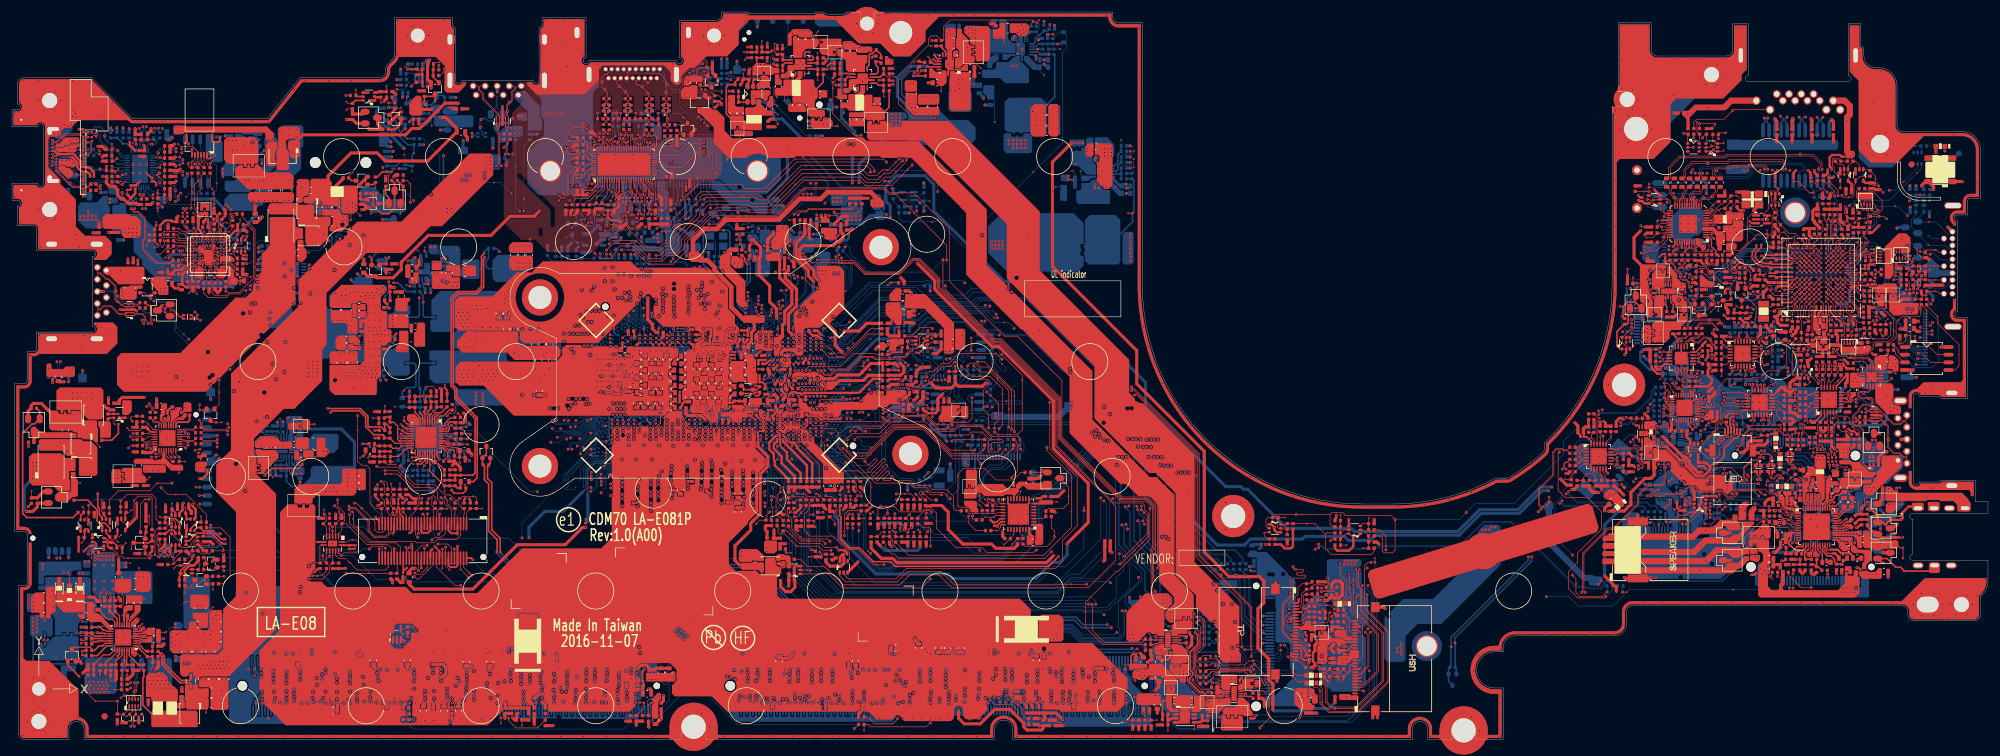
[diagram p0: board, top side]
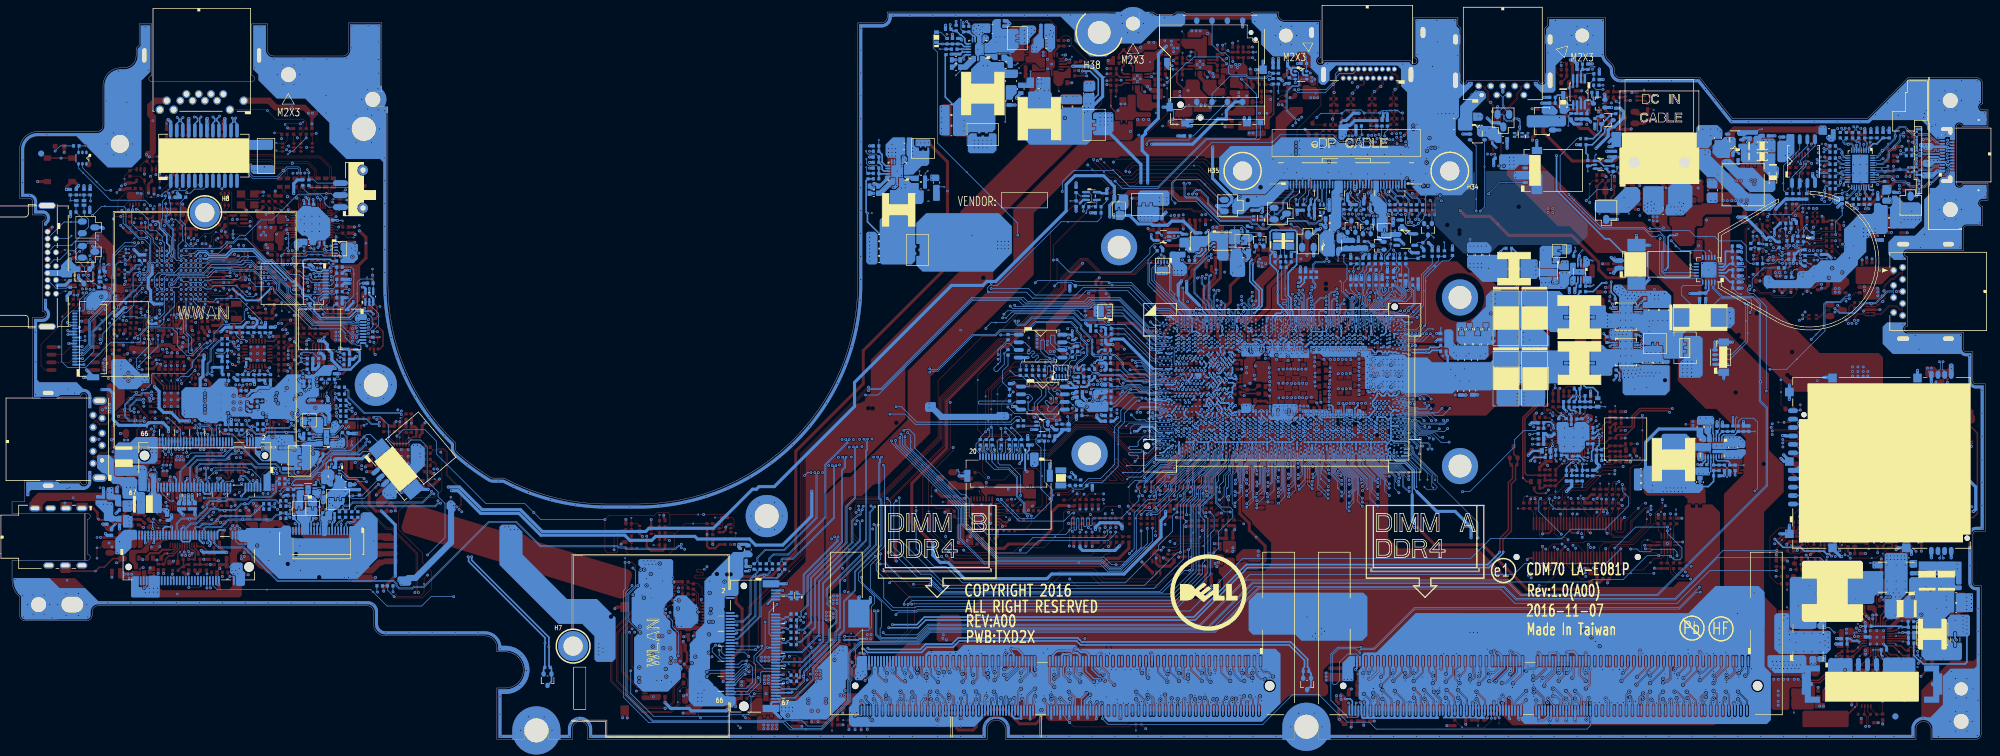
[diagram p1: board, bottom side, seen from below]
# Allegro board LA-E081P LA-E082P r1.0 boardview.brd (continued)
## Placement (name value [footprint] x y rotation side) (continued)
T219  PAD~D  [TPC12]  31.5 84.66 0 bottom
T220  PAD~D  [TPC12]  30.04 85.49 0 bottom
T223  PAD~D  [TPC12]  99.14 91.25 0 top
T224  PAD~D  [TPC12]  101.94 91.61 0 top
T225  PAD~D  [TPC12]  301.34 39.6 180 bottom
T258  PAD~D  [TPC12]  140.04 41.88 180 bottom
T267  PAD~D  [TPC12]  46.26 81.17 180 bottom
T268  PAD~D  [TPC12]  142.7 41.93 180 bottom
T281  PAD~D  [TPC12]  109.23 66.25 0 top
T282  PAD~D  [TPC12]  109.25 67.63 0 top
T283  PAD~D  [TPC12]  167.44 41.27 180 top
TL1  350UH_IH-160  [TAIMA_IH-160_24P]  301.71 92.78 180 bottom
UA1  ALC3246-CG_MQFN48_6X6  [ALC3246-CG_MQFN48_6X6-S]  296.55 37.52 0 top
UC1  SKL-U_BGA1356  [SKL-U_BGA_1356P-T]  137.46 69.71 0 bottom
UC5  -  [W25Q128FVSIQ_SO8]  160.91 67.23 270 bottom
UC6  -  [W25Q128FVSIQ_SO8]  160.53 58.59 270 bottom
UC7  TC7SH08FU_SSOP5~D  [TC7SH08FU_SSOP5]  157.98 52.77 270 bottom
UC8  74CBTLV3126BQ_DHVQFN14_2P5X3  [74CBTLV3126BQ_DHVQFN14_2P5X3-S]  54.69 32.79 180 top
UC12  -  [74AHC1G09GW_TSSOP5]  149.74 90.9 270 bottom
UD1  -  [74AUP1G07GW_TSSOP5]  63.24 16.58 0 top
UE1  MEC5105_WFBGA169_11X11  [MEC5105_WFBGA_169P]  295.56 71.93 90 top
UE2  MCP23008T-E-ML_QFN20_4X4  [IT8010FN-BX-R_QFN20_4X4]  44.31 77 0 bottom
UE3  TC7SH08FU_SSOP5~D  [TC7SH08FU_SSOP5]  307.36 94.69 180 top
UE4  -  [74AUP1G07GW_TSSOP5]  289.56 87.03 270 top
UE5  TC7SH08FU_SSOP5~D  [TC7SH08FU_SSOP5]  304.82 94.69 180 top
UE6  -  [74AUP1G07GW_TSSOP5]  269.39 72.66 180 bottom
UE7  RT9826-30GB  [AP2112K-3P3TRG1_SOT23-5]  284.53 75.78 90 top
UE9  -  [W25Q80DVSSIG_SO8]  314.26 65.17 270 top
UI1  -  [SY6288D20AAC_SOT23-5]  21.27 76.08 270 top
UI2  -  [SY6288D20AAC_SOT23-5]  85.98 101.49 270 bottom
UI3  -  [SLGC55544CVTR_TQFN16_3X3]  309.49 61.77 180 top
UI5  PS8713BTQFN24GTR2_TQFN24_4X4  [PS8713BTQFN24GTR2_TQFN24_4X4-S]  300.38 54.36 0 top
UL1  WGI219LM-QREF- A0_QFN48_6X6~D  [WGI217LM-QPN9-A2_QFN48_6X6-S]  281.24 83.42 90 top
UL2  TC7SH08FU_SSOP5~D  [TC7SH08FU_SSOP5]  273.62 89.03 90 top
UN4  PS8558BTQFN24GTR2-A_TQFN24_4X4  [PS8558BTQFN24_TQFN24_4X4-S]  261.35 48.26 0 top
UN5  PS8558BTQFN24GTR2-A_TQFN24_4X4  [PS8558BTQFN24_TQFN24_4X4-S]  288.89 53.91 90 top
UN7  PI3EQX6741STZDEX_TQFN20_4X4  [PI3EQX6741STZDEX_TQFN20_4X4-S]  278.14 65.3 270 top
UR1  RTS5242-GR_QFN32_4X4  [RTS5242-GR_QFN32_4X4-S]  27.84 48.66 180 top
UT5  TPS65982_BGA96  [TPS65982_BGA_96P]  35.14 83.04 270 top
UT6  -  [W25Q80DVSSIG_SO8]  32.52 92.4 180 bottom
UT7  AP2112K-3.3TRG1_SOT23-5  [AP2112K-3P3TRG1_SOT23-5]  40.85 98.64 90 bottom
UT8  AP2204R-5.0TRG1_SOT89-3  [AP2204R-5P0TRG1_SOT89-3]  46.41 98.64 180 top
UT9  -  [TUSB546_QFN40_4X6]  19.81 97.81 270 bottom
UV2  -  [AP2330W-7_SC59-3]  114.11 104.53 180 top
UV4  -  [AP2330W-7_SC59-3]  316.11 75.71 0 bottom
UV6  RTD2166-CG_QFN32_4X4  [RTD2166-CG_QFN32_4X4-S]  275.64 56.47 0 top
UV7  PS8348BQFN66GTR-A0_QFN66_5X10  [PS8348BQFN66GTR-A0_QFN66_5X10-S]  97.21 92.97 90 top
UV24  -  [G524B1T11U_SOT23-5]  98.15 83.96 270 bottom
UZ2  EM5209VF_SON14_2X3  [TPS22966DPUR_SON14_2X3-S]  274.82 48.98 90 bottom
UZ3  EM5209VF_SON14_2X3  [TPS22966DPUR_SON14_2X3-S]  201.86 8.81 270 top
UZ4  EM5209VF_SON14_2X3  [TPS22966DPUR_SON14_2X3-S]  190.88 17.73 270 top
UZ5  EM5209VF_SON14_2X3  [TPS22966DPUR_SON14_2X3-S]  276.16 75.46 180 top
UZ6  TC7SH08FU_SSOP5~D  [TC7SH08FU_SSOP5]  137.42 27.7 0 top
UZ8  AOZ1336_DFN8_2X2  [AOZ1336_DFN8_2X2-S]  271.65 51.92 180 top
UZ10  TC7SH08FU_SSOP5~D  [TC7SH08FU_SSOP5]  279.93 49.1 180 top
UZ12  -  [NPCT650JB2YX_QFN32_5X5]  169.62 35.67 180 top
UZ19  -  [TPS22961DNYR_WSON8]  131.83 81.43 180 bottom
UZ21  -  [TPS22961DNYR_WSON8]  128.48 83.73 270 bottom
UZ23  AOZ1336_DFN8_2X2  [AOZ1336_DFN8_2X2-S]  277.8 40.73 90 bottom
UZ26  -  [TPS22961DNYR_WSON8]  127.22 27.86 90 top
UZ34  TC7SH08FU_SSOP5~D  [TC7SH08FU_SSOP5]  130.88 27.5 90 top
UZ35  TC7SH08FU_SSOP5~D  [TC7SH08FU_SSOP5]  135.96 82.87 90 bottom
UZ36  PS8558BTQFN24GTR2-A_TQFN24_4X4  [PS8558BTQFN24_TQFN24_4X4-S]  285.25 65.33 0 top
YC1  24MHZ_12PF_X3G024000DC1H  [Y_X3G024000DC1H_4P]  118.07 81.91 180 bottom
YC2  32.768KHZ_12.5PF_9H03200042  [Y_9H03200042_2P]  153.93 42.18 90 bottom
YE1  32.768KHZ_9PF_X1A000141000200  [Y_X1A000141000200_2P]  290.79 69.85 90 top
YL1  25MHZ_18PF_7V25000034  [Y_7V25000034_4P]  290.03 90.58 180 top

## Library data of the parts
CA1-CA4 CA12 CA13 CA19 CA22-CA24 CA27 CA28 CA33 CA35 CA41 CA54 CA69 CZ126 CZ127 = C_0402: room: CODEC
CA5 CA6 CA62 CA72 = C_0402: room: CAMERA
CA7 CV12 CZ1 CZ2 = C_0201: room: LCD
CA8 PC1030-PC1056 PC1083-PC1099 PC1125 PC1126 PC1147-PC1153 PC1164 = C_0201: room: ETY-ROOM
CA9 CA25 CA29 CA31 CA43 CA44 CA46 CA48 CA49 CA51-CA53 CA56 CA58 CA59 CA61 = C_0603: room: CODEC
CA10 CA45 CA47 CA55 CA57 CA60 CZ125 CZ128 = C_0201: room: CODEC
CA63-CA68 CE59 CE60 CI43-CI48 CL29 CL30 CR25-CR28 CT189 CT190 CV18-CV25 CZ3 CZ41 CZ62 CZ63 CZ83-CZ89 = C_0402: room: TBT
CC7 CC8 CC316 CC318-CC321 CE57 = C_0402: room: SPI ROM
CC9 CC10 = C_0201: room: SPI ROM
CC21-CC27 CC176-CC179 CC195 CC199 CC202-CC209 CC211-CC213 CC215-CC218 CC222 CC224 CC250-CC253 CC264-CC266 CC288 CC297 CC300-CC305 CC310 CC312 CC322-CC326 CE61 = C_0402: room: CPU
CC28-CC30 = C_0201: room: CPU XDP
CC32 CC33 CC269 CC306-CC308 = C_0402: room: CPU XDP
CC210 CC219-CC221 CC225 CC226 = C_0805: room: CPU
CC214 CC223 CC270 CC281 CC313 CC314 = C_0201: room: CPU
CC279 CC280 CC294-CC296 = C_0603: room: CPU
CC331-CC333 CE62 CE500 CE503-CE505 CN12-CN16 CZ10 CZ11 CZ57-CZ60 CZ75 CZ134-CZ136 CZ141 CZ142 PC131 PC132 PC314 PC1215-PC1217 PC1286 = C_0402
CD1-CD8 CD20-CD22 CD33-CD40 CD52-CD54 = C_0603: room: MEMORY
CD9-CD16 CD18 CD19 CD23-CD27 CD29 CD31 CD41-CD48 CD50 CD51 CD55-CD59 CD61 CD62 = C_0402: room: MEMORY
CD17 CD49 = C_D3: room: MEMORY
CD28 CD32 CD60 = C_0201: room: MEMORY
CE1 CE6 CE52 CE53 = C_0402: room: PCH
CE2-CE5 CE10 CE12 CE14 CE24 CE26-CE31 CE35-CE40 CE46 CE47 CE54 = C_0402: room: KBC
CE8 = C_0402: room: SIO
CE11 CE13 CE15 CE18-CE23 CE25 = C_0201: room: KBC
CE16 CE17 CE32 = C_0603: room: KBC
CI1 = C_1206: room: JUSB2
CI3 CI7 = C_0201: room: JUSB2
CI4 CI5 = C_0402: room: JUSB2
CI6 = C_0603: room: JUSB2
CI8 = C_1206: room: JUSB3
CI10 CI12 = C_0201: room: JUSB3
CI11 = C_0603: room: JUSB3
CI13 CI16 CI31 CI37-CI42 = C_0402: room: JUSB1
CI14 = C_1206: room: JUSB1
CI17 CI19 = C_0201: room: JUSB1
CI27 CI28 = C_0402: room: JUSB3
CI29 CI30 CZ17-CZ19 CZ21 CZ23-CZ25 CZ198 = C_0402: room: WWAN
CI32 = C_B2-NPM: room: JUSB1
CI33 CI34 = C_0603: room: JUSB1
CL1 CL2 CL5 CL6 CL13 CL14 CL18 = C_0402: room: LAN
CL3 CL7-CL11 CL15-CL17 CL19-CL21 = C_0201: room: LAN
CL4 CL12 = C_0603: room: LAN
CL22 = C_1808: room: LAN
CL28 = C_0805: room: LAN
CLIP1 = CLIP_SH1506X616
CMOS1 = SHORTPADS-NPM: User Part Number: PART#; room: CPU
CN1 = C_0603: room: HDD
CN2 CN3 CN9-CN11 CZ129 = C_0201: room: HDD
CN4-CN8 CZ130 = C_0402: room: HDD
CN17 CZ50 CZ51 CZ54 CZ133 = C_0201
CN20 CN30 CN61 CN62 = C_0201: room: SATA EXPRESS
CN21-CN23 CN26 CN27 CN31-CN33 CN36 CN37 CN69-CN72 = C_0402: room: SATA EXPRESS
CN60 CZ61 CZ69 CZ71-CZ73 = C_0402: room: USH
CN63 CN64 = C_0603: room: SATA EXPRESS
CR1 CR4 CR11-CR15 CR21 CR22 = C_0402: room: RTS5242
CR2 CR3 CR6 CR7 CR17 CR19 = C_0201: room: RTS5242
CR5 CR18 CR20 = C_0603: room: RTS5242
CT70-CT74 CT83 CT85-CT87 CT89 CT90 CT92 CT93 = C_0402: room: PD
CT75-CT78 = C_0805: room: PD
CT80 CT81 CT88 = C_0201: room: PD
CT82 CT84 CT91 CT94 = C_0603: room: PD
CT95-CT102 = C_0201: room: TBT
CT103-CT117 CT122 = C_0402: room: PS8740
CT118-CT121 = C_0201: room: PS8740
CV1-CV6 CV13 CV14 CV17 = C_0402: room: LCD
CV11 CV15 CV16 = C_0603: room: LCD
CV31-CV38 = C_0402: room: HDMI
CV39 CV40 = C_0201: room: HDMI
CV41 = C_0603: room: HDMI
CV80-CV82 CV96 = C_0402: room: PS8348
CV83-CV95 = C_0201: room: PS8348
CV100-CV112 CV126-CV135 = C_0402: room: CRT
CV145-CV150 CV152 CV153 CV156 CV157 CZ12-CZ15 CZ28 CZ29 CZ33-CZ36 = C_0402: room: WLAN
CZ20 = C_0603: room: WWAN
CZ26 = C_B2: room: WWAN
CZ27 CZ32 = C_0603: room: WLAN
CZ30 CZ31 = C_0201: room: WLAN
CZ37-CZ40 = C_0402: room: SIM
CZ52 CZ55 PC223 = C_0603
CZ53 = C_0201: room: TPM
CZ56 = C_0402: room: TPM
CZ64 CZ66-CZ68 = C_0201: room: USH
CZ80 CZ81 = C_0402: room: KBTP
CZ82 = C_0201: room: RSMRST
CZ90-CZ92 = C_0201: room: KBTP
CZ93 = C_0201: room: LED
CZ100 = C_0402: room: +1.0V_VCCST
CZ101 = C_0201: room: +1.0V_VCCST
CZ102 CZ104 = C_0402: room: +VCC_SFR_OC
CZ103 = C_0201: room: +VCC_SFR_OC
CZ105 = C_0402: room: +1.0V_VCCSTG
CZ106 = C_0201: room: +1.0V_VCCSTG
CZ109 CZ110 = C_0402: room: UZ2
CZ111 CZ122 = C_0201: room: UZ2
CZ112 CZ115 = C_0201: room: UZ3
CZ113 CZ114 = C_0402: room: UZ3
CZ116 CZ119 = C_0201: room: UZ4
CZ117 CZ118 CZ124 = C_0402: room: UZ4
CZ120 = C_0201: room: UZ8
CZ121 CZ197 = C_0402: room: UZ8
DA1-DA3 DA6 DA7 = L03ESDL5V0CC3-2_SOT23-3: room: CODEC
DA8 DE1 = RB520SM-30T2R_EMD2-2: room: KBC
DI1 = L05ESDL5V0NA-4_SLP2510P8-10-9: room: JUSB2
DI2 = AZC199-02SPR7G_SOT23-3: room: JUSB2
DI3 = AZC199-02SPR7G_SOT23-3: room: JUSB3
DI4 = L05ESDL5V0NA-4_SLP2510P8-10-9: room: JUSB1
DI5 = AZC199-02SPR7G_SOT23-3: room: JUSB1
DI6 = L05ESDL5V0NA-4_SLP2510P8-10-9: room: JUSB3
DT1-DT3 = 1N4148WS-7-F_SOD323-2: room: PD
DT4 = L30ESD24VC3-2_SOT23-3: room: ETY-ROOM
DT5-DT20 = ESD8011MUT5G_X3DFN2-2-S: room: ETY-ROOM
DV1-DV3 = BAT54CW_SOT323-3: room: LCD
DV4 = AZC199-02SPR7G_SOT23-3: room: TOUCH
DV5 DV6 = PJDLC05C_SOT23-3: room: CRT
DZ1 DZ2 = RB520SM-30T2R_EMD2-2: room: WLAN
DZ5 DZ6 = RB520SM-30T2R_EMD2-2: room: WWAN
DZ7 = RB520SM-30T2R_EMD2-2: room: USH
FD1-FD4 = FIDUCIAL_C40M80: room: LED
H1-H4 = H_3P8: room: LED
H5 H6 = H_1P1N: room: LED
H7 H8 H34 H35 = H_3P2: room: LED
H9 H16 H26 = H_2P3-G: room: LED
H10 = H_3P0-G: room: LED
H12 H18 H23 H24 H28 H29 = H_2P5-G: room: LED
H14 H15 H17 H20 H22 = H_4P0-G: room: LED
H25 = H_2P2-G: room: LED
H32 = H_2P6X3P6-G: room: LED
H38 = H_3P8
H42 = H_0P7N
H43 = H_0P9N
JAPS1 = ACES_50506-01841-P01_18P: room: CPU
JCRT1 = CCM_C070546HR015M29CZR_15P-T: room: CRT
JDB1 = JXT_FP241AH-006GAAM_6P: room: PD
JDEG1 = JXT_FP241AH-010GAAM_10P: room: KBC
JDIMM1 JDIMM2 = LCN_DAN05-Q0406-0103_260P: room: ETY-ROOM
JEDP1 = ACES_50398-04041-001_40P: room: LCD
JESPI = JXT_FP241AH-010GAAM_10P: room: ETY-ROOM
JFAN1 = ACES_50271-0040N-001_4P: room: KBC
JHDMI1 = CONCR_099BKAC19YBLCNF_19P: room: HDMI
JHP1 = SINGA_2SJ3095-136111F_7P-T: room: CODEC
JIR1 = ACES_50208-0060N-P01_6P: room: CAMERA
JKBTP1 = CVILU_CF5020FD0RK-05-NH_20P-T: room: KBTP
JLED1 = CVILU_CF5006FD0R0-05-NH_6P: room: LED
JLOM1 = SANTA_130456-831_13P-T: room: LAN
JNGFF1 = BELLW_80148-4221_67P: room: WLAN
JNGFF2 = BELLW_80149-4221_67P: room: WWAN
JNGFF3 = LCN_DAN05-67356-0103_75P: room: SATA EXPRESS
JRTC1 = ACES_50271-0020N-001_2P: room: ETY-ROOM
JSATA1 = ACES_59003-02006-002_20P: room: ETY-ROOM
JSD1 = T-SOL_156-2000302608_19P_NR: room: RTS5242
JSIM1 = T-SOL_5-991503004000-6_8P-T: room: SIM
JSPI1 = E-T_6705K-Y20N-00L_20P: room: ETY-ROOM
JSPK1 = ACES_50278-00401-001_4P: room: CODEC
JTAG1 = SHORTPADS: User Part Number: PART#; room: KBC
JUART1 = CVILU_CI1804M1VRA-NH_4P: room: ETY-ROOM
JUSB1 = C-K_26230A-8K1A-02_9P-T: room: JUSB3
JUSB2 = LOTES_AUSB0014-P003A_9P: room: JUSB3
JUSB3 = C-K_26210B-8K1A-02_9P: room: JUSB3
JUSBC1 = JAE_DX07BD24JJ2_24P-T: room: TBT
JUSH1 = CVILU_CF5026FD0RK-05-NH_26P-T: room: USH
JXDP1 = SAMTE_BSH-030-01-L-D-A_60P: room: CPU XDP
LA5 LA12 LA14 = MURAT_BLM15PX600SN1D_2P: room: CODEC
LA6-LA9 = MURAT_BLM15PD800SN1D_2P: room: CODEC
LA10 LA11 = MURAT_BLM15PX330SN1D_2P: room: CODEC
LA13 = TAI-T_HCB2012VF-601T20_2P: room: CODEC
LA15 LA16 = MURAT_BLM15PX330SN1D_2P
LC1 LC2 = MURAT_BLM15GA750SN1D_2P: room: ETY-ROOM
LED3 = LED_LTW-C193DC-C_2P: room: LED
LGA1 = LNG2DMTR_LGA12_2X2
LI3 = PANAS_EXC24CQ900U_4P: room: JUSB2
LI4 = PANAS_EXC24CQ900U_4P: room: JUSB3
LI7 = PANAS_EXC24CQ900U_4P: room: JUSB1
LI8 LI9 = INPAQ_MCM1012B900F06BP_4P: room: ETY-ROOM
LI16 LI17 = INPAQ_HCM1012GH900BP_4P: room: ETY-ROOM
LL1 = TAIYO_BRC2012T4R7MD_2P: room: LAN
LT11 LV14 LV30 = MURAT_BLM15PX600SN1D_2P: room: CRT
LV1 = MURAT_BLM15PX221SN1D_2P: room: LCD
LV3 LV6 LV9 LV12 = TAIYO_MCF12102G900-T_4P-NPM: room: HDMI
LV16-LV18 = MURAT_BLM15BB470SN1D_2P: room: CRT
LV19 LV20 = MURAT_BLM15AG121SN1D_L0402_2P: room: CRT
LV27 = PANAS_EXC24CQ900U_4P: room: TOUCH
LZ1 = PANAS_EXC24CQ900U_4P: room: CAMERA
PBATT1 = DEREN_40-42251-01001RHF_10P-T: room: ETY-ROOM
PC1 PC2 PC1203 PC1208-PC1210 = C_0402: room: P_DCIN
PC3-PC7 PC1202 = C_0603: room: P_DCIN
PC8 PC106-PC110 PC120-PC124 PC129 PC130 PC200 PC201 PL1201 PL1202 = C_0805: room: ETY-ROOM
PC9 PC605 PC618-PC620 PC626 PC627 PC632 PC637 PC639 PC641 PC642 PC644 PC645 PC647 PC649-PC654 PC659-PC661 PC677 PC685 PC949 PC1204 = C_0402: room: CPU_CORE
PC10 PC113 PC127 PC128 PC301 PC303 PC307 PC401 PC402 PC408-PC411 PC417-PC420 PC513 PC515 PC601 PC602 PC613 PC614 PC616 PC617 PC621 PC624 PC625 PC628-PC631 PC633 PC636 PC640 PC643 PC646 PC679 PC680 PC686 PC688 PC944 PC1211 PC1212 PC1214 = C_0402: room: ETY-ROOM
PC11 = C_0603: room: UPD
PC100 PC103 PC115 PC116 = C_0402: room: 3_5V
PC102 PC111 PC114 PC119 PC126 = C_0603: room: 3_5V
PC104 PC105 PC117 PC118 = C_0805: room: 3_5V
PC112 PC125 PC302 PC304-PC306 PC308-PC313 PC403 PC404 PC406 PC407 PC412 PC413 PC415 PC416 PC422 PC424 PC501 PC502 PC504 PC514 PC516 PC940 PC941 PC1001-PC1029 PC1057-PC1061 PC1064-PC1082 PC1129-PC1146 PC1170-PC1181 = C_0603: room: ETY-ROOM
PC202 PC203 PC206-PC208 PC216-PC218 PC221 PC222 = C_0402: room: P_1.2V
PC204 PC205 PC209-PC214 PC219 = C_0603: room: P_1.2V
PC503 PC505 PC506 = C_0402: room: 1.8V
PC603 PC604 PC611 PC622 PC655 PC662 PC671 PC678 = C_0603: room: CPU_CORE
PC606 = C_D: room: ETY-ROOM
PC608 PC612 PC656-PC658 PC672 PC673 = C_0805: room: CPU_CORE
PC663-PC665 = C_0805
PC902 PC903 PC925-PC927 PC932 PC933 PC937-PC939 PC942 PC943 PC945-PC947 PC950 PC1201 PC1205-PC1207 PC1213 = C_0402: room: CHARGER
PC904-PC906 PC911 PC935 PC936 = C_0805: room: CHARGER
PC909 PC910 = C_B2: room: ETY-ROOM
PC913-PC920 = C_0805: room: PWR_CHARGER
PC928 PC929 = C_0402: room: PWR_CHARGER
PC930 PC934 = C_0603: room: CHARGER
PC931 = C_0603: room: PWR_CHARGER
PC951 = C_B2
PC1062 PC1063 PC1127 PC1128 = C_D2: room: CPU
PD1 PD2 = TVNST52302AB0_SOT523-3: room: ETY-ROOM
PD3 = DB3J315E0L_SMINI3-F2-B3: room: ETY-ROOM
PD4 = PESD5V0U2BT_SOT23-3: room: ETY-ROOM
PD5 PD1202 = PDS5100H-13_POWERDI5-3: room: P_SELECTOR
PD100 = RB520SM-30T2R_EMD2-2
PD901 PD904 = SDMK0340L-7-F_SOD323-2: room: ETY-ROOM
PD903 = RB520SM-30T2R_EMD2-2: room: ETY-ROOM
PD905 = BAT54CW_SOT323-3
PD1205 = SDMK0340L-7-F_SOD323-2: room: P_SELECTOR
PD1801 = BAT54CW_SOT323-3: room: ETY-ROOM
PH601 PH603-PH605 PR612 PR623 PR628 PR632 PR633 PR636 PR638 PR641-PR643 PR645-PR650 PR652 PR656 PR657 = R_0402: room: CPU_CORE
PH602 PR102 PR108 PR116 PR117 PR205 PR207 PR302 PR306 PR308 PR311 PR403 PR404 PR407 PR408 PR410-PR412 PR422 PR427 PR428 PR514-PR516 PR601 PR604 PR605 PR608 PR610 PR611 PR613 PR617 PR618 PR621 PR622 PR626 PR629-PR631 PR635 PR639 PR640 PR644 PR651 PR662 PR678 PR680 PR909 PR910 PR919 PR927 PR932-PR934 PR937 PR938 PR1201 PR1208 PR1217 PR1219 PR1237 PR1239 PR1240 PR1246 PR1247 RC211 RE300 RE337-RE339 RE341 RE361-RE363 RN171 RN174 RN176 RN179 RN182-RN189 RN192 RN223-RN225 RZ22 RZ23 RZ43 RZ60 RZ334 RZ335 = R_0402: room: ETY-ROOM
PJP1 = JUMP_43X39: room: +1.0V_VCCST
PJP2 = JUMP_43X39: room: +1.0V_VCCSTG
PJP3 = JUMP_43X118: room: +1.0V_MPHYGT
PJP4 PJP19 PJP37 = JUMP_43X39: room: UZ2
PJP7 = JUMP_43X39: room: PD
PJP8 = JUMP_43X118: room: PD
PJP12 = JUMP_43X39: room: LCD
PJP14 = JUMP_43X79: room: RTS5242
PJP15 PJP16 PJP18 = JUMP_43X39: room: CODEC
PJP17 PJP34 PJP40 = JUMP_43X79: room: UZ4
PJP20-PJP22 = JUMP_43X39: room: KBC
PJP31 = JUMP_43X118: room: SATA EXPRESS
PJP32 PJP33 = JUMP_43X39: room: HDD
PJP35 = JUMP_43X39: room: KBTP
PJP36 = JUMP_43X79: room: UZ2
PJP38 = JUMP_43X39: room: UZ3
PJP39 = JUMP_43X118: room: UZ3
PJP41 = JUMP_43X118: room: UZ4
PJP42 = JUMP_43X39: room: UZ8
PJP100 PJP101 PJP202 PJP301 PJP602 = JUMP_43X79: room: DDR_VTT_0.75V
PJP102 PJP103 PJP1202 = JUMP_43X118: room: 1.5V
PJP200 = JUMP_43X118: room: P_1.2V
PJP201 = JUMP_43X39: room: P_1.2V
PJP302 = JUMP_43X118: room: ETY-ROOM
PJP391 PJP403 PJP404 PJP501 = JUMP_43X39
PJP401 PJP402 = JUMP_43X79: room: 1.5V
PJP502 PJP505 PJP506 PJP603 = JUMP_43X39: room: VGA_CORE
PJP601 = JUMP_43X118: room: CHARGER
PJP901 = JUMP_43X118-NPM: room: CHARGER
PJPDC1 = CVILU_CI0805M1HRC-NH_5P-T: room: ETY-ROOM
PL1 PL2 PL4 = TAIYO_FBMJ4516HS720NT_2P: room: P_DCIN
PL3 = MURAT_BLM15AG102SN1D_2P: room: P_DCIN
PL100 PL201 = L_7X7X3_M_2P: room: ETY-ROOM
PL101 = L_7X7X3_M_2P: room: VDDCI
PL301 = L_5X5X3_M_2P: room: ETY-ROOM
PL402 PL404 PL501 = MAG_MLV-FY12N1R0M-O1L_2P: room: ETY-ROOM
PL602 = 9A_Z80_1812_2P-NPM: room: CPU_CORE
PL610 PL612 = L_7X7X3_M
PL614 = L_5X5X3_M_2P
PL901 = MAGLA_MMD-05CZ-1R0M-M7L_2P: room: ETY-ROOM
PL902 = CYNTE_PCMB103T-2R2MS_2P: room: ETY-ROOM
PQ1 PQ1201 PQ1204 PQ1209 PQ1214 QE2 = DMN65D8LDW-7_SOT363-6: room: ETY-ROOM
PQ2 = FDV301N-G_SOT23-3: room: P_DCIN
PQ3 = MMST3904-7-F_SOT323-3: room: P_DCIN
PQ4 = FDMC6679AZ_MLP8-5: room: CHARGER
PQ5 PQ1203 PQ1215 = NTR4502PT1G_SOT23-3: room: P_CHARGER
PQ6-PQ8 PQ909 PQ1205 PQ1212 = DMN65D8LW-7_SOT323-3: room: ETY-ROOM
PQ9 PQ906 PQ1202 PQ1206 PQ1213 = FDMC6679AZ_MLP8-5: room: ETY-ROOM
PQ501 = AON7934_DFN3X3A8-10: room: ETY-ROOM
PQ904 PQ905 = CSD87351Q5D_SON8-7: room: ETY-ROOM
PQ1207 PQ1208 PQ1210 PQ1211 = DMN66D0LDW-7_SOT363-6: room: P_USBB
PQ1216 = DMN65D8LW-7_SOT323-3
PR1-PR8 PR11 PR12 PR14 PR16 PR18 PR24 PR27 PR1207 PR1210 PR1222 PR1224 PR1227-PR1229 PR1248 = R_0402: room: P_DCIN
PR10 PR15 PR17 PR28 PR944 PR945 PR1202 PR1205 PR1206 PR1209 PR1212-PR1214 PR1226 PR1230-PR1236 PR1249 PR1251-PR1253 = R_0402: room: P_SELECTOR
PR13 = R_0805: room: P_DCIN
PR19 PR21 PR22 PR25 PR1211 PR1215 PR1216 PR1218 PR1220 PR1223 PR1238 PR1250 = R0402_0OHM: room: P_DCIN
PR20 PR23 PR104 PR105 PR114 PR119 PR120 PR208 PR210 PR312 PR402 PR406 PR423 PR425 PR426 PR504 PR513 PR602 PR603 PR614 PR616 PR620 PR625 PR659 PR671 PR679 PR920 PR922 PR926 PR928 PR935 PR936 PR947 PR1243 RA35-RA37 RC37 RC170 RC171 RC173 RC214 RC228-RC231 RC235 RC300-RC308 RC328 RC337 RE32 RE275 RE290 RE318 RE360 RE364 RN99 RR6-RR10 RZ64 RZ70 RZ85 RZ345-RZ347 = R0402_0OHM: room: ETY-ROOM
PR26 PR1221 = R0402_0OHM: room: P_USBA
PR29 PR1225 = R0402_0OHM: room: P_SELECTOR
PR100 PR111 PR304 R274 RA3 RC169 RC299 RC309 RC310 = R0603_0OHM: room: ETY-ROOM
PR103 = R_0402: room: 3_5V
PR106 PR112 = R_1206: room: 1.5V
PR107 PR113 PR307 PR310 = R_0402: room: 1P5V
PR202 = R_1206: room: P_1.2V
PR203 = R0603_0OHM: room: P_1.2V
PR204 PR206 PR209 PR212 PR517 = R_0402: room: P_1.2V
PR303 PR923 PR924 = R_1206: room: ETY-ROOM
PR405 PR409 PR502 = R_0603: room: 1.8V
PR413-PR420 PR424 PR915 PR918 PR925 PR930 PR931 PR940 PR1203 = R_0402: room: CHARGER
PR421 RC1-RC7 RC10-RC17 RC19-RC23 RC25 RC27 RC44-RC48 RC50-RC52 RC54 RC56 RC57 RC59 RC60 RC65 RC67-RC69 RC71-RC75 RC77-RC84 RC86-RC96 RC109 RC110 RC112-RC115 RC120 RC130 RC140 RC141 RC152 RC153 RC157 RC161 RC163 RC165-RC168 RC175-RC178 RC183 RC184 RC186 RC187 RC189 RC190 RC215 RC220 RC222-RC225 RC227 RC234 RC237 RC243 RC267 RC268 RC272 RC278 RC279 RC282 RC283 RC287 RC288 RC291 RC292 RC295 RC297 RC298 RC311 RC313 RC317-RC319 RC323 RC324 RC330 RC331 RC338 RC344-RC349 RC362 RC363 RC366-RC370 RC387 RC402-RC405 RC411 RE95 RE349 RL70 RV7 = R_0402: room: CPU
PR501 PR505 PR506 = R_0402: room: 1.8V
PR606 PR949 PR951 PR960 PR1257 RE515 RI81 RT380 RZ89 RZ363 = R0402_0OHM
PR619 PR624 PR660 PR661 PR672 PR674 = R_0603: room: CPU_CORE
PR627 PR663 PR676 = R_1206: room: CPU_CORE
PR681 PR682 PR948 PR950 PR953 PR1254 PR1255 PR1258-PR1261 RA59-RA61 RC413 RC414 RC417 RE376 RE377 RE505 RE507 RE508 RE512-RE514 RE524-RE526 RE530 RE532 RE536 RE537 RE539 RN6-RN21 RN100 RN101 RT375-RT379 RT393 RZ62 RZ111-RZ113 RZ131 RZ132 RZ154-RZ167 RZ348 RZ354-RZ362 = R_0402
PR901 PR917 = R_1206_4P-D: room: CHARGER
PR914 PR921 = R_0603: room: CHARGER
PR916 = R_0805: room: CHARGER
PR929 = R0402_0OHM: room: CHARGER
PR939 PR941 PR942 PR946 = R0402_0OHM: room: PWR_CHARGER
PR943 = R0603_0OHM: room: CHARGER
PR1241 PR1242 PR1244 PR1245 = R0402_0OHM: room: P_USBB
PRP1 = RP_0804_8P4R: room: ETY-ROOM
PT1 T258 T267 T268 T281-T283 = TPC12
PU1 PU1200 = TC7SH08FU_SSOP5: room: PCH
PU2 = AP2204RA-3P3TRG1_SOT89-3: room: ETY-ROOM
PU100 = SY8288BRAC_QFN20_3X3: room: ETY-ROOM
PU102 = SY8288CRAC_QFN20_3X3: room: ETY-ROOM
PU200 = SY8210AQVC_QFN19_4X3: room: P_1.2V
PU301 = SY8288RAC_QFN20_3X3: room: ETY-ROOM
PU401 PU402 = SY8057QDC_QFN16_3X3: room: ETY-ROOM
PU501 = RT8097ALGE_SOT23-6: room: ETY-ROOM
PU503 = AP7361C-FGE-7_U-DFN3030-8_3X3: room: ETY-ROOM
PU602 = ISL62883CHRTZ-T_TQFN40_5X5-S: room: GPU_CORE
PU610 PU612 = CSD97374CQ4M_SON8_3P5X4P5
PU614 = ISL95808HRZ-TS2378_DFN8_2X2-S
PU901 = ISL88738HRTZ-T_TQFN32_4X4: room: ETY-ROOM
PU903 = TC7SH08FU_SSOP5: room: ETY-ROOM
PU1201 = LM393DGKR_VSSOP8: room: ETY-ROOM
QC2 = DMN65D8LDW-7_SOT363-6: room: CPU
QE3-QE7 = MMBT3904WT1G_SC70-3: room: KBC
QE11 QE12 = L2N7002WT1G_SC-70-3: room: ETY-ROOM
QE13 QZ2 = DMN65D8LDW-7_SOT363-6
QL1 QL2 = DMN65D8LDW-7_SOT363-6: room: LAN
QN1 = DMN65D8LDW-7_SOT363-6: room: HDD
QN4 QN5 = DMN66D0LDW-7_SOT363-6: room: CODEC
QR1 = L2N7002WT1G_SC-70-3: room: RTS5242
QT1 = DMN66D0LDW-7_SOT363-6: room: PD
QV1 = AO6405_TSOP6: room: LCD
QV2 = L2N7002WT1G_SC-70-3: room: LCD
QV3 = DMN65D8LDW-7_SOT363-6: room: HDMI
QV4 QV5 = L2N7002WT1G_SC-70-3: room: HDMI
QV7 = L2N7002WT1G_SC-70-3: room: TOUCH
QV8 = LP2301ALT1G_SOT23-3: room: TOUCH
QZ1 = LP2301ALT1G_SOT23-3: room: CAMERA
QZ3 = DDTA144VCA-7-F_SOT23-3
QZ7 = DMN65D8LDW-7_SOT363-6: room: LED
QZ8 = L2N7002WT1G_SC-70-3
QZ9 = LP2301ALT1G_SOT23-3
RA5-RA9 RA12-RA14 RA17 RA18 RA44 RA45 RA51 RA52 = R_0402: room: CODEC
RA48 RA54 RE90 = R0402_0OHM: room: UZ8
RA50 RA53 RA57 RA58 = R_0402: room: UZ8
RC28-RC32 RC39 RC42 RC43 RC316 RC407-RC410 RE98 RE350 RE366-RE374 = R_0402: room: SPI ROM
RC33-RC36 RC38 RC40 RC41 = R0402_0OHM: room: SPI ROM
RC62 RC212 RC221 RC244 RC290 RC296 RC325 RC373-RC378 = R0402_0OHM: room: CPU
RC121-RC124 RC126 RC128 RC129 RC131-RC139 RC217-RC219 RC239-RC241 RE79 = R_0402: room: CPU XDP
RC143 = R0603_0OHM: room: CPU
RC216 = R0603_0OHM: room: CPU XDP
RC371 RC372 RC400 RC401 RE6 RE14 RE15 RE18 RE31 RE33 RE37 RE43 RE48 RE51 RE55-RE58 RE60 RE63-RE65 RE67-RE75 RE77 RE86 RE280 RE292 RE301-RE304 RE306 RE308 RE312-RE314 RE340 RE342 RE343 RE348 RE375 = R_0402: room: KBC
RD4 RD6 RD8 RD11 RD14-RD20 RD23 RD24 RD27-RD31 = R_0402: room: MEMORY
RD5 RD7 RD9 RD12 RD21 RD22 RD25 = R0402_0OHM: room: MEMORY
RD10 RD26 = R0603_0OHM: room: MEMORY
RE5 RE8 RE10-RE13 RE16 RE17 RE20 RE21 RE25 RE26 RE35 RE38 RE83-RE85 RE91 RE92 RE94 RE274 RE288 RE324 RE365 = R_0402: room: SIO
RE30 RE34 RE59 = R0402_0OHM: room: KBC
RE93 = R_0201: room: SIO
RI13 RI14 RI34-RI45 RI51-RI58 = R_0402: room: JUSB1
RI27-RI30 RI47-RI50 = R_0402-NPM: room: ETY-ROOM
RI79 RT397 = R_0603
RI80 RT398 = R0603_0OHM
RL1 RL2 RL4-RL6 RL9 RL11-RL20 RL29 RL30 = R_0402: room: LAN
RL3 RL7 RL34 = R0402_0OHM: room: LAN
RL8 = R0603_0OHM: room: LAN
RL71-RL78 = R_0603: room: LAN
RN1-RN5 = R_0402: room: HDD
RN25-RN28 RN30 RN31 RN37-RN44 RN49-RN65 RN69-RN74 = R_0402: room: SATA EXPRESS
RN77 RN78 RN81 RN82 = R0402_0OHM: room: SATA EXPRESS
RPC1 = RP_0804_8P4R: room: SPI ROM
RPC3 RPC4 = RP_0804_8P4R: room: CPU
RPE7 RPE10 RPE12 = RP_0804_8P4R: room: KBC
RPE9 RPE11 = RP_0804_8P4R: room: SIO
RR3 RR4 RR19 = R_0402: room: RTS5242
RR5 = R0402_0OHM: room: RTS5242
RT50-RT53 RT64-RT68 RT71 RT75 RT76 RT81 RT82 RT84-RT88 RT95-RT98 RT100 RT101 RT103 RT106 RT107 RT110 RT111 = R_0402: room: PD
RT54-RT60 RT63 RT69 RT70 RT72 RT73 RT83 RT89 RT90 RT92 RT93 RT99 RT104 RT105 RT108 RT109 = R0402_0OHM: room: PD
RT74 RT339 = R_0402: room: TBT
RT120-RT123 = R0402_0OHM: room: TBT
RT130-RT133 RT135-RT145 RT247 RT248 RT300-RT308 = R_0402: room: PS8740
RT246 = R0402_0OHM: room: PS8740
RV1-RV5 = R_0402: room: LCD
RV6 RV8 = R_0402: room: TOUCH
RV10-RV35 = R_0402: room: HDMI
RV70-RV97 = R_0402: room: PS8348
RV102 RV106 RV107 RV116-RV124 = R_0402: room: CRT
RZ8-RZ10 RZ114 = R_0402: room: USH
RZ18-RZ21 RZ116 RZ117 = R_0402: room: KBTP
RZ25 RZ28 RZ32 = R_0402: room: LED
RZ26 RZ29 = R0402_0OHM: room: KBTP
RZ38 RZ71 = R_0402: room: UZ2
RZ40 = R_0402: room: UZ4
RZ56 = R0402_0OHM: room: WLAN
RZ58 RZ59 RZ63 RZ69 = R_0402: room: TPM
RZ61 = R0402_0OHM: room: TPM
RZ65 = R_0402: room: UZ3
RZ76 RZ77 RZ326 = R_0402: room: WWAN
RZ78-RZ81 = R_0402: room: WLAN
RZ87 = R0402_0OHM: room: USH
RZ119 = R_0402: room: +VCC_SFR_OC
RZ120 = R0402_0OHM: room: +VCC_SFR_OC
RZ128-RZ130 = R_0201
RZ151 = R_0603: room: +1.0V_VCCSTG
RZ320 = R_0402: room: +1.0V_VCCSTG
SW1 = SW_SS3-CMFTQR9_3P: room: CPU
SW3 = SW_SKRBAAE010_4P: room: LED
T1-T6 T9-T19 T113-T115 T120 T122 T123 T126-T130 T132 = TPC12: room: CPU
T50 T51 T54 T55 T225 = TPC12: room: MEMORY
T87 = TPC12: room: CRT
T88 T89 = TPC12: room: LAN
T204 T223 T224 = TPC12: room: PS8348
T219 T220 = TPC12: room: PD
TL1 = TAIMA_IH-160_24P: room: LAN
UA1 = ALC3246-CG_MQFN48_6X6-S: room: ETY-ROOM
UC1 = SKL-U_BGA_1356P-T: room: CPU
UC5 UC6 = W25Q128FVSIQ_SO8: room: SPI ROM
UC7 UE3 UE5 = TC7SH08FU_SSOP5: room: CPU
UC8 = 74CBTLV3126BQ_DHVQFN14_2P5X3-S: room: CPU XDP
UC12 = 74AHC1G09GW_TSSOP5: room: CPU
UD1 = 74AUP1G07GW_TSSOP5: room: MEMORY
UE1 = MEC5105_WFBGA_169P: room: ETY-ROOM
UE2 = IT8010FN-BX-R_QFN20_4X4: room: ETY-ROOM
UE4 UE6 = 74AUP1G07GW_TSSOP5: room: ETY-ROOM
UE7 = AP2112K-3P3TRG1_SOT23-5: room: ETY-ROOM
UE9 UT6 = W25Q80DVSSIG_SO8: room: PD
UI1 = SY6288D20AAC_SOT23-5: room: JUSB2
UI2 = SY6288D20AAC_SOT23-5: room: JUSB3
UI3 = SLGC55544CVTR_TQFN16_3X3: room: JUSB1
UI5 = PS8713BTQFN24GTR2_TQFN24_4X4-S: room: JUSB1
UL1 = WGI217LM-QPN9-A2_QFN48_6X6-S: room: LAN
UL2 = TC7SH08FU_SSOP5: room: LAN
UN4 UN5 = PS8558BTQFN24_TQFN24_4X4-S: room: SATA EXPRESS
UN7 = PI3EQX6741STZDEX_TQFN20_4X4-S
UR1 = RTS5242-GR_QFN32_4X4-S: room: RTS5242
UT5 = TPS65982_BGA_96P: room: PD
UT7 = AP2112K-3P3TRG1_SOT23-5: room: PD
UT8 = AP2204R-5P0TRG1_SOT89-3: room: PD
UT9 = TUSB546_QFN40_4X6: room: ETY-ROOM
UV2 = AP2330W-7_SC59-3: room: HDMI
UV4 = AP2330W-7_SC59-3: room: CRT
UV6 = RTD2166-CG_QFN32_4X4-S: room: CRT
UV7 = PS8348BQFN66GTR-A0_QFN66_5X10-S: room: PS8348
UV24 = G524B1T11U_SOT23-5: room: LCD
UZ2 = TPS22966DPUR_SON14_2X3-S: room: UZ2
UZ3 = TPS22966DPUR_SON14_2X3-S: room: UZ3
UZ4 = TPS22966DPUR_SON14_2X3-S: room: UZ4
UZ5 = TPS22966DPUR_SON14_2X3-S: room: CODEC
UZ6 = TC7SH08FU_SSOP5: room: RSMRST
UZ8 = AOZ1336_DFN8_2X2-S: room: UZ8
UZ10 = TC7SH08FU_SSOP5: room: LED
UZ12 = NPCT650JB2YX_QFN32_5X5: room: ETY-ROOM
UZ19 = TPS22961DNYR_WSON8: room: +1.0V_VCCSTG
UZ21 = TPS22961DNYR_WSON8: room: +1.0V_VCCST
UZ23 = AOZ1336_DFN8_2X2-S: room: HDD
UZ26 = TPS22961DNYR_WSON8: room: +VCC_SFR_OC
UZ34 = TC7SH08FU_SSOP5: room: +VCC_SFR_OC
UZ35 = TC7SH08FU_SSOP5: room: +1.0V_VCCSTG
UZ36 = PS8558BTQFN24_TQFN24_4X4-S
YC1 = Y_X3G024000DC1H_4P: room: CPU
YC2 = Y_9H03200042_2P: room: CPU
YE1 = Y_X1A000141000200_2P: room: ETY-ROOM
YL1 = Y_7V25000034_4P: room: LAN

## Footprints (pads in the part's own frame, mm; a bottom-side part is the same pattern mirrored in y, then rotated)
1N4148WS-7-F_SOD323-2
  rect 1.346x0.66 smd: 1(0,0) 2(2.4,0)
9A_Z80_1812_2P-NPM
  rect 1.803x3.404 smd: 1(0,0) 2(3.8,0)
74AHC1G09GW_TSSOP5
  oval 0.381x1.346 smd: 1(0,0) 2(0.65,0) 3(1.3,0) 4(1.3,1.79) 5(0,1.79)
74AUP1G07GW_TSSOP5
  oval 0.381x1.346 smd: 1(0,0) 2(0.65,0) 3(1.3,0) 4(1.3,1.79) 5(0,1.79)
74CBTLV3126BQ_DHVQFN14_2P5X3-S
  oval 1.041x0.254 smd: 1(0,0) 7(2.95,0) 8(2.95,0.5) 14(0,0.5)
  oval 0.254x1.041 smd: 2(0.475,-0.975) 3(0.975,-0.975) 4(1.475,-0.975) 5(1.975,-0.975) 6(2.475,-0.975) 9(2.475,1.475) 10(1.975,1.475) 11(1.475,1.475) 12(0.975,1.475) 13(0.475,1.475)
  rect 1.499x0.991 smd: 15(1.475,0.25)
ACES_50208-0060N-P01_6P
  oval 0.508x0.991 smd: 1(0,0) 2(0.8,0) 3(1.6,0) 4(2.4,0) 5(3.2,0) 6(4,0)
  rect 1.194x1.702 smd: 7(-1.3,-1.95) 8(5.3,-1.95)
ACES_50271-0020N-001_2P
  oval 0.787x1.6 smd: 1(0,0) 2(1.25,0)
  rect 2.108x2.997 smd: 3(3.8,-2.9) 4(-2.55,-2.9)
ACES_50271-0040N-001_4P
  oval 0.787x1.6 smd: 1(0,0) 2(-1.25,0) 3(-2.5,0) 4(-3.75,0)
  rect 2.108x2.997 smd: 5(2.55,-2.9) 6(-6.3,-2.9)
ACES_50278-00401-001_4P
  oval 0.787x1.905 smd: 1(0,0) 2(1.25,0) 3(2.5,0) 4(3.75,0)
  rect 1.295x3.353 smd: 5(-2.85,-4.925) 6(6.6,-4.925)
ACES_50398-04041-001_40P
  oval 0.254x1.295 smd: 1(0,0) 2(0.5,0) 3(1,0) 4(1.5,0) 5(2,0) 6(2.5,0) 7(3,0) 8(3.5,0) 9(4,0) 10(4.5,0) 11(5,0) 12(5.5,0) 13(6,0) 14(6.5,0) 15(7,0) 16(7.5,0) 17(8,0) 18(8.5,0) 19(9,0) 20(9.5,0) 21(10,0) 22(10.5,0) 23(11,0) 24(11.5,0) 25(12,0) 26(12.5,0) 27(13,0) 28(13.5,0) 29(14,0) 30(14.5,0) 31(15,0) 32(15.5,0) 33(16,0) 34(16.5,0) 35(17,0) 36(17.5,0) 37(18,0) 38(18.5,0) 39(19,0) 40(19.5,0)
  rect 1.194x3.2 smd: 41(-2.4,1.95) 45(21.9,1.95)
  rect 2.311x1.295 smd: 42(0.85,3.9) 43(9.75,3.9) 44(18.65,3.9)
ACES_50506-01841-P01_18P
  oval 0.305x0.889 smd: 1(0,0) 2(0.5,0) 3(1,0) 4(1.5,0) 5(2,0) 6(2.5,0) 7(3,0) 8(3.5,0) 9(4,0) 10(4.5,0) 11(5,0) 12(5.5,0) 13(6,0) 14(6.5,0) 15(7,0) 16(7.5,0) 17(8,0) 18(8.5,0)
  rect 0.991x2.007 smd: 19(-2.1,-3.05) 20(10.6,-3.05)
ACES_59003-02006-002_20P
  oval 0.254x1.397 smd: 1(0,0) 2(0.5,0) 3(1,0) 4(1.5,0) 5(2,0) 6(2.5,0) 7(3,0) 8(3.5,0) 9(4,0) 10(4.5,0) 11(5,0) 12(5.5,0) 13(6,0) 14(6.5,0) 15(7,0) 16(7.5,0) 17(8,0) 18(8.5,0) 19(9,0) 20(9.5,0)
  rect 1.295x1.397 smd: 21(10.55,0.125) 22(10.55,4.125) 23(-1.05,4.125) 24(-1.05,0.125)
ALC3246-CG_MQFN48_6X6-S
  oval 0.889x0.203 smd: 1(0,0) 2(0,-0.4) 3(0,-0.8) 4(0,-1.2) 5(0,-1.6) 6(0,-2) 7(0,-2.4) 8(0,-2.8) 9(0,-3.2) 10(0,-3.6) 11(0,-4) 12(0,-4.4) 25(6.1,-4.4) 26(6.1,-4) 27(6.1,-3.6) 28(6.1,-3.2) 29(6.1,-2.8) 30(6.1,-2.4) 31(6.1,-2) 32(6.1,-1.6) 33(6.1,-1.2) 34(6.1,-0.8) 35(6.1,-0.4) 36(6.1,0)
  oval 0.203x0.889 smd: 13(0.85,-5.25) 14(1.25,-5.25) 15(1.65,-5.25) 16(2.05,-5.25) 17(2.45,-5.25) 18(2.85,-5.25) 19(3.25,-5.25) 20(3.65,-5.25) 21(4.05,-5.25) 22(4.45,-5.25) 23(4.85,-5.25) 24(5.25,-5.25) 37(5.25,0.85) 38(4.85,0.85) 39(4.45,0.85) 40(4.05,0.85) 41(3.65,0.85) 42(3.25,0.85) 43(2.85,0.85) 44(2.45,0.85) 45(2.05,0.85) 46(1.65,0.85) 47(1.25,0.85) 48(0.85,0.85)
  rect 4.394x4.394 smd: 49(3.05,-2.2)
AO6405_TSOP6
  oval 0.508x1.473 smd: 1(0,0) 2(0.95,0) 3(1.9,0) 4(1.9,2.35) 5(0.95,2.35) 6(0,2.35)
AON7934_DFN3X3A8-10
  oval 0.457x0.508 smd: 1(0,0) 2(0.65,0) 3(1.3,0) 4(1.95,0) 5(1.95,2.76) 6(1.3,2.76) 7(0.65,2.76) 8(0,2.76)
  rect 2.54x1.041 smd: 9(0.975,1.813)
  rect 2.54x0.559 smd: 10(0.975,0.708)
AOZ1336_DFN8_2X2-S
  oval 0.254x0.787 smd: 1(0,0) 2(0.5,0) 3(1,0) 4(1.5,0) 5(1.5,2.2) 6(1,2.2) 7(0.5,2.2) 8(0,2.2)
  rect 1.499x0.889 smd: 9(0.75,1.1)
AP2112K-3P3TRG1_SOT23-5
  oval 0.508x0.965 smd: 1(0,0) 2(0.95,0) 3(1.9,0) 4(1.9,2.375) 5(0,2.375)
AP2204R-5P0TRG1_SOT89-3
  oval 0.889x1.295 smd: 1(0,0) 3(3,0)
  custom 0.433x0.433 smd: 2(1.5,1.775)
AP2204RA-3P3TRG1_SOT89-3
  oval 0.889x1.295 smd: 1(0,0) 3(3,0)
  custom 0.433x0.433 smd: 2(1.5,1.775)
AP2330W-7_SC59-3
  oval 0.787x0.991 smd: 1(0,0) 2(-0.95,-2.4) 3(0.95,-2.4)
AP7361C-FGE-7_U-DFN3030-8_3X3
  oval 0.457x0.94 smd: 1(0,0) 2(0.65,0) 3(1.3,0) 4(1.95,0) 5(1.95,3.05) 6(1.3,3.05) 7(0.65,3.05) 8(0,3.05)
  rect 2.261x1.499 smd: 9(0.975,1.525)
AZC199-02SPR7G_SOT23-3
  oval 1.016x1.524 smd: 1(0,0) 2(0.965,2.083) 3(-0.965,2.083)
BAT54CW_SOT323-3
  oval 0.711x0.889 smd: 1(0,0) 2(-0.65,-1.9) 3(0.65,-1.9)
BELLW_80148-4221_67P
  round 1.092 hole 1.092 unplated: (-0.75,-5.275)
  round 1.6 hole 1.6 unplated: (19.25,-5.275)
  oval 0.305x1.549 smd: 1(0,0) 2(0.25,-7.55) 3(0.5,0) 4(0.75,-7.55) 5(1,0) 6(1.25,-7.55) 7(1.5,0) 8(3.75,-7.55) 9(4,0) 10(4.25,-7.55) 11(4.5,0) 12(4.75,-7.55) 13(5,0) 14(5.25,-7.55) 15(5.5,0) 16(5.75,-7.55) 17(6,0) 18(6.25,-7.55) 19(6.5,0) 20(6.75,-7.55) 21(7,0) 22(7.25,-7.55) 23(7.5,0) 24(7.75,-7.55) 25(8,0) 26(8.25,-7.55) 27(8.5,0) 28(8.75,-7.55) 29(9,0) 30(9.25,-7.55) 31(9.5,0) 32(9.75,-7.55) 33(10,0) 34(10.25,-7.55) 35(10.5,0) 36(10.75,-7.55) 37(11,0) 38(11.25,-7.55) 39(11.5,0) 40(11.75,-7.55) 41(12,0) 42(12.25,-7.55) 43(12.5,0) 44(12.75,-7.55) 45(13,0) 46(13.25,-7.55) 47(13.5,0) 48(13.75,-7.55) 49(14,0) 50(14.25,-7.55) 51(14.5,0) 52(14.75,-7.55) 53(15,0) 54(15.25,-7.55) 55(15.5,0) 56(15.75,-7.55) 57(16,0) 58(16.25,-7.55) 59(16.5,0) 60(16.75,-7.55) 61(17,0) 62(17.25,-7.55) 63(17.5,0) 64(17.75,-7.55) 65(18,0) 66(18.25,-7.55) 67(18.5,0)
  rect 1.194x2.743 smd: 68(-1.1,-0.775) 69(19.6,-0.775)
BELLW_80149-4221_67P
  round 1.092 hole 1.092 unplated: (-0.75,-5.275)
  round 1.6 hole 1.6 unplated: (19.25,-5.275)
  oval 0.305x1.549 smd: 1(0,0) 2(0.25,-7.55) 3(0.5,0) 4(0.75,-7.55) 5(1,0) 6(1.25,-7.55) 7(1.5,0) 8(1.75,-7.55) 9(2,0) 10(2.25,-7.55) 11(2.5,0) 12(4.75,-7.55) 13(5,0) 14(5.25,-7.55) 15(5.5,0) 16(5.75,-7.55) 17(6,0) 18(6.25,-7.55) 19(6.5,0) 20(6.75,-7.55) 21(7,0) 22(7.25,-7.55) 23(7.5,0) 24(7.75,-7.55) 25(8,0) 26(8.25,-7.55) 27(8.5,0) 28(8.75,-7.55) 29(9,0) 30(9.25,-7.55) 31(9.5,0) 32(9.75,-7.55) 33(10,0) 34(10.25,-7.55) 35(10.5,0) 36(10.75,-7.55) 37(11,0) 38(11.25,-7.55) 39(11.5,0) 40(11.75,-7.55) 41(12,0) 42(12.25,-7.55) 43(12.5,0) 44(12.75,-7.55) 45(13,0) 46(13.25,-7.55) 47(13.5,0) 48(13.75,-7.55) 49(14,0) 50(14.25,-7.55) 51(14.5,0) 52(14.75,-7.55) 53(15,0) 54(15.25,-7.55) 55(15.5,0) 56(15.75,-7.55) 57(16,0) 58(16.25,-7.55) 59(16.5,0) 60(16.75,-7.55) 61(17,0) 62(17.25,-7.55) 63(17.5,0) 64(17.75,-7.55) 65(18,0) 66(18.25,-7.55) 67(18.5,0)
  rect 1.194x2.743 smd: 68(-1.1,-0.775) 69(19.6,-0.775)
C-K_26210B-8K1A-02_9P
  round 1.118 hole 0.711: 1(0,0) 2(-2.5,0) 3(-4.5,0) 4(-7,0) 5(-7.5,-1.5) 6(-5.5,-1.5) 7(-3.5,-1.5) 8(-1.5,-1.5) 9(0.5,-1.5)
  oval 1.549x3.353 hole 0.787x2.591: 10(4.35,-2.43) 11(-11.35,-2.43)
  oval 1.549x2.464 hole 0.787x1.702: 12(-11.35,-9.23) 13(4.35,-9.23)
C-K_26230A-8K1A-02_9P-T
  round 1.194 hole 0.711: 1(0,0) 2(-2.5,0) 3(-4.5,0) 4(-7,0) 5(-7.5,-1.5) 6(-5.5,-1.5) 7(-3.5,-1.5) 8(-1.5,-1.5) 9(0.5,-1.5)
  oval 1.295x2.388 hole 0.711x1.803: 10(2.9,-0.4) 11(4.2,-8.95) 12(-9.9,-0.4) 13(-11.2,-8.95)
C_0201
  rect 0.381x0.356 smd: 1(0,0) 2(0.584,0)
C_0402
  rect 0.508x0.559 smd: 1(0,0) 2(0.914,0)
C_0603
  rect 0.635x0.889 smd: 1(0,0) 2(1.397,0)
C_0805
  rect 0.813x1.397 smd: 1(0,0) 2(1.702,0)
C_1206
  rect 1.016x1.778 smd: 1(0,0) 2(2.667,0)
C_1808
  rect 1.041x2.311 smd: 1(0,0) 2(4.35,0)
C_B2
  rect 1.346x2.692 smd: 1(0,0) 2(-2.75,0)
C_B2-NPM
  rect 1.346x2.692 smd: 1(0,0) 2(-2.75,0)
C_D
  rect 2.388x2.896 smd: 1(0,0) 2(6.1,0)
C_D2
  rect 2.388x2.794 smd: 1(0,0) 2(6.4,0)
C_D3
  rect 2.388x2.794 smd: 1(0,0) 2(6.4,0)
CCM_C070546HR015M29CZR_15P-T
  round 0.965 hole 0.711: 1(0,0) 2(-2.29,0) 3(-4.58,0) 4(-6.87,0) 5(-9.16,0) 6(1.145,0) 7(-1.145,0) 8(-3.435,0) 9(-5.725,0) 10(-8.015,0) 11(0,-1.4) 12(-2.29,-1.4) 13(-4.58,-1.4) 14(-6.87,-1.4) 15(-9.16,-1.4)
  oval 1.092x2.896 hole 0.787x2.591: 16(-14.63,0.1) 17(5.47,0.1)
CLIP_SH1506X616
  custom 3.922x3.922 smd: 1(0,0)
CONCR_099BKAC19YBLCNF_19P
  round 0.813 hole 0.508: 1(0,0) 2(0.5,1.5) 3(1,0) 4(1.5,1.5) 5(2,0) 6(2.5,1.5) 7(3,0) 8(3.5,1.5) 9(4,0) 10(4.5,1.5) 11(5,0) 12(5.5,1.5) 13(6,0) 14(6.5,1.5) 15(7,0) 16(7.5,1.5) 17(8,0) 18(8.5,1.5) 19(9,0)
  oval 1.397x3.15 hole 0.787x2.54: 20(-2.75,0.9) 21(11.75,0.9)
  oval 1.803x2.794 hole 0.787x1.803: 22(-4.75,-6.08) 23(13.75,-6.08)
CSD87351Q5D_SON8-7
  oval 1.93x0.838 smd: 1(0,0)
  oval 0.66x0.838 smd: 2(1.905,0) 3(3.175,0) 4(3.175,5.39) 5(1.905,5.39) 6(0.635,5.39) 7(-0.635,5.39)
  custom 0.87x0.87 smd: 8(1.27,2.695)
CSD97374CQ4M_SON8_3P5X4P5
  oval 0.203x0.889 smd: 1(0,0) 2(0.4,0) 3(0.8,0) 6(0.8,3.5) 7(0.4,3.5) 8(0,3.5)
  custom 0.225x0.225 smd: 4(2.2,0.262) 5(2.2,3.238)
  rect 4.039x2.21 smd: 9(1.6,1.75)
CVILU_CF5006FD0R0-05-NH_6P
  oval 0.305x1.092 smd: 1(0,0) 2(0.5,0) 3(1,0) 4(1.5,0) 5(2,0) 6(2.5,0)
  rect 0.991x2.007 smd: 7(-2.1,-3.15) 8(4.6,-3.15)
CVILU_CF5020FD0RK-05-NH_20P-T
  oval 0.305x0.94 smd: 1(0,0) 2(0.5,0) 3(1,0) 4(1.5,0) 5(2,0) 6(2.5,0) 7(3,0) 8(3.5,0) 9(4,0) 10(4.5,0) 11(5,0) 12(5.5,0) 13(6,0) 14(6.5,0) 15(7,0) 16(7.5,0) 17(8,0) 18(8.5,0) 19(9,0) 20(9.5,0)
  rect 1.651x1.397 smd: 21(-2.325,-3.375) 22(11.825,-3.375)
CVILU_CF5026FD0RK-05-NH_26P-T
  oval 0.305x0.94 smd: 1(0,0) 2(0.5,0) 3(1,0) 4(1.5,0) 5(2,0) 6(2.5,0) 7(3,0) 8(3.5,0) 9(4,0) 10(4.5,0) 11(5,0) 12(5.5,0) 13(6,0) 14(6.5,0) 15(7,0) 16(7.5,0) 17(8,0) 18(8.5,0) 19(9,0) 20(9.5,0) 21(10,0) 22(10.5,0) 23(11,0) 24(11.5,0) 25(12,0) 26(12.5,0)
  rect 1.651x1.397 smd: 27(14.825,-3.375) 28(-2.325,-3.375)
CVILU_CI0805M1HRC-NH_5P-T
  round 1.803 hole 1.803 unplated: (-0.2,5.2) (8.2,5.2)
  oval 0.889x2.388 smd: 1(0,0) 2(2,0) 3(4,0) 4(6,0) 5(8,0)
  rect 1.6x2.489 smd: 6(11.15,9.05) 7(-3.15,9.05)
CVILU_CI1804M1VRA-NH_4P
  oval 0.508x0.991 smd: 1(0,-0.05) 2(-0.8,-0.05) 3(-1.6,-0.05) 4(-2.4,-0.05)
  rect 1.194x1.702 smd: 5(-3.7,1.4) 6(1.3,1.4)
CYNTE_PCMB103T-2R2MS_2P
  rect 3.81x3.988 smd: 1(0,0) 2(9.2,0)
DB3J315E0L_SMINI3-F2-B3
  oval 0.889x0.787 smd: 1(0,0) 2(-0.65,-1.9) 3(0.65,-1.9)
DDTA144VCA-7-F_SOT23-3
  oval 1.016x1.524 smd: 1(0,0) 2(0.965,2.083) 3(-0.965,2.083)
DEREN_40-42251-01001RHF_10P-T
  oval 0.838x2.21 smd: 1(0,0.1) 2(1.5,0.1) 3(3,0.1) 4(4.5,0.1) 5(6,0.1) 6(7.5,0.1) 7(9,0.1) 8(10.5,0.1) 9(12,0.1) 10(13.5,0.1)
  custom 0.75x0.75 smd: 11(-3.4,-3.15) 12(16.9,-3.15)
DMN65D8LDW-7_SOT363-6
  oval 0.432x0.61 smd: 1(0,0) 2(0.65,0) 3(1.3,0) 4(1.3,1.9) 5(0.65,1.9) 6(0,1.9)
DMN65D8LW-7_SOT323-3
  oval 0.711x0.889 smd: 1(0,0) 2(-0.65,-1.9) 3(0.65,-1.9)
DMN66D0LDW-7_SOT363-6
  oval 0.432x0.61 smd: 1(0,0) 2(0.65,0) 3(1.3,0) 4(1.3,1.9) 5(0.65,1.9) 6(0,1.9)
E-T_6705K-Y20N-00L_20P
  oval 0.305x1.092 smd: 1(0,0) 2(-0.5,0) 3(-1,0) 4(-1.5,0) 5(-2,0) 6(-2.5,0) 7(-3,0) 8(-3.5,0) 9(-4,0) 10(-4.5,0) 11(-5,0) 12(-5.5,0) 13(-6,0) 14(-6.5,0) 15(-7,0) 16(-7.5,0) 17(-8,0) 18(-8.5,0) 19(-9,0) 20(-9.5,0)
  rect 0.991x2.007 smd: 21(2.1,-3.15) 22(-11.6,-3.15)
ESD8011MUT5G_X3DFN2-2-S
  rect 0.33x0.356 smd: 1(0,0) 2(0.43,0)
FDMC6679AZ_MLP8-5
  oval 0.432x0.711 smd: 1(0,0) 2(0.65,0) 3(1.3,0) 4(1.95,0)
  custom 0.537x0.537 smd: 5(0.975,2.075)
FDV301N-G_SOT23-3
  oval 1.016x1.524 smd: 1(0,0) 2(0.965,2.083) 3(-0.965,2.083)
FIDUCIAL_C40M80
  round 1.016 smd: 1(0,0)
G524B1T11U_SOT23-5
  oval 0.533x1.194 smd: 1(0,0) 2(0.95,0) 3(1.9,0) 4(1.9,3) 5(0,3)
H_0P7N
  round 0.711 hole 0.711 unplated: (0,0)
H_0P9N
  round 0.889 hole 0.889 unplated: (0,0)
H_1P1N
  round 1.092 hole 1.092 unplated: (0,0)
H_2P2-G
  round 2.718 hole 2.21: 1(0,0)
H_2P3-G
  round 2.819 hole 2.311: 1(0,0)
H_2P5-G
  round 2.997 hole 2.489: 1(0,0)
H_2P6X3P6-G
  oval 3.099x4.115 hole 2.591x3.607: 1(0,0)
H_3P0-G
  round 3.505 hole 2.997: 1(0,0)
H_3P2
  round 3.708 hole 3.2: 1(0,0)
H_3P8
  round 4.318 hole 3.81: 1(0,0)
H_4P0-G
  round 4.496 hole 3.988: 1(0,0)
INPAQ_HCM1012GH900BP_4P
  rect 0.711x0.305 smd: 1(0,0) 2(1.25,0) 3(1.25,-0.5) 4(0,-0.5)
INPAQ_MCM1012B900F06BP_4P
  rect 0.711x0.305 smd: 1(0,0) 2(1.25,0) 3(1.25,-0.5) 4(0,-0.5)
ISL62883CHRTZ-T_TQFN40_5X5-S
  oval 0.203x0.991 smd: 1(0,0) 2(0.4,0) 3(0.8,0) 4(1.2,0) 5(1.6,0) 6(2,0) 7(2.4,0) 8(2.8,0) 9(3.2,0) 10(3.6,0) 21(3.6,4.95) 22(3.2,4.95) 23(2.8,4.95) 24(2.4,4.95) 25(2,4.95) 26(1.6,4.95) 27(1.2,4.95) 28(0.8,4.95) 29(0.4,4.95) 30(0,4.95)
  oval 0.991x0.203 smd: 11(4.275,0.675) 12(4.275,1.075) 13(4.275,1.475) 14(4.275,1.875) 15(4.275,2.275) 16(4.275,2.675) 17(4.275,3.075) 18(4.275,3.475) 19(4.275,3.875) 20(4.275,4.275) 31(-0.675,4.275) 32(-0.675,3.875) 33(-0.675,3.475) 34(-0.675,3.075) 35(-0.675,2.675) 36(-0.675,2.275) 37(-0.675,1.875) 38(-0.675,1.475) 39(-0.675,1.075) 40(-0.675,0.675)
  rect 3.505x3.505 smd: 41(1.8,2.475)
ISL88738HRTZ-T_TQFN32_4X4
  oval 0.889x0.203 smd: 1(0,0) 2(0,-0.4) 3(0,-0.8) 4(0,-1.2) 5(0,-1.6) 6(0,-2) 7(0,-2.4) 8(0,-2.8) 17(4.1,-2.8) 18(4.1,-2.4) 19(4.1,-2) 20(4.1,-1.6) 21(4.1,-1.2) 22(4.1,-0.8) 23(4.1,-0.4) 24(4.1,0)
  oval 0.203x0.889 smd: 9(0.65,-3.45) 10(1.05,-3.45) 11(1.45,-3.45) 12(1.85,-3.45) 13(2.25,-3.45) 14(2.65,-3.45) 15(3.05,-3.45) 16(3.45,-3.45) 25(3.45,0.65) 26(3.05,0.65) 27(2.65,0.65) 28(2.25,0.65) 29(1.85,0.65) 30(1.45,0.65) 31(1.05,0.65) 32(0.65,0.65)
  rect 2.692x2.692 smd: 33(2.05,-1.4)
ISL95808HRZ-TS2378_DFN8_2X2-S
  oval 0.254x0.787 smd: 1(0,0) 2(0.5,0) 3(1,0) 4(1.5,0) 5(1.5,2.2) 6(1,2.2) 7(0.5,2.2) 8(0,2.2)
  rect 1.549x0.889 smd: 9(0.75,1.1)
IT8010FN-BX-R_QFN20_4X4
  oval 0.889x0.254 smd: 1(0,0) 2(0,-0.5) 3(0,-1) 4(0,-1.5) 5(0,-2) 11(4.1,-2) 12(4.1,-1.5) 13(4.1,-1) 14(4.1,-0.5) 15(4.1,0)
  oval 0.254x0.889 smd: 6(1.05,-3.05) 7(1.55,-3.05) 8(2.05,-3.05) 9(2.55,-3.05) 10(3.05,-3.05) 16(3.05,1.05) 17(2.55,1.05) 18(2.05,1.05) 19(1.55,1.05) 20(1.05,1.05)
  rect 2.565x2.565 smd: 21(2.05,-1)
JAE_DX07BD24JJ2_24P-T
  oval 1.194x2.311 hole 0.61x1.905: 1(-1.695,-0.7) 2(6.945,-0.7)
  oval 1.651x1.092 hole 1.245x0.711: 3(-1.37,-1.3) 4(6.62,-1.3)
  custom 0.325x0.325 hole 0.711x1.499: 5(-3.225,-6) 6(8.475,-6)
  oval 0.279x0.889 smd: A1(0,0) A2(0.5,0) A3(1,0) A4(1.5,0) A5(2,0) A6(2.5,0) A7(3,0) A8(3.5,0) A9(4,0) A10(4.5,0) A11(5,0) A12(5.5,0)
  oval 0.279x0.787 smd: B1(5.25,-1.6) B2(4.75,-1.6) B3(4.25,-1.6) B4(3.75,-1.6) B5(3.25,-1.6) B6(2.75,-1.6) B7(2.25,-1.6) B8(1.75,-1.6) B9(1.25,-1.6) B10(0.75,-1.6) B11(0.25,-1.6) B12(-0.25,-1.6)
JUMP_43X39
  custom 0.191x0.191 smd: 1(0,0) 2(0.914,0)
JUMP_43X79
  custom 0.188x0.188 smd: 1(0,0) 2(1.1,0)
JUMP_43X118
  custom 0.187x0.187 smd: 1(0,0) 2(1.1,0)
JUMP_43X118-NPM
  custom 0.187x0.187 smd: 1(0,0) 2(1.1,0)
JXT_FP241AH-006GAAM_6P
  oval 0.305x0.965 smd: 1(0,0) 2(0.5,0) 3(1,0) 4(1.5,0) 5(2,0) 6(2.5,0)
  rect 0.305x1.143 smd: 7(-0.885,-2.965) 8(3.385,-2.965)
JXT_FP241AH-010GAAM_10P
  oval 0.305x1.092 smd: 1(0,0) 2(0.5,0) 3(1,0) 4(1.5,0) 5(2,0) 6(2.5,0) 7(3,0) 8(3.5,0) 9(4,0) 10(4.5,0)
  rect 0.406x0.787 smd: 11(-1,-2.65) 12(5.5,-2.65)
L2N7002WT1G_SC-70-3
  oval 0.711x0.889 smd: 1(0,0) 2(-0.65,-1.9) 3(0.65,-1.9)
L03ESDL5V0CC3-2_SOT23-3
  oval 1.016x1.524 smd: 1(0,0) 2(0.965,2.083) 3(-0.965,2.083)
L05ESDL5V0NA-4_SLP2510P8-10-9
  rect 0.203x0.686 smd: 1(0,0) 2(-0.5,0) 4(-1.5,0) 5(-2,0) 6(-2,-0.875) 7(-1.5,-0.875) 8(-0.5,-0.875) 9(0,-0.875)
  rect 0.406x1.549 smd: 3(-1,-0.437)
L30ESD24VC3-2_SOT23-3
  oval 1.016x1.524 smd: 1(0,0) 2(0.965,2.083) 3(-0.965,2.083)
L_5X5X3_M_2P
  rect 2.159x2.794 smd: 1(0,0) 2(4.35,0)
L_7X7X3_M
  custom 0.591x0.591 smd: 1(0,0) 4(6.05,0)
  rect 0.762x0.508 smd: 2(0.8,0) 3(5.25,0)
L_7X7X3_M_2P
  rect 2.362x3.505 smd: 1(0,0) 2(6.05,0)
LCN_DAN05-67356-0103_75P
  round 1.092 hole 1.092 unplated: (-0.75,-5.275)
  round 1.6 hole 1.6 unplated: (19.25,-5.275)
  oval 0.305x1.549 smd: 1(0,0) 2(0.25,-7.55) 3(0.5,0) 4(0.75,-7.55) 5(1,0) 6(1.25,-7.55) 7(1.5,0) 8(1.75,-7.55) 9(2,0) 10(2.25,-7.55) 11(2.5,0) 12(2.75,-7.55) 13(3,0) 14(3.25,-7.55) 15(3.5,0) 16(3.75,-7.55) 17(4,0) 18(4.25,-7.55) 19(4.5,0) 20(4.75,-7.55) 21(5,0) 22(5.25,-7.55) 23(5.5,0) 24(5.75,-7.55) 25(6,0) 26(6.25,-7.55) 27(6.5,0) 28(6.75,-7.55) 29(7,0) 30(7.25,-7.55) 31(7.5,0) 32(7.75,-7.55) 33(8,0) 34(8.25,-7.55) 35(8.5,0) 36(8.75,-7.55) 37(9,0) 38(9.25,-7.55) 39(9.5,0) 40(9.75,-7.55) 41(10,0) 42(10.25,-7.55) 43(10.5,0) 44(10.75,-7.55) 45(11,0) 46(11.25,-7.55) 47(11.5,0) 48(11.75,-7.55) 49(12,0) 50(12.25,-7.55) 51(12.5,0) 52(12.75,-7.55) 53(13,0) 54(13.25,-7.55) 55(13.5,0) 56(13.75,-7.55) 57(14,0) 58(14.25,-7.55) 67(16.5,0) 68(16.75,-7.55) 69(17,0) 70(17.25,-7.55) 71(17.5,0) 72(17.75,-7.55) 73(18,0) 74(18.25,-7.55) 75(18.5,0)
  rect 1.194x2.743 smd: 76(19.6,-0.775) 77(-1.1,-0.775)
LCN_DAN05-Q0406-0103_260P
  round 1.092 hole 1.092 unplated: (-67.775,-4.1)
  round 1.6 hole 1.6 unplated: (1.025,-4.1)
  oval 0.305x1.753 smd: 1(0,0) 2(-0.25,-8.2) 3(-0.5,0) 4(-0.75,-8.2) 5(-1,0) 6(-1.25,-8.2) 7(-1.5,0) 8(-1.75,-8.2) 9(-2,0) 10(-2.25,-8.2) 11(-2.5,0) 12(-2.75,-8.2) 13(-3,0) 14(-3.25,-8.2) 15(-3.5,0) 16(-3.75,-8.2) 17(-4,0) 18(-4.25,-8.2) 19(-4.5,0) 20(-4.75,-8.2) 21(-5,0) 22(-5.25,-8.2) 23(-5.5,0) 24(-5.75,-8.2) 25(-6,0) 26(-6.25,-8.2) 27(-6.5,0) 28(-6.75,-8.2) 29(-7,0) 30(-7.25,-8.2) 31(-7.5,0) 32(-7.75,-8.2) 33(-8,0) 34(-8.25,-8.2) 35(-8.5,0) 36(-8.75,-8.2) 37(-9,0) 38(-9.25,-8.2) 39(-9.5,0) 40(-9.75,-8.2) 41(-10,0) 42(-10.25,-8.2) 43(-10.5,0) 44(-10.75,-8.2) 45(-11,0) 46(-11.25,-8.2) 47(-11.5,0) 48(-11.75,-8.2) 49(-12,0) 50(-12.25,-8.2) 51(-12.5,0) 52(-12.75,-8.2) 53(-13,0) 54(-13.25,-8.2) 55(-13.5,0) 56(-13.75,-8.2) 57(-14,0) 58(-14.25,-8.2) 59(-14.5,0) 60(-14.75,-8.2) 61(-15,0) 62(-15.25,-8.2) 63(-15.5,0) 64(-15.75,-8.2) 65(-16,0) 66(-16.25,-8.2) 67(-16.5,0) 68(-16.75,-8.2) 69(-17,0) 70(-17.25,-8.2) 71(-17.5,0) 72(-17.75,-8.2) 73(-18,0) 74(-18.25,-8.2) 75(-18.5,0) 76(-18.75,-8.2) 77(-19,0) 78(-19.25,-8.2) 79(-19.5,0) 80(-19.75,-8.2) 81(-20,0) 82(-20.25,-8.2) 83(-20.5,0) 84(-20.75,-8.2) 85(-21,0) 86(-21.25,-8.2) 87(-21.5,0) 88(-21.75,-8.2) 89(-22,0) 90(-22.25,-8.2) 91(-22.5,0) 92(-22.75,-8.2) 93(-23,0) 94(-23.25,-8.2) 95(-23.5,0) 96(-23.75,-8.2) 97(-24,0) 98(-24.25,-8.2) 99(-24.5,0) 100(-24.75,-8.2) 101(-25,0) 102(-25.25,-8.2) 103(-25.5,0) 104(-25.75,-8.2) 105(-26,0) 106(-26.25,-8.2) 107(-26.5,0) 108(-26.75,-8.2) 109(-27,0) 110(-27.25,-8.2) 111(-27.5,0) 112(-27.75,-8.2) 113(-28,0) 114(-28.25,-8.2) 115(-28.5,0) 116(-28.75,-8.2) 117(-29,0) 118(-29.25,-8.2) 119(-29.5,0) 120(-29.75,-8.2) 121(-30,0) 122(-30.25,-8.2) 123(-30.5,0) 124(-30.75,-8.2) 125(-31,0) 126(-31.25,-8.2) 127(-31.5,0) 128(-31.75,-8.2) 129(-32,0) 130(-32.25,-8.2) 131(-32.5,0) 132(-32.75,-8.2) 133(-33,0) 134(-33.25,-8.2) 135(-33.5,0) 136(-33.75,-8.2) 137(-34,0) 138(-34.25,-8.2) 139(-34.5,0) 140(-34.75,-8.2) 141(-35,0) 142(-35.25,-8.2) 143(-35.5,0) 144(-35.75,-8.2) 145(-38,0) 146(-38.25,-8.2) 147(-38.5,0) 148(-38.75,-8.2) 149(-39,0) 150(-39.25,-8.2) 151(-39.5,0) 152(-39.75,-8.2) 153(-40,0) 154(-40.25,-8.2) 155(-40.5,0) 156(-40.75,-8.2) 157(-41,0) 158(-41.25,-8.2) 159(-41.5,0) 160(-41.75,-8.2) 161(-42,0) 162(-42.25,-8.2) 163(-42.5,0) 164(-42.75,-8.2) 165(-43,0) 166(-43.25,-8.2) 167(-43.5,0) 168(-43.75,-8.2) 169(-44,0) 170(-44.25,-8.2) 171(-44.5,0) 172(-44.75,-8.2) 173(-45,0) 174(-45.25,-8.2) 175(-45.5,0) 176(-45.75,-8.2) 177(-46,0) 178(-46.25,-8.2) 179(-46.5,0) 180(-46.75,-8.2) 181(-47,0) 182(-47.25,-8.2) 183(-47.5,0) 184(-47.75,-8.2) 185(-48,0) 186(-48.25,-8.2) 187(-48.5,0) 188(-48.75,-8.2) 189(-49,0) 190(-49.25,-8.2) 191(-49.5,0) 192(-49.75,-8.2) 193(-50,0) 194(-50.25,-8.2) 195(-50.5,0) 196(-50.75,-8.2) 197(-51,0) 198(-51.25,-8.2) 199(-51.5,0) 200(-51.75,-8.2) 201(-52,0) 202(-52.25,-8.2) 203(-52.5,0) 204(-52.75,-8.2) 205(-53,0) 206(-53.25,-8.2) 207(-53.5,0) 208(-53.75,-8.2) 209(-54,0) 210(-54.25,-8.2) 211(-54.5,0) 212(-54.75,-8.2) 213(-55,0) 214(-55.25,-8.2) 215(-55.5,0) 216(-55.75,-8.2) 217(-56,0) 218(-56.25,-8.2) 219(-56.5,0) 220(-56.75,-8.2) 221(-57,0) 222(-57.25,-8.2) 223(-57.5,0) 224(-57.75,-8.2) 225(-58,0) 226(-58.25,-8.2) 227(-58.5,0) 228(-58.75,-8.2) 229(-59,0) 230(-59.25,-8.2) 231(-59.5,0) 232(-59.75,-8.2) 233(-60,0) 234(-60.25,-8.2) 235(-60.5,0) 236(-60.75,-8.2) 237(-61,0) 238(-61.25,-8.2) 239(-61.5,0) 240(-61.75,-8.2) 241(-62,0) 242(-62.25,-8.2) 243(-62.5,0) 244(-62.75,-8.2) 245(-63,0) 246(-63.25,-8.2) 247(-63.5,0) 248(-63.75,-8.2) 249(-64,0) 250(-64.25,-8.2) 251(-64.5,0) 252(-64.75,-8.2) 253(-65,0) 254(-65.25,-8.2) 255(-65.5,0) 256(-65.75,-8.2) 257(-66,0) 258(-66.25,-8.2) 259(-66.5,0) 260(-66.75,-8.2)
  rect 3.505x4.597 smd: 261(0.425,7.9) 262(-67.175,7.9)
LED_LTW-C193DC-C_2P
  rect 0.787x0.787 smd: 1(0,0) 2(1.5,0)
LM393DGKR_VSSOP8
  oval 1.575x0.381 smd: 1(0,0) 2(0,-0.65) 3(0,-1.3) 4(0,-1.95) 5(4.35,-1.95) 6(4.35,-1.3) 7(4.35,-0.65) 8(4.35,0)
LNG2DMTR_LGA12_2X2
  oval 0.406x0.305 smd: 1(0,0) 4(0,-1.5) 7(1.602,-1.5) 10(1.602,0)
  oval 0.508x0.305 smd: 2(0.051,-0.5) 3(0.051,-1) 8(1.551,-1) 9(1.551,-0.5)
  oval 0.305x0.508 smd: 5(0.551,-1.5) 6(1.051,-1.5) 11(1.051,0) 12(0.551,0)
LOTES_AUSB0014-P003A_9P
  round 1.118 hole 0.711: 1(0,0) 2(-2.5,0) 3(-4.5,0) 4(-7,0) 5(-7.5,-1.5) 6(-5.5,-1.5) 7(-3.5,-1.5) 8(-1.5,-1.5) 9(0.5,-1.5)
  oval 1.549x2.769 hole 0.787x2.007: 10(-11.35,-1.59) 11(4.35,-1.59)
  oval 1.549x2.565 hole 0.787x1.803: 12(-11.35,-9.09) 13(4.35,-9.09)
LP2301ALT1G_SOT23-3
  oval 1.016x1.524 smd: 1(0,0) 2(0.965,2.083) 3(-0.965,2.083)
MAG_MLV-FY12N1R0M-O1L_2P
  rect 0.889x2.489 smd: 1(0,0) 2(2.6,0)
MAGLA_MMD-05CZ-1R0M-M7L_2P
  rect 1.905x2.794 smd: 1(0,0) 2(4.1,0)
MEC5105_WFBGA_169P
  round 0.343 smd: A1(0,0) A2(0.8,0) A3(1.6,0) A4(2.4,0) A5(3.2,0) A6(4,0) A7(4.801,0) A8(5.601,0) A9(6.401,0) A10(7.201,0) A11(8.001,0) A12(8.801,0) A13(9.601,0) B1(0,-0.8) B2(0.8,-0.8) B3(1.6,-0.8) B4(2.4,-0.8) B5(3.2,-0.8) B6(4,-0.8) B7(4.801,-0.8) B8(5.601,-0.8) B9(6.401,-0.8) B10(7.201,-0.8) B11(8.001,-0.8) B12(8.801,-0.8) B13(9.601,-0.8) C1(0,-1.6) C2(0.8,-1.6) C3(1.6,-1.6) C4(2.4,-1.6) C5(3.2,-1.6) C6(4,-1.6) C7(4.801,-1.6) C8(5.601,-1.6) C9(6.401,-1.6) C10(7.201,-1.6) C11(8.001,-1.6) C12(8.801,-1.6) C13(9.601,-1.6) D1(0,-2.4) D2(0.8,-2.4) D3(1.6,-2.4) D4(2.4,-2.4) D5(3.2,-2.4) D6(4,-2.4) D7(4.801,-2.4) D8(5.601,-2.4) D9(6.401,-2.4) D10(7.201,-2.4) D11(8.001,-2.4) D12(8.801,-2.4) D13(9.601,-2.4) E1(0,-3.2) E2(0.8,-3.2) E3(1.6,-3.2) E4(2.4,-3.2) E5(3.2,-3.2) E6(4,-3.2) E7(4.801,-3.2) E8(5.601,-3.2) E9(6.401,-3.2) E10(7.201,-3.2) E11(8.001,-3.2) E12(8.801,-3.2) E13(9.601,-3.2) F1(0,-4) F2(0.8,-4) F3(1.6,-4) F4(2.4,-4) F5(3.2,-4) F6(4,-4) F7(4.801,-4) F8(5.601,-4) F9(6.401,-4) F10(7.201,-4) F11(8.001,-4) F12(8.801,-4) F13(9.601,-4) G1(0,-4.801) G2(0.8,-4.801) G3(1.6,-4.801) G4(2.4,-4.801) G5(3.2,-4.801) G6(4,-4.801) G7(4.801,-4.801) G8(5.601,-4.801) G9(6.401,-4.801) G10(7.201,-4.801) G11(8.001,-4.801) G12(8.801,-4.801) G13(9.601,-4.801) H1(0,-5.601) H2(0.8,-5.601) H3(1.6,-5.601) H4(2.4,-5.601) H5(3.2,-5.601) H6(4,-5.601) H7(4.801,-5.601) H8(5.601,-5.601) H9(6.401,-5.601) H10(7.201,-5.601) H11(8.001,-5.601) H12(8.801,-5.601) H13(9.601,-5.601) J1(0,-6.401) J2(0.8,-6.401) J3(1.6,-6.401) J4(2.4,-6.401) J5(3.2,-6.401) J6(4,-6.401) J7(4.801,-6.401) J8(5.601,-6.401) J9(6.401,-6.401) J10(7.201,-6.401) J11(8.001,-6.401) J12(8.801,-6.401) J13(9.601,-6.401) K1(0,-7.201) K2(0.8,-7.201) K3(1.6,-7.201) K4(2.4,-7.201) K5(3.2,-7.201) K6(4,-7.201) K7(4.801,-7.201) K8(5.601,-7.201) K9(6.401,-7.201) K10(7.201,-7.201) K11(8.001,-7.201) K12(8.801,-7.201) K13(9.601,-7.201) L1(0,-8.001) L2(0.8,-8.001) L3(1.6,-8.001) L4(2.4,-8.001) L5(3.2,-8.001) L6(4,-8.001) L7(4.801,-8.001) L8(5.601,-8.001) L9(6.401,-8.001) L10(7.201,-8.001) L11(8.001,-8.001) L12(8.801,-8.001) L13(9.601,-8.001) M1(0,-8.801) M2(0.8,-8.801) M3(1.6,-8.801) M4(2.4,-8.801) M5(3.2,-8.801) M6(4,-8.801) M7(4.801,-8.801) M8(5.601,-8.801) M9(6.401,-8.801) M10(7.201,-8.801) M11(8.001,-8.801) M12(8.801,-8.801) M13(9.601,-8.801) N1(0,-9.601) N2(0.8,-9.601) N3(1.6,-9.601) N4(2.4,-9.601) N5(3.2,-9.601) N6(4,-9.601) N7(4.801,-9.601) N8(5.601,-9.601) N9(6.401,-9.601) N10(7.201,-9.601) N11(8.001,-9.601) N12(8.801,-9.601) N13(9.601,-9.601)
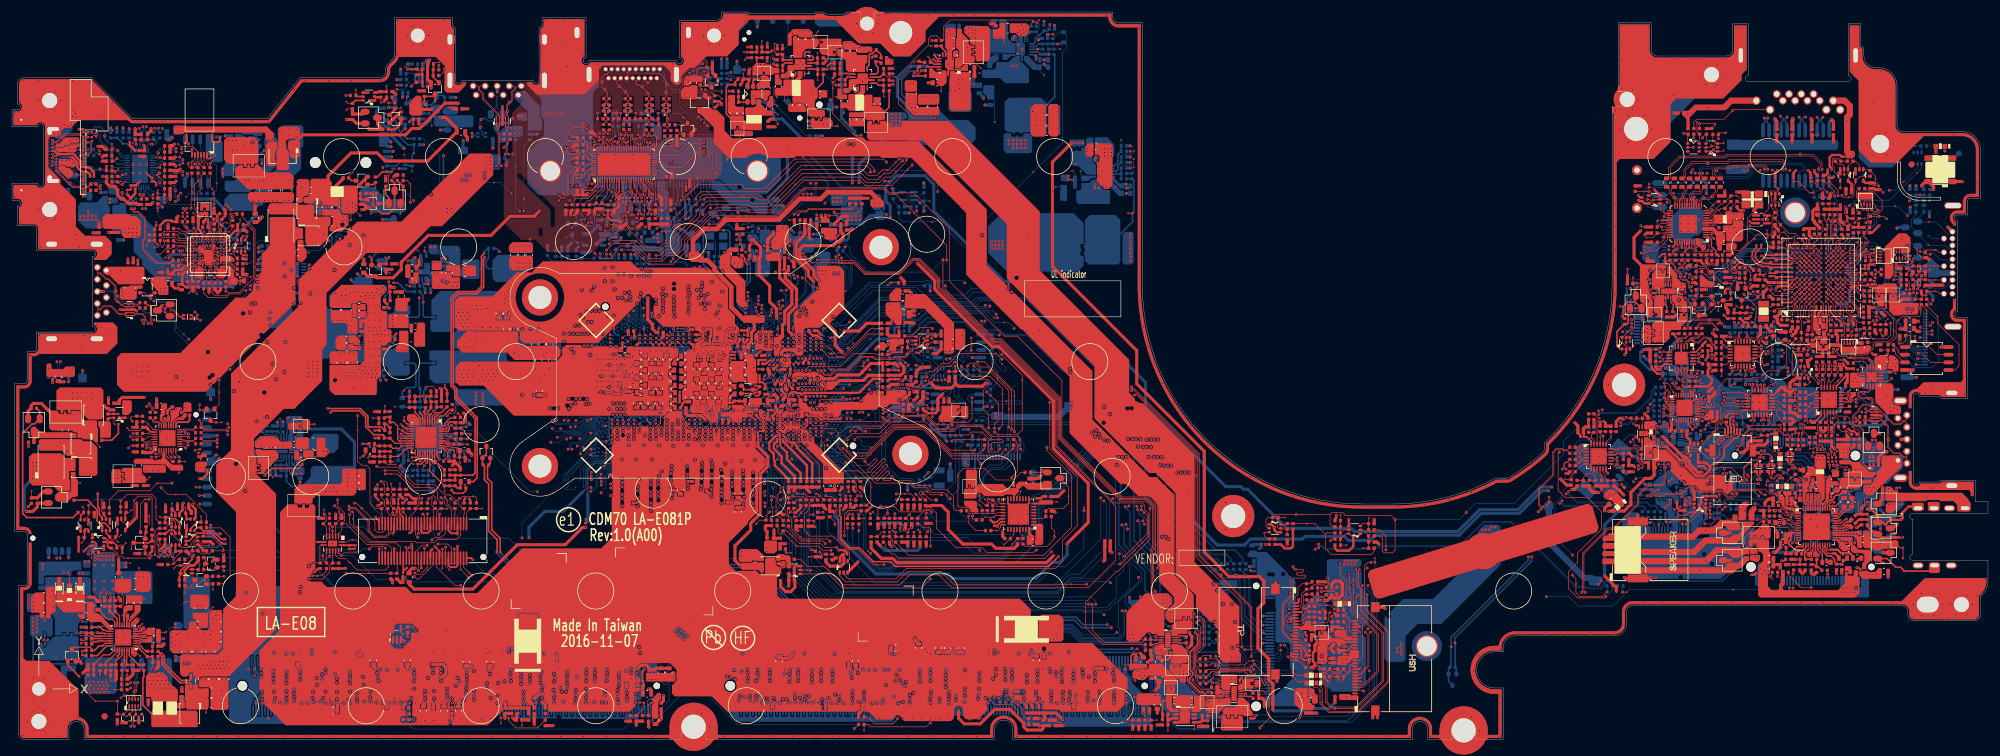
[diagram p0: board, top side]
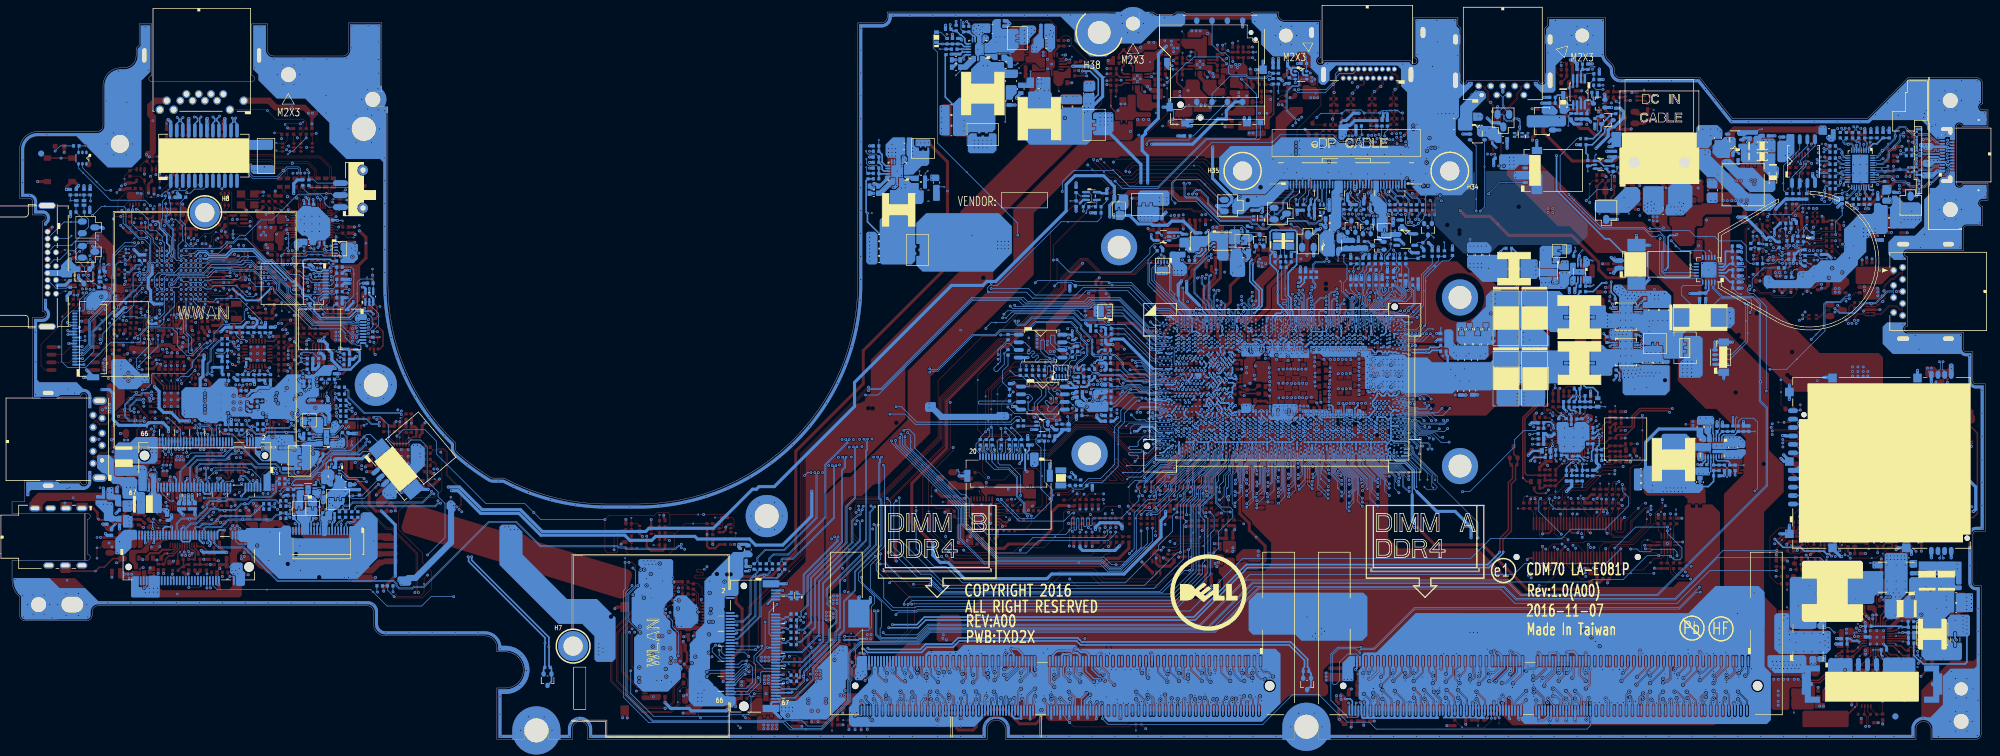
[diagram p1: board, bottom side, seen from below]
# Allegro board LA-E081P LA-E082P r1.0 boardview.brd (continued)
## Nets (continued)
+3.3V_RUN: CA7.1 CC30.1 CN1.1 CN2.1 CN3.1 CN20.1 CN21.1 CN30.1 CN31.1 CV80.1 CV81.1 CV82.1 CV83.1 CV84.1 CV85.1 CV100.1 CV106.1 CZ67.1 CZ72.1 JEDP1.10 JESPI.1 JESPI.2 JUSH1.19 LGA1.2 LGA1.3 LGA1.9 LGA1.10 LV14.1 LV30.1 PJP14.1 PJP18.1 PJP31.2 PJP34.1 PJP35.1 PJP39.2 PR612.1 QC2.2 QC2.5 QV3.2 QV3.5 QV5.2 QZ1.3 RC13.2 RC27.2 RC47.2 RC50.2 RC51.2 RC59.2 RC137.2 RC175.2 RC176.2 RC177.2 RC178.2 RC186.2 RC189.2 RC190.2 RC225.2 RC237.2 RC267.2 RC272.2 RC278.2 RC279.2 RC282.2 RC287.2 RC291.2 RC292.2 RC318.2 RC319.2 RC345.2 RC370.2 RC402.2 RC403.2 RC404.2 RC413.2 RC414.2 RD4.1 RD6.1 RD8.1 RD10.1 RD19.2 RD20.1 RD22.1 RD24.1 RD26.1 RE48.1 RE51.1 RE67.2 RI79.1 RN2.1 RN4.1 RN25.1 RN26.1 RN27.1 RN28.1 RN42.1 RN43.1 RN44.1 RN49.1 RN50.1 RN51.1 RN55.1 RN56.1 RN57.1 RN58.1 RN63.1 RN64.1 RN65.1 RN69.1 RN70.1 RN71.1 RN171.1 RPC4.5 RPC4.6 RPC4.7 RPC4.8 RT397.1 RV8.2 RV18.1 RV19.2 RV20.2 RV70.2 RV71.2 RV72.2 RV79.2 RV81.2 RV83.2 RV85.2 RV87.2 RV89.2 RV91.2 RV93.2 RV95.2 RV106.2 RV107.2 RV124.1 RZ89.1 RZ362.1 UC8.14 UC12.5 UN4.12 UN4.24 UN5.12 UN5.24 UV6.14 UV6.26 UV7.1 UV7.10 UV7.34 UZ5.6 UZ5.7
+3.3V_RUN_AUDIO: CA67.1 CA68.1 LA12.2 LA14.2 PJP16.2 PJP18.2 RA18.2 RA59.1 RA61.1
+3.3V_RUN_AUDIO_DVDD: CA10.1 CA61.1 LA14.1 UA1.1
+3.3V_RUN_AUDIO_IO: CA55.1 CA56.1 LA12.1 UA1.9
+3.3V_RUN_AUDIO_UZ5: CZ128.1 PJP16.1 UZ5.8 UZ5.9
+3.3V_RUN_CARD: CR17.2 CR18.2 JSD1.4 UR1.12
+3.3V_RUN_DIMM1: CD27.1 CD28.1 JDIMM1.255 RD10.2
+3.3V_RUN_DIMM2: CD59.1 CD60.1 JDIMM2.255 RD26.2
+3.3V_RUN_UT9: LT11.1 RT131.2 RT135.2 RT137.2 RT139.2 RT141.2 RT143.2 RT145.2 RT247.2 RT308.2 RT397.2 RT398.2
+3.3V_RUN_UZ3: CZ115.1 PJP39.1 UZ3.8 UZ3.9
+3.3V_SPI: CC9.1 CC10.1 JSPI1.6 RC30.2 RC31.2 RC41.2 UC1.AJ16 UC5.8 UC6.8
+3.3V_TBTA_FLASH: CT70.1 CT84.1 JDB1.1 RT50.1 RT51.1 RT52.1 RT53.1 RT66.2 RT67.2 RT76.2 RT95.2 RT98.2 RT106.2 RT107.2 RT378.2 RT379.2 UT5.G1 UT6.8
+3.3V_TP: CZ83.1 CZ90.1 JKBTP1.9 PJP35.2 RZ18.1 RZ19.1 RZ20.1 RZ21.1 RZ116.1 RZ117.1
+3.3V_USB_UI5: CI37.1 CI38.1 RI79.2 RI80.2 UI5.1 UI5.13
+3.3V_VCCHDA: CC313.1 CC324.1 LC1.2 UC1.AJ19
+3.3V_VDD_DCIN: PC9.1 PC10.1 PD1801.3 PR17.1 PR27.2 PR1206.1 PR1208.1 PU1.5 PU2.3
+3.3V_VDD_PIC: CT91.1 CT92.1 PC1204.1 PD1801.2 PJP7.1 PR1214.1 PR1226.1 PR1236.2 PR1237.1 PR1240.1 PR1253.1 PR1254.2 PU1200.5 QT1.2 QT1.5 RT398.1 UT7.5
+3.3V_VDD_PIC_PDA: CT74.1 PJP7.2 UT5.B1 UT5.H1
+3.3V_VGA: LV14.2 UV6.1
+3.3V_WLAN: CZ27.1 CZ28.1 CZ29.1 CZ30.1 CZ31.1 CZ32.1 CZ33.1 CZ34.1 CZ35.1 CZ36.1 JNGFF1.2 JNGFF1.4 JNGFF1.64 JNGFF1.66 PJP36.2
+3.3V_WLAN_UZ4: CZ122.1 PJP36.1 UZ4.8 UZ4.9
+3.3V_WWAN: CZ17.1 CZ18.1 CZ19.1 CZ20.1 CZ21.1 CZ23.1 CZ24.1 CZ25.1 CZ26.1 CZ133.1 CZ134.1 JNGFF2.2 JNGFF2.4 JNGFF2.62 JNGFF2.64 JNGFF2.66 PJP41.2 RZ43.2 RZ154.1 RZ156.1 RZ158.1 RZ160.1 RZ162.1 RZ164.1 RZ166.1 RZ354.1 RZ356.1 RZ358.1 RZ360.1 UZ36.12 UZ36.24
+3.3V_WWAN_UZ2: CZ119.1 CZ124.1 PJP41.1 UZ2.13 UZ2.14
+5V_ALW: CI6.1 CI7.1 CI11.1 CI12.1 CI19.1 CI31.1 CI33.1 CI34.1 CZ64.1 CZ69.1 DT1.2 JLED1.1 JUART1.1 JUSH1.18 LED3.2 PC661.1 PC677.1 PC685.1 PJP8.1 PJP103.2 PJP403.1 PJP404.1 PR7.1 PR602.2 PU602.9 PU602.10 PU610.2 PU612.2 PU614.6 RA53.2 RI13.2 UI1.5 UI2.5 UI3.1 UI3.7 UI3.8 UZ2.4 UZ3.4 UZ4.1 UZ4.2 UZ4.4 UZ5.4 UZ8.4 UZ19.3 UZ21.3 UZ23.1 UZ23.2 UZ23.4 UZ26.3
+5V_ALW2: PC126.1 PU102.15
+5V_ALW_PDA: CT75.1 CT76.1 CT77.1 CT78.1 PJP8.2 UT5.A11 UT5.B11 UT5.C11 UT5.D11 UT5.H10
+5V_ALWP: PC120.1 PC121.1 PC122.1 PC123.1 PC124.1 PC130.1 PJP103.1 PL101.2 PR117.2 PU102.14
+5V_HDD: CN8.1 CN9.1 JSATA1.15 JSATA1.16 JSATA1.17 PJP32.2 PJP33.1 RN1.1
+5V_HDD_UZ23: CZ129.1 PJP32.1 UZ23.7 UZ23.8
+5V_PD_VDD: CT88.1 CT89.1 DT1.1 DT2.1 RT111.1 RT393.1 UT7.1
+5V_RUN: CE32.1 CV39.1 CZ66.1 CZ71.1 CZ92.1 DE1.1 JFAN1.4 JKBTP1.16 JUSH1.20 PJP17.1 PJP33.2 PJP40.2 QV8.3 RV6.2 UV2.1 UV4.1 UZ5.1 UZ5.2
+5V_RUN_AUDIO: CA59.1 CA60.1 CA63.1 CA64.1 LA5.2 LA13.2 PJP15.1 PJP17.2
+5V_RUN_AUDIO_UZ5: CZ125.1 PJP15.2 UZ5.13 UZ5.14
+5V_RUN_PVDD_L: CA45.1 CA46.1 CA47.1 CA48.1 LA13.1 UA1.41 UA1.46
+5V_RUN_UZ4: CZ116.1 PJP40.1 UZ4.13 UZ4.14
+5V_TBT_VBUS: CT93.1 DT2.2 DT3.1
+5V_TBTA_VBUS_D: DT3.2 UT8.3
+5V_TSP: CV18.1 CV19.1 CZ2.1 JEDP1.1 QV8.1
+5V_USB_CHG_PWR: CI14.1 CI17.1 CI32.1 CI43.1 CI44.1 JUSB1.1 UI3.12
+DV33_18: CR22.1 UR1.18
+GND_CHASSIS: CL22.2 RL15.2 RL16.2 RL17.2 RL18.2
+VBUS_DC_SS: PD903.2 PD1202.2 PD1202.3 PQ1202.5 PQ1213.5
+VCC1V8A_TBTA_LDO: CT73.1 UT5.K1
+VCC1V8D_TBTA_LDO: CT72.1 RT97.1 UT5.A2
+VCC_1P8: CC222.1 RC313.2 UC1.U11 UC1.U12
+VCC_CORE: PC1001.1 PC1002.1 PC1003.1 PC1004.1 PC1005.1 PC1006.1 PC1007.1 PC1008.1 PC1009.1 PC1010.1 PC1011.1 PC1012.1 PC1013.1 PC1030.1 PC1031.1 PC1032.1 PC1033.1 PC1034.1 PC1035.1 PC1036.1 PC1037.1 PC1038.1 PC1039.1 PC1050.1 PC1051.1 PC1052.1 PC1053.1 PC1054.1 PC1061.1 PC1062.1 PC1064.1 PC1065.1 PC1066.1 PC1067.1 PC1068.1 PC1069.1 PC1070.1 PC1071.1 PC1072.1 PC1073.1 PC1074.1 PC1075.1 PC1076.1 PC1077.1 PC1078.1 PC1079.1 PC1080.1 PC1081.1 PC1082.1 PC1083.1 PC1084.1 PC1085.1 PC1086.1 PC1087.1 PC1088.1 PC1089.1 PC1090.1 PC1091.1 PC1092.1 PC1093.1 PC1094.1 PC1095.1 PC1096.1 PC1097.1 PC1098.1 PC1099.1 PC1125.1 PC1126.1 PC1127.1 PC1164.1 PC1170.1 PC1171.1 PC1172.1 PC1173.1 PC1174.1 PL610.1 RC140.2 UC1.A30 UC1.A34 UC1.A39 UC1.A44 UC1.AK33 UC1.AK35 UC1.AK37 UC1.AK38 UC1.AK40 UC1.AL33 UC1.AL37 UC1.AL40 UC1.AM32 UC1.AM33 UC1.AM35 UC1.AM37 UC1.AM38 UC1.G30 UC1.G32 UC1.G33 UC1.G35 UC1.G37 UC1.G38 UC1.G40 UC1.G42 UC1.J30 UC1.J33 UC1.J37 UC1.J40 UC1.K33 UC1.K35 UC1.K37 UC1.K38 UC1.K40 UC1.K42 UC1.K43
+VCC_CORE_G0: T122.1(TP-1) UC1.K32
+VCC_CORE_G1: T123.1(TP-1) UC1.AK32
+VCC_GT: PC1014.1 PC1015.1 PC1016.1 PC1017.1 PC1018.1 PC1019.1 PC1020.1 PC1021.1 PC1022.1 PC1023.1 PC1024.1 PC1025.1 PC1026.1 PC1027.1 PC1028.1 PC1029.1 PC1040.1 PC1041.1 PC1042.1 PC1043.1 PC1044.1 PC1045.1 PC1046.1 PC1047.1 PC1048.1 PC1049.1 PC1055.1 PC1056.1 PC1063.1 PC1128.1 PC1129.1 PC1130.1 PC1131.1 PC1132.1 PC1133.1 PC1134.1 PC1135.1 PC1136.1 PC1137.1 PC1138.1 PC1175.1 PC1176.1 PC1177.1 PC1178.1 PC1179.1 PC1180.1 PC1181.1 PL612.1 RC161.2 UC1.A48 UC1.A53 UC1.A58 UC1.A62 UC1.A66 UC1.AA63 UC1.AA64 UC1.AA66 UC1.AA67 UC1.AA69 UC1.AA70 UC1.AA71 UC1.AC64 UC1.AC65 UC1.AC66 UC1.AC67 UC1.AC68 UC1.AC69 UC1.AC70 UC1.AC71 UC1.J43 UC1.J45 UC1.J46 UC1.J48 UC1.J50 UC1.J52 UC1.J53 UC1.J55 UC1.J56 UC1.J58 UC1.J60 UC1.K48 UC1.K50 UC1.K52 UC1.K53 UC1.K55 UC1.K56 UC1.K58 UC1.K60 UC1.L62 UC1.L63 UC1.L64 UC1.L65 UC1.L66 UC1.L67 UC1.L68 UC1.L69 UC1.L70 UC1.L71 UC1.M62 UC1.N63 UC1.N64 UC1.N66 UC1.N67 UC1.N69 UC1.N70 UC1.N71 UC1.R63 UC1.R64 UC1.R65 UC1.R66 UC1.R67 UC1.R68 UC1.R69 UC1.R70 UC1.R71 UC1.T62 UC1.U65 UC1.U68 UC1.U71 UC1.W63 UC1.W64 UC1.W65 UC1.W66 UC1.W67 UC1.W68 UC1.W69 UC1.W70 UC1.W71 UC1.Y62
+VCC_GTUS: UC1.AK42 UC1.AK43 UC1.AK45 UC1.AK46 UC1.AK48 UC1.AK50 UC1.AK52 UC1.AK53 UC1.AK55 UC1.AK56 UC1.AK58 UC1.AK60 UC1.AL43 UC1.AL46 UC1.AL50 UC1.AL53 UC1.AL56 UC1.AL60 UC1.AM48 UC1.AM50 UC1.AM52 UC1.AM53 UC1.AM56 UC1.AM58
+VCC_SA: PC633.2 PC637.2 PC644.1 PC1057.1 PC1058.1 PC1059.1 PC1060.1 PC1139.1 PC1140.1 PC1141.1 PC1142.1 PC1143.1 PC1144.1 PC1145.1 PC1146.1 PC1147.1 PC1148.1 PC1149.1 PC1150.1 PC1151.1 PC1152.1 PC1153.1 PH604.2 PL614.1 PR636.2 PR641.2 PR643.1 RC168.1 UC1.AK23 UC1.AK25 UC1.G23 UC1.G25 UC1.G27 UC1.G28 UC1.J22 UC1.J23 UC1.J27 UC1.K23 UC1.K25 UC1.K27 UC1.K28 UC1.K30
+VCC_SFR_OC: CC288.1 CC322.1 CZ103.1 RZ119.2 UC1.AL23 UZ26.6
+VCCK_12: CV103.1 CV104.1 CV105.1 UV6.4 UV6.25
+VDD_DAC_33: LV30.2 UV6.20
+VDDA_AVDD1: CA8.1 CA9.1 LA5.1 UA1.26
+VSS_PLL: CE17.2 CE18.2 UE1.G1
GND: CA5.2 CA6.2 CA7.2 CA10.2 CA12.2 CA13.1 CA19.2 CA22.2 CA23.2 CA24.2 CA31.2 CA33.2 CA45.2 CA46.2 CA47.2 CA48.2 CA49.2 CA53.2 CA54.2 CA55.2 CA56.2 CA59.2 CA60.2 CA61.2 CA62.2 CA63.2 CA64.2 CA65.2 CA66.2 CA67.2 CA68.2 CA69.2 CA72.2 CC7.2 CC8.2 CC9.2 CC10.2 CC21.2 CC22.2 CC23.2 CC24.2 CC25.2 CC26.2 CC27.2 CC28.2 CC29.2 CC30.2 CC32.2 CC33.2 CC176.2 CC177.2 CC178.2 CC179.2 CC195.2 CC199.2 CC202.2 CC203.2 CC204.2 CC205.2 CC206.2 CC207.2 CC208.2 CC209.2 CC210.2 CC211.2 CC212.2 CC213.2 CC214.2 CC215.2 CC216.2 CC217.2 CC218.2 CC219.2 CC220.2 CC221.2 CC222.2 CC223.2 CC224.2 CC225.2 CC226.2 CC250.2 CC251.2 CC252.2 CC253.2 CC264.2 CC265.2 CC266.2 CC269.2 CC270.2 CC279.2 CC280.2 CC281.2 CC288.2 CC294.2 CC295.2 CC296.2 CC297.2 CC300.2 CC301.2 CC302.2 CC303.2 CC304.2 CC305.2 CC306.2 CC307.2 CC308.2 CC310.2 CC312.2 CC313.2 CC314.2 CC316.2 CC318.2 CC319.2 CC320.2 CC321.2 CC322.2 CC323.2 CC324.2 CC325.2 CC326.2 CC331.2 CC332.2 CC333.2 CD1.2 CD2.2 CD3.2 CD4.2 CD5.2 CD6.2 CD7.2 CD8.2 CD9.2 CD10.2 CD11.2 CD12.2 CD13.2 CD14.2 CD15.2 CD16.2 CD17.2 CD18.2 CD19.2 CD20.2 CD21.2 CD22.2 CD23.2 CD24.2 CD25.2 CD26.2 CD27.2 CD28.2 CD29.2 CD32.2 CD33.2 CD34.2 CD35.2 CD36.2 CD37.2 CD38.2 CD39.2 CD40.2 CD41.2 CD42.2 CD43.2 CD44.2 CD45.2 CD46.2 CD47.2 CD48.2 CD49.2 CD50.2 CD51.2 CD52.2 CD53.2 CD54.2 CD55.2 CD56.2 CD57.2 CD58.2 CD59.2 CD60.2 CD61.2 CE1.2 CE2.2 CE3.2 CE4.2 CE5.2 CE6.2 CE8.2 CE10.2 CE11.2 CE12.2 CE13.2 CE14.2 CE15.2 CE16.2 CE19.2 CE20.2 CE21.2 CE22.2 CE23.2 CE25.2 CE28.2 CE29.2 CE30.2 CE31.2 CE32.2 CE36.2 CE38.2 CE40.2 CE47.2 CE52.2 CE53.2 CE54.2 CE57.2 CE59.2 CE60.2 CE61.2 CE62.2 CE500.2 CE503.2 CE504.2 CE505.2 CI1.2 CI3.2 CI6.2 CI7.2 CI8.2 CI10.2 CI11.2 CI12.2 CI14.2 CI17.2 CI19.2 CI31.2 CI32.2 CI33.2 CI34.2 CI37.2 CI38.2 CI43.2 CI44.2 CI45.2 CI46.2 CI47.2 CI48.2 CL3.2 CL4.2 CL7.2 CL8.2 CL9.2 CL10.2 CL11.2 CL12.2 CL13.2 CL14.2 CL15.2 CL16.2 CL17.2 CL18.2 CL19.2 CL20.2 CL21.2 CL22.1 CL28.2 CL29.2 CL30.2 CMOS1.2 CN1.2 CN2.2 CN3.2 CN8.2 CN9.2 CN10.2 CN11.2 CN16.2 CN17.2 CN20.2 CN21.2 CN30.2 CN31.2 CN60.2 CN61.2 CN62.2 CN63.2 CN64.2 CR1.2 CR2.2 CR3.2 CR4.2 CR5.2 CR6.2 CR7.2 CR15.2 CR17.1 CR18.1 CR19.1 CR20.1 CR21.2 CR22.2 CR25.2 CR26.2 CR27.2 CR28.2 CT70.2 CT71.2 CT72.2 CT73.2 CT74.2 CT75.2 CT76.2 CT77.2 CT78.2 CT82.2 CT83.2 CT84.2 CT85.2 CT86.2 CT87.2 CT88.2 CT89.2 CT90.2 CT91.2 CT92.2 CT93.2 CT94.2 CT99.2 CT100.2 CT101.2 CT102.2 CT117.2 CT118.2 CT119.2 CT120.2 CT121.2 CT122.2 CT189.2 CT190.2 CV11.2 CV12.2 CV14.2 CV15.2 CV16.2 CV17.2 CV18.2 CV19.2 CV20.2 CV21.2 CV22.2 CV23.2 CV24.2 CV25.2 CV39.2 CV40.2 CV41.2 CV80.2 CV81.2 CV82.2 CV83.2 CV84.2 CV85.2 CV96.2 CV100.2 CV101.2 CV102.2 CV103.2 CV104.2 CV105.2 CV106.2 CV126.2 CV127.2 CV128.2 CV129.2 CV130.2 CV131.2 CV132.2 CV133.2 CV134.2 CV135.2 CZ1.2 CZ2.2 CZ3.2 CZ17.2 CZ18.2 CZ19.2 CZ20.2 CZ21.2 CZ23.2 CZ24.2 CZ25.2 CZ26.2 CZ27.2 CZ28.2 CZ29.2 CZ30.2 CZ31.2 CZ32.2 CZ33.2 CZ34.2 CZ35.2 CZ36.2 CZ37.2 CZ39.2 CZ40.2 CZ41.2 CZ50.2 CZ51.2 CZ52.2 CZ53.2 CZ54.2 CZ55.2 CZ56.2 CZ57.2 CZ58.2 CZ59.2 CZ60.2 CZ61.2 CZ62.2 CZ63.2 CZ64.2 CZ66.2 CZ67.2 CZ68.2 CZ69.2 CZ71.2 CZ72.2 CZ73.2 CZ75.2 CZ80.2 CZ81.2 CZ82.2 CZ83.2 CZ84.2 CZ85.2 CZ86.2 CZ87.2 CZ88.2 CZ89.2 CZ90.2 CZ91.2 CZ92.2 CZ93.2 CZ100.2 CZ101.2 CZ102.2 CZ103.2 CZ104.2 CZ105.2 CZ106.2 CZ109.2 CZ110.2 CZ111.2 CZ112.2 CZ113.2 CZ114.2 CZ115.2 CZ116.2 CZ117.2 CZ118.2 CZ119.2 CZ120.2 CZ121.2 CZ122.2 CZ124.2 CZ125.2 CZ126.2 CZ127.2 CZ128.2 CZ129.2 CZ130.2 CZ133.2 CZ134.2 CZ197.2 CZ198.2 DA1.1 DA2.1 DA3.1 DA6.1 DA7.1 DE1.2 DI1.3 DI2.1 DI3.1 DI4.3 DI5.1 DI6.3 DT4.1 DT5.2 DT6.2 DT7.2 DT8.2 DT9.2 DT10.2 DT11.2 DT12.2 DT13.2 DT14.2 DT15.2 DT16.2 DT17.2 DT18.2 DT19.2 DT20.2 DV4.1 DV5.1 DV6.1 H1.1(TP-1) H2.1(TP-1) H3.1(TP-1) H4.1(TP-1) H7.1(TP-1) H8.1(TP-1) H9.1(TP-1) H10.1(TP-1) H12.1(TP-1) H14.1(TP-1) H15.1(TP-1) H16.1(TP-1) H17.1(TP-1) H18.1(TP-1) H20.1(TP-1) H22.1(TP-1) H23.1(TP-1) H24.1(TP-1) H25.1(TP-1) H26.1(TP-1) H28.1(TP-1) H29.1(TP-1) H32.1(TP-1) H34.1(TP-1) H35.1(TP-1) H38.1(TP-1) JAPS1.8 JAPS1.10 JAPS1.12 JAPS1.14 JAPS1.19 JAPS1.20 JCRT1.5 JCRT1.6 JCRT1.7 JCRT1.8 JCRT1.10 JCRT1.16 JCRT1.17 JDB1.6 JDB1.7 JDB1.8 JDEG1.10 JDEG1.11 JDEG1.12 JDIMM1.1 JDIMM1.2 JDIMM1.5 JDIMM1.6 JDIMM1.9 JDIMM1.10 JDIMM1.14 JDIMM1.15 JDIMM1.18 JDIMM1.19 JDIMM1.22 JDIMM1.23 JDIMM1.26 JDIMM1.27 JDIMM1.30 JDIMM1.31 JDIMM1.35 JDIMM1.36 JDIMM1.39 JDIMM1.40 JDIMM1.43 JDIMM1.44 JDIMM1.47 JDIMM1.48 JDIMM1.51 JDIMM1.52 JDIMM1.56 JDIMM1.57 JDIMM1.60 JDIMM1.61 JDIMM1.64 JDIMM1.65 JDIMM1.68 JDIMM1.69 JDIMM1.72 JDIMM1.73 JDIMM1.77 JDIMM1.78 JDIMM1.81 JDIMM1.82 JDIMM1.85 JDIMM1.86 JDIMM1.89 JDIMM1.90 JDIMM1.93 JDIMM1.94 JDIMM1.98 JDIMM1.99 JDIMM1.102 JDIMM1.103 JDIMM1.106 JDIMM1.107 JDIMM1.167 JDIMM1.168 JDIMM1.171 JDIMM1.172 JDIMM1.175 JDIMM1.176 JDIMM1.180 JDIMM1.181 JDIMM1.184 JDIMM1.185 JDIMM1.188 JDIMM1.189 JDIMM1.192 JDIMM1.193 JDIMM1.196 JDIMM1.197 JDIMM1.201 JDIMM1.202 JDIMM1.205 JDIMM1.206 JDIMM1.209 JDIMM1.210 JDIMM1.213 JDIMM1.214 JDIMM1.217 JDIMM1.218 JDIMM1.222 JDIMM1.223 JDIMM1.226 JDIMM1.227 JDIMM1.230 JDIMM1.231 JDIMM1.234 JDIMM1.235 JDIMM1.238 JDIMM1.239 JDIMM1.243 JDIMM1.244 JDIMM1.247 JDIMM1.248 JDIMM1.251 JDIMM1.252 JDIMM1.261 JDIMM1.262 JDIMM2.1 JDIMM2.2 JDIMM2.5 JDIMM2.6 JDIMM2.9 JDIMM2.10 JDIMM2.14 JDIMM2.15 JDIMM2.18 JDIMM2.19 JDIMM2.22 JDIMM2.23 JDIMM2.26 JDIMM2.27 JDIMM2.30 JDIMM2.31 JDIMM2.35 JDIMM2.36 JDIMM2.39 JDIMM2.40 JDIMM2.43 JDIMM2.44 JDIMM2.47 JDIMM2.48 JDIMM2.51 JDIMM2.52 JDIMM2.56 JDIMM2.57 JDIMM2.60 JDIMM2.61 JDIMM2.64 JDIMM2.65 JDIMM2.68 JDIMM2.69 JDIMM2.72 JDIMM2.73 JDIMM2.77 JDIMM2.78 JDIMM2.81 JDIMM2.82 JDIMM2.85 JDIMM2.86 JDIMM2.89 JDIMM2.90 JDIMM2.93 JDIMM2.94 JDIMM2.98 JDIMM2.99 JDIMM2.102 JDIMM2.103 JDIMM2.106 JDIMM2.107 JDIMM2.167 JDIMM2.168 JDIMM2.171 JDIMM2.172 JDIMM2.175 JDIMM2.176 JDIMM2.180 JDIMM2.181 JDIMM2.184 JDIMM2.185 JDIMM2.188 JDIMM2.189 JDIMM2.192 JDIMM2.193 JDIMM2.196 JDIMM2.197 JDIMM2.201 JDIMM2.202 JDIMM2.205 JDIMM2.206 JDIMM2.209 JDIMM2.210 JDIMM2.213 JDIMM2.214 JDIMM2.217 JDIMM2.218 JDIMM2.222 JDIMM2.223 JDIMM2.226 JDIMM2.227 JDIMM2.230 JDIMM2.231 JDIMM2.234 JDIMM2.235 JDIMM2.238 JDIMM2.239 JDIMM2.243 JDIMM2.244 JDIMM2.247 JDIMM2.248 JDIMM2.251 JDIMM2.252 JDIMM2.261 JDIMM2.262 JEDP1.4 JEDP1.6 JEDP1.8 JEDP1.15 JEDP1.23 JEDP1.24 JEDP1.25 JEDP1.27 JEDP1.28 JEDP1.39 JEDP1.41 JEDP1.42 JEDP1.43 JEDP1.44 JEDP1.45 JESPI.9 JESPI.11 JESPI.12 JFAN1.1 JFAN1.5 JFAN1.6 JHDMI1.2 JHDMI1.5 JHDMI1.8 JHDMI1.11 JHDMI1.17 JHDMI1.20 JHDMI1.21 JHDMI1.22 JHDMI1.23 JIR1.2 JIR1.3 JIR1.7 JIR1.8 JKBTP1.1 JKBTP1.4 JKBTP1.6 JKBTP1.12 JKBTP1.18 JKBTP1.19 JKBTP1.21 JKBTP1.22 JLED1.4 JLED1.7 JLED1.8 JLOM1.14 JLOM1.15 JNGFF1.1 JNGFF1.7 JNGFF1.10 JNGFF1.15 JNGFF1.16 JNGFF1.21 JNGFF1.22 JNGFF1.25 JNGFF1.28 JNGFF1.31 JNGFF1.37 JNGFF1.43 JNGFF1.49 JNGFF1.55 JNGFF1.61 JNGFF1.67 JNGFF1.68 JNGFF1.69 JNGFF2.3 JNGFF2.5 JNGFF2.11 JNGFF2.19 JNGFF2.25 JNGFF2.31 JNGFF2.37 JNGFF2.43 JNGFF2.49 JNGFF2.63 JNGFF2.65 JNGFF2.68 JNGFF2.69 JNGFF3.1 JNGFF3.3 JNGFF3.9 JNGFF3.15 JNGFF3.21 JNGFF3.27 JNGFF3.33 JNGFF3.39 JNGFF3.45 JNGFF3.51 JNGFF3.57 JNGFF3.71 JNGFF3.73 JNGFF3.75 JNGFF3.76 JNGFF3.77 JRTC1.2 JRTC1.3 JRTC1.4 JSATA1.1 JSATA1.4 JSATA1.7 JSATA1.12 JSATA1.14 JSATA1.18 JSATA1.21 JSATA1.22 JSATA1.23 JSATA1.24 JSD1.3 JSD1.6 JSD1.10 JSD1.13 JSD1.17 JSD1.20 JSD1.21 JSD1.22 JSD1.23 JSD1.24 JSD1.25 JSD1.26 JSIM1.5 JSIM1.10 JSIM1.11 JSIM1.12 JSIM1.13 JSIM1.14 JSIM1.15 JSIM1.16 JSPI1.1 JSPI1.2 JSPI1.3 JSPI1.21 JSPI1.22 JSPK1.5 JSPK1.6 JTAG1.2 JUART1.4 JUART1.5 JUART1.6 JUSB1.4 JUSB1.7 JUSB1.10 JUSB1.11 JUSB1.12 JUSB1.13 JUSB2.4 JUSB2.7 JUSB2.10 JUSB2.11 JUSB2.12 JUSB2.13 JUSB3.4 JUSB3.7 JUSB3.10 JUSB3.11 JUSB3.12 JUSB3.13 JUSBC1.1 JUSBC1.2 JUSBC1.3 JUSBC1.4 JUSBC1.5 JUSBC1.6 JUSBC1.A1 JUSBC1.A12 JUSBC1.B1 JUSBC1.B12 JUSH1.6 JUSH1.7 JUSH1.10 JUSH1.24 JUSH1.25 JUSH1.27 JUSH1.28 JXDP1.2 JXDP1.7 JXDP1.8 JXDP1.13 JXDP1.14 JXDP1.19 JXDP1.20 JXDP1.25 JXDP1.26 JXDP1.31 JXDP1.32 JXDP1.37 JXDP1.38 JXDP1.49 JXDP1.50 JXDP1.59 LGA1.5 LGA1.6 LGA1.7 LGA1.8 PBATT1.7 PBATT1.8 PBATT1.9 PBATT1.10 PC1.2 PC2.1 PC3.2 PC5.2 PC7.2 PC8.2 PC9.2 PC10.2 PC11.2 PC100.2 PC103.2 PC104.2 PC105.2 PC106.2 PC107.2 PC108.2 PC109.2 PC110.2 PC111.2 PC112.2 PC115.2 PC116.2 PC117.2 PC118.2 PC119.2 PC120.2 PC121.2 PC122.2 PC123.2 PC124.2 PC125.2 PC126.2 PC128.2 PC129.2 PC130.2 PC131.2 PC132.2 PC200.2 PC201.2 PC202.2 PC203.2 PC204.2 PC206.2 PC207.2 PC209.2 PC210.2 PC211.2 PC212.2 PC213.2 PC214.2 PC216.2 PC217.2 PC218.2 PC219.2 PC221.2 PC222.2 PC223.2 PC301.2 PC302.2 PC303.2 PC305.2 PC306.2 PC308.2 PC309.2 PC310.2 PC311.2 PC312.2 PC313.2 PC314.2 PC401.2 PC402.2 PC403.2 PC404.2 PC406.2 PC407.2 PC408.2 PC409.2 PC410.2 PC411.2 PC412.2 PC413.2 PC415.2 PC416.2 PC417.2 PC418.2 PC419.2 PC420.2 PC422.2 PC424.2 PC501.2 PC502.1 PC504.2 PC505.2 PC506.2 PC513.2 PC514.2 PC516.2 PC601.2 PC602.2 PC603.2 PC604.2 PC605.1 PC606.2 PC608.2 PC612.2 PC613.1 PC614.1 PC616.1 PC618.1 PC619.1 PC621.1 PC622.2 PC625.1 PC628.2 PC629.1 PC631.2 PC636.1 PC641.2 PC643.2 PC644.2 PC645.2 PC647.1 PC649.2 PC651.1 PC652.2 PC654.1 PC656.2 PC657.2 PC658.2 PC659.2 PC660.2 PC661.2 PC662.2 PC663.2 PC664.2 PC665.2 PC672.2 PC673.2 PC677.2 PC678.2 PC679.2 PC680.2 PC685.2 PC686.2 PC688.2 PC902.2 PC903.2 PC904.2 PC905.2 PC906.2 PC909.2 PC910.2 PC911.2 PC913.2 PC914.2 PC915.2 PC916.2 PC917.2 PC918.2 PC919.2 PC920.2 PC926.2 PC927.2 PC928.2 PC929.2 PC931.1 PC932.1 PC933.2 PC935.2 PC936.2 PC937.1 PC938.2 PC939.2 PC940.2 PC941.2 PC942.2 PC943.2 PC944.2 PC946.2 PC947.2 PC949.1 PC950.1 PC951.2 PC1001.2 PC1002.2 PC1003.2 PC1004.2 PC1005.2 PC1006.2 PC1007.2 PC1008.2 PC1009.2 PC1010.2 PC1011.2 PC1012.2 PC1013.2 PC1014.2 PC1015.2 PC1016.2 PC1017.2 PC1018.2 PC1019.2 PC1020.2 PC1021.2 PC1022.2 PC1023.2 PC1024.2 PC1025.2 PC1026.2 PC1027.2 PC1028.2 PC1029.2 PC1030.2 PC1031.2 PC1032.2 PC1033.2 PC1034.2 PC1035.2 PC1036.2 PC1037.2 PC1038.2 PC1039.2 PC1040.2 PC1041.2 PC1042.2 PC1043.2 PC1044.2 PC1045.2 PC1046.2 PC1047.2 PC1048.2 PC1049.2 PC1050.2 PC1051.2 PC1052.2 PC1053.2 PC1054.2 PC1055.2 PC1056.2 PC1057.2 PC1058.2 PC1059.2 PC1060.2 PC1061.2 PC1062.2 PC1063.2 PC1064.2 PC1065.2 PC1066.2 PC1067.2 PC1068.2 PC1069.2 PC1070.2 PC1071.2 PC1072.2 PC1073.2 PC1074.2 PC1075.2 PC1076.2 PC1077.2 PC1078.2 PC1079.2 PC1080.2 PC1081.2 PC1082.2 PC1083.2 PC1084.2 PC1085.2 PC1086.2 PC1087.2 PC1088.2 PC1089.2 PC1090.2 PC1091.2 PC1092.2 PC1093.2 PC1094.2 PC1095.2 PC1096.2 PC1097.2 PC1098.2 PC1099.2 PC1125.2 PC1126.2 PC1127.2 PC1128.2 PC1129.2 PC1130.2 PC1131.2 PC1132.2 PC1133.2 PC1134.2 PC1135.2 PC1136.2 PC1137.2 PC1138.2 PC1139.2 PC1140.2 PC1141.2 PC1142.2 PC1143.2 PC1144.2 PC1145.2 PC1146.2 PC1147.2 PC1148.2 PC1149.2 PC1150.2 PC1151.2 PC1152.2 PC1153.2 PC1164.2 PC1170.2 PC1171.2 PC1172.2 PC1173.2 PC1174.2 PC1175.2 PC1176.2 PC1177.2 PC1178.2 PC1179.2 PC1180.2 PC1181.2 PC1201.1 PC1204.2 PC1205.2 PC1206.2 PC1207.2 PC1208.2 PC1209.2 PC1211.2 PC1212.2 PC1213.2 PC1214.2 PC1215.2 PC1216.2 PC1217.2 PC1286.2 PD1.1 PD2.1 PD4.1 PH601.1 PH603.1 PJP19.2 PJPDC1.4 PJPDC1.5 PJPDC1.6 PJPDC1.7 PQ1.1 PQ1.4 PQ3.3 PQ6.3 PQ7.3 PQ501.5 PQ501.6 PQ501.7 PQ904.8 PQ905.8 PQ909.3 PQ1201.1 PQ1201.4 PQ1204.1 PQ1204.4 PQ1207.1 PQ1207.4 PQ1208.1 PQ1208.4 PQ1209.1 PQ1209.4 PQ1210.1 PQ1210.4 PQ1212.3 PQ1214.1 PQ1214.4 PQ1216.3 PR8.1 PR13.2 PR14.2 PR24.2 PR103.2 PR116.2 PR206.2 PR207.1 PR209.2 PR212.2 PR302.2 PR310.2 PR311.2 PR403.2 PR407.2 PR412.1 PR415.2 PR416.2 PR419.2 PR420.2 PR424.2 PR427.2 PR428.2 PR505.2 PR506.2 PR514.2 PR516.2 PR608.2 PR611.2 PR613.1 PR629.1 PR631.1 PR647.1 PR651.2 PR662.2 PR680.2 PR681.2 PR682.2 PR925.2 PR927.2 PR930.2 PR932.2 PR945.2 PR948.2 PR953.2 PR960.1 PR1210.2 PR1217.2 PR1219.2 PR1222.2 PR1227.2 PR1246.2 PR1247.2 PR1249.2 PU1.3 PU2.1 PU100.7 PU100.8 PU100.18 PU100.21 PU102.7 PU102.8 PU102.18 PU102.21 PU200.4 PU200.9 PU200.15 PU301.7 PU301.8 PU301.18 PU301.21 PU401.6 PU401.15 PU401.16 PU401.17 PU402.6 PU402.15 PU402.16 PU402.17 PU501.2 PU503.4 PU503.9 PU602.41 PU610.3 PU610.9 PU612.3 PU612.9 PU614.4 PU614.9 PU901.33 PU903.3 PU1200.3 PU1201.4 QE2.1 QE2.4 QE12.3 QE13.2 QN1.1 QN1.4 QN4.1 QN4.4 QN5.1 QN5.4 QV2.3 QV4.3 QV7.3 QZ8.3 RA35.2 RA36.2 RA37.2 RA45.2 RA51.2 RA52.1 RC1.2 RC3.2 RC4.2 RC5.2 RC6.2 RC7.2 RC44.2 RC48.2 RC65.2 RC75.2 RC86.2 RC88.2 RC89.2 RC90.2 RC91.2 RC96.2 RC109.2 RC110.2 RC112.2 RC113.2 RC114.2 RC122.2 RC136.2 RC139.2 RC141.2 RC163.2 RC166.2 RC167.2 RC219.2 RC220.2 RC227.2 RC268.2 RC311.2 RC316.2 RC324.2 RC337.2 RC338.2 RC349.2 RC372.2 RC401.2 RC411.2 RD5.2 RD7.2 RD9.2 RD16.2 RD18.2 RD21.2 RD23.2 RD25.2 RD29.2 RD31.2 RE14.2 RE16.2 RE18.2 RE20.2 RE55.2 RE56.2 RE58.2 RE65.2 RE77.2 RE85.2 RE86.2 RE93.2 RE95.1 RE313.2 RE342.2 RE513.2 RE537.1 RI14.1 RI35.1 RI36.1 RI37.1 RI39.2 RI41.2 RI43.2 RI45.2 RI52.2 RI54.2 RI56.2 RI58.2 RL3.2 RL9.2 RL12.2 RL13.2 RN5.2 RN7.1 RN9.1 RN11.1 RN13.1 RN15.1 RN17.1 RN19.2 RN21.2 RN30.2 RN31.2 RN38.2 RN39.2 RN40.2 RN41.2 RN52.2 RN53.2 RN54.2 RN59.2 RN60.2 RN61.2 RN62.2 RN72.2 RN73.2 RN74.2 RN174.2 RN176.2 RN179.2 RN183.2 RN185.2 RN188.2 RPE10.5 RPE10.6 RPE10.7 RPE10.8 RR4.2 RT63.2 RT64.2 RT65.2 RT71.2 RT81.2 RT82.2 RT86.2 RT96.2 RT99.2 RT100.2 RT101.2 RT103.2 RT130.2 RT136.2 RT138.2 RT140.2 RT142.2 RT144.2 RT248.2 RT300.2 RT301.2 RT302.2 RT303.2 RT304.2 RT305.2 RT306.2 RT307.2 RT377.2 RT393.2 RV1.2 RV2.2 RV3.1 RV21.2 RV73.2 RV74.2 RV75.2 RV76.2 RV77.2 RV78.2 RV80.2 RV82.2 RV84.2 RV86.2 RV88.2 RV90.2 RV92.2 RV94.2 RV96.2 RV97.2 RV102.2 RV116.2 RV117.2 RV118.2 RV123.1 RZ10.1 RZ25.2 RZ38.1 RZ40.1 RZ62.2 RZ111.2 RZ155.2 RZ157.2 RZ159.2 RZ161.2 RZ163.2 RZ165.2 RZ167.2 RZ334.2 RZ348.2 RZ355.2 RZ357.2 RZ359.2 SW1.4 SW1.5 SW3.1 SW3.3 UA1.49 UC1.A5 UC1.A67 UC1.A70 UC1.AA2 UC1.AA4 UC1.AA65 UC1.AA68 UC1.AB8 UC1.AB15 UC1.AB16 UC1.AB18 UC1.AB21 UC1.AD8 UC1.AD13 UC1.AD16 UC1.AD19 UC1.AD20 UC1.AD21 UC1.AD62 UC1.AE64 UC1.AE65 UC1.AE66 UC1.AE67 UC1.AE68 UC1.AE69 UC1.AF1 UC1.AF2 UC1.AF4 UC1.AF10 UC1.AF15 UC1.AF17 UC1.AF63 UC1.AG16 UC1.AG17 UC1.AG18 UC1.AG19 UC1.AG20 UC1.AG21 UC1.AG71 UC1.AH6 UC1.AH13 UC1.AH63 UC1.AH64 UC1.AH67 UC1.AJ4 UC1.AJ15 UC1.AJ18 UC1.AJ20 UC1.AK8 UC1.AK11 UC1.AK16 UC1.AK18 UC1.AK21 UC1.AK22 UC1.AK27 UC1.AK63 UC1.AK68 UC1.AK69 UC1.AL2 UC1.AL4 UC1.AL28 UC1.AL32 UC1.AL35 UC1.AL38 UC1.AL45 UC1.AL48 UC1.AL52 UC1.AL55 UC1.AL58 UC1.AL64 UC1.AL65 UC1.AL66 UC1.AM8 UC1.AM13 UC1.AM21 UC1.AM25 UC1.AM27 UC1.AM43 UC1.AM45 UC1.AM46 UC1.AM55 UC1.AM60 UC1.AM61 UC1.AM68 UC1.AM71 UC1.AN20 UC1.AN23 UC1.AN28 UC1.AN30 UC1.AN32 UC1.AN33 UC1.AN35 UC1.AN37 UC1.AN38 UC1.AN40 UC1.AN42 UC1.AN58 UC1.AN63 UC1.AP10 UC1.AP18 UC1.AP20 UC1.AP23 UC1.AP28 UC1.AP32 UC1.AP35 UC1.AP38 UC1.AP42 UC1.AP58 UC1.AP63 UC1.AP68 UC1.AP70 UC1.AR5 UC1.AR8 UC1.AR11 UC1.AR15 UC1.AR16 UC1.AR20 UC1.AR23 UC1.AR28 UC1.AR35 UC1.AR42 UC1.AR43 UC1.AR45 UC1.AR46 UC1.AR48 UC1.AR50 UC1.AR52 UC1.AR53 UC1.AR55 UC1.AR58 UC1.AR63 UC1.AT2 UC1.AT4 UC1.AT20 UC1.AT23 UC1.AT28 UC1.AT35 UC1.AT42 UC1.AT56 UC1.AT58 UC1.AT63 UC1.AT68 UC1.AT71 UC1.AU10 UC1.AU15 UC1.AU20 UC1.AU32 UC1.AU38 UC1.AV1 UC1.AV68 UC1.AV69 UC1.AV70 UC1.AV71 UC1.AW6 UC1.AW8 UC1.AW10 UC1.AW12 UC1.AW14 UC1.AW16 UC1.AW18 UC1.AW21 UC1.AW23 UC1.AW26 UC1.AW28 UC1.AW30 UC1.AW32 UC1.AW34 UC1.AW36 UC1.AW38 UC1.AW41 UC1.AW43 UC1.AW45 UC1.AW47 UC1.AW49 UC1.AW51 UC1.AW53 UC1.AW55 UC1.AW57 UC1.AW60 UC1.AW62 UC1.AW64 UC1.AW66 UC1.AY3 UC1.AY66 UC1.AY71 UC1.B10 UC1.B14 UC1.B18 UC1.B22 UC1.B30 UC1.B34 UC1.B39 UC1.B44 UC1.B48 UC1.B53 UC1.B58 UC1.B62 UC1.B66 UC1.B71 UC1.BA1 UC1.BA2 UC1.BA6 UC1.BA10 UC1.BA14 UC1.BA18 UC1.BA23 UC1.BA28 UC1.BA32 UC1.BA36 UC1.BA41 UC1.BA45 UC1.BA49 UC1.BA53 UC1.BA57 UC1.BA62 UC1.BA66 UC1.BA71 UC1.BB6 UC1.BB18 UC1.BB26 UC1.BB30 UC1.BB34 UC1.BB38 UC1.BB43 UC1.BB55 UC1.BB60 UC1.BB64 UC1.BB67 UC1.BB70 UC1.C1 UC1.C5 UC1.C25 UC1.D6 UC1.D10 UC1.D11 UC1.D14 UC1.D18 UC1.D22 UC1.D25 UC1.D26 UC1.D30 UC1.D34 UC1.D39 UC1.D44 UC1.D45 UC1.D47 UC1.D48 UC1.D53 UC1.D58 UC1.D62 UC1.D66 UC1.D69 UC1.E6 UC1.E11 UC1.E15 UC1.E18 UC1.E21 UC1.E46 UC1.E50 UC1.E53 UC1.E56 UC1.E65 UC1.E71 UC1.F1 UC1.F2 UC1.F4 UC1.F8 UC1.F13 UC1.F22 UC1.F23 UC1.F27 UC1.F28 UC1.F32 UC1.F33 UC1.F35 UC1.F37 UC1.F38 UC1.F40 UC1.F42 UC1.F68 UC1.G5 UC1.G6 UC1.G10 UC1.G22 UC1.G43 UC1.G45 UC1.G48 UC1.G52 UC1.G55 UC1.G58 UC1.G60 UC1.G63 UC1.G66 UC1.H15 UC1.H18 UC1.H71 UC1.J8 UC1.J11 UC1.J13 UC1.J25 UC1.J28 UC1.J32 UC1.J35 UC1.J38 UC1.J42 UC1.K16 UC1.K18 UC1.K22 UC1.K61 UC1.K63 UC1.K64 UC1.K65 UC1.K66 UC1.K67 UC1.K68 UC1.K70 UC1.K71 UC1.L2 UC1.L4 UC1.L8 UC1.L11 UC1.L16 UC1.L17 UC1.L18 UC1.L20 UC1.N6 UC1.N10 UC1.N13 UC1.N19 UC1.N21 UC1.N65 UC1.N68 UC1.P17 UC1.P19 UC1.P20 UC1.P21 UC1.R6 UC1.R13 UC1.T2 UC1.T4 UC1.T15 UC1.T17 UC1.T18 UC1.T21 UC1.U10 UC1.U63 UC1.U64 UC1.U66 UC1.U67 UC1.U69 UC1.U70 UC1.V16 UC1.V17 UC1.V18 UC1.W6 UC1.W9 UC1.W13 UC1.Y17 UC1.Y19 UC1.Y20 UC1.Y21 UC5.4 UC6.4 UC7.3 UC8.7 UC8.15 UC12.3 UD1.3 UE1.A6 UE1.A13 UE1.C4 UE1.E6 UE1.H4 UE2.17 UE2.21 UE3.3 UE4.3 UE5.3 UE6.3 UE7.2 UE9.4 UI1.2 UI2.2 UI3.14 UI3.17 UI5.10 UI5.21 UI5.25 UL1.49 UL2.3 UN4.7 UN4.25 UN5.7 UN5.25 UN7.3 UN7.21 UR1.33 UT5.A1 UT5.A6 UT5.A7 UT5.A8 UT5.B7 UT5.B8 UT5.D8 UT5.E5 UT5.E6 UT5.E7 UT5.E8 UT5.F5 UT5.F6 UT5.F7 UT5.F8 UT5.G5 UT5.G6 UT5.G7 UT5.G8 UT5.H4 UT5.H5 UT5.H8 UT5.L1 UT6.4 UT7.2 UT8.2 UT9.41 UV2.2 UV4.2 UV6.24 UV6.33 UV7.67 UV24.2 UZ2.11 UZ2.15 UZ3.11 UZ3.15 UZ4.11 UZ4.15 UZ5.11 UZ5.15 UZ6.3 UZ8.5 UZ8.9 UZ10.3 UZ12.9 UZ12.16 UZ12.23 UZ12.32 UZ12.33 UZ19.5 UZ21.5 UZ23.5 UZ23.9 UZ26.5 UZ34.3 UZ35.3 UZ36.7 UZ36.25 YL1.2 YL1.4
GNDA: CA1.1 CA2.2 CA3.2 CA4.2 CA8.2 CA9.2 CA25.2 CA35.2 CA41.2 CA51.2 CA52.2 CA57.2 CA58.2 DA2.2 JHP1.5 JHP1.7 PJP19.1 RA35.1 RA36.1 RA37.1 RA44.2 UA1.25 UA1.38
VBAT1_ISL88738: PC950.2 PR940.2 PU901.31
VBUS1_ECOK: PR1220.2 PR1222.1 PR1257.1 UE2.13
VBUS2_ECOK: PR20.2 PR24.1 PR1242.1 UE2.16
VCC_CPU: PC603.1 PR602.1 PU602.34
VCC_GT_SENSE: PC617.1 PC618.2 PC620.1 PR622.1 RC161.1 UC1.J70
VCCIO_SENSE: PR422.2 RC165.1 UC1.AM23
VCCSA_B+: PC608.1 PC612.1 PJP603.1 PQ501.2 PQ501.3 PQ501.4 PQ501.10
VCCSENSE: PC639.1 PC651.2 PC653.1 PR648.1 RC140.1 UC1.E32
VCCST_PWRGD: CC301.1 RC71.1 RC78.1 RC123.1 RE308.1 UE4.4
VCCST_PWRGD_CPU: RC78.2 UC1.B65
VCCST_PWRGD_EC: RE308.2 UE1.K10
VCCSTG_EN: RZ120.1 RZ320.2 UZ19.4 UZ35.4
VDD_ISL88738: PC933.1 PR915.2 PR918.2 PR919.1 PU901.18
VDDP_ISL88738: PC932.2 PR915.1 PU901.8
VIN_1.8VALW: PC502.2 PJP501.2 PU501.4
VIN_1V_PRIM: PC412.1 PC413.1 PC417.1 PC418.1 PJP404.2 PU402.10 PU402.11 PU402.12
VIN_1VS_VCCIO: PC403.1 PC404.1 PC408.1 PC409.1 PJP403.2 PU401.10 PU401.11 PU401.12
VIN_CPU: PC604.1 PR603.1 PU602.33
VSS_GT_SENSE: PC619.2 PC620.2 PU602.6 RC163.1 UC1.J69
VSSIO_SENSE: PR412.2 RC167.1 UC1.AM22
VSSSENSE: PC653.2 PC654.2 PU602.18 RC141.1 UC1.E33
32KHZ_OUT: CE54.1 UE1.F3
+AC_IN: PC1202.1 PC1210.2 PJP1202.2 PQ1206.1 PQ1206.2 PQ1206.3 PQ1213.1 PQ1213.2 PQ1213.3 PQ1215.3 PR1205.1 PR1228.1 PR1251.1 PR1255.1
+BL_PWR_SRC: CV11.1 CV15.1 CV24.1 CV25.1 JEDP1.17 JEDP1.18 JEDP1.19 QV1.1 QV1.2 QV1.5 QV1.6
+CHARGER_SRC: PC902.1 PC903.1 PC904.1 PC905.1 PC906.1 PC909.1 PC910.1 PC911.1 PC951.1 PJP901.2 PL901.1 PQ905.1
+COINCELL: JRTC1.1 PC2.2 PR2.1
+CRT_VCC: CV101.1 CV102.1 CV134.1 JCRT1.9 RV119.2 RV120.2 RV121.2 RV122.2 UV4.3 UV6.17
+DC_IN: PC6.2 PC7.1 PC11.1 PL4.2 PQ9.1 PQ9.2 PQ9.3 PR12.1 PR13.1 PR1201.1 PU2.2
+DC_IN_SS: PC8.1 PD5.2 PD5.3 PD904.2 PQ4.5 PQ9.5 PR14.1
+DCIN_JACK: PC5.1 PJPDC1.2 PJPDC1.3 PL4.1
+DCPRTC: CC214.1 UC1.BB10
+DDR_VREF_A_CA: CD25.1 CD26.1 JDIMM1.164 RD15.2 RD16.1 RD17.1
+DDR_VREF_A_DQ: T132.1(TP-1) UC1.AY68
+DDR_VREF_B_CA: CD57.1 CD58.1 JDIMM2.164 RD28.2 RD29.1 RD30.1
+DDR_VREF_B_DQ: CD62.1 RD30.2 UC1.BA67
+DDR_VREF_CA: CD31.1 RD17.2 UC1.AY67
+EC_DEBUG_VCC: JDEG1.1 RE71.2
+EDP_VDD: PJP12.2 UV24.1
+LCDVDD: CV12.1 CV16.1 CV20.1 CV21.1 JEDP1.30 JEDP1.31 PJP12.1 RV7.2
+LINE1-VREFO-L: RA57.1 UA1.31
+LINE1-VREFO-R: RA58.1 UA1.30
+MIC2-VREFO: RA5.1 RA6.1 UA1.29
+PBATT: PL1.2 PL2.2 PQ906.5 PR940.1
+PECI_VREF: CE25.1 RE59.2 UE1.J11
+PWR_SRC: CV13.2 CZ3.1 JIR1.5 JIR1.6 PC913.1 PC914.1 PC915.1 PC916.1 PC917.1 PC918.1 PC919.1 PC920.1 PC928.1 PC929.1 PD901.2 PJP100.1 PJP101.1 PJP202.1 PJP301.1 PJP601.2 PL602.2 PQ904.1 PR102.2 PR917.1 PR929.2 QV1.4 RV4.2 RZ85.1
+PWR_SRC_AC: PJP901.1 PL901.2 PR901.4
+PWR_SRC_R: JUSH1.1 RZ85.2
+REGCTL_PNP10: LL1.1 UL1.7
+RREF: RR4.1 UR1.9
+RSVD_VCC3P3_1: RL6.1 UL1.1
+RTC_CELL: CC213.1 CC270.1 PC3.1 PD3.1 RA54.2 RC56.2 RC57.2 RC69.2 RE31.1 RE32.2 RE324.2 RE507.2 RE508.2 UC1.AK19 UC1.BB14
+RTC_CELL_VBAT: CE11.1 RE32.1 UE1.A2
+SDC_IN: PC4.1 PC1203.1 PD5.1 PD1202.1 PQ4.1 PQ4.2 PQ4.3 PQ5.3 PQ1202.1 PQ1202.2 PQ1202.3 PQ1203.3 PR10.1 PR11.1 PR901.1 PR943.2 PR944.1 PR1202.1 PR1207.1
+SDREG2: CR15.1 UR1.24
+SIM_PWR: CZ37.1 CZ41.1 JNGFF2.28 JSIM1.1 RZ335.1
+TBTA_LDO_BMC: CT71.1 UT5.E1
+TBTA_VBUS: CT99.1 CT100.1 CT101.1 CT102.1 CT189.1 CT190.1 DT4.2 DT4.3 JUSBC1.A4 JUSBC1.A9 JUSBC1.B4 JUSBC1.B9 PC1208.1 PC1215.1 PL1201.1 PL1202.1
+TBTA_VBUS_1: CT82.1 CT94.1 PC1209.1 PC1216.1 PJP1202.1 PL1201.2 PL1202.2 PQ1206.5 PR1227.1 PR1239.1 UT5.A10 UT5.B10 UT5.H11 UT5.J10 UT5.J11 UT5.K11 UT8.1
+USB_EX2_PWR: CI1.1 CI3.1 CI45.1 CI46.1 JUSB2.1 UI1.1
+USB_EX3_PWR: CI8.1 CI10.1 CI47.1 CI48.1 JUSB3.1 UI2.1
+UZ12_TPM: CZ50.1 CZ75.1 RZ89.2 UZ12.8
+VCHGR: PC935.1 PC936.1 PQ906.1 PQ906.2 PQ906.3 PR917.4
+VHDMI_VCC: CV40.1 CV41.1 JHDMI1.18 RV22.2 RV23.2 UV2.3
+VR_CAP: CE31.1 UE1.C10 UE1.J1
+Z4012: PD3.2 PR2.2
AC1_DISC#: PR939.1 PR1244.1 RT72.2
AC1_DISC#_R: RT72.1 UT5.G11
AC_DIS: PQ909.2 PR927.1 RE83.1 UE1.H12
AC_DISC#: PC1217.1 PQ1210.6 PQ1211.3 PQ1211.6 PR25.1 PR1223.1 PR1231.1 PR1245.1 UE1.E13
AC_PRESENT: RC243.1 UC1.AY15 UE1.K8
ACAV_IN: PR946.2 PR953.1 QE13.4 RE530.2 UE1.C7
ACAV_IN1: PQ909.1 PR918.1 PR925.1 PR928.1 PR942.1
ACAV_IN_NB: PC1207.1 PR21.1 PR941.1 PR1203.2 PR1206.2 PR1241.1 PR1258.1 PU1201.1 UE1.N6
ACIN_ISL88738: PC1286.1 PR944.2 PR945.1 PU901.19
ACOK_ISL88738: PR928.2 PU901.24
ADP_ISL88738: PR943.1 PU901.16
ALW_PWRGD_3V_5V: PR119.2 PR120.2 UZ6.2
ALWON: PD100.2 PR114.1 UE1.A5
AR_DET#: RC400.1 RC401.1 UC1.P4
AUD_HP_NB_SENSE: DA2.3 JHP1.6 RA60.2
AUD_HP_OUT_L: LA15.1 RA7.2 RA57.2
AUD_HP_OUT_L1: CA3.1 DA1.2 JHP1.1 LA15.2
AUD_HP_OUT_R: LA16.1 RA8.2 RA58.2
AUD_HP_OUT_R1: CA2.1 DA1.3 JHP1.2 LA16.2
AUD_NB_MUTE#: DA8.1 RA48.1 UE1.A4
AUD_PC_BEEP: CA27.2 CA28.2 UA1.16
AUD_PWR_EN: RC279.1 UC1.W8 UZ5.3 UZ5.5
AUD_SENSE_A: CA41.1 RA59.2 RA60.1 UA1.13
AUD_SENSE_B: RA61.2 UA1.14
AUX1_SNOOP_EN#: RT308.1 UT9.29
AUX_EN_WOWL: RZ38.2 RZ70.1 UE1.D3
BAT1_LED#: RZ28.1 UE1.D10
BAT2_LED#: QZ2.1 RZ361.1 UE1.D11
BAT2_LED#_R: QZ2.3 QZ2.6 QZ3.2
BATGONE_ISL88738: PC938.1 PR930.1 PR931.2 PU901.25
BATT_WHITE#: JLED1.3 QZ3.3 RZ361.2
BATT_YELLOW#: JLED1.2 RZ28.2
BBS_BIT6: RC184.1 UC1.AN5
BC_CLK_ECE1117: CZ87.1 JKBTP1.11 UE1.D13
BC_DAT_ECE1117: CZ86.1 JKBTP1.13 RE365.1 UE1.D12
BC_INT#_ECE1117: CZ85.1 JKBTP1.14 UE1.E2
BCM5882_ALERT#: JUSH1.13 RE532.1 UE1.G10
BEEP: RA13.2 UE1.L9
BEEP_R: CA28.1 CA62.1 RA13.1 RA45.1
BGATE_ISL88738: PC937.2 PQ906.4 PU901.32
BIA_PWM: DV1.1 LV1.2 RV1.1
BIA_PWM_EC: DV1.2 UE1.N1
BL_PWR_SRC_ON: CV13.1 CV14.1 QV1.3 RV4.1 RV5.1
BLUE: CV131.1 DV6.2 JCRT1.3 LV18.2
BLUE_CRT: CV128.1 LV18.1 RV118.1 UV6.21
BOARD_ID: CE40.1 RE79.2 UE1.J13
BOOT1_ISL88738: PR914.1 PU901.12
BOOT2_ISL88738: PC934.2 PU901.4
BREATH_LED#: QZ7.4 UE1.C11
BREATH_LED#_Q: QZ7.3 RZ32.1
BREATH_WHITE_LED_SNIFF#: LED3.1 RZ32.2
BST_3V: PR100.1 PU100.1
BST_3V_R: PC102.1 PR100.2
BST_5V: PR111.1 PU102.1
BST_5V_R: PC114.1 PR111.2
BST_+1VALWP: PC304.1 PU301.1
BST_+1VALWP_C: PC304.2 PR304.1
BST_C_GT: PC671.1 PR672.1
BST_C_IA: PC655.1 PR660.1
BST_C_SA: PC611.1 PR619.1
BST_GT: PC671.2 PU612.7
BST_IA: PC655.2 PU610.7
BST_R_GT: PR672.2 PU612.6
BST_R_IA: PR660.2 PU610.6
BST_SA: PC611.2 PU614.2
BT_RADIO_DIS#: DZ2.1 RE11.1 UE1.C2
BT_RADIO_DIS#_R: DZ2.2 JNGFF1.46
CAM_MIC_CBL_DET#: JEDP1.14 RC413.1 UC1.AB11
CFG0: JXDP1.9 RC113.1 RC126.1 UC1.E68
CFG1: JXDP1.11 RC112.1 UC1.B67
CFG2: JXDP1.15 UC1.D65
CFG3: JXDP1.17 RC110.1 RC121.2 UC1.D67
CFG4: JXDP1.27 RC109.1 UC1.E70
CFG5: JXDP1.29 UC1.C68
CFG6: JXDP1.33 UC1.D68
CFG7: JXDP1.35 UC1.C67
CFG8: JXDP1.10 UC1.F71
CFG9: JXDP1.12 UC1.G69
CFG10: JXDP1.16 UC1.F70
CFG11: JXDP1.18 UC1.G68
CFG12: JXDP1.28 UC1.H70
CFG13: JXDP1.30 UC1.G71
CFG14: JXDP1.34 UC1.H69
CFG15: JXDP1.36 UC1.G70
CFG16: JXDP1.6 UC1.E63
CFG17: JXDP1.4 UC1.F63
CFG18: JXDP1.24 UC1.E66
CFG19: JXDP1.22 UC1.F66
CFG_RCOMP: RC114.1 UC1.E60
CLK_DDC2_CRT: JCRT1.15 RV120.1 UV6.15
CLK_ITPXDP_N: RC297.1 UC1.F43
CLK_ITPXDP_N_R: JXDP1.42 RC297.2
CLK_ITPXDP_P: RC298.1 UC1.E43
CLK_ITPXDP_P_R: JXDP1.40 RC298.2
CLK_PCIE_N0: JNGFF2.45 UC1.D42
CLK_PCIE_N1: JNGFF1.41 UC1.B42
CLK_PCIE_N2: JNGFF1.65 UC1.D41
CLK_PCIE_N3: JNGFF3.53 UC1.D40
CLK_PCIE_N4: UC1.B40 UL1.45
CLK_PCIE_N5: UC1.E40 UR1.6
CLK_PCIE_P0: JNGFF2.47 UC1.C42
CLK_PCIE_P1: JNGFF1.39 UC1.A42
CLK_PCIE_P2: JNGFF1.63 UC1.C41
CLK_PCIE_P3: JNGFF3.55 UC1.C40
CLK_PCIE_P4: UC1.A40 UL1.44
CLK_PCIE_P5: UC1.E38 UR1.5
CLK_TP_SIO_I2C_DAT: CZ81.1 RZ23.2 RZ346.2 UE1.E10
CLK_TP_SIO_R: CZ89.1 JKBTP1.7 RZ19.2 RZ23.1
CLKDET#: T258.1(TP-1) UC1.AY8
CLKREQ_PCIE#0: JNGFF2.44 RC373.2
CLKREQ_PCIE#0_R: RC189.1 RC373.1 UC1.AR10
CLKREQ_PCIE#1: JNGFF1.45 RC374.2
CLKREQ_PCIE#1_R: RC47.1 RC374.1 UC1.AT7
CLKREQ_PCIE#2: JNGFF1.60 RC375.2
CLKREQ_PCIE#2_R: RC50.1 RC375.1 UC1.AT8
CLKREQ_PCIE#3: JNGFF3.52 RC376.2
CLKREQ_PCIE#3_R: RC59.1 RC376.1 UC1.AT10
CLKREQ_PCIE#4: RC377.2 RL4.1 UL1.48
CLKREQ_PCIE#4_R: RC51.1 RC377.1 UC1.AU8
CLKREQ_PCIE#5: RC378.2 UR1.2
CLKREQ_PCIE#5_R: RC190.1 RC378.1 UC1.AU7
CLKRUN#: RC27.1 RE337.1 UC1.AW11
CLKRUN#_EC: RE337.2 UE1.L2
CMOUT: PQ1210.2 PQ1210.3 PQ1216.2 PR951.1
COMP_GT: PC616.2 PR617.2 PU602.4
COMP_IA: PC636.2 PR639.2 PU602.16
COMP_ISL88738: PC943.1 PR934.1 PU901.28
COMP_VSA: PC628.1 PR630.1 PU602.24
CONTACTLESS_DET#: JUSH1.23 RC278.1 UC1.W11
CORE_VID0: PR408.1 UC1.AN11
CORE_VID1: PR411.1 UC1.AN13
CPU_B+: PC606.1 PC656.1 PC657.1 PC658.1 PC659.1 PC660.1 PC663.1 PC680.1 PC686.1 PJP601.1 PJP602.2 PJP603.2 PL602.1 PR603.2 PU610.5
CPU_DP1_AUXN: T281.1(TP-1) UC1.G50
CPU_DP1_AUXP: T282.1(TP-1) UC1.F50
CPU_DP1_CTRL_CLK: QV3.1 RC175.1 UC1.L13
CPU_DP1_CTRL_DATA: QV3.4 RC178.1 UC1.L12
CPU_DP1_HPD: QV5.3 RV20.1 UC1.L9
CPU_DP1_N0: CV32.1 UC1.E55
CPU_DP1_N1: CV34.1 UC1.E58
CPU_DP1_N2: CV36.1 UC1.F53
CPU_DP1_N3: CV38.2 UC1.F56
CPU_DP1_P0: CV31.1 UC1.F55
CPU_DP1_P1: CV33.1 UC1.F58
CPU_DP1_P2: CV35.1 UC1.G53
CPU_DP1_P3: CV37.2 UC1.G56
CPU_DP2_AUXN: CV95.1 UC1.E48
CPU_DP2_AUXN_C: CV95.2 UV7.63
CPU_DP2_AUXP: CV94.1 UC1.F48
CPU_DP2_AUXP_C: CV94.2 UV7.64
CPU_DP2_CTRL_CLK: RC176.1 UC1.N7 UV7.66
CPU_DP2_CTRL_DATA: RC177.1 UC1.N8 UV7.65
CPU_DP2_HPD: UC1.L7 UV7.7
CPU_DP2_N0: CV87.1 UC1.C50
CPU_DP2_N0_C: CV87.2 UV7.12
CPU_DP2_N1: CV89.1 UC1.C52
CPU_DP2_N1_C: CV89.2 UV7.15
CPU_DP2_N2: CV91.1 UC1.A50
CPU_DP2_N2_C: CV91.2 UV7.17
CPU_DP2_N3: CV93.1 UC1.D51
CPU_DP2_N3_C: CV93.2 UV7.20
CPU_DP2_P0: CV86.1 UC1.D50
CPU_DP2_P0_C: CV86.2 UV7.11
CPU_DP2_P1: CV88.1 UC1.D52
CPU_DP2_P1_C: CV88.2 UV7.14
CPU_DP2_P2: CV90.1 UC1.B50
CPU_DP2_P2_C: CV90.2 UV7.16
CPU_DP2_P3: CV92.1 UC1.C51
CPU_DP2_P3_C: CV92.2 UV7.19
CPU_DP3_AUXN: T1.1(TP-1) UC1.G46
CPU_DP3_AUXP: T2.1(TP-1) UC1.F46
CPU_POPIRCOMP: RC88.1 UC1.AT16
CPU_XDP_PRDY#: JXDP1.5 UC1.D56
CPU_XDP_PREQ#: JXDP1.3 RC138.1 UC1.D61
CPU_XDP_TCLK: JXDP1.57 RC139.1 RC328.2 UC1.B61
CPU_XDP_TDI: RC134.1 UC1.D60 UC8.6
CPU_XDP_TDO: RC135.1 UC1.A61 UC8.3
CPU_XDP_TMS: RC131.1 UC1.C60 UC8.8
CPU_XDP_TRST#: CC308.1 RC136.1 UC1.B59 UC1.C61 UC8.11
CSI2_COMP: RC3.1 UC1.E13
CSIN_ISL88738: PC925.2 PC927.1 PR910.2 PU901.14
CSIP_ISL88738: PC925.1 PC926.1 PR909.2 PU901.15
CSON_ISL88738: PC945.1 PC946.1 PR938.1 PU901.1
CSOP_ISL88738: PC942.1 PC945.2 PR937.1 PU901.2
CV2_ON: JUSH1.3 RE539.2
CV2_ON_R: RE539.1 RPE10.1 UE1.H8
DAT_DDC2_CRT: JCRT1.12 RV119.1 UV6.16
DAT_TP_SIO_I2C_CLK: CZ80.1 RZ22.2 RZ347.2 UE1.C12
DAT_TP_SIO_R: CZ88.1 JKBTP1.8 RZ18.2 RZ22.1
DCIN1_EN: PR1221.1 UE2.12
DCIN2_EN: PR26.1 UE2.15
DCIN_ISL88738: PC931.2 PR916.1 PU901.17
DDR_A_ACT#: JDIMM1.114 UC1.BA55
DDR_A_ALERT#: JDIMM1.116 UC1.AW50
DDR_A_BA0: JDIMM1.150 UC1.AU52
DDR_A_BA1: JDIMM1.145 UC1.AT48
DDR_A_BG0: JDIMM1.115 UC1.AY55
DDR_A_BG1: JDIMM1.113 UC1.AY54
DDR_A_CKE0: JDIMM1.109 UC1.BA56
DDR_A_CKE1: JDIMM1.110 UC1.BB56
DDR_A_CKE2: T3.1(TP-1) UC1.AW56
DDR_A_CKE3: T4.1(TP-1) UC1.AY56
DDR_A_CLK0: JDIMM1.137 UC1.AT53
DDR_A_CLK1: JDIMM1.138 UC1.AT55
DDR_A_CLK#0: JDIMM1.139 UC1.AU53
DDR_A_CLK#1: JDIMM1.140 UC1.AU55
DDR_A_CS#0: JDIMM1.149 UC1.AU45
DDR_A_CS#1: JDIMM1.157 UC1.AU43
DDR_A_D0: JDIMM1.7 UC1.AL71
DDR_A_D1: JDIMM1.3 UC1.AL68
DDR_A_D2: JDIMM1.21 UC1.AN68
DDR_A_D3: JDIMM1.16 UC1.AN69
DDR_A_D4: JDIMM1.4 UC1.AL70
DDR_A_D5: JDIMM1.8 UC1.AL69
DDR_A_D6: JDIMM1.17 UC1.AN70
DDR_A_D7: JDIMM1.20 UC1.AN71
DDR_A_D8: JDIMM1.28 UC1.AR70
DDR_A_D9: JDIMM1.24 UC1.AR68
DDR_A_D10: JDIMM1.38 UC1.AU71
DDR_A_D11: JDIMM1.42 UC1.AU68
DDR_A_D12: JDIMM1.29 UC1.AR71
DDR_A_D13: JDIMM1.25 UC1.AR69
DDR_A_D14: JDIMM1.41 UC1.AU70
DDR_A_D15: JDIMM1.37 UC1.AU69
DDR_A_D16: JDIMM1.194 UC1.AF65
DDR_A_D17: JDIMM1.195 UC1.AF64
DDR_A_D18: JDIMM1.204 UC1.AK65
DDR_A_D19: JDIMM1.203 UC1.AK64
DDR_A_D20: JDIMM1.190 UC1.AF66
DDR_A_D21: JDIMM1.191 UC1.AF67
DDR_A_D22: JDIMM1.207 UC1.AK67
DDR_A_D23: JDIMM1.208 UC1.AK66
DDR_A_D24: JDIMM1.186 UC1.AF70
DDR_A_D25: JDIMM1.174 UC1.AF68
DDR_A_D26: JDIMM1.173 UC1.AH71
DDR_A_D27: JDIMM1.183 UC1.AH68
DDR_A_D28: JDIMM1.182 UC1.AF71
DDR_A_D29: JDIMM1.187 UC1.AF69
DDR_A_D30: JDIMM1.169 UC1.AH70
DDR_A_D31: JDIMM1.170 UC1.AH69
DDR_A_D32: JDIMM1.46 UC1.BB65
DDR_A_D33: JDIMM1.62 UC1.AW65
DDR_A_D34: JDIMM1.63 UC1.AW63
DDR_A_D35: JDIMM1.45 UC1.AY63
DDR_A_D36: JDIMM1.50 UC1.BA65
DDR_A_D37: JDIMM1.49 UC1.AY65
DDR_A_D38: JDIMM1.59 UC1.BA63
DDR_A_D39: JDIMM1.58 UC1.BB63
DDR_A_D40: JDIMM1.66 UC1.BA61
DDR_A_D41: JDIMM1.70 UC1.AW61
DDR_A_D42: JDIMM1.79 UC1.BB59
DDR_A_D43: JDIMM1.84 UC1.AW59
DDR_A_D44: JDIMM1.67 UC1.BB61
DDR_A_D45: JDIMM1.71 UC1.AY61
DDR_A_D46: JDIMM1.83 UC1.BA59
DDR_A_D47: JDIMM1.80 UC1.AY59
DDR_A_D48: JDIMM1.211 UC1.AT66
DDR_A_D49: JDIMM1.215 UC1.AU66
DDR_A_D50: JDIMM1.225 UC1.AP65
DDR_A_D51: JDIMM1.229 UC1.AN65
DDR_A_D52: JDIMM1.216 UC1.AN66
DDR_A_D53: JDIMM1.212 UC1.AP66
DDR_A_D54: JDIMM1.224 UC1.AT65
DDR_A_D55: JDIMM1.228 UC1.AU65
DDR_A_D56: JDIMM1.233 UC1.AT61
DDR_A_D57: JDIMM1.237 UC1.AU61
DDR_A_D58: JDIMM1.246 UC1.AP60
DDR_A_D59: JDIMM1.250 UC1.AN60
DDR_A_D60: JDIMM1.236 UC1.AN61
DDR_A_D61: JDIMM1.232 UC1.AP61
DDR_A_D62: JDIMM1.249 UC1.AT60
DDR_A_D63: JDIMM1.245 UC1.AU60
DDR_A_DQS0: JDIMM1.13 UC1.AM69
DDR_A_DQS1: JDIMM1.34 UC1.AT70
DDR_A_DQS2: JDIMM1.200 UC1.AH65
DDR_A_DQS3: JDIMM1.179 UC1.AG70
DDR_A_DQS4: JDIMM1.55 UC1.AY64
DDR_A_DQS5: JDIMM1.76 UC1.BA60
DDR_A_DQS6: JDIMM1.221 UC1.AR65
DDR_A_DQS7: JDIMM1.242 UC1.AR60
DDR_A_DQS#0: JDIMM1.11 UC1.AM70
DDR_A_DQS#1: JDIMM1.32 UC1.AT69
DDR_A_DQS#2: JDIMM1.198 UC1.AH66
DDR_A_DQS#3: JDIMM1.177 UC1.AG69
DDR_A_DQS#4: JDIMM1.53 UC1.BA64
DDR_A_DQS#5: JDIMM1.74 UC1.AY60
DDR_A_DQS#6: JDIMM1.219 UC1.AR66
DDR_A_DQS#7: JDIMM1.240 UC1.AR61
DDR_A_MA0: JDIMM1.144 UC1.AY50
DDR_A_MA1: JDIMM1.133 UC1.BB50
DDR_A_MA2: JDIMM1.132 UC1.AY51
DDR_A_MA3: JDIMM1.131 UC1.BA50
DDR_A_MA4: JDIMM1.128 UC1.BB52
DDR_A_MA5: JDIMM1.126 UC1.BA51
DDR_A_MA6: JDIMM1.127 UC1.BA52
DDR_A_MA7: JDIMM1.122 UC1.AW52
DDR_A_MA8: JDIMM1.125 UC1.AY52
DDR_A_MA9: JDIMM1.121 UC1.BB54
DDR_A_MA10: JDIMM1.146 UC1.AT50
DDR_A_MA11: JDIMM1.120 UC1.BA54
DDR_A_MA12: JDIMM1.119 UC1.AW54
DDR_A_MA13: JDIMM1.158 UC1.AU46
DDR_A_MA14: JDIMM1.151 UC1.AT46
DDR_A_MA15: JDIMM1.156 UC1.AU48
DDR_A_MA16: JDIMM1.152 UC1.AU50
DDR_A_ODT0: JDIMM1.155 UC1.AT45
DDR_A_ODT1: JDIMM1.161 UC1.AT43
DDR_A_PARITY: JDIMM1.143 UC1.AT52
DDR_B_ACT#: JDIMM2.114 UC1.AN53
DDR_B_ALERT#: JDIMM2.116 UC1.AN43
DDR_B_BA0: JDIMM2.150 UC1.BB44
DDR_B_BA1: JDIMM2.145 UC1.BA44
DDR_B_BG0: JDIMM2.115 UC1.AP52
DDR_B_BG1: JDIMM2.113 UC1.AN52
DDR_B_CKE0: JDIMM2.109 UC1.AN56
DDR_B_CKE1: JDIMM2.110 UC1.AP55
DDR_B_CKE2: T5.1(TP-1) UC1.AN55
DDR_B_CKE3: T6.1(TP-1) UC1.AP53
DDR_B_CLK0: JDIMM2.137 UC1.AP45
DDR_B_CLK1: JDIMM2.138 UC1.AP46
DDR_B_CLK#0: JDIMM2.139 UC1.AN45
DDR_B_CLK#1: JDIMM2.140 UC1.AN46
DDR_B_CS#0: JDIMM2.149 UC1.BB42
DDR_B_CS#1: JDIMM2.157 UC1.AY42
DDR_B_D0: JDIMM2.8 UC1.AY39
DDR_B_D1: JDIMM2.3 UC1.AW39
DDR_B_D2: JDIMM2.16 UC1.AY37
DDR_B_D3: JDIMM2.20 UC1.AW37
DDR_B_D4: JDIMM2.7 UC1.BB39
DDR_B_D5: JDIMM2.4 UC1.BA39
DDR_B_D6: JDIMM2.21 UC1.BA37
DDR_B_D7: JDIMM2.17 UC1.BB37
DDR_B_D8: JDIMM2.28 UC1.AY35
DDR_B_D9: JDIMM2.24 UC1.AW35
DDR_B_D10: JDIMM2.42 UC1.AY33
DDR_B_D11: JDIMM2.38 UC1.AW33
DDR_B_D12: JDIMM2.29 UC1.BB35
DDR_B_D13: JDIMM2.25 UC1.BA35
DDR_B_D14: JDIMM2.37 UC1.BA33
DDR_B_D15: JDIMM2.41 UC1.BB33
DDR_B_D16: JDIMM2.170 UC1.AU40
DDR_B_D17: JDIMM2.174 UC1.AT40
DDR_B_D18: JDIMM2.182 UC1.AT37
DDR_B_D19: JDIMM2.186 UC1.AU37
DDR_B_D20: JDIMM2.173 UC1.AR40
DDR_B_D21: JDIMM2.169 UC1.AP40
DDR_B_D22: JDIMM2.187 UC1.AP37
DDR_B_D23: JDIMM2.183 UC1.AR37
DDR_B_D24: JDIMM2.191 UC1.AT33
DDR_B_D25: JDIMM2.195 UC1.AU33
DDR_B_D26: JDIMM2.203 UC1.AU30
DDR_B_D27: JDIMM2.207 UC1.AT30
DDR_B_D28: JDIMM2.190 UC1.AR33
DDR_B_D29: JDIMM2.194 UC1.AP33
DDR_B_D30: JDIMM2.208 UC1.AR30
DDR_B_D31: JDIMM2.204 UC1.AP30
DDR_B_D32: JDIMM2.50 UC1.AY31
DDR_B_D33: JDIMM2.45 UC1.AW31
DDR_B_D34: JDIMM2.58 UC1.AY29
DDR_B_D35: JDIMM2.62 UC1.AW29
DDR_B_D36: JDIMM2.49 UC1.BB31
DDR_B_D37: JDIMM2.46 UC1.BA31
DDR_B_D38: JDIMM2.63 UC1.BA29
DDR_B_D39: JDIMM2.59 UC1.BB29
DDR_B_D40: JDIMM2.66 UC1.AY27
DDR_B_D41: JDIMM2.70 UC1.AW27
DDR_B_D42: JDIMM2.67 UC1.AY25
DDR_B_D43: JDIMM2.71 UC1.AW25
DDR_B_D44: JDIMM2.79 UC1.BB27
DDR_B_D45: JDIMM2.83 UC1.BA27
DDR_B_D46: JDIMM2.80 UC1.BA25
DDR_B_D47: JDIMM2.84 UC1.BB25
DDR_B_D48: JDIMM2.216 UC1.AU27
DDR_B_D49: JDIMM2.215 UC1.AT27
DDR_B_D50: JDIMM2.224 UC1.AT25
DDR_B_D51: JDIMM2.228 UC1.AU25
DDR_B_D52: JDIMM2.211 UC1.AP27
DDR_B_D53: JDIMM2.212 UC1.AN27
DDR_B_D54: JDIMM2.229 UC1.AN25
DDR_B_D55: JDIMM2.225 UC1.AP25
DDR_B_D56: JDIMM2.233 UC1.AT22
DDR_B_D57: JDIMM2.237 UC1.AU22
DDR_B_D58: JDIMM2.245 UC1.AU21
DDR_B_D59: JDIMM2.249 UC1.AT21
DDR_B_D60: JDIMM2.236 UC1.AN22
DDR_B_D61: JDIMM2.232 UC1.AP22
DDR_B_D62: JDIMM2.246 UC1.AP21
DDR_B_D63: JDIMM2.250 UC1.AN21
DDR_B_DQS0: JDIMM2.13 UC1.AY38
DDR_B_DQS1: JDIMM2.34 UC1.BA34
DDR_B_DQS2: JDIMM2.179 UC1.AR38
DDR_B_DQS3: JDIMM2.200 UC1.AR32
DDR_B_DQS4: JDIMM2.55 UC1.AY30
DDR_B_DQS5: JDIMM2.76 UC1.BA26
DDR_B_DQS6: JDIMM2.221 UC1.AR27
DDR_B_DQS7: JDIMM2.242 UC1.AR21
DDR_B_DQS#0: JDIMM2.11 UC1.BA38
DDR_B_DQS#1: JDIMM2.32 UC1.AY34
DDR_B_DQS#2: JDIMM2.177 UC1.AT38
DDR_B_DQS#3: JDIMM2.198 UC1.AT32
DDR_B_DQS#4: JDIMM2.53 UC1.BA30
DDR_B_DQS#5: JDIMM2.74 UC1.AY26
DDR_B_DQS#6: JDIMM2.219 UC1.AR25
DDR_B_DQS#7: JDIMM2.240 UC1.AR22
DDR_B_MA0: JDIMM2.144 UC1.BA46
DDR_B_MA1: JDIMM2.133 UC1.AY46
DDR_B_MA2: JDIMM2.132 UC1.AY47
DDR_B_MA3: JDIMM2.131 UC1.BB46
DDR_B_MA4: JDIMM2.128 UC1.BA47
DDR_B_MA5: JDIMM2.126 UC1.AY48
DDR_B_MA6: JDIMM2.127 UC1.BA48
DDR_B_MA7: JDIMM2.122 UC1.AP48
DDR_B_MA8: JDIMM2.125 UC1.BB48
DDR_B_MA9: JDIMM2.121 UC1.AP50
DDR_B_MA10: JDIMM2.146 UC1.AW46
DDR_B_MA11: JDIMM2.120 UC1.AN48
DDR_B_MA12: JDIMM2.119 UC1.AN50
DDR_B_MA13: JDIMM2.158 UC1.BA43
DDR_B_MA14: JDIMM2.151 UC1.AY44
DDR_B_MA15: JDIMM2.156 UC1.AY43
DDR_B_MA16: JDIMM2.152 UC1.AW44
DDR_B_ODT0: JDIMM2.155 UC1.BA42
DDR_B_ODT1: JDIMM2.161 UC1.AW42
DDR_B_PARITY: JDIMM2.143 UC1.AP43
DDR_DRAMRST#: RD11.2 RD12.2 UC1.AT13
DDR_DRAMRST#_R: CD29.1 CD61.1 JDIMM1.108 JDIMM2.108 RD12.1
DDR_VTT_CTRL: UC1.AW67 UD1.2
DDR_XDP_WAN_SMBCLK: JDIMM1.253 JDIMM2.253 JXDP1.53 LGA1.1 QC2.1 RC319.1
DDR_XDP_WAN_SMBDAT: JDIMM1.254 JDIMM2.254 JXDP1.51 LGA1.4 QC2.4 RC318.1
DEBUG_TX: JDEG1.9 RE30.2 RE74.2
DEW1: RN16.2 RN17.2 UN7.16
DEW2: RN14.2 RN15.2 UN7.6
DIMM1_SA0: JDIMM1.256 RD4.2 RD5.1
DIMM1_SA1: JDIMM1.260 RD6.2 RD7.1
DIMM1_SA2: JDIMM1.166 RD8.2 RD9.1
DIMM2_SA0: JDIMM2.256 RD20.2 RD21.1
DIMM2_SA1: JDIMM2.260 RD22.2 RD23.1
DIMM2_SA2: JDIMM2.166 RD24.2 RD25.1
DISP_ON: DV2.1 JEDP1.22 RV2.1
DMIC0: CA6.1 JEDP1.7 RA52.2 UA1.2
DMIC_CLK0: CA5.1 CA54.1 JEDP1.9 RA14.1
DMIC_CLK_CODEC: RA14.2 UA1.3
EC_FPM_EN: JUSH1.5 UE1.D6
EDP_AUXN: CV1.1 UC1.E45
EDP_AUXN_C: CV1.2 JEDP1.33
EDP_AUXP: CV2.1 UC1.F45
EDP_AUXP_C: CV2.2 JEDP1.34
EDP_BIA_PWM: DV1.3 UC1.R11
EDP_COMP: RC2.1 UC1.E52
EDP_HPD: JEDP1.26 RC1.1 RV7.1 UC1.L10
EDP_TXN0: CV4.1 UC1.C47
EDP_TXN0_C: CV4.2 JEDP1.36
EDP_TXN1: CV6.1 UC1.D46
EDP_TXN1_C: CV6.2 JEDP1.38
EDP_TXP0: CV3.1 UC1.C46
EDP_TXP0_C: CV3.2 JEDP1.35
EDP_TXP1: CV5.1 UC1.C45
EDP_TXP1_C: CV5.2 JEDP1.37
EDRAM_OPIO_RCOMP: RC90.1 UC1.H66
EMMC_RCOMP: RC4.1 UC1.AT1
EN_0.6V: PC222.1 PR210.1 PR212.1 PU200.2
EN_1.0V_PRIM_COREP: PC411.1 PR406.2 PR407.1 PU402.13
EN_1.2V: PC221.1 PR208.1 PR209.1 PU200.1
EN_1.8VALW: PC505.1 PR504.2 PR505.1 PU501.1
EN_1VS_VCCIO: PC402.1 PR402.2 PR403.1 PU401.13
EN_2.5V: PC513.1 PR513.2 PR514.1 PU503.5
EN_+1VALWP: PR302.1 PR312.1 PU301.11
EN_CPU: PR616.2 PU602.40
EN_INVPWR: QV2.2 RE55.1 UE1.B2
EN_LCDPWR: DV3.1 RV3.2 UV24.4
EN_PD_HV_1: PQ1214.5 PR1210.1 PR1211.1 PR1250.2 PR1254.1 PR1260.1 RT70.2
EN_PD_HV_1#: PQ1214.2 PQ1214.3 PR1253.2
EN_PD_HV_1_R: RT70.1 UT5.C2
ENLDO_3V5V: PR102.1 PR103.1 PU100.11 PU102.11
ENVDD_PCH: DV3.3 UC1.U13 UE1.L12
EOPIO_RCOMP: RC91.1 UC1.H65
ESPI_ALERT#: RC21.1 UC1.AY11 UE1.H7
ESPI_CLK: RC16.1 UC1.AW9
ESPI_CLK_5105: CC316.1 JESPI.10 RC16.2 RE350.1 UE1.G7
ESPI_CS#: JESPI.7 UC1.BA12 UE1.H6
ESPI_IO0: JESPI.3 RC366.2 UE1.K5
ESPI_IO0_R: RC366.1 UC1.AY13
ESPI_IO1: JESPI.4 RC367.2 UE1.L4
ESPI_IO1_R: RC367.1 UC1.BA13
ESPI_IO2: JESPI.5 RC368.2 UE1.G6
ESPI_IO2_R: RC368.1 UC1.BB13
ESPI_IO3: JESPI.6 RC369.2 UE1.L5
ESPI_IO3_R: RC369.1 UC1.AY12
ESPI_RESET#: UC1.BA11 UE1.K6
EXPANDER_ALERT#: T267.1(TP-1) UE2.7
EXPANDER_GPU_SMCLK: CE505.1 RE525.1 UE1.M4 UE2.19
EXPANDER_GPU_SMDAT: CE504.1 RE524.1 UE1.M7 UE2.20
FAN1_PWM: JFAN1.2 RE48.2 UE1.L10
FAN1_TACH: JFAN1.3 RE51.2 UE1.E3
FB_1.8VALW: PC503.2 PR501.2 PR506.1 PU501.6
FB_1VS_VCCIO: PR421.2 PR422.1 PU401.5
FB_+1VALWP: PR306.2 PR308.2 PR311.1 PU301.14
FB_GT: PR621.2 PR622.2 PR623.2 PU602.5
FB_IA: PR645.2 PR648.2 PR650.1 PU602.17
FB_PRIM_CORE: PR423.1 PR424.1 PU402.5
FB_VSA: PR646.1 PR649.1 PR652.1 PU602.25
FCCM_GT: PR671.2 PR682.1 PU602.11
FCCM_IA: PR659.2 PR681.1 PU602.21
FCCM_R_GT: PR671.1 PU612.1
FCCM_R_IA: PR659.1 PU610.1
FCCM_VSA: PR679.2 PU602.29
FFS_INT2: LGA1.11 QN1.2 RC404.1 UC1.J5
FFS_INT2_Q: JSATA1.19 QN1.3 RN1.2
FIVR_EN: RC217.1 RC218.1 RC219.1
FIVR_EN_R: JXDP1.45 RC126.2 RC132.1 RC217.2
GPIO126: RE5.1 UE1.E12
GPP_B23: RC317.1 UC1.AM7
GPP_C5: RC25.1 UC1.W1
GPP_C8: RC405.1 UC1.AB1
GPP_E23: T120.1(TP-1) UC1.N12
GPU_B+: PC664.1 PC665.1 PC672.1 PC673.1 PC679.1 PC688.1 PJP602.1 PU612.5
GREEN: CV130.1 DV5.3 JCRT1.2 LV17.2
GREEN_CRT: CV127.1 LV17.1 RV117.1 UV6.22
GT1P: PL612.3 PR674.2
GT_SNUB1: PC678.1 PR676.2
GT_SW1: PL612.4 PR676.1 PU612.4
H_CATERR#: RC79.1 UC1.D63
H_CPU_SVIDALRT#: RC153.1 UC1.B63
H_CPUPWRGD: CC300.1 RC77.2 UC1.A68
H_CPUPWRGD_R: RC77.1 T9.1(TP-1)
H_PROCHOT#: CC310.1 PC605.2 PR678.1 PR926.1 RC83.1 RC84.1 RE288.2
H_PROCHOT#_R: RC84.2 UC1.C65
H_PROCHOT#_R1: RE288.1 UE1.H13
H_THERMTRIP#: CC312.1 QE4.3 RC80.1 RD14.2 RD27.2 UC1.C63
H_VCCST_PWRGD_XDP: CC307.1 JXDP1.39 RC123.2 RC124.2
HDA_BIT_CLK: RC93.2 UC1.AY22
HDA_BIT_CLK_R: CC27.1 RA17.1 RC93.1 UA1.6
HDA_RST#: CC331.1 RC95.2 UC1.AW22
HDA_RST#_R: RA50.1 RC95.1
HDA_SDIN0: CC332.1 RA9.1 UC1.BA21
HDA_SDIN0_R: RA9.2 UA1.8
HDA_SDOUT: CC333.1 RC94.2 RC187.1 RC223.2 UC1.BB22
HDA_SDOUT_R: RC94.1 UA1.5
HDA_SYNC: RC92.2 UC1.BA22
HDA_SYNC_R: RC92.1 UA1.10
HDD_A_EQ: RN10.1 RN11.2 UN7.17
HDD_A_EQ2: RN20.2 RN21.1 UN7.18
HDD_A_PRE: RN6.2 RN7.2 UN7.9
HDD_B_EQ: RN12.2 RN13.2 UN7.19
HDD_B_EQ2: RN18.2 RN19.1 UN7.13
HDD_B_PRE: RN8.1 RN9.2 UN7.8
HDD_DET#: JSATA1.13 RPC4.3 UC1.H2
HDD_DEVSLP: JSATA1.11 RN3.2 UC1.J1
HDD_EN: RN4.2 RN5.1 UC1.AB4 UZ23.3
HDD_FALL_INT: LGA1.12 RC370.1 UC1.AM5
HDMI_CEC: JHDMI1.13 RV19.1
HDMI_CLKN: CV38.1 LV12.2 RV17.1 RV34.1
HDMI_CLKP: CV37.1 LV12.1 RV16.1 RV33.1
HDMI_CTRL_CLK: JHDMI1.15 QV3.6 RV22.1
HDMI_CTRL_DATA: JHDMI1.16 QV3.3 RV23.1
HDMI_HPD: JHDMI1.19 QV5.1 RV21.1
HDMI_L_CLKN: JHDMI1.12 LV12.3 RV34.2 RV35.1
HDMI_L_CLKP: JHDMI1.10 LV12.4 RV33.2 RV35.2
HDMI_L_TX_N0: JHDMI1.9 LV9.3 RV31.2 RV32.1
HDMI_L_TX_N1: JHDMI1.6 LV6.3 RV28.2 RV29.1
HDMI_L_TX_N2: JHDMI1.3 LV3.3 RV25.2 RV26.1
HDMI_L_TX_P0: JHDMI1.7 LV9.4 RV30.2 RV32.2
HDMI_L_TX_P1: JHDMI1.4 LV6.4 RV27.2 RV29.2
HDMI_L_TX_P2: JHDMI1.1 LV3.4 RV24.2 RV26.2
HDMI_OB: QV4.1 RV10.2 RV11.2 RV12.2 RV13.2 RV14.2 RV15.2 RV16.2 RV17.2
HDMI_TX_N0: CV36.2 LV9.2 RV15.1 RV31.1
HDMI_TX_N1: CV34.2 LV6.2 RV13.1 RV28.1
HDMI_TX_N2: CV32.2 LV3.2 RV11.1 RV25.1
HDMI_TX_P0: CV35.2 LV9.1 RV14.1 RV30.1
HDMI_TX_P1: CV33.2 LV6.1 RV12.1 RV27.1
HDMI_TX_P2: CV31.2 LV3.1 RV10.1 RV24.1
HOST_DEBUG_TX: JDEG1.8 RE73.2 RE306.2 RZ132.1 UE1.G11
HOST_SD_WP#: QR1.2 RC292.1 UC1.W10
HP_OUT_L: CA43.2 RA7.1 UA1.32
HP_OUT_R: CA44.2 RA8.1 UA1.33
HSYNC_CONN: CV133.1 JCRT1.13 LV19.2 RV122.1
HSYNC_CRT: LV19.1 UV6.19
HV_GATE1_A: RT64.1 UT5.B9
HV_GATE2_A: RT65.1 UT5.A9
HW_GPS_DISABLE#: DZ6.1 RE12.1 UE1.H5
HW_GPS_DISABLE#_R: DZ6.2 JNGFF2.18
I2C1_SCK_TP: RZ21.2 RZ29.1 UC1.U9
I2C1_SCK_TP_R: JKBTP1.2 RZ29.2 RZ117.2 RZ347.1
I2C1_SDA_TP: RZ20.2 RZ26.1 UC1.U8
I2C1_SDA_TP_R: JKBTP1.3 RZ26.2 RZ116.2 RZ346.1
I_ADP: PR935.2 UE1.B11
I_BATT: PR947.2 RE64.2
I_BATT_R: CE3.1 RE64.1 UE1.J4
I_SYS: PR620.1 PR936.2 RE312.2
I_SYS_R: CE4.1 RE312.1 RE313.1 UE1.J5
IA_SNUB: PC662.1 PR663.2
IA_SW: PL610.4 PR663.1 PU610.4
IFDET_SATA_PCIE#: QN4.6 RN171.2 RN186.1 RN189.1 RN192.1
ILIM_SEL: RI13.1 UI3.4
ILMT_+1VALWP: PR307.2 PR310.1 PU301.13
ILMT_DDR: PR205.1 PR207.2 PU200.17
IMON_IA: PC625.2 PR629.2 PU602.14
IMON_VSA: PC643.1 PR651.1 PU602.23
IMVP_VR_ON: PR616.1 RE304.1 UE3.4 UE4.2
IMVP_VR_ON_EC: RE304.2 RPE10.2 UE1.N7 UE3.1
INT_SPK_L+: CA22.1 LA6.1 UA1.42
INT_SPK_L-: CA23.1 LA7.1 UA1.43
INT_SPK_R+: CA19.1 LA8.1 UA1.45
INT_SPK_R-: CA24.1 LA9.1 UA1.44
INT_SPKR_L+: DA6.2 JSPK1.1 LA6.2
INT_SPKR_L-: DA6.3 JSPK1.2 LA7.2
INT_SPKR_R+: DA7.2 JSPK1.3 LA8.2
INT_SPKR_R-: DA7.3 JSPK1.4 LA9.2
INTRUDER#: RC69.1 UC1.AP16
IR_CAM_DET#: JIR1.1 RC345.1 UC1.H5
ISH_I2C2_SCL: RC362.1 RZ76.1 UC1.AD12
ISH_I2C2_SCL_R: JNGFF2.32 RZ76.2
ISH_I2C2_SDA: RC363.1 RZ77.1 UC1.AD11
ISH_I2C2_SDA_R: JNGFF2.34 RZ77.2
ISH_UART0_CTS#: RZ80.1 UC1.U4
ISH_UART0_CTS#_R: JNGFF1.54 RZ80.2
ISH_UART0_RTS#: RZ81.1 UC1.U3
ISH_UART0_RTS#_R: JNGFF1.56 RZ81.2
ISH_UART0_RXD: RZ78.1 UC1.U1
ISH_UART0_RXD_R: JNGFF1.50 RZ78.2
ISH_UART0_TXD: RZ79.1 UC1.U2
ISH_UART0_TXD_R: JNGFF1.52 RZ79.2
ISPSCL: RV106.1 UV6.30
ISPSDA: RV107.1 UV6.29
ISUMN_GT: PC624.2 PC626.2 PC641.1 PH602.2 PL612.2 PR632.1 PR633.2 PR638.1
ISUMN_IA: PC642.2 PC645.1 PC646.2 PH605.2 PL610.2 PR640.2 PR644.2 PR656.2
ISUMN_R_GT: PC627.2 PR638.2 PU602.8
ISUMN_R_IA: PC630.1 PR640.1 PU602.20
ISUMN_R_VSA: PC632.1 PR636.1 PU602.28
ISUMP_GT: PC624.1 PC626.1 PR628.1 PR633.1 PR674.1 PU602.7
ISUMP_IA: PC642.1 PC646.1 PR656.1 PR657.1 PR661.2 PU602.19
ISUMP_VSA: PC633.1 PC637.1 PR624.2 PR642.1 PR643.2 PU602.27
ITP_PMODE: JXDP1.46 RC115.1 UC1.E8
JCRT-11: JCRT1.11 T87.1(TP-1)
JDIMM1_EVENT#: JDIMM1.134 RD14.1
JDIMM2_EVENT#: JDIMM2.134 RD27.1
JTAG_CLK: JDEG1.4 RPE7.3 UE1.C8
JTAG_RST#: CE30.1 JTAG1.1 RE63.1 RE65.1 UE1.G13
JTAG_TDI: JDEG1.2 RPE7.1 UE1.E9
JTAG_TDO: JDEG1.5 RPE7.4 UE1.F6
JTAG_TMS: JDEG1.3 RPE7.2 UE1.C5
KB_DET#: CZ84.1 JKBTP1.20 RC288.1 UC1.D8
LAN_ACTLED_YEL#: QL1.6 RL14.1
LAN_ACTLED_YEL_R#: JLOM1.10 RL14.2
LAN_DISABLE#_R: RL5.1 RL7.2 RL9.1 UL1.3
LAN_MDIN0: RL72.1 UL1.14
LAN_MDIN0_L: RL72.2 TL1.11
LAN_MDIN1: RL74.1 UL1.18
LAN_MDIN1_L: RL74.2 TL1.5
LAN_MDIN2: RL76.1 UL1.21
LAN_MDIN2_L: RL76.2 TL1.8
LAN_MDIN3: RL78.1 UL1.24
LAN_MDIN3_L: RL78.2 TL1.2
LAN_MDIP0: RL71.1 UL1.13
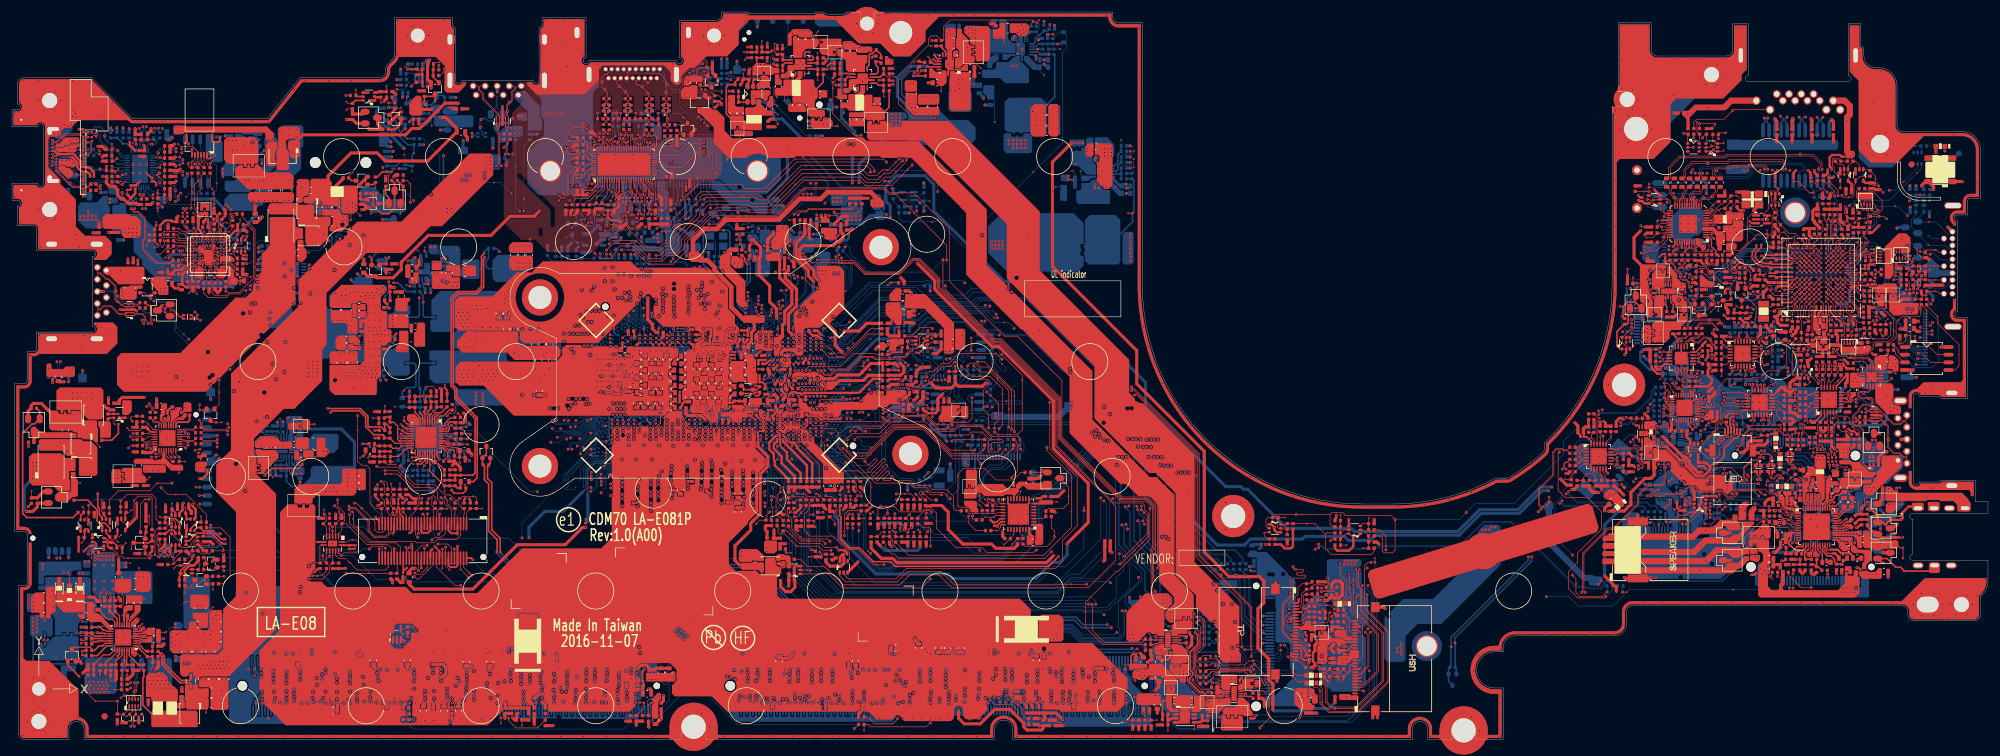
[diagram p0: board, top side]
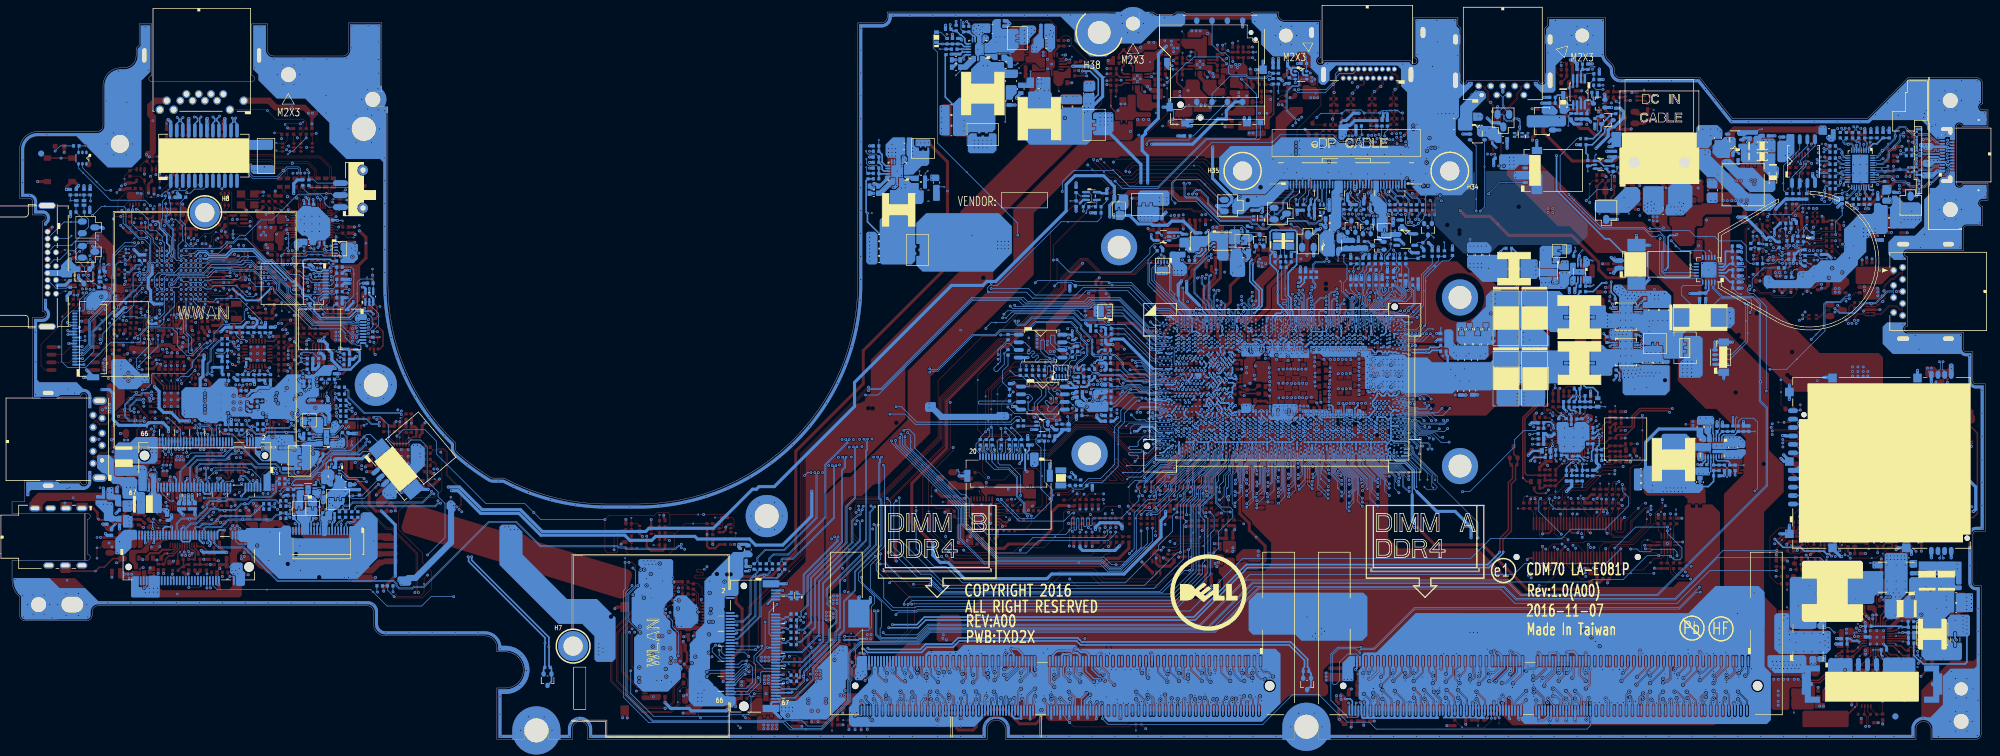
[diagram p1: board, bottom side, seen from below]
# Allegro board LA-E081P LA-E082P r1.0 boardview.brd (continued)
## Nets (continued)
LAN_MDIP0_L: RL71.2 TL1.12
LAN_MDIP1: RL73.1 UL1.17
LAN_MDIP1_L: RL73.2 TL1.6
LAN_MDIP2: RL75.1 UL1.20
LAN_MDIP2_L: RL75.2 TL1.9
LAN_MDIP3: RL77.1 UL1.23
LAN_MDIP3_L: RL77.2 TL1.3
LAN_TEST_EN: RL12.1 UL1.30
LAN_WAKE#: RC323.1 RL70.1 UC1.AM15 UE1.L3 UL1.2
LCD_CBL_DET#: JEDP1.40 RC287.1 UC1.AC3
LCD_TST: JEDP1.29 RE20.1 UE1.D1
LCD_VCC_TEST_EN: DV3.2 UE1.E1
LED_10_GRN#: QL2.6 RL19.1
LED_10_GRN_R#: JLOM1.11 RL19.2
LED_100_ORG#: QL1.3 RL20.1
LED_100_ORG_R#: JLOM1.13 RL20.2
LG1_ISL88738: PQ905.4 PU901.9
LG2_ISL88738: PQ904.4 PU901.7
LID_CL#: JLED1.5 RE26.1 UZ10.2
LID_CL#_PCH: T268.1(TP-1) UC1.AW7
LID_CL_NB#: CE8.1 RE25.2 RE26.2 UE1.N11
LINE1_L: CA43.1 UA1.22
LINE1_R: CA44.1 UA1.21
LM393_P: PC949.2 PC1201.2 PD1801.1 PR950.2 PU903.5 PU1201.8
LOM_ACTLED_YEL#: QL1.1 UL1.26
LOM_CABLE_DETECT#: RE505.1 UE1.D2 UL2.4
LOM_SPD10LED_GRN#: QL2.1 RL30.2 UL1.25 UL2.2
LOM_SPD100LED_ORG#: QL1.4 RL29.2 UL1.27 UL2.1
LPM_1.0V_PRIM_COREP: PR410.2 PR426.2 PU402.14
LPM_1VS_VCCIO: PR404.2 PR425.2 PU401.14
LPS_PROTECT#: PR1248.2 PT1.1(TP-1)
LPSS_UART2_RXD: JUART1.3 RC330.1 RC402.1 UC1.AD1
LPSS_UART2_TXD: JUART1.2 RC331.1 RC403.1 UC1.AD2
LX1_ISL88738: PC930.2 PQ905.3 PU901.10
LX2_ISL88738: PQ904.3 PR921.1 PU901.6
LX_1.8VALW: PL501.1 PR502.1 PU501.3
LX_1V_PRIM: PL404.1 PR409.1 PU402.2 PU402.3
LX_1VS_VCCIO: PL402.1 PR405.1 PU401.2 PU401.3
LX_3V: PC102.2 PL100.1 PR106.1 PU100.6 PU100.19 PU100.20
LX_5V: PC114.2 PL101.1 PR112.1 PU102.6 PU102.19 PU102.20
M2280_DEVSLP: JNGFF3.38 RN37.2 UC1.J3
M2280_PCIE_SATA#: JNGFF3.69 QN4.2 RN182.1 RN184.1 RN187.1 RPC4.4 UC1.G4 UN4.20 UN5.20
M3042_DEVSLP: JNGFF2.30 UC1.J2
M3042_PCIE#_SATA: QZ8.2 RPC4.1 UC1.H3 UE1.J12
M3042_PCIE_SATA#: QZ8.1 RZ360.2 UZ36.20
M_ID2#: CV135.1 JCRT1.4
MASK_BASE_LEDS#: QZ7.5 UZ10.4
ME_FW_EC: RC221.1 SW1.1 UE1.G12
ME_FWP: RC221.2 RC223.1 SW1.3
ME_RESET#: RC225.1 RC227.1 UC12.2
ME_SUS_PWR_ACK: RC74.1 UC1.AR13 UE1.B13
MEC_XTAL1: CE28.1 UE1.A1 YE1.1
MEC_XTAL2: CE29.1 RE290.2 YE1.2
MEC_XTAL2_R: RE290.1 UE1.A3
MEDIACARD_IRQ#: RR19.1 UC1.AN8 UR1.32
MEM_INTERLEAVED: RC371.1 RC372.1 UC1.P2
MEM_SMBCLK: CC320.1 QC2.6 RC12.1 UC1.R7
MEM_SMBDATA: QC2.3 RC14.1 UC1.R8
MPHYP_PWR_EN: RC387.1 UC1.AM10
MSCLK: JDEG1.6 RE30.1 RE72.2 UE1.H10
MSDATA: JDEG1.7 RE75.2 RE86.1 UE1.G9
MUX1_DP_SEL: RT89.1 UT9.23
MUX1_DPEQ0: RT139.1 RT140.1 RT306.1 UT9.14
MUX1_DPEQ1: RT247.1 RT248.1 RT303.1 UT9.2
MUX1_FLIP_SEL: RT69.2 RT375.1 UT9.21
MUX1_FLIP_SEL_R: RT69.1 UT5.B2
MUX1_I2C_EN: RT145.1 RT300.1 RT301.1 UT9.17
MUX1_SSEQ0: RT137.1 RT138.1 RT302.1 UT9.11
MUX1_SSEQ1: RT135.1 RT136.1 RT305.1 UT9.3
MUX1_USB_EQ0: RT143.1 RT144.1 RT304.1 UT9.38
MUX1_USB_EQ1: RT141.1 RT142.1 RT307.1 UT9.35
MUX1_USB_SEL: RT90.1 RT376.1 UT9.22
NB_PSID: PD4.2 PD4.3 PJPDC1.1 PL3.2
NRB_BIT: RC186.1 UC1.AR7
NTC_GT: PR610.2 PU602.3
NTC_GT_R: PH601.2 PR610.1 PR631.2
NTC_IA: PR635.2 PU602.15
NTC_R_IA: PH603.2 PR635.1 PR647.2
NVME_LED#: JNGFF3.10 RN100.1
ONE_DIMM#: RC267.1 RC268.1 UC1.AP7
OTG_ID: RT74.1 UT5.E10
OTGEN/CMIN: PR919.2 PR960.2 PU901.20
PANEL_BKEN_EC: DV2.2 UE1.J9
PANEL_BKLEN: DV2.3 UC1.R12
PANEL_ID: CE47.1 RE300.2 UE1.J10
PBAT_CHARGER_SMBCLK: PD2.3 PR922.1 PRP1.3 RE43.1 UE1.N2
PBAT_CHARGER_SMBDAT: PD1.2 PR920.1 PRP1.2 RE37.1 UE1.M3
PBAT_PRES#: PD1.3 PR1.2 PR931.1 PRP1.1 UE1.F9
PBAT_PRES#_C: PBATT1.6 PRP1.8
PBAT_SMBCLK_C: PBATT1.4 PRP1.6
PBAT_SMBDAT_C: PBATT1.5 PRP1.7
PBATT+_C: PBATT1.1 PBATT1.2 PBATT1.3 PC1.1 PL1.1 PL2.1
PCH_ALW_ON: RPE10.3 RZ65.1 UE1.M8
PCH_BATLOW#: RC72.1 UC1.AU13
PCH_CL_CLK1: JNGFF1.34 UC1.G3
PCH_CL_DATA1: JNGFF1.32 UC1.G2
PCH_CL_RST1#: JNGFF1.30 UC1.G1
PCH_DPWROK: CC266.1 RC215.1 RC220.1 RE536.2 UC1.BB20 UE7.1
PCH_DPWROK_EC: RE34.1 UE1.F8
PCH_JTAG_TCK: JXDP1.55 RC86.1 UC1.B56
PCH_JTAG_TDI: CC304.1 RC81.1 RC229.2 UC1.D59
PCH_JTAG_TDO: CC303.1 RC82.1 RC230.2 UC1.A56
PCH_JTAG_TMS: RC130.1 RC228.2 UC1.C59
PCH_PCIE_WAKE#: RC67.1 RE274.2 UC1.BB15 UE1.L1
PCH_PLTRST#: RC60.1 RC62.1 RC244.1 UC1.AN10 UC7.1 UC7.2
PCH_PLTRST#_5105: RE340.1 UE1.K1 UE6.4
PCH_PLTRST#_AND: CZ61.1 JNGFF1.44 JNGFF1.58 JNGFF2.42 JNGFF3.50 RC65.1 RC325.1 RZ114.1 UC7.4 UR1.1
PCH_PLTRST#_EC: RC244.2 RE375.2 UE6.2
PCH_POPIRCOMP: RC89.1 UC1.AU16
PCH_PWROK: PR614.1 RC411.1 UC1.BA20
PCH_RSMRST#: RE342.1 RE363.2 RE364.2 UZ6.1
PCH_RSMRST#_AND: RC75.1 RC124.1 RC215.2 UC1.AY17 UZ6.4
PCH_RSMRST#_GPIO204: RE363.1 UE1.H2
PCH_RTCRST#: CC25.1 CMOS1.1 JAPS1.9 RC57.1 RE94.2 UC1.AM16
PCH_RTCX1: CC23.1 RC54.2 UC1.AM18 YC2.1
PCH_RTCX2: RC54.1 RC296.1 UC1.AM20
PCH_RTCX2_R: CC26.1 RC296.2 YC2.2
PCH_SMB_ALERT#: RC23.1 UC1.R10
PCH_SPI_CLK: JSPI1.13 RC35.2 UC1.AV2
PCH_SPI_CLK_0_R: RC29.1 RPC1.6 UC5.6
PCH_SPI_CLK_1_R: RC28.1 RC408.2 UC6.6
PCH_SPI_CLK_2_R: RZ60.2 RZ63.2 UZ12.19
PCH_SPI_CLK_R1: JSPI1.14 RC35.1 RC408.1 RPC1.3 RZ60.1
PCH_SPI_CS#0: JSPI1.11 RC36.2 UC1.AU3
PCH_SPI_CS#0_R1: JSPI1.12 RC36.1 RC37.1
PCH_SPI_CS#0_R2: RC37.2 UC5.1
PCH_SPI_CS#1: JSPI1.19 RC32.2 UC1.AU2
PCH_SPI_CS#1_R1: JSPI1.20 RC32.1 RC42.1
PCH_SPI_CS#1_R2: RC42.2 UC6.1
PCH_SPI_CS#2: RZ61.1 UC1.AU1
PCH_SPI_CS#2_R: RZ61.2 RZ113.1 UZ12.20
PCH_SPI_D0: JSPI1.17 RC10.2 RC33.2 UC1.AV3
PCH_SPI_D0_0_R: RPC1.7 UC5.5
PCH_SPI_D0_1_R: RC409.2 UC6.5
PCH_SPI_D0_2_R: RZ59.2 UZ12.21
PCH_SPI_D0_R1: JSPI1.18 RC33.1 RC409.1 RPC1.2 RZ59.1
PCH_SPI_D1: JSPI1.15 RC34.2 UC1.AW3
PCH_SPI_D1_0_R: RPC1.8 UC5.2
PCH_SPI_D1_1_R: RC410.2 UC6.2
PCH_SPI_D1_2_R: RZ58.2 UZ12.24
PCH_SPI_D1_R1: JSPI1.16 RC34.1 RC410.1 RPC1.1 RZ58.1
PCH_SPI_D2: JSPI1.9 RC11.2 RC38.2 UC1.AW2
PCH_SPI_D2_0_R: RC39.2 UC5.3
PCH_SPI_D2_1_R: RC43.2 UC6.3
PCH_SPI_D2_R1: JSPI1.10 RC30.1 RC38.1 RC39.1 RC43.1
PCH_SPI_D3: JSPI1.7 RC40.2 UC1.AU4
PCH_SPI_D3_0_R: RPC1.5 UC5.7
PCH_SPI_D3_1_R: RC407.2 UC6.7
PCH_SPI_D3_R1: JSPI1.8 RC31.1 RC40.1 RC316.1 RC407.1 RPC1.4
PCH_SPI_DO2_XDP: JXDP1.60 RC11.1
PCH_SPI_DO_XDP: RC10.1 RC128.1 RC133.1
PCI_CLK_LPC1: RC22.1 UC1.AY9
PCIE_PRX_C_DTX_N1: CR14.2 UR1.8
PCIE_PRX_C_DTX_N9: CL2.2 UL1.39
PCIE_PRX_C_DTX_N11: JNGFF3.29 RN82.1
PCIE_PRX_C_DTX_N12: JNGFF3.43 RN78.1
PCIE_PRX_C_DTX_P1: CR13.2 UR1.7
PCIE_PRX_C_DTX_P9: CL1.2 UL1.38
PCIE_PRX_C_DTX_P11: JNGFF3.31 RN81.1
PCIE_PRX_C_DTX_P12: JNGFF3.41 RN77.1
PCIE_PRX_C_RD_DTX_N8: CZ142.2 UZ36.4
PCIE_PRX_C_RD_DTX_N11: CN27.2 UN4.4
PCIE_PRX_C_RD_DTX_N12: CN37.2 UN5.4
PCIE_PRX_C_RD_DTX_P8: CZ141.2 UZ36.5
PCIE_PRX_C_RD_DTX_P11: CN26.2 UN4.5
PCIE_PRX_C_RD_DTX_P12: CN36.2 UN5.5
PCIE_PRX_DTX_N1: CR14.1 UC1.H13
PCIE_PRX_DTX_N3: JNGFF1.35 UC1.H16
PCIE_PRX_DTX_N4: JNGFF1.59 UC1.G15
PCIE_PRX_DTX_N8: CZ142.1 UC1.G21
PCIE_PRX_DTX_N9: CL2.1 UC1.E22
PCIE_PRX_DTX_N11: CN27.1 UC1.E28
PCIE_PRX_DTX_N12: CN37.1 UC1.E30
PCIE_PRX_DTX_P1: CR13.1 UC1.G13
PCIE_PRX_DTX_P3: JNGFF1.33 UC1.G16
PCIE_PRX_DTX_P4: JNGFF1.57 UC1.F15
PCIE_PRX_DTX_P8: CZ141.1 UC1.F21
PCIE_PRX_DTX_P9: CL1.1 UC1.E23
PCIE_PRX_DTX_P11: CN26.1 UC1.E27
PCIE_PRX_DTX_P12: CN36.1 UC1.F30
PCIE_PRX_RD_DTX_N8: JNGFF2.35 UZ36.15
PCIE_PRX_RD_DTX_N11: RN82.2 UN4.15
PCIE_PRX_RD_DTX_N12: RN78.2 UN5.15
PCIE_PRX_RD_DTX_P8: JNGFF2.33 UZ36.14
PCIE_PRX_RD_DTX_P11: RN81.2 UN4.14
PCIE_PRX_RD_DTX_P12: RN77.2 UN5.14
PCIE_PTX_C_DRX_N1: CR12.2 UR1.4
PCIE_PTX_C_DRX_N3: CZ13.2 JNGFF1.29
PCIE_PTX_C_DRX_N4: CZ15.2 JNGFF1.53
PCIE_PTX_C_DRX_N8: CZ10.2 JNGFF2.39
PCIE_PTX_C_DRX_N9: CL6.2 UL1.42
PCIE_PTX_C_DRX_N11: CN69.1 JNGFF3.35
PCIE_PTX_C_DRX_N12: CN71.1 JNGFF3.47
PCIE_PTX_C_DRX_P1: CR11.2 UR1.3
PCIE_PTX_C_DRX_P3: CZ12.2 JNGFF1.27
PCIE_PTX_C_DRX_P4: CZ14.2 JNGFF1.51
PCIE_PTX_C_DRX_P8: CZ11.2 JNGFF2.41
PCIE_PTX_C_DRX_P9: CL5.2 UL1.41
PCIE_PTX_C_DRX_P11: CN70.1 JNGFF3.37
PCIE_PTX_C_DRX_P12: CN72.1 JNGFF3.49
PCIE_PTX_C_RD_DRX_N8: CZ136.2 UZ36.2
PCIE_PTX_C_RD_DRX_N11: CN23.2 UN4.2
PCIE_PTX_C_RD_DRX_N12: CN33.2 UN5.2
PCIE_PTX_C_RD_DRX_P8: CZ135.2 UZ36.1
PCIE_PTX_C_RD_DRX_P11: CN22.2 UN4.1
PCIE_PTX_C_RD_DRX_P12: CN32.2 UN5.1
PCIE_PTX_DRX_N1: CR12.1 UC1.B17
PCIE_PTX_DRX_N3: CZ13.1 UC1.D17
PCIE_PTX_DRX_N4: CZ15.1 UC1.B19
PCIE_PTX_DRX_N8: CZ136.1 UC1.D21
PCIE_PTX_DRX_N9: CL6.1 UC1.B23
PCIE_PTX_DRX_N11: CN23.1 UC1.D24
PCIE_PTX_DRX_N12: CN33.1 UC1.A25
PCIE_PTX_DRX_P1: CR11.1 UC1.A17
PCIE_PTX_DRX_P3: CZ12.1 UC1.C17
PCIE_PTX_DRX_P4: CZ14.1 UC1.A19
PCIE_PTX_DRX_P8: CZ135.1 UC1.C21
PCIE_PTX_DRX_P9: CL5.1 UC1.A23
PCIE_PTX_DRX_P11: CN22.1 UC1.C24
PCIE_PTX_DRX_P12: CN32.1 UC1.B25
PCIE_PTX_RD_DRX_N8: CZ10.1 UZ36.17
PCIE_PTX_RD_DRX_N11: CN69.2 UN4.17
PCIE_PTX_RD_DRX_N12: CN71.2 UN5.17
PCIE_PTX_RD_DRX_P8: CZ11.1 UZ36.18
PCIE_PTX_RD_DRX_P11: CN70.2 UN4.18
PCIE_PTX_RD_DRX_P12: CN72.2 UN5.18
PCIE_RCOMPN: RC45.1 UC1.F5
PCIE_RCOMPP: RC45.2 UC1.E5
PCIE_WAKE#: JNGFF1.47 JNGFF1.62 JNGFF2.46 JNGFF3.54 RE274.1 RE275.1
PCIE_WAKE#_R: RE35.1 RE275.2 UE1.N13
PD1_GPIO2: RT71.1 UT5.D10
PD1_GPIO6: RT75.1 UT5.G10
PD1_GPIO7: RT339.1 UT5.D7
PD1_GPIO8: RT76.1 RT377.1 UT5.H6
PD#: CA31.1 DA8.2 RA18.1 RA48.2 RA50.2 UA1.47
PDA_RESET#_R: RT110.2 UT5.F11
PECI_EC: RE60.2 UC1.A54
PECI_EC_R: RE60.1 UE1.K13
PGOOD_3V: PR107.2 PR119.1 PU100.9
PGOOD_5V: PR113.2 PR120.1 PU102.9
PLTRST_LAN#: RC62.2 UL1.36
PLTRST_TPM#: RC60.2 RC325.2 UZ12.17
PM_LANPHY_ENABLE: RL7.1 UC1.AW17
PME#: T115.1(TP-1) UC1.AU11
POA_WAKE#: JUSH1.4 RE324.1 UE1.E4
PORT80_DET#: RE512.1 RE513.1 RZ131.1 UE1.K4
POWER_SW#_MB: CE10.1 JAPS1.11 RE33.2 SW3.2 SW3.4
POWER_SW_IN#: CE12.1 RE31.2 RE33.1 UE1.D5
PRIM_PWRGD_GPIO024: RE361.1 RE362.1 UE1.C1
PROCHOT#_ISL88738: PQ1216.1 PR926.2 PU901.23
PROG1_CPU: PR608.1 PU602.32
PROG2_CPU: PR611.1 PU602.31
PS8348B_CFG: RV85.1 RV86.1 UV7.21
PS8348B_PC1: RV83.1 RV84.1 UV7.22
PS8348B_PC2: RV81.1 RV82.1 UV7.23
PS8348B_PC3: RV79.1 RV80.1 UV7.45
PS8348B_PEQ: RV87.1 RV88.1 UV7.18
PS8348B_PI0: RV95.1 RV96.1 UV7.2
PS8348B_PI1: RV93.1 RV94.1 UV7.3
PS8348B_SW0: RV89.1 RV90.1 UV7.5
PS8348B_SW1: RV91.1 RV92.1 UV7.4
PS_ID: PR4.1 PR5.2 UE1.L11
PWM1_GT: PR680.1 PU602.12 PU612.8
PWM_IA: PR662.1 PU602.22 PU610.8
PWM_SA: PR606.2 PU614.3
PWM_VSA: PR606.1 PU602.30
RD1_A_DE0: RN25.2 RN38.1 UN4.6
RD1_A_DE1: RN26.2 RN39.1 UN4.8
RD1_A_EQ0: RN42.2 RN179.1 UN4.23
RD1_A_EQ1: RN43.2 RN176.1 UN4.22
RD1_A_EQ2: RN44.2 RN174.1 UN4.19
RD1_B_DE0: RN27.2 RN40.1 UN4.13
RD1_B_DE1: RN28.2 RN41.1 UN4.9
RD1_B_EQ0: RN49.2 RN52.1 UN4.11
RD1_B_EQ1: RN50.2 RN53.1 UN4.21
RD1_B_EQ2: RN51.2 RN54.1 UN4.16
RD1_REXT: RN30.1 UN4.10
RD2_A_DE0: RN55.2 RN59.1 UN5.6
RD2_A_DE1: RN56.2 RN60.1 UN5.8
RD2_A_EQ0: RN225.2 UN5.23
RD2_A_EQ0_R: QN5.3 RN63.2 RN225.1
RD2_A_EQ1: RN224.2 UN5.22
RD2_A_EQ1_R: QN5.6 RN64.2 RN224.1
RD2_A_EQ2: RN223.2 UN5.19
RD2_A_EQ2_R: QN4.3 RN65.2 RN223.1
RD2_B_DE0: RN57.2 RN61.1 UN5.13
RD2_B_DE1: RN58.2 RN62.1 UN5.9
RD2_B_EQ0: RN69.2 RN72.1 UN5.11
RD2_B_EQ1: RN70.2 RN73.1 UN5.21
RD2_B_EQ2: RN71.2 RN74.1 UN5.16
RD2_REXT: RN31.1 UN5.10
RD5_A_DE0: RZ154.2 RZ155.1 UZ36.6
RD5_A_DE1: RZ156.2 RZ157.1 UZ36.8
RD5_A_EQ0: RZ354.2 RZ355.1 UZ36.23
RD5_A_EQ1: RZ356.2 RZ357.1 UZ36.22
RD5_A_EQ2: RZ358.2 RZ359.1 UZ36.19
RD5_B_DE0: RZ158.2 RZ159.1 UZ36.13
RD5_B_DE1: RZ160.2 RZ161.1 UZ36.9
RD5_B_EQ0: RZ162.2 RZ163.1 UZ36.11
RD5_B_EQ1: RZ164.2 RZ165.1 UZ36.21
RD5_B_EQ2: RZ166.2 RZ167.1 UZ36.16
RD5_REXT: RZ348.1 UZ36.10
RED: CV129.1 DV5.2 JCRT1.1 LV16.2
RED_CRT: CV126.1 LV16.1 RV116.1 UV6.23
REM_DIODE1_N: CE24.1 CE35.1 QE3.3 UE1.A8
REM_DIODE1_P: CE24.2 CE35.2 QE3.1 QE3.2 UE1.A7
REM_DIODE2_N: CE26.1 CE37.2 CE46.2 QE5.3 QE7.1 QE7.2 UE1.A10
REM_DIODE2_P: CE26.2 CE37.1 CE46.1 QE5.1 QE5.2 QE7.3 UE1.A9
REM_DIODE4_N: CE27.1 CE39.1 QE6.3 UE1.A11
REM_DIODE4_P: CE27.2 CE39.2 QE6.1 QE6.2 UE1.B10
RES_BIAS: RL13.1 UL1.12
RESET_OUT#_R: CC33.1 JXDP1.47 RC128.2 RC129.2
RING2: LA10.1 RA5.2 UA1.17
RING2_R: CA4.1 CA13.2 DA3.3 JHP1.4 LA10.2
RJ45_MDIN0: JLOM1.2 TL1.14
RJ45_MDIN1: JLOM1.6 TL1.20
RJ45_MDIN2: JLOM1.5 TL1.17
RJ45_MDIN3: JLOM1.8 TL1.23
RJ45_MDIP0: JLOM1.1 TL1.13
RJ45_MDIP1: JLOM1.3 TL1.19
RJ45_MDIP2: JLOM1.4 TL1.16
RJ45_MDIP3: JLOM1.7 TL1.22
RTCRST_ON: QE12.2 RE93.1 RE514.2 RE515.2
RTCRST_ON_GPIO122: RE515.1 UE1.F11
RTCRST_ON_GPIO141: RE514.1 UE1.B6
RTD3_CIO_PWR_EN: T18.1(TP-1) UC1.AC2
RUN_ON: PR402.1 QE2.2 RE280.2 RE292.1 RZ320.1 RZ345.1 UE5.4 UZ3.5 UZ4.3 UZ35.2
RUN_ON#: QE2.5 QE2.6 RE68.1
RUN_ON_1.8V: CZ197.1 RZ345.2 UZ8.3
RUN_ON_EC: RE292.2 RPE10.4 UE1.E8 UE5.2
RUNPWROK: QE2.3 RE67.1 UC8.1 UC8.4 UC8.10 UC8.13 UE1.G3
SA_LGATE: PQ501.8 PU614.5
SA_SNUB: PC622.1 PR627.2
SA_SW: PL614.2 PQ501.9 PR619.2 PR624.1 PR627.1 PU614.8
SA_UGATE: PQ501.1 PU614.1
SATA_LED_EN: QZ2.5 UE2.14
SATA_PRX_C_DTX_N0: CN6.1 JSATA1.5
SATA_PRX_C_DTX_P0: CN7.1 JSATA1.6
SATA_PRX_C_RD_DTX_N0: CN14.2 UN7.4
SATA_PRX_C_RD_DTX_P0: CN15.2 UN7.5
SATA_PRX_DTX_N0: CN14.1 UC1.F20
SATA_PRX_DTX_P0: CN15.1 UC1.E20
SATA_PRX_RD_DTX_N0: CN6.2 UN7.12
SATA_PRX_RD_DTX_P0: CN7.2 UN7.11
SATA_PTX_C_DRX_N0: CN5.1 JSATA1.3
SATA_PTX_C_DRX_P0: CN4.1 JSATA1.2
SATA_PTX_C_RD_DRX_N0: CN13.2 UN7.2
SATA_PTX_C_RD_DRX_P0: CN12.2 UN7.1
SATA_PTX_DRX_N0: CN13.1 UC1.B21
SATA_PTX_DRX_P0: CN12.1 UC1.A21
SATA_PTX_RD_DRX_N0: CN5.2 UN7.14
SATA_PTX_RD_DRX_P0: CN4.2 UN7.15
SATALED#: QZ2.4 RN100.2 RN101.2 RPC4.2 UC1.H1
SBIOS_TX: RE306.1 UC1.AB2
SCL_ISL88738: PR922.2 PU901.22
SD/MMCCD#: JSD1.18 UR1.30
SD/MMCCLK: RR5.1 UR1.17
SD/MMCCLK_R: CR21.1 JSD1.5 RR5.2
SD/MMCCMD: RR6.1 UR1.19
SD/MMCCMD_R: JSD1.2 RR6.2
SD/MMCDAT0/RCLK+: RR10.1 UR1.16
SD/MMCDAT0/RCLK+_R: JSD1.7 RR10.2
SD/MMCDAT1/RCLK-: RR9.1 UR1.15
SD/MMCDAT1/RCLK-_R: JSD1.8 RR9.2
SD/MMCDAT2: RR8.1 UR1.21
SD/MMCDAT2_R: JSD1.9 RR8.2
SD/MMCDAT3: RR7.1 UR1.20
SD/MMCDAT3_R: JSD1.1 RR7.2
SD_GPIO: RR3.2 UR1.28
SD_RCOMP: RC96.1 UC1.AB7
SD_UHS2_D0N: JSD1.12 UR1.25
SD_UHS2_D0P: JSD1.11 UR1.26
SD_UHS2_D1N: JSD1.15 UR1.23
SD_UHS2_D1P: JSD1.16 UR1.22
SDA_ISL88738: PR920.2 PU901.21
SDWP: QR1.1 UR1.29
SDWP_Q: JSD1.19 QR1.3
SHD_CLK: RE374.1 UE1.J8
SHD_CLK_R1: RE374.2 UE9.6
SHD_CS#: RE98.1 RE364.1 UE1.M5 UE9.1
SHD_IO0: CE503.1 QE13.5 RE366.1 RE530.1 UE1.J7
SHD_IO0_R1: RE366.2 RE367.1
SHD_IO0_R2: RE367.2 UE9.5
SHD_IO1: RE368.1 UE1.L6
SHD_IO1_R1: RE368.2 RE369.1
SHD_IO1_R2: RE369.2 UE9.2
SHD_IO2: RE360.1 RE370.1 UE1.L7
SHD_IO2_R1: RE370.2 RE371.1 RE376.1
SHD_IO2_R2: RE371.2 UE9.3
SHD_IO3: RE372.1 UE1.M6
SHD_IO3_R1: RE372.2 RE373.1 RE377.1
SHD_IO3_R2: RE373.2 UE9.7
SIM_DET: JNGFF2.58 JSIM1.9
SIO_EXT_SCI#: RC237.1 RE341.1 UC1.AN7
SIO_EXT_SCI#_EC: RE341.2 UE1.M1
SIO_EXT_SMI#: RC346.1 RE338.1 UC1.A6
SIO_EXT_SMI#_EC: RE338.2 UE1.K7
SIO_EXT_WAKE#: RC283.1 UC1.AC1 UE1.M12
SIO_PWRBTN#: CC269.1 JXDP1.41 RC241.1 UC1.BA15 UE1.K11
SIO_RCIN#: RC13.1 RE339.1 UC1.AW13
SIO_RCIN#_EC: RE339.2 UE1.N3
SIO_SLP_A#: JAPS1.6 UC1.AN16 UE1.M11
SIO_SLP_LAN#: RC68.1 RC344.1 UC1.AW15 UE1.H9 UZ2.5
SIO_SLP_S0#: JAPS1.15 PR425.1 PR426.1 RZ112.1 RZ363.1 UC1.AT11 UZ35.1
SIO_SLP_S3#: JAPS1.2 QE11.2 RE280.1 UC1.AP15 UE1.K9 UE3.2 UE5.1
SIO_SLP_S4#: JAPS1.5 PR208.2 PR513.1 UC1.BA16 UE1.N12 UZ21.4 UZ34.2
SIO_SLP_S5#: JAPS1.4 UC1.AY16 UE1.N8
SIO_SLP_SUS#: PR312.2 PR406.1 PR504.1 RE349.1 RZ64.1 UC1.AN15 UZ34.1
SIO_SLP_WLAN#: RZ71.1 UC1.BB17 UE1.D9
SLEEVE: LA11.1 RA6.2 UA1.18
SLEEVE_R: CA1.2 CA12.1 DA3.2 JHP1.3 LA11.2
SLOT2_CONFIG_0: JNGFF2.13 RPE9.3 UE1.N9
SLOT2_CONFIG_1: JNGFF2.61 RPE9.1 UE1.M10
SLOT2_CONFIG_2: JNGFF2.67 RPE9.2 UE1.N10
SLOT2_CONFIG_3: JNGFF2.1 RPE9.4 UE1.F4
SLOT2_SATA_LED#: JNGFF2.10 RN101.1
SM_RCOMP0: RC5.1 UC1.AR18
SM_RCOMP1: RC6.1 UC1.AT18
SM_RCOMP2: RC7.1 UC1.AU18
SML0_SMBCLK: CC318.1 RC19.1 RC347.1 UC1.R9 UL1.28
SML0_SMBDATA: RC20.1 RC348.1 UC1.W2 UL1.31
SML1_SMBCLK: CC319.1 RC15.1 UC1.W3 UE1.D8
SML1_SMBDATA: RC17.1 UC1.V3 UE1.E11
SNB_+1VALWP: PC302.1 PR303.2
SNUB_1.8VALW: PC506.1 PR502.2
SNUB_1V_PRIM: PC419.1 PR409.2
SNUB_1VS_VCCIO: PC401.1 PR405.2
SNUB_CHG1: PC940.1 PR923.2
SNUB_CHG2: PC941.1 PR924.2
SPKR: RA12.2 RC183.1 UC1.AW5
SPKR_R: CA27.1 CA72.1 RA12.1 RA51.1
SRTCRST#: CC24.1 RC56.1 UC1.AN18
SS_1V_PRIM: PC420.1 PR428.1 PU402.7
SS_1VS_VCCIO: PC410.1 PR427.1 PU401.7
SUSACK#: UC1.AP11 UE1.K12
SUSCLK: RC48.1 RN99.2 RZ56.1 UC1.BA17
SUSCLK_R: JNGFF3.68 RN99.1
SW1_ISL88738: PL902.1 PQ905.5 PQ905.6 PQ905.7 PR923.1
SW2_DP1_AUXN: CT81.1 CT116.1 RV70.1 UV7.61
SW2_DP1_AUXN_C: CT116.2 RT131.1 UT9.25
SW2_DP1_AUXP: CT80.1 CT115.1 RV76.1 UV7.62
SW2_DP1_AUXP_C: CT115.2 RT130.1 UT9.24
SW2_DP1_CADET: RV73.1 UV7.48
SW2_DP1_HPD: RT73.2 RT380.1 UV7.53
SW2_DP1_HPD_R: RT73.1 UT5.C10
SW2_DP1_N0: CT104.1 UV7.54
SW2_DP1_N0_C: CT104.2 UT9.10
SW2_DP1_N1: CT106.1 UV7.51
SW2_DP1_N1_C: CT106.2 UT9.13
SW2_DP1_N2: CT108.1 UV7.49
SW2_DP1_N2_C: CT108.2 UT9.16
SW2_DP1_N3: CT110.1 UV7.46
SW2_DP1_N3_C: CT110.2 UT9.19
SW2_DP1_P0: CT103.1 UV7.55
SW2_DP1_P0_C: CT103.2 UT9.9
SW2_DP1_P1: CT105.1 UV7.52
SW2_DP1_P1_C: CT105.2 UT9.12
SW2_DP1_P2: CT107.1 UV7.50
SW2_DP1_P2_C: CT107.2 UT9.15
SW2_DP1_P3: CT109.1 UV7.47
SW2_DP1_P3_C: CT109.2 UT9.18
SW2_DP2_AUXN: CV150.1 RV71.1 UV7.59
SW2_DP2_AUXN_C: CV150.2 JNGFF1.12
SW2_DP2_AUXP: CV149.1 RV77.1 UV7.60
SW2_DP2_AUXP_C: CV149.2 JNGFF1.14
SW2_DP2_CADET: RV74.1 UV7.37
SW2_DP2_HPD: JNGFF1.23 UV7.42
SW2_DP2_N0: CV156.1 UV7.43
SW2_DP2_N0_C: CV156.2 JNGFF1.24
SW2_DP2_N1: CV152.1 UV7.40
SW2_DP2_N1_C: CV152.2 JNGFF1.18
SW2_DP2_N2: CV148.1 UV7.38
SW2_DP2_N2_C: CV148.2 JNGFF1.17
SW2_DP2_N3: CV145.1 UV7.35
SW2_DP2_N3_C: CV145.2 JNGFF1.11
SW2_DP2_P0: CV157.1 UV7.44
SW2_DP2_P0_C: CV157.2 JNGFF1.26
SW2_DP2_P1: CV153.1 UV7.41
SW2_DP2_P1_C: CV153.2 JNGFF1.20
SW2_DP2_P2: CV147.1 UV7.39
SW2_DP2_P2_C: CV147.2 JNGFF1.19
SW2_DP2_P3: CV146.1 UV7.36
SW2_DP2_P3_C: CV146.2 JNGFF1.13
SW2_DP3_AUXN: CV112.1 RV72.1 UV7.57
SW2_DP3_AUXN_C: CV112.2 UV6.3
SW2_DP3_AUXP: CV111.1 RV78.1 UV7.58
SW2_DP3_AUXP_C: CV111.2 UV6.2
SW2_DP3_CADET: RV75.1 UV7.26
SW2_DP3_HPD: RV102.1 UV6.32 UV7.31
SW2_DP3_N0: CV108.1 UV7.32
SW2_DP3_N0_C: CV108.2 UV6.6
SW2_DP3_N1: CV110.1 UV7.29
SW2_DP3_N1_C: CV110.2 UV6.8
SW2_DP3_P0: CV107.1 UV7.33
SW2_DP3_P0_C: CV107.2 UV6.5
SW2_DP3_P1: CV109.1 UV7.30
SW2_DP3_P1_C: CV109.2 UV6.7
SW2_ISL88738: PL902.2 PQ904.5 PQ904.6 PQ904.7 PR924.1
SW_+1VALWP: PL301.1 PR303.1 PR304.2 PU301.6 PU301.19 PU301.20
SW_USB20_N1: LI7.1 UI3.11
SW_USB20_P1: LI7.4 UI3.10
SYS_LED_MASK#: QL1.2 QL1.5 QL2.2 RE21.1 UE1.A12 UZ10.1
SYS_PWROK: RC129.1 RE56.1 UC1.B6 UE1.G4
SYS_RESET#: CC302.1 JAPS1.13 RC224.2 RC291.1 UC1.B5
SYS_RESET#_R: RC224.1 RC290.2 UC12.4
TBT_FORCE_PWR: T19.1(TP-1) UC1.B7
TBT_RESET_N_EC_R: RE95.2 UE1.L8
TBTA_AUXN_C: CT81.2 RT95.1 UT5.J2
TBTA_AUXP_C: CT80.2 RT96.1 UT5.J1
TBTA_BOT_N: RT122.2 UT5.L7
TBTA_BOT_N_R: DT20.1 JUSBC1.B7 RT122.1
TBTA_BOT_P: RT123.2 UT5.K7
TBTA_BOT_P_R: DT19.1 JUSBC1.B6 RT123.1
TBTA_CC1: CT86.1 DT7.1 JUSBC1.A5 RT104.2 UT5.L9
TBTA_CC2: CT85.1 DT16.1 JUSBC1.B5 RT105.2 UT5.L10
TBTA_DBG_CTL1: RT106.1 UT5.E4
TBTA_DBG_CTL2: RT107.1 UT5.D5
TBTA_DEBUG1: RT92.2 UT5.L2
TBTA_DEBUG2: RT93.2 UT5.K2
TBTA_DEBUG3: RT89.2 UT5.L3
TBTA_DEBUG4: RT90.2 UT5.K3
TBTA_LSRX_R: RT88.2 UT5.K4
TBTA_LSTX_R: RT87.2 UT5.L4
TBTA_MRESET: RT86.1 UT5.E11
TBTA_ROM_CLK_PD: RT54.1 UT5.A3
TBTA_ROM_CLK_PD_R: JDB1.2 RT54.2 UT6.6
TBTA_ROM_CS#_PD: RT57.1 UT5.B3
TBTA_ROM_CS#_PD_R: JDB1.5 RT51.2 RT57.2 UT6.1
TBTA_ROM_DI_PD: RT55.1 UT5.B4
TBTA_ROM_DI_PD_R: JDB1.3 RT55.2 UT6.5
TBTA_ROM_DO_PD: RT56.1 UT5.A4
TBTA_ROM_DO_PD_R: JDB1.4 RT52.2 RT56.2 UT6.2
TBTA_ROM_HOLD#_PD: RT50.2 UT6.7
TBTA_ROM_WP#_PD: RT53.2 UT6.3
TBTA_ROSC: RT100.1 UT5.G2
TBTA_RX1N: DT14.1 JUSBC1.B10 UT9.31
TBTA_RX1P: DT13.1 JUSBC1.B11 UT9.30
TBTA_RX2N: DT9.1 JUSBC1.A10 UT9.39
TBTA_RX2P: DT10.1 JUSBC1.A11 UT9.40
TBTA_SBU1: DT8.1 JUSBC1.A8 RT108.2 RT132.2
TBTA_SBU1_R: RT108.1 UT5.K8
TBTA_SBU2: DT15.1 JUSBC1.B8 RT109.2 RT133.2
TBTA_SBU2_R: RT109.1 UT5.L8
TBTA_TOP_N: RT121.1 UT5.L6
TBTA_TOP_N_R: DT12.1 JUSBC1.A7 RT121.2
TBTA_TOP_P: RT120.1 UT5.K6
TBTA_TOP_P_R: DT11.1 JUSBC1.A6 RT120.2
TBTA_TX1N: CT96.1 UT9.34
TBTA_TX1N_C: CT96.2 DT6.1 JUSBC1.A3
TBTA_TX1P: CT95.1 UT9.33
TBTA_TX1P_C: CT95.2 DT5.1 JUSBC1.A2
TBTA_TX2N: CT98.1 UT9.36
TBTA_TX2N_C: CT98.2 DT18.1 JUSBC1.B3
TBTA_TX2P: CT97.1 UT9.37
TBTA_TX2P_C: CT97.2 DT17.1 JUSBC1.B2
TDI_XDP: JXDP1.56 RC229.1 UC8.5
TDO_XDP: CC306.1 JXDP1.52 RC230.1 UC8.2
THERMATRIP1#: RE301.1 UE1.B12
THERMATRIP2#: CE36.1 QE4.1 RE69.2 UE1.H3
TOUCH_SCREEN_DET#: JEDP1.32 RV8.1 UC1.AY5
TOUCH_SCREEN_PD#: JEDP1.5 RC272.1 UC1.A7
TOUCHPAD_INTR#: JKBTP1.5 RC414.1 RE318.2 UC1.BA5
TP_LAN_JTAG_TCK: RL2.1 UL1.35
TP_LAN_JTAG_TDI: T88.1(TP-1) UL1.32
TP_LAN_JTAG_TDO: T89.1(TP-1) UL1.34
TP_LAN_JTAG_TMS: RL1.1 UL1.33
TPM_GPIO4: T283.1(TP-1) UZ12.13
TPM_LPM#: QZ9.1 RZ111.1 RZ363.2 UZ12.3
TPM_PIRQ#: RZ69.2 UC1.AP8 UZ12.18
TPM_TYPE: RC349.1 UC1.AY7
TRST#_XDP: JXDP1.54 UC8.12
TUSB546A_SBU1_R: RT132.1 UT9.27
TUSB546A_SBU2_R: RT133.1 UT9.26
TYPEC_ID: CE62.1 RE343.2 UE1.F2
UART_MISO: RT82.1 RT83.2 UT5.F2
UART_MOSI: RT81.1 RT83.1 UT5.E2
UG1_ISL88738: PQ905.2 PU901.11
UG2_ISL88738: PQ904.2 PU901.5
UIM_CLK: CZ38.1 JNGFF2.24 JSIM1.3
UIM_DATA: CZ39.1 JNGFF2.26 JSIM1.7 RZ335.2
UIM_RESET: CZ40.1 JNGFF2.22 JSIM1.2
UPD1_ALERT#: RE91.1 RT60.1 UE1.F10
UPD1_SMBCLK: QT1.1 RE303.1 RT58.1 UE1.C3
UPD1_SMBCLK_Q: QT1.6 RT58.2 RT67.1 RT92.1 RT375.2 UT5.B5
UPD1_SMBDAT: QT1.4 RE302.1 RT59.1 UE1.B4
UPD1_SMBDAT_Q: QT1.3 RT59.2 RT66.1 RT93.1 RT376.2 UT5.A5
UPD1_SMBUS_ALERT#: RT60.2 RT68.1 UT5.B6
UPD2_ALERT#: RE92.1 UE1.F5
UPD2_SMBCLK: RPE12.3 UE1.D7
UPD2_SMBDAT: RPE12.4 UE1.E7
USB1_A_DE0: RI53.1 RI54.1 UI5.16
USB1_A_DE1: RI51.1 RI52.1 UI5.18
USB1_A_EQ0: RI40.1 RI41.1 UI5.17
USB1_A_EQ1: RI38.1 RI39.1 UI5.15
USB1_B_DE0: RI57.1 RI58.1 UI5.3
USB1_B_DE1: RI55.1 RI56.1 UI5.6
USB1_B_EQ0: RI44.1 RI45.1 UI5.2
USB1_B_EQ1: RI42.1 RI43.1 UI5.4
USB1_TEST: RI34.2 UI5.14
USB2_ID: RC337.1 RT74.2 UC1.AG3
USB2_VBUSSENSE: RC338.1 UC1.AG4
USB3_PD#: RI37.2 RI81.2 UI5.5
USB3_PRX_C_DTX_N6: CT112.2 UT9.4
USB3_PRX_C_DTX_P6: CT111.2 UT9.5
USB3_PRX_C_RD_DTX_N1: CI42.2 UI5.23
USB3_PRX_C_RD_DTX_P1: CI41.2 UI5.22
USB3_PRX_DTX_N1: CI42.1 UC1.H8
USB3_PRX_DTX_N2: LI16.4 RI28.1 UC1.J6
USB3_PRX_DTX_N3: DI1.1 DI1.9 JUSB2.5 UC1.J10
USB3_PRX_DTX_N4: DI6.1 DI6.9 JUSB3.5 UC1.E10
USB3_PRX_DTX_N6: CT112.1 UC1.G11
USB3_PRX_DTX_P1: CI41.1 UC1.G8
USB3_PRX_DTX_P2: LI16.1 RI27.1 UC1.H6
USB3_PRX_DTX_P3: DI1.2 DI1.8 JUSB2.6 UC1.H10
USB3_PRX_DTX_P4: DI6.2 DI6.8 JUSB3.6 UC1.F10
USB3_PRX_DTX_P6: CT111.1 UC1.F11
USB3_PRX_L_DTX_N2: JNGFF2.21 LI16.3 RI28.2
USB3_PRX_L_DTX_P2: JNGFF2.23 LI16.2 RI27.2
USB3_PRX_RD_DTX_N1: DI4.1 DI4.9 JUSB1.5 UI5.8
USB3_PRX_RD_DTX_P1: DI4.2 DI4.8 JUSB1.6 UI5.9
USB3_PTX_C_DRX_N1: CI13.1 DI4.4 DI4.7 JUSB1.8
USB3_PTX_C_DRX_N2: CI29.1 LI17.4 RI30.1
USB3_PTX_C_DRX_N3: CI5.1 DI1.4 DI1.7 JUSB2.8
USB3_PTX_C_DRX_N4: CI27.1 DI6.4 DI6.7 JUSB3.8
USB3_PTX_C_DRX_N6: CT114.2 UT9.7
USB3_PTX_C_DRX_P1: CI16.1 DI4.5 DI4.6 JUSB1.9
USB3_PTX_C_DRX_P2: CI30.1 LI17.1 RI29.1
USB3_PTX_C_DRX_P3: CI4.1 DI1.5 DI1.6 JUSB2.9
USB3_PTX_C_DRX_P4: CI28.1 DI6.5 DI6.6 JUSB3.9
USB3_PTX_C_DRX_P6: CT113.2 UT9.8
USB3_PTX_C_RD_DRX_N1: CI40.1 UI5.20
USB3_PTX_C_RD_DRX_P1: CI39.1 UI5.19
USB3_PTX_DRX_N1: CI40.2 UC1.C13
USB3_PTX_DRX_N2: CI29.2 UC1.B13
USB3_PTX_DRX_N3: CI5.2 UC1.B15
USB3_PTX_DRX_N4: CI27.2 UC1.C15
USB3_PTX_DRX_N6: CT114.1 UC1.D16
USB3_PTX_DRX_P1: CI39.2 UC1.D13
USB3_PTX_DRX_P2: CI30.2 UC1.A13
USB3_PTX_DRX_P3: CI4.2 UC1.A15
USB3_PTX_DRX_P4: CI28.2 UC1.D15
USB3_PTX_DRX_P6: CT113.1 UC1.C16
USB3_PTX_L_DRX_N2: JNGFF2.27 LI17.3 RI30.2
USB3_PTX_L_DRX_P2: JNGFF2.29 LI17.2 RI29.2
USB3_PTX_RD_DRX_N1: CI13.2 UI5.11
USB3_PTX_RD_DRX_P1: CI16.2 UI5.12
USB20_N1: UC1.AB9 UI3.2
USB20_N1_R: DI5.2 JUSB1.2 LI7.2
USB20_N2: LI3.4 UC1.AD6
USB20_N2_R: DI2.3 JUSB2.2 LI3.3
USB20_N3: LI4.4 UC1.AH3
USB20_N3_R: DI3.3 JUSB3.2 LI4.3
USB20_N4: LI8.4 RI48.1 UC1.AD9
USB20_N4_L: JNGFF2.9 LI8.3 RI48.2
USB20_N5: LZ1.1 UC1.AJ1
USB20_N5_R: JEDP1.12 LZ1.2
USB20_N7: LI9.1 RI50.1 UC1.AH1
USB20_N7_L: JNGFF1.5 LI9.2 RI50.2
USB20_N8: LV27.3 UC1.AF8
USB20_N8_R: DV4.2 JEDP1.2 LV27.4
USB20_N9: UC1.AG1 UT5.K5
USB20_N10: JUSH1.8 UC1.AH7
USB20_P1: UC1.AB10 UI3.3
USB20_P1_R: DI5.3 JUSB1.3 LI7.3
USB20_P2: LI3.1 UC1.AD7
USB20_P2_R: DI2.2 JUSB2.3 LI3.2
USB20_P3: LI4.1 UC1.AJ3
USB20_P3_R: DI3.2 JUSB3.3 LI4.2
USB20_P4: LI8.1 RI47.1 UC1.AD10
USB20_P4_L: JNGFF2.7 LI8.2 RI47.2
USB20_P5: LZ1.4 UC1.AJ2
USB20_P5_R: JEDP1.13 LZ1.3
USB20_P7: LI9.4 RI49.1 UC1.AH2
USB20_P7_L: JNGFF1.3 LI9.3 RI49.2
USB20_P8: LV27.2 UC1.AF9
USB20_P8_R: DV4.3 JEDP1.3 LV27.1
USB20_P9: UC1.AG2 UT5.L5
USB20_P10: JUSH1.9 UC1.AH8
USB_OC0#: RPC3.2 UC1.A9 UI3.13
USB_OC1#: RPC3.3 UC1.C9 UI1.3
USB_OC2#: RPC3.4 UC1.D9 UI2.3
USB_OC3#: RPC3.1 UC1.B9
USB_PWR_EN1#: RPE11.3 UE1.K3 UI1.4
USB_PWR_EN2#: RPE11.1 UE1.G5 UI2.4
USB_PWR_SHR_LFT_EN#: RPE11.2 UE1.J3 UI3.6
USB_PWR_SHR_VBUS_EN: RI81.1 RPE11.4 UE1.J2 UI3.5
USBCOMP: RC44.1 UC1.AB6
USH_DET#: DZ7.2 RE526.1 RZ87.1 UE1.C13
USH_DET#_R: DZ7.1 JUSH1.26 RZ87.2
USH_PWR_STATE#: JUSH1.22 RZ10.2 UE2.9
USH_RST#_R: JUSH1.21 RZ114.2
USH_SMBCLK: CZ62.1 JUSH1.11 RZ8.2 UE1.B3
USH_SMBDAT: CZ63.1 JUSH1.12 RZ9.2 UE1.E5
VCI_IN1#: RE507.1 UE1.B5
VCI_IN2#: RE508.1 UE1.D4
VCT_LAN_R1: RL3.1 UL1.6
VGA_ID: RE84.1 RE85.1 UE1.H11
VID0_PRIM_CORE: PR408.2 PR418.2 PR420.1 PU402.9
VID0_VCCIO: PR414.2 PR416.1 PU401.9
VID1_PRIM_CORE: PR411.2 PR417.2 PR419.1 PU402.8
VID1_VCCIO: PR413.2 PR415.1 PU401.8
VIDALERT_N: PR604.2 PR625.1 RC152.1 RC153.2
VIDALERT_N_B: PR625.2 PU602.36
VIDSCLK: CC321.1 PR601.2 PR618.1 UC1.A63
VIDSCLK_B: PR618.2 PU602.37
VIDSOUT: PR605.2 PR626.1 RC157.1 UC1.D64
VIDSOUT_B: PR626.2 PU602.35
VR_HOT#_CPU: PR678.2 PU602.38
VR_READY_CPU: PR612.2 PR614.2 PU602.39
VRALERT#: RC73.1 UC1.AM11
VSA_SEN+: PC640.2 PC650.1 PC652.1 PR649.2 RC168.2 UC1.H20
VSA_SEN-: PC649.1 PC650.2 PU602.26 RC166.1 UC1.H21
VSET_5105: CE38.1 RE77.1 UE1.C9
VSYNC_CONN: CV132.1 JCRT1.14 LV20.2 RV121.1
VSYNC_CRT: LV20.1 UV6.18
VSYS_ISL88738: PC939.1 PR929.1 PU901.3
WIGIG_32KHZ: JNGFF1.42 RZ56.2
WLAN_COEX1: JNGFF1.40 RZ130.2
WLAN_COEX2: JNGFF1.38 RZ129.2
WLAN_COEX3: JNGFF1.36 RZ128.2
WLAN_WIGIG60GHZ_DIS#: DZ1.1 RE8.1 UE1.L13
WLAN_WIGIG60GHZ_DIS#_R: DZ1.2 JNGFF1.48
WRST#: CE500.1 RE6.2 UE2.4
WWAN_COEX1: JNGFF2.56 RZ130.1
WWAN_COEX2: JNGFF2.54 RZ129.1
WWAN_COEX3: JNGFF2.52 RZ128.1
WWAN_PWR_EN: CZ198.1 JNGFF2.6 RZ43.1
WWAN_RADIO_DIS#: DZ5.1 RE10.1 UE1.M2
WWAN_RADIO_DIS#_R: DZ5.2 JNGFF2.8
WWAN_WAKE#: JNGFF2.15 RE38.1 UE1.M13
XCLK_BIASREF: RC52.1 RC324.1 UC1.E42
XDP_DBRESET#: CC32.1 JXDP1.48 RC137.1 RC290.1 UC12.1
XDP_JTAGX: CC305.1 RC87.1 RC328.1 UC1.A59
XDP_OBS0: JXDP1.21 RC239.2
XDP_OBS0_R: RC239.1 UC1.C55
XDP_OBS1: JXDP1.23 RC240.2
XDP_OBS1_R: RC240.1 UC1.D55
XDP_OBS2_R: T10.1(TP-1) UC1.B54
XDP_OBS3_R: T11.1(TP-1) UC1.C56
XDP_PRSNT_PIN1: JXDP1.1 RC121.1 RC122.1
XDP_TMS: JXDP1.58 RC228.1 UC8.9
XTAL24_IN: RC46.2 RC417.1 UC1.E37
XTAL24_IN_R: CC21.1 RC417.2 YC1.3
XTAL24_OUT: RC46.1 RC295.1 UC1.E35
XTAL24_OUT_R: CC22.1 RC295.2 YC1.1
XTALI: CL14.1 RL11.2 UL1.10 YL1.1
XTALO: RL11.1 RL34.2 UL1.9
XTALO_R: CL13.1 RL34.1 YL1.3
Z2805: RL18.1 TL1.24
Z2806: RL16.1 TL1.18
Z2807: RL17.1 TL1.21
Z2808: RL15.1 TL1.15
N43975: QN1.5 QN1.6 RN2.2
N16399089: PD901.1 PD903.1 PD904.1 PR916.2
N16400770: PR901.3 PR910.1
N16404606: PD905.3 PR939.2 PR950.1
N16404788: PD905.1 PU903.1
N16404800: PR946.1 PU903.4
N16783126: PC111.1 PR104.1 PR105.1 PU100.16 PU100.17
N17185089: PQ1204.5 PR1218.1
N17185092: PQ1204.6 PR1214.2 PR1218.2
N17185371: PQ1204.2 PR1223.2
N17370862: PC4.2 PQ4.4 PQ5.1 PR11.2 PR16.1
N17370885: PQ5.2 PR10.2 PR15.1
N17370921: PQ1.6 PR15.2
N17370961: PL3.1 PQ2.1 PR3.1 PR6.2
N17370983: PQ2.3 PR3.2 PR5.1
N17370995: PQ3.2 PR6.1 PR8.2
N17370999: PQ2.2 PQ3.1 PR7.2
N17371029: PC6.1 PQ9.4 PR12.2 PR18.1
N17371125: PQ7.2 PR20.1
N17371184: PR23.2 PU1.4
N17372063: PQ1.3 PR17.2 PR19.1
N17372074: PQ1.5 PR25.2
N17372283: PQ1.2 PR19.2
N17400451: PC515.2 PR515.2 PR516.1 PU503.3
N17479322: PQ1215.2 PR1251.2 PR1252.1
N17494434: PC1211.1 PD1205.1 PQ1212.1 PR1238.1 PR1239.2 PR1246.1 PR1255.2 PU1201.5
N17509431: PC947.1 PR935.1 PR947.1 PR949.2
N18490882: RI14.2 UI3.16
N18762046: CA33.1 RA17.2
N18762152: CZ127.1 UZ5.10
N18762172: CZ126.1 UZ5.12
N18762349: CA51.1 RA44.1 UA1.27
N18762353: CA53.1 UA1.7
N18762355: CA52.1 UA1.39
N18762401: RA53.1 RA54.1 UA1.20
N18762411: CA29.1 UA1.35
N18762416: CA29.2 UA1.37
N18762426: CA35.1 UA1.28
N18762428: CA49.1 UA1.34
N18762438: CA25.1 UA1.19
N20151644: PR901.2 PR909.1
N27076242: PC930.1 PR914.2
N27077001: PR917.2 PR937.2
N28424999: T113.1(TP-1) UC1.AW71
N28425002: T114.1(TP-1) UC1.AW70
N28489601: RC222.1 SW1.2
N28810563: CZ110.1 UZ2.10
N28811129: CZ114.1 UZ3.10
N28856399: T16.1(TP-1) UC1.BA70
N28856402: T17.1(TP-1) UC1.BA68
N28857231: T12.1(TP-1) UC1.BB68
N28857234: T13.1(TP-1) UC1.BB69
N28857237: T14.1(TP-1) UC1.AK13
N28857240: T15.1(TP-1) UC1.AK12
N28861827: RC120.1 UC1.C64
N28938912: CC8.1 RC29.2
N28938914: CC7.1 RC28.2
N29708559: T126.1(TP-1) UC1.AY4
N29708561: T127.1(TP-1) UC1.BB3
N29708599: T128.1(TP-1) UC1.AU5
N29708601: T129.1(TP-1) UC1.AT5
N29708639: T130.1(TP-1) UC1.BB5
N30342894: QV4.2 RV18.2
N32590572: CZ117.1 UZ4.12
N32592963: CZ118.1 UZ4.10
N32594166: CZ109.1 UZ2.12
N32817808: CZ113.1 UZ3.12
N32818355: RZ64.2 RZ65.2 UZ3.3
N32819772: CZ121.1 UZ8.6
N32875032: CZ130.1 UZ23.6
N33199744: JDIMM1.165 T51.1(TP-1)
N33298471: JDIMM2.165 T55.1(TP-1)
N35551558: PC1210.1 PQ1206.4 PR1228.2 PR1229.1
N35551572: PC1214.1 PQ1209.5 PR1243.2
N35551576: PQ1209.2 PQ1209.3 PR1236.1
N35551584: PC1213.1 PD1205.2 PR1238.2 PR1240.2 PR1243.1 PU1201.7
N35551592: PC1212.1 PR1237.2 PR1247.1 PU1201.6
N35551616: PQ1212.2 PR1248.1 PR1249.1 PR1250.1
N35551696: PC1202.2 PQ1213.4 PQ1215.1 PR1205.2 PR1212.1
N35551783: PC1203.2 PQ1202.4 PQ1203.1 PR1207.2 PR1213.1
N35551785: PQ1203.2 PR1202.2 PR1209.1
N35551806: PQ1204.3 PR1209.2
N36626863: CT90.1 RT111.2 UT7.3
N36827741: RZ120.2 UZ26.4 UZ34.4
N37776698: CV96.1 UV7.56
N37776840: RV97.1 UV7.9
N37894644: QE13.1 RE34.2 RE348.1 RE536.1 RE537.2 UE7.3
N37894887: CE5.1 UE7.4
N38798736: RT97.2 RT98.1 RT99.1 UT5.F10
N38798744: RT85.1 UT5.G4
N38798745: RT84.1 UT5.F4
N38798858: RT63.1 UT5.F1
N38798904: RT105.1 UT5.K10
N38798905: RT104.1 UT5.K9
N38798908: RT103.1 UT5.L11
N38798948: RT85.2 T220.1(TP-1)
N38798949: RT84.2 T219.1(TP-1)
N38799002: CT87.1 UT5.H7
N38799008: RT101.1 UT5.D6
N38802239: QV2.1 RV5.2
N38802260: QV7.1 QV8.2 RV6.1
N38804727: JEDP1.21 LV1.1
N39067212: RE57.1 RE58.1 UE1.B1
N39067288: RE318.1 UE1.G2
N39067419: RE349.2 UE1.N4
N39070459: QE11.3 RE70.1 RE90.2
N39070470: QE4.2 RE70.2
N39154673: RV123.2 UV6.10
N39154676: RV124.2 UV6.9
N39468508: PC647.2 PR650.2
N39468570: PC629.2 PR639.1
N39469718: PC627.1 PR632.2
N39469798: PR679.1 PU614.7
N39469812: PH602.1 PR628.2
N39469818: PC631.1 PR630.2
N39469908: PC617.2 PR621.1
N39470129: PC640.1 PR646.2
N39470145: PC601.1 PR652.2
N39470169: PC630.2 PR644.1
N39470173: PC632.2 PR641.1
N39470189: PH604.1 PR642.2
N39470248: PC621.2 PR623.1
N39470270: PH605.1 PR657.2
N39470328: PC614.2 PR617.1
N39470375: PC613.2 PR613.2 PU602.2
N39470546: PC639.2 PR645.1
N39473183: PL610.3 PR661.1
N40543303: RI36.2 UI5.7
N40543312: RI35.2 UI5.24
N40719702: CE57.1 RE350.2
N41288260: JNGFF2.17 RZ326.1
N41303246: CZ38.2 RZ334.1
N41840158: QN4.5 RN182.2 RN183.1 RN192.2
N41840194: QN5.2 RN184.2 RN185.1 RN186.2
N41840238: QN5.5 RN187.2 RN188.1 RN189.2
N45131598: RZ70.2 RZ71.2 UZ4.5
N45200928: JNGFF2.59 T225.1(TP-1)
N45242868: RE13.2 RE14.1 UE2.1
N45242870: RE15.2 RE16.1 UE2.2
N45242966: RE17.2 RE18.1 UE2.3
N45269008: JESPI.8 RE375.1
N45589397: CL17.1 TL1.4
N45589399: CL16.1 TL1.1
N45589425: CL20.1 TL1.7
N45589439: CL21.1 TL1.10
N45863109: CD31.2 RD18.1
N45863346: JDIMM1.162 T50.1(TP-1)
N45879530: JDIMM2.162 T54.1(TP-1)
N45879727: CD62.2 RD31.1
N45886539: RT378.1 UT5.D1
N45886541: RT379.1 UT5.D2
N45912878: PC119.1 PU102.16 PU102.17
N45957243: PR949.1 PU901.29
N45957346: PR936.1 PR948.1 PU901.30
N45971013: PQ8.3 PR26.2 PR28.1
N45971015: PQ8.1 PR22.1 PR27.1
N45971023: PQ8.2 PR29.2
N45972642: PQ1205.2 PR1225.1
N45972646: PQ1205.1 PR1215.1 PR1226.2
N45972650: PQ1205.3 PR1221.2 PR1224.1
N45973945: PQ1208.2 PQ1208.3 PR1259.1
N45973953: PQ1208.5 PR1244.2 PR1260.2 PR1261.1
N45973980: PQ1208.6 PQ1211.1 PR1234.1 PR1261.2
N45974004: PQ1211.5 PR1233.1 PR1242.2
N45974006: PQ1211.2 PR1235.1 PR1257.2
N45974105: PQ1207.6 PQ1211.4 PR1230.1 PR1258.2
N45974290: PQ1207.2 PQ1207.3 PR1232.1
N45981582: PR933.2 PR951.2 PU901.26
N46029111: PC1206.1 PR1201.2 PR1203.1 PR1219.1 PU1201.3
N46029167: PC1205.1 PR1208.2 PR1217.1 PU1201.2
N46142452: PQ1201.2 PR1216.2
N46142922: PR1216.1 PU1200.4
N46144380: PQ1214.6 PR1252.2
N46177388: PQ7.1 PR16.2
N46177446: PQ6.1 PR18.2
N46177523: PQ1209.6 PR1229.2
N46178128: PQ1201.6 PR1212.2
N46178191: PQ1201.3 PR1213.2
N46204184: PC313.1 PU301.16 PU301.17
N46204205: PC307.2 PR308.1
N46260620: PC944.1 PR934.2
N46425689: PR1211.2 PU1200.1
N46425853: PR1215.2 PU1200.2
N46425954: PQ1201.5 PR1220.1
N46426354: PQ1207.5 PR1241.2
N46426548: PQ1210.5 PR1245.2
N46427561: PR21.2 PU1.1
N46427605: PR22.2 PU1.2
N46427645: PQ6.2 PR23.1
N46428671: PR620.2 PU602.1
N46430626: PD905.2 PR941.2
N46430682: PR942.2 PU903.2
N46447690: QZ3.1 RZ25.1
N46932507: RT380.2 UT9.32
N47045001: CZ56.1 RZ63.1
N47045031: RZ112.2 RZ362.2 UZ12.29
N47045035: RZ62.1 UZ12.27
N47045174: QZ9.2 RZ113.2
N47046012: JNGFF2.48 RZ131.2
N47046031: JNGFF2.50 RZ132.2
N47298137: QE12.1 RE94.1
N49127672: QE13.3 QE13.6
N132000604: PC934.1 PR921.2
N132005053: PR917.3 PR938.2
N379222690: T224.1(TP-1) UV7.13
N379222980: T223.1(TP-1) UV7.6
N3792239420: T204.1(TP-1) UV7.8
N4919186218: PR932.1 PU901.27

Pads without a net: CLIP1 1; DV6 3; FD1 1; FD2 1; FD3 1; FD4 1; JAPS1 16 17 18; JDIMM1 87 88 91 92 95 97 100 101 104 105; JDIMM2 87 88 91 92 95 97 100 101 104 105; JEDP1 16 20; JHDMI1 14; JIR1 4; JKBTP1 10 17; JNGFF1 6 8 9; JNGFF2 12 14 16 20 36 38 40 51 53 55 57 60; JNGFF3 5 6 7 8 11 13 17 19 20 22 23 24 25 26 28 30 32 34 36 40 42 44 46 48 56 58 67; JSATA1 8 20; JSIM1 4 6 8; JSPI1 4; JUSH1 2 17; PBATT1 11 12; PD2 2; PRP1 4 5; PU100 10 15; PU102 10; PU200 18 19; PU301 9 10 12; PU401 4; PU402 4; PU503 2 6 7; PU602 13; PU901 13; QL2 3 4 5; QZ7 1 2 6; RC22 2; RC405 2; RPE12 1 2 7 8; RT75 2; RT87 1; RT88 1; RT110 1; RT339 2; RZ326 2; UA1 4 11 12 15 23 24 48; UC1 A3 A4 A11 A26 A27 A29 A31 A33 A36 A38 A45 A47 A52 A65 A69 AB3 AB12 AB13 AB62 AC63 AD3 AD4 AE62 AE63 AF6 AF7 AF11 AF12 AF13 AG62 AH9 AH10 AH11 AH12 AJ62 AK6 AK7 AK9 AK10 AK62 AK70 AL25 AL27 AL61 AL63 AM1 AM2 AM3 AM4 AN1 AN2 AN3 AP1 AP2 AP3 AP4 AP13 AP56 AR56 AU56 AU58 AU63 AW1 AW20 AW48 AW68 AW69 AY1 AY2 AY20 AY21 B2 B3 B11 B26 B27 B29 B31 B33 B36 B38 B45 B47 B52 B69 B70 BA3 BA4 BA7 BA8 BA9 BB2 BB4 BB7 BB9 BB11 BB57 BB66 C2 C4 C7 C8 C11 C12 C19 C20 C23 C27 C28 C29 C31 C32 C33 C36 C37 C38 C54 C70 C71 D1 D3 D4 D5 D7 D12 D19 D20 D23 D27 D28 D29 D31 D32 D33 D36 D37 D38 D54 D71 E1 E2 E3 E16 E25 E61 F6 F16 F18 F25 F52 F60 F61 F65 G18 G61 G65 H11 H63 J4 J68 J71 K45 K46 L6 M1 M2 M3 M4 N1 N2 N3 N9 N11 P1 P3 P62 U6 U7 V1 V2 V62 W4 W7 W12; UD1 1; UE1 B8 B9 F7 F12 F13 J6; UE2 5 6 8 10 11; UE4 1; UE6 1; UI3 9 15; UN4 3; UN5 3; UN7 7; UR1 31; UT5 C1; UT7 4; UV6 11 12 13 27 28 31; UV7 24 25 27 28; UV24 3; UZ12 2 4 5 6 7 10 11 12 15 25 26 28 30 31; UZ36 3; YC1 2 4

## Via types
v1: diameter 0.457, hole 0.203, TOP to BOTTOM, 5964 vias
v2: diameter 0.305, hole 0.152, TOP to BOTTOM, 945 vias
v3: diameter 0.406, hole 0.203, TOP to BOTTOM, 176 vias
v4: diameter 0.508, hole 0.254, TOP to BOTTOM, 96 vias

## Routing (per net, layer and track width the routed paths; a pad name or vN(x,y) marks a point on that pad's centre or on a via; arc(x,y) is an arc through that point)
0.6V_DDR_VTT_ON: length 4.3
  TOP w0.102: v1(67.03,18.12) v2(66.65,18.5) 66.45,18.7 RD19.1 65.34,18.37 UD1.4
  BOTTOM w0.254: PR210.2 v1(42.34,53.53)
1.8V_PRIM_PWRGD: length 100.7
  TOP w0.102: v1(314.46,74.69) 314.46,74.98 314.53,75.05 RE360.2 ; v1(295.65,65.84) 295.65,65.96 296.14,66.45 RE361.2
  TOP w0.254: v1(123.96,109.67) 123.94,109.65 PR517.1 123.05,109.45 PU501.5
  BOTTOM w0.102: v1(123.96,109.67) 121.42,107.13 121.42,100.04 121.62,99.84 129.77,99.84 137.75,91.86 142.58,91.86 v2(145.23,94.52) 151.78,94.52 153.68,92.61 v1(153.68,91.01) ; v1(314.46,74.69) 314.56,74.69 315.98,73.27 315.98,71.42 316.24,71.16 318.1,71.16 319.79,69.47 319.79,62.73 318.81,61.75 315.85,61.75 311.66,65.94 306.94,65.94 306.68,66.2 306.68,67.18 305.52,68.34 301.48,68.34 300.56,67.43 300.56,65.3 299.03,63.76 298.06,63.76 295.98,65.84 v1(295.65,65.84)
2.5VSP: length 4.3
  TOP w0.254: PC515.1 190.98,4.2 190.98,6.27 191.16,6.45 PC516.1
  TOP w0.381: PC515.1 191.01,3.31 PR515.1
  vias: v2(192.09,5.25)
3.3V_CAM_EN#: length 64.9
  TOP w0.076: 130.35,49.35 130.17,49.53 130.17,50.71 130,50.88 129.87,50.88 129.87,50.88 129.54,50.88 129.54,50.88 129.26,50.88 128.88,50.51 v1(128.88,50.47)
  TOP w0.102: v1(115.71,85.59) 117.03,85.59 118.29,86.85 127.06,86.85 131.61,91.41 144.78,91.41 145.62,90.57 146.65,90.57 v2(148.7,88.52) 155.16,82.06 v1(155.16,79.61) ; 130.35,49.35 133.99,45.71 RC311.1
  BOTTOM w0.102: QZ1.2 113.87,84.49 114.6,85.22 115.34,85.22 v1(115.71,85.59) ; v1(128.88,50.47) 129.26,50.85 UC1.AT15
3.3V_TS_EN: length 3.7
  TOP w0.102: v2(152.79,55.89) RC282.1 152.15,54.88 v1(152.02,55.01)
  BOTTOM w0.076: UC1.AP5 134.58,52.15 134.32,52.41 v1(134.32,52.55)
  BOTTOM w0.102: QV7.2 121.56,81.16 v1(121.8,80.92)
3.3V_WWAN_EN: length 32.6
  TOP w0.102: v1(278.12,48.32) 280,48.32 283.22,51.54 283.22,52.3 283.93,53.02 283.93,53.82 284.66,54.55 286.55,54.55 287.28,53.81 287.28,52.8 287.93,52.16 v2(288.16,52.16) 291.5,52.16 292.46,53.12 292.46,53.89 292.22,54.13 v1(292.22,54.2)
  TOP w0.107: UE1.C6 296.77,75.54 v1(296.75,75.54)
  BOTTOM w0.102: v1(278.12,48.32) 277.23,48.32 277.16,48.25 272.83,48.25 272.42,48.66 272.42,50.18 RZ40.2 273.39,50.97 273.54,50.82 273.54,50.13 273.88,49.78 UZ2.3
3V5V_EN: length 7.3
  TOP w0.254: v1(153.04,112.92) 153.35,112.61 PU100.12
  BOTTOM w0.102: v1(153.04,112.92) v2(152.34,112.92)
  BOTTOM w0.254: PD100.1 174.31,115.5 v1(173.6,115.5) PR114.2 PR116.1 171.91,115.5 PC128.1 170.43,115.5 170,115.07 PU102.12
3V_FB: length 2.6
  TOP w0.102: PC113.1 152.45,113.04 v2(152.1,113.39)
  TOP w0.254: PU100.13 153.89,112.16 153.07,112.16 152.76,112.46 PC113.1
3V_FB_R: length 2
  TOP w0.102: PR108.1 149.93,112.65 v2(149.67,112.39)
  TOP w0.254: PC113.2 150.8,112.46 PR108.1
3V_SN: length 1.9
  BOTTOM w0.102: PR106.2 v2(158.95,110.95)
3V_VIN:
  vias: v1(157.98,114.96) v1(157.95,114.33) v1(158.58,114.98) v1(158.59,114.36) v2(158.44,115.49)
5V_FB: length 1.9
  BOTTOM w0.254: PC127.1 v1(170.29,114.63) 170.28,114.62 PU102.13
5V_FB_R: length 2
  BOTTOM w0.102: v2(174.05,114.65) PR117.1
  BOTTOM w0.254: PR117.1 172.96,114.63 PC127.2
5V_SN: length 4.5
  BOTTOM w0.102: PC125.1 163.15,106.11 v2(163.15,102.55)
5V_VIN: length 0.8
  TOP w0.102: v1(164.67,116.65) v2(164.67,115.82)
  vias: v1(163.25,116.65) v1(164.04,116.65)
+0.6V_DDR_VTT: length 5.6
  TOP w0.127: 49.28,52.34 v3(50.17,52.34)
  BOTTOM w0.254: v1(106.73,6.75) 105.89,6.75 105.53,6.39 JDIMM1.258 ; JDIMM2.258 186.53,5.82 v1(187.05,6.34)
  vias: v1(48.97,52.79) v1(48.97,52.15) v1(107.4,6.65) v1(107.45,7.23) v1(189.84,7.31) v1(190.46,7.32)
+0.6VSP:
  vias: v1(46.2,51.9) v1(46.83,51.91) v2(46.04,52.43)
+0.9V_LAN: length 12.3
  TOP w0.203: UL1.37 276.06,82.16 v1(275.76,81.86) ; UL1.8 282.22,86.22 v1(282.3,86.3) ; UL1.11 281.75,87.42 282.2,87.86 v1(282.2,87.98) ; UL1.40 v1(277.26,81.7) ; UL1.43 v1(278.46,81.61) ; UL1.22 v1(276.86,89.68)
  TOP w0.254: UL1.16 279.26,89.32 279.15,89.43 279.15,89.93 v1(279.28,90.06) ; CL8.1 273.95,80.57 v1(273.52,80.14)
  BOTTOM w0.254: CL11.1 278.77,89.55 v1(279.28,90.06) ; CL10.1 276.99,81.97 v1(277.26,81.7) ; CL9.1 276.23,82.11 275.98,81.86 v1(275.76,81.86)
  vias: v1(280.71,81.41) v1(280.98,81.93) v1(284.74,87.5) v1(285.32,87.47) v1(285.88,87.22) v2(280.54,82.76)
+1.0V_AMPHYPLL: length 1.1
  BOTTOM w0.254: UC1.K15 v1(129.68,63.86) UC1.L15
  vias: v1(145.67,72.28) v2(145.62,71.05)
+1.0V_APLL: length 12.7
  TOP w0.508: 134.61,60.02 134.73,59.9 136.47,59.9 137.1,60.53 140.66,60.53 142.56,62.44 LC2.2 144.54,61.36 CC323.1
  BOTTOM w0.254: UC1.V15 129.62,60.09 129.77,60.24 v1(129.86,60.24)
  vias: v2(133.74,60.65)
+1.0V_APLLEBB: length 1.5
  TOP w0.381: v1(127.06,62.19) 127.06,62.09 126.48,61.51 CC325.1
  BOTTOM w0.254: v1(127.06,62.19) UC1.N18
  vias: v1(146.41,74.03) v2(145.95,73.51)
+1.0V_CLK1: length 20.1
  TOP w0.508: RC302.2 131.6,86.17 131.6,83.84 130.18,82.42 130.18,79.96 132.21,77.93 132.21,76.97 v1(133.09,76.08)
  BOTTOM w0.203: 130.9,72.08 130.4,71.59 130.4,71.23 129.66,70.49 129.66,69.5 129.66,69.5 UC1.A14
  BOTTOM w0.508: v1(133.09,76.08) 133.03,76.02 133.03,74.22 v2(131.63,72.81) 130.9,72.08
+1.0V_CLK2: length 15.2
  TOP w0.508: 126.85,80.31 127.45,79.71 127.45,76.68 129.47,74.66 129.47,72.27 128.28,71.07 128.28,69.18 127.92,68.82 127.92,67.38
  BOTTOM w0.254: v1(127.06,63.86) 126.74,64.18 UC1.K19
  vias: v2(126.85,64.61)
+1.0V_CLK3: length 3.2
  TOP w0.508: v1(128.15,78) 128.26,78.1 RC303.2
  BOTTOM w0.127: v1(128.15,78) 128.15,77.44 v2(128.11,77.4)
  BOTTOM w0.254: v1(125.76,63.86) UC1.L21
+1.0V_CLK4: length 0.5
  BOTTOM w0.254: v1(125.76,62.18) UC1.N20
  vias: v1(125.4,77.48) v2(124.45,78.49)
+1.0V_CLK5: length 2.5
  TOP w0.305: v1(126.41,63.02) 126.3,62.91 125.69,62.91 125.17,62.39 RC52.2
  BOTTOM w0.254: v1(126.41,63.02) UC1.L19
  vias: v1(135.12,83.58) v2(136.56,83.28)
+1.0V_CLK6: length 25
  TOP w0.508: v1(133.93,76.16) 133.1,77 133.1,77.91 130.79,80.22 130.79,81.48 131.32,82.01 136.35,82.01 136.97,82.63 137.36,82.63 137.96,83.23 137.96,83.94 137.6,84.3 CC216.1 RC300.2
  BOTTOM w0.203: 134.43,73.74 134.34,73.65 134.34,72.95 132.51,71.12 132.51,70.21 132.14,69.84 UC1.A10
  BOTTOM w0.508: v1(133.93,76.16) 133.93,76.02 v2(134.43,75.52) 134.43,73.74
+1.0V_DTS: length 10.5
  BOTTOM w0.203: UC1.T1 138.64,61.56
  BOTTOM w0.508: RC301.2 145.39,66.49 143.57,66.49 v2(141.9,64.82) 138.64,61.56
+1.0V_MPHYAON: length 11.7
  TOP w0.508: v1(137.88,64.23) 136.66,65.46 136.66,67.76 134.02,70.4 ; 129.78,64.7 CC203.1 128.11,64.7 127.71,64.3 v1(127.71,63.86)
  BOTTOM w0.254: UC1.L1 137.63,64.21 137.65,64.23 v1(137.88,64.23) ; v1(127.71,63.86) UC1.K17
  vias: v1(133.88,77.88) v1(133.88,77.25) v1(134.52,77.88) v1(134.52,77.25) v1(135.1,77.88) v1(135.1,77.24) v2(133.14,77.98)
+1.0V_MPHYGT: length 2.8
  BOTTOM w0.254: UC1.N16 129.01,62.92 v1(129.01,63.02) ; UC1.P16 128.69,61.8 128.38,62.11 v1(128.38,62.18) 128.38,62.26 UC1.N17 ; UC1.N15 129.03,62.29 v1(129.03,62.18) 129.03,62.07 UC1.P15
  vias: v1(119.93,79.01) v1(120.56,79.11) v1(120.51,78.51) v1(120.89,79.8) v1(121.08,78.66) v1(121.16,79.27) v1(136.33,89.94) v1(136.33,89.29) v1(136.96,89.96) v1(136.97,89.28) v1(137.55,89.95) v1(137.59,89.32) v1(155.03,64.44) v1(155.66,64.43) v1(156.16,66.12) v1(156.18,65.53) v3(127.86,62.77)
+1.0V_PRIM: length 59.2
  TOP w0.508: v1(126.37,84.35) 126.37,83.94 v3(126,83.57) 125.46,83.04 RC170.1 ; v4(95.23,35.2) 94.7,35.2 91.84,32.34 83.89,32.34 76.52,24.97 66.74,24.97 65.92,25.8 RC216.1 ; LC2.1 146.59,62.44 v1(147.14,61.88) ; RC302.1 132.59,85.65 132.34,85.4 132.34,83.36 v1(132.59,83.11) ; v1(127.67,61.32) 127.8,61.45 CC206.1 ; v1(129.14,82.95) 128.26,82.07 RC303.1 ; v1(145.32,65.6) 145.01,65.3 CC225.1 143.85,65.3 v1(143.36,64.81) ; v1(138.82,86.25) 138.51,85.95 RC300.1 ; RC171.1 136.53,85.62 137.8,86.89 v1(138.82,86.89)
  BOTTOM w0.203: v1(124.92,53.9) 124.96,53.86 125.58,53.86 125.71,53.99 UC1.AK20
  BOTTOM w0.254: UC1.AB20 126.09,58.36 v1(126.39,57.97) 126.39,58.06 UC1.AB19 126.78,58.41 v1(127.09,58.02) ; v1(127.71,59.67) 127.39,59.34 UC1.Y18 127.8,58.83 127.8,58.65 UC1.AB17 ; UC1.P18 127.67,61.4 v1(127.67,61.32)
  BOTTOM w0.508: v1(145.32,65.6) 146.24,65.6 146.49,65.85 RC301.1
  vias: v1(139.45,86.89) v1(139.45,86.25) v1(140.09,86.89) v1(140.09,86.25) v1(140.72,86.89) v1(140.72,86.25) v1(162.63,82.7) v1(162.63,82.1) v1(162.63,81.51) v1(163.23,82.7) v1(163.23,82.1) v1(163.23,81.51) v1(163.83,82.7) v1(163.83,82.1) v1(163.83,81.51) v1(164.42,82.7) v1(164.42,82.1) v1(164.42,81.51)
+1.0V_PRIM_CORE: length 5.7
  TOP w0.127: 135.9,101.87 v3(137.04,101.87)
  TOP w0.508: v1(127.06,56.31) 127.06,56.87 126.73,57.21 CC205.1
  BOTTOM w0.254: v1(125,60.42) 124.79,60.22 v1(124.79,59.82) 125.23,59.82 UC1.V21 125.51,60.01 126.01,60.01 UC1.V20 ; UC1.AF19 v1(127.06,56.31) UC1.AF18
  vias: v1(134.68,102.15) v1(135.29,102.2) v1(135.34,102.91) v1(135.87,102.63)
+1.0V_PRIM_COREP: length 3.7
  TOP w0.254: PR423.2 134.67,109.16 133.48,107.97 ; v1(129.61,109.97) 130.08,110.44 PU402.1
  vias: v1(132.8,107.78) v2(132.63,105.42)
+1.0V_PRIM_XDP: length 11.4
  TOP w0.127: RC115.2 v2(128.96,86.25)
  TOP w0.254: v1(63.84,37.79) 63.95,37.91 63.95,38.33 CC29.1 64.34,38.32 64.34,37.52 64.95,36.9 JXDP1.43 ; CC28.1 64.95,27.73 JXDP1.44
  TOP w0.305: RC138.2 75.06,39.85 v1(75.21,40) ; v1(65.51,28.49) 64.9,27.88 CC28.1
  TOP w0.508: RC216.2 65.92,27.9 66.44,28.43 v1(66.92,28.43) ; v1(129.9,85.49) RC115.2
+1.0V_SRAM: length 3
  TOP w0.381: CC217.1 125.55,57.33 v1(125.76,57.13)
  BOTTOM w0.254: UC1.AF20 126.09,56.8 v1(125.76,57.13) 125.44,56.8 UC1.AF21 ; UC1.T20 126.09,60.81 126.32,60.57 126.32,60.52 v1(126.35,60.49) 126.74,60.87 UC1.T19
  vias: v1(121.54,72.82) v1(121.89,72.19) v2(118.24,78.89)
+1.0V_VCCST: length 177.6
  TOP w0.508: RE90.1 v1(281.33,74.69) ; RE59.1 v1(305.65,88.11) ; v1(126.99,69.96) 126.94,70 126.94,71.51 125.78,72.67 125.78,75.36 124.03,77.11 v3(124.03,78.63) 124.03,79.96 CC202.1 124.27,81.75 123.05,82.97 v1(122.64,82.97) ; v1(125.11,63.86) 125.02,63.77 CC195.1 ; RC218.2 64.39,40.53 v1(64.9,40.02)
  BOTTOM w0.152: v1(126.99,69.96) 127.18,69.76 UC1.A18
  BOTTOM w0.254: UC1.K20 125.99,64.28 125.95,64.31 125.57,64.31 125.53,64.28 UC1.K21 125.44,64.18 v1(125.11,63.86) ; RC71.2 v1(97.67,80.69) ; RC120.2 v1(98.68,80.6) ; RC80.2 v1(100.72,80.54)
  BOTTOM w0.508: PC602.1 72.4,50.37 v1(72.78,50.37) 73.02,50.37 73.43,50.78 PR601.1 PR604.1 PR605.1 ; v1(145.8,86.76) 145.8,88.66 145.04,89.43 RZ151.2 145.04,91.83 146.84,93.63 151.56,93.63 153.04,92.16 153.04,87.78 164.75,76.07 166.22,76.07 166.88,75.41 172.06,75.41 188.17,59.29 188.17,55.31 201.5,41.99 204.04,41.99 204.48,41.55 205.13,41.55 211.6,35.07 222.31,35.07 222.84,34.54 240.02,34.54 243.64,38.16 250,38.16 253.77,41.93 v1(255.63,41.93) ; RC79.2 v1(101.61,77.23) ; v1(98.38,78.24) 98.68,77.93 RC157.2 ; RC152.2 v1(99.7,78.38)
  vias: v1(122.45,83.62)
+1.0V_VCCST_C: length 0.6
  BOTTOM w0.127: v2(125.09,85.03) 125.09,84.47
+1.0V_VCCSTG: length 64.4
  TOP w0.305: RC131.2 50.81,28.39 v1(50.24,27.82)
  TOP w0.508: 123.22,69.46 123.22,68.04 122.74,67.56 122.74,66.11 122.29,65.66 RC143.2 121.5,65.16 CC199.1 ; v1(53.73,37.41) RC135.2 ; RC134.2 v1(50.82,36.73)
  TOP w0.762: v1(144,89.1) 144,89.45 142.59,90.86 135.34,90.86 134.27,89.79 130.77,89.79 127.3,86.32 118.52,86.32 116.97,84.78 v3(115.77,84.78) 114.91,84.78 113.06,82.92 v1(113.06,80.38) ; v1(114.08,79.8) 114.31,79.57 115.45,79.57 116.63,78.39 116.63,77.94 119.41,75.16 119.41,71.8 121.47,69.74
  BOTTOM w0.203: v1(124.39,70.1) 124.5,70.1 124.7,69.89 UC1.A22
  BOTTOM w0.508: RC83.2 93.66,81.42 v1(94.06,81.81) ; v1(101.63,80.54) 101.73,80.43 RC87.2 ; RC82.2 v1(105.8,80.56) ; v1(103.41,80.56) 103.76,80.21 RC81.2 ; RC130.2 v1(102.75,80.56)
  vias: v1(143.13,89.12)
+1.0V_VCCSTG_C: length 14.1
  BOTTOM w0.508: UZ19.6 131.61,84.13 133.56,86.07 135.51,86.07 v2(136.03,85.56) 136.2,85.39 138.71,85.39 138.94,85.62 141.09,85.62 142.49,87.01 143.52,87.01
+1.0V_VCCSTG_R: length 0.5
  BOTTOM w0.254: v1(126.12,65.94) UC1.G20
  vias: v2(125.59,67.75)
+1.0VO_DSW: length 6.7
  TOP w0.254: CC204.1 132.14,53.71 133.67,53.71 134.18,53.21 v2(136.07,53.21) 137.44,53.21 v1(137.63,53.39)
  BOTTOM w0.254: v1(137.63,53.39) 137.35,53.39 UC1.AL1
+1.0VS_VCCIO: length 85.3
  TOP w0.508: RC132.2 v1(63.38,39.9) ; v1(105.54,73.42) 105.54,69.74 106.3,68.98 106.3,68.22 106.94,67.58 RC2.2 ; QE11.1 v1(281.21,70.44)
  BOTTOM w0.203: v1(120.63,54.62) 120.86,54.62 UC1.AK28 ; v1(120.63,54.62) UC1.AL30 ; v1(120.63,54.62) 120.4,54.62 UC1.AK30 ; UC1.AL30 120.17,53.47 UC1.AM30 ; UC1.AL30 v1(120.63,53.06)
  BOTTOM w0.254: v1(119.72,53.06) UC1.AM30 ; v1(113.32,53.06) UC1.AM42 v1(114.23,53.06) UC1.AL42 ; UC1.AM28 v1(120.63,53.06)
  BOTTOM w0.508: v1(255.07,41.32) 254.02,41.32 250.24,37.54 243.88,37.54 240.27,33.93 226.33,33.93 225.47,33.07 221.86,33.07 221.2,33.72 214.68,33.72 214.25,33.29 205.62,33.29 204.6,32.28 200.11,32.28 195.28,37.1 v1(195.28,41.22)
  vias: v1(142.37,100.98) v1(202.43,13.66) v1(202.42,13.03) v1(203.02,13.66) v1(203.02,13.03) v1(203.63,13.66) v1(203.62,13.05) v3(168.66,83.71)
+1.2V_DDR_B+:
  vias: v1(41.41,46.87) v1(42.13,46.84) v1(42.83,46.84) v1(43.46,46.83) v2(43.46,46.22)
+1.2V_DDR_BST: length 1.3
  TOP w0.102: v2(46.11,47.66) 47.04,47.66 PR203.1
  vias: v1(47.8,46.51)
+1.2V_DDR_BST_R: length 2.6
  TOP w0.102: PR203.2 48.67,46.44 48.29,46.07 47.31,46.07 v2(47.25,46.13)
+1.2V_DDR_FB: length 5.4
  BOTTOM w0.102: v2(43.31,43.58) 43.31,45.12 PR206.1
  BOTTOM w0.203: PR204.2 45.56,45.58 PU200.16
  BOTTOM w0.254: PR206.1 PC208.2 PR204.2
+1.2V_DDR_LX:
  vias: v1(51.77,47.82) v1(52.36,47.82) v2(52.13,47.3)
+1.2V_DDR_SNB: length 1.1
  TOP w0.102: 47.85,49.93 47.16,49.93 v2(46.89,50.2)
+1.2V_DDR_VCC: length 1.5
  BOTTOM w0.203: PC207.1 46.46,45.87 PU200.14
+1.2V_DDR_VTTREF: length 3.7
  BOTTOM w0.102: PC218.1 44.98,51.15 44.53,51.59 v2(44.53,53.23)
  BOTTOM w0.203: PC218.1 44.98,50.87 45.11,50.74 PU200.3
+1.2V_DDRP: length 19.8
  BOTTOM w0.254: PC208.1 PR204.1 45.55,44.63 PC217.1 45.55,42.86 46.42,41.99 47.79,41.99
  BOTTOM w0.508: 48.2,51.56 54.65,51.56 56.86,49.35 PC223.1
  vias: v1(50.22,41.77) v1(50.74,41.17) v1(50.86,41.77) v1(51.38,41.17) v1(51.49,41.77) v1(52.01,41.17) v1(52.13,41.77) v1(52.65,41.17) v1(52.76,41.77) v1(53.28,41.17) v1(53.4,41.77) v1(53.92,41.17) v1(55.78,44.72) v1(55.73,44.09) v1(55.73,43.48) v1(55.72,42.83) v1(55.72,42.21) v3(55.76,41.29)
+1.2V_LDO:
  vias: v1(24.77,53.23) v1(28.33,53.52) v2(27.69,53.29)
+1.2V_MEM: length 118.1
  TOP w0.102: v1(74.6,14.37) 75.38,13.59 CD6.1
  TOP w0.254: CD16.1 47.47,14.15 v1(47.86,14.55) ; CD42.1 171.33,11.84 v1(171.25,11.76) ; v1(176.55,6.73) 177.19,6.09 CD48.1
  TOP w0.356: CD32.1 90.52,12.01 v1(90.78,11.75)
  TOP w0.508: CD9.1 102.76,10.06 v1(102.78,10.08)
  BOTTOM w0.152: v1(119.64,46.54) 119.63,46.55 UC1.BB32
  BOTTOM w0.178: v1(124.8,46.16) 124.8,46.21 124.65,46.36 124.65,47.46 UC1.BB23 ; UC1.BB47 111.02,46.54 v1(111.06,46.5)
  BOTTOM w0.203: v1(120.63,50.55) 120.63,50.53 120.96,50.2 UC1.AU28 ; UC1.BB51 108.57,46.56 v1(108.52,46.51) ; UC1.BB41 114.59,47.4 114.59,46.54 114.62,46.51 v1(114.61,46.51)
  BOTTOM w0.254: JDIMM2.199 171.78,12.02 171.52,11.76 v1(171.25,11.76) ; JDIMM2.33 v1(128.28,11.6) ; v1(123.37,50.55) 123.37,50.55 123.65,50.27 123.76,50.27 UC1.AU23 ; v1(181.74,11.1) 182.28,11.63 JDIMM2.241 ; v1(42.16,6.05) 42.03,5.91 JDIMM1.12 ; JDIMM2.75 138.78,14.12 v1(138.92,14.27) ; UC1.AU35 117.36,50.27 117.23,50.27 v1(116.98,50.52) ; v1(74.53,3.29) 74.47,3.24 73.72,3.24 73.03,3.94 JDIMM1.136 ; JDIMM1.153 79.28,14.63 v1(79.27,14.63) ; JDIMM2.147 158.78,11.31 v1(158.19,10.72) ; JDIMM1.163 81.78,13.97 81.95,14.15 v1(81.95,14.72) ; JDIMM2.96 v1(144.03,3.57) ; UC1.AU42 113.45,50.52 v1(113.35,50.52) ; v1(176.55,6.73) 177.03,6.26 JDIMM2.220 ; v1(152,14.52) 152.18,14.7 154.5,14.7 155.28,13.92 JDIMM2.141 ; JDIMM1.199 v1(90.78,11.75) ; JDIMM2.178 166.53,6.92 v1(166.31,7.13) ; JDIMM1.130 v1(71.53,3.21) ; v1(133.41,6.67) 133.53,6.55 JDIMM2.54 ; v1(79.38,3.45) 79.53,3.59 JDIMM1.154 ; v1(162.12,15) 161.15,15 160.28,14.12 JDIMM2.153 ; JDIMM2.148 v1(159.03,3.38) ; JDIMM1.96 63.03,6.35 v1(63.47,6.8) ; v1(77.86,3.32) 78.03,3.49 JDIMM1.148 ; JDIMM1.178 v1(85.53,6.07) ; v1(162.11,14.39) 162.29,14.39 162.78,13.91 JDIMM2.163 ; v1(52.71,6.62) 52.52,6.44 JDIMM1.54 ; JDIMM1.33 47.27,13.96 v1(47.86,14.55) ; JDIMM2.12 v1(123.03,6.15) ; v1(81.03,6.62) 81.27,6.38 81.27,5.88 81.03,5.63 JDIMM1.160 ; JDIMM1.112 v1(67.03,6.08) ; JDIMM1.75 v1(57.78,14.78) ; JDIMM1.124 v1(70.03,3.15)
  BOTTOM w0.305: v1(66.78,14.31) JDIMM1.111 ; JDIMM1.241 101.28,11.3 102.49,10.08 v1(102.78,10.08) ; v1(151.59,14.95) 151.04,14.95 150.58,14.49 149.74,14.49 149.28,14.03 JDIMM2.117 ; JDIMM1.141 74.27,14.05 v1(74.6,14.37) ; v1(152,14.52) 151.87,14.39 151.21,14.39 150.78,13.96 JDIMM2.123 ; JDIMM1.123 69.78,14.14 69.88,14.24 v1(69.88,14.42) 69.75,14.55 68.76,14.55 68.27,14.06 JDIMM1.117 ; JDIMM1.135 72.78,14.18 72.63,14.32 v1(71.66,14.32) 71.58,14.32 71.27,14.01 JDIMM1.129 ; v1(162.11,14.39) 161.78,14.06 JDIMM2.159 ; JDIMM2.136 v1(154.03,3.5) ; v1(81.41,14.37) 81.28,14.37 80.78,13.86 JDIMM1.159 ; JDIMM2.111 147.78,13.99 147.5,14.27 v1(147.3,14.27) ; v1(78.73,14.29) 78.21,14.29 77.78,13.86 JDIMM1.147 ; JDIMM2.118 v1(149.52,3.54) ; JDIMM2.112 v1(148.03,3.42) ; JDIMM2.160 162.03,3.95 161.57,3.49 v1(160.53,3.49) JDIMM2.154 ; JDIMM2.129 152.28,13.97 v1(152.47,14.17) 153.54,14.17 153.78,13.93 JDIMM2.135 ; JDIMM1.220 v1(96.03,6.08) ; v1(152.53,3.48) JDIMM2.130 ; JDIMM2.124 v1(151.03,3.5) ; JDIMM2.142 v1(155.53,3.52)
  BOTTOM w0.381: JDIMM1.142 v1(74.53,3.29) ; JDIMM1.118 v1(68.52,3.13)
  vias: v3(72.14,18.05)
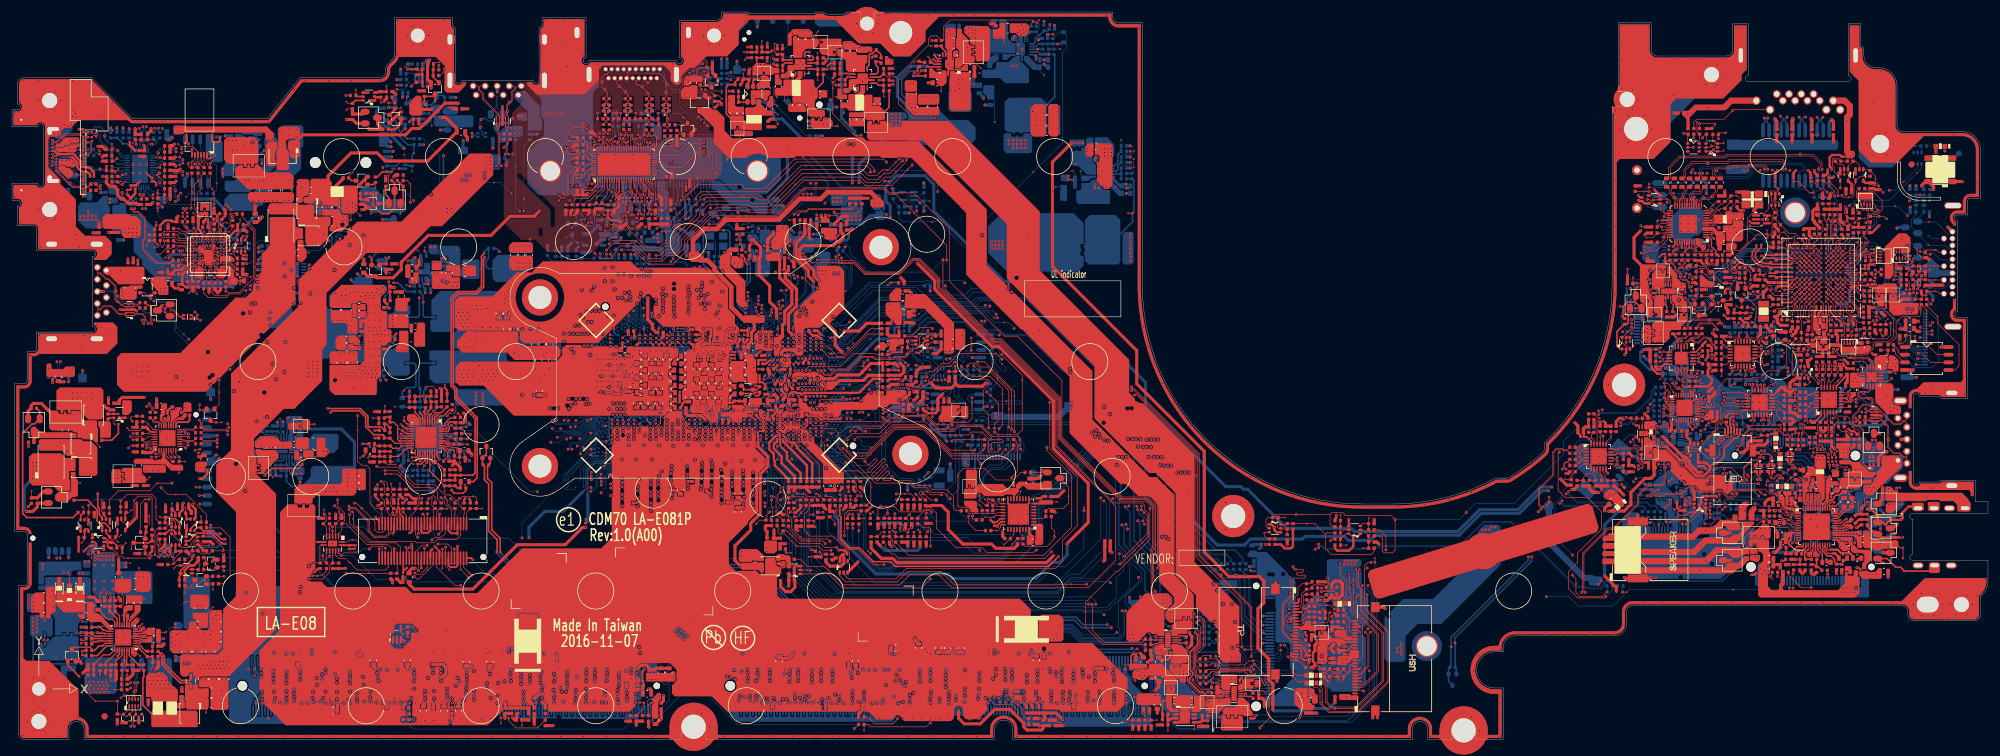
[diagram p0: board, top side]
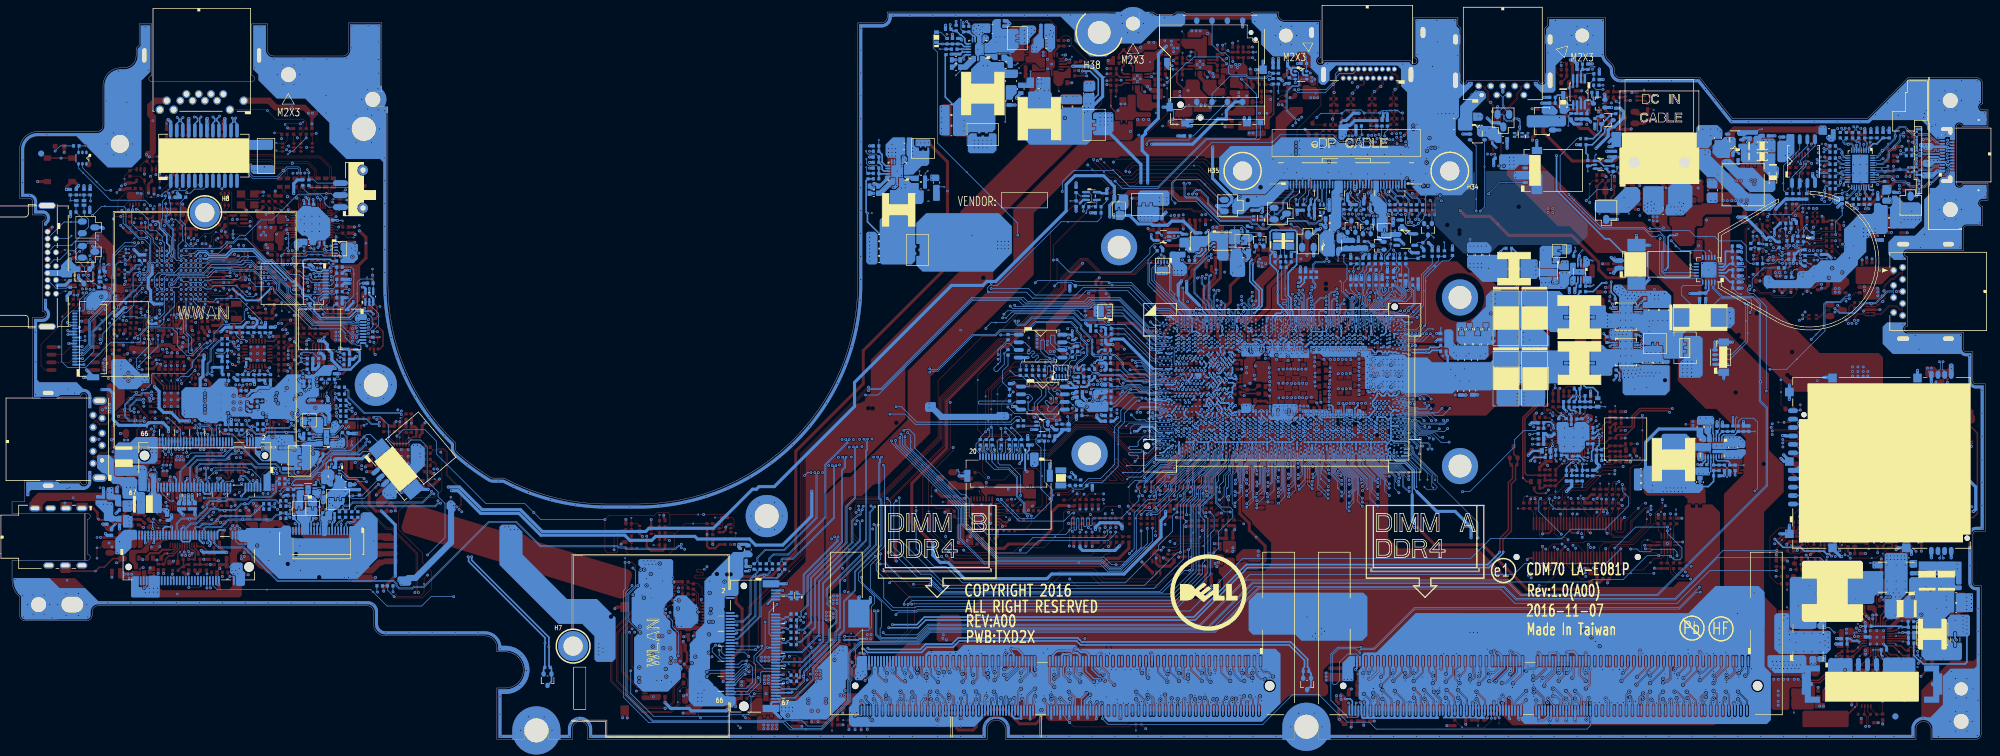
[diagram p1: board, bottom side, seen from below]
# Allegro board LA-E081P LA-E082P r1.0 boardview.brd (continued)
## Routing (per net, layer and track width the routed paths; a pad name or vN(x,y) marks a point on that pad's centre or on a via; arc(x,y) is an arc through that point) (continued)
+1.2V_MEM_CPUCLK: length 4.6
  TOP w0.508: CC297.1 111.89,55.07 RC231.1 112.21,53.8 v2(113.68,53.8) 114.41,53.8 v1(115.14,53.06)
+1.8V_3.3V_ALW_VTR3: length 6.4
  TOP w0.254: 309.74,75.03 309.7,75.07 308.53,75.07 308.15,75.46 CE21.1 307.96,75.39 305.76,75.39 305.49,75.13 UE1.N5
  BOTTOM w0.102: v2(270.32,75.67) 270.22,75.77 v1(269.77,75.77)
  BOTTOM w0.508: RE340.2 v1(269.77,75.77)
  vias: v1(311.86,74.88)
+1.8V_PGPPF: length 17.7
  TOP w0.381: RC304.2 144.2,59.89 142.93,59.89 140.6,57.56 131.48,57.56 v2(131.22,57.3) 131.07,57.3 130.84,57.52 130.21,57.52 130.06,57.67 129.41,57.67 129.03,57.29 v1(129.03,57.15)
  BOTTOM w0.254: v1(129.03,57.15) UC1.AF16
+1.8V_PRIM: length 34
  TOP w0.127: v1(255.19,39.35) v3(255.19,40.25)
  TOP w0.381: v1(147.84,59.55) 148.29,60 148.29,60.17 CC212.1 ; RC304.1 145.67,59.84 v1(147.28,59.84)
  TOP w0.508: v1(146.06,69.36) 145.8,69.11 RC313.1 ; RC212.1 v1(155.58,56.66)
  BOTTOM w0.203: v1(139.08,58.91) UC1.AA1
  BOTTOM w0.508: RC234.1 151.72,56.85 v1(151.97,56.6)
  BOTTOM w1.016: 164.28,53.56 173.74,53.56 174.89,54.71 ; 255.17,38.07 255.17,32.73 261.08,26.82 262.26,26.82
  vias: v1(122.01,100.71) v1(122.64,100.7) v1(163.34,54.07) v1(163.34,53.47) v1(175.76,55.08) v1(175.81,55.75) v1(254.78,38.87) v1(263.35,25.75) v1(263.82,26.32) v1(272.16,51.93) v1(272.69,51.66) v1(310.8,73.09) v1(310.82,73.68)
+1.8V_RUN: length 27.6
  TOP w0.508: CA66.1 272.62,43.91 272.06,43.35 271.1,43.35 268.77,41.02 268.77,39.04 267.67,37.94 v1(266.73,37.94) ; v1(264.42,27.15) 266.35,25.21 v1(266.35,24.63) ; RC362.2 RC363.2 149.23,55.64 v1(149.61,55.26)
  BOTTOM w0.508: v1(264.42,27.15) 264.42,35.63 v1(266.73,37.94)
  vias: v1(284.71,42.17) v1(284.74,41.56) v1(302.33,44.6) v1(302.96,44.6) v3(276.99,43.83)
+1.8V_RUN_AUDIO:
  vias: v1(301.8,43.59) v1(301.87,42.98) v1(302.26,38.01) v1(302.82,38.24) v2(301.45,42.66)
+1.8V_RUN_CARD:
  vias: v1(6.1,62.17) v1(6.1,61.59) v1(9.4,61.68) v1(10.04,61.68) v1(25.41,53.21) v3(9.72,61.04)
+1.8V_RUN_UZ8: length 0.7
  BOTTOM w0.127: v1(271.66,48.85) v2(271.66,49.51)
+1.8VALWP: length 8.6
  TOP w0.254: PC503.1 120.04,109.18 PR501.1 120.02,108.75 v3(118.98,108.75) 118.58,108.36 118.58,103.88 119.22,103.25 119.69,103.25
+1VALWP: length 12.7
  TOP w0.102: v1(186.03,87.39) v2(185.3,87.39)
  BOTTOM w0.254: PC310.1 186.03,85.97 v1(186.03,87.39) 186.25,87.61 186.25,92.78 PC307.1 185.07,93.1 PR306.1
+1VALWP_B+:
  vias: v1(178.52,98.19) v1(178.52,97.6) v1(178.52,97.02) v2(176.61,95.6)
+1VS_VCCIOP: length 4.8
  TOP w0.254: 144.82,104.19 145.62,104.99 v2(145.62,105.25) PR421.1 ; PU401.1 140.48,107.87 140.16,107.55 v1(139.98,107.55)
  vias: v1(144.45,104.46)
+2.5V_MEM:
  vias: v1(105.72,9.97) v1(106.3,9.97) v1(106.89,9.97) v1(109.89,11.02) v1(109.89,10.43) v1(109.89,9.85) v1(186.41,10.73) v1(186.77,11.27) v1(187.21,10.57) v1(187.61,11.06) v1(187.67,10.12) v3(187.97,10.59)
+2.5V_VIN: length 1.3
  TOP w0.102: v2(196.02,7.9) 196.55,7.37 196.55,6.84
+3.3V_1.8V_ESPI: length 44.4
  TOP w0.254: v1(173.72,30.37) v2(172.85,29.51) 172.09,28.75 146.61,28.75 145.83,29.53 142.93,29.53 140.64,31.82 139.04,31.82 137.63,33.23 137.63,36.94 137.42,37.14 137.42,38.73 RC21.2
  vias: v1(158.27,53.49)
+3.3V_1.8V_PGPPA: length 0.7
  BOTTOM w0.254: UC1.AK15 129.41,54.21 v1(129.82,53.71)
  vias: v1(154.08,53.08) v1(154.69,52.98) v2(154.98,53.68)
+3.3V_1.8V_PGPPG: length 3.9
  TOP w0.508: v1(149.66,56.33) 149.78,56.33 RC235.2
  BOTTOM w0.127: v1(149.66,56.33) 149.6,56.33 149.3,56.63 v2(149.06,56.63)
  BOTTOM w0.254: v1(129.67,57.15) 129.67,57.24 UC1.AD15
  BOTTOM w0.508: v1(149.66,56.33) 149.78,56.33 RC235.2 150.36,56.91 CC326.1
+3.3V_ALW: length 163.9
  TOP w0.254: v1(291.45,86.32) 291.35,86.42 UE4.5 ; v1(41.98,43.9) 43.1,45.02 47.54,45.02 v1(48.2,45.68) ; v1(136.77,108.68) 136.77,108.68 PR404.1 ; v1(218.57,9.55) 217.86,10.25 RZ8.1 ; JKBTP1.15 213.82,15.65 214.76,14.71 214.76,14.42 215.19,13.99 ; JLED1.6 286.9,50.64 286.34,50.08 286.01,50.08 284.26,48.33 284.26,46.98 283.04,45.76 282.42,45.76 281.91,45.25 ; PR107.1 v1(152.66,116.08) ; 123.63,111.99 PR417.1 PR418.1 ; RZ9.1 v1(217.05,11.7)
  TOP w0.305: RE69.1 284.41,74.62 284.64,74.85 v1(285.15,74.85)
  TOP w0.381: CE53.1 307.73,92.42 UE3.5 ; v1(138.1,30.14) 138.05,30.18 CZ82.1 137.89,30.75 137.5,30.36 137.5,29.68 UZ6.5 ; v1(267.75,63.92) 267.98,64.15 267.98,64.85 ; PR1235.2 25.41,32.29 PR1230.2 25.25,32.16 24.63,31.54 v1(24.63,31.36) ; v1(301.45,94.62) 301.45,94.07 301.07,93.69 RE84.2 ; RE38.2 RE35.2 ; RE35.2 306.6,85.04 RE25.1 ; RE35.2 v1(306.58,85.77) ; CE52.1 305.39,92.22 UE5.5 ; CZ91.1 214.87,13.99 v1(214.63,13.75) ; v1(304.03,83.19) 304.03,83.6 RE79.1 ; v1(274.12,48.63) 274.66,48.63 276.9,46.39 277.51,46.39 277.91,45.99 277.91,45.53 279.63,43.81 280.92,43.81 281.91,44.8 281.91,45.27 281.21,45.97 CZ93.1 279.93,45.98 UZ10.5
  TOP w0.457: RT68.2 38.44,79.77 v1(38.93,79.77) ; v1(137.42,41.29) 137.8,41.67 RC214.1
  TOP w0.508: CE53.1 309,92.42 v1(309.27,92.16) ; v1(295.49,67.05) 295.53,67.05 296.06,67.57 RE362.2 296.14,67.89 296.49,68.24 RE11.2 ; v1(25.48,38.96) PR1234.2 ; RE92.2 290.28,67.28 v1(289.82,66.82) ; v1(309.55,65.47) 309.66,65.58 RE376.2 ; v1(29.49,30.72) 29.21,31 28.94,31.26 PR1233.2 ; v1(298.76,83.3) 298.38,83.69 298.38,84.84 ; v1(63.4,93.46) 63.68,93.74 PR4.2 ; RC68.2 135.13,29.44 135.79,28.79 137.63,28.79 138.1,29.26 v1(138.1,30.14) ; RE98.2 v1(313.42,66.41) ; v1(29.34,39.13) 29.34,38.37 29.75,37.96 PR1232.2 ; v1(292.65,84.3) 292.65,83.86 292.33,83.55 RE301.2 ; 298.38,84.84 297.6,84.84 RE365.2 ; 298.38,84.84 RE5.2 ; PR933.1 v1(15.54,10.77) ; PR1231.2 32.96,32.85 v1(33.41,32.4) ; RE10.2 308.32,70.97 RE43.2 308.28,71.01 RE37.2 308.4,71.72 v1(309.17,71.72) ; PR1.1 v1(17.48,2.56) ; PR1224.2 v1(22.23,39.13) ; UE9.8 v1(320.25,65.17) ; RE68.2 v1(295.92,58.95) ; RE303.2 RE302.2 290.91,74.36 v1(291.37,74.82) ; RE63.2 RE91.2 RE83.2 303.51,88.05 CE61.1 303.54,88.78 v1(303.54,88.79) ; v1(305.39,90.75) CE52.1 ; RE300.1 v1(300.61,90.74) ; RE8.2 304.81,85.22 v1(305.04,85.45) ; v1(181.22,29.62) 181.41,29.81 CZ57.1 CZ58.1 ; RE512.2 v1(310.95,70.35) ; v1(128.96,25.48) CZ104.1 128.98,26.38 UZ34.5 ; PR1225.2 v1(20.33,30.88) ; RE505.2 v1(270.41,91.93) ; PR1259.2 v1(27.46,39.16)
  BOTTOM w0.254: UE2.18 46.36,74.64 CE2.1 ; v1(48.2,45.68) 48.15,45.63 PC206.1 46.91,46.28 PU200.13 ; PR205.2 v1(41.98,43.9) ; v1(170.13,119.04) 170.13,118.48 PR113.1 ; JAPS1.3 v1(316.35,63.25) ; JAPS1.7 v1(316.41,65.25)
  BOTTOM w0.305: v1(285.15,74.85) 287.06,72.93 289.23,72.93 290.21,73.91 290.45,73.91 v1(291.37,74.82)
  BOTTOM w0.381: UZ35.5 138.55,82.87 138.92,83.24 v1(138.92,83.86) ; v1(272.01,77.88) 272.76,77.88 273.22,77.42 RE72.1 ; v1(269.93,75.13) 269.65,75.13 269.39,74.86 UE6.5
  BOTTOM w0.457: PR307.1 v1(185.68,96.73)
  BOTTOM w0.508: RE17.1 v1(40.77,79.01) ; RE532.2 300.13,90.05 RE526.2 300.12,90.25 v1(300.61,90.74) ; v1(271.94,75.77) 272.85,75.77 RE75.1 ; CE2.1 CE1.1 47.96,74.06 v1(49.5,74.06) ; v1(40.9,80.93) 41.01,81.04 RE6.1 ; v1(97.68,84.65) 97.68,84.96 CV17.1 95.9,83.96 UV24.5 ; PR28.2 61.08,104.83 60.53,104.29 60.53,103.24 62.04,101.73 62.55,101.73 63.06,101.22 63.06,100.16 v1(65.07,98.15) ; RE15.1 v1(40.77,78) ; 146,100.88 140.63,95.51 v1(140.63,92.44) ; 182.96,92.91 183.96,91.9 PC312.1 184.6,92.22 v1(184.98,92.22) ; PR29.1 v1(65.26,101.39) ; v1(310.95,70.35) 310.75,70.35 309.38,71.72 v1(309.17,71.72) ; RE74.1 RE73.1 v1(272.42,73.36) ; RE13.1 v1(40.8,74.95)
  vias: v1(124.27,112.1) v1(124.62,111.59) v1(124.91,112.1) v1(125.61,111.78) v1(145.5,103.27) v1(145.47,102.69) v1(145.53,103.89) v1(146.06,112.76) v1(146.13,103.88) v1(146.12,103.28) v1(146.12,102.69) v1(146.11,102.08) v1(146.72,103.93) v1(146.71,103.3) v1(146.71,102.69) v1(146.72,102.07) v1(147.4,103.28) v1(147.4,102.67) v1(147.4,103.93) v1(147.4,102.05) v1(170.95,32.72) v1(190.1,15.36) v1(190.1,14.78) v1(190.69,14.82) v1(190.95,14.29) v1(191.5,14.51) v1(191.43,13.93) v1(198.47,5.3) v1(198.47,4.71) v1(199.06,5.31) v1(199.08,4.72) v1(199.66,5.29) v1(199.66,4.7) v1(200.28,5.33) v1(200.26,4.74) v1(202.44,10.53) v1(202.48,9.92) v1(202.48,9.34) v1(203.12,10.51) v1(203.15,9.9) v1(203.13,9.3) v1(220.22,9.8) v1(220.88,12.69) v1(220.96,13.33) v1(220.99,9.8) v1(221.15,29.09) v1(221.35,29.65) v1(221.47,12.67) v1(221.55,13.29) v1(221.75,29.09) v1(221.95,29.65) v1(222.33,29.07) v1(222.53,29.66) v1(222.97,29.07) v1(223.17,29.66) v1(271.07,81.81) v1(271.07,81.21) v1(273.31,49.78) v1(273.31,49.19) v1(273.54,48.63) v1(273.75,51.85) v1(273.96,49.22) v1(274.21,52.71) v1(274.29,52.12) v1(274.78,52.46) v1(274.85,51.87) v1(281.28,75.32) v1(299.66,65.9) v1(299.81,65.18) v1(307.79,64.29) v1(313.8,83.61) v1(313.8,83.03) v1(314.74,70.92) v1(315.33,70.92) v3(200.55,6.47) v3(312.6,71.34)
+3.3V_ALW2: length 3.2
  TOP w0.127: v1(150.95,111.09) 150.95,110.96 150.5,110.51 150.12,110.51 149.87,110.76 v3(149.74,110.76)
  TOP w0.254: PR104.2 v1(150.95,111.09)
  TOP w0.508: v1(295.28,67.71) 295.28,67.94 295.58,68.24 RE57.2
+3.3V_ALW_DSW: length 14.4
  TOP w0.127: RC243.2 v2(132.31,30.35)
  TOP w0.254: RC241.2 v1(65.53,39.9)
  TOP w0.508: RC323.2 143.64,32.68 v1(144.17,32.15) ; v1(133.17,35.34) 133.08,35.43 RC67.2 ; RC243.2 134.29,30.35 v1(134.36,30.28) ; RC72.2 v1(150.75,32.13)
  BOTTOM w0.254: v1(127.71,54.64) UC1.AJ17 ; UC1.AD17 v1(127.73,57.15) 127.66,57.23 UC1.AD18
  BOTTOM w0.508: v1(144.17,32.15) 144.93,31.39 150.32,31.39 150.75,31.82 v1(150.75,32.13)
  vias: v1(136.02,43.58)
+3.3V_ALW_PCH: length 75.5
  TOP w0.254: RC12.2 147.76,64.34 v1(147.73,64.32) 146.09,64.32 145.74,63.96 RC23.2
  TOP w0.305: RC133.2 60.33,40.28 v1(60.81,39.79)
  TOP w0.381: v1(129.82,37.66) 130.1,37.66 130.94,38.5 RC187.2
  TOP w0.457: RI55.2 306.66,48.9 306.66,48.31 v1(306.67,48.29)
  TOP w0.508: v1(147.55,76.68) 148.11,76.12 RC288.2 ; 151.25,56.88 151.25,56.52 v1(150.55,55.82) ; 151.25,56.88 RC306.1 ; 151.25,56.88 RC235.1 ; v1(149.79,32.09) 149.74,32.09 RC387.2 ; RI57.2 301.12,51.43 300.8,51.11 v1(300.64,51.11) 300.23,51.52 RI44.2 ; RC344.2 136.35,29.85 136.66,30.15 v1(136.93,30.15) ; RI38.2 RI53.2 301.63,64.1 v1(301.51,64.22) ; RC184.2 v1(149.74,38.25) ; RI80.1 v1(316.51,69.46) ; RI42.2 v1(302.07,51.11) ; v1(300.61,64.23) RI40.2 RI51.2 ; v1(147.45,62.5) 148.03,61.92 148.03,60.98 147.53,60.47 RC308.1 ; RC183.2 148.34,35.03 v1(148.16,34.85) ; RC14.2 v1(154.26,67.91) ; RI34.1 303.66,61.8 303.37,62.09 v1(303.37,62.31) ; v1(126.5,34.79) LC1.1 127.5,33.4 CC215.1 ; RC74.2 v1(143.77,34.98) ; RC73.2 v1(151.77,32.06) ; RC211.1 v1(154.69,56.66)
  BOTTOM w0.254: RC347.2 151.16,60.09 151.77,60.09 v1(151.9,60.22) ; RC348.2 150.37,62.15 v1(150.07,62.15) ; UC1.AJ21 125.14,55.35 125.04,55.35 v1(124.92,55.47) ; UC1.V19 126.41,59.76 v1(126.41,59.61) ; v1(147.73,64.32) 147.29,64.76 146.69,64.76 RC17.2 ; RC41.1 159.19,48.66 159.19,48.05 159.85,47.38 JSPI1.5 ; UC1.AK17 128.04,53.79 v1(127.96,53.71) ; JAPS1.1 v1(316.11,62.25)
  BOTTOM w0.305: v1(159.54,44.47) 159.85,44.78 JSPI1.5
  BOTTOM w0.381: RC371.2 RC400.2 146.74,68.47 v1(147.25,68.47)
  BOTTOM w0.508: v1(147.45,62.5) RC15.2 146.41,62.32 146.41,61.54 RC25.2 ; v1(313.14,58.1) 311.92,58.1 311.23,57.41 311.23,53.08 310.32,52.16 305.77,52.16 305.33,52.61 302.99,52.61 302.07,51.69 v1(302.07,51.11) ; v1(281.29,90.64) 281.29,92.3 280.66,92.93 RC222.2 ; RC346.2 v1(152.43,74.47) ; UC7.5 v1(156.08,52.19) ; v1(143.77,34.98) 143.77,35.42 144.34,35.99 147.42,35.99 148.16,35.25 v1(148.16,34.85) ; v1(158.6,48.9) RC41.1
  vias: v1(136.5,77.41) v1(137.22,77.39) v1(147.12,57.78) v1(147.17,55.72) v1(151.34,55.66) v1(206.9,9.58) v1(206.94,8.99)
+3.3V_ALW_PCH_UZ3: length 2.5
  TOP w0.127: v2(207.95,9.09) 207.6,9.44 207.6,9.84 207.36,10.08 206.09,10.08
+3.3V_ALW_UE1: length 22
  TOP w0.203: 294.85,76.04 295.13,76.33 295.96,76.33 UE1.B7 ; v1(303.16,72.33) UE1.K2
  TOP w0.254: UE1.H1 v1(301.16,70.51) 301.16,70.34 301.35,70.15 301.35,69.53 CE15.1 301.31,69.44 301.31,68.03 RE314.2 ; v1(306.96,78.15) CE20.1 307.65,78.74 CE19.1 ; v1(299.98,77.9) UE1.G8 ; UE1.M9 v1(304.8,78.76)
  TOP w0.381: v1(292.92,75.88) CE13.1 294.68,75.88 294.85,76.04
  TOP w0.508: v1(292.92,75.88) v2(292.04,75.88) 291.52,75.88 CE14.1
  BOTTOM w0.508: v1(303.16,72.33) 304.54,72.33 305.05,72.83 305.05,74.57 305.44,74.96 305.44,76.65 304.8,77.3 v1(304.8,78.76)
+3.3V_ALWP: length 20.6
  TOP w0.254: PU100.14 152.04,111.71 v1(151.95,111.8) ; v1(150.35,110.99) 150.35,111.46 PR108.2
  BOTTOM w0.254: v1(150.35,110.99) 149.08,110.99 147.71,109.62 147.71,107.08 148.47,106.32
  BOTTOM w0.508: v1(151.95,111.8) 148.87,111.8 146.99,109.92 146.99,106.78 148.47,105.3
  vias: v1(148.98,105.56) v1(149.36,104.92) v1(149.74,105.56) v1(149.99,104.92) v1(149.99,104.16) v3(149.46,104.36)
+3.3V_CAM: length 9.1
  TOP w0.127: v1(111.82,86.43) 112.2,86.43 v3(112.4,86.63)
  BOTTOM w0.254: CZ1.1 111.76,88.94 111.76,89.51 111.3,89.97 JEDP1.11
  BOTTOM w0.508: QZ1.1 112.31,83.8 111.44,84.67 111,84.67 v1(110.82,84.86) ; v1(111.82,86.43) CV23.1 CV22.1 111.85,88.13 CZ1.1
+3.3V_CPS: length 10.9
  TOP w0.127: v1(16.39,101.54) v2(16.78,101.15)
  TOP w0.254: v1(19.11,91.23) 19.5,91.23 CT120.1 ; v1(23.93,92.05) 23.93,92.41 23.65,92.69 CT121.1
  TOP w0.381: CT119.1 21.93,97.81 CT117.1 21.98,98.57 v1(21.85,98.7) ; v1(19.1,90.6) 19.1,90.49 LT11.2 20.45,90.66 CT118.1
  BOTTOM w0.203: UT9.20 23.67,92.56 23.93,92.3 v1(23.93,92.05) ; v1(19.11,91.23) 19.61,91.23 19.81,91.43 UT9.28
  BOTTOM w0.254: v1(21.85,98.7) 21.81,98.66 UT9.6
  BOTTOM w0.508: RT246.1 v1(16.39,101.54)
+3.3V_CPS_R1: length 4.5
  BOTTOM w0.203: 19.58,98.42 19.81,98.19 UT9.1
  BOTTOM w0.254: RT246.2 CT122.1 17.47,99.89 v2(18.42,98.94) 19.07,98.94 19.58,98.42
+3.3V_EC_PLL: length 0.6
  BOTTOM w0.102: v2(300.61,68.22) v1(300.03,68.22)
+3.3V_HDD: length 32.9
  TOP w0.127: v3(270.66,64.39) 270.64,64.39 270.64,64.41 271.02,64.79 v1(271.16,64.79) ; v3(273.99,60.27) 274.2,60.47 274.2,60.98 273.75,61.43 v1(273.61,61.43)
  TOP w0.254: UN7.20 279.55,64.32 CN16.1 ; RN12.1 RN20.1 281.56,63.4 v1(281.19,63.03) ; UN7.10 274.36,62.32 273.97,61.93 CN17.1
  TOP w0.381: CN17.1 272.84,61.81 273.22,61.43 v1(273.61,61.43) ; CN16.1 280.66,65.54 v1(281.18,66.06) ; RN18.1 281.58,58.62 282.15,59.19 v3(282.15,59.68) 282.15,59.89 281.56,60.47 RN16.1 281.56,61.37 v1(281.9,61.71) 281.59,62.02 RN10.2
  TOP w0.508: v1(271.16,64.79) RN14.1 RN8.2 RN6.1
  BOTTOM w0.381: 273.58,61.43 271.87,61.43 270.34,62.96 270.34,64.38 270.74,64.79 v1(271.16,64.79)
  BOTTOM w0.508: 273.58,61.43 v1(273.61,61.43) 273.61,61.68 274.96,63.03 274.96,64.15 275.71,64.9 275.71,65.59 276.31,66.19 v1(277.17,66.19)
  vias: v1(274.4,38.45) v1(274.83,38.85) v1(275.34,39.82) v1(275.32,39.19)
+3.3V_HDD_M2:
  vias: v1(290.33,28.4) v1(290.66,27.51) v1(290.9,28.05) v1(291.28,27.51) v1(291.54,28.04) v1(291.75,28.64) v1(303.92,25.1) v1(303.92,24.47) v1(304.55,25.1) v1(304.55,24.47) v1(305.25,25.1) v1(305.25,24.47) v3(293.76,25.67) v3(300.61,24.15) v3(305.95,24.4)
+3.3V_LAN: length 59.5
  TOP w0.381: RL4.2 279.4,79.57 RL5.2 280.4,79.34 v1(280.8,78.94) ; UL2.5 271,89.03 CL15.1 270.17,89.39 v1(270.01,89.55)
  TOP w0.457: RL29.1 282.19,101.44 v1(282.32,101.57)
  TOP w0.508: v1(282.93,78.81) 283.09,78.97 RL6.2 ; RL2.2 v1(271.15,82.57) ; RL30.1 v1(278.26,102.25) ; v1(271.1,83.83) 271.36,84.09 RL1.2 ; RL70.2 142.63,31.75 144.3,30.08 146.2,30.08 146.92,29.36 v3(150.93,29.36) 171.73,29.36 v1(172.93,30.55)
  TOP w1.016: JLOM1.12 304.25,106.08 305.11,105.22 305.11,103.76 304.68,103.33 v3(304.68,102.76) 304.68,97.79 ; JLOM1.9 285.39,106.08 284.42,105.11
  BOTTOM w0.254: RC19.2 151.26,59.56 v1(151.69,59.56) ; v1(148.77,62.17) 148.32,61.72 RC20.2
  vias: v1(278.19,104) v1(278.86,104.01) v1(279.81,52.38) v1(280.02,52.94) v1(285.63,81.62) v1(285.89,82.16) v1(305.26,96.75) v1(305.72,97.14) v3(281.61,104.95)
+3.3V_LAN_OUT: length 6.4
  TOP w0.203: UL1.19 v1(278.06,89.68) ; UL1.15 v1(279.66,89.55) ; v1(274.01,86.19) 274.04,86.22 UL1.29
  BOTTOM w0.127: v1(274.01,86.19) v2(273.27,86.19)
  BOTTOM w0.254: v1(279.66,89.55) 279.53,89.42 CL7.1 ; v1(278.06,89.68) 278.01,89.63 CL30.1
  BOTTOM w0.381: v1(274.01,86.19) 274.07,86.25 CL29.1
  vias: v1(282.44,84.61) v1(284.14,83.92)
+3.3V_LAN_UZ2:
  vias: v2(276.71,53.33)
+3.3V_M_TPM: length 2.5
  TOP w0.254: UZ12.22 164.06,36.67 163.45,36.06 CZ53.1
  TOP w0.381: v1(162.44,36.5) 162.87,36.06 CZ53.1
  vias: v1(162.64,41.55) v2(161.17,41.55)
+3.3V_MMI_AUX: length 2.4
  TOP w0.127: RR19.2 v2(27.74,44.25)
  TOP w0.203: 25.15,46.58 25.19,46.61 ; UR1.27 25.19,47.44
  TOP w0.508: 25.19,47.44 25.19,46.61
+3.3V_MMI_IN: length 1.2
  TOP w0.127: v2(22.84,43.55) 22.37,43.08 CR25.1
  vias: v1(20.61,43.92) v1(21.33,43.91) v1(27.34,54.86) v1(27.92,54.86)
+3.3V_PDA_VOUT: length 4.4
  TOP w0.076: 30.53,84.41 31.39,83.55 31.39,82.79 UT5.H2
  TOP w0.102: 30.53,84.41 30.5,84.43 v2(30.5,84.51) 30.5,84.61 v1(30.18,84.93)
  BOTTOM w0.102: v1(30.18,84.93) 29.45,84.21 CT83.1
+3.3V_PGPPB: length 2.5
  TOP w0.508: v1(129.03,55.48) 129.03,55.85 128.97,55.91 CC265.1 129.87,56.44 RC305.2
  BOTTOM w0.254: v1(129.03,55.48) 129.28,55.82 UC1.AG15
+3.3V_PGPPC: length 3.6
  TOP w0.127: v2(151.4,58.68) 151.19,58.68 150.33,57.82 RC306.2
  TOP w0.508: RC306.2 v1(149.67,57.73) ; v1(128.4,58.82) 128.4,58.32 CC207.1
  BOTTOM w0.254: UC1.Y16 128.66,59.24 128.39,58.88 v1(128.4,58.82)
+3.3V_PGPPD: length 2.2
  TOP w0.508: RC307.2 143.9,57.55 v1(143.64,57.8)
  BOTTOM w0.127: v2(144.11,57.3) 143.64,57.76 v1(143.64,57.8)
  BOTTOM w0.254: v1(129.71,58.89) 129.71,58.9 129.36,59.25 UC1.Y15
+3.3V_PGPPE: length 10.7
  TOP w0.381: v1(128.4,60.47) 128.29,60.37 128.29,59.49 127.78,58.98 CC208.1
  TOP w0.508: RC308.2 142.16,60.47 141.31,59.61 137.35,59.61 136.87,59.13
  BOTTOM w0.254: UC1.T16 128.45,60.61 128.45,60.52 128.42,60.48 v1(128.4,60.47)
  vias: v1(134.42,59.17) v2(136.13,59.11)
+3.3V_RTC_LDO: length 26.1
  TOP w0.127: v3(59.4,80.17) 59.7,79.86 v1(59.7,79.7)
  TOP w0.254: PR105.2 v1(149.62,110.2) ; PD3.3 v1(59.7,79.7)
  BOTTOM w0.254: v1(59.7,79.7) 59.7,79.97 62.87,83.14 63.57,83.14 71.63,91.2 v1(71.63,96.96)
+3.3V_RUN: length 185.1
  TOP w0.203: UV7.34 106.48,98.07 107.02,98.61 107.02,99.92 v1(107.22,100.12) ; UV7.10 100.81,92.03 100.78,92.01 100.78,90.95 100.42,90.59 100.42,89.98 CV85.1 ; CV81.1 96.32,91.2 97.21,92.09 UV7.1
  TOP w0.254: v1(264.93,44.24) 264.65,44.51 UN4.12 ; v1(93.14,97.74) 93.24,97.84 93.81,97.84 RV71.2 ; UN4.24 262.15,49.58 261.49,50.25 CN20.1 ; v1(98.91,87.2) 98.94,87.23 RV89.2 ; v1(92.72,99.87) 92.86,100.01 93.8,100.01 RV72.2 ; v1(93.22,95.79) 93.82,95.79 RV70.2 ; v1(150.12,64.23) 150.63,64.23 151.26,64.86 151.26,65.83 151.67,66.25 QC2.2 ; QC2.5 v1(149.34,66.25) ; UN5.12 292.48,57.21 293.04,57.78 ; CZ67.1 221.24,16.15 JUSH1.19 ; v1(279.03,51.45) 279.03,51.53 278.29,52.27 UV6.14 ; UN5.24 287.31,54.71 v1(287.23,54.63) ; v1(278.69,57.96) UV6.26
  TOP w0.305: v1(65.82,16.96) 65.66,17.11 RD19.2 ; v1(57,32.25) CC30.1 54.73,32.25 UC8.14
  TOP w0.381: v1(117.81,105.4) 117.81,105.61 117.43,105.99 RV19.2 ; v1(141.44,41.25) 141.44,41.32 RC414.2 ; RN171.1 v1(212.67,34.05) 212.67,32.09 212.32,31.74 211.31,31.74 210.66,32.39 RN65.1 ; v1(146,32.04) 145.67,32.37 RC51.2 ; CN21.1 260.96,50.92 CN20.1 ; v1(142.75,38.75) 141.98,37.98 RC190.2 ; v1(98.91,87.2) 98.91,86.74 99.43,86.22 100.74,86.22 CV82.1 ; RN2.1 276.84,38.04 276.44,38.44 v1(276.44,39.49) ; RC282.2 153.7,54.56 153.32,54.18 152.08,54.18 151.76,54.5 151.52,54.5 151.26,54.76 RC237.2 ; CV85.1 100.84,89.81 100.84,90.21 v1(101.14,90.51) ; CA7.1 v1(111.89,91.13) ; RN64.1 219.64,31.71 220,31.35 221.97,31.35 222.68,32.06 v1(222.68,33.77)
  TOP w0.457: RN42.1 v1(261.75,52.53) RN43.1 ; v1(264.29,52.79) 264.55,52.53 RN50.1
  TOP w0.508: RC178.2 RC175.2 RC413.2 v1(142.12,89.88) ; RC189.2 RC186.2 148.72,32.05 v1(148.71,32.05) ; CV81.1 CV83.1 95.34,90.44 v1(95.58,90.69) ; RN25.1 258.12,42.23 v1(257.1,43.25) ; v1(134.75,36.91) 134.66,36.82 RC13.2 ; RV124.1 275.5,51.56 275.5,52.74 v1(275.45,52.79) ; RV18.1 110.37,98.69 v1(110.64,98.42) ; v1(152.87,64.05) 153.53,64.05 154.26,64.79 RC319.2 ; RC345.2 RC404.2 145.64,67.01 RC318.2 v1(147.25,67.89) ; v1(147.2,58.97) 147.2,58.97 147.2,58.97 146.07,58.97 145.66,58.57 RC279.2 ; RN27.1 v1(269.19,44.47) ; RD20.1 v1(186.06,1.66) ; v1(103.64,2.35) RD4.1 RD6.1 ; RC50.2 v1(144.79,35.2) ; RV93.2 RV91.2 95.89,87.48 v1(95.62,87.21) ; v1(174.68,41.35) 173.68,40.35 RZ89.1 ; LV30.1 CV100.1 282.14,56.91 282.67,57.44 282.67,57.73 v1(282.73,57.79) ; v1(92.77,87.08) 92.77,87.68 RV95.2 ; v1(187.27,14.33) 187.84,13.76 RD26.1 ; v1(138.05,38.25) 138.44,38.63 RC27.2 ; RC137.2 63.15,26.39 v1(63.15,26) ; RN51.1 268.51,47.52 v1(268.99,47.03) ; 266.88,41.29 v1(267.58,40.59) ; 266.88,41.29 RN49.1 ; 266.88,41.29 RE51.1 ; CN21.1 260.88,51.62 261.17,51.91 RN42.1 ; RD8.1 v1(89.84,2.29) ; v1(316.74,67.79) 316.25,67.79 RI79.1 ; v1(116.29,112.57) RV20.2 116.29,110.73 QV5.2 ; v1(263.43,41.01) 262.49,41.01 261.88,41.62 RN28.1 RN26.1 ; RC176.2 RC177.2 v1(120.34,85.57) ; RV81.2 RV83.2 RV85.2 RV87.2 v1(105.8,84.88) ; RN58.1 295.46,53.29 v1(295.98,52.78) 295.81,52.78 295.37,52.34 RN56.1 ; RC292.2 v1(133.61,84.78) ; RD22.1 v1(189.11,1.63) ; RE67.2 v1(296.17,63.85) ; RD10.1 106.13,8.2 105.96,8.37 v1(105.68,8.37) ; RC59.2 v1(149.36,35.2) ; RN63.1 v1(226.14,36.54) ; RC47.2 v1(146.56,35.2) ; 293.04,57.78 293.71,58.44 CN31.1 ; RC282.2 153.7,56.58 v1(154.53,57.41) ; RZ362.1 166.95,32.29 166.4,31.74 163.33,31.74 162.62,32.45 157.84,32.45 155.43,34.87 155.43,37.76 154.34,38.85 RC370.2 152.68,38.85 v1(152.58,38.76) 151.74,38.76 RC278.2 ; v1(170.55,3.56) 170.5,3.5 RD24.1 ; RN44.1 RN50.1 ; RC267.2 v1(147.71,38.25)
  BOTTOM w0.254: RV8.2 98.95,87.51 98.95,87.24 v1(98.91,87.2) ; v1(111.89,91.13) 111.82,91.2 111.82,91.25 111.8,91.27 JEDP1.10
  BOTTOM w0.305: QV3.5 113.58,110.32 113.77,110.51 113.77,111.22 114.1,111.55 115.42,111.55 115.7,111.27 115.7,110.69 115.33,110.32 QV3.2
  BOTTOM w0.381: UC12.5 147.4,90.9 147.21,90.71 RC291.2
  BOTTOM w0.508: RV79.2 105.14,102.79 105.92,102 106.56,102 ; RC287.2 147.1,58.88 147.2,58.97 147.2,58.97 v1(147.2,58.97) ; v1(111.97,80.31) 111.94,80.33 QZ1.3 ; RC403.2 146.73,56.85 v1(147.24,56.34) ; 115.7,111.27 116.29,111.85 v1(116.29,112.57) ; RC225.2 v1(151.39,92.44) ; 273.87,46.63 269.93,46.63 269.52,47.03 v1(268.99,47.03) ; RC272.2 137.01,81.53 v1(137.29,81.81) ; PR612.1 75.75,52.57 v1(76.03,52.29) ; v1(296.17,63.85) 296.17,63.14 296.36,62.95 296.36,60.33 296.82,59.87 296.82,58.11 296.83,58.1 ; RN55.1 292.61,52.76 293.19,53.33 293.19,53.74 ; RC291.2 146.31,91.33 v1(146.13,91.51) ; v1(147.22,53.93) 147.09,53.8 RC402.2
  vias: v1(16.24,89.77) v1(16.24,89.16) v1(16.79,43.93) v1(16.82,44.61) v1(16.81,43.31) v1(17.46,44.6) v1(17.46,43.97) v1(17.46,43.35) v1(106.66,100.42) v1(148.04,71.21) v1(148.04,70.6) v1(201.13,2.37) v1(201.12,1.79) v1(201.81,2.37) v1(201.81,1.79) v1(202.53,2.37) v1(202.55,1.79) v1(203.26,2.39) v1(203.25,1.8) v1(217.15,13) v1(217.89,13) v1(270.68,70.26) v1(270.73,69.66) v1(272.19,41.5) v1(272.6,77.26) v1(272.52,75.15) v1(272.75,41.19) v1(273.28,41.45) v1(274.52,61.68) v1(290.26,35.04) v1(290.67,35.48) v1(291.05,35.04) v1(291.43,35.49) v1(291.73,34.97) v1(295.99,58.08) v1(299.42,54.54) v1(299.46,53.93) v3(217.81,14.5)
+3.3V_RUN_AUDIO: length 16
  TOP w0.508: 294.68,40.74 294.68,39.13 v1(294.72,39.08) ; RA61.1 296.22,30.98 v1(296.64,31.4) ; v1(292.41,31.08) 292.77,31.08 293.58,31.9 RA59.1 293.62,32.75 LA12.2 ; v1(270.39,84.47) 269.29,83.38 v3(269.29,82.42) 269.29,79.95 270.52,78.73
  BOTTOM w0.508: v1(292.41,31.08) 296.32,31.08 v1(296.64,31.4)
+3.3V_RUN_AUDIO_DVDD:
  vias: v2(294.45,38.6)
+3.3V_RUN_AUDIO_IO:
  vias: v2(295.53,34.46)
+3.3V_RUN_AUDIO_UZ5:
  vias: v2(272.72,72.59)
+3.3V_RUN_CARD:
  vias: v1(26.02,53.56) v1(26.02,52.97) v1(30.64,45.12) v1(31.25,45.13) v3(30.94,44.62)
+3.3V_RUN_DIMM1: length 5.8
  TOP w0.305: CD27.1 104.82,9.55 CD28.1 v2(104.65,10.89) 104.65,11.28 v1(105,11.62)
  TOP w0.508: CD27.1 104.73,8.87 RD10.2
  BOTTOM w0.254: JDIMM1.255 104.78,11.84 v1(105,11.62)
+3.3V_RUN_DIMM2: length 2.3
  TOP w0.102: CD60.1 v2(184.74,12.36)
  BOTTOM w0.254: JDIMM2.255 v1(185.78,11.73)
+3.3V_RUN_UT9: length 13.8
  TOP w0.508: RT145.2 26.99,92.47 v1(27.24,92.72) ; v1(23.06,101.45) 23.06,101.06 RT135.2 ; RT143.2 v1(14.95,96.04) ; RT131.2 20.91,88.84 20.7,89.05 LT11.1 19.24,89.05 18.51,89.78 18.11,89.78 17.55,90.34 17.55,91.24 16.92,91.88 v1(16.27,91.88) 16.19,91.88 15.68,92.39 RT141.2 ; v1(27.11,96.73) 26.92,96.54 RT137.2 ; v1(27.19,95.23) 26.9,95.52 RT139.2
  BOTTOM w0.508: RT247.2 v1(18.42,101.57)
  vias: v1(26.08,99.62) v1(26.61,99.97) v2(25.49,99.66)
+3.3V_RUN_UZ3: length 1.1
  TOP w0.127: CZ115.1 206.57,4.08 v2(206.7,3.95)
+3.3V_SPI: length 21.6
  TOP w0.508: v1(161.74,59.26) 161.14,58.66 v2(158.26,58.66) 157.1,58.66 156.6,59.17 ; v1(152.6,59.29) 152.6,59.14 153.38,58.36 155.96,58.36 156.6,59 156.6,59.17 ; 156.6,59.17 RC31.2
  BOTTOM w0.254: JSPI1.6 160.35,46.35 160.69,46.02 160.69,45.89 v1(160.79,45.79) ; UC1.AJ16 128.69,54.95 v1(129,54.64)
  BOTTOM w0.305: UC5.8 152.31,67.23 CC9.1
  BOTTOM w0.381: UC6.8 153.07,58.38 151.32,58.38 CC10.1 151.6,58.57 152.29,59.25 152.56,59.25 v1(152.6,59.29) ; v1(152.04,67.9) 152.02,67.88 CC9.1
  BOTTOM w0.508: v1(161.74,59.26) 161.91,59.08 RC30.2 ; RC41.2 v1(159.43,50.49)
+3.3V_TBTA_FLASH: length 28.6
  TOP w0.203: UT5.G1 32.27,83.16 v1(32.27,83.69)
  TOP w0.254: v1(33.08,96.73) 32.82,96.47 32.52,96.47 32.37,96.62 JDB1.1
  TOP w0.381: RT378.2 35.39,86.94 RT379.2 ; RT66.2 24.59,85.37 25.41,86.19 v2(25.89,86.19) 26.42,86.19 26.61,86 RT95.2
  TOP w0.508: v1(41.53,86.76) 40.68,85.91 CT84.1 ; RT98.2 v1(32.71,74.25) ; v1(27.56,86.89) 27.36,86.68 RT95.2 ; RT378.2 35.39,87.88 v1(35.18,88.08)
  BOTTOM w0.381: RT106.2 32.45,83.51 v1(32.27,83.69) ; RT67.2 36.47,83.39 35.88,83.39 35.12,82.63 RT107.2
  BOTTOM w0.508: RT53.1 RT52.1 RT51.1 RT50.1 33.61,89.73 35.18,88.16 v1(35.18,88.08) ; RT76.2 26.61,80.54 v1(26.04,79.96) ; RT67.2 37.41,83.72 v1(37.41,83.9) 40.26,86.76 v1(41.53,86.76)
  vias: v1(33.08,97.31) v1(33.66,96.98)
+3.3V_TP: length 9.5
  TOP w0.254: RZ19.1 214.91,21.71 v1(214.38,21.71)
  TOP w0.508: RZ117.1 219.08,25.75 219.64,26.31 v3(220.05,26.31) 220.45,26.31 220.86,25.9 RZ21.1 RZ20.1 220.86,24 220.35,23.49 219.41,23.49 219.08,23.82 ; 219.08,23.82 219.08,23.79 218.37,23.08 v1(217.94,23.08) ; 219.08,23.82 RZ116.1
  vias: v1(216.94,18.76) v1(217.59,18.78)
+3.3V_USB_UI5: length 20
  TOP w0.254: CI38.1 300.38,53.84 UI5.1 ; UI5.13 302.88,58.72 304.07,59.91 304.07,60.04 CI37.1
  TOP w0.508: v1(313.43,68.18) 314.3,68.18 RI79.2 RI80.2 ; CI37.1 304.68,59.38 304.42,59.12 v1(304.42,58.59) ; CI38.1 298.79,52.67 v1(298.56,52.9)
  BOTTOM w0.508: v1(298.56,52.9) 300.23,52.9 301.63,54.3 302.89,54.3 303.64,55.05 v2(303.64,56.38) 303.64,57.81 v1(304.42,58.59)
+3.3V_VCCHDA: length 1.5
  TOP w0.381: v1(126.41,54.64) 126.36,54.69 CC313.1
  BOTTOM w0.254: UC1.AJ19 126.74,54.96 v1(126.41,54.64)
  vias: v1(125.36,31.82) v1(125.37,31.21) v2(126.32,31.35)
+3.3V_VDD_DCIN: length 8.1
  TOP w0.102: v1(73.07,104.89) v2(72.51,104.89)
  TOP w0.508: v1(73.07,104.89) 73.23,104.73 PC10.1 ; PR17.1 63.27,107.59 v1(63.71,107.14)
  BOTTOM w0.457: PR27.2 v1(68.33,98.76)
  BOTTOM w0.508: PU1.5 62.5,96.09 PC9.1 v1(63.02,96.75) ; PR1206.1 v1(63.89,109.59) ; PR1208.1 v1(65.67,112.18) ; v1(63.71,107.14) 63.6,107.03 PD1801.3
+3.3V_VDD_PIC: length 36.9
  TOP w0.254: QT1.5 38.04,83.27 v1(38.36,83.58) ; v1(38.93,80.41) 38.3,80.41 38.04,80.66 QT1.2 ; PR1214.1 v1(18.3,31.02)
  TOP w0.381: PU1200.5 18.79,34.94 v2(20.71,36.85) v1(20.71,39.26) ; PR1226.1 23.25,31.26 v1(22.87,30.88) ; PR1253.1 v1(11.05,31.26)
  TOP w0.508: PR1254.2 v1(18.95,39.36) ; PR1240.1 v1(67.54,102.21) ; PC1204.1 16.93,55.83 PR1236.2 17.79,56.3 18.29,56.81 v1(21.95,56.81)
  TOP w1.016: 42.82,100.58 42.11,101.29 28.64,101.29
  BOTTOM w0.508: v1(67.54,102.21) 68.73,102.21 69.24,102.72 PR1237.1 ; PD1801.2 v1(62.48,104.95)
  vias: v1(27.09,101.69) v1(27.74,101.69) v1(31.82,88.92) v1(32.45,88.92) v1(42.51,99.73) v1(43.23,99.77)
+3.3V_VDD_PIC_PDA: length 4.8
  TOP w0.102: v2(30.08,87.44) 30.59,86.94 30.82,86.94
  TOP w0.203: UT5.H1 31.64,83.95 31.34,84.26 ; UT5.B1 v1(34.64,83.59)
  TOP w0.381: 31.34,84.26 31.34,84.38 30.92,84.8 CT74.1
  vias: v1(31.95,87.01)
+3.3V_VGA: length 2.1
  TOP w0.203: UV6.1 275.79,56.47 275.8,56.49 v1(275.8,56.95)
  BOTTOM w0.127: v1(275.8,56.95) v2(275.8,57.63)
  BOTTOM w0.508: LV14.2 275.6,56.74 v1(275.8,56.95)
+3.3V_WLAN: length 1.7
  TOP w0.127: 214.13,5.1 214.13,3.96 v3(213.75,3.57)
  vias: v1(193.89,11.37) v1(193.89,10.79) v1(193.86,10.19) v1(194.49,11.38) v1(194.49,10.8) v1(194.49,10.19) v1(213.5,7.67) v1(213.53,7.01) v1(213.54,6.37) v1(214.17,7.63) v1(214.19,6.32) v1(214.2,6.98) v3(194.49,9.54) v3(213.16,8.17)
+3.3V_WLAN_UZ4:
  vias: v2(193.93,14.75)
+3.3V_WWAN: length 20.8
  TOP w0.127: v3(285.37,58.69) 285.74,59.06 v1(285.96,59.06)
  TOP w0.254: UZ36.24 284.61,66.13 CZ134.1 ; v1(289.31,61.87) 288.93,61.49 288.68,61.49 288.55,61.62 UZ36.12
  TOP w0.381: RZ360.1 290.97,65.79 v1(290.58,66.19)
  TOP w0.508: RZ43.2 288.55,49.6 288.15,49.2 288.15,48.32 287.5,47.67 287.06,47.67 v1(287.06,47.67) ; RZ154.1 282.42,61.3 v1(282.27,61.15) ; v1(284.74,66.95) CZ134.1
  BOTTOM w0.381: RZ160.1 RZ156.1 286.1,59.2 v1(285.96,59.06) ; v1(288.8,69.28) 289.06,69.28 289.81,68.53 RZ164.1 RZ358.1 ; v1(289.31,61.87) 289.18,61.99 CZ133.1
  BOTTOM w0.457: v1(293.88,63.65) RZ166.1 RZ158.1
  BOTTOM w0.508: RZ356.1 RZ354.1 286.03,68.83 285.96,68.9 v1(285.96,69.26) ; RZ162.1 290.8,59.67 v1(291.22,60.09)
  vias: v1(282.84,49.36) v1(283.26,49.79) v1(283.37,49.08) v1(283.67,50.21) v1(283.83,49.5) v1(284.21,49.95) v1(304.12,48.21) v1(304.14,47.63) v1(304.75,48.21) v1(304.78,47.63)
+3.3V_WWAN_UZ2: length 1
  BOTTOM w0.127: 278.03,46.26 278.03,45.73 v2(277.69,45.39)
+5V_ALW: length 78.3
  TOP w0.203: v1(275.04,76.3) 275.04,76.25 274.96,76.17 UZ5.4 ; UZ4.4 v1(189.82,16.53)
  TOP w0.254: JUSH1.18 222.55,15.65 221.65,14.75 CZ64.1 ; v1(62.74,65.3) 62.29,64.84 PC677.1 ; v1(62.67,71.65) 62.58,71.74 PC661.1 ; UZ3.4 201.15,7.61 200.76,7.22 198.46,7.22 197.75,7.93 197.15,7.93 195.48,9.6 195.48,10.14 196.02,10.69 196.02,11.09 195.62,11.49 195.62,14.55 196.83,15.75 196.83,17.34 v1(196.42,17.75) ; v1(269.6,52.16) 269.9,52.16 UZ8.4
  TOP w0.305: JLED1.1 284.4,50.67 v1(284.81,50.26)
  TOP w0.381: RI13.2 304.24,63.04 v1(304.11,63.04)
  TOP w0.508: RA53.2 v1(303.79,27.58) ; CZ64.1 220.6,14.75 CZ69.1 220.35,14.72 v1(219.92,15.16) ; v1(273.98,50.28) 274.1,50.28 277.44,46.94 277.75,46.94 278.5,46.19 278.5,45.74 279.86,44.37 v1(280.57,44.37) ; PR602.2 v1(75.23,46.2) ; LED3.2 v1(319.4,97.5) ; PR7.1 v1(62.03,93.51)
  BOTTOM w0.203: v1(62.67,71.65) 62.45,71.43 PU610.2 ; UZ2.4 274.07,50.18 v1(273.98,50.28) ; v1(62.74,65.3) 62.55,65.49 PU612.2
  BOTTOM w0.254: UZ21.3 128.64,82.43 v1(129.1,81.98) ; UZ23.4 277.57,42.46 v1(277.57,42.74) ; v1(131.37,80.74) 130.96,80.74 130.53,81.17 UZ19.3 ; v1(189.82,16.53) 187.52,16.53 187.32,16.73 v1(186.15,16.73) ; PU614.6 68.09,75.88 68.33,75.65 68.33,75.13 PC685.1
  BOTTOM w0.508: v1(136.41,115.14) 137.72,113.82 137.72,103.14 139.88,100.98 139.88,100.6 140.42,100.07 140.42,97.81 139.5,96.9 v1(139.5,92.41) ; v1(68.58,74.19) PC685.1 ; JUART1.1 v1(43.29,62.29)
  vias: v1(24.71,74.88) v1(24.71,74.27) v1(25.34,74.88) v1(25.34,74.27) v1(35.89,99.48) v1(35.88,97.86) v1(36.55,99.48) v1(36.59,97.86) v1(37.23,99.48) v1(37.23,97.86) v1(65.92,53.16) v1(66.44,53.45) v1(66.43,52.77) v1(82.81,101.49) v1(83.44,100.73) v1(84.21,100.73) v1(84.46,101.49) v1(127.75,29.43) v1(128.01,28.7) v1(128.33,29.22) v1(134.54,114.82) v1(135.2,114.83) v1(135.2,114.19) v1(135.58,115.97) v1(135.58,115.33) v1(165.49,99.52) v1(165.49,98.89) v1(166.18,99.52) v1(166.18,98.89) v1(166.18,98.25) v1(166.88,99.52) v1(166.88,98.89) v1(166.88,98.25) v1(167.58,99.52) v1(167.58,98.89) v1(167.58,98.25) v1(168.28,99.52) v1(168.28,98.89) v1(168.28,98.25) v1(185.44,17.42) v1(185.51,16.71) v1(186.07,17.41) v1(191.08,23.83) v1(191.09,23.19) v1(191.08,22.6) v1(191.68,23.83) v1(191.68,23.2) v1(191.73,22.59) v1(192.23,23.58) v1(192.27,22.91) v1(277.04,41.38) v1(277.21,40.28) v1(305.43,60.01) v1(305.68,59.44) v1(306.03,60) v1(306.36,60.49) v1(306.34,59.45) v1(309.83,62.72) v1(309.97,62.14) v1(309.98,61.5) v1(311.02,61.89) v1(311.16,62.53) v3(38.49,98.82) v3(136.66,116.03) v3(185.81,18.69)
+5V_ALW2: length 2.3
  TOP w0.102: v3(169.99,112.93) v1(169.99,113.49)
  BOTTOM w0.254: PU102.15 169.77,113.72 v1(169.99,113.49) PC126.1
+5V_ALW_PDA: length 1
  TOP w0.203: UT5.H10 31.64,78.99 v1(31.72,79.06) ; v1(33.64,77.55) UT5.D11
  vias: v1(34.49,76.95) v1(34.62,77.54) v1(35.12,76.95) v1(35.3,77.52) v1(38.68,92.83) v1(38.82,92.25) v1(39.28,92.83) v1(41.05,92.76) v1(41.74,92.78) v1(45.8,92.91) v1(46.44,92.91) v2(44.84,93.74)
+5V_ALWP: length 13
  BOTTOM w0.254: 170.63,113.81 170.27,114.17 PU102.14 ; PC130.1 171.24,104.83 173.11,106.7 173.11,113.61 PR117.2
  BOTTOM w0.508: 170.63,113.81 v1(172.15,113.81)
  vias: v1(169.99,103.71) v1(169.99,102.82) v1(169.99,101.87) v1(169.99,101.05) v3(169.42,104.29)
+5V_HDD: length 10.4
  TOP w0.127: v3(276.61,37.23) 277.88,37.23 278.37,37.72 v1(279.07,37.72) 279.07,37.27 v3(278.77,36.98)
  TOP w0.381: v1(279.07,37.72) 279.46,37.72 280.17,38.43 280.17,39.01 280.42,39.26 280.42,40.02 280.8,40.4 v3(282.2,40.4) 282.94,40.4 v1(283.05,40.29)
  BOTTOM w0.381: v1(283.05,40.29) 282.76,40.58 RN1.1
+5V_PD_VDD:
  vias: v2(39.93,97.68)
+5V_RUN: length 22.2
  TOP w0.254: JKBTP1.16 213.75,15.15 214.06,14.84 214.06,13.56 214.45,13.17 215.22,13.17 CZ92.1
  TOP w0.381: CZ92.1 215.4,12.87 v1(215.19,12.67)
  BOTTOM w0.254: v1(122.18,85.06) 122.58,85.06 122.78,85.26 RV6.2
  BOTTOM w0.508: v1(128.73,98.39) 128.73,93.18 125.54,89.98 125.54,89.37 126.27,88.64 128.05,88.64 ; QV8.3 127.11,87.7 128.05,88.64 ; v1(127.99,88.7) 128.05,88.64 ; v1(317,77.11) 317,76.6 UV4.1
  vias: v1(191.72,20.89) v1(191.72,20.25) v1(192.26,21.13) v1(192.24,20.52) v1(192.25,19.89) v1(192.86,21.11) v1(192.84,20.52) v1(192.87,19.89) v1(220.1,17.16) v1(220.68,17.16) v1(229.96,15.17) v1(229.96,14.52) v1(230.63,15.87) v1(230.63,15.27) v1(230.66,14.68) v1(230.66,14.06) v1(244.07,34.84) v1(244.66,34.84) v1(245.27,34.84) v1(245.62,35.32) v1(246.23,35.32) v1(260.22,48.55) v1(260.27,46.93) v1(260.31,47.51) v1(260.77,48.85) v1(261.41,48.85) v1(264.75,40.15) v1(265.16,40.61) v1(265.74,40.58) v1(266.25,40.89) v1(270.88,66.76) v1(270.91,68.35) v1(271.49,67.61) v1(271.52,68.23) v1(271.53,66.76) v1(271.53,66.14) v1(275.06,77.74) v1(275.26,78.32) v1(277.04,74.82) v1(277.12,75.48) v1(277.68,74.9) v1(277.7,75.51) v1(278.12,39.62) v1(278.51,40.16) v1(278.62,39.31) v3(170.57,67.96)
+5V_RUN_AUDIO:
  vias: v1(273.66,67.68) v1(273.66,67.05) v1(273.66,66.36) v1(274.28,67.64) v1(274.28,67.04) v1(274.3,66.41) v1(299.59,46.42) v1(299.94,47) v1(300.17,46.42) v1(300.58,47) v1(300.77,46.42) v1(308.17,27.45) v1(308.81,27.45) v1(309.4,27.45) v3(308.62,26.82)
+5V_RUN_AUDIO_UZ5:
  vias: v2(277.4,72.48)
+5V_RUN_PVDD_L:
  vias: v2(300.64,40.15)
+5V_RUN_UZ4: length 1
  TOP w0.127: 193.02,18.83 v2(191.98,18.83)
+5V_TBT_VBUS: length 0.6
  TOP w0.102: v1(34.99,94.06) v3(34.99,93.45)
  vias: v1(25.34,89.81) v1(25.34,89.17) v1(34.99,94.7)
+5V_TBTA_VBUS_D:
  vias: v1(42.76,95.63) v1(43.33,95.88) v2(43.87,95.95)
+5V_TSP:
  vias: v3(121.42,90.12)
+5V_USB_CHG_PWR:
  vias: v1(307.78,41.88) v1(307.9,41.24) v1(308.41,41.88) v1(308.67,41.24) v1(309.05,41.88) v1(311.82,55.67) v1(311.85,55.06) v1(311.87,54.48) v1(312.48,55.06) v1(313.03,54.75) v3(311.41,57.04)
+DV33_18: length 5.3
  TOP w0.127: CR22.1 21.16,51.33 19.5,51.33 v2(19.12,51.71)
  TOP w0.254: 22.57,51.54 23.06,51.06 UR1.18
  TOP w0.508: 22.57,51.54 22.28,51.83 CR22.1
+GND_CHASSIS: length 5.9
  TOP w0.127: RL17.2 v2(299.93,100.4)
  TOP w0.508: RL16.2 v1(295.53,99.21) ; v1(298.84,99.21) RL17.2 ; RL15.2 v1(292.99,99.21) ; RL18.2 v1(302.39,99.21)
+VBUS_DC_SS: length 2.3
  TOP w0.102: PD903.2 v2(9.53,27.26)
  TOP w0.254: v1(9.53,24.94) PD903.2
  vias: v1(9.23,47.92)
+VCC1V8A_TBTA_LDO: length 4.7
  TOP w0.076: UT5.K1 30.64,83.24 30.12,83.77
  TOP w0.102: 30.12,83.77 29.95,83.93 29.25,83.93 28.78,84.4 28.16,84.4 v2(27.72,84.84) 27.7,84.85 CT73.1
+VCC1V8D_TBTA_LDO: length 5.1
  TOP w0.102: RT97.1 37.46,85.53 37.88,85.95 v2(37.88,86.38)
  TOP w0.203: UT5.A2 35.15,82.54 35.95,83.33 35.95,83.38
  TOP w0.381: 35.95,83.38 37.06,84.5 37.36,84.5 CT72.1 RT97.1
+VCC_1P8: length 8.4
  TOP w0.356: CC222.1 130.02,59.59 130.46,60.03 v1(131.09,60.03)
  TOP w0.508: RC313.2 141.89,69.11 140.61,67.83 v2(138.63,67.83) 138.26,67.83 v1(138.07,67.64)
+VCC_CORE: length 27.5
  TOP w0.381: 111.44,57.16 PC1035.1 111.43,57.73 PC1036.1
  BOTTOM w0.127: 115.91,64.76 UC1.K38 115.6,64.44 ; 114.69,54.76 UC1.AK40 114.88,54.39 115.01,54.51 ; 118.8,54.27 UC1.AL33 118.46,53.93 ; 117.43,64.43 UC1.K35 117.75,64.76 ; 118.02,64.76 UC1.K33 118.34,64.46 ; 116.66,53.93 UC1.AL37 117.25,53.93 ; UC1.AK38 115.6,54.8 ; UC1.AK38 115.28,54.39 ; UC1.AK38 115.6,54.05 ; 118.19,65.23 UC1.J33 ; UC1.J33 117.58,65.23 ; UC1.J33 117.89,65.53 ; 119.41,65.23 UC1.J30 119.72,64.92 ; 116.52,54.04 UC1.AK37 ; UC1.AK37 116.87,54.39 ; UC1.AK37 116.52,54.77 ; UC1.J40 113.92,65.23 113.77,65.07 UC1.K42 113.77,64.44 ; UC1.J40 114.23,64.92 ; UC1.J40 114.54,65.23 ; 117.43,54.76 UC1.AK35 ; UC1.AK35 117.13,54.39 ; UC1.AK35 117.43,54.03 ; 115.14,54.28 UC1.AL40 115.47,53.93 ; 112.86,64.38 UC1.K43 ; UC1.J37 116.06,65.53 ; UC1.J37 116.06,64.92 ; UC1.J37 116.36,65.23 ; UC1.J37 115.75,65.23 ; 114.69,65.1 UC1.K40 114.69,64.45 ; UC1.AK33 118.34,54.03 ; UC1.AK33 118.34,54.74 ; UC1.AK33 118.68,54.39 ; 116.52,64.43 UC1.K37 116.21,64.76
  BOTTOM w0.203: UC1.A39 114.87,69.47 114.87,70.23 v1(114.92,70.28) ; UC1.G33 118.34,65.72 v1(117.84,66) 117.43,65.77 UC1.G35 ; v1(112.31,70.3) UC1.A44 ; v1(119.54,70.01) 119.75,69.8 UC1.A30 ; UC1.A34 117.27,69.42 117.49,69.64 v1(117.49,69.88)
  BOTTOM w0.254: 115.96,65.94 115.85,65.94 UC1.G38 ; UC1.G42 114.07,65.99 v1(114.22,65.99) 114.39,65.99 UC1.G40 ; UC1.AM33 117.89,53.06 UC1.AM35 v1(116.97,53.06) UC1.AM37 v1(116.06,53.06) UC1.AM38 ; UC1.G30 120.17,65.71 119.9,65.98 v1(119.76,65.98) 119.55,65.98 UC1.G32 ; 116.12,65.96 116.39,65.69 UC1.G37
  BOTTOM w0.508: RC140.2 113.29,78.29 v1(113.27,78.31)
  vias: v1(73.73,69.11) v1(73.8,70.29) v1(74.11,70.88) v1(74.17,69.68) v1(74.36,71.52) v1(74.49,70.31) v1(74.49,69.11) v1(74.87,70.88) v1(74.87,69.68) v1(75,71.46) v1(74.94,68.53) v1(75.19,70.31) v1(75.25,69.11) v1(75.63,70.88) v1(75.7,69.74) v1(75.76,68.53) v1(75.82,71.46) v1(76.01,70.38) v1(76.01,69.17) v1(76.59,71.46) v1(76.84,68.41) v1(77.09,72.03) v1(77.28,71.46) v1(77.73,72.03) v1(78.05,71.46) v1(78.11,68.41) v1(78.75,71.58) v1(79.44,68.41) v1(79.51,71.58) v1(80.65,68.41) v1(81.79,73.93) v1(81.79,73.17) v1(81.79,72.34) v1(82.3,74.38) v1(82.3,73.61) v1(82.36,72.79) v1(111.76,63.47) v1(111.79,61.99) v1(111.74,59.39) v1(112.38,64.48) v1(112.35,56.83) v1(112.93,55.36) v1(113.16,59.12) v1(113.16,56.74) v1(113.25,61.52) v1(113.31,64.52) v1(113.59,55.36) v1(113.85,64.08) v1(114.23,64.54) v1(114.2,55.37) v1(114.21,54.78) v1(114.4,59.11) v1(114.34,56.79) v1(114.4,63.63) v1(114.56,61.44) v1(114.72,64.14) v1(114.92,55.4) v1(115.15,64.54) v1(115.59,64.1) v1(115.56,55.39) v1(115.62,59.13) v1(115.61,56.76) v1(115.73,61.52) v1(116.05,64.46) v1(116.21,62.93) v1(116.29,55.36) v1(116.54,64.09) v1(116.97,64.53) v1(117,61.49) v1(116.91,55.34) v1(116.96,54.72) v1(117.03,59.16) v1(117,56.74) v1(117.36,64.09) v1(117.64,55.32) v1(117.91,64.4) v1(118.12,63.13) v1(118.34,55.34) v1(119.25,59.44) v1(119.25,58.04) v3(91.83,78.63)
+VCC_CORE_G0: length 1.1
  TOP w0.254: T122.1 119.59,64.36 v1(119.58,64.34)
  BOTTOM w0.254: UC1.K32 119.58,64.45 v1(119.58,64.34)
+VCC_CORE_G1: length 1.6
  TOP w0.254: v1(119.21,55.36) 119.21,55.22 T123.1
  BOTTOM w0.254: v1(119.21,55.36) 119.26,55.3 UC1.AK32
+VCC_GT: length 37.1
  TOP w0.381: 104.42,63.17 v1(104.45,63.17)
  BOTTOM w0.127: 107.38,65.1 107.37,65.1 UC1.K53 ; 102.04,62.08 102.04,62.08 UC1.R63 ; UC1.J46 110.2,65.23 110.2,65.23 ; UC1.J46 110.95,65.23 110.96,65.23 ; UC1.J46 110.57,64.92 ; UC1.J52 108.19,65.23 108.19,65.23 ; UC1.J52 107.83,64.92 ; UC1.J52 107.48,65.23 107.48,65.23 ; 106.37,65.23 UC1.J55 106,64.92 ; 102.36,59.91 UC1.W63 ; UC1.W63 102.04,59.6 ; UC1.W63 101.68,59.91 ; 104.32,64.76 UC1.K58 ; UC1.K58 104.63,64.39 ; UC1.K58 104.63,65.07 ; UC1.K58 104.93,64.76 ; 101.73,63.57 UC1.L63 ; UC1.L63 102.36,63.57 ; UC1.L63 102.04,63.39 102.08,63.34 102.08,63.26 ; 102.04,58.66 UC1.AA63 ; UC1.AA63 101.7,59 ; UC1.AA63 102.36,59 ; UC1.AA63 102.04,59.3 ; 105.55,64.39 105.54,64.4 UC1.K56 ; 111.85,65.23 111.84,65.23 UC1.J45 ; UC1.J45 111.49,64.92 ; UC1.J45 111.14,65.23 111.14,65.23 ; 106.91,64.92 UC1.J53 ; UC1.J53 106.61,65.23 ; UC1.J53 107.32,65.23 107.33,65.23 ; 109.51,64.76 UC1.K50 ; UC1.K50 109.2,64.45 ; UC1.K50 109.2,65.07 ; UC1.K50 108.9,64.76 ; UC1.K48 110.12,65.12 110.12,65.13 ; UC1.K48 110.42,64.76 ; UC1.K48 109.81,64.76 ; UC1.K48 110.12,64.39 ; UC1.K60 104.02,64.76 ; UC1.K60 103.71,64.41 ; UC1.K60 103.41,64.76 ; UC1.R63 102.34,61.74 ; UC1.R63 102.04,61.39 ; UC1.R63 101.73,61.74 ; 108.39,65.23 108.4,65.23 UC1.J50 ; UC1.Y62 102.78,59.45 ; UC1.Y62 102.51,59.79 102.5,59.8 ; UC1.Y62 102.51,59.11 102.5,59.11 ; UC1.Y62 102.18,59.45 ; 104.5,65.23 UC1.J58 ; UC1.J58 103.84,65.23 103.81,65.2 ; UC1.J58 104.17,64.92 ; UC1.K53 107.07,64.76 ; UC1.K53 107.37,64.38 ; UC1.K53 107.68,64.76 ; UC1.K55 106.76,64.76 ; UC1.K55 106.15,64.76 ; UC1.K55 106.46,64.38 ; UC1.K55 106.46,65.07 ; 108.29,65.1 108.29,65.1 UC1.K52 ; UC1.L62 102.89,64.02 ; UC1.L62 102.51,64.35 ; UC1.L62 102.51,63.72 ; UC1.N63 101.7,62.65 ; UC1.N63 102.36,62.65 ; UC1.N63 102.04,62.29 ; 112.4,64.94 UC1.J43 112.1,65.23 ; 103.26,64.92 UC1.J60 103.6,65.23 ; UC1.J56 105.42,65.23 105.42,65.23 ; UC1.J56 105.09,64.92 ; UC1.J56 104.74,65.23 ; UC1.J50 108.74,64.92 ; UC1.J50 109.1,65.23 ; UC1.M62 102.82,63.11 ; UC1.M62 102.51,62.77 ; UC1.M62 102.51,63.42 ; 102.81,61.28 UC1.T62 ; UC1.T62 102.51,61.59 ; UC1.T62 102.51,60.92 102.5,60.91 ; UC1.T62 102.18,61.28 ; 109.31,65.23 UC1.J48 ; UC1.J48 110.02,65.23 110.02,65.23 ; UC1.J48 109.66,64.92 ; 105.24,64.76 UC1.K56 ; UC1.K56 105.85,64.76 ; 108.29,64.42 UC1.K52 ; UC1.K52 108.59,64.76 ; UC1.K52 107.98,64.76
  BOTTOM w0.203: UC1.A53 107.28,69.47 107.28,70.18 v1(107.37,70.28) ; v1(99.92,70.4) UC1.A66 ; UC1.A48 109.89,69.44 109.89,70.09 v1(109.99,70.2) ; v1(104.88,70.4) UC1.A58 ; v1(102.4,70.4) UC1.A62
  BOTTOM w0.381: 89.69,62.38 89.69,63.67 89.97,63.95 RC161.2
  vias: v1(73.92,60.66) v1(73.94,59.5) v1(74.24,61.3) v1(74.24,60.09) v1(74.55,59.52) v1(74.68,60.66) v1(75,61.3) v1(75,60.09) v1(75.32,59.52) v1(75.44,60.66) v1(75.76,61.3) v1(75.76,60.09) v1(76.08,59.52) v1(76.21,60.66) v1(76.52,61.3) v1(76.52,60.09) v1(77.54,59.58) v1(77.98,60.22) v1(78.11,61.36) v1(78.36,60.79) v1(78.3,59.58) v1(78.75,60.22) v1(78.87,61.36) v1(79.06,59.58) v1(79.13,60.79) v1(79.51,60.22) v1(79.63,61.36) v1(79.89,60.79) v1(79.82,59.58) v1(80.27,60.22) v1(80.4,61.36) v1(80.65,60.79) v1(86.15,59.5) v1(86.87,61.54) v1(87.62,59.55) v1(88.38,60.39) v1(89.18,61.46) v1(97.16,63.11) v1(97.16,62.2) v1(97.16,61.28) v1(97.16,60.37) v1(97.16,59.45) v1(97.16,58.54) v1(97.15,57.68) v1(97.81,63.11) v1(97.81,62.2) v1(97.81,61.28) v1(97.81,59.45) v1(97.81,58.54) v1(98.46,63.11) v1(98.46,62.2) v1(98.46,61.28) v1(98.46,60.37) v1(98.46,59.45) v1(98.46,58.54) v1(99.11,63.11) v1(99.11,61.28) v1(99.11,60.37) v1(99.11,59.45) v1(99.76,63.11) v1(99.76,62.2) v1(99.76,61.28) v1(99.76,59.45) v1(99.76,58.54) v1(100.41,63.11) v1(100.41,62.2) v1(100.41,61.28) v1(100.41,60.37) v1(100.41,59.45) v1(100.41,58.54) v1(101.06,60.37) v1(101.71,63.11) v1(101.71,62.2) v1(101.71,58.54) v1(102.77,61.74) v1(103.01,63.58) v1(103.03,62.28) v1(103.01,60.96) v1(103.01,59.87) v1(103.03,59.14) v1(103.01,58.53) v1(103.26,64.54) v1(103.35,55.82) v1(104.17,64.54) v1(104.4,57.93) v1(104.43,61.82) v1(104.42,60.44) v1(105.09,64.51) v1(105.31,55.82) v1(105.78,63.08) v1(105.9,60.8) v1(105.88,58.25) v1(105.92,55.8) v1(106,64.51) v1(106.91,64.51) v1(107.8,55.81) v1(107.83,64.51) v1(107.87,63.11) v1(107.88,60.72) v1(107.84,58.24) v1(108.74,64.51) v1(109.17,63.11) v1(109.23,61.71) v1(109.25,59.66) v1(109.35,59.06) v1(109.36,57.27) v1(109.38,56.68) v1(109.38,54.89) v3(77.6,62.12)
+VCC_GTUS: length 24.9
  BOTTOM w0.102: 113.77,54.73 UC1.AK42 113.47,54.39
  BOTTOM w0.127: UC1.AK46 111.03,54.71 ; UC1.AK46 111.03,54.02 ; UC1.AK46 111.36,54.39 ; UC1.AK46 110.63,54.39 ; 104.17,53.6 UC1.AL60 ; UC1.AL60 104.53,53.93 ; UC1.AL60 103.85,53.93 ; UC1.AL60 104.17,54.26 ; 108.63,53.45 UC1.AM52 ; UC1.AM52 107.93,53.45 ; UC1.AM52 108.29,53.77 ; UC1.AK43 112.49,54.39 ; UC1.AK43 112.86,54.06 ; UC1.AK43 113.19,54.39 ; UC1.AK43 112.86,54.71 ; UC1.AL46 111.49,54.3 ; UC1.AL46 111.8,53.93 ; UC1.AL46 111.14,53.93 ; UC1.AK45 111.65,54.39 ; UC1.AK45 111.94,54.72 ; UC1.AK45 112.27,54.39 ; UC1.AK45 111.94,54.04 ; 107.72,53.45 UC1.AM53 ; UC1.AM53 107.01,53.45 ; UC1.AM53 107.37,53.78 ; 109.66,53.58 UC1.AL50 ; UC1.AL50 109.66,54.26 ; UC1.AL50 110,53.93 ; UC1.AL50 109.33,53.93 ; UC1.AK55 106.46,54.75 ; UC1.AK55 106.46,54.04 ; UC1.AK55 106.14,54.39 ; 108.29,54.7 UC1.AK52 ; UC1.AK52 108.29,54.05 ; UC1.AK52 107.92,54.39 ; 107.37,54.06 UC1.AK53 ; UC1.AK53 107.37,54.71 ; UC1.AK53 107.7,54.39 ; UC1.AM50 109.2,53.81 ; UC1.AM50 108.84,53.45 ; UC1.AM50 109.55,53.45 ; UC1.AM48 110.47,53.45 ; UC1.AM48 109.75,53.45 ; UC1.AM48 110.12,53.82 ; UC1.AK48 110.47,54.39 ; UC1.AK48 109.8,54.39 ; UC1.AK48 110.12,54.09 ; UC1.AK48 110.12,54.7 ; 113.32,54.28 UC1.AL43 112.97,53.93 ; 109.56,54.39 UC1.AK50 109.2,54.05 ; 107.83,54.26 UC1.AL53 ; UC1.AL53 107.83,53.6 ; UC1.AL53 107.48,53.93 ; UC1.AL53 108.16,53.93 108.17,53.93 ; 103.71,54.02 UC1.AK60 104.05,54.39 ; 105.18,53.45 UC1.AM56 105.54,53.78 ; 104.31,53.45 UC1.AM58 104.63,53.76 ; UC1.AL56 106,53.6 ; UC1.AL56 106,54.29 ; UC1.AL56 106.36,53.93 ; UC1.AL56 105.58,53.93 ; 104.63,54.06 UC1.AK58 ; UC1.AK58 104.63,54.72 ; UC1.AK58 104.31,54.39 ; 105.54,54.8 UC1.AK56 105.54,54.1
+VCC_SA: length 68.2
  TOP w0.254: PR636.2 72.71,43.88 PR641.2 ; PR641.2 73.57,43.87 PC644.1 74.45,43.88 76.5,43.88 76.87,44.25 76.87,53.31 73.51,56.67 73.51,58.07 72.91,58.67 72.91,73.36 73.93,74.38 77.05,74.38 77.93,75.26 77.93,80.23 v1(78.36,80.66) ; PR641.2 73.57,43.08 PC637.2 PR643.1 PC633.2
  TOP w0.381: PC1152.1 121.37,66.12 v1(121.55,65.94) 121.7,65.94 122.15,66.4 PC1148.1
  TOP w0.508: v1(122.68,82.29) 122.43,82.04 RC168.1
  BOTTOM w0.127: 121.89,64.49 122,64.6 UC1.K27 ; 123.98,65.23 UC1.J22 124.29,64.92 ; 120.17,65.07 UC1.K30 120.17,64.46 ; 123.68,65.23 UC1.J23 ; UC1.J23 123.07,65.23 ; UC1.J23 123.37,64.92 ; 121.24,65.23 UC1.J27 ; UC1.J27 121.85,65.23 ; UC1.J27 121.55,64.92 ; 122,65.07 UC1.K27 ; UC1.K27 121.7,64.76 ; UC1.K28 121.39,64.76 ; UC1.K28 121.09,64.46 ; UC1.K28 121.09,65.07 ; UC1.K23 123.53,64.76 ; UC1.K23 123.83,64.46 ; UC1.K23 123.83,65.07 ; UC1.K25 123.22,64.76 ; UC1.K25 122.92,65.07 ; UC1.K25 122.92,64.46
  BOTTOM w0.203: UC1.G23 v1(123.37,65.94) UC1.G25 UC1.G27 v1(121.55,65.94) UC1.G28
  BOTTOM w0.254: v1(78.36,80.66) 78.36,80.97 78.95,81.55 PH604.2 79.1,79.88 78.72,79.49 78.72,78.5 79.04,78.19 PL614.1
  vias: v1(84.08,79.01) v1(84.1,78.38) v1(84.71,79.01) v1(84.71,78.4) v1(85.35,79.01) v1(85.35,78.4) v1(85.98,79.01) v1(85.98,78.4) v1(121.55,64.54) v1(121.8,60.47) v1(122.53,59.15) v1(122.52,55.53) v1(123.09,61.79) v1(123.09,60.88) v1(123.1,55.43) v1(123.73,55.5) v3(82.94,78.25)
+VCC_SFR_OC: length 27.5
  TOP w0.254: 124.59,51.2 124.08,51.2 123.83,50.95 123.83,49.42
  TOP w0.508: 123.83,49.42 123.83,48.66 125.48,47.01 125.48,45.36 124.21,44.08 124.21,37.48 122.64,35.91 122.64,34.75 v3(121.49,33.6) 120.02,32.14 120.02,29.74 120.78,28.97 CC288.1
  BOTTOM w0.254: v1(124.29,54.55) UC1.AL23
+VCCK_12: length 6.7
  TOP w0.254: v1(279.34,57.98) 279.34,57.93 279.09,57.68 UV6.25 ; UV6.4 275.25,55.27 274.53,56 274.53,56.67 v1(274.32,56.87)
  BOTTOM w0.102: v1(274.32,56.87) 274.51,56.68 v2(274.51,56.39)
  BOTTOM w0.254: v1(274.32,56.87) 273.8,56.34 CV103.1 ; CV104.1 CV105.1 278.71,58.62 v1(279.34,57.98)
+VDD_DAC_33: length 3.1
  TOP w0.127: v2(282.64,55.29) 282.58,55.23 LV30.2
  TOP w0.203: UV6.20 280.27,54.87 280.57,55.17 281.13,55.17 281.18,55.23 LV30.2
+VDDA_AVDD1:
  vias: v2(305.44,32.89)
+VSS_PLL:
  vias: v2(300,70.5)
GND: length 1929
  TOP w0.127: v1(171.92,117.11) v3(172.85,117.11) ; v1(310.14,91.31) 310.16,91.31 v3(310.65,90.82) ; v3(270.41,85.34) 270.64,85.11 v1(271.2,85.11) ; v1(268.2,77.1) v3(268.2,78.12) ; v3(176.05,92.96) v1(175.38,92.96)
  TOP w0.203: UT5.A6 UT5.A7 ; UZ4.11 v1(193.93,16.53) ; UT5.A1 35.45,83.35 v1(35.45,83.71) ; UT5.L1 30.14,83.2 v1(29.89,83.46) ; v1(204.82,7.59) 204.81,7.61 UZ3.11
  TOP w0.254: RC166.2 121.16,82.08 v1(120.9,82.34) ; JKBTP1.18 212.64,14.15 v1(212.37,14.42) 212.3,14.35 212.3,13.95 212.61,13.65 JKBTP1.19 ; CC179.2 103.69,39.25 v1(103.88,39.44) ; v1(288.51,86.03) 288.81,85.73 UE4.3 ; v1(285.26,61.73) 285.74,61.73 UZ36.7 ; v1(278.81,56.19) 279.06,56.19 279.34,56.47 UV6.24 ; DT7.2 11.85,93.23 v1(11.83,93.21) ; v1(93.19,96.46) 93.34,96.6 RV77.2 ; UE1.E6 298.34,75.51 298.34,75.52 v1(298.35,75.52) ; v1(300.51,56.41) 300.26,56.66 UI5.21 ; JKBTP1.12 212.64,17.15 v1(212.35,17.44) ; v1(142.77,113.24) 143.01,113.48 PR415.2 ; PC402.2 v1(135.93,111.41) ; PC651.1 v1(60.19,51.33) ; v1(135.31,111.31) 135.29,111.31 135.29,111.31 PR424.2 ; CZ90.2 214.74,17.41 v1(214.97,17.19) ; PR403.2 135.86,112.3 v1(135.44,111.88) ; JXDP1.38 66.45,32.26 v1(66.34,32.38) ; PQ1208.4 v1(26.48,35.96) ; v1(302.53,62.06) 302.65,61.94 RI39.2 ; CC323.2 147.15,61.36 v1(147.27,61.23) ; PC1091.2 115.46,54.84 PC1098.2 115.95,54.85 v1(116.05,54.74) 116.28,54.52 PC1125.2 PC1099.2 ; DT15.2 v1(11.86,96.03) DT16.2 ; v1(116.23,63.6) PC1054.2 115.58,63.04 PC1126.2 ; CZ67.2 v1(221.67,15.44) ; v1(223.93,10.24) 223.84,10.15 JUSH1.7 ; UZ12.9 168.82,39.17 v1(168.6,38.94) ; v1(276.21,66.83) 275.72,67.33 CA64.2 CA63.2 ; JXDP1.19 v1(70.95,37.44) ; RI41.2 v1(300.61,62.09) ; v1(93.33,93.96) 93.33,93.98 RV76.2 ; v1(165.55,38.94) 165.32,39.17 UZ12.16 ; v1(186.57,14.22) 186.14,14.22 185.81,13.89 CD60.2 ; RN19.2 278.35,58.51 277.63,58.51 v1(277.39,58.75) ; v1(121.95,55.34) 122.52,54.77 RC167.2 ; CC29.2 v1(64.14,39.95) ; UI5.10 304.56,56.66 v1(304.63,56.59) ; CC33.2 62.36,39.76 v1(62.22,39.91) ; CC204.2 132.06,52.88 132.06,52.23 v1(131.6,51.77) ; CA55.2 295.28,33.17 295.03,32.91 295.03,32.39 v1(295.26,32.16) ; v1(22.33,94.05) 23.11,93.27 CT121.2 ; v1(309.36,60.22) 309.61,59.97 UI3.14 ; v1(122.12,114.99) 122.12,114.99 PR419.2 ; PC1094.2 113.84,63.02 PC1096.2 v1(114.39,63.01) ; v1(11.44,18.65) 12.25,18.65 PR960.1 ; v1(212.32,19.54) 212.32,19.8 212.67,20.15 JKBTP1.6 ; PC654.1 v1(60.23,50.06) ; UE1.A6 295.16,75.53 ; RT63.2 33.72,87.34 33.98,87.09 33.98,86.84 34.04,86.78 34.04,86.08 33.98,86.02 33.98,86.01 CT71.2 ; v1(106,65.94) 106.43,65.51 PC1041.2 ; PR420.2 v1(125.4,115.65) ; PC1042.2 109.2,65.5 v1(109.64,65.94) ; v1(271.05,45.99) 270.88,45.99 270.52,46.35 CZ121.2 ; JUSH1.6 223.84,9.65 v1(223.91,9.58) ; v1(119.98,63.86) 119.53,63.86 119.52,63.85 PC1052.2 ; PC1040.2 108.3,65.58 v1(107.88,66) 107.45,65.57 PC1046.2 ; CC195.2 124.26,64.46 v1(124.3,64.46) ; JXDP1.32 v1(67.95,28.49) ; PC1033.2 118.12,65.4 117.76,65.4 117.5,65.67 PC1039.2 117.28,65.68 PC1038.2 ; RI52.2 299.6,61.89 v1(299.45,62.04) ; v1(274.96,74.44) UZ5.11 ; PC1051.2 v1(119.98,63.28) ; v1(114.21,66.62) 114.03,66.62 113.73,66.32 RC324.2 ; v1(285.68,52.39) 285.9,52.17 JLED1.4 ; v1(217.51,21.74) 218.03,21.21 CZ89.2 CZ88.2 ; UN7.3 v1(277.14,64.15) ; v1(287.07,79.19) 286.74,79.19 285.95,78.39 CE57.2 ; PR412.1 144.68,109.48 v1(143.91,109.48) ; JUSH1.10 223.6,11.65 v1(223.91,11.96) ; UN4.7 262.15,45.76 v1(262.29,45.89) ; JUSH1.25 223.4,19.15 v1(223.81,18.74) 223.72,18.65 JUSH1.24 ; PC1036.2 110.85,57.73 PC1035.2 ; v1(269.62,50.25) UZ8.5 ; CZ63.2 v1(219.53,11.7) ; v1(295.16,81.93) UE1.A13 ; v1(163.63,35.37) 163.63,35.6 164.2,36.17 UZ12.23 ; PR407.2 v1(127.05,115.3) ; UN5.7 291.39,54.71 v1(291.25,54.84) ; RI54.2 v1(301.63,62.06) ; v1(301.56,73.93) UE1.H4 ; CZ81.2 217.3,23.13 v1(217.35,23.08) ; v1(127.92,115.32) 127.92,115.31 PC411.2 ; JDB1.6 v1(29.87,98.04) ; CZ62.2 v1(219.43,10.43)
  TOP w0.305: JXDP1.20 70.95,31.26 v1(70.19,32.02) ; JXDP1.13 72.45,34.71 72.93,34.23 73.85,34.23 v1(73.95,34.13) JXDP1.7 ; RC139.2 60.92,38.85 v1(60.7,38.85) ; JDB1.7 33.25,99.41 33.43,99.23 34.25,99.23 34.55,99.52 v1(34.55,100.04) ; v1(103.73,10.35) 104.07,10.01 CD28.2 103.91,9.55 CD27.2 ; UE1.C4 v1(296.76,73.93) ; DT8.2 v1(11.83,98.85) DT18.2 ; v1(11.13,101.34) 11.14,101.33 DT17.2 ; v1(73.95,32.07) JXDP1.8 73.95,28.89 73.68,28.62 72.76,28.62 72.45,28.92 JXDP1.14 ; v1(63.22,34.23) 63.45,34.47 JXDP1.49 ; RI37.1 305.77,51.24 305.24,51.24 v1(304.91,51.57) ; JXDP1.37 66.45,34.61 66.15,34.31 v1(65.99,34.31) ; v1(11.85,90.21) 11.85,90.24 11.84,90.25 DT20.2 ; CE15.2 v1(300.79,70.06) ; v1(11.83,93.21) 11.85,93.19 DT19.2 ; CC30.2 v1(56.88,31.66) ; CA60.2 306.56,28.53 v1(306.27,28.53) ; v1(76.5,29.86) 76.26,30.11 JXDP1.2 ; RC122.2 76.08,39.77 v1(75.9,39.95) ; v1(213.62,23.26) 213.62,22.85 213.42,22.65 JKBTP1.1 ; v1(118.16,63.84) 117.9,63.59 PC1093.2 PC1092.2 ; v1(50.68,32.79) UC8.7 ; JXDP1.26 69.45,31.3 v1(69.73,31.58) ; JXDP1.50 v1(63.45,31.69) ; v1(125.04,58.89) 124.61,59.31 PC1151.2 PC1150.2 PC1153.2 ; JXDP1.59 60.95,36.28 v1(60.36,36.87) ; CC223.2 129.83,55.63 v1(129.68,55.48) ; RC44.2 129.58,58.28 v1(129.03,58.83) ; JKBTP1.4 v1(214.13,21.15) ; v1(29.32,98.87) 28.98,99.21 JDB1.8 ; JXDP1.25 69.45,34.69 69.07,34.31 v1(68.1,34.31) 67.95,34.46 JXDP1.31 ; v1(65.16,16.25) 64.82,16.58 UD1.3 ; v1(15.68,95.2) RT307.2 ; RT142.2 v1(14.99,93.49)
  TOP w0.356: v1(292.68,89.69) 292.74,89.76 QE13.2 ; v1(129.03,58.83) 129.03,59.46 CC222.2
  TOP w0.381: CD58.2 168.43,5.63 v1(168.03,6.03) ; v1(299.22,94.51) 299.22,94.2 RE85.2 ; CZ82.2 138.64,30.98 138.17,31.45 v1(137.27,31.45) ; UE5.3 v1(303.52,93.87) ; v1(292.89,74.92) 293.26,75.29 CE13.2 294.92,75.29 295.16,75.53 ; v1(296.17,94.51) 295.79,94.13 CL20.2 ; PQ1.4 v1(59.13,107.42) ; PC1032.2 118.61,67.1 PC1030.2 118.61,66.13 v1(118.74,66) ; PC1032.2 118.98,67.12 PC1087.2 ; PC1032.2 118.61,67.15 PC1085.2 119.11,68.23 v1(119.84,68.23) ; RE77.2 CE38.2 291.98,81.68 v1(291.75,81.9) ; PQ1209.1 v1(17.71,53.42) ; PC1011.2 110.58,63.14 v1(110.25,63.14) 109.97,62.86 PC1029.2 ; 125.28,53.12 125.3,53.14 CC270.2 ; 125.28,53.12 125.28,53.47 125.5,53.69 CC313.2 ; 125.28,53.12 v1(125.2,53.04) ; v1(90.37,14.24) 90.52,14.09 CD32.2 ; PC1037.2 112.46,68.09 v1(112.31,68.23) ; CZ117.2 195.9,17.09 195.5,17.49 CZ116.2 ; v1(81.25,70.75) 80.88,70.38 PC1081.2 ; CC253.2 117.99,52.51 v1(117.89,52.41) ; v1(116.35,59.14) 116.17,59.32 PC1068.2 ; CZ122.2 192.37,13.77 191.84,13.24 v1(191.5,13.24) ; v1(111.8,62.73) 111.71,62.73 111.38,62.4 PC1001.2 ; v1(129.07,60.49) 129.16,60.58 129.16,61.4 CC206.2 ; PC1056.2 100.94,58.66 v1(101.06,58.54) ; v1(115.14,65.94) 115.41,65.68 PC1089.2 115.85,65.76 PC1090.2 115.85,66.78 115.99,66.92 PC1097.2 116.01,67.02 PC1084.2 PC1086.2 115.06,68.12 v1(114.97,68.21) ; PC949.1 28.67,28.07 29.49,28.9 PU903.3 30.18,28.9 v1(30.61,29.33) ; v1(116.34,56.77) 116.34,57.21 PC1066.2 ; v1(216.46,12.51) 215.98,13 CZ92.2 CZ91.2 215.98,14.42 CZ85.2 ; CE25.2 v1(304.63,88.11) ; CR17.1 32.43,44.13 31.6,43.3 v1(31.12,43.3) ; PC1005.2 119.71,58.82 v1(119.24,58.82) ; PC1043.2 103.75,65.52 v1(104.17,65.94) ; v1(104.41,59.81) 103.99,59.81 PC1134.2 ; v1(104.45,63.99) 104.49,63.99 104.5,63.97 104.52,63.97 104.81,63.68 PC1019.2 ; v1(104.45,57.26) 104.19,57.26 103.82,57.63 PC1137.2 ; QN4.1 209.1,35.72 v1(209.56,35.26) 209.55,34.82 209.95,34.42 QN4.4 ; v1(110.75,56.01) 110.86,56.12 PC1083.2 110.86,57.16 PC1035.2 ; CZ66.2 220.3,18.51 CZ71.2 219.18,18.71 CZ61.2 ; CL21.2 292.74,94.13 v1(293.12,94.51) ; PC1055.2 101.68,60.94 101.68,60.4 v1(101.71,60.37) 101.77,60.42 PC1048.2 ; v1(305.44,69.54) 305.76,69.23 CE3.2 ; CD57.2 169.45,5.61 v1(169.03,6.03) ; v1(288.65,70.27) 288.3,69.92 CE12.2 ; CC217.2 125.01,58.85 v1(125.04,58.89) ; v1(106.51,55.81) 106.51,55.42 PC1136.2 ; PC1079.2 117.73,61.2 v1(117.73,61.5) ; v1(288.83,27.35) 289.23,27.35 CN61.2 ; PQ1207.1 30.49,36.81 30.49,38.25 29.98,38.75 v1(29.98,39.01) ; v1(128.38,57.15) 128.38,57.28 127.72,57.93 CC207.2 ; v1(117.2,105.4) 116.76,104.96 CV39.2 ; v1(28.98,35.6) PQ1207.4 28.9,34.62 PQ1210.1 ; v1(270.9,50.82) 270.91,50.84 272,50.84 272.55,50.29 CZ120.2 ; v1(115.12,61.54) 115.11,61.53 115.11,61.01 PC1069.2 ; v1(107.17,60.77) 107.17,60.39 107.46,60.1 PC1021.2 ; CL16.2 302.28,93.27 v1(302.44,93.44) ; CZ115.2 206.16,3.5 v1(206.3,3.64) ; PC680.2 59.08,67.72 v1(59.2,67.84) ; v1(289.31,76.34) 289.31,76.95 CE11.2 ; CI3.2 v1(20.89,79.66) ; PU1200.3 v1(17.49,35.74) ; RE93.2 286.52,75.84 286.5,75.82 v1(286.45,75.82) ; v1(115.03,59.11) 114.93,59.01 PC1082.2 ; PC1025.2 107.44,62.72 107.18,62.98 v1(107.18,63.11) ; PC1075.2 111.64,56.11 v1(111.43,55.9) 111.24,55.7 111.24,55.43 110.97,55.16 CC297.2 ; v1(204.17,10.27) 203.85,9.95 CZ112.2 ; v1(111.71,58.68) 111.67,58.68 111.64,58.65 PC1064.2 ; v1(219.84,37.24) 219.84,36.8 219.64,36.59 RN188.2 ; v1(274.76,78.96) 274.45,79.27 CL8.2 ; CC314.2 132.45,59.7 v1(132.45,59.14) ; v1(302.07,94.67) 302.07,94.88 301.77,95.18 301.77,96.66 302.17,97.06 303.45,97.06 303.72,96.79 CL19.2 ; v1(287.48,87.8) 287.43,87.85 286.82,87.85 286.39,88.28 CL13.2 ; PC1130.2 109.8,56.09 v1(109.38,56.09) ; v1(118.74,66) 119.14,65.6 PC1031.2 ; v1(118.74,66) 118.29,65.56 PC1033.2 ; PC1003.2 113.92,61.9 v1(113.92,61.49) ; v1(32.45,86.38) 32.53,86.3 RT100.2 ; CA45.2 299.56,41.46 CA46.2 298.62,41.97 CA47.2 ; v1(278.07,50.18) 278.63,49.62 UZ10.3 ; CD37.2 169.46,13.86 v1(169.07,14.24) ; v1(19.56,99.21) 19.56,98.66 CT119.2 ; CI46.2 v1(19.24,79.81) ; PQ1204.1 v1(13.35,34.05) ; CE62.2 299.09,66.3 v1(299.6,66.8) CE23.2 ; PR428.2 134.82,113.18 v1(135.26,112.73) 134.82,112.29 PC420.2 ; PC1135.2 109.72,55.49 v1(109.38,55.49) ; PC1012.2 119.72,57.36 119.47,57.11 119.31,57.11 v1(119.24,57.04) 119.24,56.58 PC1095.2 119.13,55.9 PC1053.2 119.59,55.9 CC251.2 CC250.2 121.64,56.19 PC1139.2 121.69,55.6 v1(121.95,55.34) ; v1(109.25,60.44) 109.28,60.44 109.63,60.1 PC1015.2 ; PC1073.2 117.73,56.47 v1(117.73,56.74) ; CA7.2 112.48,93.12 v1(112.44,93.15) ; CE8.2 308.8,84.16 v3(309.6,84.95) v1(310,85.36) ; v1(309.25,78.89) 308.38,78.89 CE19.2 308.24,78.16 CE20.2 ; CI19.2 309.03,63.9 v1(308.84,64.09) ; CE22.2 v1(311.09,71.71) ; CC208.2 126.67,59.08 127.06,59.47 v1(127.06,59.67) ; PQ1214.4 v1(12.69,35.72) ; CN17.2 272.25,61.63 273.15,60.74 v1(273.69,60.74) ; v1(104,55.85) 104,55.4 PC1133.2 ; RD29.2 170.46,5.75 v1(170.03,6.19) ; CR19.1 v1(6.74,59.26) ; CC212.2 v1(149.26,59.58) ; v1(282.25,52.8) 282.73,52.8 283.1,53.17 CV101.2 CV102.2 ; CI31.2 CI37.2 304.02,62.22 304.02,62.41 v1(303.97,62.45) ; PC1065.2 111.11,61.19 111.42,60.88 111.71,60.88 v1(111.74,60.86) ; PC1074.2 117.76,58.79 v1(117.76,59.17) ; v1(116.34,61.52) 116.34,62 PC1078.2 ; DI4.3 310.17,53.87 v1(310.39,53.65) ; v1(20.67,71.13) 20.43,71.38 DI1.3 v1(17.93,71.38) ; CZ64.2 v1(221.65,14.17) ; CZ53.2 163.53,35.48 v1(163.63,35.37) ; v1(281.21,44.93) 281.21,45 280.83,45.38 CZ93.2 ; v1(107.14,58.24) 107.14,57.9 PC1014.2 ; PC1027.2 107.09,55.42 v1(107.09,55.81) ; PQ1201.1 v1(14.95,35.41) ; v1(55.39,28.45) 55.33,28.39 RC136.2 CC308.2 ; PQ1210.4 30.97,32.34 31.63,31.67 v1(31.63,31.42) ; v1(274.96,74.44) 276.48,74.44 276.95,73.97 CZ125.2 ; PC1044.2 101.98,63.77 v1(101.69,64.05) ; v1(106.53,60.77) 106.53,60.65 106.22,60.34 PC1132.2 ; v1(113.79,56.75) 113.79,57.27 PC1007.2 ; PQ1208.1 27.78,37.58 28.3,38.09 28.3,39.11 v1(28.45,39.26) ; v1(282.2,64.53) 282.2,65.05 281.82,65.44 CN16.2 ; v1(120.66,64.54) 121.1,64.09 PC1059.2 ; v1(101.06,62.2) 100.99,62.13 100.99,61.71 PC1047.2 ; CI7.2 v1(26.42,76.66) ; CC199.2 120.48,65.86 v1(120.65,66.03) 120.78,66.16 PC1152.2 ; v1(281.34,37.38) 281.18,37.54 QN1.1 ; CZ75.2 171.11,40.35 CZ50.2 v1(169.93,40.06) ; PQ1.1 v1(59.38,106.12) ; v1(114.99,56.76) 114.99,56.2 PC1077.2 ; PC410.2 v1(146.28,111.42) ; v1(112.16,42.89) 112.21,42.84 CC177.2 ; CV81.2 93.83,90.77 CV83.2 v1(93.35,90.44) ; PQ1204.4 v1(15.25,31.51) ; PC1088.2 121.99,67.91 122.15,68.07 ; PQ1201.4 v1(16.25,35.85) ; UZ34.3 v1(130.02,28.8) ; CN20.2 260.38,50.48 259.96,50.89 CN21.2 ; v1(104.42,61.13) 104.57,61.27 PC1131.2 ; PC1028.2 108.64,63.51 108.47,63.34 v1(108.47,63.08) ; CE21.2 308.77,75.54 v1(309.4,75.54) ; CA31.2 295.41,39.05 CA10.2 ; PC1149.2 123.91,62.91 PC1147.2 123.99,63.02 v1(125.11,63.02) ; PC1006.2 111.33,59.94 111.61,60.22 v1(111.75,60.22) ; CC252.2 119,52.61 v1(118.8,52.41) ; DI6.3 v1(81.41,105.1) ; CV85.2 100.72,88.54 100.07,87.89 RV97.2 ; CC176.2 115.7,40.9 v1(116.09,40.9) ; PC1049.2 100.7,63.74 v1(100.39,64.05) ; CZ54.2 v1(166.31,42.69) ; PC1050.2 113.09,65.63 PC1034.2 112.77,65.64 v1(112.42,65.98) ; v1(104.43,62.45) 104.41,62.47 PC1020.2 ; QN5.4 v1(221.94,36.52) ; PR427.2 v1(146.28,110.53) ; v1(82.48,70.73) 82.48,70.42 PC1067.2 ; PC1022.2 104.61,55.45 v1(104.61,55.82) ; PC1148.2 122.15,68.07 ; 122.15,68.07 v1(122.34,68.26) ; v1(101.33,65.94) 101.33,65 PC1023.2 ; CL17.2 298.58,94.13 v1(298.2,94.51) ; v1(106.52,58.27) 106.52,57.82 PC1026.2 ; RC1.2 131.37,62.68 131.82,63.12 v1(131.82,63.28) ; v1(102.97,57.86) 102.95,57.84 PC1129.2 101.9,57.64 v1(101.18,57.64) 100.92,57.37 PC1045.2 100.02,57.37 v1(99.78,57.62) 99.76,57.6 v1(98.46,57.6) ; PC1018.2 109.69,58.47 v1(109.34,58.47) ; PC1138.2 v1(104.41,58.85) ; CC214.2 v1(139.2,38.51) ; CR4.2 26.49,55.21 v1(26.07,54.78) 25.8,54.51 CR6.2 ; CL15.2 270.35,89.97 v1(270.01,90.32) ; PC1016.2 109.69,61.32 109.39,61.03 v1(109.2,61.03) ; v1(272.67,91.28) UL2.3 ; v1(106.59,63.11) 106.54,63.11 106.24,62.81 PC1024.2 ; v1(109.36,57.86) 109.8,57.86 PC1017.2 ; CT120.2 CT118.2 20.58,92 v1(21.21,92.64) ; UE3.3 v1(306.06,93.89) ; PQ1214.1 v1(11.39,35.28) ; QN5.1 v1(223.39,33.72) ; CZ128.2 v1(272.29,74.14)
  TOP w0.457: v1(102.34,67.21) 102.29,67.27 RC114.2 ; CT74.2 32.21,86.38 v1(32.45,86.38) ; v1(31.63,31.42) 31.73,31.32 PC1217.2 ; CD41.2 166.46,7.97 v1(166.26,7.78) ; CI6.2 26.55,75.39 26.99,74.95 v1(27.63,74.95) 27.89,74.68 CT85.2 ; v1(267.49,53.15) 267.34,53.31 266.81,53.31 266.32,52.82 RN174.2 ; RN53.2 v1(263.66,52.79) ; RA45.2 297.69,27.96 v1(297.25,27.51) 296.8,27.96 CA62.2 ; v1(139.96,41.17) 139.71,41.42 CC316.2 ; RN176.2 v1(262.64,52.53) RN179.2 ; PC927.2 18.01,23.3 v1(17.66,23.65) ; RN60.2 295.36,51.45 295.46,51.56 v1(296.22,51.56) ; CC307.2 66.93,39.74 v1(67.21,40.02) 66.5,40.02 65.88,40.64 RC219.2
  TOP w0.508: CC32.2 64.48,26.08 v1(64.9,26.08) CC28.2 ; v1(11.56,12.65) 11.18,13.04 PQ1216.3 ; v1(73.1,45.49) 73.42,45.81 PR608.2 ; RC3.2 129.82,79.14 v1(129.38,79.58) ; CE29.2 291.88,73.61 v1(291.66,73.61) ; v1(311.11,67.34) RE313.2 ; v1(305.34,48.25) 305.78,48.7 RI56.2 ; RA52.1 CA61.2 291.62,39.92 291.02,39.32 v1(291.02,38.88) ; CD14.2 62.25,5.81 v1(62.52,6.09) ; v1(269.4,45.26) 269.17,45.48 RN40.2 RN54.2 ; v1(126.53,6.11) 126.26,5.85 CD45.2 ; v1(57.27,14.29) 57.55,14.01 CD15.2 ; PR8.1 58.39,88.89 PQ3.3 58.84,88.35 58.5,88.01 v1(58.03,88.01) ; DE1.2 265.79,37.91 v1(265.08,37.91) ; RN30.2 RN41.2 ; RN30.2 RN52.2 ; RN30.2 v1(263.91,41.47) ; JUSH1.27 227.72,21.97 v1(227.97,21.72) ; YL1.2 287.51,90.9 v1(286.29,90.9) ; v1(269.54,35.13) 269.92,35.51 JSPK1.6 v1(269.92,37.31) ; v1(40.23,88.82) 40.37,88.68 CT84.2 ; v1(53.94,6.03) 54.01,5.97 CD5.2 ; v1(38.99,84.28) 38.68,84.6 CT72.2 ; CV100.2 282.26,58.36 v1(282.44,58.36) ; QE2.1 298.22,62.36 298.07,62.5 CE54.2 298.35,62.93 v1(298.73,63.31) ; CD24.2 107.78,3.46 v1(107.66,3.34) 106.88,2.56 CD22.2 ; v1(71.07,58.31) 71.3,58.08 PR631.1 71.3,57.39 PC621.1 ; RD31.2 v1(174.46,2.29) ; SW3.1 v1(323.81,92.65) ; v1(23.37,89.17) 23.04,88.84 RT130.2 ; v1(319.03,91.34) 319.03,91.73 SW3.3 317.68,92.65 v1(317,91.97) ; CA49.2 305.57,39.96 v1(305.57,39.39) ; DI5.1 v1(310.06,50.82) ; DA1.1 312.3,35.07 v1(312.98,35.76) ; CZ61.2 219.14,18.09 v1(218.93,17.87) ; RA51.2 298.71,27.61 v1(298.84,27.48) 299.32,27.48 CA72.2 ; v1(54.74,37.36) CC306.2 ; CZ84.2 215.91,11.96 v1(216.46,12.51) ; CC224.2 131.73,56.92 v1(131.82,57.01) ; v1(309.54,67.36) 309.29,67.61 CE4.2 ; v1(209.99,9.62) 209.99,10.59 JKBTP1.22 ; RN185.2 226.58,32.78 v1(226.94,32.43) ; CV96.2 96.35,100.88 v1(96.92,100.31) ; RD21.2 v1(187.08,1.6) ; v1(64.66,104.21) 64.47,104.21 PQ7.3 ; v1(304.6,50.59) 304.6,50.42 304.93,50.09 304.93,49.83 CZ24.2 CZ23.2 CZ21.2 ; PC1208.2 v1(13.4,84.14) ; v1(70.07,6.03) 69.95,5.91 CD11.2 ; v1(285.61,80.78) 285.3,80.47 RE537.1 ; RL13.2 CL14.2 v1(284.36,91.08) ; PC111.2 v1(152.1,109.06) ; QN1.4 279.28,41.1 v1(278.9,41.48) ; v1(225.91,3.57) 225.91,4.39 JUSH1.28 226.67,4.5 v1(226.67,3.6) ; DA7.1 285.15,34.31 v1(285.26,34.42) ; RZ155.2 v1(282.2,62.25) ; RC89.2 131.96,41.58 v1(132.46,41.08) ; RC89.2 RC5.2 RC7.2 ; RC89.2 RC88.2 RC311.2 ; RN183.2 v1(211.71,32.4) ; CD34.2 156.95,14.49 v1(156.81,14.36) ; PQ909.3 33.52,29.85 v1(33.28,29.61) ; v1(293.34,67.76) 293.43,67.67 QZ8.3 ; v1(164.47,34.59) 164.47,33.72 RZ62.2 ; v1(81.83,3.53) 81.83,4.23 CD25.2 CD26.2 ; CC279.2 CC280.2 v1(136.53,42.12) ; CZ85.2 CZ86.2 216.63,15.95 216.63,16 216.63,16 v1(216.63,16.29) ; PR925.2 30.91,29.63 v1(30.61,29.33) ; v1(311.28,47.77) 310.77,47.77 309.86,46.86 CI43.2 CI44.2 ; CC203.2 128.96,63.79 v1(129.03,63.86) ; v1(141.43,6.03) 141.15,5.76 141.15,4.91 140.54,4.3 CD61.2 ; v1(108.15,7.27) 108.15,6.42 CD23.2 ; v1(115.89,106.57) 115.42,106.57 UV2.2 ; PC605.1 74.83,52.61 75.27,53.05 75.27,53.9 v1(74.96,54.21) ; v1(129.78,41.27) 129.93,41.41 RC7.2 ; CD2.2 79.34,11.54 v1(79.25,11.45) ; v1(113.39,101.34) 112.8,100.74 QV4.3 ; CC178.2 119.51,39.41 v1(119.56,39.46) ; v1(310.14,91.31) 309.33,91.31 309.12,91.51 CE53.2 ; v1(26.24,89.67) RT301.2 RT300.2 ; v1(189.75,8.12) 190.38,8.75 CD53.2 189.88,10.16 CD51.2 ; v1(139.45,84.85) 139.2,84.6 CC216.2 ; v1(271.05,45.99) CA65.2 CA66.2 ; v1(135.03,6.11) 135.03,5.65 CD44.2 ; CZ87.2 215.73,17.37 CZ83.2 215.93,17.4 216.27,17.06 v1(216.54,17.06) ; CN31.2 295.18,59.16 295.69,59.67 v1(295.9,59.67) 296.26,60.03 QE2.4 ; v1(123.2,79.52) 123.35,79.68 CC202.2 ; v1(278.01,78.4) 278.28,78.67 CE5.2 ; CD9.2 101.99,8.5 v1(102.01,8.48) ; CD3.2 74.14,6.16 v1(74.39,6.41) ; v1(103.88,85.01) 104.47,85.6 RV88.2 ; v1(140.28,11.61) 140.03,11.85 CD39.2 ; PR506.2 122.36,111.21 v1(122.5,111.34) ; CN64.2 CN63.2 292.61,29.04 RA37.2 v1(293.55,28.38) ; RT305.2 RT136.2 v1(20.45,101.43) ; RD16.2 RD18.2 v1(86.7,2.51) ; CD29.2 64.97,5.62 65.25,5.9 v1(65.25,6.08) ; PC2.1 v1(63.99,78.98) ; v1(304.21,85.51) 303.6,86.12 CE40.2 303.54,86.15 CE61.2 ; v1(149.93,16.78) 149.93,16.46 CD38.2 ; PR1210.2 v1(13.65,36.95) ; CC265.2 128.05,56.57 128.38,56.89 v1(128.38,57.15) ; PC3.2 v1(58.39,79.78) ; v1(121.39,39.65) 121.28,39.65 120.78,40.15 CC296.2 ; v1(299.72,88.91) 299.73,88.91 JTAG1.2 299.34,88.11 298.98,87.74 298.98,86.28 RE65.2 299.26,85.86 300.09,85.02 CE30.2 ; RT99.2 33.72,74.63 v1(34.17,74.19) 34.61,74.63 RT86.2 ; CI45.2 v1(20.13,80) ; PR608.2 74.44,45.18 PC644.2 ; PR608.2 73.41,46.21 PR611.2 ; RZ10.1 219.89,20.59 v1(219.54,20.95) ; CE32.2 265.09,39.08 264.42,38.42 v1(264.42,37.97) ; RN38.2 258.35,44.19 v1(258,44.19) ; v1(190.09,2.42) PR516.2 ; CR15.2 v1(20.1,47.77) ; v1(286.45,75.82) 286.45,74.93 QE12.3 ; v1(278.07,50.18) 278.07,51.18 RV123.1 ; v1(149.9,71.17) 149.47,71.17 CC219.2 148.96,70.63 149.13,70.46 v1(149.78,70.46) ; PC931.1 11.33,20.45 v1(11.05,20.72) ; v1(296.36,38.59) 296.03,38.92 296.03,39.28 CA31.2 ; CZ55.2 170.36,43.33 v1(170.82,43.78) ; DA6.1 v1(285.44,29.74) ; CD1.2 65.63,11.87 v1(65.79,11.7) ; CD36.2 CD33.2 155.58,14.49 v1(156.11,15.02) ; RL12.2 v1(271.2,85.11) ; v1(33.53,88.28) RT63.2 ; 314.26,61.36 v1(315.68,61.36) ; v1(8.64,59.39) 7.82,59.39 CR20.1 ; CZ102.2 127.59,25.39 128.44,24.54 129.26,24.54 129.97,25.25 129.97,26.27 CZ104.2 129.88,28.66 v1(130.02,28.8) ; v1(21.21,96.88) 21.25,96.84 CT117.2 ; 66.3,68.6 v1(66.3,67.71) ; v1(105.74,2.06) 105.67,2.13 RD7.2 ; v1(149.33,74.08) 148.93,74.48 CC218.2 ; RC220.2 131.06,35.43 CC266.2 130.18,34.97 v1(130.46,34.69) ; CD35.2 145.83,15.03 v1(145.83,14.29) ; CD43.2 179.98,11.84 v1(179.78,11.63) ; PC1178.2 88.47,57.19 v1(88.49,57.22) ; RE95.1 313.13,78.25 313.06,78.33 v1(312.81,78.33) ; RL9.2 281.31,79.29 v1(281.69,78.91) ; v1(149.84,69.16) 149.37,69.16 149.29,69.23 CC264.2 ; PC1204.2 v1(16.01,56.77) ; CD54.2 v1(190.12,4.39) ; v1(68.55,6.16) 68.29,5.91 CD4.2 ; v1(289.96,47.62) 289.96,47.6 289.4,47.6 JLED1.8 289,48.26 289.65,48.91 290.96,48.91 291.47,49.42 CZ198.2 ; CA56.2 293.12,34.34 292.78,34.68 v1(292.78,34.78) ; v1(271.02,54.12) 271.61,53.54 CZ197.2 ; CA59.2 v1(311.47,26.94) ; v1(107.29,90.4) 107.83,89.86 RV84.2 ; CT73.2 v1(25.9,85.55) ; CD10.2 71.49,12.43 CD12.2 71.52,12.45 72.01,11.96 72.01,10.89 71.51,10.38 v1(71.27,10.38) ; v1(30.04,74.41) RT103.2 ; CC205.2 125.46,56.29 PC1140.2 125.45,55.78 v1(125.76,55.47) ; CZ134.2 282.38,67.46 v1(282.33,67.46) ; v1(191.5,13.24) 190.75,13.24 CD52.2 ; CD13.2 87.44,7.56 v1(88.04,7.56) ; v1(278.97,75.89) 279.41,75.89 CE6.2 ; RN39.2 259.85,42.04 259.34,41.53 v1(258.97,41.53) ; RZ38.1 189.06,13.99 189.21,13.84 CD50.2 188.97,13.2 v1(188.56,12.79) ; v1(99.57,87.2) 99.87,87.5 99.87,87.8 RV97.2 ; RV96.2 91.95,87.22 v1(91.87,87.14) ; v1(293.5,71.14) 293.5,70.75 292.98,70.24 CE28.2 293.1,69.77 293.1,69.27 293.6,68.76 RE55.2 293.8,68.75 RE58.2 ; CZ41.2 v1(126.67,101.75) ; RN72.2 v1(296.04,56.28) ; v1(15.33,55.39) 15.74,54.97 PC1214.2 16.18,54.72 PQ1209.4 ; RC7.2 RC6.2 128.94,41.89 128.94,41.04 ; CV132.2 318.88,75.44 318.88,75.44 v1(320.57,75.44) ; UZ6.3 138.72,27.73 v1(140.47,29.48) ; v1(19.99,51.83) CR22.2 20.71,51.88 CR21.2 ; RI36.1 v1(304.3,54.37) ; CE31.2 302.86,67.9 RE56.2 302.83,67.25 RE342.2 v1(303.09,66.09) ; PC11.2 75.23,100.38 75.6,100.02 v1(75.6,99.51) ; PC946.2 24.29,12.07 v1(23.75,11.53) ; RI35.1 296.59,53.61 296.02,54.18 v1(296.02,54.23) 295.61,54.23 295.53,54.31 RN62.2 RN31.2 ; PC1076.2 113.79,59.63 v1(113.79,59.14) ; v1(276.41,70.63) 275.95,70.17 CZ126.2 CZ127.2 ; v1(298.11,67.91) 298.28,68.08 RE20.2 ; RI45.2 RI58.2 RI43.2 302.07,48.72 v1(302.54,48.25) ; v1(93.4,87.14) 93.86,87.6 RV94.2 ; RD5.2 v1(101.89,3.05) ; PC10.2 v1(75.69,104.73) ; v1(267.69,26.91) 267.84,26.76 JSPK1.5 272.08,26.76 v1(272.2,26.87) ; v1(176.53,6.03) 176.28,5.79 CD48.2 ; CE503.2 292.7,85.18 293.29,84.6 v1(293.29,84.42) ; PC1209.2 PR1227.2 v1(16.01,84.19) ; v1(17.07,9.77) 17.28,9.98 PC944.2 17.27,10.64 PC943.2 ; CD59.2 v1(186.57,14.22) ; CZ113.2 CZ114.2 207.56,6.83 207.92,6.47 v1(207.92,5.45) ; v1(96.72,87.19) 96.72,87.89 RV92.2 RV90.2 ; PR681.2 62.95,75.08 v1(63.51,75.08) ; v1(135.06,87.06) 135.06,86.26 CC221.2 134.9,86.21 134.35,86.77 v1(134.35,87.06) ; CZ80.2 218.14,26.18 v1(218.17,26.15) ; v1(127.26,37.6) 127.73,37.6 CC331.2 ; CE59.2 CE60.2 313.67,72.84 v1(313.19,72.84) ; v1(289.31,76.34) CE14.2 ; PD2.1 v1(21.04,3.49) ; CI33.2 305.69,57.11 v1(305.25,56.67) ; RT304.2 15.25,96.97 v1(14.99,96.72) ; CZ73.2 v1(218.66,13.48) ; RT96.2 v1(30.05,86.7) ; CE10.2 284.87,71.29 284.54,71.62 v1(284.54,72.2) CE36.2 ; CV82.2 101.35,85.08 101.85,85.58 v1(102.01,85.58) ; PC942.2 24.9,15.5 v1(25.26,15.86) ; RT140.2 27.7,94.51 v1(27.9,94.7) ; RT144.2 15.47,97.99 14.97,98.49 v1(14.26,98.49) ; CZ58.2 CZ57.2 182.33,31.29 v1(182.58,31.03) ; RZ111.2 172.97,37.93 v1(173.17,37.72) ; DI2.1 v1(24.94,72.07) ; CD20.2 CD21.2 106.89,11.81 CD18.2 CD19.2 105.76,11.82 105.25,12.33 104.44,12.33 v1(103.78,11.67) ; RV78.2 93.45,98.76 v1(93,98.31) ; v1(195.39,15.28) 195.85,15.74 CZ118.2 CZ117.2 ; v1(129.78,14.32) 128.93,13.48 CD46.2 127.57,13.48 CD40.2 ; CZ69.2 218.81,15.12 v1(218.79,15.12) CZ72.2 ; v1(60.55,11.62) 59.95,12.22 CD8.2 ; PC926.2 v1(15.35,23.65) ; v1(310.52,41.93) 310.52,39.92 DA3.1 ; PC937.1 v1(28.2,8.65) ; UE7.2 285.48,76.73 v1(285.53,76.68) ; v1(155.45,59.4) 155.58,59.53 RC316.2 ; v1(148.72,38.25) RC268.2 ; PR24.2 62.18,106.42 v1(61.71,105.95) ; v1(128.44,32.5) CC215.2 127.5,32.49 CC332.2 ; v1(47.78,11.7) 47.47,12.01 CD16.2 ; YL1.4 v1(289.14,87.89) ; v1(152.27,61.87) 152.12,61.87 152.06,61.81 v3(151.26,61.81) 150.89,61.81 150.12,61.04 RC96.2 ; CZ29.2 CZ36.2 v1(216.65,4.39) ; RV86.2 v1(106.81,87.27) ; v1(109.38,89.67) 109.35,89.65 RV82.2 ; v1(296.73,44.9) 296.89,44.73 297.44,44.73 ; CR18.1 31.63,47.2 31.37,46.94 v1(30.93,46.94) ; PC1.2 v1(22.61,5.73) ; CC27.2 125.18,35.51 RC411.2 125.06,35.4 v1(125.06,34.84) 125.35,34.55 CC324.2 ; CL18.2 v1(275.91,104.03) ; 64.65,74.31 v1(63.51,74.31) ; v1(72.23,6.54) 71.72,6.03 CD7.2 ; PR514.2 197.61,2.19 PC513.2 v1(196.91,2.2) ; CD56.2 v1(187.84,4.45) ; v1(24.2,77.55) CT86.2 ; CE16.2 306.91,65.85 v1(306.17,65.85) ; CD47.2 138.89,11.88 v1(139.28,11.5) ; RV75.2 v1(109.56,94.16) ; v1(170.56,2.24) 170.31,2.49 RD25.2 ; CN21.2 259.96,52.1 v1(259.47,52.6) ; v1(57.81,91.98) 57.81,92.25 PQ6.3 ; v1(139.2,38.51) 139.74,38.51 RC349.2 ; PC950.1 20.08,11.49 PR948.2 20.07,10.78 v1(19.98,10.69) 19.34,10.05 PC947.2 ; v1(109.53,41.39) 110.39,41.39 CC294.2 ; CR5.2 v1(24.01,56.58) ; RD9.2 88.52,5.74 v1(87.99,6.27) ; JKBTP1.21 v1(209.75,26.21) ; CA53.2 v1(293.44,36.02) ; v1(59.26,69.63) 59.14,69.51 PC660.2 57.93,69.49 PC659.2 ; CC325.2 125.72,61.32 v1(125.72,60.48) ; CT82.2 v1(37.85,76.15) ; PC116.2 162.98,118.89 v1(162.41,118.89) ; v1(135.13,38.25) 134.75,38.63 CC24.2 RC48.2 133.73,38.85 RC75.2 ; v1(69.33,112.85) 69.06,112.58 PR1249.2 68.98,112.1 PR1219.2 68.97,111.26 PC1206.2 68.97,109.65 PQ1212.3 v1(69.56,108.2) ; v1(271.53,80.17) CA68.2 CA67.2 ; CD55.2 v1(188.85,4.41) ; PR927.2 v1(35.14,30.7) ; v1(290.16,38.02) 290.81,38.02 CA54.2 CA33.2 ; CC269.2 CC307.2 ; PC1211.2 v1(67.45,107.71) ; CC213.2 127.97,55.36 128.09,55.48 v1(128.38,55.48) ; v1(298.96,43.33) 298.96,42.31 CA46.2 ; RT302.2 RT138.2 26.66,98.57 v1(26.93,98.84) ; PC938.2 PR930.2 12.29,11.56 v1(11.72,10.99) ; PD1.1 v1(18.21,2.78) ; CC295.2 120.58,38.44 v1(121.39,38.44) ; PC940.2 v1(17.71,29.99) ; JUSB1.7 v1(313.62,49.85) ; v1(38.99,77.23) RT65.2 RT64.2 ; CI38.2 v1(297.72,51.76) ; RD23.2 v1(188.09,1.61) ; RC337.2 v1(152.67,35.88) ; CV133.2 v1(317.63,77.06) ; CZ68.2 v1(218.74,12.72) ; PC603.2 76.32,47.4 v1(76.32,47.17) ; CE47.2 301.83,90.09 301.83,90.5 v1(302.04,90.71) ; CC209.2 149,57.35 148.49,56.84 148.29,56.84 v1(147.83,56.38) ; v1(171.4,14.42) 171.33,14.34 CD42.2 ; PC1164.2 114.76,65.56 v1(115.14,65.94) ; PC645.2 v1(59.33,46.09) ; JUSB2.7 v1(15.19,74.4) ; PR953.2 v1(24.24,29.05) ; JCRT1.6 321.71,84.77 321.71,84.77 v1(321.39,85.08) ; v1(281.2,48.1) 281.3,48 JLED1.7 ; PR1222.2 v1(15.22,39.29) ; PC647.1 v1(60.15,54.45) ; CR26.2 v1(19.91,42.17) ; CR25.2 v1(22.67,42.17) ; RC338.2 v1(150.75,38.25) ; RT306.2 v1(27.23,93.49) ; CD6.2 v1(76.37,12.19) ; DA2.1 v1(310.58,31.01) ; RZ25.2 v1(268.2,77.1) ; CE52.2 v1(304.47,90.56)
  BOTTOM w0.102: UC1.F35 117.45,66.34 117.8,66.69 117.8,67.19 UC1.D34 ; UC1.B34 116.97,69.04 116.97,69.78 116.36,70.39 116.34,70.39 ; v1(114.97,68.21) 115.09,68.09 115.58,68.09 116.08,67.59 116.08,66.73 116.47,66.34 UC1.F37 ; 115.38,70.59 115.38,70.15 115.12,69.89 115.12,69.07 UC1.B39 ; v1(85.98,81.93) v3(85.98,83.08)
  BOTTOM w0.127: v1(195.41,44.32) 195.99,44.32 v3(196.47,43.83) ; UC1.AN58 105.08,52.8 105.4,53.12 106.06,53.12 106.39,53.45 UC1.AM55 ; v1(281.49,42.36) 281.49,42.66 280.97,43.18 278.43,43.18 277.24,44.37 276.61,44.37 ; CZ124.2 275.74,47.39 275.18,47.95 271.92,47.95 v1(269.62,50.25) 269.25,50.61 268.51,50.61 267.11,49.22 JFAN1.5 267.62,47.8 269.83,47.8 270.34,47.28 274.76,47.28 275.14,46.9 CN3.2 ; v3(311.92,78.89) 312.25,78.89 v1(312.81,78.33) ; v1(93.35,90.44) 93.35,87.19 v1(93.4,87.14) 93.67,86.87 93.67,86.51 94.48,85.69 v1(94.57,85.69) 94.92,85.34 v1(95.31,85.34) 96.37,85.34 96.72,85.68 v1(96.72,87.19) ; v1(170.82,43.78) 170.82,44.47 v3(171.07,44.72) ; v1(281.21,44.93) 281.21,44.23 280.83,43.85 278.71,43.85 277.27,45.29 v1(277.27,45.87)
  BOTTOM w0.178: v1(96.07,53.19) 96.13,53.24 96.88,53.24 UC1.AM71 ; UC1.BB55 106.21,47.02 106.21,46.54 v1(106.25,46.5) ; UC1.BB60 103.61,46.54 v1(103.57,46.5) ; UC1.BB64 101.26,46.88 101.26,46.5 v1(101.26,46.5) ; UC1.BB26 123.31,47.01 123.31,46.5 v1(123.37,46.45) ; UC1.BB38 115.99,47.4 115.99,46.45 v1(116.02,46.43) ; v1(96.06,50.89) 96.24,50.89 UC1.AT71 ; UC1.BB34 118.33,47.14 118.33,45.83 v1(118.36,45.8) ; v1(95.87,55.78) 95.99,55.9 96.67,55.9 UC1.AG71 ; UC1.BB18 127.06,46.52 v1(127.09,46.49) ; v1(96.2,65.39) 96.3,65.5 UC1.H71 ; v1(113.35,46.46) 113.38,46.48 UC1.BB43 ; UC1.BB30 120.96,46.76 120.96,46.37 v1(121.09,46.24)
  BOTTOM w0.203: UC1.D48 109.88,67.76 UC1.D47 ; v1(99.6,49.23) 99.79,49.23 UC1.AW66 100.14,49.41 101.11,49.41 UC1.AW64 101.64,49.36 101.67,49.39 101.97,49.39 102,49.36 UC1.AW62 102.87,49.36 102.9,49.39 103.19,49.39 103.22,49.36 UC1.AW60 104.1,49.36 104.13,49.39 104.42,49.39 104.45,49.36 UC1.AW57 105.37,49.36 105.4,49.39 105.7,49.39 105.73,49.36 UC1.AW55 106.6,49.36 106.63,49.39 106.92,49.39 106.95,49.36 UC1.AW53 107.82,49.36 107.85,49.39 108.15,49.39 108.18,49.36 UC1.AW51 108.99,49.36 109.02,49.39 109.31,49.39 109.34,49.36 UC1.AW49 110.25,49.36 110.28,49.39 110.57,49.39 110.6,49.36 UC1.AW47 111.41,49.36 111.44,49.39 111.74,49.39 111.77,49.36 UC1.AW45 112.64,49.36 112.69,49.41 112.84,49.41 112.86,49.39 112.92,49.39 112.92,49.4 112.93,49.39 112.96,49.39 112.99,49.36 113.48,49.36 UC1.AW43 ; v1(99.6,49.23) UC1.AY66 UC1.BA66 ; v1(99.6,49.23) 99.15,49.69 UC1.AV68 ; v1(122.29,64.32) 122.46,64.49 UC1.J25 ; v1(46.44,44.1) 46.02,44.52 46.02,46.09 46.01,46.1 PU200.15 ; v1(121.95,55.34) 122,55.28 UC1.AK27 ; UC1.F38 v1(115.14,65.94) UC1.F40 ; v1(131.6,65.94) UC1.G10 ; UC1.K71 97.13,64.11 96.53,64.11 96.31,63.89 v1(95.99,63.89) ; v1(107.09,55.81) 106.91,55.63 UC1.AL55 ; v1(120.66,64.54) 120.63,64.56 UC1.J28 ; UC1.D44 UC1.D45 111.25,67.76 111.19,67.71 110.57,67.71 UC1.D47 ; UC1.AV1 137.99,49.57 v1(138.12,49.44) ; UC1.AM13 130.26,53.45 130.46,53.66 130.46,53.87 v1(130.51,53.92) 130.54,53.94 131.03,53.94 UC1.AK11 ; UC1.K61 102.32,64.76 UC1.K63 ; UC1.AM68 99.11,52.86 99.14,52.83 99.14,52.53 99.11,52.5 UC1.AP68 99.11,51.63 99.14,51.6 99.14,51.31 99.11,51.28 UC1.AT68 99.11,50.47 99.16,50.3 99.16,50.12 99.11,50.07 99.11,49.7 UC1.AV68 ; UC1.AM68 99.11,53.73 99.2,53.82 99.2,54.09 98.79,54.5 UC1.AK68 98.81,54.57 99.14,54.9 v1(99.17,54.9) 99.17,55.05 99.44,55.31 UC1.AH67 ; UC1.AM68 99.3,53.34 v1(99.6,53.04) ; v1(109.38,55.49) 108.99,55.49 108.74,55.25 UC1.AL52 ; UC1.AL58 105.09,54.96 104.61,55.43 v1(104.61,55.82) ; v1(117.39,68.23) 117.27,68.1 UC1.D34 ; UC1.C1 138.45,68.75 v1(139.04,69.34) ; UC1.AF63 102.14,56.15 102.14,55.44 UC1.AH63 ; UC1.D47 110.51,67.29 v1(110.57,67.24) ; UC1.AD21 125.55,57.68 125.98,57.68 UC1.AD20 ; UC1.AW8 132.74,49.36 132.71,49.39 132.42,49.39 132.39,49.36 UC1.AW10 131.9,49.57 v1(131.6,49.87) 131.1,49.36 UC1.AW12 130.32,49.36 130.29,49.39 130,49.39 129.97,49.36 UC1.AW14 129.37,49.36 128.92,49.81 128.8,49.81 128.35,49.36 UC1.AW16 127.9,49.36 127.87,49.39 127.58,49.39 127.55,49.36 UC1.AW18 126.63,49.36 126.6,49.39 126.3,49.39 126.27,49.36 UC1.AW21 125.48,49.36 125.45,49.39 125.16,49.39 125.13,49.36 UC1.AW23 124.16,49.36 124.13,49.39 123.83,49.39 123.8,49.36 UC1.AW26 122.93,49.36 122.9,49.39 122.6,49.39 122.57,49.36 UC1.AW28 121.7,49.36 121.67,49.39 121.38,49.39 121.35,49.36 UC1.AW30 120.48,49.36 120.45,49.39 120.15,49.39 120.12,49.36 UC1.AW32 119.29,49.36 v1(118.8,49.85) 118.43,49.49 UC1.AW34 117.95,49.36 117.92,49.39 117.62,49.39 117.59,49.36 UC1.AW36 116.72,49.36 116.69,49.39 116.4,49.39 116.37,49.36 UC1.AW38 115.65,49.36 v1(115.14,49.87) ; UC1.BA1 UC1.BA2 ; UC1.F1 137.57,66.87 v1(137.77,67.07) ; v1(45.79,53.41) 45.66,53.28 45.66,50.81 45.56,50.7 PU200.4 ; UC1.AV68 98.83,49.69 v1(98.64,49.5) ; UC1.AL64 101.29,53.55 101.24,53.51 100.86,53.51 100.82,53.55 UC1.AL65 100.65,53.55 100.61,53.51 100.23,53.51 100.18,53.55 UC1.AL66 ; 275.93,44.75 275.93,45.86 275.4,46.38 CN3.2 ; UC1.K70 98.15,64.14 98.3,64.35 ; v1(116.05,54.74) 116.06,54.73 UC1.AL38 ; UC1.AM61 102.89,53.55 103.62,53.55 UC1.AM60 ; UZ2.11 v1(278.07,50.18)
  BOTTOM w0.254: JDIMM1.31 46.78,14.14 v1(46.65,14.26) ; UC1.E50 v1(108.74,67.22) ; UC1.AB15 v1(129.03,58.83) UC1.AB16 ; UC1.AR5 134.8,51.42 134.43,51.13 v1(134.35,51.14) ; UC1.F27 121.91,66.44 121.18,66.44 UC1.F28 120.96,66.34 v1(120.65,66.03) ; v1(128.89,53.69) 128.7,54.22 UC1.AK16 ; UC1.AR28 v1(120.63,51.14) UC1.AT28 ; v1(61.52,6.07) JDIMM1.90 ; UC1.F22 124.55,66.15 124.4,66.15 124.23,65.98 v1(124.23,65.97) ; JNGFF2.5 287.8,42.58 v1(287.37,43.01) 287.37,42.79 287.3,42.73 JNGFF2.3 ; v1(121.63,7.06) 121.53,6.95 JDIMM2.6 ; UC1.D18 127.1,67.8 v1(127.1,68.23) 127.1,68.66 UC1.B18 ; v1(96.78,11.7) JDIMM1.223 ; v1(133.45,51.7) 133.17,51.7 UC1.AR8 ; JDIMM2.106 146.52,6.91 v1(146.39,7.05) ; CN8.2 280.4,35.86 JSATA1.18 ; UC1.BA41 v1(114.68,48.85) UC1.AW41 ; UC1.U10 132.13,60.39 132.32,60.13 132.32,60.1 132.78,59.64 UC1.W9 132.78,59.47 v1(132.45,59.14) ; UC1.AN30 v1(120.63,52.41) UC1.AN28 ; UC1.AP68 v1(98.5,52.07) UC1.AP70 ; JNGFF3.57 293.95,34.47 293.65,34.78 v1(292.78,34.78) ; JDIMM2.98 v1(144.52,6.03) ; JDIMM1.197 90.28,14.15 v1(90.37,14.24) ; v1(48.03,6.03) JDIMM1.36 ; JDIMM2.1 120.28,11.93 v1(119.89,11.55) ; JDIMM2.78 v1(139.52,6.03) ; JNGFF3.39 298.45,33.04 298.65,32.85 299.7,32.85 299.95,33.1 JNGFF3.33 299.95,34.97 v1(299.6,35.32) ; UC1.B62 UC1.D62 102.4,67.27 v1(102.34,67.21) ; 126.6,49.39 126.57,49.42 UC1.AU20 126.47,50.2 v1(126.15,50.53) 126.47,50.85 UC1.AT20 ; v1(145.49,11.6) 145.78,11.89 JDIMM2.103 ; UC1.W6 134.75,59.6 134.79,59.54 135.01,59.16 ; v1(199.83,13.84) 199.91,13.75 JNGFF1.37 ; JEDP1.39 97.3,93.72 v1(97.48,93.9) ; UC1.AU38 v1(115.14,49.87) ; v1(125.2,67.22) UC1.E21 ; UC1.E65 100.66,67.21 100.31,67.21 99.92,67.6 UC1.D66 v1(99.92,68.23) UC1.B66 ; UC1.AT63 v1(101.43,51.14) UC1.AR63 ; v1(142.7,6.01) 142.52,5.83 JDIMM2.90 ; UC1.C25 122.74,68.26 122.34,68.26 ; v1(144.58,6.64) 144.96,6.64 145.52,6.08 JDIMM2.102 ; v1(96.2,67.43) 96.33,67.3 UC1.E71 ; v1(164.82,11.76) 164.78,11.8 JDIMM2.171 ; UC1.AR55 106.46,51.43 106.06,51.11 v1(105.99,51.12) ; JEDP1.15 109.3,93.9 v1(109.56,94.16) ; 116.34,70.39 116.27,70.46 116.27,70.8 v1(117.52,72.05) 117.92,72.45 v1(117.92,74.36) v1(117.92,77.78) 119.19,79.05 119.19,80.36 118.67,80.88 v1(118.35,80.88) 118.49,81.02 118.95,81.02 119.19,81.26 119.19,84.25 118.86,84.57 v1(118.14,84.57) 115.04,84.57 114.77,84.3 114.77,80.96 ; v1(116.97,51.77) UC1.AP35 ; v1(101.06,62.2) 100.74,62.52 UC1.N65 ; 114.77,80.96 114.79,80.97 115.56,80.97 v1(115.66,80.87) ; 114.77,80.96 114.77,78.85 v1(115.4,78.22) 116.17,77.45 v1(116.17,76) 116.17,73.74 115.71,73.28 v1(115.71,72.43) 115.71,71.4 115.38,71.07 115.38,70.59 ; v1(178.53,6.32) JDIMM2.226 ; UC1.AD21 UC1.AB21 125.44,58.49 v1(125.04,58.89) 125.04,58.98 125.31,59.25 UC1.Y21 UC1.Y20 ; v1(131.82,57.01) 131.82,56.72 UC1.AF10 ; 58.27,11.64 JDIMM1.77 ; UC1.AP42 v1(113.32,51.77) UC1.AR43 ; JDIMM2.35 128.78,11.83 v1(129.11,11.49) ; UC1.U70 97.49,60.69 v1(97.81,60.37) 98.14,60.69 UC1.U69 ; v1(134.35,65.94) UC1.G5 ; JDIMM2.36 v1(129.03,6.12) ; v1(118.8,52.41) UC1.AN32 ; v1(49.79,14.9) 49.31,14.9 48.78,14.37 JDIMM1.39 ; UC1.F4 135.68,66.7 v1(135.99,66.7) 136.16,66.87 UC1.F2 ; JDIMM2.94 v1(143.52,6.03) ; v1(105.73,93.9) 105.24,93.9 104.3,92.95 JEDP1.25 ; JDIMM2.218 v1(176.53,6.03) ; v1(40.52,6.03) JDIMM1.6 ; v1(61.18,11.62) 61.27,11.71 JDIMM1.89 ; v1(296.25,32.64) 296.46,32.64 296.95,33.13 JNGFF3.45 ; UC1.AL28 v1(121.55,54.62) 121.78,54.62 UC1.AK27 ; UC1.AW23 v1(124.62,48.85) UC1.BA23 ; UC1.K63 v1(101.69,64.05) UC1.K64 UC1.K65 v1(100.39,64.05) UC1.K66 99.8,64.18 v1(99.8,63.99) 99.8,63.98 UC1.K67 UC1.K68 98.3,64.35 ; v1(93.53,6.12) JDIMM1.210 ; v1(45.56,14.24) 45.78,14.02 JDIMM1.27 ; JAPS1.12 318.64,67.75 v1(318.8,67.91) ; v1(163.1,14.9) 163.56,14.9 163.78,14.68 JDIMM2.167 ; 135.01,59.16 v1(135.01,59.08) ; 135.01,59.16 135.01,59.16 135.26,58.91 UC1.AA4 UC1.AA2 ; CC312.2 99.7,80.22 v1(99.33,80.59) ; JDIMM2.223 177.78,11.7 v1(177.72,11.65) ; UC1.AW18 v1(127.06,48.67) UC1.BA18 ; JDIMM2.22 125.53,6.06 v1(125.43,6.16) ; UC1.J32 118.8,65.94 v1(118.74,66) ; JDIMM2.2 120.53,6.34 v1(120.65,6.46) ; v1(134.32,10.35) 134.42,10.35 135.28,11.21 JDIMM2.61 ; UC1.J13 v1(130.69,64.67) UC1.J11 ; CC319.2 146.98,63 147.85,63 v1(148.31,62.55) ; UC1.AN20 126.44,52.8 126.16,52.56 v1(126.12,52.56) 126.53,52.15 UC1.AP20 ; v1(64.01,11.58) 63.78,11.82 JDIMM1.99 ; v1(105.09,50.5) UC1.AT56 ; JNGFF2.11 289.3,41.1 v1(289.98,40.42) ; v1(45.52,6.12) JDIMM1.26 ; v1(107.88,66) 108.18,65.69 UC1.G52 ; UE2.17 v1(46.86,74.95) ; JEDP1.24 104.8,91.47 v1(105.09,91.18) 105.3,91.38 JEDP1.23 ; UC1.H15 129.07,65.04 v1(128.82,65.29) ; v1(53.03,6.03) JDIMM1.56 ; UC1.AK22 124.78,54.36 125.11,54.36 125.25,54.22 UC1.AK21 125.76,54.54 125.76,54.64 125.87,54.75 126.09,54.96 UC1.AJ20 126.09,55.14 v1(125.76,55.47) ; JNGFF1.15 199.89,19.25 v1(199.62,19.52) ; UC1.AN38 v1(116.06,52.41) UC1.AN37 ; JDIMM2.73 138.28,11.74 ; 138.28,11.74 139.15,10.86 v1(139.32,10.86) ; 138.28,11.74 138.28,11.73 138.38,11.62 ; v1(101.43,52.41) 101.61,52.56 101.63,52.56 101.77,52.71 UC1.AN63 ; v1(84.57,11.13) 84.78,11.34 JDIMM1.175 ; UC1.AT35 v1(116.97,51.14) UC1.AR35 ; UC1.F8 132.55,66.56 v1(132.55,66.64) ; UC1.AH13 129.93,55.33 129.79,55.48 v1(129.68,55.48) ; v1(274.67,36.14) 274.67,36.1 274.9,35.87 JSATA1.7 ; v1(131.6,49.87) UC1.AU10 ; UC1.AJ15 129.34,55.13 129.68,55.47 v1(129.68,55.48) ; UC1.L16 v1(128.36,63.02) UC1.L17 ; v1(126.12,51.22) 126.19,51.22 126.55,51.5 UC1.AR20 ; v1(129.68,55.48) 129.75,55.55 129.75,56.05 129.61,56.19 129.61,56.46 UC1.AF15 UC1.AG16 v1(128.38,55.48) 128.04,55.81 UC1.AG17 ; JEDP1.28 102.8,92.86 101.76,93.9 v1(100.23,93.9) ; v1(101.69,54.88) UC1.AK63 UC1.AM61 v1(102.34,53.06) ; v1(101.69,54.88) UC1.AH64 ; v1(101.69,54.88) UC1.AH63 ; v1(98.96,70.31) 98.96,70.2 99.17,70 99.17,69.8 UC1.A67 ; v1(127.71,62.18) UC1.P17 ; UC1.F13 129.97,66.6 v1(129.78,66.6) 129.75,66.6 UC1.E15 ; JDIMM2.234 v1(180.53,6.07) ; UC1.U63 102.04,60.69 v1(101.71,60.37) 101.39,60.69 UC1.U64 ; 122.27,67.76 122.34,67.84 122.34,68.26 ; 122.27,67.76 UC1.D26 ; 122.27,67.76 UC1.D25 ; UC1.AR46 v1(111.49,51.14) UC1.AR45 ; UC1.B48 v1(109.84,68.23) UC1.D48 ; UC1.G58 v1(104.17,65.94) 103.92,65.69 UC1.G60 ; UC1.AE68 98.72,57.1 98.2,57.1 UC1.AE69 97.81,57.49 v1(97.81,57.66) ; UC1.AE68 98.9,57.06 99.33,57.06 UC1.AE67 99.44,57.28 v1(99.78,57.62) 100.09,57.31 UC1.AE66 100.21,57.05 100.62,57.05 UC1.AE65 101.18,57.61 v1(101.18,57.64) 101.39,57.43 UC1.AE64 UC1.AF63 ; UC1.AE68 98.79,57.28 v1(98.46,57.6) ; v1(101.33,65.94) UC1.G63 ; v1(110.57,53.06) UC1.AM46 110.57,53.91 UC1.AL48 ; UC1.BA36 v1(117.16,48.85) UC1.AW36 ; v1(298.96,43.33) 298.96,43.2 299.3,42.86 JNGFF2.43 ; 119.72,48.85 v1(119.72,48.86) ; 119.72,48.85 119.63,48.94 UC1.AW32 ; 119.72,48.85 119.63,48.76 UC1.BA32 ; UC1.E6 133.89,66.96 133.51,66.58 v1(133.46,66.58) ; UC1.J8 132.98,64.44 v1(132.53,64.72) ; JEDP1.27 103.3,93.58 v1(102.98,93.9) ; 87.27,13 87.27,11.84 87.88,11.23 v1(88.01,11.23) ; v1(62.27,11.55) JDIMM1.93 ; UC1.D58 104.9,67.74 v1(104.9,68.23) 104.9,68.72 UC1.B58 ; UC1.T17 127.89,60.78 127.54,60.78 UC1.T18 v1(127.08,61.34) UC1.P19 ; 7.93,94.43 JUSBC1.A1 ; UC1.AU32 v1(118.8,49.85) ; UC1.AR11 131.42,51.77 v1(131.6,51.77) UC1.AP10 ; UC1.AG17 127.39,55.24 UC1.AJ18 127.38,55.06 127.2,54.87 127.2,54.41 UC1.AK18 127.34,54.21 v1(127.02,53.73) ; UC1.AG17 128.04,55.99 127.71,56.31 ; v1(124.3,64.46) 124.6,64.76 UC1.K22 ; UC1.BB67 99.25,46.6 v1(99.32,46.53) ; JDIMM1.252 104.03,5.95 v1(104.24,6.16) ; v1(104.17,51.77) UC1.AP58 ; JDIMM2.9 122.28,11.85 v1(122.07,11.65) ; UC1.N13 130.18,62.78 129.78,62.37 v1(129.78,62.34) 129.78,62.02 130.07,61.73 UC1.R13 ; v1(53.62,10.86) 53.28,11.21 ; 53.28,11.21 53.27,11.21 53.27,11.4 ; 53.28,11.21 53.28,11.39 53.27,11.4 ; JDIMM2.40 v1(130.03,6.26) ; JDIMM2.77 v1(139.28,11.5) ; v1(207.72,17.7) 207.92,17.5 JNGFF1.22 ; v1(58.52,6.32) JDIMM1.78 ; JDIMM2.181 167.28,14.13 v1(167.14,14.27) ; v1(134.95,61.25) 134.74,61.61 UC1.R6 ; JDIMM2.19 124.78,11.22 v1(123.9,10.35) ; UC1.AW53 v1(107.39,48.85) UC1.BA53 ; UC1.AW62 v1(102.43,48.85) UC1.BA62 ; UC1.Y19 126.8,59.25 127.06,59.51 v1(127.06,59.67) 127.39,59.99 UC1.V18 127.6,60.3 127.82,60.3 UC1.V17 ; JDIMM2.85 v1(141.28,11.62) ; CV103.2 271.96,55.7 v1(271.96,55.66) ; v1(199.96,9.4) 200.11,9.25 JNGFF1.55 ; v1(146.53,14.18) 146.78,13.93 JDIMM2.107 ; JDIMM2.197 171.28,14.29 v1(171.4,14.42) ; v1(293.03,42.94) 293.3,42.67 JNGFF2.19 ; UC1.AW10 v1(131.9,48.85) UC1.BA10 ; v1(128.3,10.94) 128.03,10.94 127.78,11.19 JDIMM2.31 ; v1(101.06,58.54) 100.74,58.86 UC1.AA65 ; UC1.N10 131.82,63.12 v1(131.82,63.28) UC1.L11 ; v1(99.11,62.2) 98.79,62.52 UC1.N68 ; v1(60.55,11.62) 60.27,11.89 JDIMM1.85 ; v1(200,17.84) 200.09,17.75 JNGFF1.21 ; v1(83.06,15) 83.78,14.29 JDIMM1.171 ; v1(117.89,52.41) UC1.AN33 ; JNGFF3.21 302.95,35.02 302.65,35.32 v1(301.57,35.32) 301.45,35.21 JNGFF3.27 ; v1(135.34,48.85) 135.46,48.74 135.6,48.74 135.96,48.37 UC1.AY3 UC1.BA2 ; UC1.B30 119.84,68.65 v1(119.84,68.23) 119.84,67.82 UC1.D30 ; JEDP1.8 112.8,92.79 v1(112.44,93.15) ; v1(96.11,48.2) UC1.AY71 ; UC1.F68 UC1.D69 98.06,67.37 v1(98.06,67.37) ; UC1.BA14 v1(129.48,48.77) UC1.AW14 ; v1(124.23,65.97) 124.51,65.69 UC1.G22 ; v1(124.23,65.97) 124.18,65.97 123.83,66.32 UC1.F23 ; v1(117.89,54.71) UC1.AL35 ; v1(105.09,67.21) UC1.E56 ; JDIMM2.60 v1(135.03,6.11) ; v1(102.97,57.86) 102.97,57.78 102.81,57.62 UC1.AD62 ; v1(52.04,10.99) 51.94,10.99 50.78,12.15 JDIMM1.47 ; UC1.P20 v1(126.41,62.2) UC1.N19 v1(127.07,63.02) UC1.L18 ; UC1.AH6 v1(135.01,54.88) 135.37,54.44 UC1.AJ4 ; UC1.AL4 135.71,53.8 v1(135.98,53.8) 136.29,53.8 UC1.AL2 ; JDIMM2.89 v1(142.28,11.58) ; v1(63.52,6.09) JDIMM1.98 ; 122.34,68.26 v1(122.34,68.26) ; v1(42.52,3.5) JDIMM1.14 ; UC1.D22 124.7,68.1 v1(124.57,68.24) 124.7,68.38 UC1.B22 ; v1(129.03,63.86) UC1.K16 ; UC1.AF4 135.78,56.52 136.23,56.52 UC1.AF2 UC1.AF1 137.24,56.36 137.77,56.36 137.78,56.35 138.16,56.35 138.17,56.36 138.36,56.36 v1(138.52,56.52) ; JDIMM2.65 136.28,11.55 v1(136.22,11.49) ; v1(202.59,22.53) 201.88,23.25 JNGFF1.7 ; v1(136.22,70.17) 135.65,70.17 UC1.A5 ; UC1.AD13 130.55,57.01 130.61,56.94 v1(130.61,56.97) ; JEDP1.6 v1(113.8,93.22) ; JDIMM2.86 141.52,5.94 v1(141.43,6.03) ; v1(109.66,51.14) UC1.AR48 ; UC1.D6 134.59,68.12 v1(134.71,68.24) 135.02,68.24 UC1.C5 ; v1(125.76,55.47) 126.09,55.79 UC1.AG20 126.18,55.89 126.22,55.86 126.6,55.86 126.64,55.89 UC1.AG19 126.83,55.89 126.87,55.86 127.25,55.86 127.29,55.89 UC1.AG18 127.71,56.31 ; v1(125.76,55.47) 125.44,55.79 UC1.AG21 ; CZ101.2 123.75,84.65 v1(123.96,84.85) ; JNGFF2.49 300.8,43.25 v1(301.11,43.56) ; JDIMM2.72 v1(138.03,6.03) ; UC1.AR23 v1(123.37,51.14) UC1.AT23 ; v1(121.55,53.06) UC1.AM27 ; v1(120.63,51.77) UC1.AP28 ; UC1.L20 126.09,63.38 125.64,62.94 125.64,62.81 UC1.N21 125.11,62.92 v1(125.11,63.02) ; v1(296.73,43.05) 296.72,43.05 296.3,42.62 JNGFF2.31 296.3,41.04 296.05,40.79 295.15,40.79 294.8,41.14 JNGFF2.25 ; JSATA1.4 v1(273.4,35.69) ; JNGFF2.37 v1(297.8,43.13) ; UC1.B44 v1(112.31,68.23) UC1.D44 ; v1(133.72,58.08) UC1.AB8 ; JNGFF1.28 v1(207.69,16) ; v1(132.95,6.14) 133.03,6.06 JDIMM2.52 ; v1(295.26,32.16) 295.04,32.38 295.04,32.74 295.45,33.16 JNGFF3.51 ; 130.78,11.88 130.78,11.89 ; 130.78,11.89 v1(130.51,11.62) ; 130.78,11.89 JDIMM2.43 ; UC1.AT58 v1(104.17,51.14) UC1.AR58 ; UC1.T2 136.45,61.52 136.16,61.52 v1(136.01,61.37) 135.82,61.56 UC1.T4 ; v1(169.07,14.24) 169.28,14.04 JDIMM2.189 ; v1(99.6,53.04) 100.09,53.53 UC1.AL66 ; UC1.L4 135.67,64.05 v1(136,64.05) 136.33,64.05 UC1.L2 ; UC1.AW57 v1(104.91,48.85) UC1.BA57 ; UC1.B10 UC1.D10 UC1.D11 v1(130.69,67.21) UC1.E11 ; UC1.W13 130.17,59.48 130.5,59.06 v1(130.59,59.06) ; JDIMM1.73 v1(57.27,14.29) ; v1(127.03,65.31) UC1.H18 UC1.K18 ; v1(134.32,11.62) 134.28,11.66 JDIMM2.57 ; UC1.AM43 112.86,53.47 UC1.AL45 112.4,53.91 UC1.AM45 v1(111.49,53.06) ; v1(123.37,51.77) UC1.AP23 ; v1(125.72,60.48) 125.69,60.5 125.69,60.61 125.44,60.87 UC1.T21 UC1.P21 ; v1(111.5,65.95) 111.76,65.69 UC1.G45 112.24,65.98 v1(112.42,65.98) 112.57,65.98 UC1.G43 113.32,65.23 UC1.J42 ; JDIMM2.39 v1(129.78,14.32) ; JDIMM2.69 137.28,14.07 137.14,14.2 v1(136.53,14.2) ; v1(62.52,6.09) JDIMM1.94 ; JNGFF1.43 v1(199.76,12.25) ; v1(120.9,82.34) 120.5,81.94 QV7.3 ; v1(133.46,65.96) 133.46,65.96 133.49,65.94 133.5,65.91 UC1.G6 ; 53.27,11.4 JDIMM1.57 ; UC1.AN42 113.34,52.43 v1(113.32,52.41) ; v1(96.11,49.32) 96.29,49.5 UC1.AV71 UC1.AV70 UC1.AV69 v1(98.64,49.5) ; v1(122.46,53.06) UC1.AM25 ; v1(136.99,6.03) 137.03,5.99 JDIMM2.68 ; v1(114.21,66.62) 113.93,66.34 UC1.F42 ; UC1.D39 114.97,67.9 v1(114.97,68.21) 114.97,68.56 UC1.B39 ; v1(106.91,51.14) UC1.AR53 ; v1(276.74,73.01) 276.35,73.4 JDEG1.10 ; v1(125.2,53.04) 125.27,53.04 125.66,53.39 UC1.AM21 ; JDIMM2.18 v1(124.53,6.15) ; UC1.E46 110.82,66.99 v1(110.57,67.24) ; CZ130.2 281.31,38.56 281.81,38.06 v1(281.88,38.06) ; v1(44.52,6.14) JDIMM1.22 ; UC1.AW28 v1(122.14,48.85) UC1.BA28 ; JDIMM2.10 v1(122.53,6.52) ; v1(96.26,69.31) 96.3,69.27 96.82,69.27 UC1.B71 UC1.A70 ; JDIMM2.175 165.78,11.79 v1(165.94,11.62) ; v1(99.11,58.54) 98.79,58.86 UC1.AA68 ; v1(199.95,16.57) 200.12,16.75 JNGFF1.25 ; v1(125.81,10.35) 126.04,10.35 126.78,11.09 JDIMM2.27 ; v1(116.97,52.41) UC1.AN35 ; v1(140.52,6.27) JDIMM2.82 ; 127.71,56.31 UC1.AF17 ; v1(114.23,52.41) UC1.AN40 ; UC1.E53 107.36,67 UC1.D53 v1(107.36,68.23) UC1.B53 ; UC1.Y17 128.26,59.54 128.4,59.71 UC1.V16 128.77,60.09 129.07,60.46 v1(129.07,60.49) 129.07,60.6 129.34,60.87 UC1.T15 ; UC1.AU15 128.94,49.93 128.92,49.81 v1(128.92,49.84) ; UC1.D14 v1(129.66,68.23) UC1.B14 ; JDIMM2.56 134.03,6.05 v1(134.09,6.11) ; JDIMM2.64 v1(136.03,6.09) ; JNGFF1.31 v1(202.63,15.25) ; UC1.F33 118.4,66.34 v1(118.74,66) ; v1(123.53,6.54) JDIMM2.14 ; v1(92.17,11.24) 92.28,11.35 JDIMM1.205 ; UC1.U66 100.09,60.69 v1(99.76,60.37) 99.44,60.69 UC1.U67 ; JDIMM1.189 88.28,14.25 v1(88.27,14.25) ; CN9.2 278.1,36.41 278.4,36.1 JSATA1.14 ; UC1.F35 117.43,66.4 117.19,66.64 v1(117.04,66.64) 116.82,66.64 UC1.F37 116.97,65.88 UC1.J35 ; JNGFF1.1 v1(200.08,24.75) ; PH601.1 61.17,60.8 v1(61.17,59.66) ; v1(112.2,48.85) UC1.BA45 ; JDIMM2.51 v1(132.78,11.51) ; UZ23.5 281.36,42.23 v1(281.49,42.36) ; UC1.AD19 126.53,57.36 126.29,57.36 UC1.AD20 ; JAPS1.10 v1(316.74,66.75) ; v1(47.78,11.7) JDIMM1.35 ; v1(278.9,41.48) 278.9,40.67 279.37,40.2 CZ129.2 ; UC1.AP18 127.47,52.13 127.47,52.13 v1(127.04,51.78) ; JAPS1.8 v1(318.65,65.75) ; UC1.N6 134.63,62.8 134.24,62.42 v1(134.24,62.32) ; UC1.AT2 136.18,50.96 v1(136,50.78) 135.82,50.96 UC1.AT4 ; v1(40.28,11.75) JDIMM1.5 ; JNGFF1.49 v1(200,10.75) ; v1(119.72,54.62) UC1.AL32 ; UC1.AK69 98.12,54.57 98.3,54.75 98.61,54.75 UC1.AK68 ; JDIMM2.26 v1(126.53,6.11) ; UC1.F32 119.08,66.34 v1(118.74,66) ; v1(121.09,11.27) 121.09,11.83 121.28,12.02 JDIMM2.5 v1(121.28,14.25) ; JNGFF1.61 198.66,7.75 v1(198.54,7.88) ; v1(133.72,57.01) UC1.AD8 ; v1(109.64,65.94) 110.1,65.69 UC1.G48 ; JDIMM2.231 v1(179.78,11.63) ; v1(43.52,6.22) JDIMM1.18 ; UC1.AR50 v1(108.74,51.14) UC1.AR52 v1(107.83,51.14) ; JDIMM2.206 v1(173.53,6.03) ; v1(60.76,10.35) 60.63,10.35 59.27,11.71 JDIMM1.81 ; UC1.AN58 v1(104.17,52.41) ; UC1.J38 v1(115.14,65.94) ; UC1.BA71 96.33,47.55 v1(96.08,47.3) 96.3,47.09 UC1.BB70 ; JDIMM2.230 v1(179.53,6.49) ; v1(128.38,57.15) UC1.AD16 128.27,57.99 127.72,57.99 UC1.AB18 ; v1(91.53,6.28) JDIMM1.202 ; JDIMM2.30 v1(127.53,6.1) ; v1(101.43,51.77) UC1.AP63 ; JDIMM2.99 v1(144.78,11.58) ; v1(123.78,11.61) JDIMM2.15 ; JEDP1.4 v1(114.8,94.12) ; v1(131.55,14.29) 131.78,14.07 JDIMM2.47 ; UC1.BB6 UC1.BA6 v1(134.32,48.85) 134.28,48.9 UC1.AW6 ; JDIMM2.81 v1(140.28,11.61) ; JDIMM2.210 v1(174.53,6.09) ; v1(99.29,65.94) UC1.G66 ; JDIMM2.202 v1(172.53,6.14) ; JSATA1.12 277.4,35.62 277.27,35.75 v1(277.27,35.83) ; v1(127.03,67.21) UC1.E18 ; v1(64.52,6.16) JDIMM1.102 ; JDIMM2.93 v1(143.28,11.55) ; v1(106,65.94) UC1.G55 ; JDIMM2.48 v1(132.03,6.15) ; UC1.AR42 v1(113.32,51.14) UC1.AT42 ; v1(100.78,10.99) JDIMM1.239 ; UC1.AR16 128.5,51.5 128.77,51.24 v1(128.86,51.24) 129.19,51.5 UC1.AR15 ; v1(49.78,14.27) JDIMM1.43 ; UC1.L8 v1(133.72,63.28) ; v1(98.78,11.62) JDIMM1.231 ; JDIMM2.214 v1(175.53,6.03) ; v1(109.79,48.72) UC1.BA49 ; JDIMM2.23 v1(125.78,11.62) ; JNGFF1.16 v1(207.67,19) ; v1(115.14,51.77) UC1.AP38 ; JDIMM2.252 v1(185.03,6.05) ; JNGFF1.10 v1(207.68,20.5) ; JAPS1.14 v1(318.5,68.75) ; v1(118.8,51.77) UC1.AP32 ; UC1.AM8 133.44,53.91 UC1.AK8 133.07,54.76 v1(133.07,54.88) ; v1(41.52,6.03) JDIMM1.10 ; v1(123.37,52.41) UC1.AN23 ; JDIMM2.44 v1(131.03,6.15) ; v1(55.03,6.03) JDIMM1.64
  BOTTOM w0.305: v1(95.35,11.62) 95.28,11.69 JDIMM1.217 ; v1(98.6,6.14) 98.53,6.06 JDIMM1.230 ; JDIMM1.52 v1(52.03,6.08) ; JDIMM2.213 175.28,14.32 v1(175.43,14.47) ; v1(46.83,6.41) 46.52,6.11 JDIMM1.30 ; JDIMM2.238 181.53,6.58 180.8,7.3 v1(180.63,7.3) ; v1(56.1,11.24) 55.27,12.07 JDIMM1.65 ; JDIMM2.185 168.28,14.39 168.76,14.88 169.19,14.88 v1(169.27,14.8) ; DT4.1 v1(11.85,90.21) 11.4,90.66 DT13.2 ; JDIMM2.201 172.28,11.75 v1(172.27,11.75) ; JDIMM1.227 97.78,11.22 98.65,10.35 v1(98.77,10.35) ; JDIMM1.60 54.03,5.95 v1(53.94,6.03) ; v1(101.95,11.37) 101.78,11.54 JDIMM1.243 ; JDIMM1.44 50.03,6.17 v1(50.09,6.24) ; v1(170.26,11.49) 170.28,11.51 JDIMM2.193 ; JDIMM1.61 54.27,14.27 54.06,14.49 v1(53.57,14.49) 52.06,14.49 51.78,14.2 JDIMM1.51 ; v1(93.57,7.43) 93.44,7.43 92.53,6.52 JDIMM1.206 ; JDIMM1.19 43.78,14.17 v1(43.53,14.42) ; v1(277.55,36.72) CN9.2 ; JNGFF1.69 202.05,5.94 201.75,6.25 JNGFF1.67 ; JDIMM1.247 102.78,11.75 v1(102.78,11.75) ; JDIMM2.205 173.28,14.02 173.01,14.29 v1(172.29,14.29) ; v1(45.56,11.24) 44.78,12.03 JDIMM1.23 ; JDIMM2.239 181.78,11.81 v1(181.69,11.72) ; v1(100.55,7.56) 99.53,6.53 JDIMM1.234 ; JUSBC1.A1 v1(8.37,94.42) ; JDIMM1.222 96.53,6.09 v1(96.63,6.19) ; v1(41.37,11.62) 41.27,11.72 JDIMM1.9 ; v1(68.91,108.37) 68.87,108.41 PU1201.4 ; JDIMM2.243 182.78,11.83 v1(182.88,11.72) ; v1(60.52,6.14) JDIMM1.86 ; JDIMM2.209 174.28,11.8 v1(174.32,11.75) ; DT15.2 v1(11.86,96.03) DT16.2 ; DT18.2 v1(11.83,98.85) DT8.2 ; v1(305.92,32.62) 305.95,32.65 JNGFF3.9 ; JDIMM1.238 100.53,5.92 v1(100.67,6.06) ; v1(95.35,6.16) 95.53,5.98 JDIMM1.218 ; v1(56.1,6.03) 56.03,5.96 JDIMM1.68 ; v1(176.23,11.49) 176.28,11.54 JDIMM2.217 ; v1(103.78,11.67) 103.78,11.67 JDIMM1.251 ; JDIMM2.196 v1(171.03,6.08) ; v1(59.52,6.32) JDIMM1.82 ; v1(182.96,6.03) 183.03,5.97 JDIMM2.244 ; JDIMM2.251 v1(184.78,11.64) ; JDIMM2.247 183.78,11.26 v1(182.96,10.44) ; v1(57.27,14.29) 56.69,14.29 56.27,13.87 JDIMM1.69 ; UE6.3 268.09,73.21 268.74,73.86 v1(268.74,74.92) ; JDIMM1.48 51.03,6.21 v1(51.14,6.32) ; v1(43.4,11.37) 42.78,11.99 JDIMM1.15 ; DT5.2 10.73,93.77 v1(10.71,93.78) ; JDIMM1.40 v1(49.03,6.06) ; v1(65.25,6.08) 65.52,5.81 JDIMM1.106 ; UC1.AL64 101.39,53.09 v1(101.43,53.04) ; v1(270.68,65.99) 270.33,66.34 JESPI.9 ; v1(304.55,32.66) 304.45,32.76 JNGFF3.15 ; v1(57.25,6.16) 57.03,5.94 JDIMM1.72 ; DT17.2 11.14,101.33 v1(11.13,101.34) ; v1(100.81,9.72) 100.68,9.72 99.78,10.62 JDIMM1.235 ; DT14.2 11.4,92.79 v1(11.83,93.21) ; v1(39.28,11.75) JDIMM1.1 ; JDIMM1.209 93.28,10.9 v1(93.82,10.35)
  BOTTOM w0.381: RN73.2 288.52,55.26 289.02,55.76 v1(289.02,55.96) ; v1(274.67,36.14) 274.5,36.31 CN11.2 CN10.2 ; v1(112.33,89.77) 112.44,89.66 CZ1.2 112.73,88.56 CV22.2 CV23.2 ; v1(17.33,15.84) 16.82,15.33 PR932.2 ; v1(288.65,70.27) 288.3,69.92 288.13,69.92 288.13,69.92 287.71,69.92 287.34,69.54 287.34,69.08 287.91,68.51 RZ357.2 RZ165.2 ; v1(32.3,79.06) 32.3,79.62 RT71.2 32.17,80.63 RT101.2 31.93,80.64 31.45,81.12 v1(31.16,81.12) 30.97,81.31 RT377.2 ; v1(129.42,84.56) 129.86,84.13 UZ19.5 ; RN74.2 288.27,57.83 v1(289.02,57.08) ; CV84.2 107.12,102.79 CV80.2 ; v1(35.45,83.71) 35.45,84.79 RT81.2 ; v1(151.38,66.61) 151.62,66.36 CC9.2 ; v1(110.88,85.54) 110.6,85.54 110.21,85.15 CV15.2 CV11.2 ; CZ105.2 133.99,84.17 UZ35.3 ; v1(69.98,54.5) 70.47,54.99 PC619.1 PC618.1 ; v1(277.27,45.87) 276.83,46.31 CZ119.2 276.41,47.05 CZ124.2 ; CZ133.2 288.66,63.21 v1(288.41,62.97) ; JESPI.11 272.41,71.53 271.4,72.54 v1(271.4,72.79) ; JDEG1.12 278.63,72.02 v1(278.39,71.77) ; v1(273.68,65.01) 273.36,65.01 273.18,64.84 JESPI.12 272.04,64.47 RN15.1 ; CC10.2 149.64,58.57 149.26,58.95 v1(149.26,59.58) 148.8,59.58 148.32,60.06 CC318.2 ; v1(276.57,53.95) 276.03,53.41 CZ111.2 ; CI12.2 82.3,98.95 v1(81.67,98.32) ; v1(41.91,97.85) 41.36,97.3 CT88.2 ; CZ106.2 v1(145.14,87.19) ; PU1.3 v1(64.22,94.79) ; v1(150.75,89.07) 150.23,89.6 UC12.3 ; CV21.2 102.54,88.13 CV12.2 ; RE513.2 304.23,69.03 305.17,69.03 305.44,69.3 v1(305.44,69.54) ; CN30.2 288.68,54.5 v1(289.02,54.84) ; CZ31.2 205.75,27.96 v1(205.62,28.09) ; v1(152.15,44.34) 151.49,43.68 CC26.2 ; PC604.2 75.57,47.92 v1(76.32,47.17) ; v1(124.84,82) 125.06,81.78 UZ21.5 ; CT87.2 30.66,78.62 31.16,79.11 v1(31.16,79.37) ; v1(120.55,87.46) 120.4,87.61 CZ2.2 120.66,88.31 121.07,87.89 CV18.2 ; UC7.3 v1(158.83,51.47)
  BOTTOM w0.457: PC1215.2 15.55,90.82 v1(14.7,90.82) ; RZ167.2 v1(293.88,64.66) ; RV80.2 100.59,103.21 100.41,103.38 v1(100.41,104.03) ; CC8.2 151.64,65.32 v1(151.95,65.02) ; RV73.2 99.7,103.9 v1(99.83,104.03) ; PR310.2 v1(185.68,95.84) ; v1(32.45,86.38) 32.14,86.38 31.81,86.05 RT82.2 ; PC217.2 43.87,43.79 v1(43.76,43.9) PR206.2 ; v1(132.99,83.91) CZ105.2 ; PR302.2 v1(185.68,98.57) ; RN61.2 293.2,60.77 RZ159.2 294.72,61.8 v1(294.84,61.68) ; PR311.2 v1(185.68,94.89)
  BOTTOM w0.508: RV3.1 92.89,82.5 v1(92.27,81.88) RC112.2 ; CZ40.2 v1(134.52,100.22) ; v1(41.6,20.9) JDIMM1.261 v1(38.85,24.34) ; v1(45.15,60.99) JUART1.6 v1(43.86,59.87) ; CMOS1.2 152.67,51.45 CC25.2 153.74,51.14 154.5,50.37 RC65.2 154.93,49.8 v1(155.18,49.55) ; v1(32.98,58.88) JSD1.20 v1(32.98,56.47) ; CA69.2 301.96,36.39 301.57,36.78 v1(301.57,37.29) ; v1(270.9,63.62) 271.38,63.14 RN9.1 RN7.1 ; RN59.2 291.67,53.08 v1(291.63,53.13) ; v1(185.55,23.59) 185.55,22.8 JDIMM2.262 187.45,23.58 v1(187.34,23.69) ; v1(44.09,52.7) PR212.2 44.08,52.06 PC222.2 ; JSD1.17 v1(9.4,59.39) ; CV16.2 v1(98.75,85.36) ; JRTC1.2 62.03,79.53 v1(62.56,80.06) ; v1(280.29,50.69) 280.29,50.31 279.91,49.92 CZ109.2 CZ110.2 ; UC6.4 160.94,54.78 161.45,55.29 v1(161.93,55.29) ; v1(74.91,99.48) 74.91,97.83 JIR1.8 ; UV4.2 314.65,78.62 v1(314.65,79.26) ; JEDP1.44 97.65,96.98 v1(97.48,97.15) ; CV20.2 v1(102.01,85.58) ; CT94.2 v1(18.55,82.95) ; PR1246.2 v1(73.68,106.63) ; CZ3.2 82.06,96.3 v1(82.06,95.27) ; PC1216.2 v1(18.29,90.85) ; PC1205.2 68.24,112.16 PR1217.2 68.24,112.2 68.88,112.85 v1(69.33,112.85) ; PC125.2 v1(161.51,105.36) ; v1(277.14,64.15) 276.74,64.15 276.23,63.64 RN13.1 ; CC300.2 v1(91.25,81.79) ; v1(42.4,65.99) JUART1.5 v1(45.36,65.99) 45.31,65.94 JUART1.4 ; v1(58.35,83.7) JRTC1.3 v1(56.12,82.08) ; PC933.2 v1(11.44,18.65) ; v1(123.2,79.52) 122.76,79.95 CC226.2 123.25,80.79 v1(123.61,81.16) ; v1(32.98,35.58) JSD1.22 v1(34.55,34.15) ; JFAN1.1 266.57,45.61 266.37,45.61 v1(266.35,45.64) ; PC641.2 v1(65.98,57.87) ; v1(278.81,56.19) 278.62,56.38 CV106.2 ; PR207.1 v1(42.87,43.9) ; JEDP1.43 106.55,96.33 v1(105.73,97.15) ; UV24.2 97.73,83.01 v1(96.98,82.26) ; DI3.1 81.15,102.41 82.35,102.41 v1(83.14,103.19) ; PC313.2 v1(184.98,90.7) ; RC113.2 RC110.2 v1(94.59,74.67) ; CT83.2 29.73,83.29 v1(29.89,83.46) ; CC326.2 151.45,57.73 151.71,57.47 v1(152.03,57.47) ; v1(285.23,44.4) 285.7,43.92 JNGFF2.68 ; RV2.2 105.84,88.82 RV1.2 105.92,89.13 106.3,89.51 v1(106.3,90.57) ; PC1013.2 v1(83.36,68.14) ; v1(135.84,106.24) JSIM1.14 v1(136.95,105.01) ; PC312.2 185.36,91.59 v1(184.98,91.59) ; v1(171.33,112.16) 171.84,111.65 PC119.2 ; v1(40.89,81.65) 41.18,81.95 CE500.2 ; UC5.4 v1(159.39,63.42) ; v1(56.28,76.36) 56.91,75.73 JRTC1.4 58.35,76.32 v1(57.32,77.35) ; CV21.2 102.53,87.77 v1(102.25,87.48) ; PC1201.1 v1(64.85,106.65) ; v1(281.21,44.93) 281.26,44.98 CZ20.2 ; UT7.2 40.55,99.89 CT90.2 39.5,99.61 v1(39.92,99.19) ; PD4.1 v1(61.5,86.36) ; v1(120.35,112.64) JSIM1.11 v1(121.6,111.21) ; CV135.2 318.9,73.66 v1(318.9,72.93) ; CC305.2 v1(102.75,76.98) ; v1(41.91,97.85) 42.35,97.42 CT92.2 ; v1(84.7,57.24) 84.71,57.23 PC1181.2 ; CA13.1 310.65,41.8 v1(310.52,41.93) ; v1(15.25,31.51) 14.93,31.82 JSD1.26 13.27,31.82 12.71,31.26 v1(12.71,30.75) ; CC302.2 v1(149.03,87.45) ; v1(96.02,81.17) 95.66,80.82 CC310.2 ; PC649.2 69.98,42.91 PC652.2 69.11,42.04 v1(69.98,41.17) ; v1(271.09,42.44) 271.21,42.31 CN1.2 ; v1(281.34,37.38) 281.26,37.3 CN8.2 ; v1(40.59,52.78) PC221.2 39.71,52.06 PR209.2 ; v1(314.65,81.92) 314.3,81.57 DV6.1 ; v1(136.49,87.58) 136.49,87.49 137.14,86.84 CZ100.2 ; v1(161.27,106.47) 161.27,106.63 PC112.2 ; RV117.2 v1(316.11,91.97) ; v1(278.01,78.4) 278.5,78.9 JDEG1.11 ; RE14.2 v1(40.77,75.96) ; v1(149.84,69.16) 149.41,68.73 RC401.2 RC372.2 ; JIR1.2 v1(78.43,93.29) ; PC1178.2 86.69,57.19 v1(86.66,57.22) ; v1(62.91,99.22) 62.47,99.65 PJPDC1.7 61.7,99.06 62.32,98.45 v1(62.94,98.45) ; PC1170.2 v1(86.06,68.11) ; v1(65.97,102.56) 66.42,103.01 PC1213.2 66.6,103.04 67.49,103.04 ; RC4.2 147.31,52.85 147.94,53.48 v1(147.94,53.86) ; JUSB3.7 v1(80.55,107.52) ; JSIM1.15 136.29,111.77 v1(135.93,111.41) ; v1(307.82,81.39) CE504.2 CE505.2 ; CE1.2 v1(47.88,72.45) ; v1(312.92,84.87) 313.09,85.04 DV5.1 ; v1(122.61,103.22) 122.61,102.73 JSIM1.12 123.47,102.77 v1(123.47,103.24) ; PC9.2 v1(63.3,97.67) ; CA23.2 CA22.2 300.36,38.05 v1(299.6,37.29) ; CV134.2 318.46,76.2 319.22,75.44 v1(320.57,75.44) ; v1(104.93,100.4) RV74.2 ; RT303.2 v1(19.44,101.43) ; CZ18.2 CZ17.2 281.52,48.42 v1(281.2,48.1) ; v1(132.15,102.68) 132.92,102.68 JSIM1.13 132.85,101.9 v1(132.21,101.9) ; RV102.2 v1(273.69,60.74) ; PR116.2 v1(171.92,117.11) ; DV4.1 117.13,86.63 117.21,86.63 v1(117.29,86.55) ; v1(11.46,17.79) 11.49,17.77 PR945.2 12.3,16.91 PC1286.2 ; CV131.2 312.81,77.88 v1(312.81,78.33) ; v1(79.82,98.19) CI11.2 ; v1(24.3,30.37) 24.46,30.37 25.8,31.71 JSD1.24 ; RC227.2 v1(151.39,87.72) ; CC303.2 v1(105.8,76.98) ; v1(117.15,109.39) 117.52,109.76 RZ334.2 ; v1(199.47,25.85) JNGFF1.68 ; JSD1.10 v1(9.4,30.17) ; CV25.2 CV24.2 v1(109.38,89.67) ; JIR1.3 v1(78.43,94.09) ; RZ163.2 RZ348.2 RZ161.2 287.91,59.37 287.79,59.24 v1(287.79,58.95) ; PC1207.2 v1(64.52,111.32) ; 67.49,103.04 PR1247.2 ; 67.49,103.04 PC1212.2 ; v1(293.34,67.76) 292.64,68.46 RZ359.2 ; PR103.2 v1(173.08,118.61) ; JSIM1.10 v1(121.74,119.21) ; UI2.2 v1(87.19,100.54) ; JSD1.25 v1(11.7,61.3) ; RZ40.1 272.14,50.82 v1(270.9,50.82) ; CT93.2 24.4,88.97 v1(24.96,88.41) ; CV126.2 317.38,91.59 v1(317,91.97) ; RZ355.2 284.42,68.46 v1(284.29,68.59) ; CV127.2 v1(315.09,91.97) ; CV17.2 v1(97.97,86.26) ; v1(33.91,47.26) 32.98,46.32 JSD1.21 33.84,46.15 v1(34.37,46.68) ; RC141.2 v1(114.16,78.48) ; CV105.2 CV104.2 280.11,59.5 v1(280.36,59.75) ; v1(114.69,87.19) CA6.2 CA5.2 ; RZ157.2 285.15,58.8 285.48,58.47 287.11,58.47 287.65,57.93 RN74.2 ; CC23.2 v1(148.7,41.39) ; PC132.2 162.86,119.33 v1(162.41,118.89) 162.86,118.45 PC115.2 ; CC301.2 v1(96.65,75.22) ; PC601.2 65.18,44.7 v1(64.46,45.42) 65.02,45.97 PC629.1 65.01,46.36 PC636.1 ; RC86.2 v1(104.91,76.98) ; JFAN1.6 v1(258.97,41.53) ; v1(170.38,116.16) 170.63,116.42 PC128.2 ; v1(27.25,60.15) 25.93,60.15 JSD1.23 ; CT89.2 v1(41.48,95.6) ; v1(94.34,91.92) 94.34,94.03 JEDP1.45 95.09,94.09 95.39,93.79 v1(95.39,92.83) ; CE2.2 v1(46.87,72.44) ; PC1174.2 v1(87.39,68.09) ; v1(118.7,113.05) CZ37.2 118.69,112.4 CZ39.2 ; v1(40.9,79.65) 41.28,80.03 RE18.2 ; CZ28.2 207.4,31.97 v1(207.4,32.4) 206.06,32.4 CZ32.2 ; QV2.3 100.59,82.64 101.1,83.15 v1(101.1,83.35) ; v1(277.14,62.5) 277.14,62 277.64,61.5 278.14,61.5 ; RT248.2 v1(20.45,101.43) ; PC1072.2 v1(84.71,68.12) ; JNGFF1.69 v1(200.51,3.61) ; v1(297.63,37.29) 297.69,37.36 CA19.2 CA24.2 ; PC685.2 v1(69.5,74.19) ; PC932.1 19.63,17.03 v1(19.56,16.96) ; 278.14,61.5 RN11.1 278.11,62.4 RN21.2 ; 278.14,61.5 RN17.1 ; v1(264.52,47.01) 264.91,47.4 266.2,47.4 JFAN1.5 ; RE86.2 v1(271.84,76.41) ; CC321.2 v1(100.59,77.23) ; CV19.2 CV18.2 ; CA12.2 v1(312.98,35.76) ; v1(116.86,94.09) JEDP1.41 v1(118.7,96.35) ; PU2.1 v1(71.07,101.21) ; PC218.2 v1(44.98,52.78) ; CC21.2 v1(115.66,80.87) ; v1(34.09,50.47) 33.65,50.47 33.57,50.4 JSD1.6 ; CV14.2 v1(104.53,83.46) ; PC939.2 v1(25.26,15.86) ; PC126.2 v1(171.33,112.86) ; RE16.2 v1(40.77,76.98) ; CC7.2 v1(151.34,53.16) ; CC22.2 v1(118.35,80.88) ; JSD1.3 v1(31.12,43.3) ; v1(104.41,104) 105.36,104 106.57,102.79 CV80.2 ; CC304.2 v1(104.02,77.06) ; JSPI1.21 v1(155.75,45.79) ; CV129.2 v1(318.34,86.81) ; RV116.2 v1(319.03,91.34) ; CZ34.2 CZ33.2 v1(205.47,28.72) ; JSIM1.5 v1(123.74,118.35) ; JSD1.13 v1(6.1,30.17) ; CT70.2 v1(34.55,100.04) ; v1(29.09,94) 29.09,93.5 28.71,93.11 UT6.4 ; PC211.2 v1(47.81,42.72) ; RT393.2 v1(35.37,100.25) ; CT122.2 v1(17.4,101.59) ; RC109.2 v1(88.91,81.97) ; JEDP1.42 115.45,96.86 v1(115.7,97.11) ; CV130.2 v1(315.14,88.41) ; JSPI1.22 v1(170.82,43.78) ; v1(316.17,60.15) JAPS1.19 314.58,60.27 v1(315.68,61.36)
  vias: v1(0.56,104.03) v1(0.51,90.11) v1(0.98,57.93) v1(0.98,54.12) v1(0.98,50.31) v1(0.98,46.5) v1(0.98,42.69) v1(0.98,38.88) v1(0.98,35.07) v1(1.4,105.91) v1(1.4,85.79) v1(1.66,21.74) v1(1.66,17.93) v1(1.66,14.12) v1(1.66,6.5) v1(1.78,0.65) v1(1.81,109.38) v1(2.48,8.4) v1(2.6,3) v1(2.74,23.89) v1(2.74,23.26) v1(2.74,22.56) v1(2.74,21.93) v1(2.93,25.67) v1(3.05,63.77) v1(3,31.31) v1(3,28.87) v1(3.5,10.11) v1(3.53,23.56) v1(3.53,22.92) v1(3.53,22.22) v1(3.53,21.59) v1(3.59,6.92) v1(3.52,4.61) v1(3.52,1.39) v1(4.37,109.39) v1(4.4,106.1) v1(4.4,88) v1(4.58,67.07) v1(4.65,81.76) v1(5.11,29.08) v1(5.11,28.38) v1(5.32,107.71) v1(5.32,104.49) v1(5.32,89.61) v1(5.32,86.39) v1(5.31,6.92) v1(5.38,4.61) v1(5.38,1.39) v1(5.4,10.11) v1(6.3,3) v1(6.42,8.4) v1(7.07,100.41) v1(7.18,107.71) v1(7.18,104.49) v1(7.18,89.61) v1(7.18,86.39) v1(7.75,100.42) v1(8.1,106.1) v1(8.1,88) v1(8.23,0.52) v1(8.53,27.7) v1(8.7,102.06) v1(9.29,27.7) v1(9.31,101.79) v1(9.3,93.95) v1(9.3,93.36) v1(9.63,99.46) v1(9.85,102.19) v1(10.06,109.39) v1(10.04,103.46) v1(10.17,104.41) v1(10.21,102.79) v1(10.55,103.97) v1(10.68,103.32) v1(10.72,99.64) v1(10.8,3.57) v1(11.21,81.65) v1(12.07,67.07) v1(12.45,0.53) v1(12.77,9.54) v1(12.77,8.4) v1(13.06,109.37) v1(13.09,8.97) v1(13.15,7.83) v1(13.53,9.54) v1(13.53,8.4) v1(13.73,28.95) v1(13.73,26.28) v1(13.73,24.95) v1(13.82,30.47) v1(13.82,29.89) v1(13.85,8.97) v1(13.91,7.83) v1(14.1,79.98) v1(14.1,68.85) v1(14.29,9.54) v1(14.29,8.4) v1(14.41,30.47) v1(14.41,29.89) v1(14.6,23.74) v1(14.61,8.97) v1(14.67,7.83) v1(14.79,24.33) v1(14.89,107.56) v1(14.99,30.47) v1(14.99,29.89) v1(14.99,9.54) v1(14.99,8.4) v1(15.24,28.95) v1(15.24,26.28) v1(15.24,24.95) v1(15.31,8.97) v1(15.37,7.83) v1(15.58,30.47) v1(15.58,29.89) v1(15.58,0.5) v1(15.68,24.35) v1(15.63,9.54) v1(15.63,8.4) v1(15.94,8.97) v1(16.01,7.83) v1(16.16,30.47) v1(16.16,29.89) v1(16.69,105.71) v1(16.77,30.47) v1(16.77,29.89) v1(16.75,28.95) v1(16.75,26.28) v1(16.75,24.95) v1(17.33,18.08) v1(17.33,16.96) v1(18.29,74.92) v1(18.29,74.31) v1(18.29,73.68) v1(18.45,18.08) v1(18.45,16.96) v1(18.45,15.84) v1(18.7,103.75) v1(18.67,0.53) v1(19.56,18.08) v1(19.56,15.84) v1(20.1,95.47) v1(20.1,94.05) v1(20.51,75.17) v1(20.51,74.56) v1(21.1,101.46) v1(21.24,102.56) v1(21.21,95.47) v1(21.21,94.05) v1(21.87,69.08) v1(22.18,44.65) v1(22.33,95.47) v1(22.48,0.53) v1(22.99,48.3) v1(23.14,46.89) v1(23.32,44.62) v1(23.56,72.79) v1(23.55,69.66) v1(24.29,44.65) v1(24.67,51.17) v1(24.67,48.94) v1(24.95,101.44) v1(25.05,102.56) v1(25.79,50.06) v1(26.29,0.53) v1(26.53,17.7) v1(26.53,16.94) v1(26.51,16.06) v1(26.51,15.3) v1(26.9,51.17) v1(26.9,48.94) v1(27.06,16.4) v1(27.06,15.64) v1(27.12,89.32) v1(27.84,96.72) v1(27.86,95.42) v1(27.87,17.63) v1(27.87,16.12) v1(27.87,14.61) v1(28,90.73) v1(28.15,98.1) v1(28.17,97.43) v1(28.76,55.75) v1(28.76,55.16) v1(28.73,50.97) v1(28.86,102.56) v1(29.21,17.63) v1(29.21,14.61) v1(30.1,0.53) v1(30.37,70.98) v1(30.54,17.63) v1(30.54,14.61) v1(31.3,69.61) v1(31.5,9.99) v1(31.88,17.63) v1(31.88,16.12) v1(31.88,14.61) v1(32.14,9.99) v1(32.67,102.56) v1(32.89,79.06) v1(32.9,16.53) v1(32.97,17.43) v1(33.02,18.02) v1(33.22,9.99) v1(33.31,20.09) v1(33.47,82.01) v1(33.84,20.59) v1(33.88,19.82) v1(33.91,9.99) v1(33.91,0.53) v1(34.05,48.58) v1(34.66,18.45) v1(34.68,17.59) v1(34.66,16.54) v1(34.6,15.73) v1(34.8,9.99) v1(34.82,8.03) v1(34.82,7.33) v1(34.82,6.32) v1(34.82,5.68) v1(35.57,9.99) v1(35.64,80.18) v1(35.64,79.6) v1(35.82,52.42) v1(35.82,50.64) v1(36.23,80.08) v1(36.48,102.56) v1(36.53,79.57) v1(37.72,0.53) v1(39.73,102.58) v1(40.02,89.52) v1(40.68,49.43) v1(40.97,89.5) v1(41.09,49.87) v1(41.39,48.63) v1(41.37,10.35) v1(41.5,7.3) v1(41.53,0.53) v1(41.65,50.12) v1(41.89,89.49) v1(42.05,48.52) v1(42.28,50.09) v1(42.58,102.58) v1(42.54,89.48) v1(42.63,48.52) v1(42.75,69.89) v1(42.9,70.94) v1(42.85,68.8) v1(42.9,50.1) v1(43.27,89.47) v1(43.22,48.53) v1(43.4,9.46) v1(43.52,50.08) v1(43.96,89.48) v1(44.15,104.49) v1(44.16,48.72) v1(44.91,101.36) v1(45.05,48.72) v1(45.26,89.47) v1(45.31,79.05) v1(45.31,76.94) v1(45.34,0.53) v1(45.45,106.09) v1(45.56,9.97) v1(45.56,7.43) v1(45.99,101.36) v1(45.98,89.49) v1(46.02,100.26) v1(46.36,78) v1(46.89,107.92) v1(46.81,53.35) v1(46.83,8.32) v1(47.29,44.09) v1(47.35,101.32) v1(47.41,79.05) v1(47.41,76.94) v1(47.76,53.38) v1(47.85,10.48) v1(48.02,44.13) v1(48.72,109.39) v1(49.15,0.53) v1(50.55,89.02) v1(50.53,87.6) v1(50.84,88.49) v1(51.08,87.85) v1(51.1,87.25) v1(51.21,89.12) v1(51.47,88.41) v1(51.49,10.1) v1(52.05,88.44) v1(52.53,109.39) v1(52.63,88.44) v1(52.96,0.53) v1(53.22,32.54) v1(53.87,84.97) v1(54.46,60.89) v1(54.72,73.75) v1(54.72,73.14) v1(54.95,86.78) v1(54.95,86.1) v1(55.15,60.86) v1(55.35,73.75) v1(55.35,73.14) v1(55.58,86.12) v1(55.5,60.34) v1(55.6,86.81) v1(55.82,60.91) v1(56.01,74) v1(56.11,60.36) v1(56.1,9.97) v1(56.34,109.39) v1(56.46,60.91) v1(56.77,60.34) v1(56.77,0.53) v1(56.9,74.25) v1(57.09,60.91) v1(57.41,60.34) v1(57.6,74.25) v1(57.59,43.86) v1(57.59,43.28) v1(57.59,42.68) v1(57.58,42.08) v1(57.72,61.46) v1(57.82,60.88) v1(58.04,73.55) v1(58.07,61.97) v1(58.04,60.34) v1(58.3,74.25) v1(58.3,61.3) v1(58.54,73.17) v1(58.5,60.72) v1(58.68,73.74) v1(58.68,61.87) v1(58.93,61.3) v1(58.93,60.15) v1(59.06,74.25) v1(59.12,73.23) v1(59.19,60.72) v1(59.26,72.02) v1(59.26,70.83) v1(59.26,68.44) v1(59.24,66.08) v1(59.24,64.89) v1(59.24,63.7) v1(59.24,62.5) v1(59.44,73.74) v1(59.44,61.87) v1(59.7,61.3) v1(59.7,60.15) v1(59.82,74.25) v1(59.82,73.23) v1(59.84,67.82) v1(59.89,60.72) v1(60.04,67.26) v1(60.14,73.74) v1(60.14,72.02) v1(60.14,70.83) v1(60.14,69.63) v1(60.14,68.44) v1(60.11,66.08) v1(60.11,64.89) v1(60.11,63.7) v1(60.11,62.5) v1(60.14,61.87) v1(60.36,60.11) v1(60.46,74.31) v1(60.41,61.33) v1(60.5,67.83) v1(60.51,60.72) v1(60.58,0.53) v1(60.62,74.89) v1(60.65,67.26) v1(60.77,61.87) v1(60.82,73.84) v1(60.99,66.08) v1(60.99,64.89) v1(60.99,63.7) v1(60.99,62.5) v1(61.1,75.26) v1(61.01,72.02) v1(61.01,70.83) v1(61.01,69.63) v1(61.01,68.44) v1(61.12,109.39) v1(61.14,67.83) v1(61.22,74.67) v1(61.28,67.26) v1(61.39,74.05) v1(61.66,75.08) v1(61.84,74.48) v1(61.85,67.84) v1(61.93,67.18) v1(62.57,111.45) v1(62.55,67.92) v1(62.54,67.18) v1(64.01,119.4) v1(64.01,113.73) v1(64.39,0.53) v1(65.58,116.9) v1(66.47,118.43) v1(66.47,115.37) v1(66.77,11.62) v1(66.77,10.35) v1(67.24,51.71) v1(67.24,50.18) v1(67.24,48.66) v1(67.84,77.66) v1(68.23,118.43) v1(68.23,115.37) v1(68.2,0.53) v1(68.55,7.43) v1(68.76,51.71) v1(68.76,50.18) v1(68.76,48.66) v1(69.12,116.9) v1(69.86,11.7) v1(70.01,77.49) v1(70.29,51.71) v1(70.29,50.18) v1(70.29,48.66) v1(70.62,77.49) v1(71.27,11.62) v1(71.84,119.4) v1(72.01,0.53) v1(72.23,7.81) v1(72.87,75.9) v1(73.1,114.01) v1(73.1,75.25) v1(73.48,75.88) v1(73.83,75.25) v1(74.08,75.88) v1(74.3,65.17) v1(74.27,9.67) v1(74.68,92.86) v1(75.04,108.93) v1(75.06,65.17) v1(75.38,93.68) v1(75.44,92.86) v1(75.46,11.21) v1(75.49,9.12) v1(75.41,7.18) v1(75.76,65.17) v1(75.82,0.53) v1(76.01,93.68) v1(76.52,65.17) v1(76.7,7.25) v1(77.04,57.56) v1(77.02,56.98) v1(77.02,56.34) v1(77.02,55.71) v1(77.16,67.58) v1(77.16,66.82) v1(77.16,65.99) v1(78.05,66.82) v1(78.13,57.45) v1(78.17,56.86) v1(78.19,56.28) v1(78.19,55.69) v1(78.92,8.63) v1(79.63,0.53) v1(82.17,66.62) v1(82.73,10.36) v1(82.83,11.58) v1(83.09,97.21) v1(83.32,81.93) v1(83.38,64.12) v1(83.44,0.53) v1(84.02,103.52) v1(84.08,81.93) v1(84.3,63.68) v1(84.55,9.84) v1(84.61,103.52) v1(84.71,81.93) v1(84.78,17.75) v1(84.92,7.3) v1(84.93,6.03) v1(85.35,81.93) v1(85.43,17.77) v1(85.98,108.96) v1(85.95,9.34) v1(86.01,17.77) v1(86.16,64.12) v1(86.6,63.68) v1(87.03,6.06) v1(87.25,0.53) v1(87.74,9.97) v1(88.02,113.56) v1(88.07,8.81) v1(88.28,63.7) v1(88.55,119.35) v1(88.69,64.21) v1(88.78,103.9) v1(89.41,103.9) v1(90.05,103.9) v1(90.02,6.15) v1(90.12,10.22) v1(90.12,7.56) v1(90.48,63.68) v1(90.68,103.9) v1(91.04,8.55) v1(91.06,0.53) v1(91.16,98.36) v1(91.32,103.9) v1(91.5,119.4) v1(91.42,115.84) v1(91.5,90.61) v1(92.17,9.97) v1(92.21,8.55) v1(94.77,119.35) v1(94.77,113.71) v1(94.79,102.15) v1(94.81,101.18) v1(94.87,0.53) v1(95.36,10.35) v1(95.35,7.58) v1(96.19,98.27) v1(96.74,9.72) v1(97.16,112.16) v1(97.54,100.68) v1(98.17,100) v1(98.48,7.43) v1(98.68,0.53) v1(100.23,97.15) v1(101.11,100.46) v1(101.44,99.79) v1(102.08,6.41) v1(102.49,0.53) v1(102.98,97.15) v1(103.7,86.57) v1(103.61,6.8) v1(104.27,99.94) v1(104.78,112.16) v1(105.54,109.1) v1(106.3,0.53) v1(106.49,98.74) v1(108.04,72.22) v1(108.27,98.54) v1(108.55,73.79) v1(109.39,98.55) v1(109.62,112.2) v1(109.86,72.18) v1(110.16,17.96) v1(110.55,2.1) v1(110.65,18.46) v1(110.63,17.5) v1(111.17,18.04) v1(111.11,17.12) v1(111.35,118.86) v1(111.31,114.01) v1(111.68,17.61) v1(111.61,16.74) v1(111.77,109.64) v1(111.85,4.35) v1(112.12,17.14) v1(112.27,109.97) v1(112.27,109.34) v1(112.33,72.16) v1(112.51,74.09) v1(113.76,74.65) v1(113.92,103.35) v1(114.02,73.34) v1(114.26,98.12) v1(114.27,97.07) v1(114.31,99.45) v1(114.37,72.34) v1(114.45,4.35) v1(114.78,116.9) v1(115.4,101.95) v1(115.47,73.96) v1(115.67,118.43) v1(115.67,115.37) v1(115.75,2.1) v1(117.43,118.43) v1(117.43,115.37) v1(118.17,119.78) v1(118.24,0.53) v1(118.32,116.9) v1(119.09,106.29) v1(119.25,60.17) v1(119.31,61.71) v1(119.31,60.92) v1(119.33,10.33) v1(119.71,103.98) v1(120.94,103.98) v1(121.15,31.26) v1(121.15,30.55) v1(121.65,62.02) v1(121.72,59.84) v1(121.95,120.29) v1(122.05,0.53) v1(122.16,74.27) v1(122.12,9.58) v1(123.06,106.84) v1(123.91,73.56) v1(123.93,70.55) v1(124.17,7.3) v1(124.39,107.43) v1(124.38,106.83) v1(124.49,72.13) v1(125.86,70.35) v1(125.86,0.53) v1(126.73,77.62) v1(127.15,84.33) v1(127.97,72.95) v1(127.98,72) v1(128.02,85.04) v1(128.56,110.03) v1(128.68,110.61) v1(128.68,85.03) v1(129.15,104.96) v1(129.14,10.2) v1(129.27,110.84) v1(129.57,117.24) v1(129.67,0.53) v1(129.95,105.4) v1(129.94,76.6) v1(130,7.56) v1(130.35,112.08) v1(130.51,10.35) v1(130.64,105.4) v1(130.79,117.67) v1(130.84,112.59) v1(130.83,111.64) v1(130.89,71.38) v1(131.3,112.08) v1(131.47,117.67) v1(131.45,71.57) v1(131.65,7.3) v1(132.18,117.67) v1(132.72,90.57) v1(132.79,9.46) v1(132.87,72.71) v1(133.48,0.53) v1(134.17,107.61) v1(134.15,106.86) v1(136.22,10.22) v1(136.68,119.86) v1(137.29,0.53) v1(137.33,7.26) v1(138.49,115.75) v1(138.75,120.29) v1(139.08,107.99) v1(139.32,115.76) v1(139.35,102.96) v1(139.51,108.44) v1(139.53,8.07) v1(140.18,118.9) v1(140.21,102.97) v1(140.68,114.92) v1(140.75,109.72) v1(141.07,117.37) v1(141.18,102.97) v1(141.1,0.53) v1(141.23,110.23) v1(141.22,109.26) v1(141.43,7.3) v1(141.7,109.72) v1(142.83,117.37) v1(143.28,105.52) v1(143.72,118.9) v1(143.88,120.21) v1(143.94,105.52) v1(144.91,0.53) v1(147.14,66.29) v1(147.15,65.64) v1(147.35,11.57) v1(147.76,9.31) v1(148.24,8.88) v1(148.72,0.53) v1(148.98,108.98) v1(149.02,6.77) v1(149.61,108.98) v1(150.74,11.53) v1(150.7,10.17) v1(151.26,106.83) v1(151.91,106.82) v1(152.33,120.29) v1(152.48,11.65) v1(152.48,10.38) v1(152.5,6.1) v1(152.53,0.53) v1(152.61,7.33) v1(153.02,106.8) v1(153.7,106.8) v1(154,6.19) v1(155.08,11.45) v1(155.02,9.41) v1(155.15,117.32) v1(155.28,116.71) v1(155.44,112.16) v1(155.53,7.96) v1(155.55,6.01) v1(155.63,117.72) v1(155.68,114.52) v1(155.78,117.11) v1(156.14,120.29) v1(156.15,112.96) v1(156.12,111.35) v1(156.26,116.26) v1(156.26,115.63) v1(156.27,115.04) v1(156.39,116.93) v1(156.34,0.53) v1(156.7,7.23) v1(157.87,67.07) v1(157.87,66.44) v1(157.87,65.8) v1(157.87,65.17) v1(158.17,7.79) v1(158.11,6.21) v1(158.25,45.99) v1(158.63,45.48) v1(158.63,38.75) v1(159.31,38.04) v1(159.95,120.29) v1(160.15,0.53) v1(160.48,7.44) v1(160.6,10.44) v1(162.03,6.01) v1(162.69,2.3) v1(163.76,120.29) v1(164.06,6.27) v1(164.93,10.48) v1(164.95,6.22) v1(165.05,7.3) v1(165.49,3.51) v1(165.55,37.42) v1(165.55,35.9) v1(165.94,9.72) v1(165.99,6.24) v1(166.45,2.58) v1(166.76,0.53) v1(166.97,118.34) v1(166.94,117.38) v1(166.95,113.85) v1(167.01,115.42) v1(167.07,38.94) v1(167.07,37.42) v1(167.07,35.9) v1(167.03,6.24) v1(167.33,117.85) v1(167.47,117.07) v1(167.57,120.29) v1(167.58,118.56) v1(167.69,114.62) v1(167.92,118.01) v1(167.97,7.3) v1(168,117.33) v1(168.33,118.46) v1(168.46,117.75) v1(168.48,10.1) v1(168.6,37.42) v1(168.6,35.9) v1(168.98,33.67) v1(169.49,33.04) v1(170.01,7.3) v1(170.26,10.22) v1(170.57,0.53) v1(171.38,120.29) v1(172.55,8.07) v1(172.93,16.55) v1(173.39,10.51) v1(173.43,17.38) v1(173.5,16.79) v1(173.74,104.98) v1(173.74,104.35) v1(173.74,103.21) v1(173.74,102.51) v1(173.74,101.43) v1(173.74,100.73) v1(174.27,10.28) v1(174.38,0.53) v1(174.45,7.3) v1(175.19,120.29) v1(175.38,93.55) v1(175.59,7.3) v1(176.23,9.59) v1(176.58,7.38) v1(177.75,10.35) v1(178.57,0.53) v1(179,120.29) v1(179.78,10.33) v1(180.36,95.13) v1(180.36,93.63) v1(181.11,94.38) v1(181.18,91.97) v1(181.36,98.09) v1(181.36,97.48) v1(181.36,96.89) v1(181.68,91.65) v1(181.74,120.29) v1(181.95,98.09) v1(181.95,97.48) v1(181.95,96.89) v1(182.38,0.53) v1(182.53,98.09) v1(182.53,97.48) v1(182.53,96.89) v1(182.96,7.94) v1(184.99,7.3) v1(185.01,46.88) v1(185.17,34.96) v1(185.27,49.9) v1(185.68,83.95) v1(185.68,83.33) v1(185.68,82.06) v1(185.67,81.46) v1(185.67,80.81) v1(185.67,80.16) v1(185.67,79.44) v1(185.7,82.67) v1(186.19,0.53) v1(186.74,38.73) v1(186.95,48.64) v1(187.14,118.06) v1(187.15,114.5) v1(187.15,110.69) v1(187.15,106.88) v1(187.15,103.07) v1(187.15,99.26) v1(187.15,95.45) v1(187.15,91.64) v1(187.15,87.83) v1(187.15,84.02) v1(187.15,80.21) v1(187.15,76.4) v1(187.23,72.89) v1(187.34,49.84) v1(187.49,38.74) v1(187.81,68.52) v1(188.01,35.76) v1(188.36,49.79) v1(188.63,65.27) v1(188.71,46.91) v1(189.06,48.54) v1(189.62,62.32) v1(190,0.53) v1(190.26,49.81) v1(190.66,45.59) v1(190.86,46.84) v1(190.99,59.15) v1(191.99,33.31) v1(191.9,16.53) v1(192.47,45.48) v1(192.87,55.82) v1(192.95,6.7) v1(192.95,6.11) v1(193.49,44.33) v1(193.81,0.53) v1(194.24,4.74) v1(194.24,2.93) v1(195.28,4.74) v1(195.28,2.93) v1(195.64,52.01) v1(195.84,6.65) v1(195.83,6.03) v1(197.62,0.53) v1(198.51,48.91) v1(200.15,37.1) v1(201.45,39.35) v1(201.45,34.85) v1(201.43,0.53) v1(202.06,45.92) v1(202.88,7.61) v1(204.05,39.35) v1(204.05,34.85) v1(205.24,0.53) v1(205.35,37.1) v1(205.52,43.63) v1(209.05,0.53) v1(209.17,41.75) v1(212.83,40.35) v1(212.86,0.53) v1(215.99,7.38) v1(216.36,31.59) v1(216.51,39.39) v1(216.57,7.26) v1(216.67,0.53) v1(220.43,38.78) v1(220.48,0.53) v1(224.29,0.53) v1(225.1,18.36) v1(225.48,38.6) v1(228.1,0.53) v1(230.18,38.6) v1(231.91,0.53) v1(232.14,2.43) v1(234.19,3.45) v1(234.52,38.96) v1(235.39,2.35) v1(235.51,0.53) v1(238.4,1.5) v1(238.69,39.85) v1(239.7,3.75) v1(242.3,41.01) v1(242.3,3.75) v1(242.65,11.45) v1(243.54,13.89) v1(243.6,1.5) v1(243.74,9.01) v1(244.73,42.03) v1(246.89,0.53) v1(247.02,15.08) v1(247.05,7.14) v1(247.05,4.16) v1(247.27,42.89) v1(250.68,17.69) v1(252.46,45.59) v1(253.37,37.81) v1(254.49,17.69) v1(256.21,50.36) v1(258.3,17.7) v1(258.81,53.46) v1(261.09,56.91) v1(262.11,17.69) v1(262.29,48.13) v1(262.29,47.01) v1(262.9,60.39) v1(263.4,48.13) v1(263.4,47.01) v1(263.4,45.89) v1(264,54.73) v1(264.14,63.57) v1(264.52,48.13) v1(264.52,45.89) v1(265.08,66.74) v1(265.05,58.9) v1(265.79,70.53) v1(266,17.7) v1(266.2,104.41) v1(266.17,96.59) v1(266.17,92.78) v1(266.17,88.97) v1(266.17,85.16) v1(266.17,81.35) v1(266.15,77.54) v1(266.12,73.75) v1(266.35,61.15) v1(266.35,56.65) v1(267.05,101.4) v1(267.15,118.5) v1(267.14,115.84) v1(267.17,112.92) v1(267.16,110.62) v1(267.29,108.08) v1(267.25,104.55) v1(268.1,22.37) v1(268.35,103.65) v1(268.35,99.15) v1(268.94,118.51) v1(268.95,61.15) v1(268.95,56.65) v1(269.08,107.91) v1(269.08,104.69) v1(270,106.3) v1(270.25,58.9) v1(270.9,22.7) v1(270.95,103.65) v1(270.95,99.15) v1(271.63,118.46) v1(271.66,114.85) v1(272.25,101.4) v1(272.5,113.15) v1(272.91,26.86) v1(274.07,22.7) v1(275.09,42.89) v1(275.63,43.25) v1(275.77,112.97) v1(275.85,50.18) v1(276.57,56.19) v1(276.99,86.89) v1(276.99,85.62) v1(276.99,84.35) v1(277.69,55.07) v1(277.88,22.7) v1(278.26,86.89) v1(278.26,85.62) v1(278.26,84.35) v1(278.81,53.95) v1(279.14,64.87) v1(279.44,94.06) v1(279.58,112.97) v1(279.53,86.89) v1(279.53,85.62) v1(279.53,84.35) v1(280.3,110.4) v1(281.22,112.01) v1(281.22,108.79) v1(281.42,94.03) v1(281.69,22.7) v1(283.08,112.01) v1(283.08,108.79) v1(283.96,38.2) v1(284,110.4) v1(284.59,113) v1(285.07,85.03) v1(285.5,22.7) v1(285.97,85.05) v1(285.94,83.72) v1(286.18,65.2) v1(286.18,64.08) v1(286.18,62.97) v1(286.26,84.22) v1(286.71,83.77) v1(286.87,118.33) v1(286.9,85.06) v1(287.3,65.2) v1(287.3,64.08) v1(287.3,62.97) v1(287.53,94.51) v1(287.76,111.52) v1(288.17,94.51) v1(288.41,65.2) v1(288.41,64.08) v1(289.31,22.7) v1(290.02,65.92) v1(290.14,57.08) v1(290.14,55.96) v1(290.14,54.84) v1(290.25,94.53) v1(290.47,62.71) v1(291.25,57.08) v1(291.25,55.96) v1(292.22,94.56) v1(293.12,22.7) v1(295.15,94.51) v1(296.93,22.7) v1(300.51,57.52) v1(300.51,55.29) v1(300.74,22.7) v1(301.63,57.52) v1(301.63,56.41) v1(301.63,55.29) v1(302.29,64.25) v1(302.75,57.52) v1(302.75,56.41) v1(302.75,55.29) v1(304.37,43.92) v1(304.55,22.7) v1(304.93,39.39) v1(305,43.91) v1(305.06,40.79) v1(305.12,28.47) v1(305.36,111.14) v1(305.9,118.33) v1(306.17,55.33) v1(306.1,44.82) v1(306.61,90.65) v1(306.68,44.82) v1(307.09,54.37) v1(307.23,90.73) v1(307.27,44.82) v1(308.04,98.9) v1(308.12,60.22) v1(308.36,22.7) v1(308.74,60.84) v1(308.74,59.59) v1(309.1,100.73) v1(309.1,97.07) v1(310.2,32.85) v1(310.37,110.99) v1(311.2,100.73) v1(311.2,97.07) v1(312.17,22.7) v1(312.26,98.9) v1(312.31,62.46) v1(312.45,106.01) v1(312.67,63.13) v1(312.67,61.94) v1(312.77,61.36) v1(312.92,62.49) v1(314.66,71.54) v1(315.14,55.39) v1(315.12,44.06) v1(315.47,71.52) v1(315.47,20.34) v1(315.64,22.4) v1(317.01,24.23) v1(317.01,20.57) v1(317.66,57.5) v1(319.09,24.23) v1(319.09,20.57) v1(320.46,22.4) v1(321.44,20.21) v1(321.8,22.4) v1(322.25,100.45) v1(322.43,85.74) v1(322.48,72.81) v1(322.72,24.01) v1(322.72,20.79) v1(324.16,67.63) v1(324.13,62.71) v1(324.13,57.32) v1(324.58,24.01) v1(324.58,20.79) v1(325.13,90.34) v1(325.43,40.79) v1(325.5,22.4) v1(326.14,20.34) v1(326.27,96.23) v1(326.29,92.5) v1(326.27,23.89) v1(327.54,26.56) v3(6.1,11.32) v3(10.17,99.75) v3(10.55,83.84) v3(11.44,64.79) v3(14.86,103.65) v3(16.13,67.84) v3(27.31,17.42) v3(44.46,100.98) v3(51.77,87.24) v3(53.73,74.06) v3(55.38,74.76) v3(56.65,58.44) v3(58.68,58.18) v3(70.87,75.08) v3(76.08,66.31) v3(88.78,65.49) v3(92.21,111.78) v3(113.04,20.34) v3(157.99,67.84) v3(174.12,19.07) v3(181.95,98.82) v3(268,32.97) v3(270.77,27.7) v3(275.91,106.95) v3(280.1,86.31) v3(309,105.81) v3(318.52,41.8) v3(318.78,58.18) v3(318.9,41.67) v3(318.9,26.43)
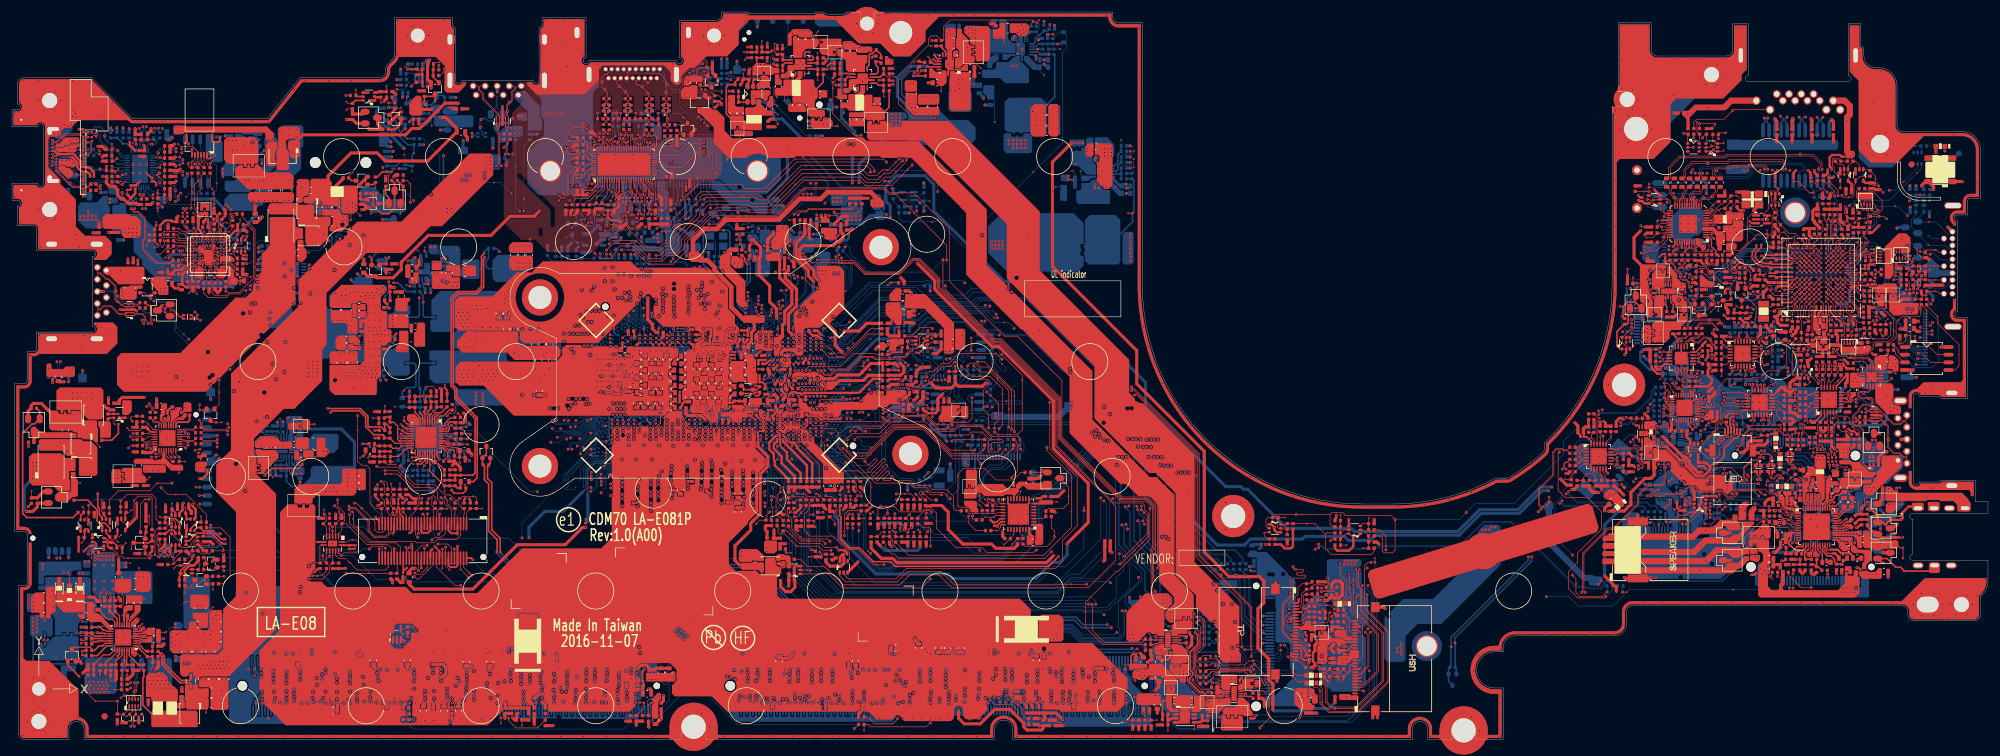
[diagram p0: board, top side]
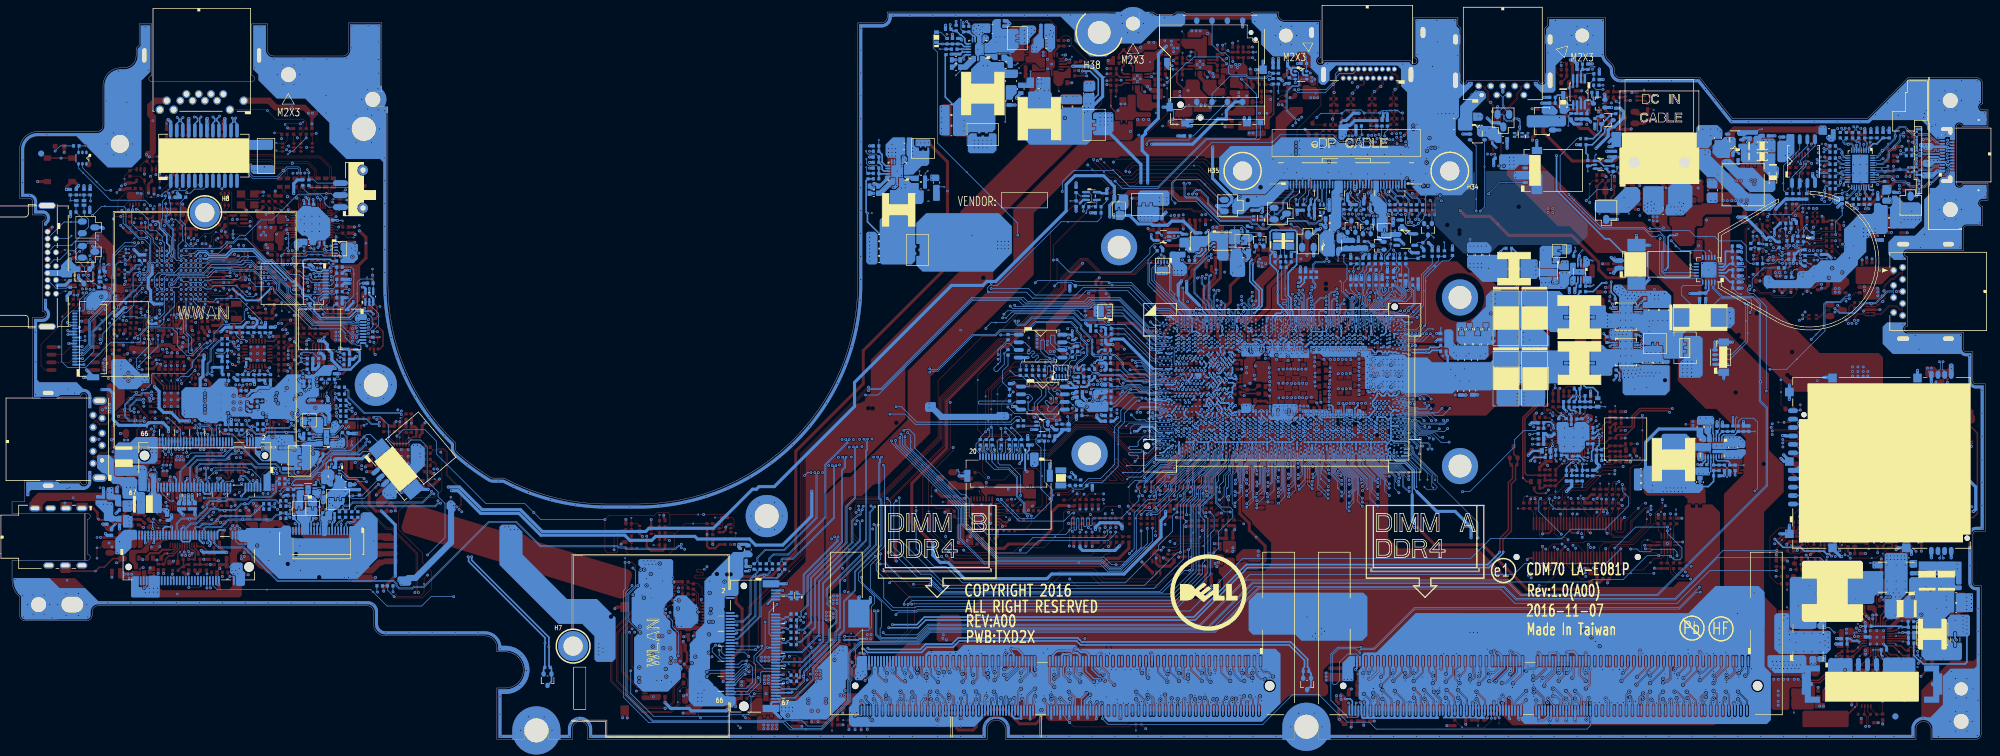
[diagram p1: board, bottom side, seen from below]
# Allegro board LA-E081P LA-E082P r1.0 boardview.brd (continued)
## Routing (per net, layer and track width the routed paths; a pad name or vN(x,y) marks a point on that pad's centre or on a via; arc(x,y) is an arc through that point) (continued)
GNDA: length 15.7
  TOP w0.127: v3(313.95,30.09) v3(313.95,31.82) 313.43,31.82 CA2.2 ; v1(312.87,41.74) 312.93,41.8 v3(313.44,41.8)
  TOP w0.203: v1(302.52,39.39) 302.02,39.39 301.4,38.77 UA1.38
  TOP w0.254: CA57.2 301.99,40.7 v1(302.07,40.79)
  TOP w0.381: v1(302.07,40.79) 302.2,40.79 CA58.2
  TOP w0.508: v1(301.25,29.61) 301.44,29.42 CA25.2 ; DA2.2 v1(311.46,31.97) ; RA37.1 v1(295.15,29.04) ; CA41.2 v1(296.22,29.91) ; CA2.2 v1(311.94,32.63)
  BOTTOM w0.508: CA1.1 313.81,40.28 CA4.2 312.87,40.29 v1(312.87,41.74) ; v1(312.55,34.18) 312.27,33.9 CA3.2
  vias: v1(303.6,43.2) v1(303.54,32.02) v1(304.93,31.96) v1(319.28,39.26)
VBAT1_ISL88738: length 4
  TOP w0.203: PU901.31 19.45,13.95 v2(20.08,13.31) PC950.2 PR940.2
VBUS1_ECOK: length 18.6
  TOP w0.102: PR1220.2 16.16,38.48 ; 16.16,38.48 16.16,39.79 17.66,41.29 22.87,41.29 v2(24.14,42.56) v1(26.55,42.56) ; 16.16,38.48 PR1222.1 ; v1(25.34,30.39) 24.91,30.39 24.25,31.05 24.25,31.81 24.58,32.14 24.58,32.59 24.52,32.66 PR1257.1
  BOTTOM w0.102: v1(49.36,78.2) 49.15,78 UE2.13
VBUS2_ECOK: length 37.7
  TOP w0.102: v1(62.5,105.71) PR20.2 63.1,106.16 PR24.1 ; PR1242.1 26.22,30.76 v1(26.68,30.31)
  BOTTOM w0.102: v1(54.44,83.18) 54.56,83.05 54.56,77.35 53.72,76.51 47.54,76.51 47.36,76.33 UE2.16 47.36,75.56 47.51,75.41 50.59,75.41 50.92,75.08 50.92,73.86 49.09,72.03 45.73,72.03 v2(44.75,73) 44.58,73.17 39.5,73.17 39.25,72.92 39.25,71.27 39.5,71.01 v1(39.5,70.88)
VCC_CPU: length 6
  TOP w0.102: PR602.1 74.31,46.06 v2(74.43,45.95)
  TOP w0.203: PC603.1 73.87,48.46 73.07,48.46 72.78,48.75 72.78,48.94 72.46,49.26 72.26,49.26 71.93,49.58 PU602.34
  TOP w0.254: PR602.1 74.31,47.9 PC603.1
VCC_GT_SENSE: length 11
  TOP w0.254: PC617.1 69.55,57.83 PR622.1 68.89,56.99 v1(68.84,57.04) 68.64,56.85 PC620.1
  BOTTOM w0.076: UC1.J70 97.46,64.83 97.19,64.56 95.95,64.56 95.66,64.27 95.55,64.27 95.52,64.24 95.44,64.24
  BOTTOM w0.254: RC161.1 91.02,64.61 92.31,64.61 92.68,64.24 v1(93.25,64.24) 95.44,64.24 ; PC618.2 69.56,56.32 v1(68.84,57.04)
VCCIO_SENSE: length 2.5
  TOP w0.254: PR422.2 145.75,108.76 v1(146.28,108.76) ; v1(123.37,53.06) 122.63,53.8 RC165.1
  BOTTOM w0.254: v1(123.37,53.06) 123.77,53.45 UC1.AM23
VCCSA_B+:
  vias: v1(69.97,79.16) v1(70.58,79.16) v2(73.78,81.25)
VCCSENSE: length 22.8
  TOP w0.254: PC653.1 62.74,51.78 PR648.1 62.09,52.46 PC639.1 61.88,52.39 PC651.2 61.32,51.89 59.31,51.89 59.08,52.12 59.08,53.7 57.83,54.95 v1(52.41,54.95)
  BOTTOM w0.076: UC1.E32 118.77,67.48 118.77,67.94 118.84,68 118.84,68.24 118.76,68.31 118.76,68.52 118.83,68.59 118.83,68.86 118.78,68.91 118.78,70.03
  BOTTOM w0.254: 118.78,70.03 118.78,70.11 118.12,70.77 117.44,70.77 v1(117.18,71.02) ; RC140.1 113.49,76.54 113.49,75.91 114.18,75.22 114.54,75.22 v1(114.54,75.23)
VCCST_PWRGD: length 74.7
  TOP w0.102: RC123.1 68.04,39.36 v1(68.04,40.05) ; RE308.1 306.28,87.82 306.28,88.34 306.07,88.55 v1(306.07,88.8) ; v1(98.69,81.26) 99.82,82.39 103.29,82.39 105.83,79.85 107.79,79.85 108.75,80.8 110.1,80.8 111.15,81.85 111.15,83.02 115.74,87.61 116.19,87.61 116.86,88.28 121.93,88.28 122.29,87.92 125.95,87.92 131.41,93.39 140.88,93.39 141.79,92.47 144,92.47 144.91,93.39 145.91,93.39 v2(146.79,94.27) 148.47,95.94 v1(148.47,96.31) ; v1(288.53,85.27) 288.63,85.16 290.39,85.16 290.95,85.73 UE4.4
  BOTTOM w0.102: 96.71,77.12 97.08,76.74 97.08,75.07 96.58,74.56 v1(96.22,74.56) ; 96.71,77.12 RC78.1 97.34,77.35 97.34,78.67 RC71.1 97.89,79 98.2,79.31 98.2,80.77 v1(98.69,81.26) ; 96.71,77.12 CC301.1
VCCST_PWRGD_CPU: length 10.5
  BOTTOM w0.076: UC1.B65 100.91,69.37 100.91,69.84 100.69,70.06 100.69,70.64 99.64,71.69 99.64,72.32 99.34,72.62
  BOTTOM w0.102: RC78.2 97.41,76.05 v2(97.41,75.3) 97.41,75.13 96.61,74.33 96.61,73.48 97.22,72.88 99.08,72.88 99.34,72.62
VCCST_PWRGD_EC: length 10
  TOP w0.102: v1(305.94,85.86) 306.6,86.52 RE308.2 v2(307.6,86.52)
  TOP w0.107: v1(303.16,79.51) 303.16,79.5 303.14,79.5 UE1.K10
  BOTTOM w0.102: v1(305.94,85.86) 305.94,84.59 304.62,83.27 304.62,82.64 303.57,81.59 303.57,79.92 v1(303.16,79.51)
VCCSTG_EN: length 147.6
  TOP w0.102: v1(131.68,80.16) 132.62,79.22 137.06,79.22 137.25,79.02 139.76,79.02 141.57,77.21 147.37,77.21 149.66,79.5 150.51,79.5 153.62,76.4 153.62,74.92 162.89,65.65 164.02,65.65 173.28,56.38 173.28,48.65 183.24,38.69 183.24,29.77 178.66,25.19 156.01,25.19 153.88,27.32 149.03,27.32 147.38,25.67 138,25.67 134.95,28.72 132.09,28.72 130.88,29.92 RZ120.1
  BOTTOM w0.254: v1(137.17,83.71) 137.62,84.17 UZ35.4 ; UZ19.4 129.88,81.11 v2(130.54,80.45) 130.71,80.28 131.55,80.28 v1(131.68,80.16) RZ320.2
VDD_ISL88738: length 10.7
  TOP w0.203: 15.25,18.12 15.56,18.12 15.72,17.96 PU901.18
  TOP w0.254: 15.25,18.12 15.18,18.12 v2(14.8,18.5) 14.65,18.65 v1(14.24,18.65) 13.29,18.65 PR919.1
  BOTTOM w0.254: PR918.2 13.24,18.68 PC933.1 v1(14.24,18.65) 14.39,18.8 PR915.2
VDDP_ISL88738: length 3.2
  TOP w0.127: v1(21.15,18.75) v2(21.61,19.21)
  TOP w0.203: PU901.8 20.76,18.36 v1(21.15,18.75)
  BOTTOM w0.254: v1(21.15,18.75) 21.1,18.8 PR915.1 20.34,18.79 PC932.2
VIN_1V_PRIM: length 2.1
  TOP w0.102: 133.48,115.65 133.48,117.25 v2(133.81,117.58)
VIN_1VS_VCCIO:
  vias: v2(139.13,112.48)
VIN_CPU: length 3.9
  TOP w0.203: PU602.33 71.92,49.18 v1(72.29,48.81)
  BOTTOM w0.102: v1(72.29,48.81) v2(72.29,49.33)
  BOTTOM w0.203: v1(72.29,48.81) 72.29,48.74 72.65,48.38 PC604.1 72.65,46.9 PR603.1
VSS_GT_SENSE: length 12.2
  TOP w0.203: PC620.2 68.56,55.04 68.56,54.73 68.38,54.55 v1(68.38,54.33) 68.56,54.14 PU602.6
  BOTTOM w0.076: 95.29,64.75 95.3,64.74 96.31,64.74 96.68,65.11 96.92,65.11 97.05,65.04 97.26,65.04 97.4,65.12 97.77,65.12 98.06,64.83 UC1.J69
  BOTTOM w0.254: 95.29,64.75 92.93,64.75 v1(92.84,64.84) 92.84,64.86 92.59,65.12 v2(91.88,65.12) 91.18,65.12 RC163.1 ; v1(68.38,54.33) 68.71,54.65 69.25,54.65 69.56,54.96 PC619.2
VSSIO_SENSE: length 2.4
  TOP w0.254: PR412.2 145.75,109.39 v1(146.28,109.39) ; v1(124.29,53.06) 123.58,53.77 RC167.1
  BOTTOM w0.254: v1(124.29,53.06) 124.68,53.45 UC1.AM22
VSSSENSE: length 23
  TOP w0.203: PC654.2 61.82,50.03 PC653.2 63.58,49.18 PU602.18
  TOP w0.254: v1(52.86,54.33) 53.1,54.57 57.67,54.57 58.7,53.54 58.7,51.96 60.06,50.61 61.54,50.61 61.8,50.35 PC654.2
  BOTTOM w0.076: 118.33,69.4 118.33,69.04 118.21,68.93 118.21,68.63 118.27,68.57 118.27,68.26 118.2,68.2 118.2,67.93 118.34,67.79 UC1.E33
  BOTTOM w0.254: 118.33,69.4 118.33,69.89 117.87,70.35 117.02,70.35 v1(116.81,70.55) ; RC141.1 114,76.58 114,76.12 114.27,75.85 v1(114.54,75.85)
32KHZ_OUT: length 10.3
  TOP w0.102: CE54.1 298.07,64.53 v1(298.21,64.67)
  TOP w0.107: v1(299.16,73.13) UE1.F3
  BOTTOM w0.102: v1(298.21,64.67) 298.21,66.67 299.17,67.62 v2(299.17,68.7) 299.17,73.12 v1(299.16,73.13)
+AC_IN: length 7.8
  TOP w0.102: PR1255.1 13.98,49.22 v2(14.61,48.58)
  TOP w0.508: 6.42,54.25 4.87,55.8 3.53,55.8 3.17,55.44 PR1251.1 2.66,54.5 PQ1215.3
+BL_PWR_SRC: length 4.2
  TOP w0.102: v3(108.56,82.72) v1(108.56,84.35) ; v1(108.56,84.35) v3(107.87,84.35) ; v1(108.56,84.35) 109.03,84.35 v3(110.04,85.35)
+CHARGER_SRC:
  vias: v1(6.75,24.74) v1(6.93,23.79) v1(6.94,23.16) v1(6.93,21.96) v2(5.97,25.29)
+COINCELL: length 3.4
  TOP w0.508: PC2.2 62.12,78.07 PR2.1 v1(62.12,77.44)
  BOTTOM w0.127: v1(62.12,77.44) v2(62.75,77.44)
  BOTTOM w0.508: JRTC1.1 61.39,78.28 62.12,77.54 v1(62.12,77.44)
+CRT_VCC: length 9.7
  TOP w0.127: RV119.2 317.05,80.01 316.31,80.75 v2(316.31,81.36)
  TOP w0.203: v1(281.27,53.63) 281.14,53.5 280.56,53.5 280.38,53.67 UV6.17
  TOP w0.381: v1(315.73,74.82) 315.73,75.31 RV121.2 ; v1(317.15,73.78) 316.97,73.96 RV120.2
  TOP w0.508: RV122.2 315.6,77.46 315.33,77.2 v1(315.33,77.08) ; v1(318.29,79.65) 317.93,80.01 RV119.2
  BOTTOM w1.016: 319.41,77.74 319.7,77.46 322.15,77.46 JCRT1.9
  vias: v1(281.57,54.14) v1(318.39,78.02)
+DC_IN: length 31.9
  TOP w0.254: PR1201.1 v1(65.65,111.31)
  TOP w0.508: 52.48,92.69 52.48,93.59 56.29,97.4 60.63,97.4 v2(61.29,96.74) 61.96,96.07 69.01,96.07 PC11.1 73.84,101.46 72,103.3 v1(71.14,103.3)
+DC_IN_SS: length 8.9
  TOP w0.254: v1(10.41,25.06) 11.26,25.92 PD904.2
  BOTTOM w0.254: v1(53.53,77.99) 53.09,78.43 53.09,83.46 52.84,83.71 v2(52.3,83.71) 51.82,83.71 v1(51.66,83.87)
+DCIN_JACK: length 2.4
  TOP w0.102: v3(56.19,86.25) 56.27,86.33 56.27,87.52 ; 57.03,87.78 v3(57.79,87.01)
  vias: v1(55.36,88.92) v1(55.51,88.22) v1(55.9,89.33) v1(55.89,87.78) v1(55.93,88.73) v1(56.49,89.02) v1(56.52,88.41) v1(56.52,87.75) v1(57.07,88.72) v1(57.04,88.12) v3(55.12,87.78)
+DCPRTC: length 11.8
  TOP w0.102: CC214.1 v1(139.2,40.4)
  BOTTOM w0.076: UC1.BB10 131.9,46.81 132.86,45.85 133.41,45.85 134.92,44.34 135.39,44.34
  BOTTOM w0.102: v1(139.2,40.4) 139.08,40.4 138.46,41.02 138.46,42.08 v2(137.39,43.15) 136.2,44.34 135.39,44.34
+DDR_VREF_A_CA: length 7.3
  TOP w0.508: v1(82.03,6.22) 81.92,6.11 CD25.1 CD26.1 RD17.1 v2(84.88,5.24) 85.73,5.24 RD15.2 RD16.1
  BOTTOM w0.254: JDIMM1.164 v1(82.03,6.22)
+DDR_VREF_A_DQ: length 2.9
  TOP w0.102: v1(98.61,47.6) 98.61,45.77 T132.1
  BOTTOM w0.102: v1(98.61,47.6) UC1.AY68
+DDR_VREF_B_CA: length 9.9
  TOP w0.508: RD30.1 171.48,3.48 RD28.2 ; CD58.1 CD57.1 RD29.1 RD28.2 ; v1(174.41,3.32) v2(173.33,4.4) RD28.2
  BOTTOM w0.254: JDIMM2.164 v1(163.03,6.97)
+DDR_VREF_B_DQ: length 42.6
  TOP w0.508: CD62.1 RD30.2 171.2,1.84 170.93,1.57 168.51,1.57 167.96,2.12 167.96,2.7 165.67,4.99 163.15,4.99 160.76,2.6 158.08,2.6 157.14,3.54 v1(157.14,4.86)
  BOTTOM w0.152: 98.43,46.38 98.93,46.88 98.93,47.26 99.25,47.58 UC1.BA67
  BOTTOM w0.203: 98.43,46.38 98.22,46.17 96.69,46.17 95.26,44.74 95.26,41.61 94.8,41.15
  BOTTOM w0.508: 94.8,41.15 91.52,37.87 88.46,37.87 85.82,35.23 v1(85.82,33.5)
+DDR_VREF_CA: length 18.8
  TOP w0.203: v1(95.23,35.92) v2(95.23,36.66)
  TOP w0.508: v1(83.11,3.59) 83.45,3.25 CD31.1 83.75,4.12 RD17.2
  BOTTOM w0.203: 95.58,40.68 95.58,44.65 96.79,45.86 99.29,45.86 99.78,46.34 99.78,46.96 99.59,47.15 99.59,48.17 99.37,48.39 UC1.AY67
  BOTTOM w0.508: v1(95.23,35.92) 95.58,36.27 95.58,40.68
+EC_DEBUG_VCC: length 10.9
  BOTTOM w0.254: JDEG1.1 276.48,77.9 276.7,77.68 277.5,77.68 277.73,77.91 278.31,77.91 278.8,78.39 279.51,78.39 279.77,78.64 279.77,79.44 279.51,79.7 278.97,79.7 278.92,79.75 v2(277.46,79.75) 277.44,79.72 275.21,79.72 274.95,79.46 RE71.2
+EDP_VDD: length 1.3
  TOP w0.127: v2(99.13,82.99) 99.58,83.44 v1(100.28,83.44)
+LCDVDD: length 7.1
  TOP w0.127: v1(99.95,85.49) 99.42,85.49 v3(98.74,86.17) ; v1(99.95,85.49) 99.95,85.24 99.18,84.46 v3(98.46,84.46) ; v1(99.95,85.49) 100.34,85.49 100.46,85.36 100.46,84.38 v3(100.17,84.09)
  BOTTOM w0.508: v1(103.51,90.49) 103.51,89.78 103.64,89.66 RV7.2
+LINE1-VREFO-L:
  vias: v2(304.58,36.06)
+LINE1-VREFO-R:
  vias: v2(303.74,35.1)
+MIC2-VREFO: length 4.9
  TOP w0.203: UA1.29 304.41,34.72 v1(304.72,35.03)
  BOTTOM w0.127: v1(304.72,35.03) 304.72,36 v2(304.91,36.19)
  BOTTOM w0.508: v1(310.22,34.94) RA6.1 ; RA5.1 v1(310.78,37.55)
+PBATT: length 9.1
  TOP w0.254: 23.98,3.39 23.98,3.46 v2(22.07,5.36) 21.72,5.71 21.72,10.23 21.87,10.38 PR940.1
+PECI_VREF: length 12.1
  TOP w0.102: CE25.1 304.23,87.28 304.23,88.4 v2(304.4,88.56)
  TOP w0.254: v1(302.36,80.33) UE1.J11 ; v1(304.68,86.05) 304.63,86.1 CE25.1 304.99,86.52 RE59.2
  BOTTOM w0.254: v1(304.68,86.05) 303.84,86.05 303.55,85.76 303.55,84.93 302.37,83.75 302.37,82.44 301.88,81.96 301.88,80.94 302.36,80.47 v1(302.36,80.33)
+PWR_SRC: length 129.1
  TOP w0.508: v1(209.33,4.92) 209.33,9.18 208.64,9.87 208.64,13.37 206.85,15.17 206.85,21.72 207.83,22.7 207.83,26.33 207.12,27.04 202.05,27.04 197.93,31.16 197.93,47.86 186.72,59.07 186.72,64.58 172.74,78.57 v3(172.74,91.08) 172.74,95.9 v1(175.92,99.08) ; PD901.2 v1(7.83,25.07) ; RZ85.1 v1(219.64,6.11)
  BOTTOM w0.254: PR102.2 v1(171.31,119.27)
  BOTTOM w0.508: v1(209.33,4.92) 209.51,4.74 215.26,4.74 215.67,5.16 218.68,5.16 v1(219.64,6.11) ; PR929.2 v1(25.16,16.74)
  vias: v1(31.15,12.38) v1(31.4,11.78) v1(31.79,12.34) v1(32.04,11.78) v1(32.42,12.34) v1(32.67,11.78) v1(33.06,12.34) v1(33.21,12.93) v1(33.31,11.78) v1(33.69,12.34) v1(33.84,12.93) v1(33.94,11.78) v1(34.33,12.34) v1(34.48,12.93) v1(34.58,11.78) v1(34.96,12.34) v1(35.11,12.93) v1(35.21,11.78) v1(35.6,12.34) v1(35.75,12.93) v1(35.95,11.83) v1(49.16,62.75) v1(49.18,62.15) v1(49.19,61.55) v1(49.21,60.94) v1(49.2,60.29) v1(49.93,62.75) v1(49.92,62.14) v1(49.95,61.54) v1(49.95,60.94) v1(49.96,60.32) v1(50.67,62.74) v1(50.68,62.14) v1(50.68,61.55) v1(50.66,60.95) v1(50.66,60.32) v1(72.27,88.16) v1(72.27,87.52) v1(73.03,88.16) v1(73.03,87.52) v1(78.7,94.88) v1(78.75,96.69) v1(78.74,96.09) v1(78.7,95.48) v1(79.4,95.46) v1(79.37,94.86) v1(79.44,96.67) v1(79.42,96.06) v1(106.51,83.39) v1(107.2,83.94) v1(107.18,83.27) v1(107.27,82.62) v1(158.29,117.76) v1(158.76,118.12) v1(158.76,117.27) v1(159.39,118.03) v1(159.39,117.39) v1(159.36,116.73) v1(159.36,116.05) v1(160,117.75) v1(160,117.11) v1(159.97,116.45) v1(159.97,115.77) v1(176.54,99.08) v1(177.17,99.08) v1(177.81,99.08)
+PWR_SRC_AC:
  vias: v2(7.36,13.34)
+PWR_SRC_R:
  vias: v3(221.57,7.1)
+REGCTL_PNP10:
  vias: v2(282.58,86.82)
+RREF: length 2.8
  TOP w0.305: RR4.1 29.47,52.98 v2(29.41,52.91) 29.19,52.7 27.61,52.7
+RSVD_VCC3P3_1: length 4
  TOP w0.203: RL6.1 282.87,80.69 282.87,81.12 v2(282.4,81.59) 282.14,81.85 282.14,83.03 281.74,83.42 UL1.1
+RTC_CELL: length 158.2
  TOP w0.381: RE32.2 288.58,78.5 v1(288.49,78.5) ; RE31.1 287.58,69.23 v1(288.04,69.23) 288.24,69.03 RE508.2 ; CC270.1 126.43,53.36 v1(126.12,53.68) 126.21,53.68 126.96,54.43 126.96,54.97 126.77,55.16 CC213.1
  TOP w0.508: RE507.2 289.01,75.33 v1(288.63,74.95) ; v1(175.17,32.54) 178.67,36.04 178.67,42.54 172.88,48.33 172.88,56.22 163.87,65.22 162.74,65.22 153.19,74.77 153.19,76.2 v1(150.31,79.09) ; RE324.2 291.22,68.5 291.93,67.79 v1(292.38,67.79) ; RC56.2 RC69.2 v1(136.53,37.89) ; v1(87.62,87.83) 86.68,86.89 82.68,86.89 v2(81.41,85.62) 79.51,83.71 69.08,83.71 64.62,79.26 64.62,78.02 63.27,76.67 60.59,76.67 PD3.1 59.02,76.9 PC3.1 ; RA54.2 v1(302.9,27.58)
  BOTTOM w0.178: UC1.BB14 129.48,46.55 v1(129.47,46.53)
  BOTTOM w0.254: v1(126.12,53.68) 126.56,54.06 UC1.AK19
  BOTTOM w0.508: v1(136.53,37.89) 136.53,37.1 137.29,36.34 137.29,33.62 143.44,27.48 155.45,27.48 156.22,26.7 169.94,26.7 172.65,29.41 173.97,29.41 175.17,30.61 v1(175.17,32.54) ; v1(155.45,51.96) 154.94,51.45 RC57.2
+RTC_CELL_VBAT: length 3.9
  TOP w0.102: v1(290.77,77.02) 290.78,77.02 v2(291.14,77.39)
  TOP w0.254: v1(293.87,72.64) 293.96,72.56 295.39,72.56 UE1.A2 ; RE32.1 290.24,77.76 290.24,77.29 CE11.1 290.61,77.19 v1(290.77,77.02)
+SDC_IN: length 32.4
  TOP w0.508: PQ1203.3 5.97,39.23 PR1202.1 4.2,38.63 3.43,37.86 v1(2.39,37.86) ; PQ5.3 57.18,102.3 PR10.1 v1(55.54,102.96) ; v1(12.51,23.62) 13.6,23.62 PR943.2
  BOTTOM w0.254: v1(3.5,17.61) 3.5,12.84 3.81,12.53 10.74,12.53 11.31,13.1 11.44,13.1 12.32,13.98 12.32,15.97 PR944.1
  BOTTOM w0.508: v1(2.39,37.86) 2.04,38.22 2.04,41.93 v1(3.43,43.33)
  vias: v1(3.43,45.99) v1(3.43,45.36) v1(3.43,44.72) v1(3.43,44.09) v1(3.5,20.15) v1(3.5,19.51) v1(3.5,18.88) v1(3.5,18.24) v1(4.07,45.99) v1(4.07,45.36) v1(4.07,44.72) v1(4.07,44.09) v1(4.07,43.33) v1(4.13,20.4) v1(4.13,19.77) v1(4.13,19.13) v1(4.13,18.5) v1(4.13,17.86) v1(5.44,19.79) v1(19.94,61.11) v1(19.94,60.34) v1(20.71,61.87) v1(20.71,61.11) v1(20.71,60.34) v1(21.6,61.87) v1(21.6,61.11) v1(21.6,60.34) v1(22.48,61.87) v1(22.48,61.11) v1(22.48,60.34) v1(46.74,86.25) v3(28.33,59.58)
+SDREG2:
  vias: v2(22.6,47.77)
+SIM_PWR: length 23.9
  TOP w0.102: v1(126.45,103.04) 126.54,103.04 127.14,102.43 v3(127.14,102.21)
  TOP w0.508: CZ41.1 125.91,103.04 v1(126.45,103.04)
  BOTTOM w0.203: JNGFF2.28 295.55,50.66 v1(295.56,50.67)
  BOTTOM w0.508: v1(138.86,98.85) 132.05,98.85 127.86,103.04 v1(126.45,103.04) 126.45,104.44 125,105.88 JSIM1.1 ; RZ335.1 117.8,112.4 CZ37.1 117.78,113.04 v1(117.8,113.05)
+TBTA_LDO_BMC: length 1.9
  TOP w0.076: 33.34,84.04 33.04,83.74 33.04,83.33 33.14,83.22 UT5.E1
  TOP w0.102: 33.34,84.04 33.53,84.23 CT71.1
+TBTA_VBUS: length 3
  TOP w0.102: v1(12.64,86.95) v3(12.64,87.71)
  TOP w0.508: PC1208.1 v1(14.45,85.87)
  BOTTOM w0.203: JUSBC1.B9 6.23,95.67 6.53,95.37 6.67,95.37 v1(6.7,95.34)
  BOTTOM w0.254: 6.49,98.18 JUSBC1.B4
  vias: v1(6.74,98.35) v1(8.4,96.15) v1(8.98,96.14) v1(9.57,96.08) v1(9.71,98.11) v1(9.99,98.72) v1(9.91,95.2) v1(10.09,95.78) v1(10.32,98.11) v1(10.57,98.72) v1(11.16,98.72) v1(11.37,86.95) v1(11.37,86.31) v1(12.01,86.95) v1(12.01,86.31) v1(12.64,86.31) v1(13.28,86.95) v1(13.28,86.31) v1(13.91,86.95) v1(13.91,86.31)
+TBTA_VBUS_1: length 31.9
  TOP w0.508: v1(74.08,105.66) 71.89,105.66 67.69,101.46 66.37,101.46 65.32,100.42 48.19,100.42 UT8.1
  BOTTOM w0.508: PR1239.1 v1(74.08,105.66)
  vias: v1(10.04,57.55) v1(10.04,56.66) v1(10.8,57.55) v1(10.8,56.66) v1(11.56,57.55) v1(11.56,56.66) v1(12.45,57.55) v1(12.45,56.66) v1(13.34,57.55) v1(13.34,56.66) v1(18.74,84.83) v1(18.74,84.19) v1(19.37,84.83) v1(19.37,84.19) v1(20.01,84.83) v1(20.01,84.19) v1(20.01,83.56) v1(20.64,84.83) v1(20.64,84.19) v1(20.64,83.56) v1(30.68,77.46) v1(30.73,76.86) v1(31.26,77.29) v1(35.49,88.82) v1(35.92,88.41) v1(36.35,87.98) v1(36.33,76.6) v1(36.33,75.96) v1(46.43,97.55) v1(47,97.89) v1(46.94,97.11) v3(8.64,57.68)
+USB_EX2_PWR:
  vias: v3(17.98,77.87)
+USB_EX3_PWR: length 1
  TOP w0.127: v1(84.97,107.59) 85.22,107.59 v3(85.73,107.08)
+UZ12_TPM: length 2.4
  TOP w0.102: RZ89.2 v2(173.54,39.44)
  TOP w0.254: CZ50.1 170.58,39.17 UZ12.8
+VCHGR: length 1.6
  TOP w0.102: PC935.1 v2(32.22,4.46)
+VHDMI_VCC: length 1.6
  BOTTOM w0.381: v1(116.85,108.73) 116.6,108.97 RV23.2 ; v1(114.66,112.24) 114.62,112.27 RV22.2
  vias: v1(111.28,106.57) v1(111.87,106.57) v1(112.45,106.57) v2(111.61,107.31)
+VR_CAP: length 4.7
  TOP w0.254: UE1.J1 301.88,71.85 301.88,70.99 302.8,70.07 v2(302.8,69.76) 303.2,69.76 v1(303.49,69.47) 303.74,69.22 CE31.1 ; v1(296.76,79.53) UE1.C10
+Z4012: length 2.3
  TOP w0.102: v2(61.97,80.05) 62.12,79.9 PR2.2
  TOP w0.254: PR2.2 61.18,78.98 PD3.2
AC1_DISC#: length 11.6
  TOP w0.102: RT72.2 31.82,74.12 32.58,73.36 35.5,73.36 36.14,74 37.85,74 38.42,74.57 v1(38.82,74.57) ; PR939.1 v1(35.18,27.09)
  BOTTOM w0.102: v1(63.91,107.95) 65.12,107.95 65.46,108.3 PR1244.1
AC1_DISC#_R: length 2.5
  TOP w0.076: UT5.G11 32.14,77.9 32.26,77.78 32.26,77.03
  TOP w0.102: 32.26,77.03 v2(32.26,76.73) 32.26,76.23 RT72.1
AC_DIS: length 243.2
  TOP w0.102: v1(226.27,29.41) v2(226.27,30.1) ; UE1.H12 301.17,80.73 301.6,81.16 301.6,82.67 301.93,83.01 301.93,85.95 v1(302.03,86.05) 302.03,86.29 302.65,86.9 RE83.1 ; PQ909.2 34.22,28.73 PR927.1 v1(35.14,28.04)
  BOTTOM w0.102: v1(226.27,29.41) 226.27,24.96 226.52,24.7 226.52,6.98 222.34,2.79 200.02,2.79 198.83,1.6 193.61,1.6 188.91,6.3 188.91,9.55 188.6,9.85 188.6,11.85 187.99,12.47 187.99,14.97 187.11,15.84 177.51,15.84 175.54,17.81 128.26,17.81 121.1,24.97 80.9,24.97 78.55,22.62 51.6,22.62 46.18,28.04 v1(35.14,28.04)
AC_DISC#: length 260.1
  TOP w0.102: PQ1211.3 27.78,32.89 PQ1211.6 27.78,32.28 28.2,31.86 29.27,31.86 29.86,32.45 29.86,32.7 PQ1210.6 31.09,33.64 31.21,33.76 PR1231.1 33.06,33.76 35.06,31.77 v1(35.06,31.39) 34.99,31.32 PC1217.1 32.73,30.82 31.37,30.82 PR1245.1 ; PR25.1 v1(55.43,106.95) ; v1(22.87,30.12) v2(19.31,30.12) 18.54,30.12 18.19,30.47 17.39,30.47 16.86,31.01 14.46,31.01 PR1223.1
  TOP w0.112: UE1.E13 v1(299.2,81.97)
  BOTTOM w0.102: v1(224.97,28.47) 224.55,28.04 224.55,25.52 225.94,24.12 225.94,7.47 221.66,3.19 196.93,3.19 195.95,2.22 193.57,2.22 189.35,6.43 189.35,9.73 189.15,9.93 189.15,14.39 187.29,16.25 177.68,16.25 175.71,18.22 128.93,18.22 121.73,25.43 80.28,25.43 78.23,23.38 51.99,23.38 43.98,31.39 v1(35.06,31.39)
AC_PRESENT: length 85.4
  TOP w0.102: RC243.1 133.1,31.51 v1(132.72,31.51)
  TOP w0.107: v1(303.16,77.93) UE1.K8
  BOTTOM w0.076: UC1.AY15 128.76,48.21 128.6,47.93 128.6,47.65 128.49,47.54 128.49,45.68 130.54,43.63
  BOTTOM w0.102: v1(182.76,40.02) 182.16,39.43 182.16,31.37 177.73,26.94 175.79,26.94 173.41,24.57 137.51,24.57 132.72,29.36 v1(132.72,31.51) 132.67,31.51 132.45,31.74 132.45,39.26 131.46,40.25 131.46,41.57 v2(131.09,41.93) 130.54,42.49 130.54,43.63
ACAV_IN: length 247.7
  TOP w0.102: v1(291.34,83.29) 292.22,84.17 292.22,86.95 292.7,87.43 RE530.2 292.7,87.73 292.09,88.35 QE13.4 ; PR953.1 26.68,29.05 v1(26.87,29.25) 27.51,29.88 PR946.2
  TOP w0.107: v1(296.76,76.33) UE1.C7
  BOTTOM w0.102: v1(225.13,25.57) 225.13,25.44 226.15,24.42 226.15,7.39 221.75,2.99 199.66,2.99 198.47,1.8 193.69,1.8 189.12,6.37 189.12,9.62 188.94,9.8 188.94,14.31 187.2,16.05 177.6,16.05 175.63,18.02 128.34,18.02 121.16,25.2 80.35,25.2 78.32,23.18 51.91,23.18 44.86,30.22 v2(32.12,30.22) 27.84,30.22 v1(26.87,29.25)
ACAV_IN1: length 5.3
  TOP w0.102: v1(11.67,14.03) 11.78,13.92 PR928.1 ; v1(32.77,28.21) PR942.1 31.83,28.89 PQ909.1 32.14,29.88 PR925.1
  BOTTOM w0.102: v1(11.67,14.03) 11.67,13.94 11.21,13.48 v2(11.12,13.48) ; PR918.1 v1(11.7,19.59)
ACAV_IN_NB: length 41.2
  TOP w0.102: UE1.N6 305.53,76.29 306.02,76.29 v1(306.08,76.35) ; PR1203.2 66.96,109.14 v1(66.3,108.48) ; v1(24.74,41.83) 25.91,40.66 v2(27.18,40.66) 28.96,40.66 32.28,37.34 PR1241.1 PR1258.1 32.34,35.13 34.66,35.13 36.2,33.59 36.2,27.08 34.96,25.84 PR941.1
  BOTTOM w0.102: v1(66.69,89.48) 64.84,91.33 v1(62.55,91.33) 62.55,93.71 62.22,94.04 PR21.1 61.79,94.35 61.57,94.58 v1(61.57,95) ; v1(66.3,108.48) 66.3,108.75 PR1206.2 65.43,109.61 PC1207.1 65.53,110.64 66.55,110.64 66.92,110.27 PU1201.1
ACIN_ISL88738: length 5.7
  TOP w0.203: PU901.19 15.42,17.56
  TOP w0.254: v1(14.16,17.77) 14.29,17.63 15.35,17.63 15.42,17.56
  BOTTOM w0.102: v1(14.16,17.77) v2(14.82,17.77)
  BOTTOM w0.254: v1(14.16,17.77) PR945.1 13.2,17.75 PC1286.1 PR944.2
ACOK_ISL88738: length 3.9
  TOP w0.203: PU901.24 15.76,15.56
  TOP w0.254: 15.76,15.56 v2(14.77,14.58) 14.12,13.92 PR928.2
ADP_ISL88738: length 4.2
  TOP w0.203: PR943.1 v2(15.31,20.53) 15.9,19.93 16.67,19.93 17.05,19.55 PU901.16
ALW_PWRGD_3V_5V: length 109.1
  TOP w0.102: v1(169.58,119.25) 169.35,119.47 155.75,119.47 154.69,118.42 154.69,116.17 154.59,116.07 PR119.2 153.55,116.83 152.63,116.83 152.15,116.35 152.15,115.33 149.23,112.41 149.23,111.55 147.15,109.47 v2(147.15,107.51) 147.15,105.61 149.54,103.22 v1(153.25,103.22) ; v1(172.29,55.97) 172.29,48.2 176.84,43.66 176.84,35.48 174.43,33.07 174.43,29.58 173.23,28.39 148.47,28.39 146.74,26.66 138.84,26.66 138.07,27.43 UZ6.2
  BOTTOM w0.254: v1(169.58,119.25) 169.19,118.86 PR120.2
ALWON: length 43.4
  TOP w0.107: v1(294.29,74.64) 294.37,74.72 294.92,74.72 295.33,75.13 UE1.A5
  BOTTOM w0.102: v1(161.08,83.74) 161.08,85.73 v2(169.56,94.21) 174.38,99.03 174.38,114.1 175.11,114.84 175.11,116.91 PD100.2 173.84,117.45 PR114.1
AR_DET#: length 16.1
  BOTTOM w0.102: UC1.P4 135.51,63.01 135.7,63.2 138.55,63.2 143.57,68.22 v2(143.87,68.22) RC400.1 145.57,68.52 145.78,68.73 146.39,68.73 146.61,68.95 147.86,68.95 RC401.1
AUD_HP_NB_SENSE: length 12.5
  TOP w0.254: v1(310.71,29.36) 310.42,29.36 DA2.3 311.31,30.04 312.74,28.61 313.56,28.61 v3(314.2,27.96) 319.35,27.96 ; v1(293.79,29.67) 294.21,29.67 RA60.2
AUD_HP_OUT_L: length 4.4
  TOP w0.127: RA7.2 306.52,37.98 306.52,39.29 v2(306.65,39.41)
  TOP w0.381: LA15.1 RA7.2 306.25,37.41 RA57.2
AUD_HP_OUT_L1: length 13.1
  TOP w0.381: LA15.2 308.67,38.26 309.73,37.19 DA1.2 310.63,36.04 v1(310.9,35.77) 311.12,35.77 311.81,36.45 313.58,36.45 v3(313.72,36.59) 313.86,36.73 313.86,37.67 314.86,38.68 316.07,38.68 316.35,38.4
  BOTTOM w0.381: CA3.1 311.54,35.13 v1(310.9,35.77)
AUD_HP_OUT_R: length 2.2
  TOP w0.381: RA58.2 306.66,36.54 RA8.2 LA16.1
AUD_HP_OUT_R1: length 7
  TOP w0.127: v1(313.38,33.55) v3(313.95,33.55)
  TOP w0.381: v1(313.38,33.55) CA2.1 310.29,33.55 DA1.3 309.33,34.1 307.99,35.44 LA16.2
AUD_NB_MUTE#: length 14.8
  TOP w0.102: RA48.1 295.93,44.04 v1(295.35,43.45) 293.91,42.02 DA8.1
  TOP w0.107: v1(291.99,74.65) 291.99,74.36 v2(292.31,74.05) 292.62,73.73 294.8,73.73 295.4,74.33 UE1.A4
  BOTTOM w0.102: v1(288.78,44.39) 289.33,44.39 289.68,44.73 294.2,44.73 295.3,43.63 295.3,43.5 v1(295.35,43.45)
AUD_PC_BEEP: length 3.9
  TOP w0.203: UA1.16 298.6,31.85 298.26,31.51
  TOP w0.254: CA27.2 CA28.2 297.64,30.05 297.64,31.13 298.02,31.51 298.26,31.51
AUD_PWR_EN: length 28.8
  TOP w0.102: UZ5.3 275.36,76.08 275.44,76.17 275.44,76.51 v1(275.04,76.91) 274.94,76.91 274.56,76.53 UZ5.5 ; v1(164.34,63.15) v2(163.39,64.1) 157.21,64.1 155.54,62.44 154.34,62.44 152.98,61.08 152.21,61.08 150.94,59.81 150.94,59.2 150.31,58.57 148.62,58.57 148.45,58.4 146.45,58.4 146.08,58.03 144.94,58.03 144.53,58.44 RC279.1 143.67,58.57 143.57,58.67 v1(143.57,59.19)
  BOTTOM w0.102: UC1.W8 133.44,59.67 v1(133.76,59.99)
AUD_SENSE_A: length 4.8
  TOP w0.203: 297.28,32.03 297.4,32.15 UA1.13
  TOP w0.254: 297.28,32.03 296.37,32.03 295.34,31 CA41.1 RA60.1 294.53,30.9 RA59.2
AUD_SENSE_B: length 1.7
  TOP w0.203: 297.57,31.62 297.8,31.85 UA1.14
  TOP w0.254: RA61.2 297.13,31.18 297.57,31.62
AUX1_SNOOP_EN#: length 2.1
  BOTTOM w0.102: UT9.29 18.49,92.56 18.39,92.65 v2(18.04,92.65) 17.18,92.65 RT308.1
AUX_EN_WOWL: length 36.9
  TOP w0.102: RZ38.2 RZ70.1 181.08,15.77 178.24,18.61 v2(178.24,21.29) 178.24,22.81 183.29,27.86 183.55,27.86 188.9,33.22 v1(188.9,38.37)
  TOP w0.107: UE1.D3 v1(297.56,73.13)
BAT1_LED#: length 20.3
  TOP w0.254: UE1.D10 v1(297.56,79.53) ; v1(286.39,54.12) v2(285.63,54.12) 284.99,54.12 284.61,53.74 RZ28.1
  BOTTOM w0.127: v1(297.56,79.53) 297.16,79.92 296.42,79.92 296.3,79.8
  BOTTOM w0.254: v1(282.62,76.37) 285.31,79.06 286.02,79.06 288.04,81.09 291.39,81.09 292.44,80.03 295.41,80.03 295.64,79.8 296.3,79.8
BAT2_LED#: length 45.1
  TOP w0.254: UE1.D11 v1(297.56,80.33) ; QZ2.1 266.99,64.85 266.46,65.38 266.46,67.74 267.7,68.98 RZ361.1 268.1,68.98 268.36,69.23 268.36,70.35 v1(268.04,70.67)
  BOTTOM w0.254: v1(297.56,80.33) 297,80.89 295.88,80.89 295.38,80.39 292.63,80.39 291.53,81.49 287.94,81.49 285.87,79.42 284.99,79.42 281.55,75.97 281.22,75.97 279.94,74.69 279.94,74.03 279.51,73.6 278.85,73.6 277.86,72.61 277.86,71.13 276.78,70.05 272.02,70.05 270.94,71.14 v2(268.7,71.14) 268.51,71.14 v1(268.04,70.67)
BAT2_LED#_R: length 8.8
  TOP w0.102: QZ3.2 268.62,71 269.37,70.25 269.37,68.4 268.93,67.96 268.53,67.96 v2(268.26,67.69) QZ2.6 267.33,65.95 267.8,65.47 268.01,65.47 QZ2.3
BATGONE_ISL88738: length 6.3
  TOP w0.203: PC938.1 v2(14.41,13.3) 15.16,14.06 16.19,14.06 PU901.25
  TOP w0.254: PC938.1 PR930.1 13.55,10.71 PR931.2
BATT_WHITE#: length 10.5
  TOP w0.127: 267.47,71.9 v3(266.96,71.9)
  TOP w0.254: v1(285.88,53.61) 285.6,53.61 285.22,53.23 285.22,52.13 285.4,51.96 JLED1.3 ; v1(269.48,71.61) 269.49,71.6 QZ3.3 269.49,72.66 268.23,72.66 267.47,71.9 267.47,70.15 RZ361.2
BATT_YELLOW#: length 2.7
  TOP w0.127: v2(283.69,52.31) 284.08,52.7 RZ28.2
  TOP w0.254: JLED1.2 284.9,51.93 284.61,52.22 RZ28.2
BBS_BIT6: length 4.2
  TOP w0.102: v1(146.82,40.79) v2(148.2,40.79) 149.23,40.79 149.74,40.28 RC184.1
  BOTTOM w0.102: UC1.AN5 134.8,52.79 v1(135.27,52.33)
BC_CLK_ECE1117: length 8.4
  TOP w0.102: CZ87.1 213.69,17.65 JKBTP1.11 212.8,17.65 211.31,19.14 211.31,20.19 v1(212.1,20.97) ; UE1.D13 298.14,81.7 298.14,82.12 v1(298.35,82.34) 298.38,82.36 298.38,82.92 v2(298.34,82.96)
BC_DAT_ECE1117: length 26
  TOP w0.102: CZ86.1 214.79,15.64 213.78,16.65 JKBTP1.13 212.3,16.65 211.08,17.88 211.08,22.37 212.68,23.97 212.68,26.66 212.82,26.8 214.56,26.8 214.7,26.95 214.7,27.15 214.57,27.28 213.43,27.28 213.28,27.44 213.28,27.64 213.4,27.77 214.24,27.77 214.41,27.94 214.41,28.14 214.31,28.25 v3(213.11,28.25) 212.82,28.25 212.68,28.39 v1(212.68,28.69) ; RE365.1 297.45,83.6 v1(297.87,83.17) 297.93,83.12 297.93,81.96 297.5,81.52 297.5,81.19 UE1.D12
BC_INT#_ECE1117: length 15.4
  TOP w0.102: v3(212.22,26.28) v1(212.22,24.33) 212.22,23.93 210.87,22.58 210.87,17.79 212.51,16.15 JKBTP1.14 213.84,16.15 215.02,14.98 215.17,14.98 CZ85.1
  TOP w0.112: v1(298.36,72.33) UE1.E2
BCM5882_ALERT#: length 29.2
  TOP w0.102: v1(222,27.47) v3(222,25.1) 222,24.58 222.28,24.3 222.28,21.2 224.23,19.25 224.23,13.64 223.73,13.15 222.92,13.15 JUSH1.13
  TOP w0.112: v1(299.96,79.53) UE1.G10
  BOTTOM w0.102: RE532.1 301.91,89.22 301.77,89.08 301.77,87.43 302.43,86.77 302.43,85.91 301.2,84.68 301.2,81.45 301,81.26 301,79.85 300.68,79.53 v1(299.96,79.53)
BEEP: length 1.2
  TOP w0.102: v1(295.69,27.51) 295.79,27.61 RA13.2
  TOP w0.107: v1(303.96,78.73) UE1.L9
BEEP_R: length 2.8
  TOP w0.254: RA45.1 CA62.1 ; CA62.1 296.85,29.1 CA28.1 ; CA62.1 RA13.1
BGATE_ISL88738: length 1.1
  TOP w0.127: v2(21.3,13.82) 20.95,14.18 v1(20.33,14.18)
  vias: v1(20.33,14.76) v1(27.31,5.54) v1(27.94,5.54)
BIA_PWM: length 4.1
  BOTTOM w0.102: DV1.1 106.43,86.12 v2(106.96,86.65) 107.19,86.89 107.19,87.79 LV1.2 105.99,88.05 RV1.1
BIA_PWM_EC: length 47
  TOP w0.102: v1(145.19,95.88) 144.69,96.38 142.36,96.38 142.35,96.39 130.09,96.39 130.08,96.38 129.88,96.38 124.96,91.46 121.77,91.46 121.1,92.13 v2(115.92,92.13) 113.98,92.13 111.73,89.88 111.73,88.47 109.5,86.25 109.5,85.48 109.18,85.15 107.36,85.15 v1(107.07,84.85)
  TOP w0.107: UE1.N1 305.56,71.53 v1(305.56,71.06)
  BOTTOM w0.102: v1(107.07,84.85) 106.95,84.85 DV1.2
BL_PWR_SRC_ON: length 1.4
  BOTTOM w0.102: QV1.3 v2(107.89,79.52)
BLUE: length 15.8
  BOTTOM w0.102: JCRT1.3 321.09,79.66 320.14,79.66 318.65,81.15 317.73,81.15 316.94,81.94 DV6.2 315.97,81.94 315.47,82.44 314.08,82.44 313.31,81.68 313.31,79.77 313.44,79.64 v2(313.44,79.37) 313.44,78.12 313.52,78.05 CV131.1 313.52,76.83 LV18.2
BLUE_CRT: length 12.4
  TOP w0.102: v1(281.11,56.51) 281.11,56.14 v2(280.81,55.84) 280.24,55.27 UV6.21
  BOTTOM w0.102: v1(316.79,81.06) 316.96,81.06 317.37,80.65 317.37,79.76 316.03,78.43 316.03,77.89 315.8,77.67 315.8,76.95 314.63,75.78 314.32,75.78 CV128.1 RV118.1 312.68,75.41 313.28,76.01 LV18.1
BOARD_ID: length 6.9
  TOP w0.102: UE1.J13 301.96,81.88 302.27,82.19 v2(302.27,82.9) 302.14,83.03 302.14,85.57 302.65,86.07 CE40.1 302.77,86.12 303.79,85.11 RE79.2
BOOT1_ISL88738:
  vias: v2(18.59,20.88)
BOOT2_ISL88738:
  vias: v2(21.77,16.52)
BREATH_LED#: length 15.8
  TOP w0.107: v1(296.76,80.33) UE1.C11
  BOTTOM w0.102: QZ7.4 317.01,94.86 v2(316.24,94.08) 311.71,89.55 305.99,89.55 v1(305.07,88.64)
BREATH_LED#_Q: length 2.2
  BOTTOM w0.102: v2(315.85,98.57) RZ32.1 317.01,98.48 QZ7.3
BREATH_WHITE_LED_SNIFF#: length 4.2
  TOP w0.102: LED3.1 v1(320.9,97.72)
  BOTTOM w0.102: v1(320.9,97.72) 320.05,98.57 v2(319.32,98.57) RZ32.2
BST_3V: length 3.3
  TOP w0.102: PR100.1 158.37,111.94 158.62,112.18 160.15,112.18 v2(160.86,111.47)
BST_3V_R: length 2.7
  TOP w0.102: v2(159.77,108.84) PC102.1
  TOP w0.508: PC102.1 PR100.2
BST_5V: length 3.1
  BOTTOM w0.102: v2(162.31,113.75) 162.5,113.94 164.55,113.94 164.8,113.68 PR111.1
BST_5V_R: length 1.3
  BOTTOM w0.102: PC114.1 161.39,112 v2(161.1,112.29)
BST_+1VALWP: length 1.4
  BOTTOM w0.102: PC304.1 177.87,93.32 177.4,93.79 v2(177.4,94.4)
BST_+1VALWP_C: length 1.4
  BOTTOM w0.102: v2(176.03,94.43) 176.47,93.99 PC304.2
BST_C_GT:
  vias: v2(53.84,65.82)
BST_C_SA: length 1.3
  TOP w0.102: PC611.1 65.73,79.38 v2(65.92,79.57)
BST_GT: length 0.9
  BOTTOM w0.203: PU612.7 57.72,65.49 v1(57.51,65.7)
  vias: v2(57.45,66.39)
BST_IA: length 0.9
  BOTTOM w0.203: v1(57.57,71.52) 57.66,71.43 PU610.7
BST_R_GT: length 1.5
  TOP w0.102: v1(57.51,65.09) v2(58.18,65.09)
  BOTTOM w0.203: PU612.6 v1(57.51,65.09)
BST_R_IA: length 0.9
  BOTTOM w0.203: v1(57.57,70.92) 57.69,71.03 PU610.6
BST_SA: length 3
  TOP w0.102: v1(67.59,79.65) v2(67.78,80.23)
  TOP w0.508: PC611.2 67.59,78.85 v1(67.59,79.65)
  BOTTOM w0.254: PU614.2 v1(67.59,79.65)
BT_RADIO_DIS#: length 39.7
  TOP w0.102: RE11.1 v1(296.49,70.13) 296.49,71.37 296.76,71.64 296.76,72.33 UE1.C2 ; DZ2.1 215.89,9.97 215.89,8.86 216.11,8.64 216.74,8.64 217.15,8.23 v2(217.15,8.03) 217.15,5.92 218.6,4.47 223.53,4.47 228.65,9.6 228.65,17.83 224.97,21.51 v1(224.97,24.02)
BT_RADIO_DIS#_R: length 9.2
  TOP w0.102: v2(216.97,12.21) 216.73,12.21 215.17,10.65 DZ2.2 214.84,10.62 213.24,10.62 v1(212.67,11.19)
  BOTTOM w0.102: JNGFF1.46 212.36,11.5 v1(212.67,11.19)
CAM_MIC_CBL_DET#: length 11.6
  TOP w0.102: v1(135.64,86.99) 136.69,86.99 137.1,87.39 140.33,87.39 v2(140.52,87.59) 141.1,88.17 RC413.1
  BOTTOM w0.076: v1(131.18,59.08) 131.18,59.15 131.48,58.84 UC1.AB11
  BOTTOM w0.102: JEDP1.14 109.8,90.85 109.87,90.79 109.87,88.27 v1(109.99,88.15)
CFG0: length 17.9
  TOP w0.102: JXDP1.9 73.45,37.26 73.54,37.34 RC126.1 73.08,38.36 72.28,39.15 v2(72.28,39.67) 72.28,39.76 v1(71.87,40.17)
  BOTTOM w0.076: UC1.E68 99.47,68.09 99.54,68.36 99.58,68.62 99.63,68.8 99.66,68.89 99.68,68.95 99.68,68.99 99.68,69 99.68,69.11 99.68,69.17 99.66,69.25 99.65,69.34 99.65,69.48 99.68,69.57 99.68,69.58 99.68,69.94 99.68,69.94 99.68,70.09 99.53,70.24 99.53,70.46 99.53,70.46 99.53,70.59 99.28,70.84 98.66,70.84 98.48,70.66 97.86,70.66 97.74,70.78 97.28,70.78 v1(96.87,71.19)
  BOTTOM w0.102: RC113.1 95.51,76.39 95.96,75.94 95.96,75.12 95.38,74.54 95.38,72.28 95.76,71.9 96.16,71.9 v1(96.87,71.19)
CFG1: length 20.5
  TOP w0.102: v1(71.21,40.15) 71.77,39.58 71.77,39.25 72.95,38.07 JXDP1.11
  BOTTOM w0.076: v1(95.4,71.01) 95.96,70.45 97.6,70.45 97.84,70.21 98.42,70.21 98.63,70.01 98.72,70.01 98.89,69.84 98.89,69.6 99.25,69.24 UC1.B67
  BOTTOM w0.102: v1(95.4,71.01) 94.04,72.37 94.04,77.17 v2(92.92,78.28) 92.27,78.93 RC112.1
CFG2: length 10.5
  TOP w0.102: v1(69.72,33.16) 70.11,33.55 71.25,33.55 71.95,34.25 JXDP1.15
  BOTTOM w0.076: UC1.D65 100.38,68.09 100.31,68.36 100.31,68.47 100.23,68.75 100.18,68.91 100.17,68.95 100.17,69.2 100.2,69.29 100.2,69.48 100.17,69.58 100.17,69.94 100.34,70.11 100.34,70.51 99.83,71.02 98.61,71.02 98.45,70.86 98.05,70.86 97.7,71.21 v1(97.51,71.21)
CFG3: length 24.3
  TOP w0.102: JXDP1.17 71.45,34.73 v1(70.83,34.1) ; v1(74.25,40.05) 74.5,40.05 74.83,40.38 v2(76.55,40.38) 76.89,40.38 77.09,40.18 RC121.2
  BOTTOM w0.076: v1(96.19,71.21) 96.78,70.62 97.67,70.62 97.79,70.5 98.59,70.5 98.77,70.68 99.22,70.68 99.37,70.53 99.37,70.17 99.52,70.02 99.52,69.61 99.46,69.49 99.46,69.34 99.52,69.15 99.52,68.98 99.43,68.72 UC1.D67
  BOTTOM w0.102: v1(96.19,71.21) 95.13,72.27 95.13,75.08 RC110.1 ; v1(74.25,40.05) 74.56,39.73 74.56,37.84 v1(70.83,34.1)
CFG4: length 20.4
  TOP w0.102: JXDP1.27 v1(68.95,37.47)
  BOTTOM w0.076: UC1.E70 97.21,67.41 97.01,67.61 96.67,67.61 96.64,67.65 96.46,67.82 94.38,67.82 v1(93.51,68.69)
  BOTTOM w0.102: v1(93.51,68.69) 93.35,68.85 v2(93.35,76.12) 93.35,76.73 90.61,79.47 89.51,79.47 88.91,80.08 RC109.1
CFG5: length 5.1
  TOP w0.102: v1(68.2,37.43) 68.45,37.18 JXDP1.29
  BOTTOM w0.076: UC1.C68 98.02,68.57 97.84,68.57 97.66,68.75 97.28,68.75 97.11,68.92 96.03,68.92 v1(95.63,69.31)
CFG6: length 5.8
  TOP w0.102: JXDP1.33 v1(67.45,34.17)
  BOTTOM w0.076: UC1.D68 97.34,67.94 97.03,68.24 96.59,68.24 96.43,68.08 94.88,68.08 v1(94.21,68.75)
CFG7: length 7.9
  TOP w0.102: v1(67.37,33.57) 66.95,33.98 JXDP1.35 ; v3(94.38,70.49) v1(94.78,70.09)
  BOTTOM w0.076: v1(94.78,70.09) 94.83,70.04 97.45,70.04 97.62,69.87 97.62,69.55 97.78,69.39 98.46,69.39 98.67,69.19 UC1.C67
CFG8: length 4.1
  TOP w0.102: JXDP1.10 73.45,31.57 v1(73.41,31.62)
  BOTTOM w0.076: UC1.F71 97.22,66.85 95.55,66.85 v1(95.01,67.4)
CFG9: length 11.2
  TOP w0.102: v1(70.71,32.45) 72.31,32.45 72.95,31.81 JXDP1.12
  BOTTOM w0.076: 93.8,66.15 96.42,66.15 96.68,65.89 96.94,65.89 97.06,65.95 97.2,65.95 97.43,65.88 97.56,65.88 97.78,65.96 98.03,65.96 UC1.G69
  BOTTOM w0.102: v2(92.06,66.89) v1(92.56,67.39) 93.8,66.15
CFG10: length 6.7
  TOP w0.102: v2(72.65,28.17) 71.95,28.87 JXDP1.16 71.95,31.89 v1(72.01,31.95)
  BOTTOM w0.076: UC1.F70 97.61,67.05 97.01,67.05 96.99,67.03 95.97,67.03 v1(95.62,67.39)
CFG11: length 8.1
  TOP w0.102: v2(71.35,28.38) 71.45,28.48 JXDP1.18 v1(71.45,31.59)
  BOTTOM w0.076: v1(94.42,67.39) 95.14,66.67 96.82,66.67 97.38,66.43 97.64,66.43 97.71,66.35 98.18,66.35 98.25,66.33 UC1.G68
CFG12: length 6.8
  TOP w0.102: JXDP1.28 68.95,28.58 67.82,27.44 67.09,27.44 v1(66.87,27.67)
  BOTTOM w0.076: UC1.H70 97.61,65.3 97.4,65.3 97.19,65.21 97.11,65.21 96.94,65.28 96.61,65.28 96.34,65 95.96,65 v1(95.58,65.38)
CFG13: length 5.8
  TOP w0.102: v1(68.45,31.76) JXDP1.30
  BOTTOM w0.076: UC1.G71 96.66,66.34 94.26,66.34 v1(93.22,67.37)
CFG14: length 5.9
  TOP w0.102: JXDP1.34 v1(67.45,28.06)
  BOTTOM w0.076: v1(94.98,65.38) 95.39,65.79 96.5,65.79 96.57,65.73 96.98,65.73 97.09,65.77 97.21,65.77 97.43,65.71 97.57,65.71 97.73,65.76 98.19,65.76 UC1.H69
CFG15: length 9.5
  TOP w0.102: v1(68.9,32.25) 68.08,32.25 66.95,31.13 JXDP1.36
  BOTTOM w0.076: UC1.G70 97.34,66.16 97.2,66.3 97.19,66.3 97.19,66.31 96.78,66.5 94.69,66.5 v1(93.83,67.37)
  BOTTOM w0.102: v2(92.18,68.19) 93,68.19 v1(93.83,67.37)
CFG16: length 4.4
  TOP w0.102: v1(75.84,26.84) v2(74.45,28.23) JXDP1.6
  BOTTOM w0.076: UC1.E63 101.49,66.71 v1(101.38,66.71)
CFG17: length 4
  TOP w0.102: JXDP1.4 74.95,28.63 v2(75.94,27.64) v1(76.3,27.28)
  BOTTOM w0.102: UC1.F63 101.92,66.4 v1(102.27,66.06)
CFG18: length 6
  TOP w0.102: JXDP1.24 69.95,29.05 v2(69,28.1) 67.54,26.64 67.21,26.64 v1(66.77,27.08)
  BOTTOM w0.076: v1(99.29,67.21) UC1.E66
CFG19: length 7.3
  TOP w0.102: v1(74.51,25.6) 73.51,25.6 70.45,28.65 JXDP1.22
  BOTTOM w0.076: v1(99.29,66.58) UC1.F66
CFG_RCOMP: length 2.4
  TOP w0.127: v1(103.28,66.64) v2(102.68,66.64)
  TOP w0.381: RC114.1 103.28,67.76 v1(103.28,66.64)
  BOTTOM w0.254: UC1.E60 103.37,66.64 v1(103.28,66.64)
CLK_DDC2_CRT: length 5.2
  TOP w0.102: v1(317.76,73.81) 317.89,73.93 RV120.1 v2(319.18,74.44) 319.59,74.44 320.01,74.02 JCRT1.15 ; v1(279.5,51.85) 278.69,52.67 UV6.15
CLK_ITPXDP_N: length 3
  BOTTOM w0.076: UC1.F43 v1(112.42,66.68)
  BOTTOM w0.094: v1(112.29,75.22) 112.09,75.02 111.91,75.02 111.76,75.17 111.76,75.6 112.1,75.93 112.1,76.45 RC297.1
CLK_ITPXDP_N_R: length 6
  TOP w0.094: JXDP1.42 65.45,31.19 65.51,31.25 65.51,31.78 v1(65.41,31.88)
  BOTTOM w0.094: v1(109.76,79.85) 110.26,79.34 111.69,79.34 112.1,78.94 112.1,77.94 RC297.2
CLK_ITPXDP_P: length 3.5
  BOTTOM w0.076: v1(112.42,67.25) 112.6,67.25 UC1.E43
  BOTTOM w0.094: v1(112.29,74.63) 112.09,74.83 111.84,74.83 111.58,75.09 111.58,75.67 111.91,76.01 111.91,76.47 111.64,76.74 RC298.1
CLK_ITPXDP_P_R: length 6.4
  TOP w0.094: JXDP1.40 65.95,31.06 65.7,31.32 65.7,31.59 v1(66,31.88)
  BOTTOM w0.094: v1(109.39,79.37) 109.45,79.43 109.91,79.43 110.18,79.16 111.62,79.16 111.91,78.86 111.91,77.75 111.82,77.65 RC298.2
CLK_PCIE_N0: length 44.9
  BOTTOM w0.076: v1(112.31,70.93) 112.41,71.03 112.52,71.03 112.71,70.83 112.71,70.18 112.54,70.01 112.54,69.59 112.57,69.54 112.59,69.48 112.59,69.29 112.56,69.2 112.56,68.95 112.57,68.91 112.62,68.75 112.7,68.47 112.7,68.36 112.77,68.09 UC1.D42
  BOTTOM w0.094: v1(268.68,49.4) 268.76,49.48 269.04,49.48 269.28,49.23 269.28,48.89 270.64,47.53 274.88,47.53 276.27,46.14 276.27,45.63 278.52,43.39 281.18,43.39 281.91,44.12 283.22,44.12 283.65,44.55 283.65,44.99 284.33,45.67 287.2,45.67 289.99,48.46 291.17,48.46 291.36,48.26 291.53,48.26 292.79,47 297.54,47 300.01,44.53 300.01,42.79 299.8,42.58 JNGFF2.45
CLK_PCIE_N1: length 51.2
  BOTTOM w0.076: UC1.B42 113.19,69.48 113.25,69.58 113.28,69.71 113.28,71.21 113.12,71.37 113.12,73.07 112.86,73.34 112.52,73.34 v1(112.32,73.54)
  BOTTOM w0.094: JNGFF1.41 196.83,12.75 193.32,16.26 193.32,25.86 186.16,33.03 186.16,47.9 186.02,48.03 v1(186.02,49.88)
CLK_PCIE_N2: length 56.7
  BOTTOM w0.076: v1(114.4,74.62) 114.19,74.41 114.06,74.41 113.44,73.79 113.44,69.09 113.25,68.9 113.25,68.64 UC1.D41
  BOTTOM w0.094: v1(183.68,46.9) 183.85,46.73 183.85,46.03 183.97,45.9 183.97,40.1 183.63,39.75 183.63,32.23 188,27.86 188,24.72 189.82,22.9 189.82,18.1 190.6,17.32 190.6,16.19 194.92,11.87 194.92,9.95 198.12,6.75 JNGFF1.65
CLK_PCIE_N3: length 94
  BOTTOM w0.076: UC1.D40 114.45,68.28 114.46,68.71 114.58,69 114.57,69.17 114.51,69.32 114.51,69.43 114.61,69.82 114.61,70.08 114.42,70.26 114.42,71.6 114.5,71.68 114.85,71.68 v1(115.04,71.49)
  BOTTOM w0.094: JNGFF3.53 294.95,33.29 294.64,32.98 294.64,32.61 293.82,31.79 289.57,31.79 284,26.22 264.72,26.22 264.31,25.81 264.31,25.48 263.82,24.99 261.55,24.99 261.27,25.26 259.61,25.26 248.84,36.04 244.38,36.04 240.33,31.99 227.54,31.99 227.34,31.79 226.24,31.79 226.04,31.58 217.83,31.58 217.39,32.02 217.12,32.02 v1(216.93,31.83)
CLK_PCIE_N4: length 7.1
  TOP w0.094: v1(279.57,81.76) 279.57,81.67 279.38,81.49 279.16,81.49 279.05,81.59 279.05,81.96 279.14,82.05 279.2,82.05 279.26,82.12 UL1.45
  BOTTOM w0.076: UC1.B40 113.84,69.55 113.84,69.99 113.77,70.05 113.77,72.57 114.58,73.38 114.74,73.38 v1(114.94,73.58)
CLK_PCIE_N5: length 2.2
  TOP w0.094: v1(29.29,50.75) 29.1,50.56 28.28,50.56 28.18,50.66 UR1.6
  BOTTOM w0.076: v1(115.14,66.58) UC1.E40
CLK_PCIE_P0: length 44.8
  BOTTOM w0.076: v1(112.31,71.57) 112.31,71.47 112.88,70.9 112.88,70.11 112.71,69.94 112.71,69.63 112.72,69.61 112.78,69.49 112.78,69.34 112.72,69.15 112.72,68.98 112.77,68.84 112.86,68.75 113.03,68.75 113.08,68.7 113.08,68.5 UC1.C42
  BOTTOM w0.094: JNGFF2.47 300.3,42.7 300.2,42.8 300.2,44.61 297.62,47.19 292.87,47.19 291.61,48.44 291.44,48.44 291.24,48.64 289.92,48.64 287.13,45.85 284.25,45.85 283.46,45.06 283.46,44.63 283.14,44.31 281.83,44.31 281.1,43.58 278.59,43.58 276.46,45.71 276.46,46.22 274.96,47.72 270.72,47.72 269.47,48.97 269.47,49.31 269.16,49.62 v1(269.16,49.87)
CLK_PCIE_P1: length 51.2
  BOTTOM w0.076: UC1.A42 112.97,69.69 112.93,69.69 112.89,69.73 112.89,69.86 112.99,69.96 113.08,69.96 113.11,69.99 113.11,71.14 112.95,71.3 112.95,73 112.79,73.17 112.17,73.17 112.06,73.06 112.06,72.86 112.18,72.74 v1(112.32,72.74)
  BOTTOM w0.094: JNGFF1.39 200.5,13.25 200.34,13.09 200.34,13.03 200.25,12.94 196.91,12.94 193.51,16.34 193.51,25.94 186.34,33.1 186.34,47.97 186.21,48.11 186.21,49.48 v1(186.61,49.88)
CLK_PCIE_P2: length 56.7
  BOTTOM w0.076: v1(114.38,73.84) 114.45,73.84 114.6,73.99 114.6,74.16 114.51,74.25 114.13,74.25 113.61,73.72 113.61,69.11 113.68,69.04 113.79,69.04 113.85,68.97 113.85,68.86 113.7,68.7 113.59,68.7 UC1.C41
  BOTTOM w0.094: JNGFF1.63 200.53,7.25 200.45,7.16 200.45,7.03 200.35,6.94 198.2,6.94 195.1,10.03 195.1,11.95 190.78,16.27 190.78,17.4 190.01,18.18 190.01,22.98 188.19,24.8 188.19,27.93 183.81,32.31 183.81,39.68 184.16,40.02 184.16,45.98 184.04,46.1 184.04,46.58 v1(184.36,46.9)
CLK_PCIE_P3: length 94
  BOTTOM w0.076: UC1.C40 114.04,68.34 113.87,68.34 113.79,68.41 113.79,68.56 113.97,68.74 114.24,68.74 114.29,68.76 114.34,68.87 114.41,69.03 114.41,69.14 114.34,69.28 114.34,69.45 114.44,69.85 114.44,70.01 114.26,70.2 114.26,71.67 114.44,71.85 114.83,71.85 115.04,72.05 v1(115.04,72.18)
  BOTTOM w0.094: v1(216.93,32.42) 217.11,32.23 217.45,32.23 217.91,31.77 225.97,31.77 226.17,31.97 227.27,31.97 227.47,32.17 240.26,32.17 244.31,36.22 248.92,36.22 259.69,25.45 261.35,25.45 261.63,25.17 263.74,25.17 264.13,25.56 264.13,25.89 264.65,26.41 283.92,26.41 289.49,31.98 293.74,31.98 294.45,32.69 JNGFF3.55
CLK_PCIE_P4: length 7.2
  TOP w0.094: v1(279.57,81.15) 279.42,81.3 279.08,81.3 278.86,81.52 UL1.44
  BOTTOM w0.076: v1(114.95,72.76) 115.01,72.76 115.2,72.94 115.2,73.11 115.12,73.19 114.63,73.19 113.94,72.5 113.94,70.12 114,70.06 114.15,70.06 114.26,69.95 114.26,69.8 114.17,69.71 UC1.A40
CLK_PCIE_P5: length 2.2
  TOP w0.094: v1(29.29,50.17) 29.1,50.36 28.35,50.36 28.25,50.26 UR1.5
  BOTTOM w0.076: UC1.E38 115.51,66.98 115.19,67.2 v1(115.17,67.32)
CLK_TP_SIO_I2C_DAT: length 7.6
  TOP w0.102: v1(219.52,21.64) 218.87,22.29 v2(218.33,22.29) 216.92,22.29 216.64,22.57 216.39,22.57 CZ81.1 215.78,23.18 RZ346.2 215.44,22.66 215.69,22.66 RZ23.2 ; UE1.E10 298.36,79.53 298.33,79.53 v1(298.33,79.55)
CLK_TP_SIO_R: length 5.1
  TOP w0.102: CZ89.1 216.3,21.14 RZ23.1 RZ19.2 214.85,21.2 v2(214.33,20.68) 214.15,20.51 214.15,19.83 213.97,19.65 JKBTP1.7
CLKDET#: length 11.5
  BOTTOM w0.076: 135.89,45.1 135.56,45.44 135.01,45.44 134.05,46.4 133.27,46.4 132.83,46.84 132.83,48.34 133.14,48.65 UC1.AY8
  BOTTOM w0.102: 135.89,45.1 137.31,45.1 140.04,42.38 T258.1
CLKREQ_PCIE#0: length 48.3
  TOP w0.102: v1(171.81,48.48) 171.81,47.95 175.87,43.88 v2(175.87,37.86) 175.87,35.2 171.28,30.6 148.86,30.6 RC373.2
  BOTTOM w0.102: v1(299.7,48.13) 299.55,48.27 JNGFF2.44
CLKREQ_PCIE#0_R: length 3
  TOP w0.102: v2(146.23,34.71) 146.51,34.44 v1(146.69,34.44) RC373.1 RC189.1
  BOTTOM w0.102: UC1.AR10 132.47,51.09 v1(132.54,51.09)
CLKREQ_PCIE#1: length 12
  TOP w0.102: v2(147.5,34.56) 147.45,34.61 v1(147.45,35.07) RC374.2
  BOTTOM w0.102: v1(203.03,19.51) 203.03,14.96 204.39,13.6 204.39,12.98 203.16,11.75 JNGFF1.45
CLKREQ_PCIE#1_R: length 2.2
  TOP w0.102: v1(146.56,37.48) RC47.1 RC374.1
  BOTTOM w0.102: v1(133.47,50.5) 133.82,50.85 UC1.AT7
CLKREQ_PCIE#2: length 29.2
  TOP w0.102: v1(145.67,35.17) RC375.2
  BOTTOM w0.102: v1(145.67,35.17) 145.67,35.08 146.22,34.54 146.22,33.98 146.67,33.52 158.57,33.52 v1(160.67,31.43) ; JNGFF1.60 205.94,8 204.62,9.32 204.62,12.48 204.87,12.73 204.87,13.84 203.56,15.15 v1(203.56,15.54)
CLKREQ_PCIE#2_R: length 3.1
  TOP w0.102: v2(145.37,38.12) 145.37,37.57 v1(145.37,37.57) 144.79,36.99 RC50.1 RC375.1
  BOTTOM w0.094: UC1.AT8 132.89,50.85 v1(132.54,50.5)
CLKREQ_PCIE#3: length 6.6
  TOP w0.102: v1(152.51,32.14) v2(152.51,34.75) 152.51,35.04 152.41,35.14 151.26,35.14 150.58,35.82 RC376.2
  BOTTOM w0.102: JNGFF3.52 295.2,25.27 v1(295.09,25.16)
CLKREQ_PCIE#3_R: length 4.7
  TOP w0.102: RC59.1 RC376.1 150.37,36.89 151.5,38.01 152.36,38.01 v1(152.65,37.72)
  BOTTOM w0.102: v1(131.58,50.5) 131.73,50.65 131.86,50.65 UC1.AT10
CLKREQ_PCIE#4: length 34.7
  TOP w0.102: RL4.1 279.63,80.5 280.12,80.99 281.34,80.99 v1(281.53,81.18) 281.72,81.37 281.72,82.12 281.19,82.64 UL1.48 ; v1(172.55,31.18) 171.46,30.09 147.17,30.09 146.46,30.81 146.03,30.81 v2(145.4,31.44) 144.96,31.88 144.96,32.47 RC377.2
CLKREQ_PCIE#4_R: length 4.9
  TOP w0.102: RC51.1 146.16,33.2 146.16,32.49 146.92,31.73 v2(146.92,31.62) ; RC51.1 RC377.1 ; RC51.1 v1(145.67,34.44)
  BOTTOM w0.094: UC1.AU8 132.87,50.2 v1(132.54,49.87)
CLKREQ_PCIE#5: length 8
  TOP w0.102: v1(29.23,48.87) 29.23,48.9 29.07,49.06 UR1.2 ; RC378.2 140.95,37.99 138.82,37.99 138.2,37.37 v2(138.2,34.55) v1(138.2,33.87)
CLKREQ_PCIE#5_R: length 18.4
  TOP w0.102: v1(134.35,50.5) 134.35,49.57 134.88,49.04 134.88,47.52 137.8,44.6 v2(138.4,44.6) 140.59,44.6 142.58,42.61 142.58,39.6 RC190.1 140.99,38.89 RC378.1
  BOTTOM w0.102: UC1.AU7 134.04,50.2 v1(134.35,50.5)
CLKRUN#: length 14.1
  TOP w0.102: v1(305.46,67.09) 305.5,67.13 RE337.1 ; RC27.1 v1(138.44,40.4)
  BOTTOM w0.076: UC1.AW11 131.29,48.89 131.61,48.58 131.61,46.81 132.74,45.67 133.29,45.67 134.96,44.01 135.07,44.01
  BOTTOM w0.102: 135.07,44.01 136.23,44.01 136.63,43.6 136.63,43.09 v2(137.82,41.9) 138.24,41.48 138.24,40.6 v1(138.44,40.4)
CLKRUN#_EC: length 6.6
  TOP w0.102: UE1.L2 303.96,72.33 303.96,71.62 304.04,71.54 304.04,70.43 v2(303.94,70.33) 304.68,70.33 305.06,69.94 305.59,69.94 306.22,69.32 RE337.2
CMOUT: length 12.5
  TOP w0.254: PR951.1 v1(14.61,10.69) ; v1(11.12,10.5) 9.26,12.35 PQ1216.2 ; PQ1210.3 PQ1210.2 29.42,32.99 30.71,34.28 33.08,34.28 v2(34.22,33.14) 34.85,32.51 v1(35.41,32.51)
COMP_GT: length 3.8
  TOP w0.203: v1(69.5,54.04) 69.36,53.91 PU602.4
  BOTTOM w0.102: v2(69.02,54.15) 69.4,54.15 v1(69.5,54.04)
  BOTTOM w0.254: v1(69.5,54.04) 69.17,53.71 PR617.2 PC616.2
COMP_IA: length 4.9
  TOP w0.203: v1(64.53,50.14) 64.68,49.98 PU602.16
  BOTTOM w0.203: v1(64.53,50.14) v2(64.53,49.1) 64.53,48.93 65.01,48.44 PC636.2 65.01,48.11 PR639.2
COMP_ISL88738: length 3.9
  TOP w0.203: PR934.1 PC943.1 17.27,13.13 17.45,13.31 v2(17.45,13.31) 17.54,13.4 17.7,13.4 18.25,13.95 PU901.28
COMP_VSA: length 5.8
  TOP w0.203: v1(67.74,46.25) 68.16,46.66 PU602.24
  BOTTOM w0.102: v1(67.74,46.25) v2(68.11,45.88)
  BOTTOM w0.254: v1(67.74,46.25) 68,46.5 69.6,46.5 69.89,46.79 PC628.1 70.02,47.2 PR630.1
CONTACTLESS_DET#: length 16.5
  TOP w0.102: v1(223.77,17.76) 223.37,18.15 JUSH1.23 ; RC278.1 150.64,40.77 150.64,41.04 150.82,41.22 v3(151.92,41.22) 152.51,40.63 v1(154.31,40.63)
  BOTTOM w0.076: v1(131.82,59.09) 131.49,59.54 131.48,59.55 UC1.W11
  BOTTOM w0.102: v1(224.15,25.56) 224.21,25.56 225.64,24.13 225.64,19.63 v1(223.77,17.76)
CORE_VID0: length 2
  TOP w0.102: v1(131.58,52.43) 131.09,51.94 v2(131.09,51.83)
  TOP w0.254: v1(125.37,112.6) 125.39,112.62 PR408.1
  BOTTOM w0.254: UC1.AN11 131.52,52.43 v1(131.58,52.43)
CORE_VID1: length 1.8
  TOP w0.102: v2(121.63,112.85) 122,113.22 v1(122.1,113.22)
  TOP w0.254: PR411.1 122.11,113.22 v1(122.1,113.22)
  BOTTOM w0.254: v1(129.83,52.43) 130.2,52.8 UC1.AN13
CPU_B+: length 2.7
  BOTTOM w0.254: PR603.2 75.38,46.85 v1(75.96,46.27)
  vias: v1(53.22,69.61) v1(53.98,69.59) v1(54.79,69.54) v1(55.63,69.54) v1(56.24,69.49) v1(56.27,68.57) v1(56.24,67.79) v1(69.5,81.78) v1(70.12,81.79) v2(55.78,68.94)
CPU_DP1_AUXN: length 1.1
  TOP w0.094: v1(108.74,65.95) 108.93,65.95 T281.1
  BOTTOM w0.076: UC1.G50 109.2,65.69 108.74,65.95 108.74,65.95 v1(108.74,65.95)
CPU_DP1_AUXP: length 1.8
  TOP w0.094: v1(108.7,66.63) 109.25,67.18 T282.1
  BOTTOM w0.076: UC1.F50 108.72,66.58 v1(108.7,66.63)
CPU_DP1_CTRL_CLK: length 22.4
  TOP w0.094: v1(130.51,87.12) 130.58,87.18 130.58,87.29 130.87,87.59 131.91,87.59 132.34,88.02 139.47,88.02 139.67,88.22 139.67,88.38 139.76,88.47 139.99,88.47 140.09,88.57 RC175.1
  BOTTOM w0.076: v1(130.55,63.28) UC1.L13
  BOTTOM w0.094: QV3.1 114.69,110.97 114.44,110.72 114.44,108.79 114.63,108.6 115.52,108.6 116.53,107.59 116.53,104.43 114.92,102.82 v1(114.92,102.39)
CPU_DP1_CTRL_DATA: length 21.8
  TOP w0.094: RC178.1 139.07,88.57 139.16,88.47 139.39,88.47 139.49,88.38 139.49,88.3 139.39,88.2 132.26,88.2 131.83,87.78 130.47,87.78 v1(129.87,87.18)
  BOTTOM w0.076: v1(131.18,63.28) UC1.L12
  BOTTOM w0.094: v1(114.39,102.96) 114.4,102.95 114.79,102.95 116.34,104.51 116.34,107.51 115.44,108.41 114.55,108.41 114.25,108.71 114.25,109.44 114.03,109.67 QV3.4
CPU_DP1_HPD: length 32
  TOP w0.102: QV5.3 115.49,111.53 RV20.1 114.38,111.65 113.92,111.19 112.4,111.19 111.36,110.15 111.36,108.55 110.75,107.94 110.75,105.29 114.71,101.33 114.71,100.27 115.52,99.46 115.52,98.08 116.31,97.29 v2(116.31,94.75) v1(111.09,89.53)
  BOTTOM w0.076: v1(133.09,63.28) UC1.L9
CPU_DP1_N0: length 1.6
  TOP w0.094: v1(98.95,100.61) 98.91,100.61 98.72,100.8 98.72,101.03 98.91,101.22 CV32.1
  BOTTOM w0.076: v1(106.02,67.27) 106.3,66.99 UC1.E55
CPU_DP1_N1: length 1.7
  TOP w0.094: v1(102.31,100.33) 102.07,100.57 102.07,100.87 CV34.1
  BOTTOM w0.076: v1(104.17,67.21) UC1.E58
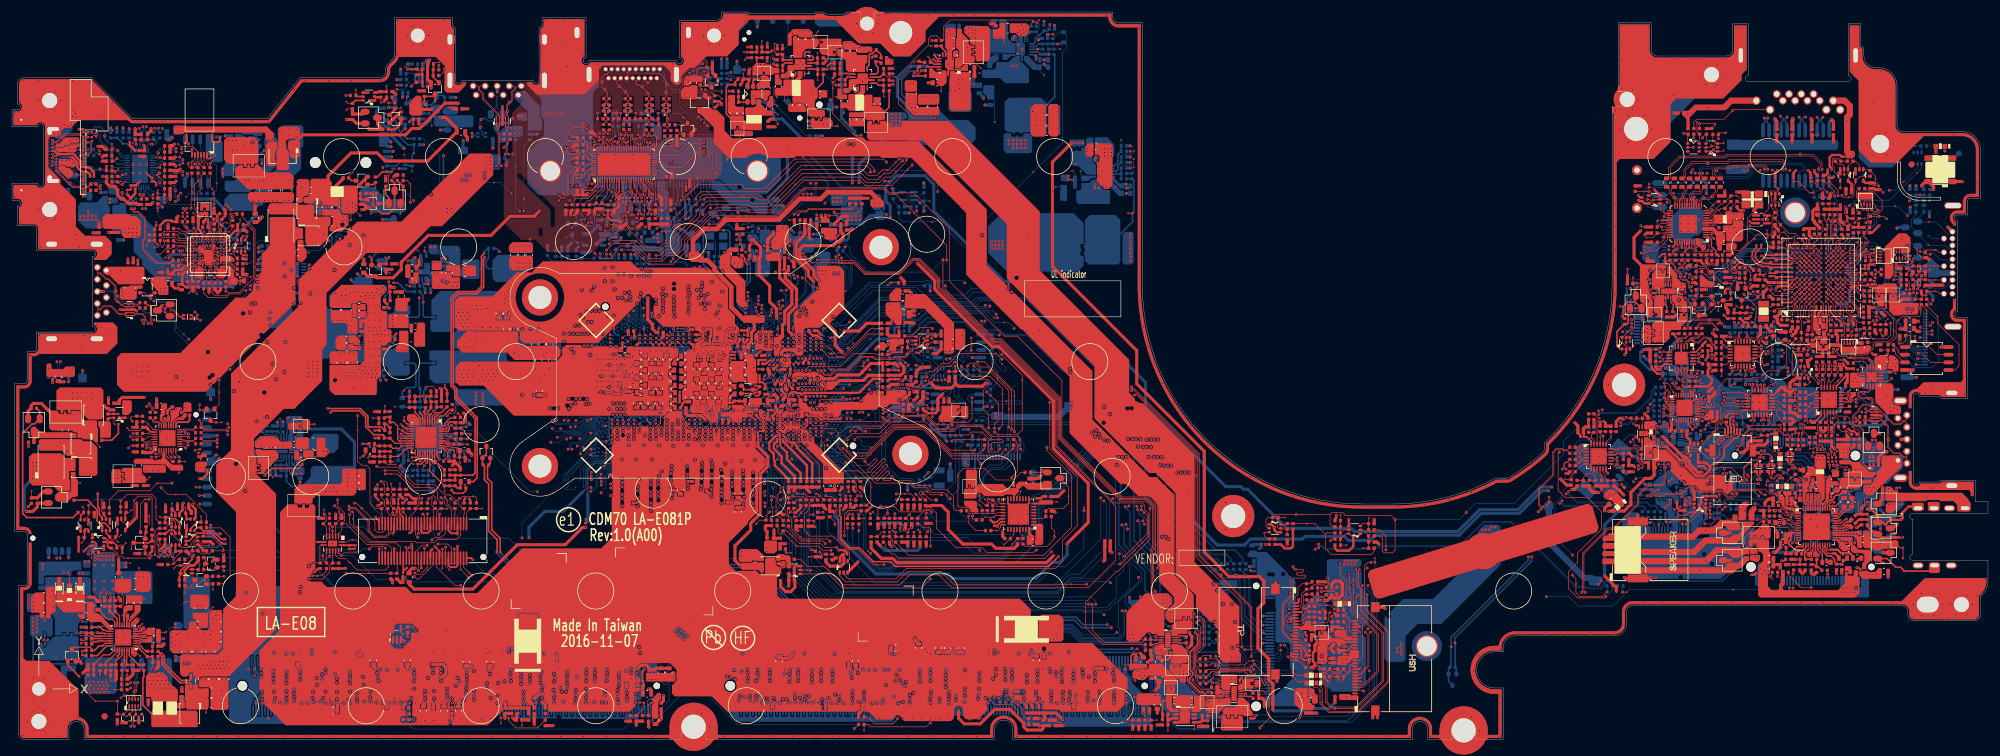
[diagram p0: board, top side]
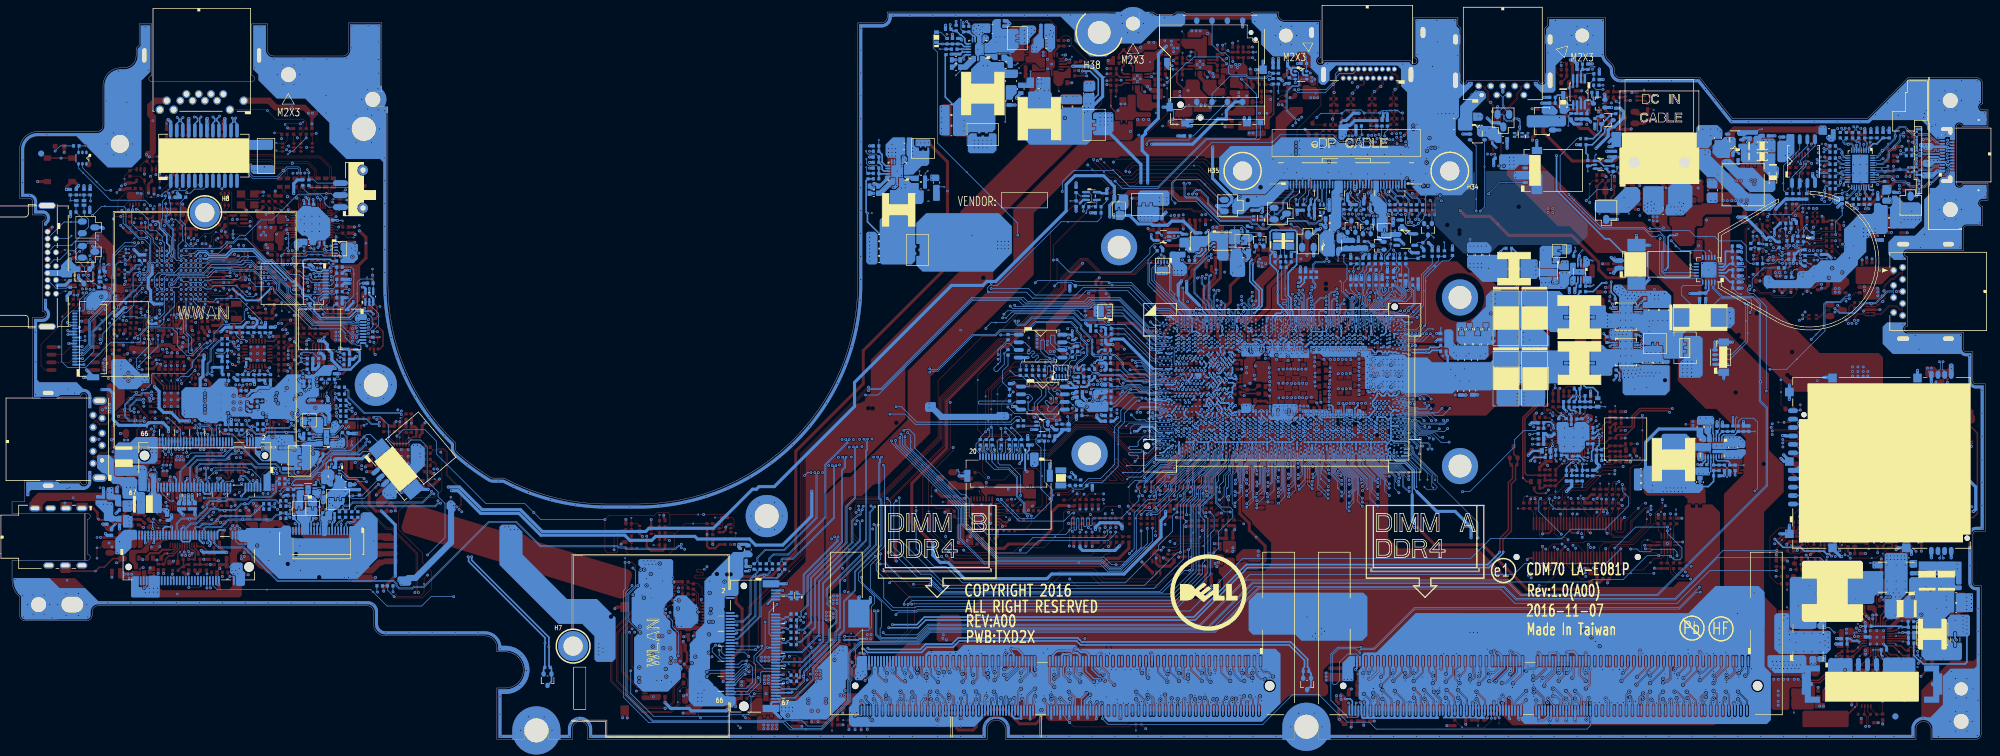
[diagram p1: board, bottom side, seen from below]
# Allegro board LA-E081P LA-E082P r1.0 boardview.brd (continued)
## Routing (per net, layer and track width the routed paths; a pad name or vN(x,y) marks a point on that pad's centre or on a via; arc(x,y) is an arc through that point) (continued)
CPU_DP1_N2: length 1.9
  TOP w0.094: CV36.1 108.91,99.77 108.91,99.26 v1(109.11,99.07)
  BOTTOM w0.076: v1(106.94,66.66) UC1.F53
CPU_DP1_N3: length 1.8
  TOP w0.094: v1(106.1,100.24) 105.88,100.46 105.88,100.8 CV38.2
  BOTTOM w0.076: UC1.F56 v1(105.1,66.61)
CPU_DP1_P0: length 1.7
  TOP w0.094: v1(98.19,100.6) 98.41,100.6 98.53,100.72 98.53,101.02 98.34,101.22 CV31.1
  BOTTOM w0.076: v1(106,66.58) UC1.F55
CPU_DP1_P1: length 1.7
  TOP w0.094: CV33.1 101.89,100.94 101.89,100.49 v1(101.72,100.33)
  BOTTOM w0.076: v1(104.17,66.58) UC1.F58
CPU_DP1_P2: length 1.9
  TOP w0.094: CV35.1 108.73,99.81 108.73,99.26 v1(108.53,99.07)
  BOTTOM w0.076: v1(106.91,65.94) UC1.G53
CPU_DP1_P3: length 1.7
  TOP w0.094: v1(105.52,100.24) 105.7,100.42 105.7,100.81 CV37.2
  BOTTOM w0.076: v1(105.09,65.94) UC1.G56
CPU_DP2_AUXN: length 3
  TOP w0.094: v1(92.96,91.94) 93.07,92.05 93.07,93.22 93.46,93.6 93.65,93.6 CV95.1
  BOTTOM w0.076: UC1.E48 109.79,66.99 109.65,67.14 v1(109.65,67.25)
CPU_DP2_AUXN_C: length 2.9
  TOP w0.094: UV7.63 96.22,94.92 96.12,94.82 95.86,94.82 95.04,94.01 95.04,93.7 94.95,93.61 94.68,93.61 CV95.2
CPU_DP2_AUXP: length 3
  TOP w0.094: CV94.1 93.86,93.33 93.76,93.42 93.54,93.42 93.26,93.14 93.26,92.21 93.54,91.92 v1(93.72,91.92)
  BOTTOM w0.076: v1(109.65,66.61) 109.94,66.61 110.12,66.44 UC1.F48
CPU_DP2_AUXP_C: length 2.9
  TOP w0.094: CV94.2 94.63,93.42 95.03,93.42 95.23,93.63 95.23,93.93 95.93,94.63 96.07,94.63 96.18,94.52 UV7.64
CPU_DP2_CTRL_CLK: length 4.5
  TOP w0.094: v1(120.92,82.97) 120.82,83.07 120.82,83.38 RC176.1 ; v1(96.31,92.29) 96.24,92.22 96.07,92.22 95.98,92.31 95.98,93.14 95.9,93.22 95.9,93.74 95.99,93.83 96.13,93.83 96.24,93.72 UV7.66
  BOTTOM w0.076: UC1.N7 134.05,62.8 v1(133.6,62.34)
CPU_DP2_CTRL_DATA: length 4.5
  TOP w0.094: v1(95.57,92.25) 95.79,92.47 95.79,93.06 95.71,93.14 95.71,93.82 95.92,94.03 96.11,94.03 96.21,94.12 UV7.65 ; RC177.1 120.64,83.61 120.64,83.27 v1(120.34,82.97)
  BOTTOM w0.076: v1(132.99,62.36) UC1.N8
CPU_DP2_HPD: length 2.6
  TOP w0.102: v1(99.55,90.93) 99.61,90.99 UV7.7
  BOTTOM w0.076: v1(134.36,63.28) UC1.L7
CPU_DP2_N0: length 10.7
  TOP w0.094: CV87.1 101.8,89.14 101.8,87.14 v1(102.03,86.91)
  BOTTOM w0.076: v1(107.96,74.01) 107.96,74.32 108.03,74.38 108.28,74.38 108.49,74.18 108.96,74.18 109.32,73.82 109.32,70.39 109.24,70.31 109.16,70.31 109.1,70.25 109.1,70.13 109.17,70.06 109.35,70.06 109.43,69.98 109.43,69.61 109.37,69.49 109.37,69.34 109.43,69.15 109.43,68.98 109.43,68.97 109.35,68.71 109.16,68.71 109.06,68.61 109.06,68.43 109.1,68.39 109.14,68.39 UC1.C50
CPU_DP2_N0_C: length 3.3
  TOP w0.094: UV7.12 101.61,92.54 101.5,92.43 101.5,91.04 101.78,90.75 101.78,90.15 CV87.2
CPU_DP2_N1: length 7.7
  TOP w0.094: v1(103.24,87.05) 103.02,87.27 103.02,87.94 103.03,87.94 103.03,88.52 103.02,88.53 103.02,89.1 CV89.1
  BOTTOM w0.076: v1(106.9,73.03) 106.9,72.88 107.26,72.51 107.26,72.49 107.61,72.14 107.61,70.87 107.95,70.53 107.95,70.05 107.77,69.87 107.77,69.61 107.83,69.49 107.83,69.34 107.77,69.15 107.77,68.98 107.85,68.72 UC1.C52
CPU_DP2_N1_C: length 3.3
  TOP w0.094: CV89.2 103.05,90.14 103.05,90.43 103.08,90.46 103.08,91.04 103.05,91.08 103.05,91.21 102.71,91.55 102.71,92.46 102.81,92.56 UV7.15
CPU_DP2_N2: length 7.5
  TOP w0.094: v1(104.5,87.24) 104.29,87.45 104.29,88.18 104.28,88.19 104.28,89.13 104.49,89.34 CV91.1
  BOTTOM w0.076: UC1.A50 109.16,69.51 109.08,69.43 108.92,69.43 108.85,69.51 108.85,70.29 109.05,70.49 109.05,72.82 108.64,73.24 108.28,73.24 v1(108.08,73.43)
CPU_DP2_N2_C: length 3.5
  TOP w0.094: UV7.17 103.61,92.38 103.48,92.26 v4(103.48,91.87) 103.48,91.66 103.79,91.36 103.79,91.09 104.03,90.84 104.29,90.58 104.29,90.17 CV91.2
CPU_DP2_N3: length 6.1
  TOP w0.094: v1(106.12,87.25) 105.89,87.49 105.89,87.99 105.89,87.99 105.89,88.57 105.89,88.58 105.89,89.17 CV93.1
  BOTTOM w0.076: UC1.D51 108.42,68.27 108.42,68.47 108.3,68.59 108.3,68.94 108.33,68.97 108.33,70.47 108.48,70.62 108.48,71.16 108.4,71.24 108.25,71.24 v1(108.03,71.03)
CPU_DP2_N3_C: length 3.6
  TOP w0.094: UV7.20 104.81,92.56 104.74,92.49 104.74,92.45 104.95,92.25 104.99,92.25 105.44,91.8 105.44,91.75 105.84,91.36 v4(105.84,90.77) 105.84,90.15 CV93.2
CPU_DP2_P0: length 10.7
  TOP w0.094: v1(101.44,86.91) 101.61,87.08 101.61,89.09 CV86.1
  BOTTOM w0.076: v1(108.09,74.83) 108.09,74.81 108.56,74.34 109.03,74.34 109.48,73.89 109.48,70.31 109.59,70.2 109.59,69.57 109.58,69.54 109.56,69.48 109.56,69.29 109.59,69.2 109.59,68.95 109.59,68.93 109.52,68.69 109.52,68.44 109.36,68.16 UC1.D50
CPU_DP2_P0_C: length 3.3
  TOP w0.094: UV7.11 101.21,92.53 101.31,92.43 101.31,90.96 101.59,90.68 101.59,90.16 CV86.2
CPU_DP2_P1: length 7.7
  TOP w0.094: CV88.1 102.84,89.14 v4(102.84,88.23) 102.84,87.24 v1(102.65,87.05)
  BOTTOM w0.076: v1(106.9,72.32) 107.2,72.32 107.44,72.07 107.44,70.8 107.78,70.46 107.78,70.12 107.6,69.94 107.6,69.57 107.62,69.53 107.66,69.45 107.66,69.37 107.6,69.17 107.6,68.95 107.62,68.91 107.66,68.75 107.74,68.47 107.74,68.36 107.82,68.09 UC1.D52
CPU_DP2_P1_C: length 3.3
  TOP w0.094: CV88.2 102.87,90.16 v4(102.87,90.75) 102.87,91.13 102.52,91.48 102.52,92.49 102.41,92.61 UV7.14
CPU_DP2_P2: length 7.5
  TOP w0.094: CV90.1 104.09,89.15 v4(104.09,87.81) 104.09,87.41 v1(103.92,87.24)
  BOTTOM w0.076: v1(108.09,72.81) 108.09,72.92 108.24,73.07 108.57,73.07 108.89,72.75 108.89,70.56 108.68,70.35 108.68,69.44 108.85,69.27 109.08,69.27 109.16,69.19 UC1.B50
CPU_DP2_P2_C: length 3.5
  TOP w0.094: CV90.2 104.11,90.13 104.11,90.5 103.6,91.01 103.6,91.23 103.26,91.57 103.26,92.15 103.29,92.18 103.29,92.3 103.21,92.38 UV7.16
CPU_DP2_P3: length 6.4
  TOP w0.094: v1(105.54,87.25) 105.7,87.41 v4(105.7,88.28) 105.7,89.07 CV92.1
  BOTTOM w0.076: UC1.C51 108.6,68.65 108.67,68.58 108.81,68.58 108.92,68.69 108.92,68.88 108.71,69.08 108.57,69.08 108.5,69.16 108.5,70.4 108.65,70.56 108.65,71.23 108.47,71.41 108.24,71.41 v1(108.03,71.61)
CPU_DP2_P3_C: length 3.7
  TOP w0.094: CV92.2 105.65,90.15 105.65,90.45 105.62,90.48 105.62,91.06 105.65,91.1 105.65,91.28 v4(105.08,91.85) 105.08,91.85 104.56,92.37 104.56,92.51 104.41,92.66 UV7.19
CPU_DP3_AUXN: length 1.5
  TOP w0.102: T1.1 110.64,65.95 v1(110.58,65.95)
  BOTTOM w0.102: v1(110.58,65.95) 110.84,65.69 UC1.G46
CPU_DP3_AUXP: length 2.2
  TOP w0.102: v1(110.58,66.59) 110.19,66.19 110.19,65.37 T2.1
  BOTTOM w0.102: UC1.F46 110.83,66.34 v1(110.58,66.59)
CPU_POPIRCOMP: length 10.8
  TOP w0.254: 129.26,49.32 128.78,49.32 128.44,49.65 128.44,50.14 128.08,50.5 v1(127.99,50.5)
  TOP w0.381: RC88.1 132.85,45.9 v2(131.57,47.18) 130.35,48.4 130.35,48.68 129.71,49.32 129.26,49.32
  BOTTOM w0.254: v1(127.99,50.5) 128.4,50.81 UC1.AT16
CPU_XDP_PRDY#: length 27.8
  TOP w0.102: JXDP1.5 74.45,33.9 73.76,33.21 70.59,33.21 70.03,32.66 67.19,32.66 66.98,32.86 59.6,32.86 56.65,35.8 v2(56.65,36.59) 56.65,37.63 v1(56.46,37.82)
  BOTTOM w0.076: v1(104.86,71.62) 104.86,70.99 105.26,70.6 105.26,70.07 105.12,69.94 105.12,69.57 105.16,69.5 105.16,69.29 105.15,69.26 105.15,69.23 105.13,69.22 105.12,69.2 105.12,68.95 105.14,68.91 105.18,68.75 105.26,68.47 105.26,68.36 105.34,68.09 UC1.D56
CPU_XDP_PREQ#: length 23.9
  TOP w0.102: JXDP1.3 74.95,37.21 75.06,37.32 RC138.1 74.82,38.36 74.07,39.11 74.07,39.64 73.97,39.74 73.63,39.74 72.76,40.61 71.84,40.61 70.1,42.34 66.88,42.34 v2(64.82,44.41) 64,45.23 60.67,45.23 v1(60.56,45.34)
  BOTTOM w0.076: UC1.D61 103.35,68.03 103.35,68.21 103.37,68.23 103.37,68.6 103.35,68.62 103.35,68.86 103.37,68.88 103.37,71.01 v1(103.17,71.21)
CPU_XDP_TCLK: length 30.9
  TOP w0.102: v1(57.38,53.79) v2(57.38,51.33) 57.38,46.17 58.02,45.53 58.83,45.53 59.42,44.95 59.42,39.24 60.29,38.36 RC139.1 61.35,37.58 61.45,37.47 JXDP1.57
  BOTTOM w0.076: v1(101.73,74.15) 101.66,74.08 101.66,73.21 101.49,73.03 101.49,72.77 102.52,71.74 102.52,71.09 102.99,70.63 102.99,70.04 102.81,69.87 102.81,69.61 102.87,69.49 102.87,69.27 UC1.B61
  BOTTOM w0.102: RC328.2 101.58,77.88 102.11,77.35 102.11,74.53 v1(101.73,74.15)
CPU_XDP_TDI: length 11.1
  TOP w0.102: UC8.6 52.22,35.29 RC134.1 52.18,36.31 52.18,37.04 v1(51.81,37.41) v2(51.81,38.18)
  BOTTOM w0.076: v1(102.62,73.52) 103.02,73.12 103.02,72.22 103.72,71.52 103.72,69.08 103.93,68.86 103.93,68.62 103.64,68.33 UC1.D60
CPU_XDP_TDO: length 9.4
  TOP w0.102: UC8.3 53.72,35.81 RC135.1 54.3,36.4 v2(54.3,37.8) 54.3,38.07 v1(53.56,38.81)
  BOTTOM w0.076: UC1.A61 103.16,69.8 103.16,70.69 102.69,71.15 102.69,71.9 101.88,72.72 v1(101.88,72.9)
CPU_XDP_TMS: length 10.4
  TOP w0.102: UC8.8 51.22,32.29 51.12,32.19 51.12,29.37 RC131.1 50.68,29.3 50.62,29.37 49.89,29.37 v1(49.28,28.76)
  BOTTOM w0.076: v1(102.65,72.93) 102.65,72.35 103.55,71.46 103.55,68.83 UC1.C60
CPU_XDP_TRST#: length 21
  TOP w0.102: RC136.1 CC308.1 ; CC308.1 UC8.11 ; CC308.1 52.71,28.79 52.71,27.75 51.59,26.64 v1(49.35,26.64) ; v1(101.26,73.33) v3(100.59,73.33)
  BOTTOM w0.076: UC1.B59 103.88,69.39 103.88,71.59 103.28,72.19 103.28,73.45 102.59,74.14 v1(102.47,74.27) ; v1(101.26,73.33) 101.26,72.72 102.36,71.62 102.36,71.02 102.82,70.56 102.82,70.11 102.65,69.94 102.65,69.57 102.66,69.54 102.68,69.48 102.68,68.87 102.69,68.86 102.69,68.8 UC1.C61
CSI2_COMP: length 13.9
  TOP w0.508: v1(129.77,67.21) 129.53,67.21 v2(128.91,67.84) 128.91,70.63 130.25,71.97 130.25,74.74 128.38,76.62 128.38,77.33 128.91,77.87 RC3.1
  BOTTOM w0.254: v1(129.77,67.21) UC1.E13
CSIN_ISL88738: length 6.4
  TOP w0.102: v2(18.32,23.94) 18.47,23.79 18.47,22.59 PC927.1
  TOP w0.203: PC925.2 17.85,20.54 PU901.14
  TOP w0.254: PC925.2 17.12,22.12 PR910.2 18.01,22.12 PC927.1
CSIP_ISL88738: length 4.5
  TOP w0.203: PC925.1 v2(17.2,20.27) 17.45,20.03 PU901.15
  TOP w0.254: PC925.1 16.2,22.1 16.21,22.11 ; 16.21,22.11 PC926.1 ; 16.21,22.11 PR909.2
CSON_ISL88738: length 5.9
  TOP w0.102: v2(23.03,11.69) 23.37,12.03 PC946.1
  TOP w0.203: PU901.1 20.81,15.56 21.19,15.18 21.19,15.01 PC945.1 22.48,13.76 PR938.1 23.37,13.7 PC946.1
CSOP_ISL88738: length 4.3
  TOP w0.203: PU901.2 20.94,15.96 21.56,15.33 v2(21.56,15.26) 22.16,14.66 PC945.2 22.49,14.63 PR937.1 PC942.1
CV2_ON: length 11
  TOP w0.102: v1(307.8,85.82) 308.03,86.05 308.03,87.13 308.17,87.27 308.98,87.27 309.03,87.22 309.76,87.22 310.48,87.93 310.48,89.48 308.89,91.06 308.13,91.06 307.71,91.48 RE539.2 ; v1(224.39,8.04) 224.28,8.15 JUSH1.3
CV2_ON_R: length 18.2
  TOP w0.102: RE539.1 306.23,91.04 306.23,89.92 306.98,89.17 RPE10.1 306.98,88.59 307.43,88.14 v1(307.43,88.05)
  TOP w0.107: v1(301.56,77.93) UE1.H8
  BOTTOM w0.102: v1(301.56,77.93) 301.95,78.32 301.95,78.93 302.17,79.14 302.59,79.14 302.75,79.31 302.75,82.47 303.13,82.85 303.13,83.52 304.09,84.47 305.06,84.47 305.44,84.86 305.44,86.37 307.11,88.05 v1(307.43,88.05)
DAT_DDC2_CRT: length 6.4
  TOP w0.102: v1(280.62,52.89) 280.62,52.97 280.26,53.33 279.39,53.33 UV6.16 ; v1(318.5,80.58) 317.84,80.58 317.63,80.8 RV119.1 318,81.3 v2(319.24,81.3) 319.54,81.3 319.95,80.89 JCRT1.12
DAT_TP_SIO_I2C_CLK: length 14.2
  TOP w0.102: v1(212.03,21.67) 212.03,22.61 213.49,24.07 213.49,25.16 214.2,25.88 RZ347.2 215.52,25.88 CZ80.1 ; v1(218.82,21.09) 218.62,20.9 218.62,19.73 218.31,19.41 RZ22.2 ; UE1.C12 296.67,81.22 296.67,82.23 296.57,82.33 v1(296.49,82.33) 295.94,82.87 v2(295.94,83.53)
DAT_TP_SIO_R: length 4.9
  TOP w0.102: JKBTP1.8 214.16,19.15 v2(214.3,19.3) 214.41,19.4 214.41,19.93 214.81,20.34 RZ18.2 RZ22.1 216.9,20.34 CZ88.1
DCIN1_EN: length 7.5
  TOP w0.102: PR1221.1 21.34,39.13 v2(22.1,39.9) v1(22.74,39.9)
  BOTTOM w0.102: v1(49.36,78.81) 49.04,78.5 UE2.12
DCIN2_EN: length 42.8
  BOTTOM w0.102: UE2.15 53.51,77 54.16,77.65 54.16,81.05 53.83,81.38 53.83,83.37 54.23,83.77 54.68,83.77 54.97,83.48 55.81,83.48 57.1,84.78 64.48,84.78 v2(67.18,87.48) 71.03,91.32 71.03,96.95 68.2,99.78 PR26.1
DCIN_ISL88738:
  vias: v2(14.23,19.7)
DDR_A_ACT#: length 9.7
  BOTTOM w0.076: UC1.BA55 105.98,47.83 105.98,47.6 105.93,47.47 105.93,47.36 105.98,47.22 105.98,46.81 105.84,46.67 105.84,46.35 106.1,46.09 106.1,45.4 104.05,43.35 v1(104.05,43.18)
  BOTTOM w0.168: v1(68.55,8.07) 67.52,7.04 JDIMM1.114
DDR_A_ALERT#: length 8.6
  BOTTOM w0.076: UC1.AW50 108.91,48.64 108.91,48.4 108.97,48.27 109,48.19 109,47.95 108.99,47.92 108.94,47.79 108.94,47.7 109.01,47.48 109.01,47.31 108.96,47.19 108.96,46.93 109.07,46.83 109.07,46.26 108.47,45.66 108.47,44.25 108.01,43.79 v1(107.43,43.79)
  BOTTOM w0.168: JDIMM1.116 68.03,6.27 v1(68.55,6.8)
DDR_A_BA0: length 4.6
  BOTTOM w0.076: UC1.AU52 108.46,50.2 v1(108.75,49.91)
  BOTTOM w0.168: v1(76.68,8.07) 78.53,6.22 JDIMM1.150
DDR_A_BA1: length 4.9
  BOTTOM w0.076: v1(109.66,50.58) 110.02,50.85 UC1.AT48
  BOTTOM w0.168: JDIMM1.145 77.27,13 77.27,10.9 v1(78.85,9.32)
DDR_A_BG0: length 13.8
  BOTTOM w0.076: UC1.AY55 106.11,48.61 106.4,48.32 106.48,48.16 106.48,47.98 106.42,47.82 106.42,47.68 106.49,47.46 106.49,47.34 106.46,47.26 106.44,47.23 106.44,46.86 106.65,46.66 106.65,45.71 104.47,43.53 104.47,40.66 v1(103.87,40.06)
  BOTTOM w0.168: JDIMM1.115 67.78,10.72 v1(66.77,9.72)
DDR_A_BG1: length 13.3
  BOTTOM w0.076: UC1.AY54 106.67,48.28 106.67,48.03 106.6,47.81 106.6,47.68 106.66,47.45 106.66,47.31 106.61,47.19 106.61,46.93 106.81,46.73 106.81,45.64 104.71,43.54 104.71,39.63 103.87,38.79 v1(103.87,38.73)
  BOTTOM w0.168: JDIMM1.113 67.27,11.49 v1(66.77,10.99)
DDR_A_CKE0: length 12.7
  BOTTOM w0.076: UC1.BA56 105.55,47.59 105.41,47.45 105.4,47.44 105.4,47.44 105.28,47.19 105.28,47.19 105.28,46.89 105.34,46.82 105.34,46.14 105.47,46.02 105.47,45.59 103.15,43.27 103.15,42.03 v1(103.85,41.33)
  BOTTOM w0.168: JDIMM1.109 66.27,11.42 66.11,11.26 66.11,9.11 v1(66.77,8.45)
DDR_A_CKE1: length 8.4
  BOTTOM w0.076: UC1.BB56 105.51,47.05 105.51,46.21 105.63,46.09 105.63,45.52 103.41,43.3 103.41,42.46 v1(103.86,42.02)
  BOTTOM w0.168: v1(66.3,6.86) 66.52,6.63 JDIMM1.110
DDR_A_CKE2: length 7.8
  BOTTOM w0.076: UC1.AW56 105.76,48.82 105.76,48.62 105.81,48.57 105.81,48.26 105.79,48.2 105.78,48.2 105.78,47.92 105.81,47.84 105.81,47.63 105.76,47.52 105.76,47.3 105.81,47.19 105.81,46.89 105.67,46.75 105.67,46.28 105.8,46.16 105.8,45.42 105.39,45.01 104.88,44.5 104.85,44.5 103.66,43.31 103.66,42.84 103.87,42.63 T3.1
DDR_A_CKE3: length 8
  BOTTOM w0.076: UC1.AY56 105.55,48.18 105.28,47.92 105.28,47.63 105.14,47.27 105.13,47.26 105.12,47.22 105.12,46.14 105.3,45.95 105.3,45.66 102.94,43.29 102.94,41.66 T4.1
DDR_A_CLK0: length 4.8
  BOTTOM w0.094: JDIMM1.137 73.27,12.12 73.36,12.03 73.36,11.68 75.01,10.03 75.35,10.03 v1(75.51,9.87) ; UC1.AT53 107.26,50.85 v1(106.96,50.55)
DDR_A_CLK1: length 5.2
  BOTTOM w0.094: v1(105.96,50.49) 105.96,50.49 106.09,50.49 UC1.AT55 ; v1(75.41,8.45) 75.16,8.2 75.01,8.2 73.68,6.88 73.68,5.98 73.53,5.82 JDIMM1.138
DDR_A_CLK#0: length 5.1
  BOTTOM w0.094: v1(106.91,49.87) 107.03,49.75 107.27,49.75 107.42,49.91 107.42,50.15 UC1.AU53 ; v1(75.51,10.53) 75.51,10.42 75.3,10.22 75.09,10.22 73.55,11.76 73.55,11.89 73.78,12.12 JDIMM1.139
DDR_A_CLK#1: length 4.9
  BOTTOM w0.094: v1(75.41,7.82) 75.41,7.87 75.27,8.02 75.09,8.02 73.87,6.8 73.87,5.98 74.02,5.82 JDIMM1.140 ; v1(105.96,49.86) 105.96,49.96 106.2,50.2 UC1.AU55
DDR_A_CS#0: length 5.6
  BOTTOM w0.076: v1(111.49,49.87) UC1.AU45
  BOTTOM w0.168: JDIMM1.149 78.28,11.08 79.98,9.38 v1(80.7,9.38)
DDR_A_CS#1: length 5.2
  BOTTOM w0.076: v1(112.4,49.87) UC1.AU43
  BOTTOM w0.168: JDIMM1.157 80.28,11.83 82.44,9.67 v1(82.81,9.67)
DDR_A_D0: length 5.9
  BOTTOM w0.076: v1(93.62,52.95) 94.12,53.45 94.91,53.45 95.35,53.89 96.63,53.89 96.65,53.91 UC1.AL71
  BOTTOM w0.102: JDIMM1.7 40.78,11.58 v1(41.37,10.99)
DDR_A_D1: length 6.9
  BOTTOM w0.076: v1(95.52,52.97) 95.72,52.77 96.23,52.77 96.47,53.01 96.98,53.01 97.01,53 97.09,52.97 97.21,52.97 97.43,53.03 97.57,53.03 97.73,52.98 97.91,52.98 98.07,53.05 98.58,53.05 98.79,53.26 UC1.AL68
  BOTTOM w0.102: JDIMM1.3 39.78,11.02 40.2,10.6 v1(40.28,10.6)
DDR_A_D2: length 12.8
  BOTTOM w0.076: UC1.AN68 98.79,52.68 98.21,52.39 97.71,52.39 97.48,52.15 96.54,52.15 96.5,52.11 95.12,52.11 94.18,51.17 90.9,51.17
  BOTTOM w0.102: v1(89.72,51.64) 90.18,51.17 90.9,51.17 ; v1(45.56,10.61) 45.43,10.61 44.27,11.77 JDIMM1.21
DDR_A_D3: length 8.4
  BOTTOM w0.076: UC1.AN69 98.03,52.78 97.78,52.78 97.56,52.86 97.43,52.86 97.2,52.79 97.1,52.79 97.09,52.79 97.08,52.79 97.06,52.79 96.94,52.85 96.54,52.85 96.3,52.6 94.86,52.6 94.22,51.97 v1(93.49,51.97)
  BOTTOM w0.102: v1(43.53,7.94) 43.03,7.43 JDIMM1.16
DDR_A_D4: length 9.5
  BOTTOM w0.076: UC1.AL70 97.34,53.91 97.16,54.08 97.04,54.14 96.92,54.17 96.68,54.17 96.56,54.05 95.26,54.05 94.93,53.73 93.16,53.73 v1(92.37,52.94)
  BOTTOM w0.102: v1(41.5,7.94) 40.03,6.47 JDIMM1.4
DDR_A_D5: length 9.2
  BOTTOM w0.076: UC1.AL69 97.93,53.91 97.67,54.17 97.5,54.17 97.31,54.25 97.31,54.25 97.18,54.29 97.1,54.3 97.03,54.31 96.97,54.33 96.9,54.35 96.6,54.35 96.46,54.22 95.19,54.22 94.86,53.89 92.54,53.89 v1(91.66,53.01)
  BOTTOM w0.102: JDIMM1.8 41.03,6.2 v1(41.5,6.67)
DDR_A_D6: length 11.6
  BOTTOM w0.076: v1(91.1,51.59) 91.34,51.34 94.11,51.34 95.04,52.27 96.44,52.27 96.48,52.32 97.22,52.32 UC1.AN70
  BOTTOM w0.102: v1(45.56,9.34) 45.18,9.72 45.18,10.22 43.27,12.13 JDIMM1.17
DDR_A_D7: length 6.8
  BOTTOM w0.076: v1(92.74,51.87) 93.05,51.56 94.07,51.56 94.95,52.44 96.37,52.44 96.51,52.58 UC1.AN71
  BOTTOM w0.102: v1(43.68,6.82) 44.03,6.47 JDIMM1.20
DDR_A_D8: length 11.4
  BOTTOM w0.076: UC1.AR70 97.34,51.55 97.07,51.82 96.68,51.82 96.64,51.78 95.4,51.78 94.45,50.83 92.29,50.83 91.53,50.07
  BOTTOM w0.102: v1(45.56,6.8) 46.03,6.33 JDIMM1.28 ; 91.53,50.07 90.78,49.32 89.52,49.32 v1(89.46,49.38)
DDR_A_D9: length 12.7
  BOTTOM w0.076: UC1.AR68 98.26,51.75 97.71,51.75 97.48,51.99 96.61,51.99 96.57,51.94 95.3,51.94 94.36,51.01 91.84,51.01 91.01,50.17 v1(90.53,50.17)
  BOTTOM w0.102: JDIMM1.24 45.03,6.44 44.97,6.49 44.97,7.47 v1(45.56,8.07)
DDR_A_D10: length 7.4
  BOTTOM w0.076: UC1.AU71 96.73,50.12 95.72,50.12 94.33,48.73 v1(93.83,48.73)
  BOTTOM w0.102: v1(50.01,7.94) 48.52,6.46 JDIMM1.38
DDR_A_D11: length 8.2
  BOTTOM w0.076: v1(94.25,49.99) 94.59,49.99 95.88,51.28 96.45,51.28 96.61,51.12 96.98,51.12 97.01,51.14 97.09,51.17 97.21,51.17 97.43,51.1 97.57,51.1 97.73,51.16 98.32,51.16 98.34,51.18 98.58,51.18 98.79,50.98 UC1.AU68
  BOTTOM w0.102: v1(49.89,6.9) 49.52,6.54 JDIMM1.42
DDR_A_D12: length 8.4
  BOTTOM w0.076: UC1.AR71 96.78,51.61 95.5,51.61 94.52,50.63 92.65,50.63 92.08,50.06 v1(92.08,49.88)
  BOTTOM w0.102: JDIMM1.29 46.27,12.18 47.34,11.11 v1(47.85,11.11)
DDR_A_D13: length 10.5
  BOTTOM w0.076: UC1.AR69 98.03,51.35 97.78,51.35 97.56,51.28 97.43,51.28 97.2,51.34 97.1,51.34 97.09,51.35 97.08,51.34 97.06,51.34 96.94,51.29 96.68,51.29 96.52,51.45 95.78,51.45 95.2,50.87 94.78,50.45 93.13,50.45 v1(92.74,50.06)
  BOTTOM w0.102: JDIMM1.25 45.27,12.16 47.59,9.84 v1(47.85,9.84)
DDR_A_D14: length 8.2
  BOTTOM w0.076: UC1.AU70 97.21,49.95 95.8,49.95 94.42,48.57 v1(94.42,47.44)
  BOTTOM w0.102: JDIMM1.41 49.27,11.46 v1(50.56,10.18)
DDR_A_D15: length 9.1
  BOTTOM w0.076: UC1.AU69 97.93,50.23 97.55,49.85 97.37,49.85 97.29,49.77 95.85,49.77 94.84,48.76 v1(94.84,48.43)
  BOTTOM w0.102: JDIMM1.37 48.27,11.45 v1(50.64,9.08)
DDR_A_D16: length 2.9
  BOTTOM w0.076: v1(101.05,55.8) UC1.AF65
  BOTTOM w0.102: JDIMM1.194 89.53,6.44 v1(90.01,6.92)
DDR_A_D17: length 2.7
  BOTTOM w0.076: v1(101.69,55.8) UC1.AF64
  BOTTOM w0.102: v1(89.99,10.89) 89.78,11.1 JDIMM1.195
DDR_A_D18: length 4.6
  BOTTOM w0.076: v1(101.05,53.97) 101.02,54.01 UC1.AK65
  BOTTOM w0.102: v1(93.59,8.18) 92.03,6.62 JDIMM1.204
DDR_A_D19: length 4.5
  BOTTOM w0.076: v1(101.69,53.97) UC1.AK64
  BOTTOM w0.102: JDIMM1.203 91.78,11.73 91.66,11.62 91.66,9.84 v1(92.17,9.34)
DDR_A_D20: length 4.6
  BOTTOM w0.076: v1(100.42,55.8) UC1.AF66
  BOTTOM w0.102: JDIMM1.190 88.53,6.33 88.7,6.5 88.7,7.06 89.88,8.24 v1(89.88,8.22)
DDR_A_D21: length 4.5
  BOTTOM w0.076: v1(99.78,55.8) UC1.AF67
  BOTTOM w0.102: v1(90.01,9.59) 88.78,10.83 JDIMM1.191
DDR_A_D22: length 3.2
  BOTTOM w0.076: v1(99.78,53.97) UC1.AK67
  BOTTOM w0.102: JDIMM1.207 92.78,11.21 v1(92.17,10.61)
DDR_A_D23: length 2.8
  BOTTOM w0.076: v1(100.42,53.97) UC1.AK66
  BOTTOM w0.102: JDIMM1.208 93.03,6.25 v1(93.55,6.77)
DDR_A_D24: length 6.7
  BOTTOM w0.076: v1(93.63,56.56) 94.23,57.16 96.67,57.16 97.27,56.56 UC1.AF70
  BOTTOM w0.102: JDIMM1.186 87.53,6.47 v1(87.97,6.92)
DDR_A_D25: length 9
  BOTTOM w0.076: v1(92.43,56.54) 93.21,57.32 96.74,57.32 97.19,56.87 97.83,56.87 97.95,56.75 98.18,56.75 98.25,56.73 UC1.AF68
  BOTTOM w0.102: JDIMM1.174 84.53,6.26 84.92,6.65 v1(84.92,6.67)
DDR_A_D26: length 7.6
  BOTTOM w0.076: v1(92.46,54.92) 92.86,54.52 94.73,54.52 95,54.8 95.93,54.8 96.37,55.23 UC1.AH71
  BOTTOM w0.102: JDIMM1.173 84.28,11.52 84.16,11.4 84.16,10.84 v1(84.54,10.46)
DDR_A_D27: length 7.5
  BOTTOM w0.076: UC1.AH68 98.79,55.89 98.58,56.09 98.13,56.09 98.03,56.16 97.72,56.16 97.59,56.12 97.36,56.12 97.35,56.13 97.35,56.13 97.35,56.13 97.26,56.16 97.06,56.16 96.97,56.13 96.61,56.13 96.56,56.18 95.64,56.18 95.26,55.8 v1(95.26,55.68)
  BOTTOM w0.102: JDIMM1.183 86.78,11.43 87.6,10.61 v1(87.73,10.61)
DDR_A_D28: length 7
  BOTTOM w0.076: v1(94.29,56.56) 94.29,56.68 94.6,56.99 96.4,56.99 UC1.AF71
  BOTTOM w0.102: v1(87.98,8.19) 86.53,6.74 JDIMM1.182
DDR_A_D29: length 7.1
  BOTTOM w0.076: v1(95.47,56.52) 96.45,56.52 96.68,56.29 96.94,56.29 97.03,56.33 97.04,56.33 97.29,56.33 97.38,56.29 97.59,56.29 97.67,56.32 97.67,56.32 97.77,56.36 98.03,56.36 UC1.AF69
  BOTTOM w0.102: v1(87.73,9.34) 88.43,10.04 88.43,11.55 87.78,12.21 JDIMM1.187
DDR_A_D30: length 11.8
  BOTTOM w0.076: 92.26,54.32 94.76,54.32 95.07,54.63 96,54.63 96.34,54.97 96.94,54.97 97.19,55.09 97.28,55.06 97.34,55.09 UC1.AH70
  BOTTOM w0.102: 92.26,54.32 91.31,54.32 v1(90.66,54.98) ; JDIMM1.169 83.28,10.47 v1(84.54,9.21)
DDR_A_D31: length 13.5
  BOTTOM w0.076: 92.08,54.09 94.77,54.09 95.09,54.41 96.16,54.41 97.05,54.84 97.54,54.84 97.93,55.23 UC1.AH69
  BOTTOM w0.102: v1(89.33,54.98) 90.47,53.83 91.82,53.83 92.08,54.09 ; JDIMM1.170 83.53,6.53 v1(84.93,7.94)
DDR_A_D32: length 10.9
  BOTTOM w0.076: UC1.BB65 100.49,46.98 100.49,46.14 99.64,45.29 97.7,45.29 96.86,44.44 96.86,43.84 v1(96.17,43.15)
  BOTTOM w0.102: v1(52.04,7.94) 51.61,7.94 50.52,6.85 JDIMM1.46
DDR_A_D33: length 13
  BOTTOM w0.076: v1(97.69,43.43) 97.39,43.73 97.39,44.16 98,44.77 100.08,44.77 101.64,46.33 101.64,46.66 101.49,46.81 101.49,47.23 101.53,47.34 101.53,47.46 101.47,47.68 101.47,47.82 101.52,47.98 101.52,48.16 101.45,48.32 101.45,48.83 101.24,49.04 UC1.AW65
  BOTTOM w0.102: JDIMM1.62 54.52,6.27 54.57,6.32 54.57,7.31 v1(53.94,7.94)
DDR_A_D34: length 13.9
  BOTTOM w0.076: UC1.AW63 101.82,48.82 102.13,48.51 102.13,47.96 102.35,47.74 102.35,46.1 100.36,44.11 99.06,44.11 98.58,43.63 98.58,41.75 v1(97.8,40.96)
  BOTTOM w0.102: v1(56.1,10.61) 54.78,11.93 JDIMM1.63
DDR_A_D35: length 9.9
  BOTTOM w0.076: v1(97.8,44.04) 98.36,44.6 100.15,44.6 101.83,46.28 101.83,46.75 101.65,46.93 101.65,47.19 101.71,47.31 101.71,47.45 101.64,47.68 101.64,47.81 101.72,48.03 101.72,48.28 UC1.AY63
  BOTTOM w0.102: JDIMM1.45 50.27,12 v1(51.46,10.82)
DDR_A_D36: length 9.1
  BOTTOM w0.076: UC1.BA65 100.59,47.59 100.45,47.45 100.45,47.44 100.44,47.44 100.33,47.19 100.33,46.21 99.57,45.46 97.59,45.46 96.65,44.52 96.65,44.24 v1(96.14,43.73)
  BOTTOM w0.102: v1(51.69,6.88) 51.69,6.32 51.52,6.16 JDIMM1.50
DDR_A_D37: length 8.9
  BOTTOM w0.076: UC1.AY65 100.59,48.18 100.33,47.92 100.33,47.63 100.27,47.5 100.27,47.46 100.24,47.39 100.16,47.23 100.16,46.28 99.5,45.62 97.45,45.62 v1(96.17,44.34)
  BOTTOM w0.102: v1(52.04,11.6) 51.81,11.82 51.5,11.82 51.27,12.05 JDIMM1.49
DDR_A_D38: length 12.8
  BOTTOM w0.076: v1(97.8,42.26) 98.35,42.81 98.35,43.63 98.99,44.27 100.29,44.27 102.18,46.17 102.18,47.26 101.92,47.52 UC1.BA63
  BOTTOM w0.102: v1(56.1,9.34) 53.78,11.66 JDIMM1.59
DDR_A_D39: length 8.8
  BOTTOM w0.076: v1(97.82,42.84) 98.13,43.15 98.13,43.64 98.92,44.44 100.22,44.44 102,46.21 102,47.01 UC1.BB63
  BOTTOM w0.102: v1(53.94,6.67) 53.52,6.25 JDIMM1.58
DDR_A_D40: length 8.7
  BOTTOM w0.076: UC1.BA61 102.95,47.51 102.68,47.25 102.68,45.96 99.78,43.06 99.78,42.83 v1(99.39,42.44)
  BOTTOM w0.102: v1(55.89,6.62) 55.52,6.26 JDIMM1.66
DDR_A_D41: length 10.6
  BOTTOM w0.076: UC1.AW61 103.05,48.85 102.72,48.52 102.72,47.98 102.52,47.77 102.52,46.03 100.23,43.74 v1(99.39,43.74)
  BOTTOM w0.102: JDIMM1.70 56.52,7.52 v1(56.1,7.94)
DDR_A_D42: length 11.9
  BOTTOM w0.076: v1(101.3,40.68) 102.22,41.6 102.22,43.57 104.13,45.48 104.13,46.06 104.37,46.3 104.37,46.98 UC1.BB59
  BOTTOM w0.102: v1(60.85,9.72) 58.78,11.8 JDIMM1.79
DDR_A_D43: length 12.4
  BOTTOM w0.076: v1(101.3,41.98) 100.91,42.37 100.91,43.48 103.18,45.75 103.18,46.66 103.38,46.86 103.38,47.22 103.38,47.22 103.34,47.31 103.34,47.51 103.38,47.6 103.38,47.6 103.38,47.6 103.39,47.61 103.39,47.84 103.34,47.97 103.34,48.22 103.42,48.32 103.42,48.83 103.62,49.04 UC1.AW59
  BOTTOM w0.102: v1(59.53,7.95) 60.03,7.46 JDIMM1.84
DDR_A_D44: length 11.8
  BOTTOM w0.076: v1(99.42,41.76) 99.99,42.33 99.99,43.03 102.85,45.89 102.85,46.98 UC1.BB61
  BOTTOM w0.102: v1(58.36,9.11) 56.65,10.82 56.65,11.26 55.78,12.13 JDIMM1.67
DDR_A_D45: length 12.8
  BOTTOM w0.076: v1(99.4,40.51) 100.16,41.27 100.16,42.98 103.01,45.82 103.01,46.73 103.21,46.93 103.21,47.19 103.18,47.28 103.18,47.29 103.18,47.54 103.21,47.63 103.21,47.84 103.18,47.92 103.18,47.92 103.15,48.02 103.15,48.28 UC1.AY61
  BOTTOM w0.102: JDIMM1.71 56.78,11.86 v1(58.26,10.38)
DDR_A_D46: length 11.5
  BOTTOM w0.076: v1(101.3,40.03) 102.41,41.14 102.41,43.51 104.3,45.39 104.3,45.99 104.54,46.23 104.54,47.18 104.48,47.33 UC1.BA59
  BOTTOM w0.102: JDIMM1.83 59.78,11.85 v1(60.64,10.99)
DDR_A_D47: length 13.6
  BOTTOM w0.076: UC1.AY59 104.27,48.18 104.54,47.92 104.54,47.72 104.67,47.29 104.7,47.22 104.7,46.16 104.46,45.92 104.46,45.31 102.61,43.46 102.61,40.05 v1(101.3,38.74)
  BOTTOM w0.102: v1(59.42,7) 59.03,6.61 JDIMM1.80
DDR_A_D48: length 4.6
  BOTTOM w0.076: v1(99.6,50.5) 99.95,50.85 UC1.AT66
  BOTTOM w0.102: v1(95.35,9.72) 95.22,9.72 93.78,11.16 JDIMM1.211
DDR_A_D49: length 3.2
  BOTTOM w0.076: v1(99.6,49.87) UC1.AU66
  BOTTOM w0.102: JDIMM1.215 94.78,12.17 94.61,12 94.61,11.36 94.98,10.99 v1(95.35,10.99)
DDR_A_D50: length 4.4
  BOTTOM w0.076: v1(100.51,52.41) 100.77,52.15 UC1.AP65
  BOTTOM w0.102: v1(98.71,9.75) 97.28,11.18 JDIMM1.225
DDR_A_D51: length 2.9
  BOTTOM w0.076: UC1.AN65 100.76,52.8 v1(100.51,53.04)
  BOTTOM w0.102: JDIMM1.229 98.28,11.32 98.63,10.97 v1(98.79,10.97)
DDR_A_D52: length 2.9
  BOTTOM w0.076: v1(99.6,52.41) 99.99,52.8 UC1.AN66
  BOTTOM w0.102: JDIMM1.216 95.03,5.89 94.95,5.96 94.95,6.57 v1(95.32,6.94)
DDR_A_D53: length 4.7
  BOTTOM w0.076: v1(99.6,51.77) UC1.AP66
  BOTTOM w0.102: JDIMM1.212 94.03,6.09 94.17,6.23 94.17,7.29 v1(95.28,8.4)
DDR_A_D54: length 4.5
  BOTTOM w0.076: v1(100.51,50.5) 100.86,50.85 UC1.AT65
  BOTTOM w0.102: v1(98.48,8.07) 98.48,8.02 97.03,6.56 JDIMM1.224
DDR_A_D55: length 2
  BOTTOM w0.076: v1(100.51,49.87) 100.85,50.2 UC1.AU65
  BOTTOM w0.102: JDIMM1.228 98.03,6.11 v1(97.97,6.16)
DDR_A_D56: length 5.3
  BOTTOM w0.076: v1(102.34,50.5) 102.69,50.85 UC1.AT61
  BOTTOM w0.102: v1(100.78,8.95) 99.28,10.45 JDIMM1.233
DDR_A_D57: length 3.4
  BOTTOM w0.076: UC1.AU61 102.68,50.2 v1(102.34,49.87)
  BOTTOM w0.102: JDIMM1.237 100.28,10.87 v1(100.77,10.38)
DDR_A_D58: length 3.8
  BOTTOM w0.102: JDIMM1.246 102.53,6.48 v1(103.6,7.56) ; v1(103.26,52.41) 103.51,52.15 UC1.AP60
DDR_A_D59: length 2
  BOTTOM w0.076: v1(103.26,53.06) 103.51,52.8 UC1.AN60
  BOTTOM w0.102: v1(103.6,6.16) 103.53,6.16 JDIMM1.250
DDR_A_D60: length 2.8
  BOTTOM w0.076: v1(102.34,52.41) 102.74,52.8 UC1.AN61
  BOTTOM w0.102: v1(100.55,6.74) 100.47,6.74 100.03,6.29 JDIMM1.236
DDR_A_D61: length 4.6
  BOTTOM w0.076: UC1.AP61 102.72,52.15 v1(102.34,51.77)
  BOTTOM w0.102: v1(100.54,8.2) 99.03,6.68 JDIMM1.232
DDR_A_D62: length 2.8
  BOTTOM w0.076: UC1.AT60 103.61,50.85 v1(103.26,50.5)
  BOTTOM w0.102: JDIMM1.249 103.28,11.44 v1(103.73,10.99)
DDR_A_D63: length 2.8
  BOTTOM w0.076: v1(103.26,49.87) 103.59,50.2 UC1.AU60
  BOTTOM w0.102: JDIMM1.245 102.28,11.62 v1(102.82,11.07)
DDR_A_DQS0: length 13.1
  BOTTOM w0.076: UC1.AM69 98.22,53.34 98.14,53.42 98.14,53.52 98.03,53.63 97.89,53.7 97.75,53.7 97.56,53.65 97.39,53.65 97.31,53.68 97.1,53.68 96.91,53.63 96.69,53.63 96.6,53.72 95.51,53.72 94.9,53.11 94.7,52.91 94.4,52.91 94.02,52.53 91.06,52.53
  BOTTOM w0.099: JDIMM1.13 42.27,12.12 42.14,11.99 42.14,11.17 42.88,10.43 43.1,10.43 v1(43.4,10.73) ; 91.06,52.53 90.27,52.53 90.17,52.63 90.17,52.78 v1(90.4,53.01)
DDR_A_DQS1: length 10.6
  BOTTOM w0.076: UC1.AT70 97.72,50.89 97.49,50.66 97.34,50.66 97.23,50.61 97.09,50.61 96.97,50.66 96.94,50.66 96.48,50.66 96.32,50.49 95.39,50.49 94.21,49.32 92.93,49.32 92.61,49 92.61,48.41 92.42,48.22 v1(92.31,48.22)
  BOTTOM w0.099: JDIMM1.34 47.52,5.82 47.37,5.98 47.37,6.18 47.71,6.52 47.71,7 47.27,7.43 46.97,7.43 46.83,7.58 v1(46.83,7.68)
DDR_A_DQS2: length 4.2
  BOTTOM w0.099: JDIMM1.200 91.03,6.65 91.76,7.39 91.76,7.71 v1(91.98,7.92) ; v1(101.05,54.88) 100.95,54.88 100.74,55.09 UC1.AH65
DDR_A_DQS3: length 9.7
  BOTTOM w0.076: UC1.AG70 97.74,55.9 97.49,55.65 97.39,55.65 arc(97.3,55.64) 97.21,55.61 97.2,55.61 arc(97.12,55.59) 97.05,55.62 97.04,55.63 arc(96.93,55.67) 96.81,55.68 96.49,55.63 96.49,55.63 96.2,55.55 95.83,55.18 94.75,55.18 94.51,54.94 93.34,54.94 93.26,55.02 93.26,55.59 v1(93.52,55.85)
  BOTTOM w0.099: v1(85.98,10.67) 85.98,10.52 85.69,10.23 85.51,10.23 85.35,10.39 85.35,10.88 85.46,10.99 85.46,11.96 85.78,12.27 JDIMM1.179
DDR_A_DQS4: length 15.2
  BOTTOM w0.076: UC1.AY64 101.16,48.56 100.86,48.27 100.86,47.63 100.81,47.52 100.81,47.3 100.86,47.19 100.86,46.93 100.7,46.77 100.7,45.96 99.86,45.13 97.81,45.13 97.06,44.37 97.06,42.09 96.56,41.58 96.24,41.58 96.1,41.72 v1(96.1,41.85)
  BOTTOM w0.099: JDIMM1.55 52.78,10.24 53.24,9.78 53.62,9.78 v1(53.94,10.1)
DDR_A_DQS5: length 10.3
  BOTTOM w0.076: v1(101.3,43.28) 101.3,43.17 101.51,42.96 101.69,42.96 101.77,43.04 101.77,43.76 103.69,45.68 103.69,46.08 104,46.39 104,46.65 103.84,46.81 103.84,47.23 103.85,47.26 103.89,47.34 103.89,47.46 103.86,47.54 103.84,47.6 103.84,47.98 103.76,48.06 UC1.BA60
  BOTTOM w0.099: v1(57.25,7.65) 57.25,7.31 57.37,7.18 57.66,7.18 57.87,6.97 57.87,5.98 58.03,5.82 JDIMM1.76
DDR_A_DQS6: length 4.1
  BOTTOM w0.099: v1(96.76,11.03) 96.76,10.89 96.45,10.58 96.21,10.58 95.96,10.83 95.96,11.88 96.28,12.19 JDIMM1.221 ; v1(100.51,51.14) 100.51,51.24 100.7,51.43 100.71,51.43 100.78,51.5 UC1.AR65
DDR_A_DQS7: length 3.9
  BOTTOM w0.076: v1(103.26,51.77) 103.53,51.5 UC1.AR60
  BOTTOM w0.099: JDIMM1.242 101.53,5.67 101.36,5.83 101.36,7.08 101.56,7.27 101.97,7.27 102.07,7.17 v1(102.07,7.01)
DDR_A_DQS#0: length 13.4
  BOTTOM w0.076: 91.06,52.34 91.07,52.34 91.09,52.36 91.14,52.36 91.15,52.37 94.09,52.37 94.47,52.75 94.77,52.75 95.58,53.56 96.53,53.56 96.62,53.47 96.93,53.47 97.12,53.52 97.28,53.52 97.35,53.48 97.58,53.48 97.77,53.54 97.85,53.54 97.94,53.49 97.98,53.45 97.98,53.32 97.9,53.25 UC1.AM70
  BOTTOM w0.099: v1(89.75,53.01) 89.99,52.77 89.99,52.55 90.2,52.34 91.06,52.34 ; v1(43.4,10.1) 43.26,10.24 42.8,10.24 41.95,11.09 41.95,11.97 41.78,12.15 JDIMM1.11
DDR_A_DQS#1: length 10.5
  BOTTOM w0.076: v1(92.96,48.21) 92.78,48.39 92.78,48.94 93,49.15 94.28,49.15 95.45,50.33 96.39,50.33 96.55,50.5 96.87,50.5 96.87,50.5 96.94,50.5 97.05,50.44 97.27,50.44 97.38,50.49 98.07,50.49 UC1.AT69
  BOTTOM w0.099: v1(46.83,7.05) 47.03,7.25 47.2,7.25 47.52,6.93 47.52,6.6 47.18,6.26 47.18,5.98 47.03,5.82 JDIMM1.32
DDR_A_DQS#2: length 4.4
  BOTTOM w0.099: JDIMM1.198 90.53,5.68 90.84,5.99 90.84,6.73 91.57,7.47 91.57,7.82 91.47,7.92 v1(91.26,7.92) ; v1(100.42,54.88) 100.09,55.21 UC1.AH66
DDR_A_DQS#3: length 10.1
  BOTTOM w0.076: UC1.AG69 97.57,55.49 97.39,55.49 arc(97.34,55.48) 97.28,55.46 97.27,55.46 arc(97.11,55.43) 96.96,55.48 96.95,55.49 arc(96.9,55.51) 96.84,55.51 96.83,55.51 96.53,55.47 96.51,55.47 96.28,55.4 95.9,55.02 94.82,55.02 94.58,54.78 93.27,54.78 93.09,54.95 93.09,55.2 v1(92.83,55.47)
  BOTTOM w0.099: JDIMM1.177 85.28,12.04 85.27,12.04 85.27,11.07 85.16,10.95 85.16,10.31 85.43,10.04 85.89,10.04 v1(85.98,9.95)
DDR_A_DQS#4: length 15
  BOTTOM w0.076: v1(96.1,41.2) 96.32,41.42 96.62,41.42 97.22,42.02 97.22,44.3 97.88,44.96 99.93,44.96 100.86,45.89 100.86,46.7 101.02,46.86 101.02,47.23 100.97,47.34 100.97,47.36 100.97,47.47 101.02,47.6 101.02,47.83 UC1.BA64
  BOTTOM w0.099: v1(53.94,9.46) 53.82,9.59 53.16,9.59 52.59,10.16 52.59,12 52.27,12.31 JDIMM1.53
DDR_A_DQS#5: length 10.3
  BOTTOM w0.076: UC1.AY60 104.01,48.06 104.01,47.63 104.03,47.59 104.04,47.53 104.06,47.45 104.06,47.31 104.01,47.19 104.01,46.88 104.17,46.72 104.17,46.33 103.85,46.01 103.85,45.61 101.93,43.69 101.93,42.97 101.76,42.8 101.46,42.8 v1(101.3,42.63)
  BOTTOM w0.099: JDIMM1.74 57.52,5.82 57.68,5.98 57.68,6.9 57.58,6.99 57.44,6.99 57.25,6.8 v1(57.25,6.8)
DDR_A_DQS#6: length 4
  BOTTOM w0.099: JDIMM1.219 95.78,10.75 96.13,10.4 96.67,10.4 v1(96.76,10.31) ; UC1.AR66 100.33,51.77 v1(100.51,51.77)
DDR_A_DQS#7: length 4.2
  BOTTOM w0.076: v1(103.26,51.14) 102.89,51.5 UC1.AR61
  BOTTOM w0.099: v1(102.07,7.73) 102.07,7.62 101.91,7.46 101.48,7.46 101.17,7.16 101.17,5.73 101.03,5.58 JDIMM1.240
DDR_A_MA0: length 10.2
  BOTTOM w0.076: UC1.AY50 109.23,48.16 109.72,47.67 109.72,46.21 108.98,45.47 108.98,43.84 107.94,42.8 v2(107.94,41.74) v1(107.28,41.08)
  BOTTOM w0.168: JDIMM1.144 75.02,6.47 v1(75,6.49)
DDR_A_MA1: length 8.8
  BOTTOM w0.076: UC1.BB50 109.31,47.01 109.31,46.27 108.64,45.59 108.64,44.16 107.58,43.11 107.36,43.11 v1(107.28,43.03)
  BOTTOM w0.168: JDIMM1.133 72.27,11.44 73.49,10.22 v1(73.97,10.22)
DDR_A_MA2: length 12.3
  BOTTOM w0.076: v1(107.28,40.44) 106.79,40.92 v2(106.79,43.33) 106.79,43.69 107.28,44.17 107.58,44.17 107.61,44.15 108.01,44.15 108.3,44.44 108.3,45.73 108.9,46.33 108.9,46.76 108.8,46.86 108.8,47.23 108.84,47.34 108.84,47.46 108.78,47.68 108.78,47.75 108.77,47.78 108.79,47.84 108.83,47.98 108.83,48.16 UC1.AY51
  BOTTOM w0.168: v1(72.99,6.8) 72.99,6.68 72.61,6.3 72.61,6.16 72.03,5.57 JDIMM1.132
DDR_A_MA3: length 11.3
  BOTTOM w0.076: UC1.BA50 109.53,47.43 109.53,46.26 108.8,45.53 108.8,43.9 v1(107.28,42.38)
  BOTTOM w0.168: v1(73.66,8.91) 73.66,9.3 71.78,11.19 JDIMM1.131
DDR_A_MA4: length 8
  BOTTOM w0.076: UC1.BB52 107.8,46.99 107.8,45.23 106.06,43.48 v1(106.06,43.03)
  BOTTOM w0.168: JDIMM1.128 71.03,6.48 71.72,7.18 v1(72.23,7.18)
DDR_A_MA5: length 8.3
  BOTTOM w0.076: UC1.BA51 108.34,47.84 108.34,47.61 108.34,47.6 108.33,47.6 108.33,47.6 108.3,47.51 108.3,47.31 108.33,47.22 108.33,46.86 108.14,46.66 108.14,44.81 v1(107.86,44.53)
  BOTTOM w0.168: JDIMM1.126 70.52,6.99 71.98,8.45 v1(72.23,8.45)
DDR_A_MA6: length 8.8
  BOTTOM w0.076: UC1.BA52 107.9,47.51 107.64,47.25 107.64,45.3 105.69,43.35 105.69,42.54 105.86,42.38 v1(106.06,42.38)
  BOTTOM w0.168: JDIMM1.127 70.78,11.38 71.14,11.01 v1(71.27,11.01)
DDR_A_MA7: length 11.4
  BOTTOM w0.076: v1(106.06,41.08) 105.52,41.61 105.52,43.42 107.47,45.36 107.47,47.77 107.68,47.98 107.68,48.52 108,48.85 UC1.AW52
  BOTTOM w0.168: v1(70.07,6.8) 69.52,6.25 JDIMM1.122
DDR_A_MA8: length 15.1
  BOTTOM w0.076: v1(106.06,37.94) 106.48,38.36 106.48,43.67 107.97,45.16 107.97,46.73 108.17,46.93 108.17,47.19 108.13,47.28 108.13,47.29 108.13,47.54 108.17,47.63 108.17,47.84 108.14,47.92 108.14,47.92 108.1,48.02 108.1,48.28 UC1.AY52
  BOTTOM w0.168: JDIMM1.125 70.27,11.95 70.35,11.88 70.35,10.65 v1(71.27,9.74)
DDR_A_MA9: length 12.2
  BOTTOM w0.076: UC1.BB54 106.98,46.98 106.98,45.57 104.9,43.49 104.9,41.49 105.27,41.11 105.27,39.38 v1(106.06,38.59)
  BOTTOM w0.168: JDIMM1.121 69.27,11.5 69.74,11.04 v1(69.89,11.04)
DDR_A_MA10: length 2.7
  BOTTOM w0.076: v1(108.74,50.5) UC1.AT50
  BOTTOM w0.168: JDIMM1.146 77.53,5.69 v1(76.68,6.54)
DDR_A_MA11: length 13.6
  BOTTOM w0.076: UC1.BA54 106.87,47.52 107.14,47.26 107.14,45.5 105.88,44.24 105.09,43.45 105.09,41.53 105.44,41.18 105.44,39.87 v1(106.06,39.24)
  BOTTOM w0.168: v1(70.07,8.07) 69.03,7.02 JDIMM1.120
DDR_A_MA12: length 12.9
  BOTTOM w0.076: v1(106.06,40.43) 105.6,40.88 105.6,41.25 105.28,41.57 105.28,43.4 107.31,45.43 107.31,47.74 107.08,47.96 107.08,48.51 106.77,48.82 UC1.AW54
  BOTTOM w0.168: v1(69.03,10.22) 68.78,10.48 JDIMM1.119
DDR_A_MA13: length 1.8
  BOTTOM w0.076: v1(110.57,49.87) UC1.AU46
  BOTTOM w0.168: v1(80.61,6.03) 80.53,5.95 JDIMM1.158
DDR_A_MA14: length 3
  BOTTOM w0.076: v1(110.57,51.14) UC1.AT46
  BOTTOM w0.168: JDIMM1.151 78.78,11.3 79.24,10.84 v1(79.38,10.84)
DDR_A_MA15: length 3.3
  BOTTOM w0.076: v1(110.57,50.5) UC1.AU48
  BOTTOM w0.168: JDIMM1.156 80.03,6.72 v1(80.61,7.3)
DDR_A_MA16: length 2.9
  BOTTOM w0.076: v1(109.66,49.86) 109.54,49.86 109.2,50.2 UC1.AU50
  BOTTOM w0.168: v1(79.47,6.92) 79.03,6.48 JDIMM1.152
DDR_A_ODT0: length 4.8
  BOTTOM w0.076: UC1.AT45 111.83,50.85 v1(111.49,50.5)
  BOTTOM w0.168: JDIMM1.155 79.78,11.61 v1(81.74,9.64)
DDR_A_ODT1: length 3.6
  BOTTOM w0.076: v1(112.41,50.5) 112.43,50.5 112.78,50.85 UC1.AT43
  BOTTOM w0.168: JDIMM1.161 81.28,11.84 82,11.11 82.56,11.11 v1(82.73,10.94)
DDR_A_PARITY: length 3.6
  BOTTOM w0.076: v1(107.81,50.52) 108.14,50.85 UC1.AT52
  BOTTOM w0.168: JDIMM1.143 74.78,12.25 75.29,11.74 76.32,11.74 v1(76.66,11.4)
DDR_B_ACT#: length 2.3
  BOTTOM w0.076: UC1.AN53 107.29,52.81 106.93,52.49 v1(106.87,52.5)
  BOTTOM w0.168: JDIMM2.114 148.52,5.63 v1(147.93,6.22)
DDR_B_ALERT#: length 1.9
  BOTTOM w0.102: v1(112.43,53.09) 112.6,53.09 112.86,52.84 UC1.AN43
  BOTTOM w0.168: JDIMM2.116 v1(149.03,6.14)
DDR_B_BA0: length 10.3
  BOTTOM w0.076: v1(112.19,41.62) 113.02,42.45 113.02,45.45 112.61,45.85 112.61,46.98 UC1.BB44
  BOTTOM w0.168: JDIMM2.150 159.53,7.24 158.32,8.45 v1(158.19,8.45)
DDR_B_BA1: length 7.3
  BOTTOM w0.076: UC1.BA44 112.45,47.47 112.45,45.69 112.64,45.5 v2(112.64,44.98) 112.64,42.68 v1(112.21,42.26)
  BOTTOM w0.168: v1(158.17,11.58) 158.28,11.68 JDIMM2.145
DDR_B_BG0: length 4.9
  BOTTOM w0.076: v1(107.83,51.77) 108.21,52.15 UC1.AP52
  BOTTOM w0.168: JDIMM2.115 148.78,11.64 147.67,10.53 147.42,10.53 v1(146.65,9.76)
DDR_B_BG1: length 3.7
  BOTTOM w0.076: v1(108.74,52.41) 108.68,52.41 UC1.AN52
  BOTTOM w0.168: v1(146.83,10.75) 146.92,10.75 147.21,11.04 147.58,11.04 148.28,11.74 JDIMM2.113
DDR_B_CKE0: length 6.3
  BOTTOM w0.076: UC1.AN56 105.75,52.8 105.81,52.86 106.08,52.86 106.32,53.1 v1(106.84,53.1)
  BOTTOM w0.168: v1(145.08,9.07) 145.94,9.93 145.94,10.85 147.28,12.18 JDIMM2.109
DDR_B_CKE1: length 2.1
  BOTTOM w0.076: v1(106,51.71) 106.01,51.78 UC1.AP55
  BOTTOM w0.168: JDIMM2.110 147.52,5.69 v1(147.15,6.06)
DDR_B_CKE2: length 1.6
  TOP w0.168: T5.1 105.42,53.01 v1(105.95,52.48)
  BOTTOM w0.076: v1(105.95,52.48) 106.03,52.48 106.36,52.8 UC1.AN55
DDR_B_CKE3: length 3.3
  TOP w0.168: v1(106.94,51.74) 106.94,51.79 107.65,52.51 T6.1
  BOTTOM w0.076: UC1.AP53 106.94,51.8 v1(106.94,51.74)
DDR_B_CLK0: length 4
  BOTTOM w0.076: UC1.AP45 112.2,52.41 v1(112.4,52.41)
  BOTTOM w0.094: v1(155.02,10.1) 154.86,10.26 154.52,10.26 154.24,10.54 154.24,11.42 154.28,11.45 JDIMM2.137
DDR_B_CLK1: length 3.7
  BOTTOM w0.094: v1(155.53,7.3) 155.27,7.05 154.94,7.05 154.65,6.76 154.65,5.7 154.53,5.57 JDIMM2.138 ; v1(111.49,51.77) 111.11,52.15 UC1.AP46
DDR_B_CLK#0: length 4.1
  BOTTOM w0.076: v1(111.49,52.41) 111.8,52.41 111.94,52.56 UC1.AN45
  BOTTOM w0.094: JDIMM2.139 154.78,12.21 154.46,11.9 154.46,11.37 154.43,11.34 154.43,10.62 154.6,10.45 154.79,10.45 155.02,10.68 v1(155.02,10.74)
DDR_B_CLK#1: length 3.4
  BOTTOM w0.094: UC1.AN46 110.97,52.8 v1(110.57,52.41) ; v1(155.53,6.67) 155.34,6.86 155.02,6.86 154.85,6.68 154.85,5.72 155.03,5.55 JDIMM2.140
DDR_B_CS#0: length 5.9
  BOTTOM w0.076: UC1.BB42 114.08,47.05 114.08,45.66 v1(114.53,45.2)
  BOTTOM w0.168: JDIMM2.149 159.28,11.07 v1(160.61,9.74)
DDR_B_CS#1: length 6.3
  BOTTOM w0.076: UC1.AY42 114.34,48.09 114.34,46.89 114.24,46.8 114.24,46.17 v1(114.54,45.87)
  BOTTOM w0.168: JDIMM2.157 161.28,12.15 162.59,10.84 163.23,10.84 v1(163.33,10.74)
DDR_B_D0: length 11.4
  BOTTOM w0.076: v1(116.14,40.32) 116.01,40.32 114.98,41.35 114.98,46.73 114.88,46.82 114.88,46.87 114.88,46.87 114.88,46.91 114.88,46.91 114.88,47.23 114.95,47.36 114.95,47.38 115.05,47.63 115.05,47.92 115.32,48.18 UC1.AY39
  BOTTOM w0.102: v1(122.51,7.18) 122.51,7.12 122.03,6.64 JDIMM2.8
DDR_B_D1: length 8
  BOTTOM w0.076: UC1.AW39 115.97,49.04 116.23,48.77 116.23,48.2 116.25,48.16 116.25,47.98 116.19,47.82 116.19,47.68 116.26,47.46 116.26,47.34 116.21,47.23 116.21,46.85 116.39,46.67 116.39,46.05 v1(116.17,45.83)
  BOTTOM w0.102: JDIMM2.3 120.78,11.74 120.2,11.16 119.42,11.16 v1(118.7,10.44)
DDR_B_D2: length 6
  BOTTOM w0.076: v1(116.3,45.24) 116.3,45.33 116.56,45.59 116.56,46.74 116.38,46.92 116.38,47.19 116.43,47.31 116.43,47.45 116.37,47.68 116.37,47.81 116.44,48.03 116.44,48.28 UC1.AY37
  BOTTOM w0.102: JDIMM2.16 124.03,6.67 v1(123.52,7.18)
DDR_B_D3: length 10.6
  BOTTOM w0.076: v1(117.81,41) v2(117.37,41.44) 117.07,41.74 117.07,47.74 116.85,47.96 116.85,48.51 116.54,48.82 UC1.AW37
  BOTTOM w0.102: JDIMM2.20 125.03,6.31 124.82,6.51 v1(124.82,6.77)
DDR_B_D4: length 9.4
  BOTTOM w0.076: v1(116.13,42.13) 115.37,42.89 115.37,45.06 115.32,45.11 115.32,47.08 UC1.BB39
  BOTTOM w0.102: v1(120.02,10) 120.71,10 121.36,10.66 121.36,10.88 121.48,11 121.48,11.7 121.67,11.89 121.67,12.9 JDIMM2.7
DDR_B_D5: length 9.4
  BOTTOM w0.076: v1(116.06,41.5) 115.16,42.4 115.16,46.79 115.05,46.89 115.05,47.19 115.17,47.44 115.17,47.44 115.18,47.45 115.32,47.59 UC1.BA39
  BOTTOM w0.102: v1(120.86,7.18) 121.24,6.8 121.24,6.03 121.03,5.82 JDIMM2.4
DDR_B_D6: length 12.2
  BOTTOM w0.076: v1(117.81,40.39) 116.91,41.29 116.91,47.47 UC1.BA37
  BOTTOM w0.102: v1(123.47,9.72) 124.03,9.72 125.09,10.78 125.09,11.28 125.28,11.46 JDIMM2.21
DDR_B_D7: length 10.6
  BOTTOM w0.076: v1(117.79,39.22) 116.72,40.29 116.72,46.81 116.64,46.89 UC1.BB37
  BOTTOM w0.102: JDIMM2.17 124.28,11.79 124.29,11.78 124.29,11.37 123.91,10.99 v1(123.78,10.99)
DDR_B_D8: length 8.5
  BOTTOM w0.076: UC1.AY35 117.87,48.28 117.87,48.02 117.91,47.92 117.91,47.92 117.94,47.84 117.94,47.63 117.9,47.54 117.9,47.28 117.94,47.19 117.94,46.92 117.75,46.74 117.75,45.66 118.36,45.05 118.36,43.41 v1(117.83,42.87)
  BOTTOM w0.102: v1(126.44,6.92) 127.03,6.34 JDIMM2.28
DDR_B_D9: length 10.1
  BOTTOM w0.076: UC1.AW35 117.77,48.85 117.45,48.52 117.45,47.98 117.35,47.87 117.35,47.42 117.24,47.32 117.24,45.36 117.26,45.34 117.26,42.18 v1(117.82,41.62)
  BOTTOM w0.102: JDIMM2.24 126.03,6.2 v1(125.43,6.8)
DDR_B_D10: length 10.4
  BOTTOM w0.076: UC1.AY33 119,48.18 119.27,47.91 119.27,47.59 119.34,47.44 119.43,47.25 119.43,46.86 119.3,46.74 119.3,46.74 119.28,46.71 119.28,46.37 119.67,45.97 119.67,45.01 120,44.68 120,41.2 v1(119.66,40.86)
  BOTTOM w0.102: v1(130.83,6.93) 130.53,6.63 JDIMM2.42
DDR_B_D11: length 12.6
  BOTTOM w0.076: v1(119.61,40.28) 118.53,41.36 118.53,45.11 117.92,45.72 117.92,46.37 118.1,46.55 118.1,46.85 118.1,46.85 118.1,47.22 118.1,47.22 118.07,47.31 118.07,47.51 118.1,47.6 118.1,47.6 118.11,47.6 118.11,47.61 118.11,47.84 118.07,47.97 118.07,48.22 118.14,48.32 118.14,48.83 118.35,49.04 UC1.AW33
  BOTTOM w0.102: JDIMM2.38 129.53,6.45 v1(130,6.92)
DDR_B_D12: length 8
  BOTTOM w0.076: UC1.BB35 117.59,47 117.59,45.59 118.2,44.98 118.2,43.89 v1(117.83,43.52)
  BOTTOM w0.102: v1(125.81,9.72) 125.94,9.72 127.28,11.06 JDIMM2.29
DDR_B_D13: length 5.4
  BOTTOM w0.076: UC1.BA35 117.67,47.51 117.4,47.25 117.4,45.43 117.71,45.12 v1(117.71,44.75)
  BOTTOM w0.102: v1(125.81,10.99) 126.28,11.45 JDIMM2.25
DDR_B_D14: length 5.9
  BOTTOM w0.076: v1(119.6,44.53) 119.46,44.66 119.46,45.95 119.11,46.3 119.11,46.78 119.12,46.79 119.12,46.79 119.26,46.93 119.26,47.21 119.18,47.4 119,47.71 UC1.BA33
  BOTTOM w0.102: JDIMM2.37 129.28,11.98 129.49,11.76 129.49,11.29 v1(129.11,10.91)
DDR_B_D15: length 7.4
  BOTTOM w0.076: UC1.BB33 118.95,47.03 118.95,46.23 119.21,45.96 119.21,44.23 v1(119.51,43.93)
  BOTTOM w0.102: v1(129.06,9.57) 129.16,9.57 129.74,10.14 129.74,10.64 130.02,10.92 130.02,11.83 130.28,12.09 JDIMM2.41
DDR_B_D16: length 4
  BOTTOM w0.076: v1(114.14,49.81) UC1.AU40
  BOTTOM w0.102: JDIMM2.170 164.53,6.5 164.6,6.57 164.6,7.48 v1(165.05,7.94)
DDR_B_D17: length 2.6
  BOTTOM w0.076: v1(114.14,50.5) 114.27,50.5 UC1.AT40
  BOTTOM w0.102: JDIMM2.174 165.53,6.48 v1(165.33,6.67)
DDR_B_D18: length 4.1
  BOTTOM w0.076: v1(116.06,50.5) UC1.AT37
  BOTTOM w0.102: JDIMM2.182 167.53,6.24 167.37,6.4 167.37,7.34 v1(168,7.97)
DDR_B_D19: length 2.7
  BOTTOM w0.076: v1(116.06,49.85) UC1.AU37
  BOTTOM w0.102: v1(167.97,6.67) 168.53,6.12 JDIMM2.186
DDR_B_D20: length 2.6
  BOTTOM w0.076: v1(114.23,51.14) UC1.AR40
  BOTTOM w0.102: v1(164.93,11.15) 165.28,11.5 JDIMM2.173
DDR_B_D21: length 4
  BOTTOM w0.076: v1(114.23,51.77) UC1.AP40
  BOTTOM w0.102: JDIMM2.169 164.28,10.49 v1(164.93,9.84)
DDR_B_D22: length 3.1
  BOTTOM w0.076: v1(116.06,51.77) UC1.AP37
  BOTTOM w0.102: JDIMM2.187 168.78,11.88 168.86,11.79 168.86,11.11 v1(168.48,10.73)
DDR_B_D23: length 4.4
  BOTTOM w0.076: v1(116.06,51.14) UC1.AR37
  BOTTOM w0.102: v1(168.48,9.46) 167.78,10.17 JDIMM2.183
DDR_B_D24: length 4.3
  BOTTOM w0.076: UC1.AT33 118.07,50.64 v1(117.89,50.5)
  BOTTOM w0.102: JDIMM2.191 169.78,11.2 169.67,11.1 169.67,10.17 v1(170.26,9.59)
DDR_B_D25: length 2.9
  BOTTOM w0.076: UC1.AU33 118.07,50 v1(117.89,49.87)
  BOTTOM w0.102: JDIMM2.195 170.78,12.2 170.65,12.08 170.65,11.25 v1(170.26,10.86)
DDR_B_D26: length 2.6
  BOTTOM w0.076: v1(119.72,49.87) UC1.AU30
  BOTTOM w0.102: JDIMM2.203 172.78,11.55 v1(172.39,11.16)
DDR_B_D27: length 2.6
  BOTTOM w0.076: v1(119.72,50.5) UC1.AT30
  BOTTOM w0.102: v1(173.33,11.17) 173.78,11.61 JDIMM2.207
DDR_B_D28: length 3.9
  BOTTOM w0.076: UC1.AR33 118.07,51.28 v1(117.89,51.14)
  BOTTOM w0.102: JDIMM2.190 169.53,7.46 v1(170.01,7.94)
DDR_B_D29: length 2.6
  BOTTOM w0.076: UC1.AP33 118.07,51.92 v1(117.89,51.77)
  BOTTOM w0.102: v1(170.49,6.79) 170.53,6.75 JDIMM2.194
DDR_B_D30: length 2.6
  BOTTOM w0.076: v1(119.72,51.77) UC1.AR30
  BOTTOM w0.102: v1(174.45,6.67) 174.03,6.24 JDIMM2.208
DDR_B_D31: length 4.3
  BOTTOM w0.076: v1(119.72,52.41) UC1.AP30
  BOTTOM w0.102: JDIMM2.204 173.03,4.8 173.03,6.16 173.22,6.35 173.22,6.7 v1(174.45,7.94)
DDR_B_D32: length 12.6
  BOTTOM w0.076: UC1.AY31 120.3,48.18 120.03,47.92 120.03,47.63 119.87,47.22 119.87,46.86 120.01,46.71 v2(120.01,45.14) 120.18,44.97 120.18,40.25 v1(121.39,39.04)
  BOTTOM w0.102: JDIMM2.50 132.53,7 v1(132.34,7.18)
DDR_B_D33: length 7.7
  BOTTOM w0.076: v1(121.37,44.63) 121.49,44.74 121.49,46.41 121.19,46.7 121.19,47.23 121.2,47.26 121.24,47.34 121.24,47.46 121.17,47.68 121.17,47.82 121.23,47.98 121.23,48.16 121.21,48.21 121.21,48.78 120.95,49.04 UC1.AW31
  BOTTOM w0.102: JDIMM2.45 131.28,11.75 v1(130.51,10.99)
DDR_B_D34: length 6.6
  BOTTOM w0.076: UC1.AY29 121.42,48.28 121.42,48.03 121.35,47.81 121.35,47.68 121.41,47.45 121.41,47.31 121.36,47.19 121.36,46.77 121.65,46.48 121.65,44.91 121.75,44.81 121.75,44.41 v1(121.39,44.04)
  BOTTOM w0.102: JDIMM2.58 v1(134.53,6.67)
DDR_B_D35: length 11.2
  BOTTOM w0.076: v1(123.08,40.53) 122.3,41.31 v2(122.3,45.2) 122.15,45.36 122.15,46.7 122.06,46.79 122.06,47.74 121.83,47.96 121.83,48.51 121.52,48.82 UC1.AW29
  BOTTOM w0.102: v1(135.53,6.83) JDIMM2.62
DDR_B_D36: length 10.7
  BOTTOM w0.076: v1(121.39,40.84) 120.51,41.73 120.51,45.38 120.34,45.55 120.34,46.86 120.3,46.91 UC1.BB31
  BOTTOM w0.102: v1(130.51,9.72) 132.28,11.48 JDIMM2.49
DDR_B_D37: length 10.3
  BOTTOM w0.076: UC1.BA31 120.3,47.59 120.16,47.45 120.15,47.44 120.15,47.44 120.03,47.19 120.03,46.93 120.18,46.78 120.18,45.45 120.34,45.28 120.34,41.24 121.33,40.25 v1(121.59,40.25)
  BOTTOM w0.102: v1(131.65,6.67) 131.53,6.54 JDIMM2.46
DDR_B_D38: length 13.1
  BOTTOM w0.076: UC1.BA29 121.62,47.51 121.89,47.24 121.89,46.7 121.98,46.61 121.98,45.06 122.14,44.91 122.14,40.09 v1(123.07,39.16)
  BOTTOM w0.102: JDIMM2.63 135.78,11.26 134.32,9.81 v1(134.32,9.72)
DDR_B_D39: length 11.3
  BOTTOM w0.076: UC1.BB29 121.62,46.74 121.82,46.54 121.82,44.99 121.97,44.84 121.97,39.66 v1(123.06,38.56)
  BOTTOM w0.102: JDIMM2.59 134.78,11.44 v1(134.32,10.99)
DDR_B_D40: length 9.2
  BOTTOM w0.076: v1(123.08,42.52) 123.6,43.04 123.6,44.88 123.3,45.18 123.3,45.59 122.81,46.08 122.81,46.82 122.92,46.93 122.92,47.19 122.88,47.28 122.88,47.29 122.88,47.54 122.92,47.63 122.92,47.84 122.89,47.92 122.89,47.92 122.85,48.02 122.85,48.28 UC1.AY27
  BOTTOM w0.102: JDIMM2.66 136.52,7.35 v1(136.63,7.46)
DDR_B_D41: length 10.2
  BOTTOM w0.076: UC1.AW27 122.75,48.85 122.43,48.52 122.43,47.98 122.22,47.77 122.22,46.86 122.31,46.77 122.31,45.71 122.64,45.38 v2(122.64,42.21) 122.64,41.7 v1(123.06,41.28)
  BOTTOM w0.102: v1(137.39,6.63) 137.52,6.49 JDIMM2.70
DDR_B_D42: length 12.9
  BOTTOM w0.076: UC1.AY25 123.98,48.18 124.25,47.91 124.25,47.57 124.3,47.46 124.42,47.21 124.42,45.68 124.74,45.36 124.74,44.55 125.48,43.81 125.48,39.15 v1(125.01,38.68)
  BOTTOM w0.102: v1(136.22,10.86) 136.78,11.41 JDIMM2.67
DDR_B_D43: length 15.5
  BOTTOM w0.076: v1(125.01,39.27) 123.8,40.48 123.8,44.91 123.47,45.23 123.47,45.69 122.97,46.19 122.97,46.75 123.08,46.86 123.08,47.22 123.08,47.22 123.05,47.31 123.05,47.51 123.08,47.6 123.08,47.6 123.09,47.6 123.09,47.61 123.09,47.84 123.05,47.97 123.05,48.22 123.12,48.49 123.12,48.83 123.33,49.04 UC1.AW25
  BOTTOM w0.102: v1(136.22,9.59) 137.78,11.14 JDIMM2.71
DDR_B_D44: length 7.3
  BOTTOM w0.076: v1(123.06,43.13) 123.43,43.5 123.43,44.81 123.12,45.12 123.12,45.51 122.64,45.99 122.64,47.08 UC1.BB27
  BOTTOM w0.102: JDIMM2.79 139.78,10.6 v1(139.43,10.25)
DDR_B_D45: length 5.9
  BOTTOM w0.076: UC1.BA27 122.65,47.51 122.39,47.25 122.39,46.93 122.48,46.84 122.48,45.87 122.89,45.46 122.89,44.93 123.06,44.75 v1(123.06,44.33)
  BOTTOM w0.102: v1(140.45,11.04) 140.78,11.36 JDIMM2.83
DDR_B_D46: length 8.8
  BOTTOM w0.076: v1(124.93,43.06) 124.58,43.42 124.58,45.29 124.26,45.61 124.26,47.17 124.13,47.44 123.98,47.59 UC1.BA25
  BOTTOM w0.102: v1(141.43,7.94) 140.16,6.67 140.16,6.41 140.03,6.27 JDIMM2.80
DDR_B_D47: length 7.1
  BOTTOM w0.076: v1(124.95,42.46) 124.8,42.46 124.41,42.85 124.41,45.22 124.09,45.54 124.09,46.75 123.98,46.86 UC1.BB25
  BOTTOM w0.102: v1(141.43,6.67) 141.03,6.26 JDIMM2.84
DDR_B_D48: length 3.9
  BOTTOM w0.076: v1(121.55,49.85) UC1.AU27
  BOTTOM w0.102: JDIMM2.216 176.03,4.8 176.03,7.51 v1(175.59,7.94)
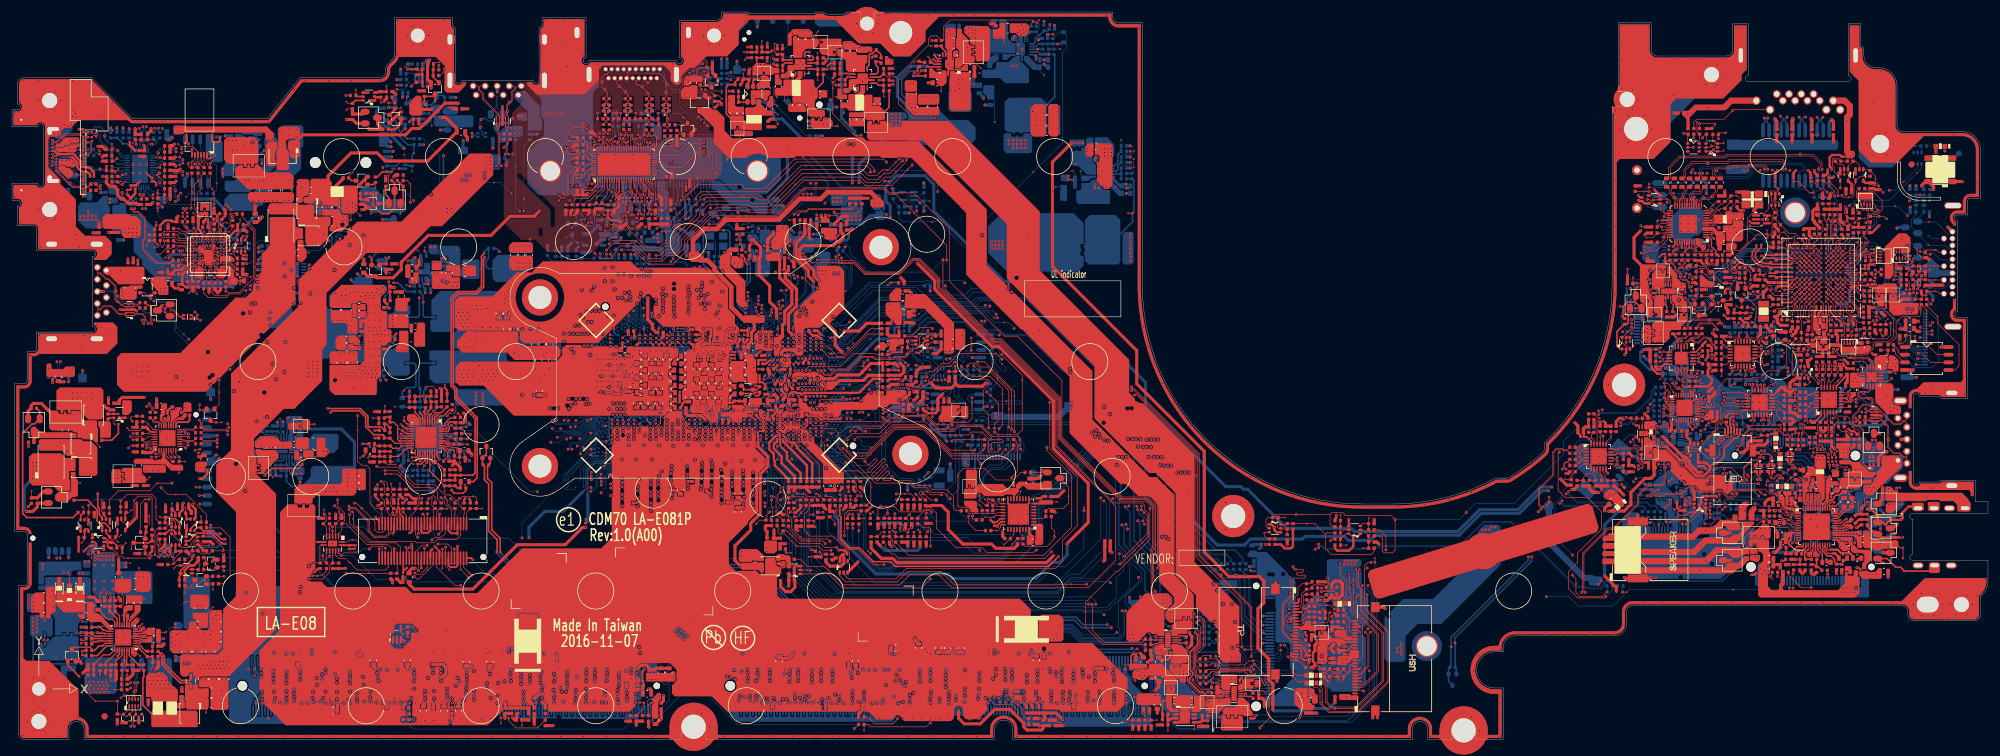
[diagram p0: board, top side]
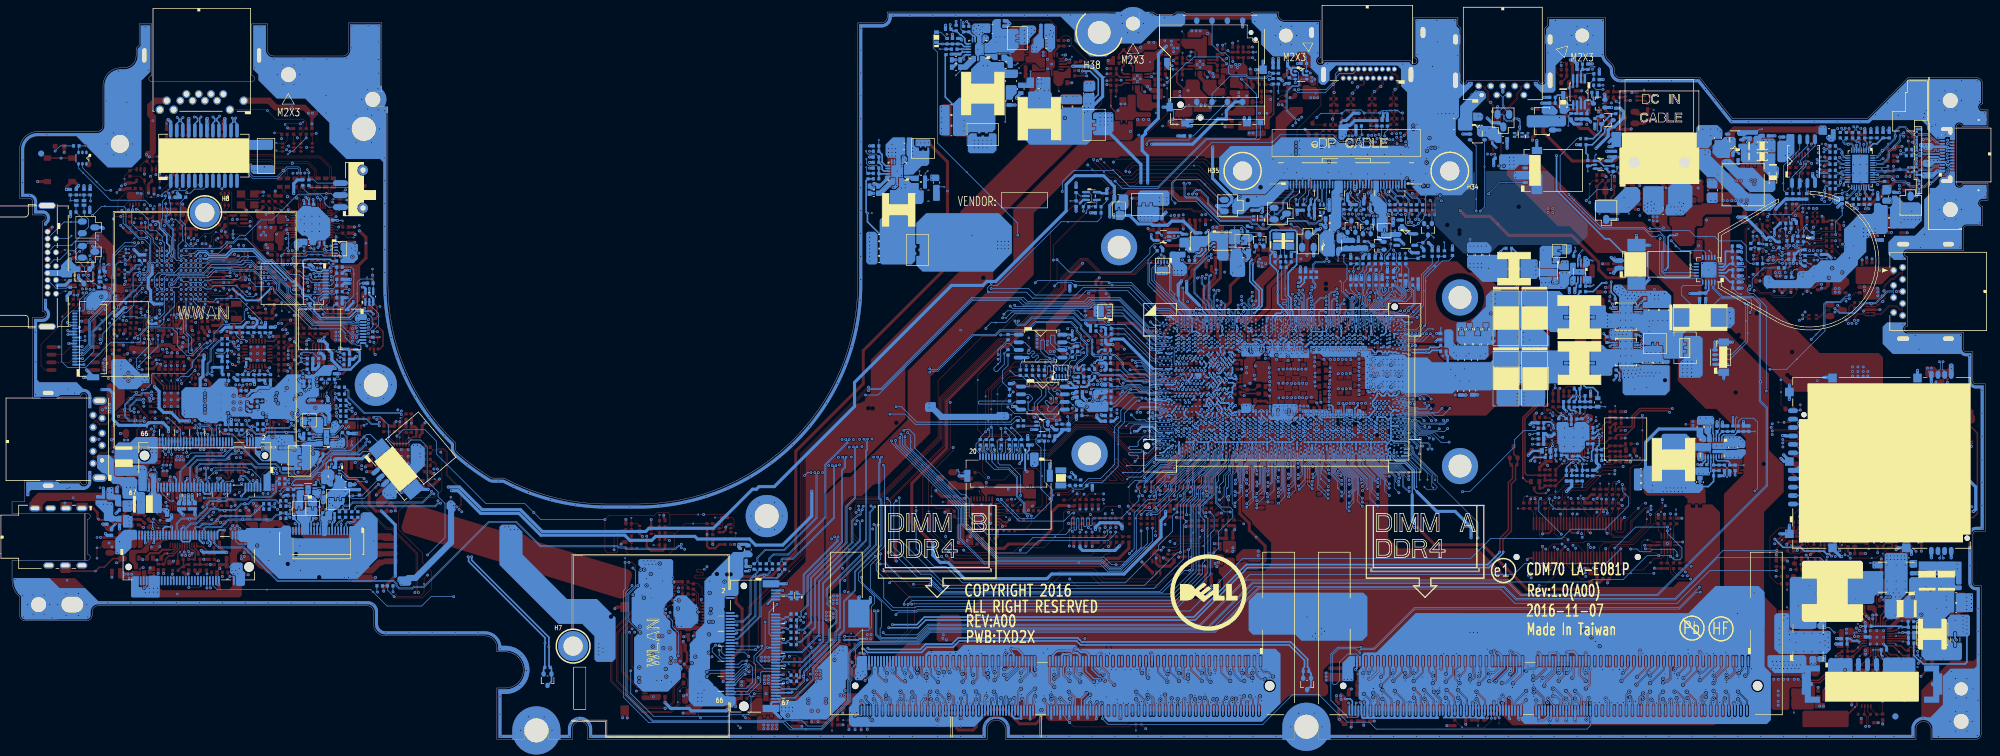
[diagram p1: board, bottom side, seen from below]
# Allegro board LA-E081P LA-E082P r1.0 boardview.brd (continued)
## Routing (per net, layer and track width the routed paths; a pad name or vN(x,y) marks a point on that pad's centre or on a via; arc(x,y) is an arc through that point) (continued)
DDR_B_D49: length 4.6
  BOTTOM w0.076: v1(121.55,50.5) UC1.AT27
  BOTTOM w0.102: v1(174.33,9.54) 175.52,10.74 175.52,11.75 175.78,12 JDIMM2.215
DDR_B_D50: length 3.9
  BOTTOM w0.076: v1(122.46,50.5) UC1.AT25
  BOTTOM w0.102: v1(178.6,7.84) 178.03,7.26 178.03,4.8 JDIMM2.224
DDR_B_D51: length 2.9
  BOTTOM w0.076: v1(122.46,49.87) UC1.AU25
  BOTTOM w0.102: v1(178.61,6.99) 179.03,6.57 JDIMM2.228
DDR_B_D52: length 2.8
  BOTTOM w0.076: v1(121.55,51.77) UC1.AP27
  BOTTOM w0.102: v1(174.22,11.04) 174.25,11.04 174.78,11.57 JDIMM2.211
DDR_B_D53: length 2.7
  BOTTOM w0.076: v1(121.55,52.41) UC1.AN27
  BOTTOM w0.102: JDIMM2.212 175.03,6.2 v1(175.49,6.67)
DDR_B_D54: length 3.4
  BOTTOM w0.076: v1(122.46,52.41) UC1.AN25
  BOTTOM w0.102: v1(178.76,10.42) 178.76,10.92 179.28,11.43 JDIMM2.229
DDR_B_D55: length 2.8
  BOTTOM w0.076: v1(122.46,51.77) UC1.AP25
  BOTTOM w0.102: JDIMM2.225 178.28,11.51 v1(177.75,10.99)
DDR_B_D56: length 2.9
  BOTTOM w0.076: v1(124.29,50.44) 124.29,50.44 124.3,50.51 UC1.AT22
  BOTTOM w0.102: JDIMM2.233 180.28,11.48 v1(179.75,10.96)
DDR_B_D57: length 4.8
  BOTTOM w0.076: v1(124.29,49.85) UC1.AU22
  BOTTOM w0.102: JDIMM2.237 181.28,10.67 180.27,9.67 v1(179.78,9.67)
DDR_B_D58: length 2.8
  BOTTOM w0.076: v1(125.2,49.91) 125.49,50.2 UC1.AU21
  BOTTOM w0.102: JDIMM2.245 183.28,11.5 v1(182.78,11.01)
DDR_B_D59: length 4.6
  BOTTOM w0.076: v1(125.2,50.5) UC1.AT21
  BOTTOM w0.102: v1(182.94,9.77) 183.01,9.7 183.23,9.7 184.28,10.74 JDIMM2.249
DDR_B_D60: length 2.8
  BOTTOM w0.076: UC1.AN22 v1(124.29,52.41)
  BOTTOM w0.102: JDIMM2.236 181.03,4.8 181.03,6.3 180.65,6.68 v1(180.54,6.68)
DDR_B_D61: length 4
  BOTTOM w0.076: v1(124.29,51.77) UC1.AP22
  BOTTOM w0.102: JDIMM2.232 180.03,4.8 180.03,6.39 179.94,6.47 179.94,7.33 v1(180.55,7.94)
DDR_B_D62: length 4.4
  BOTTOM w0.076: v1(126.12,51.77) 125.74,52.15 UC1.AP21
  BOTTOM w0.102: JDIMM2.246 183.53,6.18 183.69,6.34 183.69,6.76 184.86,7.94 v1(184.99,7.94)
DDR_B_D63: length 2.7
  BOTTOM w0.102: v1(125.2,52.41) 125.2,52.42 125.24,52.42 125.62,52.8 UC1.AN21 ; JDIMM2.250 184.53,6.2 v1(184.99,6.67)
DDR_B_DQS0: length 9.4
  BOTTOM w0.076: UC1.AY38 115.63,48.08 115.58,47.96 115.58,47.63 115.53,47.52 115.53,47.3 115.58,47.19 115.58,46.78 115.49,46.68 115.49,46.17 115.59,46.07 115.59,43.71 115.74,43.55 115.97,43.55 v1(116.15,43.38)
  BOTTOM w0.099: v1(122.12,10.2) 122.33,10.41 122.85,10.41 123.19,10.76 123.19,12 123.28,12.08 JDIMM2.13
DDR_B_DQS1: length 8.8
  BOTTOM w0.076: UC1.BA34 118.33,47.95 118.57,47.72 118.57,47.6 118.62,47.47 118.62,47.34 118.57,47.23 118.57,46.14 118.79,45.92 118.79,42.69 119.45,42.03 v1(119.54,42.03)
  BOTTOM w0.099: v1(128.6,6.67) 128.21,6.28 128.21,5.87 128.53,5.56 JDIMM2.34
DDR_B_DQS2: length 3.8
  BOTTOM w0.099: v1(115.17,51.19) 115.33,51.19 115.6,51.47 UC1.AR38 ; JDIMM2.179 166.78,10.78 166.56,10.56 166.28,10.56 v1(166.02,10.3)
DDR_B_DQS3: length 3.6
  BOTTOM w0.076: v1(118.8,51.14) 118.9,51.14 UC1.AR32
  BOTTOM w0.099: JDIMM2.200 172.03,5.82 171.87,5.98 171.87,6.94 171.97,7.04 172.3,7.04 v1(172.55,6.8)
DDR_B_DQS4: length 10.9
  BOTTOM w0.076: v1(121.39,42.12) 121.19,42.31 120.97,42.31 120.77,42.51 120.77,45.51 120.53,45.75 120.53,46.55 120.56,46.58 120.56,47.19 120.51,47.3 120.51,47.52 120.56,47.63 120.56,48.18 UC1.AY30
  BOTTOM w0.099: v1(132.79,10.1) 133.44,10.1 133.72,10.38 133.72,12.06 133.78,12.12 JDIMM2.55
DDR_B_DQS5: length 11.7
  BOTTOM w0.076: UC1.BA26 123.47,48.06 123.55,47.98 123.55,47.59 123.6,47.48 123.6,47.34 123.55,47.23 123.55,46.83 123.75,46.62 123.75,45.29 124.01,45.03 v4(124.01,41.99) 124.01,41.2 124.37,40.85 124.77,40.85 124.99,40.62 v1(124.99,40.52)
  BOTTOM w0.099: JDIMM2.76 139.03,5.56 138.71,5.88 138.71,6.79 138.99,7.07 139.25,7.07 v1(139.53,6.8)
DDR_B_DQS6: length 4
  BOTTOM w0.076: v1(121.55,51.14) UC1.AR27
  BOTTOM w0.099: JDIMM2.221 177.28,12.01 177.17,11.9 177.17,10.83 176.74,10.4 176.4,10.4 v1(176.23,10.22)
DDR_B_DQS7: length 3.2
  BOTTOM w0.076: v1(125.2,51.77) 125.47,51.5 UC1.AR21
  BOTTOM w0.099: JDIMM2.242 182.53,5.82 182.37,5.98 182.37,6.67 182.53,6.83 182.8,6.83 v1(182.96,6.67)
DDR_B_DQS#0: length 8.9
  BOTTOM w0.076: UC1.BA38 115.82,48.06 115.78,48.02 115.75,47.93 115.75,47.6 115.69,47.47 115.69,47.36 115.75,47.22 115.75,46.71 115.65,46.61 115.65,46.24 115.75,46.14 115.75,43.78 115.81,43.72 115.96,43.72 116.17,43.93 116.17,44.06 v1(116.15,44.08)
  BOTTOM w0.099: JDIMM2.11 122.78,12.17 122.87,12.08 122.94,12.08 123.01,12 123.01,10.84 122.77,10.6 122.23,10.6 122.13,10.71 v1(122.13,11.05)
DDR_B_DQS#1: length 8.8
  BOTTOM w0.076: UC1.AY34 118.43,48.57 118.73,48.27 118.73,47.63 118.78,47.52 118.78,47.3 118.73,47.19 118.73,46.21 118.95,45.99 118.95,42.76 119.2,42.51 119.37,42.51 v1(119.54,42.68)
  BOTTOM w0.099: JDIMM2.32 128.03,6.66 v1(128.01,6.68)
DDR_B_DQS#2: length 4.1
  BOTTOM w0.076: UC1.AT38 115.68,50.77 115.68,50.57 115.61,50.49 115.48,50.49 115.35,50.37 115.23,50.37 v1(115.12,50.48)
  BOTTOM w0.099: JDIMM2.177 166.28,12.19 166.59,11.88 166.59,10.85 166.48,10.74 166.13,10.74 166.02,10.86 v1(166.02,11.02)
DDR_B_DQS#3: length 3.9
  BOTTOM w0.076: UC1.AT32 119.55,51.14 v1(119.72,51.14)
  BOTTOM w0.099: JDIMM2.198 171.53,5.82 171.68,5.98 171.68,7.02 171.89,7.23 172.34,7.23 v1(172.55,7.43)
DDR_B_DQS#4: length 10.4
  BOTTOM w0.076: UC1.BA30 120.92,48.1 120.81,48.1 120.73,48.02 120.73,47.59 120.68,47.48 120.68,47.34 120.73,47.23 120.73,46.51 120.7,46.48 120.7,45.81 120.93,45.58 120.93,42.58 121.03,42.48 121.31,42.48 121.39,42.55 v1(121.39,42.77)
  BOTTOM w0.099: v1(132.79,10.73) 132.79,10.56 132.85,10.5 132.97,10.5 133.18,10.29 133.36,10.29 133.53,10.46 133.53,12.04 133.46,12.11 133.34,12.11 133.28,12.18 JDIMM2.53
DDR_B_DQS#5: length 12
  BOTTOM w0.076: v1(124.99,41.17) 124.83,41.02 124.44,41.02 124.18,41.27 124.18,41.65 124.22,41.7 124.22,42.29 124.18,42.33 124.18,45.09 123.92,45.35 123.92,46.69 123.71,46.9 123.71,47.19 123.77,47.3 123.77,47.52 123.71,47.63 123.71,48.11 UC1.AY26
  BOTTOM w0.099: v1(139.53,7.38) 139.4,7.25 138.91,7.25 138.52,6.87 JDIMM2.74
DDR_B_DQS#6: length 4.2
  BOTTOM w0.076: v1(122.46,51.14) 122.46,51.09 122.54,51.01 122.65,51.01 122.67,51.02 122.97,51.32 122.97,51.45 UC1.AR25
  BOTTOM w0.099: JDIMM2.219 176.78,12.09 176.98,11.89 176.98,10.91 176.66,10.59 176.41,10.59 176.23,10.77 v1(176.23,10.86)
DDR_B_DQS#7: length 3.7
  BOTTOM w0.076: v1(125.2,51.14) 124.84,51.5 UC1.AR22
  BOTTOM w0.099: v1(182.96,7.3) 182.96,7.23 182.75,7.02 182.45,7.02 182.18,6.75 182.18,5.98 182.03,5.82 JDIMM2.240
DDR_B_MA0: length 6.8
  BOTTOM w0.076: UC1.BA46 111.69,47.56 111.95,47.29 111.95,46.08 111.46,45.58 111.46,44.05 v1(112.05,43.46)
  BOTTOM w0.168: v1(156.67,6.54) 156.67,6.29 156.03,5.64 JDIMM2.144
DDR_B_MA1: length 12.5
  BOTTOM w0.076: UC1.AY46 111.59,48.13 111.49,48.03 111.41,47.81 111.41,47.68 111.48,47.45 111.48,47.31 111.42,47.19 111.42,46.93 111.62,46.73 111.62,46.24 111.08,45.7 111.08,42.25 v1(109.55,40.72)
  BOTTOM w0.168: JDIMM2.133 153.28,12.23 153.47,12.03 153.47,10.71 v1(152.48,9.72)
DDR_B_MA2: length 10.2
  BOTTOM w0.076: UC1.AY47 111.29,48.41 111.29,47.98 111.24,47.82 111.24,47.68 111.3,47.46 111.3,47.34 111.27,47.26 111.26,47.23 111.26,46.86 111.46,46.66 111.46,46.32 110.88,45.73 110.88,43.38 v2(110.72,43.22) v1(109.5,42)
  BOTTOM w0.168: JDIMM2.132 153.03,5.94 153.88,6.8 v1(154,6.8)
DDR_B_MA3: length 10.6
  BOTTOM w0.076: v1(109.55,40.04) 111.26,41.74 111.26,45.63 111.79,46.16 111.79,46.98 UC1.BB46
  BOTTOM w0.168: JDIMM2.131 152.78,12.12 153.04,11.85 153.04,11.15 152.87,10.99 v1(152.48,10.99)
DDR_B_MA4: length 7.9
  BOTTOM w0.076: v1(109.4,42.97) 110.67,44.24 110.67,46.7 110.79,46.82 110.79,47.22 110.79,47.22 110.76,47.31 110.76,47.51 110.79,47.6 110.79,47.6 110.8,47.6 110.8,47.61 110.8,47.84 UC1.BA47
  BOTTOM w0.168: JDIMM2.128 152.03,6.39 v1(152.38,6.75)
DDR_B_MA5: length 8.7
  BOTTOM w0.076: UC1.AY48 110.56,48.19 110.56,48.02 110.6,47.92 110.6,47.92 110.63,47.84 110.63,47.63 110.59,47.54 110.59,47.28 110.63,47.19 110.63,46.93 110.51,46.81 110.51,44.91 v2(110.11,44.52) 109.77,44.17 v1(109.36,44.17)
  BOTTOM w0.168: JDIMM2.126 151.52,6.86 v1(152.61,7.94)
DDR_B_MA6: length 6.6
  BOTTOM w0.076: UC1.BA48 110.36,47.51 110.09,47.24 110.09,46.92 110.18,46.84 110.18,46.29 109.5,45.62 v1(109.5,45.41)
  BOTTOM w0.168: v1(150.7,9.59) 151.78,10.66 JDIMM2.127
DDR_B_MA7: length 3.9
  BOTTOM w0.076: v1(109.66,51.77) UC1.AP48
  BOTTOM w0.168: v1(149.65,7.71) 149.65,7.6 150.52,6.72 JDIMM2.122
DDR_B_MA8: length 5.2
  BOTTOM w0.076: v1(109.5,44.77) 110.34,45.61 110.34,46.88 110.36,46.9 UC1.BB48
  BOTTOM w0.168: JDIMM2.125 151.28,11.18 150.89,10.8 v1(150.7,10.8)
DDR_B_MA9: length 4.9
  BOTTOM w0.076: v1(108.74,51.77) UC1.AP50
  BOTTOM w0.168: v1(148.42,9.57) 148.65,9.57 150.28,11.2 JDIMM2.121
DDR_B_MA10: length 8.1
  BOTTOM w0.076: v1(112.1,44.05) 111.66,44.49 111.66,45.55 112.12,46 112.12,47.73 111.88,47.96 111.88,48.46 111.78,48.66 111.59,48.85 UC1.AW46
  BOTTOM w0.168: v1(158.19,7.18) 158.53,6.85 JDIMM2.146
DDR_B_MA11: length 3.6
  BOTTOM w0.076: v1(109.66,52.41) UC1.AN48
  BOTTOM w0.168: JDIMM2.120 150.03,6.46 v1(149.05,7.43)
DDR_B_MA12: length 5.1
  BOTTOM w0.076: UC1.AN50 109,52.8 v1(108.74,53.06)
  BOTTOM w0.168: JDIMM2.119 149.78,11.39 148.49,10.1 147.61,10.1 v1(147.45,9.94)
DDR_B_MA13: length 7.4
  BOTTOM w0.076: UC1.BA43 113.61,47.83 113.61,47.59 113.62,47.56 113.66,47.47 113.66,47.36 113.61,47.22 113.61,46.97 113.61,46.96 113.61,46.84 113.75,46.7 113.75,44.06 v2(114.15,43.66) 114.48,43.33 v1(114.53,43.33)
  BOTTOM w0.168: v1(161.65,6.89) 161.53,6.76 JDIMM2.158
DDR_B_MA14: length 9.9
  BOTTOM w0.076: v1(114.35,41.52) 113.27,42.59 113.27,45.52 112.78,46.01 112.78,46.72 112.98,46.92 112.98,47.19 112.93,47.31 112.93,47.45 112.99,47.68 112.99,47.81 112.92,48.03 112.92,48.04 112.81,48.14 UC1.AY44
  BOTTOM w0.168: JDIMM2.151 159.78,11.9 v1(160.58,11.09)
DDR_B_MA15: length 11.3
  BOTTOM w0.076: v1(114.48,42.1) 113.45,43.13 113.45,45.7 112.96,46.19 112.96,46.67 113.15,46.85 113.15,47.23 113.1,47.34 113.1,47.46 113.16,47.68 113.16,47.82 113.11,47.98 113.11,48.16 113.19,48.32 113.19,48.42 UC1.AY43
  BOTTOM w0.168: JDIMM2.156 161.03,7.94 v1(160.55,8.41)
DDR_B_MA16: length 6.1
  BOTTOM w0.076: v1(112.1,45.32) 112.28,45.5 112.28,47.73 112.52,47.96 112.52,48.43 112.54,48.5 112.65,48.71 112.81,48.88 UC1.AW44
  BOTTOM w0.168: v1(160.34,6.75) 160.03,6.43 JDIMM2.152
DDR_B_ODT0: length 8.1
  BOTTOM w0.076: v1(114.53,43.96) 113.91,44.58 113.91,46.77 113.78,46.9 113.78,46.98 113.77,46.99 113.77,47.19 113.83,47.32 113.83,47.52 UC1.BA42
  BOTTOM w0.168: JDIMM2.155 160.78,11.97 162.67,10.08 v1(162.9,10.08)
DDR_B_ODT1: length 3.2
  BOTTOM w0.076: v1(113.37,49.86) 113.45,49.86 114.04,49.27 UC1.AW42
  BOTTOM w0.127: v1(163.33,11.66) 162.88,11.66 162.28,12.27 JDIMM2.161
DDR_B_PARITY: length 5.2
  BOTTOM w0.076: UC1.AP43 112.79,52.15 v1(112.43,51.79)
  BOTTOM w0.168: JDIMM2.143 155.78,9.46 v1(155.02,8.7)
DDR_DRAMRST#: length 2.4
  TOP w0.102: v1(66.66,3.3) RD12.2 RD11.2
  BOTTOM w0.102: UC1.AT13 130.07,50.85 v1(129.71,50.49)
DDR_DRAMRST#_R: length 99.5
  TOP w0.102: CD61.1 142.07,3.76 v2(142.42,3.41) 143.13,2.7 146.35,2.7 147.03,3.37 v1(147.03,3.48) ; v1(66.03,6.06) 65.88,5.92 CD29.1 65.92,5.23 RD12.1
  BOTTOM w0.102: v1(66.03,6.06) JDIMM1.108 66.03,2.26 66.57,1.72 101.56,1.72 102.71,2.87 106.32,2.87 107.5,4.05 107.68,4.05 111.08,7.45 115.44,7.45 120.39,2.51 146.1,2.51 147.03,3.43 v1(147.03,3.48) JDIMM2.108
DDR_VTT_CTRL: length 24.9
  TOP w0.102: v1(64.47,15.49) 63.89,16.07 UD1.2
  BOTTOM w0.076: v1(84.66,33.46) 84.66,36.01 91.45,42.79 91.45,43.75 95.2,47.5 95.2,47.8 95.34,47.94 95.34,48.51 95.73,48.9 96.45,48.9 96.75,49.2 98.02,49.2 98.08,49.13 98.72,49.13 98.82,49.03 UC1.AW67
DDR_XDP_WAN_SMBCLK: length 128.4
  TOP w0.102: v1(55.95,38.74) 56.13,38.57 56.99,38.57 59.33,36.23 59.33,34.65 60.21,33.77 62.04,33.77 62.55,34.28 62.55,34.63 62.45,34.73 JXDP1.53 ; v1(260.58,24.4) 260.74,24.55 260.74,30.94 264.92,35.12 265.82,35.12 269.85,39.16 269.85,40.58 271.66,42.39 273.88,42.39 274.28,42.78 274.28,45.62 274.17,45.72 v1(273.33,45.72) ; v1(152.65,66.69) RC319.1 152.61,65.99 152.22,65.6 QC2.1
  BOTTOM w0.102: v1(273.33,45.72) 273.72,45.33 LGA1.1 ; v1(186.44,9.79) 186.39,9.79 185.28,10.91 JDIMM2.253 ; JDIMM1.253 104.28,13.67 104.8,14.19 106.28,14.19 107.63,12.84 107.63,9.77 108.26,9.13 108.65,9.13 108.81,9.29 108.81,14.04 107.8,15.05 104.98,15.05 v1(104.28,14.34) 104.28,14.83 104.17,14.93 101.87,14.93 95.16,21.65 51.25,21.65 48.44,24.45 v1(47.75,24.45)
DDR_XDP_WAN_SMBDAT: length 131.8
  TOP w0.102: v1(152.79,68.22) 152.59,68.42 150.78,68.42 149.53,67.17 148.33,67.17 RC318.1 148.28,66.9 QC2.4 ; v1(261.17,24.4) 260.96,24.61 260.96,30.84 265.01,34.89 265.91,34.89 270.08,39.06 270.08,40.49 271.75,42.16 273.98,42.16 274.5,42.68 274.5,45.49 274.76,45.75 v1(274.99,45.75) ; JXDP1.51 62.95,34.74 62.78,34.57 62.78,34.18 62.14,33.54 60.12,33.54 59.1,34.55 59.1,36.13 56.9,38.34 56.13,38.34 v1(55.95,38.16)
  BOTTOM w0.102: JDIMM1.254 104.53,3.79 104.63,3.69 106.28,3.69 109.09,6.5 109.09,14.17 107.94,15.32 v1(104.09,15.32) 103.94,15.16 101.97,15.16 95.26,21.88 51.34,21.88 v1(47.92,25.3) ; LGA1.4 275.22,45.52 v1(274.99,45.75) ; v1(186.31,7.06) 186.31,6.62 185.53,5.83 JDIMM2.254
DEBUG_TX: length 16.2
  BOTTOM w0.102: JDEG1.9 276.55,73.9 277.17,73.27 277.17,72.68 276.29,71.8 274.69,71.8 RE74.2 273.54,71.74 272.94,71.74 272.63,72.04 272.63,72.39 271.31,73.71 v2(271.31,77.26) 271.31,78 271.75,78.44 RE30.2
DEW1: length 5.6
  TOP w0.102: RN16.2 280.41,61.22 279.4,61.22 279,60.82 v1(278.76,60.82) 278.76,61.52 279.11,61.86 UN7.16
  BOTTOM w0.102: v2(279.99,61.22) 279.72,61.49 RN17.2 278.76,61.2 v1(278.76,60.82)
DEW2: length 3.9
  TOP w0.102: UN7.6 v1(273.61,64.32) 273.14,64.79 RN14.2
  BOTTOM w0.102: RN15.2 273.32,64.03 v1(273.61,64.32) 274.05,64.32 v2(274.21,64.48)
DIMM1_SA0: length 4.9
  TOP w0.102: RD5.1 RD4.2 v2(104.58,4.91) 104.9,5.23 v1(104.9,6.06)
  BOTTOM w0.102: JDIMM1.256 105.03,5.93 v1(104.9,6.06)
DIMM1_SA1: length 4.7
  TOP w0.102: v1(106.15,6.06) 106.03,6.06 v2(105.66,5.69) 105.66,3.98 RD7.1 RD6.2
  BOTTOM w0.102: JDIMM1.260 106.03,5.94 v1(106.15,6.06)
DIMM1_SA2: length 9.9
  TOP w0.102: v1(82.45,3.54) 82.45,3.14 83.66,1.92 87.24,1.92 v2(87.33,2.01) RD8.2 RD9.1
  BOTTOM w0.102: v1(82.45,3.54) 82.45,4.72 JDIMM1.166
DIMM2_SA0: length 4.2
  TOP w0.102: RD21.1 RD20.2 185.35,3.2 v1(185.31,3.24) 185.31,3.24 v2(184.94,2.87)
  BOTTOM w0.102: JDIMM2.256 186.03,3.96 v1(185.31,3.24)
DIMM2_SA1: length 4.5
  TOP w0.102: v1(188.09,3.92) 188.09,3.92 RD23.1 RD22.2 v2(190.05,3.2)
  BOTTOM w0.102: JDIMM2.260 187.03,4.07 187.18,3.92 v1(188.09,3.92)
DIMM2_SA2: length 12.2
  TOP w0.102: v1(163.85,6.87) 164.41,7.43 164.41,7.98 164.78,8.35 165.26,8.35 165.46,8.15 165.46,7.37 166.47,6.36 166.47,6.21 166.85,5.83 166.96,5.83 v2(167.07,5.72) 167.72,5.07 167.72,4.14 168.35,3.5 RD24.2 RD25.1
  BOTTOM w0.102: v1(163.85,6.87) 163.53,6.55 JDIMM2.166
DISP_ON: length 8.4
  BOTTOM w0.102: JEDP1.22 105.8,90.34 104.85,89.39 104.66,89.39 104.39,89.12 104.39,88.42 RV2.1 104.94,87.87 v2(104.94,86.97) 103.84,85.87 DV2.1
DMIC0: length 39.9
  TOP w0.102: v1(114.89,89.72) 115.15,89.97 123.64,89.97 124.03,89.58 125.28,89.58 131,95.3 v2(131.79,95.3) 141.91,95.3 142.52,94.69 v1(142.52,94.23) ; UA1.2 296.09,37.12 295.61,37.61 294.98,37.61 294.85,37.74 v1(294.58,37.74) 293.82,38.5 293.65,38.5 RA52.2
  BOTTOM w0.102: JEDP1.7 113.3,90.79 114.42,89.67 114.42,89.07 CA6.1 114.76,88.8 114.89,88.94 v1(114.89,89.72)
DMIC_CLK0: length 39.7
  TOP w0.102: v1(113.55,89.73) 113.55,90.12 114.38,90.95 125.34,90.95 v2(128.99,94.6) 130.29,95.9 142,95.9 143.13,94.77 v1(143.13,94.35) ; RA14.1 CA54.1 291.7,38.04 291.7,38.68 v1(291.67,38.7)
  BOTTOM w0.102: v1(113.55,89.73) 113.67,89.61 CA5.1 113.08,89.39 113.08,90.11 112.78,90.41 112.78,91.06 112.3,91.55 JEDP1.9
DMIC_CLK_CODEC: length 3.7
  TOP w0.102: RA14.2 293.63,37.99 294.39,37.23 v2(294.85,37.23) 295,37.38 295.51,37.38 296.17,36.72 UA1.3
EC_FPM_EN: length 22.1
  TOP w0.102: JUSH1.5 224.42,9.15 226.6,11.33 226.6,17.47 222.71,21.35 v1(222.71,25.57) v3(222.71,26.69)
  TOP w0.107: UE1.D6 297.55,75.51 v1(297.55,75.52)
EDP_AUXN: length 1.8
  BOTTOM w0.094: UC1.E45 111.88,66.99 111.71,67.05 v1(111.45,67.32) ; CV1.1 98.18,87.9 98.04,87.75 98.04,87.36 98.25,87.15 v1(98.32,87.15)
EDP_AUXN_C: length 4.8
  BOTTOM w0.094: JEDP1.33 100.3,91.5 100.17,91.37 100.17,90.71 99.75,90.3 99.39,90.3 98.69,89.6 98.33,89.6 98.05,89.33 98.05,89.18 CV1.2
EDP_AUXP: length 1.9
  BOTTOM w0.094: UC1.F45 111.68,66.6 111.53,66.6 v1(111.47,66.54) ; CV2.1 97.86,87.57 97.86,87.3 97.71,87.15 v1(97.38,87.15)
EDP_AUXP_C: length 4.8
  BOTTOM w0.094: CV2.2 97.87,89.14 97.87,89.4 98.25,89.79 98.61,89.79 99.31,90.48 99.68,90.48 99.98,90.79 99.98,91.36 99.8,91.54 JEDP1.34
EDP_BIA_PWM: length 1.5
  BOTTOM w0.076: UC1.R11 131.48,61.58 v1(131.18,61.28)
  BOTTOM w0.102: v1(105.16,85.11) 105.02,84.97 DV1.3
EDP_COMP: length 2.2
  TOP w0.102: v2(107.38,66.31) v1(107.87,66.65)
  TOP w0.508: v1(107.87,66.65) 108.09,66.88 RC2.1
  BOTTOM w0.254: v1(107.87,66.65) 108.21,66.99 UC1.E52
EDP_HPD: length 6.9
  TOP w0.102: v2(132.45,63.82) v1(132.45,63.28) 132.29,63.12 RC1.1
  BOTTOM w0.076: v1(132.45,63.28) UC1.L10
  BOTTOM w0.102: JEDP1.26 103.8,91.38 v1(104.72,90.46) 104.72,90 104.19,89.47 104.19,88.58 RV7.1
EDP_TXN0: length 6.2
  BOTTOM w0.076: UC1.C47 110.79,68.91 110.79,69.42 110.94,69.56 110.94,70.95 110.76,71.13 110.12,71.13 v1(109.93,70.94)
  BOTTOM w0.094: CV4.1 96.09,87.56 96.09,86.63 95.82,86.36 95.82,86.01 v1(95.66,85.85)
EDP_TXN0_C: length 5.5
  BOTTOM w0.094: JEDP1.36 98.8,91.59 98.96,91.43 98.96,91.22 98.11,90.37 96.79,90.37 96.1,89.68 96.1,89.14 CV4.2
EDP_TXN1: length 9.6
  BOTTOM w0.076: v1(109.88,73.55) 110.02,73.41 110.85,73.41 111.92,72.34 111.92,70.17 112.07,70.02 112.07,69.58 112.04,69.48 112.04,69.29 112.07,69.2 112.07,68.96 111.93,68.47 111.93,68.34 111.9,68.26 111.79,68.16 111.6,68.09 UC1.D46
  BOTTOM w0.094: v1(94.46,86.29) 94.62,86.45 94.62,86.91 94.28,87.25 94.28,87.47 CV6.1
EDP_TXN1_C: length 6.3
  BOTTOM w0.094: JEDP1.38 97.8,91.51 97.96,91.35 97.96,91.25 97.85,91.14 96.6,91.14 95.55,90.09 94.8,90.09 94.29,89.58 94.29,89.23 CV6.2
EDP_TXP0: length 6.3
  BOTTOM w0.076: v1(109.93,71.59) 109.93,71.56 110.19,71.3 110.83,71.3 111.1,71.02 111.1,69.49 110.96,69.35 110.96,68.81 111.03,68.74 UC1.C46
  BOTTOM w0.094: CV3.1 96.27,87.51 96.27,86.55 96,86.28 96,86.09 v1(96.24,85.85)
EDP_TXP0_C: length 5.5
  BOTTOM w0.094: JEDP1.35 99.3,91.57 99.14,91.42 99.14,91.15 98.18,90.19 96.87,90.19 96.28,89.6 96.28,89.17 CV3.2
EDP_TXP1: length 9.5
  BOTTOM w0.076: v1(109.88,72.8) 109.82,72.86 109.82,73.08 109.9,73.15 110.05,73.15 110.14,73.24 110.78,73.24 111.75,72.27 111.75,70.11 111.91,69.95 111.91,69.61 111.87,69.51 111.87,69.26 111.91,69.17 111.91,68.98 111.85,68.8 111.76,68.73 111.5,68.73 111.25,68.48 111.25,68.37 111.34,68.28 111.5,68.28 UC1.C45
  BOTTOM w0.094: v1(95.06,86.34) 94.81,86.59 94.81,86.98 94.46,87.33 94.46,87.48 CV5.1
EDP_TXP1_C: length 6.3
  BOTTOM w0.094: CV5.2 94.47,89.2 94.47,89.5 94.88,89.9 95.63,89.9 96.68,90.95 97.92,90.95 98.14,91.17 98.14,91.37 98.3,91.53 JEDP1.37
EDRAM_OPIO_RCOMP: length 2.3
  BOTTOM w0.127: RC90.1 v2(90.86,68.38)
  BOTTOM w0.254: UC1.H66 99.49,65.1 v1(99.29,65.29)
  BOTTOM w0.381: v1(91.56,67.42) RC90.1
EMMC_RCOMP: length 6.6
  BOTTOM w0.203: 138.38,51.63 137.7,50.96 UC1.AT1
  BOTTOM w0.381: 138.38,51.63 138.69,51.94 140.49,51.94 v2(140.79,51.63) 141.22,51.2 v1(141.74,51.2) ; RC4.1 145.17,52.85 v1(144.53,53.49)
EN_0.6V: length 6
  BOTTOM w0.102: v2(41.72,53.49) 41.9,53.31 41.9,51.43 42.18,51.15 PR210.1
  BOTTOM w0.203: PR212.1 44.66,50.57 PU200.2
  BOTTOM w0.254: PR210.1 42.35,51.15 PC222.1 43.22,51.14 PR212.1
EN_1.0V_PRIM_COREP: length 5.1
  TOP w0.102: PR407.1 126.6,114.21 v2(126.6,115.55)
  TOP w0.254: PR407.1 127.06,113.77 PC411.1 127.96,113.73 PR406.2 127.98,112.84 PU402.13
EN_1.2V: length 6.4
  BOTTOM w0.102: v2(38.68,51.16) PR209.1
  BOTTOM w0.203: PU200.1 44.21,50.25 43.89,50.57 42.05,50.57 PR208.1
  BOTTOM w0.254: PR209.1 39.71,51.15 PC221.1 PR208.1
EN_1.8VALW: length 3.3
  TOP w0.203: PU501.1 122.05,105.84 PC505.1 PR505.1 PR504.2
EN_1VS_VCCIO: length 4.1
  TOP w0.254: PU401.13 139.25,110.48 139.13,110.6 v2(138.5,110.6) 137.56,110.6 PR402.2 137.46,110.53 PC402.1 137.46,112.3 PR403.1
EN_2.5V: length 4.4
  TOP w0.102: PU503.5 v2(196.29,1.65)
  TOP w0.381: PC513.1 197.61,3.95 PR513.2 ; PC513.1 198.48,3.11 PR514.1 ; PC513.1 197.36,2.86 PU503.5
EN_+1VALWP: length 5.1
  BOTTOM w0.102: PR302.1 v2(184.14,99.59)
  BOTTOM w0.254: PU301.11 183.02,95.28 183.6,95.85 183.6,97.13 PR312.1 PR302.1
EN_CPU: length 3.1
  TOP w0.203: PR616.2 73.45,53.41 72.78,53.41 v2(72.38,53.01) 71.9,52.54 71.9,52.19 71.7,51.98 PU602.40
EN_INVPWR: length 144.3
  TOP w0.102: v1(101.22,81.3) 103.24,81.3 105.6,78.94 109.76,78.94 112.1,81.27 112.1,82.77 115.97,86.64 116.37,86.64 116.79,87.06 126.94,87.06 131.49,91.61 144.87,91.61 145.71,90.77 v2(147.83,90.77) 149.68,90.77 155.6,84.85 155.6,76.12 164.75,66.97 166.92,66.97 174.3,59.59 174.3,50.23 184.28,40.26 188.67,40.26 190.18,38.75 v1(190.18,28.43) ; UE1.B2 296.36,72.69 295.99,72.32 v1(295.99,72.3) 295.99,71.68 294.81,70.5 294.26,70.5 293.79,70.03 RE55.1
  BOTTOM w0.102: v1(101.22,81.3) 101.18,81.34 QV2.2
EN_LCDPWR: length 4.3
  BOTTOM w0.102: UV24.4 94.71,82.5 RV3.2 92.97,83.34 DV3.1 92.45,83.78 v2(92.02,83.34)
EN_PD_HV_1: length 54.4
  TOP w0.102: PR1211.1 18.03,38.61 PR1254.1 v1(18.04,39.64) 19.06,40.66 23.25,40.66 23.89,40.01 v2(23.89,38.64) 23.89,36.61 PR1260.1 ; v1(39.54,75.33) 40.33,76.12 40.33,84.7 38.24,86.78 RT70.2 ; PQ1214.5 12.74,37.19 PR1210.1 v1(12.74,38.88) ; PR1250.2 v1(70.85,111.93)
  BOTTOM w0.102: v1(12.74,38.88) 13.75,39.9 17.79,39.9 v1(18.04,39.64) ; v1(36.81,57.85) 36.81,71.93 38.97,74.08 39.57,74.08 39.96,74.48 39.96,74.91 v1(39.54,75.33)
EN_PD_HV_1#: length 3.4
  TOP w0.102: v2(11.52,32.66) 11.97,33.1 PR1253.2
  TOP w0.254: PR1253.2 12.04,33.62 PQ1214.2 12.04,34.84 12.14,34.94 12.58,34.94 12.69,34.83 PQ1214.3
EN_PD_HV_1_R: length 7.1
  TOP w0.076: 34.47,83.98 34.24,83.74 34.24,83.35 34.39,83.19 34.39,82.79 UT5.C2
  TOP w0.102: RT70.1 37.26,87.34 v2(36.33,87.34) 36.19,87.2 36.19,85.27 34.89,83.98 34.47,83.98
ENLDO_3V5V: length 6.7
  TOP w0.254: v1(153.14,113.68) 153.14,113.56 153.64,113.06 PU100.11
  BOTTOM w0.102: v1(153.14,113.68) v2(153.68,113.68)
  BOTTOM w0.254: PU102.11 169.6,115.52 169.85,115.77 169.85,116.4 170.44,116.99 170.6,116.99 PR102.1 171.91,117.69 PR103.1 172.29,118.07 v1(172.29,118.71)
ENVDD_PCH: length 2.2
  TOP w0.102: UE1.L12 v1(303.96,81.13)
  BOTTOM w0.102: v1(129.96,61.27) 130.18,61.04 UC1.U13 ; DV3.3 v1(92.95,85)
EOPIO_RCOMP: length 1.5
  BOTTOM w0.254: UC1.H65 100.5,65.1 v1(100.31,65.29)
  BOTTOM w0.381: v1(91.67,66.08) 91.35,66.41 RC91.1
ESPI_ALERT#: length 12.7
  TOP w0.102: v1(137.5,40.66) 137.5,39.81 RC21.1
  TOP w0.107: v1(301.54,76.35) UE1.H7
  BOTTOM w0.076: UC1.AY11 131.02,47.93 130.91,47.82 130.91,46.81 132.71,45.01 133.34,45.01 134.76,43.59 134.76,43.51
  BOTTOM w0.102: 134.76,43.51 136.07,42.2 v2(136.07,41.6) 137.01,40.66 v1(137.5,40.66)
ESPI_CLK: length 13.2
  TOP w0.102: RC16.1 138.82,41.29 v1(138.94,41.17)
  BOTTOM w0.076: 135.39,44.66 134.83,44.66 133.48,46.02 132.97,46.02 132.13,46.85 132.13,47.23 132.19,47.34 132.19,47.48 132.13,47.59 132.13,47.87 132.17,47.95 132.17,48.52 132.57,48.92 UC1.AW9
  BOTTOM w0.102: 135.39,44.66 136.99,44.66 v2(138.94,42.7) v1(138.94,41.17)
ESPI_CLK_5105: length 109.7
  TOP w0.102: RE350.1 288.65,77.46 v2(288.65,77.03) v1(288.65,76.35) ; v1(140.98,40.4) 140.98,40.81 140.21,41.57 140.21,42.32 CC316.1 RC16.2
  TOP w0.107: v1(299.96,76.33) UE1.G7
  BOTTOM w0.102: v1(179.99,51.33) 179.84,51.48 179.1,51.48 178.16,50.54 178.16,48.38 170.41,40.63 169.8,40.63 169.14,39.97 169.14,37.05 166.1,34 153.17,34 152.2,34.97 152.2,36.67 152.07,36.8 151.86,36.8 151.73,36.67 151.73,34.87 151.63,34.77 151.43,34.77 151.33,34.87 151.33,36.67 151.22,36.77 151.02,36.77 150.92,36.67 150.92,34.94 150.82,34.84 150.61,34.84 150.51,34.94 150.51,36.67 150.41,36.77 150.21,36.77 150.11,36.67 150.11,35.45 150.01,35.35 149.8,35.35 149.7,35.45 149.7,36.67 149.6,36.77 149.24,36.77 149.14,36.67 149.14,35.63 149.04,35.53 148.84,35.53 148.74,35.63 148.74,36.67 148.63,36.77 143.9,36.77 140.98,39.69 v1(140.98,40.4) ; v1(269.14,65.34) 269.64,65.84 JESPI.10 270.12,65.84 270.26,65.7 270.26,65.53 270.36,65.43 270.77,65.43 271.02,65.68 271.66,65.68 272.75,66.77 272.75,67.51 273.44,68.19 278.31,68.19 284.61,74.49 284.61,75 284.87,75.25 287.56,75.25 v1(288.65,76.35) 289.11,76.8 290.07,76.8 290.53,76.35 295.05,76.35 295.22,76.17 296.14,76.17 296.39,75.92 296.91,75.92 296.91,75.91 298.66,75.91 298.77,76.03 299.66,76.03 v1(299.96,76.33)
ESPI_CS#: length 114
  TOP w0.102: v1(301.6,75.53) 301.56,75.53 UE1.H6
  BOTTOM w0.076: 132.93,44.69 132.78,44.69 130.74,46.73 130.74,47.74 130.72,47.77 UC1.BA12
  BOTTOM w0.102: v1(180.46,50.73) 180.22,50.48 180.22,48.87 v2(176.99,45.65) 170.16,38.82 170.16,35.76 164.36,29.96 147.05,29.96 145.71,28.62 144.12,28.62 141.4,31.34 141.4,37.18 139.32,39.26 137.83,39.26 135.72,41.37 135.72,42.26 133.29,44.69 132.93,44.69 ; v1(301.6,75.53) 301.57,75.5 301.15,75.5 300.83,75.83 300.83,76.12 300.19,76.76 295.39,76.76 294.22,77.94 291.62,77.94 291.46,77.78 289.12,77.78 289.11,77.79 287.91,77.79 286.36,76.24 284.82,76.24 284.1,75.53 284.1,74.69 278.15,68.74 273.27,68.74 271.7,67.17 270.65,67.17 270.48,67.34 JESPI.7 268.98,67.34 v1(268.86,67.46)
ESPI_IO0: length 103.7
  TOP w0.102: UE1.K5 303.1,74.78 303.18,74.78 v1(303.18,74.79) ; RC366.2 v1(138.69,35.1)
  BOTTOM w0.102: v1(138.69,35.1) 138.69,32.91 143.67,27.93 146.17,27.93 147.37,29.13 166.66,29.13 170.97,33.44 170.97,38.22 v2(181.22,48.47) 182.02,49.27 v1(182.02,49.6) ; v1(268.86,69.74) 269.27,69.34 JESPI.3 270.26,69.34 270.36,69.24 271.13,69.24 271.36,69.47 277.89,69.47 282.41,73.99 282.41,74.92 285.79,78.3 287.38,78.3 288.32,79.23 289.32,79.23 289.68,78.88 294.9,78.88 296.31,77.46 300.47,77.46 300.69,77.24 303.22,77.24 303.57,76.9 303.57,75.18 v1(303.18,74.79)
ESPI_IO0_R: length 16.5
  TOP w0.102: RC366.1 138.69,37.1 v1(138.94,37.36)
  BOTTOM w0.076: UC1.AY13 130.15,48.23 130.04,48.12 129.94,48.01 129.87,47.8 129.87,47.68 129.93,47.45 129.93,47.31 129.88,47.19 129.88,46.92 130,46.79 130,46.04 132.84,43.2
  BOTTOM w0.102: 132.84,43.2 133.15,42.89 133.15,42.72 133.61,42.26 v2(133.61,41.62) 134.61,40.63 134.61,40.15 134.86,39.9 135.31,39.9 137.85,37.36 v1(138.94,37.36)
ESPI_IO1: length 102.8
  TOP w0.102: RC367.2 v1(139.58,35.05) ; v1(303.96,73.93) UE1.L4
  BOTTOM w0.102: v1(303.96,73.93) 303.55,74.34 303,74.34 302.75,74.59 302.75,76.7 302.45,77.01 300.59,77.01 300.36,77.23 296.2,77.23 295.01,78.43 289.38,78.43 288.88,78.93 288.33,78.93 287.48,78.07 285.89,78.07 283.6,75.77 283.6,74.85 277.98,69.23 271.61,69.23 271.39,69.01 270.58,69.01 270.41,68.84 JESPI.4 269.13,68.84 v1(268.86,69.11) ; v1(181.37,49.67) 181.37,49.09 v2(179.51,47.22) 170.62,38.34 170.62,33.47 166.65,29.5 147.24,29.5 145.9,28.16 143.94,28.16 139.58,32.52 v1(139.58,35.05)
ESPI_IO1_R: length 15.8
  TOP w0.102: RC367.1 v1(139.58,37.36)
  BOTTOM w0.076: 132.84,44.12 130.41,46.55 130.41,47.27 130.15,47.53 UC1.BA13
  BOTTOM w0.102: 132.84,44.12 132.99,44.12 134.85,42.26 v2(134.85,41.98) 134.85,41.39 135.97,40.28 135.97,39.74 137.95,37.76 139.32,37.76 139.58,37.51 v1(139.58,37.36)
ESPI_IO2: length 103.8
  TOP w0.102: v1(299.98,75.54) UE1.G6 ; v1(144.74,29.03) v2(143.52,29.03) 142.95,29.03 140.47,31.51 138.92,31.51 137.16,33.27 137.16,36.97 136.96,37.17 136.96,38.24 136.66,38.55 RC368.2
  BOTTOM w0.102: v1(299.98,75.54) 300.43,75.09 301.76,75.09 302.06,75.39 302.06,75.72 301.84,75.94 301.33,75.94 300.28,76.99 295.68,76.99 294.5,78.17 291.48,78.17 291.33,78.01 287.81,78.01 286.88,77.08 285.32,77.08 283.85,75.61 283.85,74.77 278.08,69 271.72,69 271.51,68.78 270.67,68.78 270.23,68.34 JESPI.5 269,68.34 v1(268.86,68.47) ; v1(144.74,29.03) 145.51,29.03 146.75,30.27 164.35,30.27 169.93,35.85 169.93,39.05 179.81,48.92 v1(179.81,50.28)
ESPI_IO2_R: length 10.5
  TOP w0.102: RC368.1 136.08,40.35 135.22,40.35 v1(135.1,40.47)
  BOTTOM w0.076: v2(133.46,43.07) 130.24,46.29 130.24,46.8 130.15,46.9 UC1.BB13
  BOTTOM w0.102: v1(135.1,40.47) 135.1,40.76 134.32,41.54 134.32,42.21 v2(133.46,43.07)
ESPI_IO3: length 107
  TOP w0.102: RC369.2 v1(140.59,34.64) ; v1(303.96,74.73) UE1.L5
  BOTTOM w0.102: v1(270.76,67.75) 270.67,67.84 JESPI.6 269.12,67.84 268.96,68 268.7,68 268.14,68.56 v2(268.14,68.99) 268.14,69.9 269.06,70.82 270.72,70.82 271.85,69.7 276.91,69.7 279.16,71.95 279.99,71.95 282.1,74.06 282.1,74.94 285.72,78.55 287.31,78.55 288.34,79.58 289.82,79.58 290.11,79.29 295.25,79.29 296.22,78.32 300.29,78.32 301.14,77.47 303.81,77.47 304.4,76.88 304.4,75.33 303.96,74.89 v1(303.96,74.73) ; v1(140.59,34.64) 140.59,31.83 144.03,28.39 145.81,28.39 147.15,29.73 164.46,29.73 170.39,35.66 170.39,38.58 180.63,48.82 v1(180.63,50.14)
ESPI_IO3_R: length 18.2
  TOP w0.102: v2(141.51,36.72) RC369.1 v1(140.59,37.36)
  BOTTOM w0.076: UC1.AY12 130.72,48.52 130.41,48.22 130.41,47.79 130.58,47.63 130.58,46.64 132.76,44.45 133.03,44.45
  BOTTOM w0.102: 133.03,44.45 133.06,44.45 135.49,42.02 135.49,41.17 138.03,38.63 138.22,38.63 138.86,37.99 139.96,37.99 v1(140.59,37.36)
ESPI_RESET#: length 24.4
  TOP w0.102: v2(142.13,31.29) v1(142.54,30.88)
  TOP w0.107: v1(303.16,75.53) UE1.K6
  BOTTOM w0.076: UC1.BA11 131.07,47.47 131.07,46.9 132.63,45.34 133.26,45.34 134.99,43.61 134.99,43.56
  BOTTOM w0.102: 134.99,43.56 135.67,42.88 136.37,42.88 138.01,41.24 138.01,40.07 138.18,39.9 139.45,39.9 141.75,37.6 141.75,31.66 v1(142.54,30.88)
EXPANDER_ALERT#: length 1.3
  BOTTOM w0.102: UE2.7 45.86,80.77 T267.1
EXPANDER_GPU_SMCLK: length 212.1
  TOP w0.102: RE525.1 310.01,77.52 309.58,77.52 309.33,77.27 v1(309.33,77.25) ; v1(305.85,74.26) 305.53,73.93 304.92,73.93 304.52,74.33 UE1.M4
  BOTTOM w0.102: UE2.19 45.86,75.35 45.72,75.22 45.72,74.91 44.19,73.37 39.05,73.37 37.98,72.3 37.98,56.18 36.83,55.03 36.83,42.19 54.92,24.09 77.48,24.09 79.51,26.13 122.1,26.13 129.58,18.65 175.89,18.65 177.81,16.73 183.74,16.73 184.47,17.46 184.47,21.18 v1(184.29,21.36) ; CE505.1 306.35,79.24 306.35,78.94 306.65,78.64 307.35,78.64 308.5,77.5 309.09,77.5 v1(309.33,77.25)
EXPANDER_GPU_SMDAT: length 211.3
  TOP w0.102: RE524.1 310.01,77.75 309.55,77.75 v1(309.33,77.97)
  TOP w0.107: UE1.M7 v1(304.81,76.28)
  BOTTOM w0.102: v1(184.88,21.36) 184.7,21.18 184.7,17.36 183.84,16.5 177.72,16.5 175.79,18.42 129.49,18.42 122.01,25.9 79.61,25.9 77.57,23.87 54.83,23.87 36.6,42.09 36.6,55.13 37.75,56.28 v4(37.75,59.4) 37.75,72.4 38.95,73.6 44.1,73.6 45.5,75 45.5,75.22 45.36,75.35 UE2.20 ; CE504.1 306.58,79.24 306.58,79.04 306.75,78.87 307.45,78.87 308.59,77.73 309.09,77.73 v1(309.33,77.97)
FAN1_PWM: length 28.7
  TOP w0.102: v1(291.06,40.63) 290.73,40.63 v3(290.33,41.04) 290.08,41.29 286.22,41.29 285.97,41.04 285.97,40.63 285.62,40.28 284.9,40.28 283.79,41.38 283.09,41.38 282.87,41.17 280.2,41.17 279.27,42.1 278.35,42.1 277.15,40.89 273.34,40.89 273.15,40.7 272.37,40.7 272.23,40.85 271.85,40.85 v1(271.47,40.47)
  TOP w0.107: v1(303.96,79.53) UE1.L10
  BOTTOM w0.102: JFAN1.2 269.84,40.58 RE48.2 270.5,40.47 v1(271.47,40.47)
FAN1_TACH: length 25
  TOP w0.102: v1(286.37,40.86) 286.37,40.63 285.78,40.04 284.84,40.04 283.73,41.16 283.15,41.16 282.95,40.96 280.08,40.96 279.15,41.9 278.44,41.9 277.23,40.69 274.48,40.69 274.22,40.43 273.64,40.43 v3(273.64,40.43) 272.06,40.43 v1(272.06,40.43) ; RE51.2 267.24,42.3 v1(267.24,42.39)
  TOP w0.107: v1(298.36,73.13) UE1.E3
  BOTTOM w0.102: v1(272.06,40.43) 271.68,40.05 269.57,40.05 v1(267.24,42.39) 266.91,42.06 266.61,42.06 JFAN1.3
FB_1.8VALW: length 4.3
  TOP w0.102: v2(121.37,110.61) 121.45,110.53 PC503.2
  TOP w0.381: PR501.2 121.23,109.05 121.23,109.45 PC503.2 121.47,109.65 PR506.1 122.36,109.17 122.1,108.91 PU501.6
FB_1VS_VCCIO: length 4
  TOP w0.102: PR421.2 144.71,106.89 v2(144.82,106.77)
  TOP w0.254: PU401.5 143.51,108.99 143.87,108.63 PR422.1 144.71,108.63 PR421.2
FB_+1VALWP: length 6.5
  BOTTOM w0.102: PR311.1 184.14,95 184.5,95.36 185.9,95.36 186.21,95.67 v2(186.21,96.41)
  BOTTOM w0.254: PR308.2 PR306.2 ; PR308.2 184.07,93.93 PU301.14 ; PR308.2 PR311.1
FB_GT: length 4.5
  TOP w0.203: PU602.5 v2(68.96,53.99) 68.96,54.37 69.53,54.93 PR623.2 69.55,55.23 PR622.2 69.56,56.06 PR621.2
FB_IA: length 8
  TOP w0.203: PR650.1 62.75,53.53 PR648.2 63.34,52.71 64.02,52.03 v2(64.02,50.92) 64.02,49.82 64.25,49.58 PU602.17
  TOP w0.254: PR645.2 61.98,53.54 PR650.1
FB_PRIM_CORE: length 3.2
  TOP w0.102: v2(133.76,109.48) PR423.1
  TOP w0.254: PR423.1 133.76,110.44 PR424.1 133.73,111.34 PU402.5
FB_VSA: length 6.3
  TOP w0.203: PU602.25 68.56,46.35 67.95,45.74 v1(67.34,45.74)
  BOTTOM w0.102: v1(67.34,45.74) v2(66.63,45.74)
  BOTTOM w0.203: PR646.1 67.34,43.86 PR649.1 ; PR649.1 67.32,44.7 PR652.1 ; PR649.1 v1(67.34,45.74)
FCCM_GT: length 4
  TOP w0.102: v1(65.07,52.93) v2(65.07,53.56)
  TOP w0.203: v1(65.07,52.93) 65.62,52.38 65.89,52.38 PU602.11
  TOP w0.254: PR682.1 63.58,67.18 v1(63.79,67.39)
  BOTTOM w0.254: v1(63.79,67.39) 63.25,66.85 PR671.2
FCCM_IA: length 2.7
  TOP w0.203: PU602.21 66.83,47.58 v1(66.38,47.58)
  TOP w0.254: PR681.1 62.74,73.58 v1(62.77,73.55) PR659.2
  BOTTOM w0.102: v1(66.38,47.58) 66.38,48.07 v2(66.44,48.14)
FCCM_R_GT: length 1.4
  BOTTOM w0.203: PR671.1 62.86,65.93 62.82,65.89 PU612.1
FCCM_R_IA: length 2.5
  TOP w0.381: PR659.1 61.85,72.67 62.24,72.29 v1(62.32,72.29)
  BOTTOM w0.102: v2(62.95,72.84) 62.87,72.84 v1(62.32,72.29)
  BOTTOM w0.203: PU610.1 62.16,71.83 62.32,71.99 v1(62.32,72.29)
FCCM_VSA: length 2.9
  TOP w0.203: PU602.29 70.16,46.45 v1(70.36,46.24)
  BOTTOM w0.102: v2(65.49,75.48) 65.68,75.29 v1(66.03,75.29)
  BOTTOM w0.254: v1(66.03,75.29) PR679.2
FFS_INT2: length 25.2
  TOP w0.102: QN1.2 280.6,38.57 280.6,38.12 278.76,36.28 275.46,36.28 v1(275.29,36.11) ; v1(134.4,64.74) 135.75,63.39 138.18,63.39 142.12,67.33 RC404.1
  BOTTOM w0.102: LGA1.11 273.4,44.18 272.37,43.15 270.79,43.15 v2(270.65,43.01) 270.44,42.79 v1(269.22,42.79) ; v1(134.4,64.74) 134.75,64.39 UC1.J5
FFS_INT2_Q: length 11.6
  TOP w0.102: 283.09,39.39 282.68,39.8 QN1.3 ; 283.09,39.39 v2(283.09,37.57) 283.09,36.7 282.17,35.79 281.11,35.79 v1(281.04,35.85) ; 283.09,39.39 283.55,39.85 283.55,40.62 v1(283.43,40.74)
  BOTTOM w0.102: v1(283.43,40.74) 282.67,41.5 RN1.2 ; v1(281.04,35.85) 280.9,35.71 JSATA1.19
FIVR_EN: length 3
  TOP w0.102: RC218.1 v2(64.39,42.51) ; RC218.1 RC219.1 ; RC218.1 RC217.1
FIVR_EN_R: length 20.4
  TOP w0.102: v1(72.83,39.98) RC126.2 ; JXDP1.45 64.45,36.84 63.89,37.4 63.4,37.4 v1(63.2,37.59) 63.2,38.18 RC132.1 63.37,38.36 62.9,38.83 62.9,40.16 RC217.2 63.38,40.65 62.95,41.08 v2(62.95,42.49)
  BOTTOM w0.102: v1(72.83,39.98) 72.83,39.26 71.81,38.25 63.48,38.25 63.38,38.14 63.37,38.14 63.2,37.97 v1(63.2,37.59)
GPIO126: length 4.2
  TOP w0.102: RE5.1 299.7,83.45 v2(299.7,82.9) 299.27,82.47 299.16,82.47 298.36,81.67 298.36,81.13 UE1.E12
GPP_B23: length 10.9
  BOTTOM w0.102: RC317.1 148.67,57.24 v1(148.67,56.28) ; UC1.AM7 133.94,53.45 134.25,53.14 135.19,53.14 135.32,53.27 135.62,53.27 135.83,53.06 135.83,52.73 135.95,52.61 137.75,52.61 137.95,52.8 139.65,52.8 139.93,53.08 v2(140.85,53.08) 141.4,53.08 v1(142.22,53.91)
GPP_C5: length 8.9
  BOTTOM w0.076: UC1.W1 138.34,59.57 138.45,59.68 139.63,59.68 140.11,60.17 142.86,60.17
  BOTTOM w0.102: RC25.1 v2(144.35,61.36) 144.05,61.36 142.86,60.17
GPP_C8: length 9.6
  BOTTOM w0.102: RC405.1 144.73,59.84 144.66,59.91 v2(144.43,59.91) 144.23,59.71 144.23,59.28 143.64,58.69 143.16,58.69 142.93,58.91 140.68,58.91 140.29,58.52 138.77,58.52 138.77,58.52 138.38,58.52 138.24,58.65 137.64,58.65 137.46,58.48 UC1.AB1
GPP_E23: length 1.1
  TOP w0.254: T120.1 130.55,62.35 v1(130.55,62.34)
  BOTTOM w0.254: UC1.N12 130.83,62.63 v1(130.55,62.34)
GPU_B+:
  vias: v1(54.39,64.2) v1(54.52,62.6) v1(55.15,64.2) v1(55.26,62.62) v1(55.99,64.21) v1(56.33,62.63) v1(56.62,64.24) v1(56.96,62.63) v2(53.09,64.15)
GREEN: length 12.6
  BOTTOM w0.102: LV17.2 316.11,87.63 CV130.1 316.06,87.06 315.35,86.35 315.35,85.12 DV5.3 316.39,83.9 v2(318.15,82.14) 318.23,82.06 320.98,82.06 JCRT1.2
GREEN_CRT: length 5.2
  TOP w0.102: v1(280.83,57.14) 280.68,56.99 280.68,56.18 280.45,55.95 280.45,55.85 280.27,55.67 UV6.22
  BOTTOM w0.102: v1(315.03,89.43) 315.03,90.36 CV127.1 RV117.1 LV17.1
GT1P: length 8.8
  BOTTOM w0.254: PL612.3 66.74,62.5 67.06,62.18 67.06,58.76 66.74,58.44 65.54,58.44 v2(65.02,57.92) 64.78,57.68 PR674.2
GT_SNUB1:
  vias: v2(67.67,65.4)
GT_SW1:
  vias: v1(64.05,64.63) v1(64.85,64.63) v1(65.53,64.64) v2(62.65,60.9)
H_CATERR#: length 8.8
  BOTTOM w0.076: 100.81,73.45 100.81,73.17 101.08,72.91 101.08,72.59 102.19,71.48 102.19,70.73 102.01,70.55 102.01,70.09 102.16,69.94 102.16,69.58 102.12,69.48 102.12,69.29 102.16,69.2 102.16,68.95 102.15,68.91 102.1,68.75 102.02,68.47 102.02,68.36 101.94,68.09 UC1.D63
  BOTTOM w0.102: 100.81,73.45 101.35,73.98 101.35,74.4 101.45,74.51 v2(101.45,74.54) 101.61,74.69 RC79.1
H_CPU_SVIDALRT#: length 12.7
  BOTTOM w0.076: UC1.B63 101.51,69.06 101.4,69.17 101.4,70.06 101.19,70.28 101.19,70.81 101.27,70.9 101.57,70.9 101.66,70.99 101.66,71.11 101.57,71.2 101.27,71.2 101.19,71.29 101.19,71.63 100.47,72.35 100.47,72.55 100.01,73.01
  BOTTOM w0.102: RC153.1 98.66,75.46 97.31,74.11 97.31,73.92 97.46,73.77 97.68,73.77 v2(98.23,74.33) 98.4,74.5 98.56,74.5 98.7,74.36 98.7,74.16 98.32,73.78 98.32,73.61 98.44,73.49 98.61,73.49 98.98,73.87 99.15,73.87 100.01,73.01
H_CPUPWRGD: length 16.1
  BOTTOM w0.076: UC1.A68 98.6,69.79 98.34,70.05 97.77,70.05 97.53,70.29 95.47,70.29 95.29,70.47
  BOTTOM w0.102: 95.29,70.47 93.69,72.07 v2(93.69,74.47) 93.69,77.02 91.25,79.46 CC300.1 RC77.2
H_CPUPWRGD_R: length 1.4
  BOTTOM w0.102: RC77.1 90.24,82.5 T9.1
H_PROCHOT#: length 71.9
  TOP w0.102: RE288.2 301.38,85 v1(301.38,85.44) ; v1(72.92,52.18) 73.41,51.69 PR678.1 PC605.2 74.65,51.92 v1(75.42,51.92) ; v1(149.46,95.41) v2(148.68,94.63) 146.08,92.03 141.63,92.03 140.81,92.85 131.48,92.85 126.14,87.51 122.13,87.51 121.76,87.88 117.03,87.88 116.36,87.2 115.96,87.2 111.64,82.89 111.64,81.65 110.37,80.38 108.9,80.38 107.96,79.44 105.67,79.44 103.15,81.96 100.89,81.96 100.26,81.32 100.26,80.84 99.32,79.9 97.6,79.9 v1(96.75,80.75) ; v1(11.66,14.62) 11.83,14.79 PR926.1
  BOTTOM w0.102: RC83.1 94.28,80.24 CC310.1 96.64,79.9 RC84.1 96.65,80.66 v1(96.75,80.75)
H_PROCHOT#_R: length 14.4
  BOTTOM w0.076: 97.12,72.7 98.89,72.7 99.4,72.18 99.4,71.7 100.53,70.57 100.53,70.06 100.33,69.87 100.33,69.61 100.39,69.49 100.39,69.34 100.33,69.15 100.33,68.98 100.42,68.72 UC1.C65
  BOTTOM w0.102: 97.12,72.7 96.65,72.7 95.71,73.63 v2(95.71,74.34) 95.71,74.59 96.15,75.03 96.15,78.14 96.65,78.64 RC84.2
H_PROCHOT#_R1: length 2.4
  TOP w0.102: RE288.1 301.12,83.03 v2(301,82.9) 301,82.28 301.16,82.11 UE1.H13
H_THERMTRIP#: length 82.9
  TOP w0.102: v1(147.3,96.41) v2(146.71,95.82) 145.48,94.59 144.49,94.59 143.51,93.61 142.25,93.61 141.18,94.68 131.07,94.68 125.46,89.06 122.73,89.06 122.4,89.4 115.28,89.4 113.57,87.69 113.57,87.04 110.01,83.48 110.01,82.54 109.4,81.93 108.3,81.93 107.61,81.25 105.26,81.25 103.61,82.9 99.74,82.9 v1(99.14,82.3) ; RD14.2 73.03,5.99 v1(73.15,6.12) ; QE4.3 281.14,71.2 279.74,71.2 279.49,70.95 278.92,70.95 278.82,71.05 278.82,72.34 v1(277.83,73.33) ; v1(139.83,1.79) 140.53,2.49 RD27.2
  BOTTOM w0.076: 100.56,73.41 100.56,73.12 100.89,72.79 100.89,72.49 102.02,71.36 102.02,70.79 101.77,70.55 101.77,70.09 101.99,69.87 101.99,69.61 101.94,69.49 101.94,69.34 101.99,69.15 101.99,68.98 101.91,68.72 UC1.C63 ; 100.56,73.45 101.13,74.01 101.13,75.08 101.08,75.12
  BOTTOM w0.102: v1(99.14,82.3) 99.14,81.49 100.19,80.44 100.19,79.5 CC312.1 100.7,79.01 RC80.1 100.72,78 101.08,77.63 101.08,75.12 ; 100.56,73.41 100.56,73.45
H_VCCST_PWRGD_XDP: length 7.4
  TOP w0.102: RC124.2 RC123.2 CC307.1 ; JXDP1.39 65.95,36.91 66.93,37.89 CC307.1 ; v2(67.63,40.48) 67.63,39.8 67.44,39.62 67.44,38.86 CC307.1
HDA_BIT_CLK: length 13
  TOP w0.102: v1(126.08,39.77) 126.08,38.8 126.29,38.59 126.29,37.2 126.1,37.01 RC93.2
  BOTTOM w0.076: UC1.AY22 125.3,48.23 125.2,48.12 125.1,48.01 125.03,47.8 125.03,47.68 125.09,47.45 125.09,47.31 125.04,47.19 125.04,46.72 125.37,46.39 125.37,45.7 125.71,45.36 125.71,44.23 126,43.94
  BOTTOM w0.102: v1(126.08,39.77) 126.45,40.14 126.45,41.59 v2(126.3,41.74) 126.12,41.92 126.12,43.82 126,43.94
HDA_BIT_CLK_R: length 15.8
  TOP w0.102: RC93.1 CC27.1 127.02,35.46 127.18,35.3 127.18,34.37 127.44,34.12 128.24,34.12 v2(130.25,32.11) 130.26,32.1 133.91,32.1 134.61,31.4 v1(135.97,31.4) ; UA1.6 296.05,35.52 295.1,36.47 v1(294.89,36.47) 294.64,36.72 294.14,36.72 293.76,37.1 RA17.1
HDA_RST#: length 15.4
  TOP w0.102: RC95.2 CC331.1 127.46,36.95 127.26,36.95 126.84,37.37 126.84,40.11 126.59,40.36 v1(126.07,40.36)
  BOTTOM w0.076: v1(126.07,40.36) 125.67,40.77 125.67,43.89 125.37,44.2 v2(125.37,44.47) 125.37,45.46 125.21,45.62 125.21,46.3 124.87,46.64 124.87,47.23 124.89,47.26 124.92,47.34 124.92,47.46 124.85,47.68 124.85,47.82 124.91,47.98 124.91,48.06 125.13,48.76 125.13,48.76 125.3,48.94 UC1.AW22
HDA_RST#_R: length 10.6
  TOP w0.102: v1(296.87,40.7) 296.87,41.34 RA50.1 ; v1(136.91,31.92) 134.86,31.92 134.19,32.58 130.76,32.58 v2(129.55,33.8) 128.73,34.61 RC95.1
HDA_SDIN0: length 28.4
  TOP w0.102: v2(129.39,31.01) v1(128.53,31.01) 128.41,31.12 CC332.1 ; v1(287.35,32.2) 287.61,32.46 287.61,33.45 290.3,36.15 RA9.1
  BOTTOM w0.076: UC1.BA21 125.9,48.03 125.9,46.79 126.04,46.66 126.04,46.05 126.48,45.61 126.48,45.17
  BOTTOM w0.102: 126.48,45.17 126.48,45.05 127.71,43.83 127.71,42.99 128.02,42.67 128.02,39.38 127.24,38.59 125.85,38.59 125.38,38.12 125.38,36.86 127.76,34.47 127.76,31.77 v1(128.53,31.01)
HDA_SDIN0_R: length 7.6
  TOP w0.102: v2(289.87,36.63) 291.26,36.63 RA9.2 292.17,35.72 292.17,35.46 292.44,35.2 294.77,35.2 295.15,34.82 295.86,34.82 295.96,34.72 UA1.8
HDA_SDOUT: length 15
  TOP w0.102: v1(127.59,39.78) 127.93,40.12 CC333.1 ; CC333.1 128.02,41.04 128.02,41.86 v2(127.96,41.93) ; CC333.1 RC94.2 RC223.2 129.85,39.31 130.31,39.77 RC187.1
  BOTTOM w0.076: 126.58,43.29 126.58,43.39 126.58,43.81 125.91,44.49 125.91,45.48 125.54,45.84 125.54,46.45 125.38,46.62 125.38,46.82 125.3,46.9 UC1.BB22
  BOTTOM w0.102: v1(127.59,39.78) 127.56,39.81 127.44,39.81 126.83,40.42 126.83,41.85 126.58,42.1 126.58,43.29
HDA_SDOUT_R: length 12.8
  TOP w0.102: RC94.1 128.77,38.23 128.77,37.36 129.42,36.71 129.42,35.07 v2(130.83,33.66) 131.2,33.29 135.4,33.29 v1(135.8,32.89) ; UA1.5 296,35.92 295.34,36.59 v1(295.34,36.97)
HDA_SYNC: length 13.2
  TOP w0.102: v1(127.57,41.1) 127.13,40.66 127.13,39.34 128.45,38.02 128.45,37.36 128.91,36.9 RC92.2
  BOTTOM w0.076: UC1.BA22 125.3,47.53 125.57,47.27 125.57,46.66 125.71,46.52 125.71,45.91 126.1,45.52 126.1,44.69 126.91,43.88 126.91,43.29
  BOTTOM w0.102: v1(127.57,41.1) v2(127.57,41.74) 127.57,42.2 126.91,42.86 126.91,43.29
HDA_SYNC_R: length 9.5
  TOP w0.102: RC92.1 128.91,35.08 131.02,32.96 v2(132.26,32.96) 134.57,32.96 v1(135.01,32.53) ; UA1.10 296.04,33.92 295.92,33.8 295.92,32.97 v1(295.6,32.66)
HDD_A_EQ: length 3.5
  TOP w0.102: UN7.17 279.96,62.82 v1(280.06,62.72) 280.4,62.38 RN10.1
  BOTTOM w0.102: RN11.2 279.6,62.38 279.95,62.72 v1(280.06,62.72) 280.19,62.72 v2(280.52,62.39)
HDD_A_EQ2: length 3.3
  TOP w0.102: UN7.18 v1(280.04,63.32) 280.36,63.65 RN20.2
  BOTTOM w0.102: RN21.1 279.98,63.26 v1(280.04,63.32) 280.05,63.32 v2(280.44,63.72)
HDD_A_PRE: length 3.9
  TOP w0.102: RN6.2 v1(273.62,62.76) 273.78,62.76 273.85,62.82 UN7.9
  BOTTOM w0.102: RN7.2 273.28,62.25 273.62,62.59 v1(273.62,62.76) 273.79,62.76 v2(274.12,63.09)
HDD_B_EQ: length 5.2
  TOP w0.102: RN12.2 280.55,64.53 v1(280.04,64.03) 279.84,63.82 UN7.19
  BOTTOM w0.102: RN13.2 278.1,64.22 v2(278.49,64.22) 279.85,64.22 v1(280.04,64.03)
HDD_B_EQ2: length 4.6
  TOP w0.102: UN7.13 277.14,60.85 RN19.1 RN18.2 279.89,59.53 280.22,59.2 v2(280.57,59.2)
HDD_B_PRE: length 3.7
  TOP w0.102: v1(273.59,63.46) 273.27,63.77 RN8.1 ; v1(273.59,63.46) 273.72,63.32 UN7.8 ; v1(273.59,63.46) v2(273.95,63.81)
  BOTTOM w0.102: RN9.2 273.27,63.46 v1(273.59,63.46)
HDD_DET#: length 30.4
  BOTTOM w0.076: 138.45,66.3 138.44,66.28 138.44,66.26 137.96,65.78 137.4,65.78 arc(137.32,65.79) 137.25,65.79 137.16,65.8 arc(137.12,65.8) 137.08,65.8 arc(136.89,65.76) 136.72,65.67 136.6,65.54 UC1.H2
  BOTTOM w0.102: v1(162.33,71.97) 161.93,71.57 149.13,71.57 v2(148.92,71.78) 148.44,72.26 146.76,72.26 146.55,72.04 146.55,71.76 146.11,71.32 RPC4.3 143.47,71.32 138.45,66.3 ; JSATA1.13 v1(277.9,35.77)
HDD_DEVSLP: length 6.6
  BOTTOM w0.102: UC1.J1 138.65,64.88 v1(138.8,65.02) 138.82,65.02 v2(139.59,65.79) ; v1(275.95,38.22) 275.95,38.17 RN3.2 276.99,37.13 276.99,36.34 276.81,36.16 276.81,35.56 276.9,35.48 JSATA1.11
HDD_EN: length 7.2
  BOTTOM w0.102: UZ23.3 277.39,41.73 277.27,41.85 276.42,41.85 RN5.1 ; UC1.AB4 135.13,58.25 v1(135.01,58.13) ; RN5.1 RN4.2 276.36,40.93 276.81,40.47 276.81,39.93 277,39.74 v1(277,38.63) ; RN5.1 276.98,42.54 276.98,42.86 v2(277.28,43.16)
HDD_FALL_INT: length 7.9
  TOP w0.102: v1(151.23,40.79) 151.38,40.64 151.6,40.64 152.48,39.77 RC370.1
  BOTTOM w0.102: LGA1.12 273.39,44.68 v2(272.45,43.73) 272.19,43.48 269.78,43.48 v1(269.6,43.3) ; UC1.AM5 134.8,53.64 v1(135.06,53.9)
HDMI_CEC: length 16.3
  TOP w0.102: v2(117.86,106.39) 117.35,106.9 RV19.1 116.03,107.52 115.7,107.52 115.32,107.9 v1(115.11,107.9)
  BOTTOM w0.102: JHDMI1.13 104.68,111.32 105.42,110.58 107.73,110.58 108.15,110.17 108.15,109.3 110.05,107.4 114.6,107.4 v1(115.11,107.9)
HDMI_CLKN: length 3.2
  TOP w0.094: CV38.1 105.9,102.54 105.9,102.92 106.05,103.08 RV17.1 105.89,103.54 105.89,104.05 LV12.2 106.24,104.4 RV34.1
HDMI_CLKP: length 3.2
  TOP w0.094: CV37.1 105.71,102.56 105.71,102.87 105.51,103.08 RV16.1 105.7,103.54 105.7,104.05 LV12.1 105.35,104.4 RV33.1
HDMI_CTRL_CLK: length 3.5
  BOTTOM w0.102: v2(113.35,113.62) 113.11,113.38 RV22.1 113.11,110.98 QV3.6 112.78,110.97 112.5,110.69 v1(112.5,110.66)
HDMI_CTRL_DATA: length 3.1
  BOTTOM w0.102: v1(115,109.09) QV3.3 115.8,109.67 RV23.1 116.39,110.25 v2(116.39,111.14)
HDMI_HPD: length 13.9
  TOP w0.102: v1(114.5,107.9) 114.25,108.15 RV21.1 114.33,108.71 114.56,108.48 115.99,108.48 QV5.1 116.78,107.69 v2(117.89,107.69)
  BOTTOM w0.102: JHDMI1.19 108.36,110.51 108.36,109.47 109.92,107.9 v1(114.5,107.9)
HDMI_L_CLKN: length 6.4
  TOP w0.094: RV34.2 106.24,105.31 LV12.3 105.89,105.66 105.89,106.03 106.05,106.19 106.05,106.19 RV35.1 105.89,106.76 105.89,107.16 105.82,107.22 105.82,107.27 105.41,107.68 105.36,107.68 v4(104.67,108.37) 104.24,108.81 103.81,108.81 103.64,108.98 103.64,109.2 103.64,109.2 103.64,109.41 JHDMI1.12
HDMI_L_CLKP: length 6.4
  TOP w0.094: RV33.2 105.35,105.31 LV12.4 105.7,105.66 105.7,106.03 RV35.2 105.7,106.76 105.7,107.08 v4(105.46,107.32) 104.85,107.94 104.8,107.94 104.31,108.42 104.31,108.47 104.16,108.62 103.74,108.62 103.45,108.91 103.45,109.27 103.46,109.28 103.46,109.41 JHDMI1.10
HDMI_L_TX_N0: length 12.5
  TOP w0.094: JHDMI1.9 102.16,110.93 102.16,110.81 102.29,110.69 107.54,110.69 108.73,109.49 v4(108.73,108.77) 108.73,107.76 108.77,107.73 108.77,107.14 108.73,107.11 108.73,106.76 RV32.1 108.71,106 108.71,105.64 LV9.3 109.03,105.31 RV31.2
HDMI_L_TX_N1: length 6
  TOP w0.094: RV28.2 102.68,105.31 LV6.3 102.33,105.66 102.33,106.05 RV29.1 102.33,106.78 102.33,107.16 v4(101.88,107.61) 101.16,108.33 101.16,108.38 100.74,108.79 100.7,108.79 100.59,108.9 100.59,109.36 JHDMI1.6
HDMI_L_TX_N2: length 7.6
  TOP w0.094: RV25.2 99.13,105.31 LV3.3 98.78,105.66 98.78,106.08 RV26.1 98.85,106.74 98.85,107.56 v4(98.43,107.97) 98.11,108.3 98.11,108.91 98.14,108.95 98.14,109.53 98.11,109.56 98.11,110.05 98.51,110.45 98.89,110.45 99.16,110.72 99.16,110.93 JHDMI1.3
HDMI_L_TX_P0: length 12.5
  TOP w0.094: RV30.2 108.15,105.31 LV9.4 108.52,105.68 108.52,106.05 108.5,106.07 108.5,106.08 RV32.2 108.55,106.76 v4(108.55,107.43) 108.55,108.44 108.52,108.48 108.52,109.06 108.55,109.09 108.55,109.41 107.46,110.5 102.21,110.5 101.98,110.73 101.98,110.89 JHDMI1.7
HDMI_L_TX_P1: length 5.9
  TOP w0.094: JHDMI1.4 100.4,109.47 100.4,108.82 v4(100.8,108.43) 101.52,107.71 101.52,107.66 101.93,107.25 101.98,107.25 102.15,107.08 102.15,106.78 RV29.2 102.15,106.05 102.15,105.66 LV6.4 101.8,105.31 RV27.2
HDMI_L_TX_P2: length 7.7
  TOP w0.094: JHDMI1.1 98.97,110.9 98.97,110.79 98.81,110.64 98.43,110.64 97.92,110.13 v4(97.92,109.24) 97.92,108.22 98.07,108.07 98.07,108.02 98.49,107.61 98.53,107.61 98.66,107.48 98.66,106.88 RV26.2 98.59,106.08 98.59,105.66 LV3.4 98.24,105.31 RV24.2
HDMI_OB: length 25.5
  TOP w0.102: v1(111.43,103.31) 112.15,102.59 QV4.1 111.88,102.06 RV15.2 ; RV11.2 RV12.2 101,103.3 v1(101,104.04) ; v1(107.27,103.99) RV17.2 107.27,102.16 RV14.2 ; RV16.2 RV13.2 103.46,103.92 v1(103.58,104.04) ; RV10.2 v1(97.21,104.05)
  BOTTOM w0.102: v1(111.43,103.31) 110.75,103.99 v1(107.27,103.99) 107.2,103.99 106.66,104.53 104.07,104.53 v1(103.58,104.04) v1(101,104.04) 100.55,104.48 v2(98.51,104.48) 97.97,104.48 97.53,104.05 v1(97.21,104.05)
HDMI_TX_N0: length 4
  TOP w0.094: RV31.1 109.03,104.4 LV9.2 108.68,104.04 108.68,103.84 108.83,103.69 v4(108.83,103.04) 108.83,102.38 RV15.1 108.88,101.79 108.88,101.59 CV36.2
HDMI_TX_N1: length 2.9
  TOP w0.094: CV34.2 102.42,102.2 102.14,102.48 102.14,102.67 RV13.1 102.45,103.08 102.3,103.23 102.3,104.02 LV6.2 102.68,104.4 RV28.1
HDMI_TX_N2: length 3
  TOP w0.094: CV32.2 99.13,102.14 98.74,102.53 98.74,102.82 RV11.1 98.9,103.08 98.75,103.23 98.75,104.02 LV3.2 99.13,104.4 RV25.1
HDMI_TX_P0: length 4
  TOP w0.094: CV35.2 108.69,101.48 108.69,101.65 RV14.1 108.64,102.41 108.64,102.72 108.61,102.75 108.61,103.33 108.64,103.37 108.64,103.61 108.47,103.78 108.47,104.07 LV9.1 108.15,104.4 RV30.1
HDMI_TX_P1: length 2.9
  TOP w0.094: RV27.1 101.8,104.4 LV6.1 102.12,104.08 102.12,103.51 RV12.1 101.95,102.81 101.95,102.54 101.62,102.2 CV33.2
HDMI_TX_P2: length 3
  TOP w0.094: RV24.1 98.24,104.4 LV3.1 98.56,104.08 98.56,103.51 RV10.1 98.55,102.65 98.55,102.45 98.24,102.14 CV31.2
HOST_DEBUG_TX: length 34.5
  TOP w0.102: RZ132.1 299.64,50.49 v1(299.64,50.85)
  TOP w0.112: v1(299.94,80.35) UE1.G11
  BOTTOM w0.102: RE73.2 RE306.2 274.58,73.95 275.15,73.95 275.6,74.4 JDEG1.8 276.45,74.4 276.92,73.93 279.38,73.93 279.66,74.21 279.66,74.81 281.1,76.25 281.38,76.25 284.83,79.7 285.75,79.7 289.16,83.1 v3(289.26,83.1) 290.56,83.1 291.23,82.42 292.04,82.42 293.79,80.67 295.26,80.67 295.83,81.24 297.25,81.24 297.78,80.71 298.52,80.71 298.88,80.35 v1(299.94,80.35)
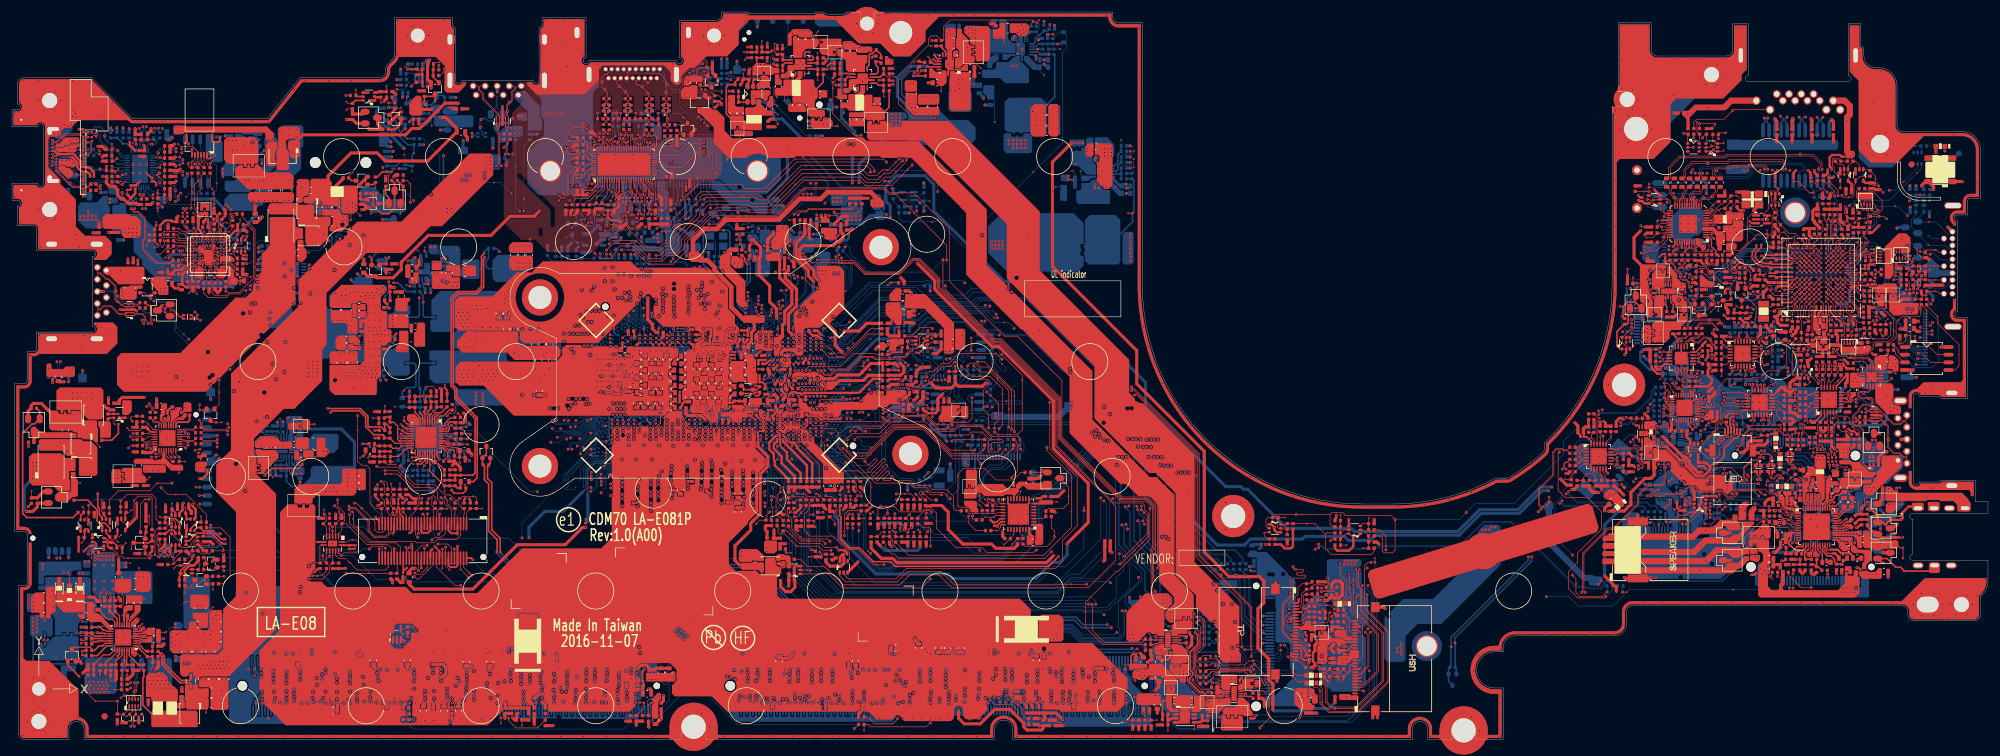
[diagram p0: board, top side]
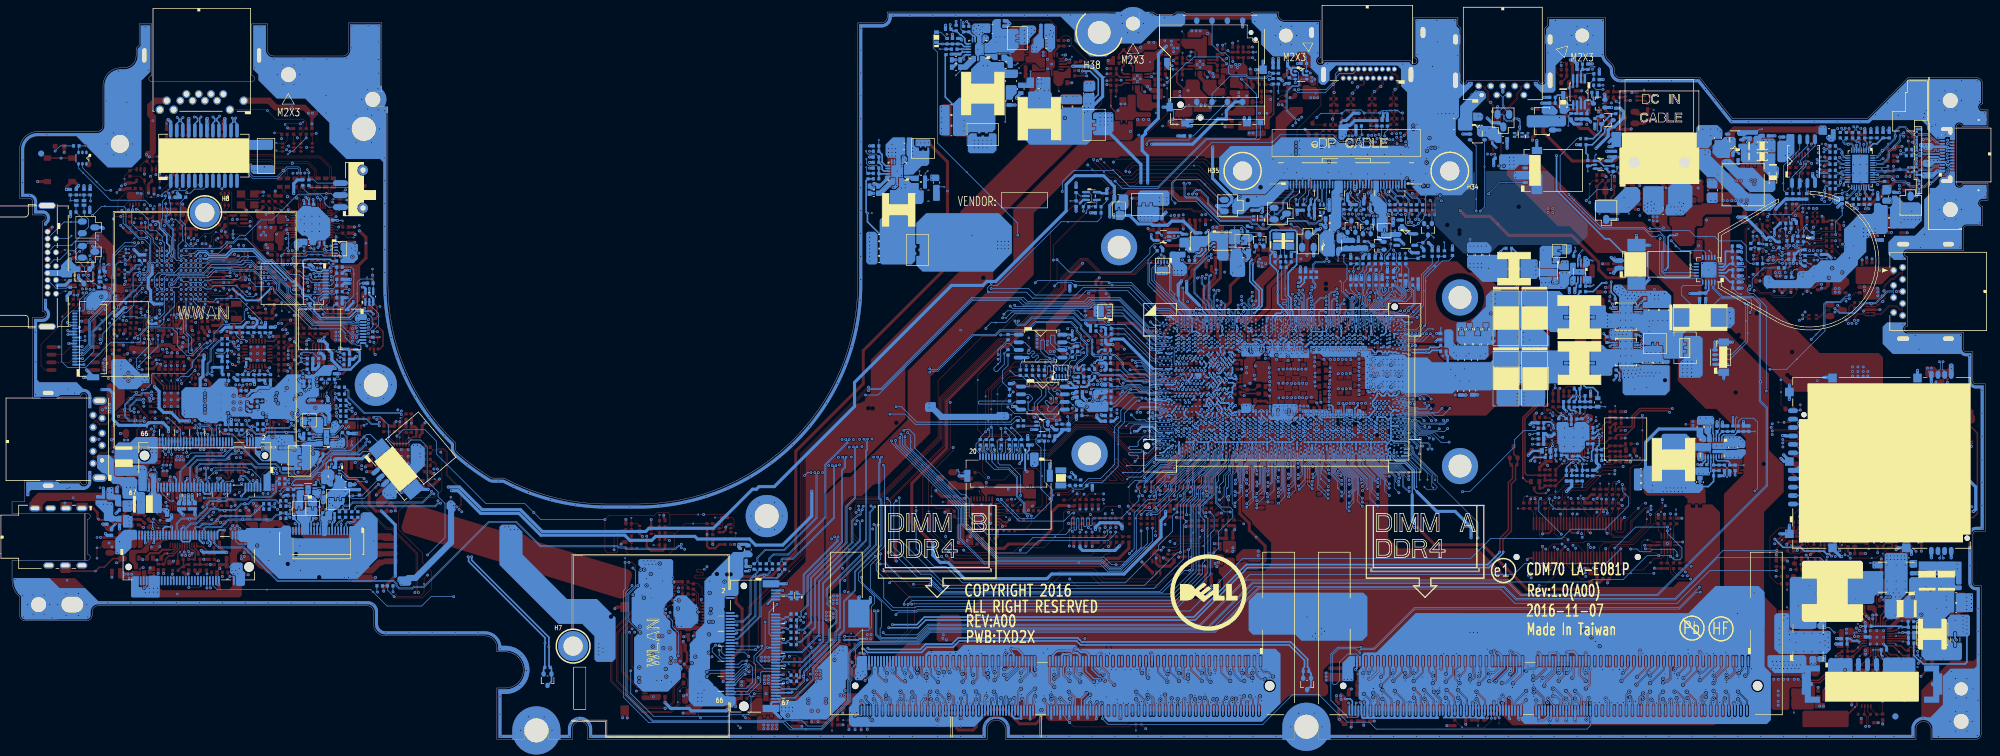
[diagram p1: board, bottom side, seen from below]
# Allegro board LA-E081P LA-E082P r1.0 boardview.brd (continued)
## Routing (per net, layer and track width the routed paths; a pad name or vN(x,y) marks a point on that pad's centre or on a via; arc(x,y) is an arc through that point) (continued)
HOST_SD_WP#: length 6.4
  TOP w0.102: v1(133.61,87.13) 133.61,86.99 133.61,86.98 RC292.1 ; v1(34.37,59.73) v2(34.37,57.68) 34.37,55.63 QR1.2
  BOTTOM w0.102: v1(131.76,60.04) 132.13,59.66 UC1.W10
HP_OUT_L: length 5.3
  TOP w0.127: v2(307.92,40.21) 307.56,39.86 307.56,39.28 307.66,39.18 v1(307.66,38.94)
  TOP w0.203: v1(304.56,36.59) 304.37,36.59 303.7,35.92 UA1.32
  TOP w0.381: v1(306.33,29.86) 306.39,29.86 306.65,30.12 CA43.2 ; RA7.1 307.09,38.44 307.6,38.94 v1(307.66,38.94)
HP_OUT_R: length 2.8
  TOP w0.203: UA1.33 303.39,36.32 v1(303.47,36.4)
  TOP w0.381: v1(306.2,35.2) 306.39,35.2 306.82,35.63 RA8.1 ; v1(303.98,29.8) 304.36,29.8 CA44.2
HSYNC_CONN: length 5.2
  TOP w0.102: JCRT1.13 319.82,78.6 319.78,78.64 v2(319.05,78.64) CV133.1 316.65,78.64 LV19.2 315.63,78.61 RV122.1
HSYNC_CRT: length 2.5
  TOP w0.102: UV6.19 280.56,54.47 v1(280.7,54.61) 281.05,54.61 v2(281.18,54.48) ; v1(316.22,77.11) 316.44,77.11 316.62,77.28 LV19.1
HV_GATE1_A: length 3.3
  TOP w0.076: v2(36.41,79) 36.2,79.22 35.39,79.22 35.32,79.29 34.89,79.29 UT5.B9
  TOP w0.102: v2(36.41,79) 36.5,78.91 36.61,78.91 RT64.1
HV_GATE2_A: length 5.8
  TOP w0.102: UT5.A9 35.22,78.96 35.9,78.96 36.23,78.63 36.52,78.63 36.93,78.22 36.93,77.7 RT65.1 37.83,76.8 v2(39.68,76.8)
HW_GPS_DISABLE#: length 15.8
  TOP w0.102: RE12.1 308.11,66.28 v1(307.71,66.68) ; v1(294.12,44.27) 293.69,44.7 v2(293.43,44.7) 293.43,45.65 DZ6.1
  TOP w0.107: v1(301.6,74.68) UE1.H5
  BOTTOM w0.102: v1(307.71,66.68) 307.31,67.08 307.07,67.08 305.53,68.62 303.48,68.62 302.84,69.26 302.84,70.2 301.1,71.95 301.1,74.18 v1(301.6,74.68)
HW_GPS_DISABLE#_R: length 2.8
  TOP w0.102: DZ6.2 293.27,47.71 v1(293.27,48.12) 293.61,48.46 v2(293.79,48.46)
  BOTTOM w0.102: JNGFF2.18 293.05,48.55 293.27,48.33 v1(293.27,48.12)
I2C1_SCK_TP: length 4.3
  TOP w0.102: RZ21.2 219.44,24.78 217.78,24.78 v1(217.4,25.16) RZ29.1
  BOTTOM w0.076: UC1.U9 132.78,60.68 132.45,61.01 v1(132.45,61.28)
I2C1_SCK_TP_R: length 9.6
  TOP w0.102: v3(218.39,26.89) 218.6,26.69 218.6,25.72 RZ117.2 217.78,25.67 216.08,25.67 215.83,25.42 RZ29.2 215.63,24.96 RZ347.1 214.05,24.1 214.05,22.55 213.65,22.15 JKBTP1.2
I2C1_SDA_TP: length 5.7
  TOP w0.102: RZ26.1 216.65,24.24 216.65,24.55 216.76,24.66 217.28,24.66 v1(217.4,24.53) 217.75,24.53 217.78,24.55 219.54,24.55 RZ20.2
  BOTTOM w0.102: v1(133.11,59.11) 133.11,60.34 UC1.U8
I2C1_SDA_TP_R: length 7.5
  TOP w0.102: RZ116.2 217.78,23.64 216.29,23.64 215.83,24.1 RZ26.2 215.78,24.1 RZ346.1 214.57,24.1 214.37,23.89 214.37,22.38 v2(214.46,22.29) 214.3,22.14 214.15,22.14 213.66,21.65 JKBTP1.3
I_ADP: length 1.3
  TOP w0.102: v1(19.69,9.42) 19.44,9.16 PR935.2
  TOP w0.107: v1(295.96,80.33) UE1.B11
I_BATT: length 1.7
  TOP w0.102: v1(305.48,67.75) RE64.2 ; v1(19.71,8.57) 19.42,8.27 PR947.2
I_BATT_R: length 2.2
  TOP w0.102: RE64.1 304.82,68.87 CE3.1 304.84,69.6 v1(304.86,69.61) ; v1(302.36,73.93) UE1.J4
I_SYS: length 5.8
  TOP w0.102: v1(72.24,53.75) 72.68,54.18 73.43,54.18 73.69,54.45 73.69,55.11 73.17,55.63 PR620.1 ; v1(19.11,10.69) PR936.2 ; v1(310.62,67) 310.2,67.42 RE312.2
  BOTTOM w0.102: v1(72.24,53.75) 72.24,53.79 v2(72.65,54.2)
I_SYS_R: length 4.3
  TOP w0.102: v1(309.64,69.62) 309.64,69.42 309.29,69.07 CE4.1 310.17,68.93 RE312.1 311.1,68.9 RE313.1 311.11,69.52 v2(311.43,69.84)
  TOP w0.107: v1(302.34,74.74) UE1.J5
IA_SNUB:
  vias: v2(65.94,73.14)
IA_SW:
  vias: v1(63.18,70.38) v1(63.17,69.78) v1(63.19,69.19) v1(63.17,68.58) v2(62.65,69.36)
IFDET_SATA_PCIE#: length 21.5
  TOP w0.102: 218.04,34.08 216.27,35.84 v2(214.95,35.84) RN171.2 RN192.1 211.59,35.72 QN4.6 ; 218.04,34.08 218.27,34.31 RN189.1 ; 218.04,34.08 218.04,31.72 219.03,30.73 225.66,30.73 226.14,31.21 RN186.1
ILIM_SEL: length 3.1
  TOP w0.102: UI3.4 307.99,62.25 307.46,62.78 v2(306.77,62.78) 305.97,62.78 RI13.1
ILMT_+1VALWP: length 6
  BOTTOM w0.102: v2(186.25,97.74) 186.25,97.49 185.96,97.2 184.62,97.2 PR307.2
  BOTTOM w0.254: PU301.13 183.32,94.38 183.6,94.66 183.6,95.29 PR310.1 PR307.2
ILMT_DDR: length 5.7
  BOTTOM w0.102: v2(40.52,45.56) PR205.1
  BOTTOM w0.203: PR207.2 42.87,45.99 43.14,46.27 44.91,46.27 45.11,46.47 PU200.17
  BOTTOM w0.254: PR205.1 PR207.2
IMON_IA: length 4.2
  TOP w0.203: v1(64.78,51.34) 65.33,50.78 PU602.14
  BOTTOM w0.102: v1(64.78,51.34) 64.56,51.34 v2(64.31,51.59)
  BOTTOM w0.254: PR629.2 PC625.2 65.21,50.91 v1(64.78,51.34)
IMON_VSA: length 4.4
  TOP w0.102: v2(66.5,46.27) 66.95,46.27 v1(67.06,46.38)
  TOP w0.203: v1(67.06,46.38) 67.76,47.08 PU602.23
  BOTTOM w0.254: PC643.1 68.08,47.05 PR651.1 67.75,47.07 v1(67.06,46.38)
IMVP_VR_ON: length 9.5
  TOP w0.102: RE304.1 306.81,93.54 UE3.4 306.06,92.35 305.8,92.08 305.8,90.29 305.57,90.06 v2(304.92,90.06) 304.08,90.06 v1(303.8,90.34) ; PR616.1 74.45,53.71 v1(74.04,54.12) ; UE4.2 v1(290.66,86.38)
IMVP_VR_ON_EC: length 24.8
  TOP w0.102: UE1.N7 306.51,76.73 v1(306.88,76.36) ; UE3.1 308.25,94.69 RE304.2 309.38,93.57 v2(309.38,93.08) 309.38,92.62 309.88,92.12 v1(309.88,91.92) ; RPE10.2 307.48,89.3 307.6,89.43 308.62,89.43 309.38,88.66 309.38,88.31 v1(309.81,87.88)
  BOTTOM w0.102: v1(309.81,87.88) 309.61,87.67 309.61,85.72 306.97,83.08 306.12,83.08 305.22,82.18 305.22,79.5 305.61,79.1 305.61,77.78 305.83,77.56 306.3,77.56 306.66,77.2 306.66,76.9 306.88,76.68 v1(306.88,76.36)
INT_SPK_L+:
  vias: v1(289.5,30.37) v1(289.99,30.02) v1(300.01,40.59) v1(300.01,40) v2(290,30.54)
INT_SPK_L-:
  vias: v1(289.5,31.01) v1(299.37,40.56) v1(299.34,39.97) v2(299.38,39.46)
INT_SPK_R+:
  vias: v1(288.75,38.07) v1(289.18,38.5) v1(298.15,40.68) v1(298.15,40.1) v2(298.09,39.59)
INT_SPK_R-:
  vias: v1(287.48,38.78) v1(287.94,39.21) v1(298.79,40.68) v1(298.73,40.05) v2(287.01,38.14)
INT_SPKR_L+: length 20.2
  TOP w1.016: 266.77,29.36 267.09,29.36 268.29,28.15 268.42,28.15 268.49,28.09 v3(280.17,28.09) 285.48,28.09 DA6.2
INT_SPKR_L-: length 18.9
  TOP w1.016: 284.55,31.45 283.08,31.45 281.23,29.61 v3(281.21,29.61) 269.12,29.61 267.91,30.82 266.9,30.82
INT_SPKR_R+: length 18.9
  TOP w1.016: 284.55,33.04 281.18,33.04 v3(280.29,32.15) 279.29,31.14 270.06,31.14 269.05,32.15 266.9,32.15
INT_SPKR_R-: length 18.5
  TOP w1.016: 284.74,35.96 283.85,35.96 282.58,34.69 v3(281.18,34.69) 280.1,34.69 279.09,33.67 267.21,33.67
INTRUDER#: length 2.2
  TOP w0.102: v1(136.63,35.73) 136.63,36.12 RC69.1
  BOTTOM w0.076: v1(127.95,51.77) UC1.AP16
IR_CAM_DET#: length 20.1
  TOP w0.102: RC345.1 142.55,68.22 137.98,63.65 137.04,63.65 135.33,65.35 v1(134.36,65.35)
  BOTTOM w0.102: v1(82.9,90.62) 81.03,92.49 v2(80,92.49) JIR1.1 ; v1(134.36,65.35) 134.5,65.35 UC1.H5
ISH_I2C2_SCL: length 5.5
  TOP w0.102: v1(296.2,48.12) 296.55,48.47 RZ76.1 ; RC362.1 147.68,55.03 146,55.03 145.25,54.28 144.71,54.28 v1(144.6,54.17)
  BOTTOM w0.076: v1(131.18,58.08) 130.83,57.73 UC1.AD12
ISH_I2C2_SCL_R: length 2.6
  TOP w0.102: v1(296.64,50.84) 296.64,49.84 RZ76.2
  BOTTOM w0.102: JNGFF2.32 296.55,49.43 296.55,50.76 v1(296.64,50.84)
ISH_I2C2_SDA: length 5.7
  TOP w0.102: RC363.1 147.59,55.27 145.92,55.27 145.16,54.51 144.84,54.51 v1(144.6,54.75) ; v1(296.78,48.12) 296.78,48.18 RZ77.1
  BOTTOM w0.076: v1(131.82,58.08) 131.48,57.74 UC1.AD11
ISH_I2C2_SDA_R: length 4.3
  TOP w0.102: RZ77.2 297.12,50.07 297.12,50.74 v1(297.22,50.84)
  BOTTOM w0.102: JNGFF2.34 297.05,50.35 297.22,50.52 v1(297.22,50.84) 297.22,51.26 297.31,51.35 297.31,51.99 v2(297.59,52.27)
ISH_UART0_CTS#: length 17.9
  TOP w0.102: v1(196.62,19.45) 197.36,18.71 v2(197.36,17.7) 197.36,15.61 196.3,14.54 196.3,11.86 196.68,11.48 196.68,10.91 RZ80.1
  BOTTOM w0.076: 141.53,61.38 139.98,61.38 138.93,60.33 137.65,60.33 137.53,60.45 137.42,60.45 137.2,60.51 137.19,60.51 136.82,60.51 136.7,60.63 135.78,60.63 UC1.U4
  BOTTOM w0.102: 141.53,61.38 v1(142.44,61.38)
ISH_UART0_CTS#_R: length 11.9
  TOP w0.102: v1(205.68,11.22) 205.48,11.42 200.7,11.42 200.61,11.33 199.24,11.33 199.12,11.21 v2(199.1,11.21) RZ80.2
  BOTTOM w0.102: JNGFF1.54 208.26,9.5 206.54,11.22 v1(205.68,11.22)
ISH_UART0_RTS#: length 19.9
  TOP w0.102: v1(196.24,20.88) 196.17,20.8 196.17,18.74 197.03,17.87 197.03,17.54 197.11,17.46 197.11,15.64 196.09,14.62 v2(196.09,11.6) 196.38,11.31 196.38,10.64 196.81,10.21 196.81,9.77 RZ81.1
  BOTTOM w0.076: 138.65,60.94 137.92,60.94 137.63,61.23 136.49,61.23 UC1.U3
  BOTTOM w0.102: v1(142.08,62.97) 140.68,62.97 138.65,60.94
ISH_UART0_RTS#_R: length 12.6
  TOP w0.102: RZ81.2 198.47,9.29 v2(199.12,9.94) 199.46,10.28 199.46,10.8 199.79,11.13 200.69,11.13 200.78,11.22 204.69,11.22 205.08,10.82 v1(206.33,10.82)
  BOTTOM w0.102: JNGFF1.56 208.26,9 206.44,10.82 v1(206.33,10.82)
ISH_UART0_RXD: length 14.7
  TOP w0.102: RZ78.1 196.7,12.92 196.7,14.19 v2(196.99,14.48) 198.09,15.58 198.09,19.52 197.28,20.34 v1(196.59,20.34)
  BOTTOM w0.076: 138.19,60.75 137.7,60.75 137.55,60.9 UC1.U1
  BOTTOM w0.102: v1(141.51,62.58) 140.59,62.58 138.76,60.75 138.19,60.75
ISH_UART0_RXD_R: length 11.9
  TOP w0.102: v1(205.81,12.1) 205.58,11.87 204.48,11.87 200.7,11.87 199.9,12.67 199.27,12.67 v2(199.12,12.51) 198.94,12.34 RZ78.2
  BOTTOM w0.102: v1(205.81,12.1) 205.87,12.04 206.64,12.04 208.19,10.5 JNGFF1.50
ISH_UART0_TXD: length 14.9
  TOP w0.102: RZ79.1 196.5,12.11 196.5,14.45 197.79,15.75 197.79,19.28 v2(197.71,19.36) 197.26,19.82 v1(197.11,19.82)
  BOTTOM w0.076: 138.16,60.56 137.66,60.56 137.6,60.61 137.45,60.61 137.25,60.67 137.22,60.68 137.04,60.68 UC1.U2
  BOTTOM w0.102: v1(141.31,62.02) 140.37,62.02 138.9,60.56 138.16,60.56
ISH_UART0_TXD_R: length 11.6
  TOP w0.102: RZ79.2 198.53,11.65 200,11.65 v2(200.22,11.87) 200.47,11.62 v1(206.14,11.62)
  BOTTOM w0.102: v1(206.14,11.62) 206.54,11.62 208.17,10 JNGFF1.52
ISPSCL: length 4
  TOP w0.102: v1(275.7,59.18) 275.91,58.97 275.91,58.65 276.41,58.15 276.84,58.15 277.2,57.79 277.2,57.63 277.09,57.51 UV6.30
  BOTTOM w0.102: v1(275.7,59.18) 275.89,59.37 275.89,59.6 275.66,59.82 RV106.1
ISPSDA: length 4.1
  TOP w0.102: v1(276.29,59.18) 276.14,59.04 276.14,58.74 276.5,58.38 v4(276.73,58.38) 276.94,58.38 277.43,57.89 277.43,57.56 277.49,57.5 UV6.29
  BOTTOM w0.102: RV107.1 276.33,59.82 276.12,59.61 276.12,59.35 v1(276.29,59.18)
ISUMN_GT: length 13.9
  TOP w0.102: v1(67.8,56.94) 68.08,56.94 v2(68.27,57.13)
  TOP w0.254: v1(67.8,56.94) PR632.1 66.88,56.08 PR638.1
  BOTTOM w0.254: PC641.1 66.88,57.07 PC626.2 ; PC624.2 PC626.2 ; PC626.2 PR633.2 67.77,56.91 v1(67.8,56.94) 67.77,56.97 67.77,58.21 PH602.2 67.57,58.41 67.57,62.25 67.82,62.5 PL612.2
ISUMN_IA: length 11.8
  TOP w0.102: v2(59.11,46.78) 59.11,46.91 v1(59.42,47.22)
  TOP w0.203: PR644.2 61.03,47 PR640.2 ; PR644.2 61.03,47 PC645.1 59.64,47 v1(59.42,47.22) ; PR644.2 61.04,47.01 PR656.2 PC646.2 PC642.2
  BOTTOM w0.254: PH605.2 67.85,74.24 67.85,74.06 68.27,73.64 v1(68.27,72.63) 68.27,70.38 68.52,70.12 PL610.2
ISUMN_R_GT: length 3.8
  TOP w0.203: PC627.2 66,55.16 PR638.2 66.88,54.32 v2(67.14,54.06) 67.76,53.44 PU602.8
ISUMN_R_IA: length 4.9
  TOP w0.203: PU602.20 65.54,48.38 v2(64.95,47.79) 64.15,47 PR640.1 62.8,46.13 PC630.1
ISUMN_R_VSA: length 5.1
  TOP w0.203: PU602.28 69.76,46.02 69.96,45.81 v2(70.69,45.81) 70.75,45.81 PC632.1
  TOP w0.254: PR636.1 PC632.1
ISUMP_GT: length 7.9
  TOP w0.254: v1(67.73,54.21) 68.16,53.78 PU602.7
  BOTTOM w0.102: v2(63.53,55.26) PR674.1
  BOTTOM w0.254: PR633.1 67.73,55.14 v1(67.73,54.21) ; PR633.1 68.69,55.18 PR628.1 ; PR633.1 PC626.1 PC624.1 64.86,55.18 PR674.1
ISUMP_IA: length 7.7
  TOP w0.203: PR661.2 60.1,49.02 PR657.1 60.51,48.76 PR656.1 PC646.1 PC642.1 63.2,48.35 v2(63.77,48.35) 64.3,48.35 64.74,48.78 PU602.19
ISUMP_VSA: length 11.4
  TOP w0.102: v2(71.81,41.15) PC633.1
  TOP w0.203: PC633.1 69.36,44.58 PU602.27
  TOP w0.254: PC633.1 PR643.2 PC637.1 73.64,42.02 73.64,42.01 73.89,41.76 PR642.1 74.41,42.09 74.48,42.15 PR624.2
ITP_PMODE: length 36.5
  TOP w0.102: v1(56.04,37.36) 56.04,35.93 59.31,32.66 63.76,32.66 64.45,31.96 JXDP1.46 ; v1(133.69,74.97) 133.53,75.13 132.9,75.13 131.7,76.32 131.7,77.87 129.77,79.8 129.77,82.8 130.82,83.84 RC115.1
  BOTTOM w0.076: 132.28,71.24 132.28,70.33 131.8,69.84 131.8,69.23 131.99,69.04 132.31,69.04 132.5,68.85 132.5,67.51 132.98,67.04 UC1.E8
  BOTTOM w0.102: 132.28,71.24 133.61,72.56 v2(133.61,73.04) 133.61,74.82 133.69,74.9 v1(133.69,74.97)
JCRT-11: length 2.8
  BOTTOM w0.102: T87.1 318.66,83.18 JCRT1.11
JDIMM1_EVENT#: length 3.5
  TOP w0.102: v1(72.78,3.19) v2(72.78,2.66)
  TOP w0.381: v1(72.78,3.19) 73.03,3.45 RD14.1
  BOTTOM w0.254: v1(72.78,3.19) 72.53,3.44 JDIMM1.134
JDIMM2_EVENT#: length 14.9
  TOP w0.102: v2(141.46,1.49) RD27.1 142.07,2.49 142.47,2.09 151.74,2.09 v1(152.45,2.8)
  BOTTOM w0.102: v1(152.45,2.8) 153.11,3.46 153.11,3.65 153.53,4.06 JDIMM2.134
JTAG_CLK: length 18
  TOP w0.102: v1(296.78,77.9) UE1.C8
  BOTTOM w0.102: RPE7.3 274.04,81.24 273.7,80.9 273.7,80.56 274.01,80.26 274.82,80.26 274.86,80.29 276.33,80.29 276.53,80.5 278.96,80.5 279.21,80.26 281.27,80.26 281.49,80.04 v3(281.49,79.86) 281.49,79.33 281.23,79.08 281.23,78.46 280.56,77.79 280.25,77.79 279.41,76.95 278.85,76.95 v1(278.56,77.24) 278.31,77 278.31,76.62 278.08,76.4 JDEG1.4
JTAG_RST#: length 8.8
  TOP w0.102: v2(301.27,85.95) 300.87,86.35 RE63.1 JTAG1.1 300,86.86 300,86.16 RE65.1 300.65,85.51 300.65,84.5 CE30.1 300.09,83.57 300.36,83.3 UE1.G13
JTAG_TDI: length 4.8
  TOP w0.112: v1(298.33,78.73) 298.36,78.73 UE1.E9
  BOTTOM w0.102: JDEG1.2 277.93,77.4 v1(277.93,77.39) ; v3(274.27,83.51) RPE7.1 274.59,82.24 274.82,82.01 275.06,82.01 v1(275.13,81.94)
JTAG_TDO: length 20.2
  TOP w0.107: v1(299.17,75.53) UE1.F6
  BOTTOM w0.102: JDEG1.5 276,75.91 278.29,75.91 278.85,76.47 v1(279,76.47) 279.61,76.47 280.34,77.21 281.89,77.21 283.38,78.7 v3(283.38,80.32) 282.96,80.74 279.4,80.74 279.16,80.98 276.33,80.98 276.15,80.8 274.68,80.8 274.62,80.74 RPE7.4
JTAG_TMS: length 4.2
  TOP w0.102: v1(296.76,74.7) 297.16,75.1 UE1.C5
  BOTTOM w0.102: v1(277.7,76.81) 277.62,76.9 JDEG1.3 ; RPE7.2 274.63,81.74 v1(275.06,81.31) 275.15,81.22 v3(275.9,81.22)
KB_DET#: length 35
  TOP w0.102: v3(145.42,75.46) 145.8,75.84 v1(145.9,75.84) RC288.1 ; CZ84.1 213.62,13.15 JKBTP1.20 212.43,13.15 v1(211.84,13.73)
  BOTTOM w0.076: UC1.D8 134.09,68.09 134.32,68.32 134.32,70.07 134.63,70.38
  BOTTOM w0.102: v1(158.18,75.84) 157.77,76.24 151.77,76.24 151.59,76.07 146.13,76.07 v1(145.9,75.84) 142.19,75.84 137.95,71.6 135.85,71.6 134.63,70.38
LAN_ACTLED_YEL#: length 5.5
  TOP w0.102: RL14.1 v1(279.21,99.9) ; QL1.6 v1(281.91,97.67)
  BOTTOM w0.102: v1(279.21,99.9) 281.45,97.67 v1(281.91,97.67) 281.91,97.51 v2(282.25,97.17)
LAN_ACTLED_YEL_R#: length 14.6
  TOP w0.102: JLOM1.10 285.8,104.58 v3(285.65,104.43) 284.22,103 279.71,103 279.21,102.51 RL14.2
LAN_DISABLE#_R: length 6.6
  TOP w0.102: RL5.1 RL9.1 RL7.2 282.21,81.09 v1(282.15,81.15) ; v1(282.3,84.04) 282.13,84.22 UL1.3
  BOTTOM w0.102: v1(282.15,81.15) 282.15,82.41 v2(282.15,82.42) 282.15,82.42 282.15,83.89 v1(282.3,84.04)
LAN_MDIN0: length 5.3
  TOP w0.089: UL1.14 280.06,89.3 280.11,89.35 280.11,89.63 280.42,89.93 v4(280.79,89.93) 281.69,89.93 282.83,91.08 282.83,91.27 RL72.1
LAN_MDIN0_L: length 13.3
  TOP w0.089: RL72.2 282.33,94.46 282.93,95.06 285.1,95.06 285.42,95.38 v4(288.42,95.38) 291.08,95.38 291.37,95.09 291.37,94.78 v1(291.49,94.67)
  BOTTOM w0.089: TL1.11 291.71,93.86 291.43,94.13 291.43,94.61 v1(291.49,94.67)
LAN_MDIN1: length 4.8
  TOP w0.089: RL74.1 280.26,91.3 280.26,91.04 280.17,90.95 279.02,90.95 278.51,90.44 278.51,89.35 278.46,89.3 UL1.18
LAN_MDIN1_L: length 24.4
  TOP w0.089: v1(280.12,94.04) 280.21,93.95 280.21,93.6 RL74.2
  BOTTOM w0.089: v1(280.12,94.04) 280.12,94.73 280.48,95.09 282.44,95.09 v4(283.02,94.51) 284.04,93.49 288.04,93.49 288.56,94.01 288.56,95.15 289.14,95.73 297.18,95.73 297.71,95.21 TL1.5
LAN_MDIN2: length 3.6
  TOP w0.089: UL1.21 277.26,89.3 277.31,89.35 v4(277.31,89.97) 277.31,90.7 277.75,91.14 277.75,91.27 RL76.1
LAN_MDIN2_L: length 22.6
  TOP w0.089: v1(294.48,94.72) 294.48,95.79 293.98,96.28 285.06,96.28 284.75,95.98 278.88,95.98 277.57,94.67 277.57,93.49 RL76.2
  BOTTOM w0.089: TL1.8 294.71,93.97 294.44,94.24 294.44,94.68 v1(294.48,94.72)
LAN_MDIN3: length 3.8
  TOP w0.089: UL1.24 276.06,89.3 276.11,89.35 276.11,89.78 v4(275.96,89.94) 275.17,90.73 275.17,91.31 RL78.1
LAN_MDIN3_L: length 32.1
  TOP w0.089: RL78.2 275.04,93.5 275.04,95.11 276.82,96.89 284.35,96.89 284.64,97.18 v4(296.89,97.18) 299.07,97.18 300.52,95.74 v1(300.52,94.67)
  BOTTOM w0.089: TL1.2 300.71,93.99 300.44,94.25 300.44,94.59 v1(300.52,94.67)
LAN_MDIP0: length 5.3
  TOP w0.089: UL1.13 280.46,89.3 280.41,89.35 280.41,89.5 280.55,89.63 281.82,89.63 v4(282.32,90.14) 283.13,90.95 283.13,91.31 RL71.1
LAN_MDIP0_L: length 13.3
  TOP w0.089: RL71.2 283.17,93.17 282.95,93.4 282.95,93.57 282.63,93.89 282.63,94.33 283.05,94.76 285.23,94.76 285.55,95.08 v4(286.16,95.08) 290.95,95.08 291.07,94.96 291.07,94.84 v1(290.9,94.67)
  BOTTOM w0.089: v1(290.9,94.67) 290.94,94.67 291.13,94.47 291.13,94.25 291.04,94.16 290.78,94.16 290.71,94.09 TL1.12
LAN_MDIP1: length 4.8
  TOP w0.089: UL1.17 278.86,89.3 278.81,89.35 v4(278.81,89.78) 278.81,90.31 279.15,90.65 280.3,90.65 280.56,90.91 280.56,91.28 RL73.1
LAN_MDIP1_L: length 24.4
  TOP w0.089: v1(280.71,94.04) 280.51,93.85 280.51,93.36 280.7,93.17 RL73.2
  BOTTOM w0.089: v1(280.71,94.04) 280.42,94.33 280.42,94.61 280.6,94.79 282.32,94.79 283.92,93.19 288.17,93.19 288.86,93.89 288.86,95.03 289.27,95.43 297.06,95.43 297.41,95.09 297.41,94.49 297.3,94.39 296.79,94.39 296.71,94.3 TL1.6
LAN_MDIP2: length 3.6
  TOP w0.089: RL75.1 278.05,91.31 278.05,91.02 277.61,90.58 277.61,89.35 277.66,89.3 UL1.20
LAN_MDIP2_L: length 22.5
  TOP w0.089: RL75.2 277.97,93.17 277.87,93.28 277.87,94.55 279,95.68 v4(281.51,95.68) 284.88,95.68 285.18,95.98 293.86,95.98 294.18,95.67 294.18,95.07 294.09,94.98 293.94,94.98 293.89,94.93 v1(293.89,94.72)
  BOTTOM w0.089: TL1.9 293.71,94.21 293.78,94.28 294.05,94.28 294.14,94.36 294.14,94.48 v1(293.89,94.72)
LAN_MDIP3: length 3.8
  TOP w0.089: RL77.1 275.47,91.27 275.47,90.85 275.79,90.53 275.98,90.34 276.41,89.91 276.41,89.35 276.46,89.3 UL1.23
LAN_MDIP3_L: length 32.1
  TOP w0.089: v1(299.93,94.67) 299.93,94.94 299.98,94.99 300.13,94.99 300.22,95.08 300.22,95.61 298.95,96.88 284.76,96.88 284.47,96.59 276.94,96.59 275.34,94.98 275.34,93.28 275.45,93.17 RL77.2
  BOTTOM w0.089: TL1.3 299.71,94.17 299.79,94.26 300.05,94.26 300.14,94.34 300.14,94.53 300,94.67 v1(299.93,94.67)
LAN_TEST_EN: length 3.4
  TOP w0.102: v2(273.13,86.1) RL12.1
  TOP w0.112: RL12.1 273.71,85.68 274.59,85.68 274.73,85.82 UL1.30
LAN_WAKE#: length 52.9
  TOP w0.102: v1(144.81,34.45) 144.41,34.45 RC323.1 RL70.1
  TOP w0.107: v1(303.96,73.13) UE1.L3
  TOP w0.112: UL1.2 281.95,83.82 v1(282.57,83.19)
  BOTTOM w0.076: v1(129.86,53.14) 129.5,53.46 UC1.AM15
  BOTTOM w0.102: v1(144.81,34.45) 144.81,34.24 146.02,33.04 157.56,33.04 159.64,30.96 164.67,30.96 169.68,35.96 169.68,39.16 178.84,48.32 v2(178.84,49.47) 178.84,50.45 v1(179.37,50.98)
LCD_CBL_DET#: length 14.5
  BOTTOM w0.076: 143.95,58.64 143.74,58.44 143.1,58.44 142.82,58.72 140.89,58.72 140.37,58.2 138.96,58.2 138.57,57.82 137.33,57.82 137.24,57.85 137.18,57.85 136.59,57.9 136.4,57.9 136,57.68 UC1.AC3
  BOTTOM w0.102: v1(96.48,93.16) 96.8,92.83 JEDP1.40 ; v1(147.83,58.91) 147.83,58.99 147.37,59.45 147.07,59.45 146.94,59.33 145.93,59.33 145.6,59 RC287.1 145.36,58.64 v2(144.43,58.64) 143.95,58.64
LCD_TST: length 4.7
  TOP w0.102: UE1.D1 297.96,71.56 297.76,71.35 297.76,69.99 RE20.1 298.07,69.26 v1(297.57,69.26)
  BOTTOM w0.102: JEDP1.29 102.3,91.13 v1(102.42,91)
LCD_VCC_TEST_EN: length 5.9
  TOP w0.102: v1(298.33,70.2) 298.33,71.49 UE1.E1
  BOTTOM w0.102: v1(92.61,89.53) 92.32,89.23 v2(92.32,87.95) DV3.2
LED_10_GRN#: length 3.8
  TOP w0.102: v2(279.73,102.51) 279.74,102.5 279.74,100.96 RL19.1 280.17,99.52 280.1,99.46 QL2.6
LED_10_GRN_R#: length 3.4
  TOP w0.102: v3(282.71,102.13) 282.58,102.25 v1(280.17,102.25) RL19.2
LED_100_ORG#: length 3.1
  TOP w0.102: v2(284.17,99.08) 284.06,98.97 QL1.3 282.82,98.97 282.38,99.41 RL20.1
LED_100_ORG_R#: length 2
  TOP w0.102: v1(283.29,99.77) RL20.2 283.29,100.55 283.47,100.73 v3(284.49,100.73)
LG1_ISL88738: length 0.7
  BOTTOM w0.127: v1(18.86,29.29) v2(19.6,29.29)
  vias: v1(18.86,28.66) v1(20.39,19.45) v1(20.83,19.92)
LG2_ISL88738: length 2
  BOTTOM w0.127: v1(27.08,18.58) 26.34,18.58 v2(25.47,17.71)
  vias: v1(21.34,18.12) v1(21.85,18.5) v1(27.08,19.21)
LID_CL#: length 19.5
  TOP w0.102: v1(285.76,52.98) 286.4,52.33 JLED1.5 286.4,50.73 286.09,50.41 285.69,50.41 283.51,48.23 283.51,47.25 282.96,46.7 281.53,46.7 280.33,47.9 277.82,47.9 277.72,48 277.72,48.49 277.95,48.71 278.28,48.71 278.46,48.53 279.06,48.53 279.28,48.75 UZ10.2 ; v3(311.23,86.45) 310.82,86.86 v1(309.99,86.86) RE26.1
LID_CL#_PCH: length 12.9
  BOTTOM w0.076: UC1.AW7 133.71,48.85 134.03,48.54 134.03,47.13 134.9,46.26 135.23,46.26
  BOTTOM w0.102: T268.1 141.58,43.05 139.95,43.05 137.36,45.63 136.19,45.63 135.56,46.26 135.23,46.26
LID_CL_NB#: length 8.4
  TOP w0.102: UE1.N11 305.7,79.93 308.26,82.49 308.26,82.7 v2(307.73,83.22) 307.46,83.5 CE8.1 307.85,84.54 307.87,84.54 RE25.2 308.52,85.19 RE26.2
LINE1_L: length 6
  TOP w0.203: 301.96,31.52 301.34,31.52 301,31.86 UA1.22
  TOP w0.381: 301.96,31.52 303.09,31.52 303.66,30.94 305.12,30.94 305.63,30.43 CA43.1
LINE1_R: length 4
  TOP w0.203: v2(302.28,30.88) 301.51,30.88 300.6,31.8 UA1.21
  TOP w0.381: CA44.1 303.28,30.29 302.68,30.88 v2(302.28,30.88)
LM393_P: length 10.4
  TOP w0.254: v1(30.18,30.62) 29.86,30.3 v2(29.86,30.17) 29.86,29.88 27.97,27.98 PU903.5 27.97,27.22 27.75,27.01 PC949.2 27.79,26.46 PR950.2
  BOTTOM w0.254: PC1201.2 65.76,106.84 v1(65.64,106.71) 65.5,106.58 PD1801.1 66.13,106.23 66.63,106.23 66.92,105.94 PU1201.8
LOM_ACTLED_YEL#: length 4.8
  TOP w0.102: UL1.26 274.54,87.42 274.25,87.71 274.25,88.68 v1(274.81,89.24) ; v1(282.46,97.95) 282.74,97.67 QL1.1 284.03,97.67 v2(284.17,97.81)
LOM_CABLE_DETECT#: length 6.5
  TOP w0.102: UL2.4 272.09,90.33 272.23,90.47 272.23,90.81 272.03,91.01 v1(271.72,91.01) v2(270.91,91.01) 270.9,91.02 RE505.1
  TOP w0.107: UE1.D2 297.58,72.34 297.58,71.58 297.42,71.42 297.42,70.27 v1(297.34,70.19)
LOM_SPD10LED_GRN#: length 7
  TOP w0.102: QL2.1 278.2,100.03 278.26,100.09 RL30.2 278.14,100.65 v1(277.55,100.65) ; UL1.25 275.29,89.42 274.97,89.74 v2(274.68,89.74) 273.68,89.74 UL2.2 273.18,89.68 273.09,89.59 v1(272.46,89.59)
LOM_SPD100LED_ORG#: length 8
  TOP w0.102: QL1.4 281.25,99.52 281.31,99.59 RL29.2 281.23,100.53 280.68,99.97 v1(280.68,99.9) ; v1(271.48,89.69) 271.81,89.69 272.46,89.03 UL2.1 273.62,88.04 v2(273.74,87.93) 274.53,87.14 275.17,87.14 UL1.27
LPM_1.0V_PRIM_COREP: length 2.4
  TOP w0.254: PU402.14 128.33,112.34 PR426.2 127.95,111.06 PR410.2
LPM_1VS_VCCIO: length 2.5
  TOP w0.254: PU401.14 138.96,109.99 v1(138.87,110.08) 138.8,110.08 PR425.2 138.32,108.68 PR404.2
LPS_PROTECT#: length 1.7
  TOP w0.102: PT1.1 71.61,111.31 71.61,110.77 71.1,110.26 PR1248.2
LPSS_UART2_RXD: length 22.8
  BOTTOM w0.102: JUART1.3 42.59,63.89 40.21,66.27 v2(40.21,69.5) 40.21,72.26 v1(40.35,72.39) ; UC1.AD1 137.46,56.95 137.72,57.2 139.35,57.2 139.7,57.56 142.59,57.56 v1(142.62,57.59) 144.97,55.24 145.17,55.24 RC330.1 RC402.1
LPSS_UART2_TXD: length 24.3
  BOTTOM w0.102: UC1.AD2 136.84,56.92 137.23,57.31 137.55,57.31 137.64,57.39 139.25,57.39 139.65,57.79 141.01,57.79 141.34,58.12 v1(142.32,58.12) 142.74,58.12 145.03,55.83 RC331.1 RC403.1 ; JUART1.2 42.86,63.09 39.88,66.07 v2(39.88,67.51) 39.88,72.27 v1(39.76,72.39)
LX1_ISL88738:
  vias: v1(12.13,29.55) v1(12.77,29.55) v1(19.75,20.08) v1(20.2,20.47) v2(20.69,20.83)
LX2_ISL88738:
  vias: v1(23.5,18.31) v1(23.5,17.67) v1(27.19,13.79) v1(27.19,13.16) v2(21.81,17.8)
LX_1.8VALW: length 1.5
  TOP w0.102: v2(127.13,103.78) 126.83,104.08 PR502.1
LX_1V_PRIM: length 1.1
  TOP w0.102: 128.25,107.18 v2(128.25,106.06)
LX_1VS_VCCIO: length 1.3
  TOP w0.102: PR405.1 v2(138.14,104.05)
LX_3V:
  vias: v1(155.95,107.84) v1(156.26,104.54) v1(156.65,107.73) v1(156.86,114.14) v1(156.86,113.56) v1(156.98,104.54) v1(157.15,109.55) v1(157.15,108.89) v1(157.28,108.08) v1(157.7,104.55) v1(157.76,109.56) v1(157.76,108.9) v1(157.86,107.71) v1(158.39,104.54) v2(157.46,106.42)
LX_5V: length 1.6
  BOTTOM w0.102: PR112.1 v2(160.61,110.66)
  vias: v1(166.1,111.88) v1(166.12,116.25) v1(166.4,116.78) v1(166.78,111.88)
M2280_DEVSLP: length 10.3
  TOP w0.102: v1(298.7,25.24) 297.01,25.24 v2(296.73,25.52) 294.91,27.34 RN37.2
  BOTTOM w0.102: JNGFF3.38 v1(298.7,25.24) ; v1(134.83,62.31) 135.11,62.59 135.11,64.99 135.32,65.2 135.7,65.2 136.02,64.88 UC1.J3
M2280_PCIE_SATA#: length 117.8
  TOP w0.102: UN4.20 v1(264.15,50.39) ; 218.83,37.36 218.83,35.76 219.26,35.32 RN187.1 ; 218.83,37.36 219.18,37.71 220.91,37.71 221.39,37.23 228.91,37.23 v1(229.62,36.52) 229.62,31.43 229.18,30.99 227.77,30.99 227.56,31.2 227.56,33.38 227.15,33.8 RN184.1 ; 218.83,37.36 v2(214.13,37.36) v1(213.24,37.36) 209.8,37.36 RN182.1 208.54,36.85 208.18,36.49 208.18,35.43 208.54,35.07 QN4.2 ; UN5.20 284.55,56.71 284.36,56.9 v1(284.29,56.9)
  BOTTOM w0.076: UC1.G4 135.81,65.9 136.41,65.9 arc(136.61,65.91) 136.81,65.93 arc(136.88,65.94) 136.95,65.96 arc(137.04,65.97) 137.13,65.98 arc(137.17,65.97) 137.2,65.97 arc(137.3,65.95) 137.4,65.95 137.81,65.95 138.13,66.27
  BOTTOM w0.102: v1(229.62,36.52) 240.26,36.52 v1(241.42,37.68) 242.96,39.21 249.41,39.21 257.56,47.36 257.56,49.49 259.49,51.43 263.12,51.43 v1(264.15,50.39) ; 138.13,66.27 143.69,71.82 RPC4.4 146.18,71.82 146.28,71.92 146.28,72.14 146.64,72.5 148.7,72.5 149.28,71.93 161.41,71.93 v1(161.59,72.11) ; JNGFF3.69 290.95,32.97 290.44,32.45 289.3,32.45 v1(289.3,32.46)
M3042_DEVSLP: length 34.9
  BOTTOM w0.102: v1(296.07,50.97) 296.05,50.95 JNGFF2.30 ; UC1.J2 136.82,64.88 137.15,64.55 137.65,64.55 137.74,64.63 139.04,64.63 143.34,68.93 146.23,68.93 146.87,69.56 150.56,69.56 151.7,70.7 161.61,70.7 163.07,69.23 v2(164.75,69.23) 165.49,69.23 165.99,68.73 166.37,68.34 v1(166.37,68.24)
M3042_PCIE#_SATA: length 36.4
  TOP w0.102: QZ8.2 293.31,66.37 292.14,65.21 292.14,64.32 291.83,64 v1(291.17,64)
  TOP w0.107: UE1.J12 v1(302.36,81.13)
  BOTTOM w0.102: UC1.H3 136.14,65.24 138.12,65.24 138.45,65.56 138.74,65.56 143.49,70.32 RPC4.1 146.53,69.78 150.48,69.78 151.68,70.99 162.04,70.99 v2(163.01,70.02) v1(163.58,70.02)
M3042_PCIE_SATA#: length 6.3
  TOP w0.102: UZ36.20 288.05,66.35 288.45,66.75 289.13,66.75 289.57,66.31 290.07,66.31 290.47,66.71 RZ360.2 ; QZ8.1 291.6,67.02 RZ360.2 ; RZ360.2 291.28,67.59 v2(291.22,67.66)
M_ID2#: length 5.3
  BOTTOM w0.102: v2(317.44,75.09) CV135.1 318.87,75.09 319.02,74.94 320.78,74.94 JCRT1.4
MASK_BASE_LEDS#: length 7.6
  TOP w0.102: v1(278.07,47.49) 278.34,47.49 UZ10.4
  BOTTOM w0.102: v1(311.66,91.2) 312.6,91.2 v2(314.03,92.63) 316.36,94.96 QZ7.5
ME_FW_EC: length 45.7
  TOP w0.102: v1(271.79,91.69) v3(271.79,92.25)
  TOP w0.107: v1(299.96,81.13) UE1.G12
  BOTTOM w0.102: RC221.1 278.44,91.69 v1(271.79,91.69) 271.72,91.69 270.94,90.91 270.94,89.07 271.61,88.39 SW1.1 275.5,88.39 276.23,89.13 276.23,89.86 276.81,90.44 280.68,90.44 284.83,86.28 286.71,86.28 289.35,83.65 290.3,83.65 291.32,82.63 292.36,82.63 293.46,81.53 299.56,81.53 v1(299.96,81.13)
ME_FWP: length 101.1
  TOP w0.102: v3(279.02,94.63) 278.77,94.38 v1(278.77,94.13) ; v1(129.18,37.75) RC223.1
  BOTTOM w0.102: v1(278.77,94.13) RC221.2 277.93,92.93 277.4,92.39 SW1.3 ; v1(183.41,45.56) 183.16,45.31 183.16,32.12 184.33,30.95 184.33,30.13 185.5,28.96 185.5,24.99 181.9,21.38 177.94,21.38 177.77,21.56 134.95,21.56 129.04,27.47 129.04,34.27 128.48,34.82 128.48,37.05 v1(129.18,37.75)
ME_RESET#: length 4.2
  BOTTOM w0.102: UC12.2 150.69,90.25 151.25,90.81 RC225.1 RC227.1 v2(152.34,89.44)
ME_SUS_PWR_ACK: length 34.7
  TOP w0.102: v1(170.06,31.44) 169.91,31.44 169.55,31.08 161.8,31.08 161.05,31.84 156.73,31.84 v2(154.87,33.7) 153.5,35.07 153.5,37.57 152.85,38.22 151.42,38.22 151,37.79 147.41,37.79 146.48,38.73 v1(144.21,38.73) 143.77,38.29 RC74.1 ; v1(295.85,82.31) 296.36,81.8 UE1.B13
  BOTTOM w0.102: v1(130.62,51.14) 130.59,51.14 UC1.AR13
MEC_XTAL1: length 6.2
  TOP w0.102: UE1.A1 294.63,71.93 294.29,71.59 v2(294.18,71.59) 293.06,71.59 CE28.1 291.16,71.16 290.79,70.79 YE1.1
MEC_XTAL2: length 2.8
  TOP w0.102: YE1.2 291.32,71.82 291.99,71.82 CE29.1 292.37,72.2 RE290.2
MEC_XTAL2_R: length 2.5
  TOP w0.102: UE1.A3 295.15,73.12 v2(294.19,73.12) RE290.1
MEDIACARD_IRQ#: length 3.6
  TOP w0.102: v2(28.73,46.14) RR19.1 v1(27.74,46.88) 27.19,47.44 UR1.32
  BOTTOM w0.102: v1(133.45,52.61) 133.44,52.61 133.25,52.8 UC1.AN8
MEM_INTERLEAVED: length 14
  BOTTOM w0.102: UC1.P2 136.93,62.23 137.25,62.54 137.58,62.54 137.89,62.85 138.83,62.85 v2(142.51,66.53) 143.31,67.33 RC371.1 146.08,66.82 147.07,66.82 RC372.1
MEM_SMBCLK: length 21.2
  TOP w0.102: v1(134.33,61.29) 135,60.62 135.85,60.62 136.66,61.43 138.8,61.43 141,63.62 143.04,63.62 143.31,63.35 146.23,63.35 146.49,63.62 148.2,63.62 v4(148.58,63.99) 149.25,64.67 149.25,64.81 149.15,64.91 148.67,64.91 RC12.1 CC320.1 149.19,65.6 QC2.6
  BOTTOM w0.076: UC1.R7 134.09,61.54 v1(134.33,61.29)
MEM_SMBDATA: length 26.5
  TOP w0.102: QC2.3 152.23,67.17 152.85,67.17 153.01,67.01 RC14.1 153.34,67.37 153.24,67.47 151.41,67.47 150.63,66.69 150.63,65.49 150.05,64.91 149.58,64.91 149.48,64.81 149.48,64.57 148.3,63.39 v4(147.34,63.39) 146.59,63.39 146.32,63.12 143.21,63.12 142.95,63.39 141.09,63.39 138.9,61.2 136.75,61.2 135.95,60.39 134.9,60.39 134.4,60.89 134.13,60.89 133.78,61.25 v1(133.78,61.32)
  BOTTOM w0.076: UC1.R8 133.44,61.67 v1(133.78,61.32)
MPHYP_PWR_EN: length 1.8
  TOP w0.102: v2(132.89,52.91) 132.57,53.23 v1(132.52,53.23) ; RC387.1 v1(149.74,34.44)
  BOTTOM w0.102: v1(132.52,53.23) 132.52,53.23 132.3,53.45 UC1.AM10
MSCLK: length 7.9
  TOP w0.102: v1(301.56,79.53) 301.56,79.52 UE1.H10
  BOTTOM w0.102: JDEG1.6 275.11,75.4 274.63,75.88 274.63,76.94 RE72.2 RE30.1 274.27,78.57 274.9,78.57 v2(275.46,79.12) 275.59,78.99 v1(276.83,78.99)
MSDATA: length 30.5
  TOP w0.112: v1(299.96,78.73) UE1.G9
  BOTTOM w0.102: v1(279.09,73.09) 279.58,73.09 280.42,73.93 281.37,73.93 281.84,74.4 281.84,75 285.62,78.78 286.13,78.78 287.56,80.21 v3(288.9,80.21) 289.89,80.21 290.48,79.62 295.35,79.62 295.86,79.11 299.64,79.11 299.96,78.79 v1(299.96,78.73) ; RE86.1 RE75.2 274.64,74.9 JDEG1.7 276.41,74.9 276.99,74.31 v1(277.78,74.31)
MUX1_DP_SEL: length 4.4
  TOP w0.102: RT89.1 v1(25.28,82.82) 25.28,82.19 v2(24.9,81.81)
  BOTTOM w0.102: v1(23.41,89.9) 23.23,90.07 22.97,90.07 21.91,91.14 21.91,91.35 21.81,91.44 UT9.23
MUX1_DPEQ0: length 5.1
  TOP w0.102: RT306.1 RT140.1 RT139.1 24.75,95.52 24.56,95.33 v1(24.56,94.96) v2(24,94.96)
  BOTTOM w0.102: UT9.14 v1(24.56,94.96)
MUX1_DPEQ1: length 4.3
  BOTTOM w0.102: RT247.1 RT303.1 RT248.1 20.45,99.52 20.09,99.16 v2(20.09,98.95) 20.09,98.62 20.21,98.49 UT9.2
MUX1_FLIP_SEL: length 18.5
  TOP w0.102: v2(24.2,91.23) v1(24.2,90.67) RT375.1 ; v1(36.58,86.84) 36.62,86.8 RT69.2
  BOTTOM w0.102: v1(36.58,86.84) 36.23,87.19 32.66,87.19 30.99,88.85 26.23,88.85 25.79,89.3 25.79,90.19 25.3,90.67 v1(24.2,90.67) 23.94,90.93 23.39,90.93 UT9.21
MUX1_FLIP_SEL_R: length 3.9
  TOP w0.076: UT5.B2 34.89,82.79 34.89,83.26 35.02,83.39 35.02,83.8
  TOP w0.102: 35.02,83.8 35.02,83.82 35.5,84.3 v2(36.02,84.3) 36.62,84.89 RT69.1
MUX1_I2C_EN: length 4.7
  TOP w0.102: v1(24.08,93.76) 24.08,93.72 v2(24.42,93.38) RT145.1 RT300.1 RT301.1
  BOTTOM w0.102: UT9.17 v1(24.08,93.76)
MUX1_SSEQ0: length 5
  TOP w0.102: v2(23.99,96.66) v1(24.63,96.66) 24.75,96.54 RT137.1 RT302.1 RT138.1
  BOTTOM w0.102: UT9.11 24.12,96.16 24.62,96.66 v1(24.63,96.66)
MUX1_SSEQ1: length 4.9
  TOP w0.102: v2(23.56,99.57) RT135.1 RT305.1 RT136.1 20.45,99.28 20.61,99.11 v1(20.61,98.82)
  BOTTOM w0.102: UT9.3 v1(20.61,98.82)
MUX1_USB_EQ0: length 5.8
  TOP w0.102: v1(17.4,96.47) 16.97,96.04 RT143.1 16.6,96.96 RT304.1 RT144.1 v2(16.59,98.95)
  BOTTOM w0.102: v1(17.4,96.47) 17.59,96.47 17.91,96.16 UT9.38
MUX1_USB_EQ1: length 6.4
  TOP w0.102: RT141.1 RT142.1 RT307.1 ; RT307.1 17.45,94.51 v2(17.66,94.71) ; RT307.1 v1(16.59,95.2)
  BOTTOM w0.102: UT9.35 16.84,94.96 v1(16.59,95.2)
MUX1_USB_SEL: length 5
  TOP w0.102: v2(22.29,82) 22.55,82.25 22.55,82.62 RT376.1 22.81,82.89 RT90.1 23.68,82.71 v1(24.14,82.25)
  BOTTOM w0.102: UT9.22 22.21,91.46 22.14,91.39 22.14,91.23 23.07,90.3 23.23,90.3 v1(23.41,90.48)
NB_PSID: length 0.7
  TOP w0.254: PL3.2 60.44,90.04 v1(60.41,90.01)
  vias: v2(59.63,88.33)
NRB_BIT: length 1.9
  TOP w0.102: RC186.1 v1(148.72,34.44) 148.89,34.6 v2(148.89,34.93)
  BOTTOM w0.076: v1(133.49,51.15) 133.84,51.5 UC1.AR7
NTC_GT: length 4.1
  TOP w0.203: PR610.2 71.24,54.26 v2(70.88,54.26) 70.38,54.26 69.76,53.65 PU602.3
NTC_GT_R: length 3.8
  TOP w0.102: v1(71.86,58.39) v2(71.86,58.9)
  TOP w0.254: v1(71.86,58.39) 72.22,58.03 PR631.2 PR610.1
  BOTTOM w0.254: v1(62.11,59.68) 61.73,60.06 PH601.2
NTC_IA: length 3.8
  TOP w0.203: v1(64.61,50.74) 64.97,50.38 PU602.15
  BOTTOM w0.102: v1(64.61,50.74) 64.46,50.74 v2(64.05,50.34)
  BOTTOM w0.254: v1(64.61,50.74) 65.32,50.03 PR635.2
NTC_R_IA: length 6.9
  BOTTOM w0.254: PR647.2 65.59,49.11 PR635.1 65.59,48.06 65.8,47.85 v1(65.8,46.3) ; PH603.2 61.88,73.61 62.54,74.27 v2(62.54,74.73) v1(62.54,75.99)
NVME_LED#: length 3.2
  TOP w0.102: v1(267.37,24.47) v2(268.1,24.47)
  BOTTOM w0.102: RN100.1 267.47,24.57 v1(267.37,24.47) ; v1(306.11,25.2) 305.7,25.6 JNGFF3.10
ONE_DIMM#: length 3.2
  TOP w0.102: v2(146.78,39.17) 146.87,39.26 v1(146.87,39.85) RC267.1 RC268.1
  BOTTOM w0.102: UC1.AP7 133.99,52.15 v1(134.39,51.75)
OTG_ID: length 2.6
  TOP w0.102: v1(33.52,79.04) 33.14,78.67 UT5.E10
  BOTTOM w0.102: v1(33.52,79.04) 33.52,78.63 RT74.1 33.83,78.3 33.15,78.3 v2(32.9,78.55)
OTGEN/CMIN: length 4.3
  TOP w0.203: PU901.20 v2(15.23,17.16) 14.79,17.16
  TOP w0.254: PR960.2 PR919.2 13.71,17.16 14.79,17.16
PANEL_BKEN_EC: length 2
  TOP w0.107: v1(302.36,78.73) UE1.J9
  BOTTOM w0.102: DV2.2 103.78,84.33 103.28,84.83 v1(102.89,84.83)
PANEL_BKLEN: length 30.6
  TOP w0.102: v1(102.37,85.11) 102.37,84.72 105.43,81.65 107.44,81.65 108.13,82.34 109.07,82.34 109.61,82.87 109.61,83.82 110.42,84.63 110.42,85.86 v2(113.26,88.7) 114.28,89.72 114.28,90.07 114.67,90.46 124,90.46 v1(124.28,90.18)
  BOTTOM w0.076: v1(130.55,61.28) 130.83,61.56 UC1.R12
  BOTTOM w0.102: v1(102.37,85.11) 102.48,85 DV2.3
PANEL_ID: length 13.6
  TOP w0.102: RE300.2 CE47.1 v1(302.53,88.97)
  TOP w0.107: v1(302.36,79.53) UE1.J10
  BOTTOM w0.102: v1(302.53,88.97) 302.53,88.33 v2(302.22,88.02) 302.22,87.35 302.63,86.94 302.63,85.82 301.4,84.59 301.4,81.31 301.21,81.12 301.21,80.16 301.4,79.97 301.77,79.97 302.21,79.53 v1(302.36,79.53)
PBAT_CHARGER_SMBCLK: length 7.8
  TOP w0.102: RE43.1 306.7,70.97 v1(306.64,70.91) 306.16,71.4 306.16,71.73 UE1.N2 ; v1(11.5,15.98) 11.67,16.15 11.98,16.15 PR922.1 ; v1(20.31,2.18) 20.13,2.35 20.13,3.77 PD2.3 20.54,4.7 20.45,4.79 20.45,5.54 PRP1.3
PBAT_CHARGER_SMBDAT: length 8.9
  TOP w0.102: PRP1.2 19.95,5.54 19.95,4.63 PD1.2 19.9,3.77 19.9,2.35 v1(19.73,2.18) ; RE37.1 307.02,71.51 v1(306.65,71.51) 306.61,71.56 306.61,71.6 305.62,72.59 305.62,72.81 305.35,73.08 304.8,73.08 UE1.M3 ; PR920.1 11.94,16.38 11.68,16.38 v1(11.5,16.57)
PBAT_PRES#: length 14.4
  TOP w0.102: PR931.1 12.2,10.25 12.2,8.02 v2(13.85,6.37) v1(17.51,6.37) 17.48,6.34 PR1.2 17.86,4.22 17.9,4.18 PD1.3 19.45,5.13 PRP1.1
  TOP w0.112: v1(299.16,78.73) UE1.F9
PBAT_PRES#_C: length 7.3
  TOP w0.102: v3(18.06,6.91) 18.43,7.28 v1(18.7,7.28) 19.28,7.28 19.45,7.12 PRP1.8
  BOTTOM w0.102: PBATT1.6 18.5,7.48 v1(18.7,7.28)
PBAT_SMBCLK_C: length 6.4
  TOP w0.102: PRP1.6 20.45,7.02 20.31,7.16 20.31,7.89 v4(20.48,8.06) 20.62,8.2 20.62,9.15 v1(20.88,9.41)
  BOTTOM w0.102: v1(20.88,9.41) 20.73,9.56 20.73,10.06 20.86,10.2 20.86,11 21.5,11.63 PBATT1.4
PBAT_SMBDAT_C: length 6.4
  TOP w0.102: v1(20.29,9.44) 20.39,9.33 20.39,8.29 20.28,8.18 20.08,7.99 20.08,7.16 19.95,7.02 PRP1.7
  BOTTOM w0.102: PBATT1.5 20,11.62 20.64,10.99 20.64,10.29 20.5,10.16 20.5,9.65 v1(20.29,9.44)
PBATT+_C:
  vias: v1(22.74,9.8) v1(22.87,8.53) v1(22.93,10.5) v1(23.18,9.16) v1(23.44,9.8) v1(23.56,8.53) v1(23.63,10.5) v1(23.88,9.16) v1(24.14,9.8) v1(24.26,8.53) v1(24.33,10.5) v1(24.58,9.16) v1(24.83,9.8) v1(24.96,8.53) v1(25.02,10.5) v1(25.28,9.16) v1(25.53,9.8) v1(25.66,8.53) v1(25.98,9.16) v1(26.36,8.53) v3(22.61,9.16) v3(24.67,10.97) v3(26.93,8.5)
PCH_ALW_ON: length 17.6
  TOP w0.102: RZ65.1 199.14,9.28 v1(199.34,9.47) ; v1(308.04,87.97) 307.98,88.03 RPE10.3 ; v1(306.16,77.16) 304.87,77.16 304.5,77.53 UE1.M8
  BOTTOM w0.102: v1(306.16,77.16) 305.95,77.16 305.41,77.7 305.41,79.02 305.01,79.41 305.01,83.19 306.36,84.54 307.09,84.54 308.23,85.68 308.23,87.78 v1(308.04,87.97) 308.04,88.51 v2(307.99,88.56)
PCH_BATLOW#: length 1.9
  TOP w0.102: v2(150.39,34.79) v1(150.75,34.44) RC72.1
  BOTTOM w0.102: v1(129.73,49.89) 130.03,50.2 UC1.AU13
PCH_CL_CLK1: length 116.3
  TOP w0.102: v1(185.86,58.51) 186.07,58.3 186.25,58.3 197.1,47.46 197.1,30.75 205.83,22.02 205.83,13.88 v1(205.74,13.79)
  BOTTOM w0.076: UC1.G3 136.27,66.2 136.79,66.72 136.79,66.98 137.14,67.33 137.14,67.58 137.33,67.77 137.61,67.77 137.79,67.95
  BOTTOM w0.102: 137.79,67.95 138.26,68.42 139.14,68.42 144.1,73.37 149.41,73.37 150.04,72.74 159.44,72.74 160.08,73.37 168.72,73.37 183.77,58.32 185.67,58.32 v1(185.86,58.51) ; v1(205.74,13.79) 206.45,14.5 JNGFF1.34
PCH_CL_DATA1: length 115.6
  TOP w0.102: v1(204.63,14.92) 205.5,14.92 205.6,15.03 205.6,21.92 196.87,30.66 196.87,47.36 186.16,58.07 186.01,58.07 v1(185.86,57.93)
  BOTTOM w0.076: UC1.G2 137.14,66.53 137.56,66.53 137.63,66.6 137.84,66.6 138.06,66.82
  BOTTOM w0.102: 138.06,66.82 139.36,68.12 139.36,68.31 144.17,73.12 149.05,73.12 149.71,72.46 159.82,72.46 160.51,73.14 168.62,73.14 183.67,58.1 185.69,58.1 v1(185.86,57.93) ; JNGFF1.32 207.9,15 207.78,14.87 204.68,14.87 v1(204.63,14.92)
PCH_CL_RST1#: length 113.1
  TOP w0.102: v1(186.36,57.2) 186.74,57.2 196.55,47.39 196.55,30.36 v2(199,27.91) 204.17,22.74 v1(204.17,15.35)
  BOTTOM w0.076: 138.12,66.56 138,66.44 137.7,66.44 UC1.G1
  BOTTOM w0.102: JNGFF1.30 204.33,15.5 v1(204.17,15.35) ; v1(186.36,57.2) 184.28,57.2 168.56,72.92 160.96,72.92 160.18,72.13 149.53,72.13 148.75,72.92 144.25,72.92 139.94,68.61 139.94,68.38 138.12,66.56
PCH_DPWROK: length 96.8
  TOP w0.102: RC215.1 131.83,38.47 v3(130.99,37.64) 130.39,37.03 v1(129.87,37.03) 130.18,36.72 CC266.1 130.19,36.35 RC220.1 ; RE536.2 280.62,77.73 281.56,76.79 282.93,76.79 283.94,75.78 UE7.1 285.33,75.78 v1(285.45,75.66)
  BOTTOM w0.076: 128.51,43.61 128.51,43.89 127.22,45.18 127.22,45.57 126.53,46.26 126.53,47.05 UC1.BB20
  BOTTOM w0.102: v1(183.84,30.83) 183.84,29.93 184.58,29.2 184.58,28.09 183.32,26.83 183.32,23.49 181.69,21.86 178.14,21.86 177.97,22.04 135.18,22.04 129.52,27.7 129.52,36.68 v1(129.87,37.03) 130.31,37.47 130.31,38.85 128.51,40.65 128.51,43.61
PCH_DPWROK_EC: length 3.6
  TOP w0.102: RE34.1 284.87,78.28 v2(285.7,77.44) 286.14,77.44 v1(286.21,77.51)
  TOP w0.112: v1(299.18,77.91) UE1.F8
PCH_JTAG_TCK: length 16.3
  TOP w0.102: JXDP1.55 61.96,35.83 61.96,34.82 61.56,34.42 60.62,34.42 60.25,34.79 60.25,36.19 v3(58.06,38.39) 57.21,39.24 v1(56.84,39.24)
  BOTTOM w0.076: v1(104.41,74.07) 104.73,73.75 104.73,72.73 105.24,72.21 105.24,70.85 105.42,70.67 105.42,70 105.29,69.87 105.29,69.61 105.35,69.49 105.35,69.27 UC1.B56
  BOTTOM w0.102: RC86.1 104.91,74.57 v1(104.41,74.07)
PCH_JTAG_TDI: length 12.9
  TOP w0.102: v1(52.71,37.48) RC229.2
  BOTTOM w0.076: CC304.1 103.89,75.33 103.89,74.06 104.3,73.65 v1(104.3,73.43) 104.3,72.16 104.48,71.98 104.48,70.1 104.64,69.94 104.64,69.58 104.6,69.48 104.6,69.29 104.64,69.2 104.64,68.95 104.62,68.91 104.58,68.75 104.5,68.47 104.5,68.36 104.42,68.09 UC1.D59
  BOTTOM w0.102: CC304.1 104.45,75.89 104.45,77.22 103.76,77.9 RC81.1
PCH_JTAG_TDO: length 12.1
  TOP w0.102: v1(105.34,77.74) v3(106.05,77.74)
  BOTTOM w0.076: UC1.A56 105.6,69.75 105.6,70.79 105.41,70.97 105.41,72.28 104.93,72.77 104.93,73.73
  BOTTOM w0.102: RC82.1 RC230.2 105.34,78.44 v1(105.34,77.74) 105.34,75.9 CC303.1 105.8,74.69 104.93,73.82 104.93,73.73
PCH_JTAG_TMS: length 14.4
  TOP w0.102: RC228.2 52.2,27.93 51.45,27.18 v3(50.68,27.18) v1(49.91,27.18)
  BOTTOM w0.076: v1(103.82,72.41) 104.3,71.93 104.3,70.04 104.47,69.87 104.47,69.61 104.41,69.49 104.41,69.34 104.47,69.15 104.47,68.98 104.39,68.72 UC1.C59
  BOTTOM w0.102: v1(103.82,72.41) 103.82,73.62 103.64,73.81 103.64,74.65 103.58,74.71 103.58,77.6 103.16,78.01 103.16,78.59 RC130.1
PCH_PCIE_WAKE#: length 83.2
  TOP w0.102: v1(306.86,68.09) 307.09,68.31 RE274.2 ; UE1.L1 v1(303.56,71.27) ; RC67.1 132.97,36.34 v1(133.1,36.21)
  BOTTOM w0.076: 131.99,43.09 130.42,44.66 129.98,44.66 128.84,45.81 128.84,47 UC1.BB15
  BOTTOM w0.102: v1(181.26,39.63) 181.65,39.24 181.65,31.93 177.17,27.45 175.57,27.45 173.17,25.05 138.47,25.05 133.6,29.92 133.6,35.62 133.1,36.11 v1(133.1,36.21) 133.56,36.67 133.56,39.09 132.06,40.58 132.06,41.62 v2(132.36,41.93) 132.09,42.21 132.09,42.99 131.99,43.09
PCH_PLTRST#: length 48.7
  TOP w0.102: v1(155.75,39.94) v2(155.17,40.52) 154.65,41.04 152.68,41.04 151.93,41.79 149.79,41.79 149.7,41.88 149.67,41.88 148.97,42.58 143.34,42.58 139.78,46.14 139.47,46.14 137.13,48.47 137.13,50.93 136.4,51.66 135.11,51.66 134.63,52.14 133.02,52.14 132.56,52.59 v1(132.52,52.59)
  BOTTOM w0.102: v1(132.52,52.59) 132.31,52.8 UC1.AN10 ; 157.58,52.12 UC7.2 158.05,52.05 RC244.1 RC62.1 ; 157.58,52.12 157.42,52.28 157.42,52.6 157.59,52.77 UC7.1 ; 157.58,52.12 157.52,52.12 157.26,51.85 157.26,50.74 RC60.1 158.06,49.94 158.06,49.23 157.23,48.41 157.23,41.6 155.75,40.12 v1(155.75,39.94)
PCH_PLTRST#_5105: length 17.4
  TOP w0.102: v1(303.54,70.68) 303.46,70.68 302.76,71.38 UE1.K1
  BOTTOM w0.102: UE6.4 268.09,75.77 RE340.1 268.09,76.26 268.3,76.46 270.17,76.46 270.75,75.89 v2(270.75,74.03) 270.75,72 272.07,70.68 275.86,70.68 276.82,71.64 v1(276.82,71.73)
PCH_PLTRST#_AND: length 47.2
  TOP w0.102: v1(28.83,48.41) 28.58,48.66 UR1.1 ; RZ114.1 220.1,19.53 CZ61.1 219.14,20.45 v1(219.13,20.47) ; v1(206.25,12.49) 208.03,10.71 208.03,9.62 208.69,8.96 208.69,3.46 v2(207.51,2.28) v1(207.15,1.92)
  BOTTOM w0.102: RC325.1 156.58,50.37 RC65.1 155.78,51.17 UC7.4 156.35,51.47 156.85,51.96 156.85,52.85 158.12,54.12 161.63,54.12 v1(162.72,55.21) ; JNGFF3.50 v1(295.7,25.15) ; v1(299.06,47.65) 299.06,49.41 JNGFF2.42 ; JNGFF1.58 206.13,8.5 205.11,9.52 205.11,12.01 205.62,12.51 206.22,12.51 v1(206.25,12.49) 206.28,12.46 206.8,12.46 207.26,12 JNGFF1.44 ; v1(219.13,20.47) 218.39,19.73 218.39,18.71 217.43,17.74 v1(217.43,13.86)
PCH_PLTRST#_EC: length 29.6
  BOTTOM w0.102: v1(267.39,67.72) RE375.2 268.17,67.82 267.21,68.77 v2(267.21,70.25) 267.21,70.74 268.74,72.26 UE6.2 ; RC244.2 160.83,53.66 161.37,53.66 162.34,52.7 177.83,52.7 180.38,55.25 v1(181.3,55.25)
PCH_POPIRCOMP: length 9.2
  TOP w0.381: v1(127.99,49.87) 127.99,49.51 131.96,45.53 v2(131.96,44.19) RC89.1
  BOTTOM w0.254: v1(127.99,49.87) 128.4,50.17 UC1.AU16
PCH_PWROK: length 33.6
  TOP w0.102: v1(125.81,37.79) 125.16,37.14 RC411.1 124.16,36.42 v3(123.55,35.81)
  BOTTOM w0.076: 128.24,43.23 128.24,43.74 126.87,45.12 126.87,45.69 126.37,46.19 126.37,46.79 126.23,46.93 126.23,47.47 UC1.BA20
  BOTTOM w0.102: v1(87.23,41.15) 86.04,41.15 78.57,48.63 78.57,49.8 77.09,51.28 75.09,51.28 PR614.1 ; v1(125.81,37.79) 126.78,37.79 128.24,39.26 128.24,43.23
PCH_RSMRST#: length 45.7
  TOP w0.102: UZ6.1 137.42,27.2 138.44,26.18 146.94,26.18 148.65,27.88 154.26,27.88 156.37,25.77 v2(175.77,25.77) v1(178.4,25.77) ; RE364.2 v1(309.06,74.51) ; RE342.1 301.82,66.99 v1(301.52,67.29) 301.97,67.75 RE363.2
PCH_RSMRST#_AND: length 29.5
  TOP w0.102: RC124.1 68.97,39.77 v1(69.22,40.02) ; v1(129.6,40.44) 129.74,40.29 131.33,40.29 RC215.2 132.82,39.79 RC75.1 132.34,39.26 132.34,38.2 131.58,37.44 131.58,34.69 v2(131.93,34.33) 132.49,33.77 136.33,33.77 139.07,31.04 139.07,29.95 UZ6.4
  BOTTOM w0.076: 129.17,43.59 129.17,43.69 127.65,45.21 127.65,46.74 127.46,46.93 127.46,47.19 127.51,47.31 127.51,47.45 127.45,47.68 127.45,47.8 127.52,48.01 127.62,48.12 127.72,48.23 UC1.AY17
  BOTTOM w0.102: 129.17,43.59 129.17,40.87 v1(129.6,40.44)
PCH_RSMRST#_GPIO204: length 4.3
  TOP w0.102: RE363.1 301.72,69.07 301.72,70.42 v2(301.7,70.43) 301.56,70.57 301.56,72.35 301.19,72.73 UE1.H2
PCH_RTCRST#: length 33.3
  TOP w0.102: RE94.2 288.74,71.77 v1(289.08,71.43) ; v3(315.92,66.95) v1(315.92,66.25)
  BOTTOM w0.076: UC1.AM16 128.49,53.45 v1(128.89,53.1)
  BOTTOM w0.102: v1(289.08,71.43) 289.41,71.1 289.41,69.81 290.14,69.08 291.83,69.08 292.04,68.87 293.06,68.87 294.52,67.42 294.52,66.17 295.49,65.2 295.83,65.2 296.93,64.1 296.93,63.87 298.14,62.66 298.14,61.81 299.16,60.79 304.66,60.79 304.87,60.58 304.87,59.11 305.91,58.06 v1(306.4,58.06) ; JAPS1.9 v1(315.92,66.25) ; v1(152.79,53.61) 152.73,53.61 152.63,53.51 CMOS1.1 152.64,52.36 CC25.1 RC57.1
PCH_RTCX1: length 24.5
  BOTTOM w0.076: UC1.AM18 127.56,53.45 v1(127.93,53.12)
  BOTTOM w0.102: YC2.1 RC54.2 151.82,41.57 150.22,41.57 CC23.1 149.61,42.21 149.13,42.69 147.07,42.69 144.4,45.36 v2(144.4,49.01) 144.4,51.61 143.32,52.68 143.32,54.22 141.3,56.24 v1(140.93,56.24)
PCH_RTCX2: length 22.5
  BOTTOM w0.076: UC1.AM20 126.66,53.45 v1(127.03,53.12)
  BOTTOM w0.102: v1(140.44,56.68) 140.61,56.85 141.77,56.85 143.96,54.66 143.96,52.91 145.04,51.83 v2(145.04,51.02) 145.04,45.62 147.33,43.33 149.36,43.33 150.5,42.18 RC296.1 RC54.1
PCH_RTCX2_R: length 4
  BOTTOM w0.102: YC2.2 152.83,43.58 CC26.1 151.92,43.1 RC296.2
PCH_SMB_ALERT#: length 14.6
  TOP w0.102: v1(131.82,61.28) 131.82,61.47 132.25,61.9 v2(135.59,61.9) 137.53,61.9 139.73,64.1 143.24,64.1 143.38,63.96 RC23.1
  BOTTOM w0.076: UC1.R10 132.13,61.59 v1(131.82,61.28)
PCH_SPI_CLK: length 35.8
  TOP w0.102: v1(138.68,49.8) 138.68,50.03 139.41,50.77 143.97,50.77 145.95,52.75 151.7,52.75 153.88,50.57 158.71,50.57 159.19,51.05 161.07,51.05 162.1,50.02 162.1,47.9 162.26,47.75 163.57,47.75 164,48.18 v1(164,48.25)
  BOTTOM w0.076: UC1.AV2 136.96,49.6 137.22,49.86 138.62,49.86 v1(138.68,49.8)
  BOTTOM w0.102: JSPI1.13 163.85,47.71 163.59,47.98 163.59,48.66 RC35.2 163.82,48.89 164,48.71 v1(164,48.25)
PCH_SPI_CLK_0_R: length 13.4
  TOP w0.102: v3(153.12,64.92) 153.01,65.02 v1(152.53,65.02)
  BOTTOM w0.102: UC5.6 154.54,64.69 155.66,65.81 155.66,67.01 155.52,67.15 155.04,67.15 154.92,67.03 154.92,65.92 154.27,65.27 152.78,65.27 v1(152.53,65.02) 152.02,64.51 RC29.1 152.02,64.29 152.53,63.78 152.53,63.26 153.67,62.12 RPC1.6
PCH_SPI_CLK_1_R: length 15.4
  BOTTOM w0.102: RC28.1 151.34,54.94 151.94,55.54 v2(151.94,55.54) 151.94,55.54 152.45,56.05 UC6.6 153.89,56.05 155.53,54.41 155.9,54.41 156.16,54.67 156.16,54.96 155.96,55.16 155.96,55.36 156.53,55.92 156.53,56.12 156.39,56.27 156.19,56.27 155.62,55.7 155.42,55.7 155.17,55.95 155.17,56.96 155.91,57.71 155.91,58.42 157.61,60.12 RC408.2
PCH_SPI_CLK_2_R: length 4.4
  TOP w0.102: UZ12.19 163.01,38.17 RZ63.2 RZ60.2 162.32,39.39 161.99,39.39 v2(161.49,39.9)
PCH_SPI_CLK_R1: length 33.2
  TOP w0.102: v1(160.6,40.53) 160.6,39.83 161.55,38.88 RZ60.1 ; v1(157.61,61.99) 159.34,60.27 162.41,60.27 164.44,58.23 v2(164.44,57.32) 164.44,52.22 v1(163.85,51.63)
  BOTTOM w0.102: v1(160.6,40.53) 160.6,43.82 162.36,45.59 164.01,45.59 164.35,45.93 JSPI1.14 164.35,47.72 164.49,47.86 164.49,49.51 164.2,49.8 RC35.1 163.81,51.59 v1(163.85,51.63) ; RPC1.3 v1(153.67,59.65) ; RC408.1 v1(157.61,61.99)
PCH_SPI_CS#0: length 38.9
  TOP w0.102: v1(140.01,51.18) 140.52,51.7 144.21,51.7 145.76,53.25 148.36,53.25 148.7,53.59 151.55,53.59 154,51.13 156.36,51.13 157.23,52 160.8,52 162.62,50.18 162.62,49.94 162.76,49.8 164.43,49.8 164.57,49.66 164.57,49.46 164.43,49.32 162.76,49.32 162.62,49.18 v1(162.62,48.25)
  BOTTOM w0.076: UC1.AU3 136.37,50.29 136.63,50.56 136.92,50.56 137.33,50.72 138.11,50.72 138.97,51.58 139.34,51.58 139.74,51.18 v1(140.01,51.18)
  BOTTOM w0.102: JSPI1.11 162.85,47.3 162.2,47.95 162.2,48.75 162.35,48.9 RC36.2 162.62,48.76 v1(162.62,48.25)
PCH_SPI_CS#0_R1: length 27.2
  TOP w0.102: v1(164.31,63.9) 167.72,60.49 v2(167.72,59.71) 167.72,51.43 166.87,50.59 163.62,50.59 v1(163.16,51.04)
  BOTTOM w0.102: v1(164.31,63.9) 164.37,63.96 164.37,64.68 RC37.1 ; v1(163.16,51.04) 162.48,50.36 RC36.1 162.9,49.81 163.09,49.62 163.09,47.73 163.35,47.47 JSPI1.12
PCH_SPI_CS#0_R2: length 3.1
  BOTTOM w0.102: v1(163.91,67.18) 162.79,67.18 RC37.2 161.96,67.28 161.91,67.23 UC5.1
PCH_SPI_CS#1: length 38.9
  TOP w0.102: v1(167.47,48.2) 167.35,48.31 167.35,50.01 167.03,50.33 162.79,50.33 160.9,52.22 157.05,52.22 156.37,51.55 v2(154.4,51.55) 153.91,51.55 151.64,53.81 148.59,53.81 148.25,53.47 145.67,53.47 144.24,52.04 140.03,52.04 v1(139.19,51.2)
  BOTTOM w0.076: UC1.AU2 136.96,50.29 137.1,50.43 137.11,50.44 137.11,50.44 137.36,50.56 138.24,50.56 138.57,50.89 138.88,50.89 v1(139.19,51.2)
  BOTTOM w0.102: JSPI1.19 166.85,47.67 167.03,47.85 167.03,48.63 RC32.2 167.3,48.36 v1(167.47,48.2)
PCH_SPI_CS#1_R1: length 21.4
  TOP w0.102: v1(166.41,51.1) v2(166.41,56.98) 166.41,57.79 161.49,62.71 v1(160.3,62.71)
  BOTTOM w0.102: v1(166.41,51.1) 167.3,50.21 RC32.1 167.3,49.78 168.01,49.06 168.01,48.09 167.35,47.43 JSPI1.20 ; v1(160.3,62.71) 160.66,62.35 RC42.1
PCH_SPI_CS#1_R2: length 5.9
  BOTTOM w0.102: v2(162.31,61.23) 161.53,60.45 RC42.2 160.44,60.45 159.12,59.13 159.12,58.69 159.22,58.59 UC6.1
PCH_SPI_CS#2: length 56.1
  TOP w0.102: v1(141.6,46.2) 141.6,46.15 142.1,45.65 142.3,45.65 143.25,46.61 143.45,46.61 143.6,46.47 143.6,46.27 142.05,44.72 142.05,44.52 142.19,44.38 142.39,44.38 144.62,46.61 144.82,46.61 144.96,46.47 144.96,46.27 142.74,44.05 142.74,43.85 142.88,43.7 143.08,43.7 145.04,45.67 145.24,45.67 145.38,45.53 145.38,45.33 143.43,43.38 143.43,43.18 143.57,43.03 143.77,43.03 145.3,44.56 145.5,44.56 145.64,44.42 145.64,44.22 144.69,43.26 144.69,43.06 144.77,42.98 145.77,42.98 145.91,43.12 145.91,43.62 146.05,43.76 146.25,43.76 146.39,43.62 146.39,43.12 146.53,42.98 149.18,42.98 149.96,42.2 152.11,42.2 152.81,41.5 155.15,41.5 156.32,40.33 156.32,38.32 156.65,37.99 RZ61.1
  BOTTOM w0.076: 140.36,50.2 140.17,50.4 138.31,50.4 138.2,50.29 UC1.AU1
  BOTTOM w0.102: v1(141.6,46.2) 141.1,46.7 141.1,47.07 141.24,47.21 142.52,47.21 142.66,47.35 142.66,47.55 142.52,47.69 140.59,47.69 140.44,47.84 140.44,48.04 140.57,48.18 142.52,48.18 142.66,48.32 v2(142.66,48.43) 142.66,48.52 142.52,48.66 141.24,48.66 141.1,48.8 141.1,49.47 140.36,50.2
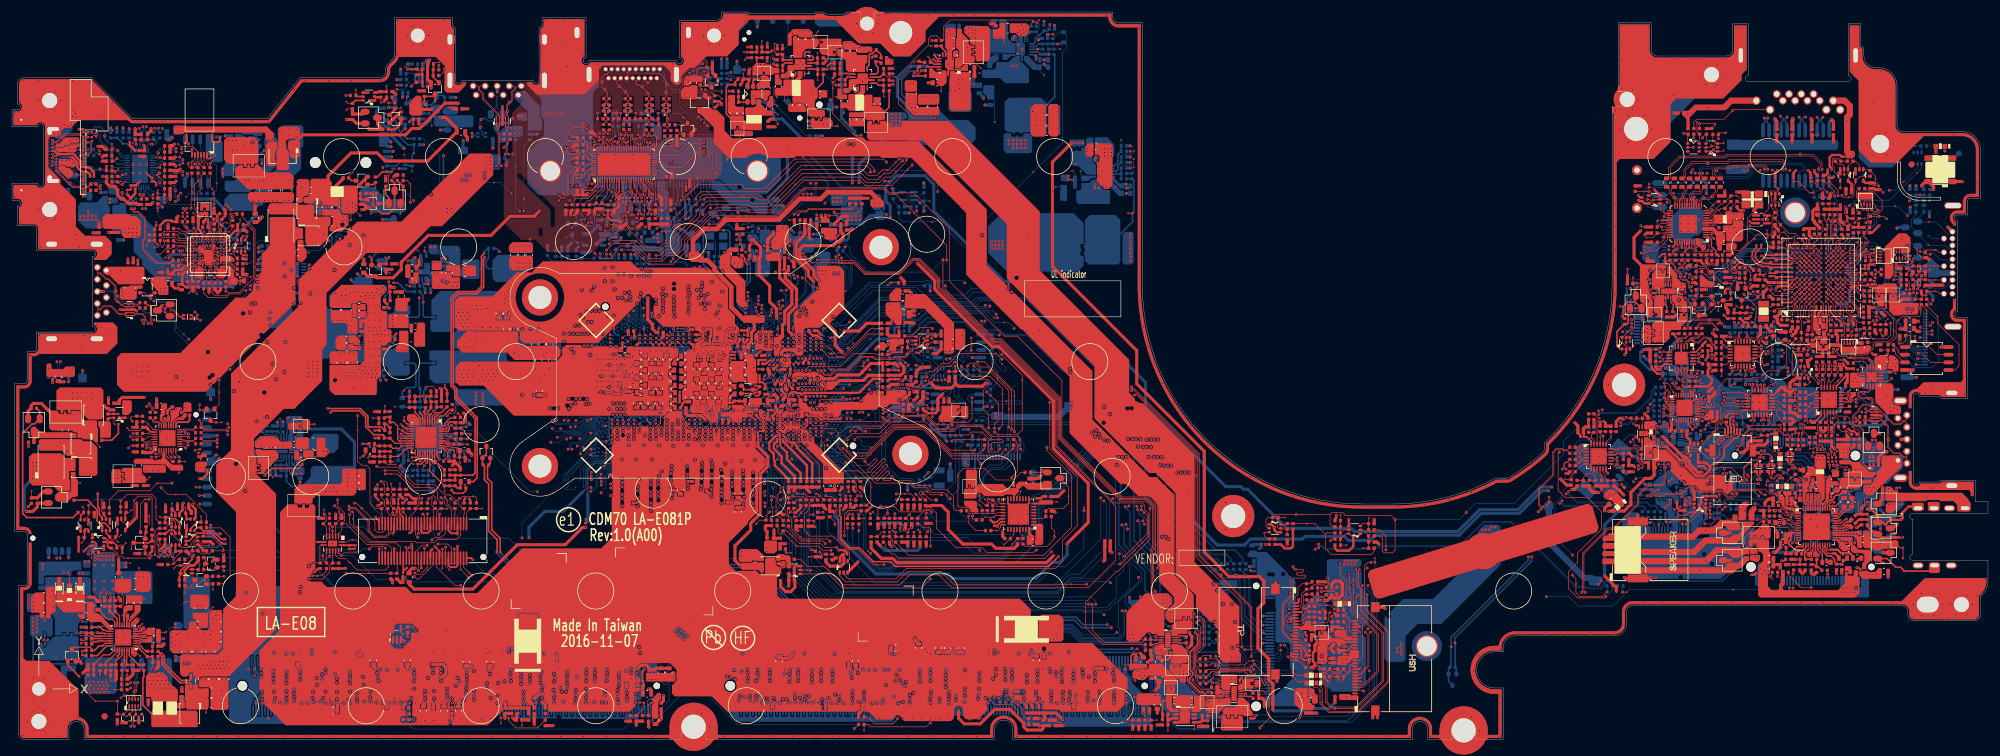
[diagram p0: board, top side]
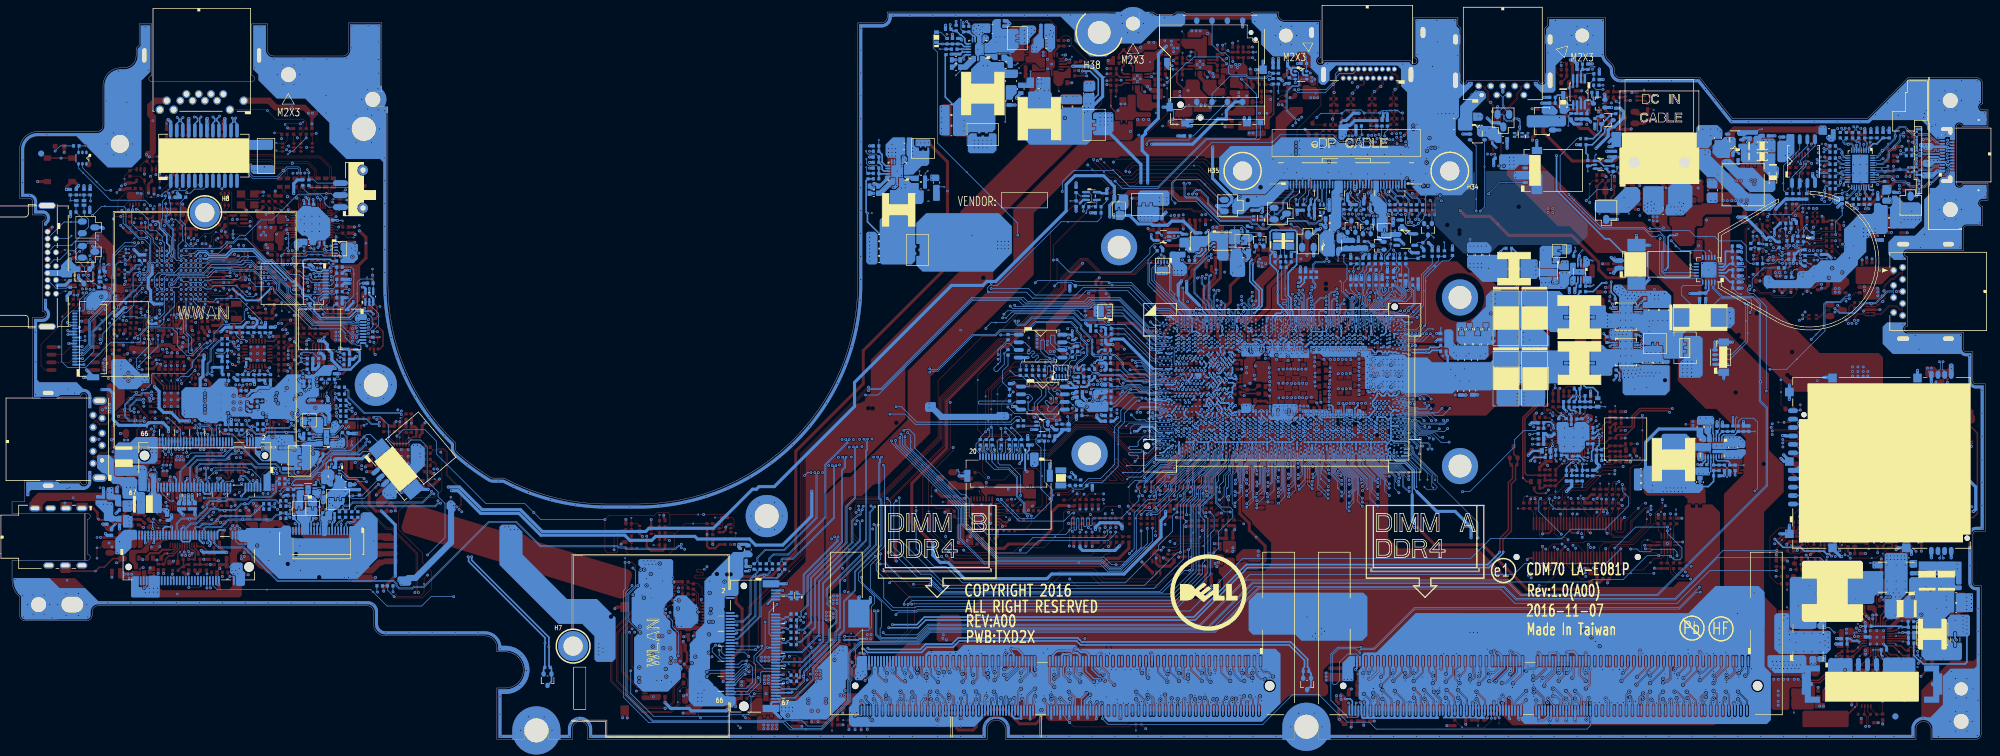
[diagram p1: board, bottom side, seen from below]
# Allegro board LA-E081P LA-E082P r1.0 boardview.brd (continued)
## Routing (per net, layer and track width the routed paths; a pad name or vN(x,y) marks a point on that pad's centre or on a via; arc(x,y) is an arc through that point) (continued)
PCH_SPI_CS#2_R: length 26.3
  TOP w0.102: RZ113.1 167.47,44.34 166.22,43.1 163.35,43.1 161.41,45.04 157.98,45.04 157.03,44.09 v2(157.03,43.76) 157.03,38.83 157.29,38.56 158.12,38.56 158.51,38.17 RZ61.2 158.97,37.53 163.45,37.53 163.58,37.67 UZ12.20
PCH_SPI_D0: length 40.5
  TOP w0.102: RC10.2 166.29,48.38 v1(166.14,48.24) v2(165.42,47.52) 164.49,46.59 156.21,46.59 151.26,51.54 146.65,51.54 141.79,46.68 139.63,46.68 v1(137.94,48.37)
  BOTTOM w0.076: v1(137.94,48.37) 137.81,48.5 137.22,48.5 136.97,48.75 136.01,48.75 135.84,48.92 UC1.AV3
  BOTTOM w0.102: JSPI1.17 165.85,47.32 166.57,48.04 166.57,48.61 RC10.2 166.27,48.9 166.14,48.77 v1(166.14,48.24)
PCH_SPI_D0_0_R: length 13.4
  TOP w0.102: v3(155.1,63.24) v1(155.73,63.24)
  BOTTOM w0.102: RPC1.7 154.17,61.72 154.78,62.32 154.78,62.52 154.58,62.72 154.58,62.92 154.72,63.06 154.92,63.06 155.12,62.87 155.36,62.87 v1(155.73,63.24) 156.01,63.52 156.32,63.52 157.25,64.45 157.25,66.21 157.11,66.35 156.79,66.35 156.66,66.22 156.66,64.67 155.92,63.93 155.01,63.93 154.5,63.42 UC5.5
PCH_SPI_D0_1_R: length 13.2
  BOTTOM w0.102: RC409.2 156.4,58.22 156.4,57.12 157.79,55.73 157.79,54.77 156.25,53.23 v2(155.15,53.23) 154.22,54.16 154.22,54.63 154.07,54.78 UC6.5
PCH_SPI_D0_2_R: length 3.8
  TOP w0.102: RZ59.2 161.51,36.92 v2(163,36.92) 163.24,37.17 UZ12.21
PCH_SPI_D0_R1: length 38.1
  TOP w0.102: v1(158.63,62.03) 159.11,62.51 159.89,62.51 160.55,61.85 162.03,61.85 165.97,57.91 v2(165.97,52.95) 165.98,52.94 v1(165.98,51.51) ; v1(159.45,37.1) 159.45,36.66 159.64,36.47 RZ59.1
  BOTTOM w0.102: RPC1.2 154.17,59.83 v1(154.34,59.66) ; v1(159.45,37.1) 160.13,37.78 160.13,39.12 161.31,40.3 161.31,43.53 162.66,44.87 165,44.87 166.35,46.22 JSPI1.18 166.35,47.49 166.8,47.94 166.8,49.6 166.59,49.81 RC33.1 165.72,50.38 165.72,51.26 v1(165.98,51.51) ; RC409.1 v1(158.63,62.03)
PCH_SPI_D1: length 38.1
  TOP w0.102: v1(138.6,49.07) 138.56,49.03 138.56,48.02 139.51,47.07 141.81,47.07 146.52,51.78 151.34,51.78 156.02,47.1 v2(161.93,47.1) 163.89,47.1 v1(164.98,48.18)
  BOTTOM w0.076: UC1.AW3 136.46,49.31 137.65,49.31 137.89,49.07 v1(138.6,49.07)
  BOTTOM w0.102: v1(164.98,48.18) 164.98,48.77 165.1,48.89 RC34.2 165.46,48.76 165.46,48.03 164.85,47.42 JSPI1.15
PCH_SPI_D1_0_R: length 14.8
  TOP w0.102: v1(159.24,64.63) v3(159.24,66.69)
  BOTTOM w0.102: UC5.2 159.93,65.96 159.02,65.05 159.02,64.85 v1(159.24,64.63) 159.51,64.36 159.51,64.16 159.37,64.02 159.17,64.02 158.68,64.51 158.48,64.51 158.34,64.37 158.34,64.17 158.75,63.76 158.75,63.57 158.61,63.43 158.4,63.43 157.99,63.83 157.8,63.83 157.65,63.69 157.65,63.49 158.14,63 158.14,62.8 158,62.66 157.8,62.66 157.31,63.15 156.23,63.15 155.67,62.59 155.67,62.53 RPC1.8
PCH_SPI_D1_1_R: length 12.7
  BOTTOM w0.102: UC6.2 159.17,57.32 158.65,56.8 158.65,56.49 159.35,55.78 159.35,54.86 159.09,54.6 158.5,54.6 158.34,54.76 158.34,55.87 157.17,57.04 157.17,57.98 RC410.2
PCH_SPI_D1_2_R: length 2.6
  TOP w0.102: UZ12.24 164.24,35.67 164.15,35.58 164.15,35.2 163.64,34.69 v2(163.43,34.69) RZ58.2
PCH_SPI_D1_R1: length 38.9
  TOP w0.102: RZ58.1 160.03,34.69 158.82,35.9 v1(158.82,37.1) ; v1(165.49,51.87) v2(165.49,54.83) 165.49,57.93 162.42,61 160.73,61 v1(159.67,62.06)
  BOTTOM w0.102: v1(158.82,37.1) 159.22,37.51 159.54,37.51 159.9,37.87 159.9,39.21 161.08,40.39 161.08,43.62 162.56,45.1 164.37,45.1 165.35,46.09 JSPI1.16 165.35,47.59 165.69,47.93 165.69,48.46 165.8,48.56 165.8,49.68 165.68,49.8 RC34.1 165.33,51.71 v1(165.49,51.87) ; RPC1.1 154.67,60.01 v1(154.94,59.74) ; v1(159.67,62.06) 159.64,62.03 RC410.1
PCH_SPI_D2: length 33.1
  TOP w0.102: RC11.2 161.46,48.33 v1(161.21,48.08) 160.64,47.52 v2(158.27,47.52) 155.93,47.52 151.41,52.04 146.39,52.04 141.89,47.54 v1(139.91,47.54)
  BOTTOM w0.076: 138.55,48.42 138.15,48.81 137.91,48.81 137.59,49.14 136.94,49.14 UC1.AW2
  BOTTOM w0.102: v1(161.21,48.08) 161.21,48.64 RC38.2 161.52,48.9 161.62,48.8 161.62,47.66 161.85,47.43 JSPI1.9 ; 138.55,48.42 139.43,47.54 v1(139.91,47.54)
PCH_SPI_D2_0_R: length 12.7
  BOTTOM w0.102: RC39.2 163.33,64.1 163.33,62.28 164.47,61.14 164.8,61.14 165.03,61.36 165.03,61.69 v2(164.38,62.34) 163.9,62.81 163.9,64.77 162.89,65.78 162.44,65.78 161.35,64.69 UC5.3
PCH_SPI_D2_1_R: length 12.8
  BOTTOM w0.102: RC43.2 v2(165.08,56.2) 167.49,56.2 167.61,56.08 167.61,55.81 167.5,55.7 161.97,55.7 161.62,56.05 UC6.3
PCH_SPI_D2_R1: length 21.7
  TOP w0.102: v1(163.11,51.67) 163.11,52.4 163.76,53.05 163.76,55.8 v1(161.83,57.73)
  BOTTOM w0.102: v1(161.83,57.73) RC43.1 RC30.1 163.61,59.34 v2(163.61,59.99) 163.61,61.19 162.69,62.11 RC39.1 ; v1(163.11,51.67) 162.84,51.67 161.46,50.3 RC38.1 161.79,49.81 161.92,49.68 161.92,47.77 162.35,47.34 JSPI1.10
PCH_SPI_D3: length 30.8
  TOP w0.102: v1(159.85,48.07) 159.82,48.05 v2(156.61,48.05) 155.72,48.05 151.5,52.26 146.15,52.26 144.13,50.25 140.36,50.25 v1(139.92,49.81)
  BOTTOM w0.076: UC1.AU4 135.78,50.03 138.17,50.03 138.36,50.22 139.51,50.22 v1(139.92,49.81)
  BOTTOM w0.102: JSPI1.7 160.85,47.3 160.55,47.6 160.55,48.8 RC40.2 160.24,48.9 160.14,48.8 160.14,48.41 159.85,48.13 v1(159.85,48.07)
PCH_SPI_D3_0_R: length 12.7
  BOTTOM w0.102: RPC1.5 152.82,61.18 152.82,60.49 152.69,60.36 152.49,60.36 152.36,60.49 152.36,61.39 152.68,61.71 152.68,62.04 152.49,62.23 152.49,62.59 152.18,62.91 151.57,62.91 151.29,63.19 151.29,63.39 151.4,63.5 151.4,63.7 151.26,63.84 151.06,63.84 150.95,63.73 150.75,63.73 150.59,63.88 150.59,64.66 150.45,64.8 150.31,64.8 150.17,64.94 v2(150.17,65.02) 150.17,65.14 150.31,65.28 150.45,65.28 150.59,65.42 150.59,65.77 150.78,65.96 151.52,65.96 151.71,65.77 152.36,65.77 152.55,65.96 UC5.7
PCH_SPI_D3_1_R: length 12.8
  BOTTOM w0.102: UC6.7 153.55,57.32 154.26,58.03 154.57,58.03 154.87,57.73 155.03,57.73 155.27,57.97 155.27,58.11 154.45,58.93 154.45,59.13 154.6,59.27 154.8,59.27 155.33,58.74 155.53,58.74 156.27,59.49 156.27,59.9 156.1,60.08 155.72,60.08 155.61,60.19 155.61,60.53 155.47,60.68 155.1,60.68 154.96,60.82 154.96,61.02 155.1,61.16 155.47,61.16 155.61,61.3 155.61,61.9 155.73,62.02 v2(155.8,62.02) 155.99,62.02 156.11,61.89 156.11,60.67 156.33,60.45 RC407.2
PCH_SPI_D3_R1: length 24.5
  TOP w0.102: v1(156.56,61.99) 156.6,61.95 RC31.1 ; v1(162.15,51.74) v2(162.15,53.93) 161.24,54.84 161.24,57.97 162.21,58.95 162.21,59.63 162.06,59.78 158.84,59.78 157.51,61.12 RC31.1 ; RC31.1 RC316.1
  BOTTOM w0.102: v1(162.15,51.74) 161.94,51.74 160.44,50.25 RC40.1 160.73,49.81 160.9,49.63 160.9,48.47 160.77,48.34 160.77,47.88 161.35,47.3 JSPI1.8 ; v1(156.56,61.99) 156.66,61.89 RC407.1 ; v1(153.07,59.7) 153.17,59.81 RPC1.4
PCH_SPI_DO2_XDP: length 135.7
  TOP w0.102: v1(156,49.56) 156.26,49.81 v2(157.1,49.81) RC11.1 ; JXDP1.60 v1(60.95,31.66)
  BOTTOM w0.102: v1(183.42,17.75) 183.04,17.37 177.8,17.37 176.03,19.14 130.81,19.14 122.55,27.4 78.72,27.4 76.85,29.27 63.34,29.27 v1(60.95,31.66)
PCH_SPI_DO_XDP: length 142
  TOP w0.102: RC10.1 166.9,49.2 166.9,44.46 v1(165.94,43.5) ; v1(60.69,42.33) 60.33,41.98 RC133.1 RC128.1
  BOTTOM w0.102: v1(60.69,42.33) v2(60.69,41.75) 60.69,41.25 59.65,40.21 59.65,38.8 63.53,34.92 69.22,34.92 70.76,33.38 82.54,33.38 85.89,30.03 123.77,30.03 132.47,21.33 177.67,21.33 177.85,21.15 180.87,21.15 v1(181.3,20.72)
PCI_CLK_LPC1: length 6.5
  TOP w0.102: v2(142.96,37.79) 142.65,37.48 v1(142.5,37.48) RC22.1
  BOTTOM w0.076: v1(135.13,45.06) 134.88,45.06 133.73,46.21 133.01,46.21 132.3,46.92 132.3,47.19 132.35,47.3 132.35,47.52 132.3,47.63 132.3,47.84 132.33,47.92 132.33,48.16 UC1.AY9
PCIE_PRX_C_DTX_N1: length 2.9
  TOP w0.094: UR1.8 28.12,51.46 28.22,51.36 28.3,51.36 28.49,51.55 30.19,51.55 CR14.2
PCIE_PRX_C_DTX_N9: length 3.2
  TOP w0.094: UL1.39 276.86,82.23 276.74,82.11 276.74,81.45 276.53,81.24 276.05,81.24 275.82,81.02 275.82,80.58 275.92,80.49 CL2.2
PCIE_PRX_C_DTX_N11: length 23.5
  BOTTOM w0.094: RN82.1 283.94,43.05 284.1,43.05 284.3,42.85 284.3,41.25 285.15,40.4 288.61,40.4 289.06,39.95 292.33,39.95 292.61,39.68 v4(293.67,39.68) 295.22,39.68 295.8,39.1 295.8,38.5 297.52,36.78 298.27,36.78 298.28,36.79 298.91,36.79 298.92,36.78 299.93,36.78 300.82,35.89 300.82,34.86 300.95,34.72 JNGFF3.29
PCIE_PRX_C_DTX_N12: length 14.4
  BOTTOM w0.094: JNGFF3.43 297.45,34.66 297.62,34.83 297.62,35.05 297.5,35.17 296.9,35.17 296.33,35.74 294.62,35.74 v4(293.96,36.4) 293.35,37.02 288.3,37.02 287.7,37.62 287.68,37.62 287.28,38.03 287.28,38.04 286.64,38.67 286.37,38.67 286.28,38.57 RN78.1
PCIE_PRX_C_DTX_P1: length 2.9
  TOP w0.094: UR1.7 28.08,51.06 28.2,51.17 28.38,51.17 28.57,51.37 30.05,51.37 CR13.2
PCIE_PRX_C_DTX_P9: length 3.2
  TOP w0.094: CL1.2 275.54,80.49 275.64,80.58 275.64,81.09 275.98,81.44 v4(276.2,81.44) 276.46,81.44 276.55,81.53 276.55,82.09 276.46,82.18 UL1.38
PCIE_PRX_C_DTX_P11: length 23.5
  BOTTOM w0.094: RN81.1 283.67,42.75 283.79,42.87 284.03,42.87 284.12,42.77 284.12,41.18 285.08,40.22 288.53,40.22 288.98,39.77 292.26,39.77 292.54,39.49 293.34,39.49 293.38,39.46 293.96,39.46 293.99,39.49 295.14,39.49 295.61,39.02 295.61,38.42 297.44,36.59 v4(298.59,36.59) 299.85,36.59 300.63,35.82 300.63,34.89 300.45,34.71 JNGFF3.31
PCIE_PRX_C_DTX_P12: length 14.5
  BOTTOM w0.094: JNGFF3.41 297.95,34.7 297.81,34.84 297.81,35.13 297.58,35.36 296.97,35.36 296.4,35.92 294.7,35.92 294.32,36.3 294.32,36.35 293.91,36.76 293.86,36.76 293.42,37.2 288.37,37.2 v4(287.62,37.96) 286.72,38.86 286.55,38.86 RN77.1
PCIE_PRX_C_RD_DTX_N8: length 1.7
  TOP w0.094: UZ36.4 284.88,63.83 284.72,63.68 284.21,63.68 CZ142.2
PCIE_PRX_C_RD_DTX_N11: length 2.4
  TOP w0.094: UN4.4 260.95,46.76 260.79,46.6 260.58,46.6 260.3,46.33 260.3,46.17 260.19,46.06 259.99,46.06 CN27.2
PCIE_PRX_C_RD_DTX_N12: length 2
  TOP w0.094: v1(290.41,53.05) 290.58,53.21 290.58,53.49 290.39,53.68 UN5.4
  BOTTOM w0.094: CN37.2 290.41,52.82 v1(290.41,53.05)
PCIE_PRX_C_RD_DTX_P8: length 1.7
  TOP w0.094: CZ141.2 284.15,63.49 284.71,63.49 284.87,63.33 UZ36.5
PCIE_PRX_C_RD_DTX_P11: length 2.4
  TOP w0.094: CN26.2 259.93,45.87 260.27,45.87 260.49,46.09 260.49,46.25 260.65,46.42 260.88,46.42 261.03,46.26 UN4.5
PCIE_PRX_C_RD_DTX_P12: length 2
  TOP w0.094: v1(291,53.05) 290.76,53.28 290.76,53.52 290.89,53.64 UN5.5
  BOTTOM w0.094: CN36.2 290.64,52.43 290.64,52.69 v1(291,53.05)
PCIE_PRX_DTX_N1: length 5.7
  TOP w0.094: CR14.1 31.69,51.83 31.78,51.74 31.78,51.48 31.86,51.41 33.17,51.41 33.2,51.43 35.44,51.43 35.83,51.83 v1(36,51.83)
  BOTTOM w0.094: v1(129.79,65.3) 129.85,65.31 130.22,65.1 UC1.H13
PCIE_PRX_DTX_N3: length 31
  BOTTOM w0.094: UC1.H16 v1(127.95,65.29) ; JNGFF1.35 200.48,14.25 200.31,14.42 196.87,14.42 194.01,17.27 194.01,26.19 187.17,33.04 187.17,36.07 v1(186.91,36.33)
PCIE_PRX_DTX_N4: length 37
  BOTTOM w0.076: UC1.G15 129.06,65.95 v1(128.87,65.95)
  BOTTOM w0.094: JNGFF1.59 198.7,8.25 198.69,8.25 198.38,8.25 198.38,8.25 197.88,8.25 196.5,9.63 196.5,10.16 196.49,10.17 196.49,10.8 196.5,10.81 196.5,11.12 191.24,16.38 191.24,17.8 190.47,18.57 190.47,26.33 184.49,32.32 184.49,35.42 v1(184.27,35.64)
PCIE_PRX_DTX_N8: length 1.5
  TOP w0.094: v1(282.21,63.91) 282.36,63.75 282.75,63.75 282.88,63.89 CZ142.1
  BOTTOM w0.094: UC1.G21 v1(125.18,65.95)
PCIE_PRX_DTX_N9: length 7.6
  TOP w0.094: v1(278.88,75.26) 278.88,75.09 278.78,75 278.6,75 278.47,75.13 278.47,75.94 278.03,76.37 277.45,76.37 277.05,76.77 v4(277.05,77.02) 277.05,77.45 276.18,78.32 276.18,78.57 275.78,78.98 275.78,79.4 275.95,79.57 CL2.1
  BOTTOM w0.094: v1(124.24,66.61) UC1.E22
PCIE_PRX_DTX_N11: length 2.8
  TOP w0.094: v1(257.43,44.9) 257.61,45.09 257.61,45.82 257.97,46.18 258.3,46.18 CN27.1
  BOTTOM w0.094: UC1.E28 v1(120.63,67.21)
PCIE_PRX_DTX_N12: length 12.5
  BOTTOM w0.076: UC1.E30 120.09,66.91 119.98,66.91 119.7,67.19 v1(119.7,67.23)
  BOTTOM w0.094: CN37.1 290.15,51.38 290.29,51.24 290.29,50.74 290.16,50.61 289.85,50.61 289.03,51.43 288.11,51.43 287.48,50.8 286.06,50.8 285.72,51.14 282.84,51.14 282.83,51.15 282.18,51.15 282.17,51.14 280.9,51.14 280.8,51.23 280.8,51.46 280.9,51.55 v1(281.08,51.55)
PCIE_PRX_DTX_P1: length 5.1
  TOP w0.094: CR13.1 31.66,51.22 33.25,51.22 33.28,51.25 v1(35.82,51.25)
  BOTTOM w0.094: v1(129.79,65.94) 129.81,65.88 UC1.G13
PCIE_PRX_DTX_P3: length 31.1
  BOTTOM w0.094: v1(127.92,66) UC1.G16 ; v1(187.76,36.31) 187.71,36.37 187.46,36.37 187.35,36.26 187.35,33.11 194.2,26.27 194.2,17.35 196.95,14.6 200.29,14.6 200.44,14.75 JNGFF1.33
PCIE_PRX_DTX_P4: length 37
  BOTTOM w0.094: JNGFF1.57 200.56,8.75 200.26,8.45 197.94,8.45 196.68,9.7 v4(196.68,10.48) 196.68,11.19 191.43,16.45 191.43,17.88 190.66,18.65 190.66,26.41 184.67,32.39 184.67,35.61 184.76,35.71 v1(184.95,35.71) ; UC1.F15 129.14,66.34 v1(128.85,66.63)
PCIE_PRX_DTX_P8: length 1.8
  TOP w0.094: v1(282.21,63.32) 282.46,63.57 282.78,63.57 282.88,63.47 CZ141.1
  BOTTOM w0.094: UC1.F21 125.6,66.51 125.35,66.64 v1(125.18,66.58)
PCIE_PRX_DTX_P9: length 7.5
  TOP w0.094: CL1.1 275.59,79.19 275.59,78.9 276,78.49 276,78.24 276.83,77.41 276.83,76.71 276.97,76.57 276.99,76.57 277.37,76.19 277.96,76.19 278.28,75.86 278.28,75.06 v1(278.85,74.49)
  BOTTOM w0.094: v1(124.23,67.32) 124.21,67.16 123.99,66.98 UC1.E23
PCIE_PRX_DTX_P11: length 2.7
  TOP w0.094: CN26.1 258.63,45.77 258.4,45.99 258.05,45.99 257.8,45.74 257.8,45.12 v1(258.01,44.9)
  BOTTOM w0.094: UC1.E27 v1(121.54,67.2)
PCIE_PRX_DTX_P12: length 12.5
  BOTTOM w0.076: v1(119.74,66.62) 119.89,66.62 UC1.F30
  BOTTOM w0.094: v1(280.37,51.3) 280.46,51.3 280.81,50.95 v4(282.5,50.95) 285.64,50.95 285.99,50.61 287.56,50.61 288.19,51.24 288.95,51.24 289.77,50.42 290.24,50.42 290.47,50.66 290.47,51.08 CN36.1
PCIE_PRX_RD_DTX_N8: length 19.3
  TOP w0.094: v1(290.41,63.89) 290.31,63.78 289.75,63.78 289.7,63.83 UZ36.15
  BOTTOM w0.094: JNGFF2.35 297.3,43.38 297.5,43.58 297.5,45.25 296.88,45.87 288.29,45.87 287.66,45.25 284.52,45.25 v4(284.28,45.01) 284.06,44.79 v1(284.06,44.17)
PCIE_PRX_RD_DTX_N11: length 2.1
  TOP w0.094: v1(266.53,46.81) 266.32,46.6 265.89,46.6 265.74,46.76 UN4.15
  BOTTOM w0.094: RN82.2 282.4,42.97 282.29,42.97 v1(282.08,43.17)
PCIE_PRX_RD_DTX_N12: length 2.2
  TOP w0.094: v1(290.32,58.89) 290.53,58.68 290.53,58.5 290.39,58.36 UN5.15
  BOTTOM w0.094: v1(284.42,38.6) 285.13,38.6 285.36,38.37 RN78.2
PCIE_PRX_RD_DTX_P8: length 19.3
  TOP w0.094: UZ36.14 289.7,63.33 289.77,63.4 289.77,63.5 289.86,63.6 290.12,63.6 v1(290.41,63.3)
  BOTTOM w0.094: JNGFF2.33 296.8,42.61 296.89,42.7 297.02,42.7 297.11,42.8 297.11,43.46 297.31,43.66 297.31,45.17 296.8,45.69 288.36,45.69 287.74,45.07 284.61,45.07 284.27,44.72 284.27,44.55 v1(284.65,44.17)
PCIE_PRX_RD_DTX_P11: length 2.1
  TOP w0.094: v1(266.53,46.23) 266.34,46.42 265.91,46.42 265.75,46.26 UN4.14
  BOTTOM w0.094: v1(282.08,42.59) 282.28,42.78 282.41,42.78 RN81.2
PCIE_PRX_RD_DTX_P12: length 2.4
  TOP w0.094: v1(290.91,58.89) 290.72,58.7 290.72,58.51 290.89,58.34 UN5.14
  BOTTOM w0.094: v1(284.42,39.18) 284.82,38.78 285.2,38.78 285.36,38.94 RN77.2
PCIE_PTX_C_DRX_N1: length 2.9
  TOP w0.094: UR1.4 28.21,49.86 28.31,49.75 28.6,49.75 28.72,49.63 28.91,49.63 28.91,49.64 29.57,49.64 29.57,49.63 30.11,49.63 CR12.2
PCIE_PTX_C_DRX_N3: length 2.9
  BOTTOM w0.094: CZ13.2 199.15,16.19 199.3,16.19 199.57,15.91 199.58,15.91 200.35,15.91 200.51,15.75 JNGFF1.29
PCIE_PTX_C_DRX_N4: length 2.9
  BOTTOM w0.094: CZ15.2 199.14,10.09 199.26,10.09 199.43,9.91 199.44,9.91 200.2,9.91 200.35,9.75 JNGFF1.53
PCIE_PTX_C_DRX_N8: length 20
  BOTTOM w0.094: v1(294.84,61.08) 295.12,60.81 295.31,60.81 295.5,61 295.5,62.33 294.99,62.85 294.99,64.77 293.74,66.02 293.37,66.02 293.2,65.84 CZ10.2 ; v1(290.43,47.98) 290.69,47.72 290.69,47.59 290.89,47.38 291.49,47.38 292.51,46.37 297.24,46.37 298.4,45.21 298.4,42.71 298.3,42.61 JNGFF2.39
PCIE_PTX_C_DRX_N9: length 2.4
  TOP w0.094: CL6.2 277.83,80.91 277.83,81.01 277.95,81.13 v4(277.95,81.45) 277.95,81.87 278.06,81.97 UL1.42
PCIE_PTX_C_DRX_N11: length 19.5
  BOTTOM w0.094: JNGFF3.35 299.45,34.67 299.38,34.74 299.38,35 298.42,35.95 297.42,35.95 295.05,38.33 293.76,38.33 293.62,38.18 293.14,38.18 293.1,38.21 292.5,38.21 292.48,38.18 292.41,38.18 292.4,38.18 291.04,38.18 290.05,39.17 v4(289.4,39.17) 288.9,39.17 288.24,39.82 284.22,39.82 283.77,39.37 283.64,39.37 283.48,39.53 CN69.1
PCIE_PTX_C_DRX_N12: length 15.1
  BOTTOM w0.094: CN71.1 283.76,37.33 284.26,37.33 284.99,36.61 285.37,36.61 285.37,36.61 286.01,36.61 286.02,36.61 v4(289.76,36.61) 292.15,36.61 293.42,35.34 295.98,35.34 296.32,35 296.32,34.77 296.45,34.64 JNGFF3.47
PCIE_PTX_C_DRX_P1: length 2.9
  TOP w0.094: UR1.3 28.16,49.46 28.27,49.57 28.52,49.57 28.64,49.45 v4(29.24,49.45) 30.13,49.45 CR11.2
PCIE_PTX_C_DRX_P3: length 2.9
  BOTTOM w0.094: JNGFF1.27 200.46,16.25 200.3,16.09 199.65,16.09 199.37,16.37 199.14,16.37 CZ12.2
PCIE_PTX_C_DRX_P4: length 2.9
  BOTTOM w0.094: CZ14.2 199.14,10.27 199.34,10.27 199.52,10.09 200.2,10.09 200.35,10.25 JNGFF1.51
PCIE_PTX_C_DRX_P8: length 20.4
  BOTTOM w0.094: v1(291.01,47.98) 290.87,47.84 290.87,47.66 290.96,47.57 291.57,47.57 292.59,46.55 297.32,46.55 298.58,45.29 298.58,42.74 298.8,42.52 JNGFF2.41 ; v1(294.84,60.5) 294.96,60.62 295.39,60.62 295.69,60.92 295.69,62.41 295.17,62.92 295.17,64.84 293.81,66.2 293.56,66.2 CZ11.2
PCIE_PTX_C_DRX_P9: length 2.4
  TOP w0.094: UL1.41 277.66,81.97 277.67,81.97 277.77,81.87 277.77,81.78 277.74,81.75 277.74,81.18 277.65,81.09 277.65,80.89 CL5.2
PCIE_PTX_C_DRX_P11: length 19.5
  BOTTOM w0.094: CN70.1 283.48,39.09 283.58,39.19 283.85,39.19 284.3,39.63 288.17,39.63 288.82,38.98 289.07,38.98 289.11,38.95 289.69,38.95 289.73,38.98 289.97,38.98 290.96,37.99 v4(292.8,37.99) 293.69,37.99 293.84,38.14 294.98,38.14 297.35,35.77 298.35,35.77 299.2,34.92 299.2,34.81 298.95,34.57 JNGFF3.37
PCIE_PTX_C_DRX_P12: length 15
  BOTTOM w0.094: JNGFF3.49 295.95,34.61 296.14,34.79 296.14,34.92 295.91,35.15 293.34,35.15 292.07,36.42 290.08,36.42 290.05,36.39 289.46,36.39 289.43,36.42 v4(285.69,36.42) 284.91,36.42 284.19,37.14 283.58,37.14 283.48,37.04 CN72.1
PCIE_PTX_C_RD_DRX_N8: length 2
  TOP w0.094: UZ36.2 285.05,64.83 284.87,65.01 284.58,65.01 284.16,65.42 283.89,65.42 283.8,65.33 CZ136.2
PCIE_PTX_C_RD_DRX_N11: length 2
  TOP w0.094: CN23.2 259.94,47.92 260.76,47.92 260.92,47.76 UN4.2
PCIE_PTX_C_RD_DRX_N12: length 4
  TOP w0.094: v1(289.29,52.99) 289.22,53.06 289.22,53.46 289.39,53.62 UN5.2
  BOTTOM w0.094: CN33.2 287.3,51.61 287.54,51.84 v4(288.28,51.84) 288.68,51.84 289.19,52.34 289.19,52.89 v1(289.29,52.99)
PCIE_PTX_C_RD_DRX_P8: length 2
  TOP w0.094: CZ135.2 283.8,65.73 283.92,65.61 284.24,65.61 284.66,65.19 284.83,65.19 284.97,65.33 UZ36.1
PCIE_PTX_C_RD_DRX_P11: length 2.1
  TOP w0.094: CN22.2 259.54,48.52 259.96,48.1 260.76,48.1 260.92,48.26 UN4.1
PCIE_PTX_C_RD_DRX_P12: length 4.1
  TOP w0.094: UN5.1 288.89,53.62 289.04,53.47 289.04,53.32 288.71,52.99 288.68,52.99 288.68,53 v1(288.69,53)
  BOTTOM w0.094: CN32.2 287.28,52.12 287.38,52.02 287.9,52.02 287.91,52.03 288.61,52.03 289,52.42 289,52.7 288.71,52.99 288.68,52.99 288.68,53 v1(288.69,53)
PCIE_PTX_DRX_N1: length 9
  TOP w0.094: CR12.1 31.77,49.61 33.85,49.61 v1(34.07,49.82)
  BOTTOM w0.076: UC1.B17 128.17,69.65 128.17,71.24 128.55,71.62 128.55,73.57 128.56,73.58 128.56,73.6
  BOTTOM w0.094: 128.56,73.6 128.56,73.81 128.31,74.06 128.31,74.5 128.4,74.59 128.5,74.59 v1(128.54,74.63)
PCIE_PTX_DRX_N3: length 31.7
  BOTTOM w0.076: v1(127.57,71.58) 127.36,71.38 127.2,71.38 127.02,71.2 127.02,70.49 127.38,70.14 127.42,69.59 127.42,69.56 127.45,69.49 127.45,69.29 127.42,69.17 127.42,68.97 127.46,68.82 127.5,68.69 127.57,68.47 127.57,68.36 127.64,68.09 UC1.D17
  BOTTOM w0.094: v1(186.9,38.15) 187.07,37.97 187.07,37.33 187.27,37.13 187.6,37.13 187.93,36.8 188.44,36.3 188.44,32.71 194.63,26.52 194.63,18.56 197.14,16.05 197.52,16.05 CZ13.1
PCIE_PTX_DRX_N4: length 40.8
  BOTTOM w0.076: v1(127.33,72.74) 127.18,72.59 126.87,72.59 126.6,72.32 126.6,70.52 125.94,69.86 125.94,69.46 126.19,69.21 126.36,69.21 UC1.B19
  BOTTOM w0.094: v1(184.82,38.63) 185.02,38.43 185.02,38.19 185.57,37.64 185.57,32.08 192.69,24.95 192.69,22.65 191.89,21.84 191.6,21.84 191.1,21.34 191.1,19.46 192.33,18.23 192.33,16.3 197.11,11.51 197.11,10.27 197.31,10.07 197.57,10.07 197.81,9.83 CZ15.1
PCIE_PTX_DRX_N8: length 9.4
  TOP w0.094: v1(279.13,65.6) 279.37,65.84 280.07,65.84 280.87,66.63 281.49,66.63 281.55,66.57 281.55,66.52 281.96,66.11 281.99,66.11 282.05,66.06 282.05,65.74 282.37,65.41 282.72,65.41 282.88,65.25 CZ136.1
  BOTTOM w0.076: v1(124.46,70.84) 124.46,71 124.64,71.18 124.86,71.18 124.95,71.08 124.95,69.58 124.98,69.48 124.98,69.29 124.95,69.2 124.95,68.95 125.09,68.47 125.09,68.36 125.16,68.09 UC1.D21
PCIE_PTX_DRX_N9: length 5.5
  TOP w0.094: CL6.1 278.03,79.57 277.86,79.4 277.86,79.1 277.66,78.9 277.59,78.9 277.26,78.57 277.26,78.43 v1(277.41,78.28)
  BOTTOM w0.076: v1(123.5,71.77) 123.5,71.67 123.32,71.49 123.15,71.49 122.98,71.32 122.98,70.75 123.55,70.18 123.55,69.6 123.55,69.4 123.73,69.21 123.88,69.21 UC1.B23
PCIE_PTX_DRX_N11: length 19.5
  TOP w0.094: CN23.1 258.23,47.92 257.48,47.92 257.25,48.15 256.43,48.15 255.98,47.71 255.98,43.91 253.58,41.5 253.58,39.02 253.98,38.62 v1(254.24,38.62)
  BOTTOM w0.076: UC1.D24 123.17,68.61 123.17,70.07 122.58,70.66 122.58,71.76 123.44,72.62 123.82,72.62 123.9,72.7 v1(123.9,72.94)
PCIE_PTX_DRX_N12: length 10.7
  BOTTOM w0.076: UC1.A25 122.92,69.71 123,69.8 123,69.98 122.92,70.06 122.79,70.06 122.61,69.88 122.53,69.88 122.47,69.95 122.35,70.12 122.35,71.83 122.85,72.33 122.85,73.04 122.57,73.32 122.37,73.32 122.15,73.54 v1(122.15,73.6)
  BOTTOM w0.094: CN33.1 286.2,51.64 282.07,51.64 281.59,52.12 v1(281.28,52.12)
PCIE_PTX_DRX_P1: length 8.9
  TOP w0.094: CR11.1 31.39,49.17 31.64,49.42 33.89,49.42 v1(34.07,49.24)
  BOTTOM w0.076: 128.38,73.6 128.38,73.58 128.39,73.57 128.39,71.69 128.01,71.31 128.01,70.16 127.95,70.11 127.82,70.11 127.75,70.03 127.75,69.76 127.8,69.71 UC1.A17
  BOTTOM w0.094: 128.38,73.6 128.38,73.74 128.12,73.99 128.12,74.59 127.99,74.73 127.85,74.73 v1(127.68,74.56)
PCIE_PTX_DRX_P3: length 31.7
  BOTTOM w0.076: v1(127.61,70.76) 127.73,70.76 127.82,70.85 127.82,71.12 127.73,71.21 127.27,71.21 127.19,71.13 127.19,70.56 127.54,70.21 127.54,70.15 127.58,69.6 127.62,69.53 127.62,69.27 127.58,69.15 127.58,68.99 127.64,68.81 127.73,68.75 127.87,68.75 127.95,68.66 127.95,68.51 UC1.C17
  BOTTOM w0.094: v1(187.48,38.15) 187.25,37.92 187.25,37.41 187.35,37.32 187.68,37.32 188.62,36.37 188.62,32.79 194.82,26.6 194.82,18.64 197.21,16.24 197.61,16.24 197.81,16.44 CZ12.1
PCIE_PTX_DRX_P4: length 40.7
  BOTTOM w0.076: v1(127.33,72.16) 127.33,72.23 127.14,72.42 126.93,72.42 126.77,72.26 126.77,70.45 126.11,69.79 126.11,69.52 126.26,69.38 126.57,69.38 126.64,69.45 126.64,69.58 UC1.A19
  BOTTOM w0.094: CZ14.1 197.81,10.38 197.69,10.25 197.39,10.25 197.3,10.35 197.3,11.59 192.51,16.38 192.51,18.31 191.28,19.54 191.28,21.27 191.68,21.66 191.96,21.66 192.88,22.57 192.88,25.03 185.75,32.16 185.75,37.72 185.2,38.26 185.2,38.49 185.25,38.54 185.25,38.68 185.35,38.77 v1(185.45,38.77)
PCIE_PTX_DRX_P8: length 9.5
  TOP w0.094: CZ135.1 282.88,65.76 282.72,65.6 282.45,65.6 282.23,65.82 282.23,66.15 v4(281.91,66.47) 281.56,66.82 280.79,66.82 280,66.02 279.29,66.02 v1(279.13,66.18)
  BOTTOM w0.076: v1(124.46,71.53) 124.65,71.34 124.92,71.34 125.11,71.15 125.11,69.61 125.15,69.54 125.15,69.26 125.11,69.15 125.11,68.98 125.17,68.8 125.26,68.74 125.52,68.74 125.69,68.57 125.69,68.42 125.62,68.34 125.45,68.34 UC1.C21
PCIE_PTX_DRX_P9: length 5.5
  TOP w0.094: CL5.1 277.46,79.57 277.67,79.36 277.67,79.18 277.58,79.08 277.51,79.08 277.07,78.64 277.07,78.53 v1(276.83,78.28)
  BOTTOM w0.076: v1(123.61,71.09) 123.36,71.33 123.22,71.33 123.14,71.25 123.14,70.82 123.71,70.25 123.71,69.49 123.82,69.38 124.1,69.38 124.2,69.48 124.2,69.62 124.11,69.71 UC1.A23
PCIE_PTX_DRX_P11: length 19.7
  TOP w0.094: CN22.1 258.2,48.1 257.56,48.1 257.33,48.34 256.35,48.34 255.8,47.79 255.8,43.99 253.39,41.58 253.39,38.95 253.83,38.51 v1(253.83,38.21)
  BOTTOM w0.076: UC1.C24 123.47,68.7 123.56,68.61 123.7,68.61 123.79,68.7 123.79,68.89 123.58,69.09 123.41,69.09 123.34,69.16 123.34,70.14 122.74,70.73 122.74,71.69 123.51,72.46 123.82,72.46 123.9,72.38 v1(123.9,72.25)
PCIE_PTX_DRX_P12: length 10.6
  BOTTOM w0.076: v1(122.18,72.83) 122.18,73.05 122.28,73.16 122.5,73.16 122.69,72.97 122.69,72.4 122.18,71.89 122.18,70.06 122.51,69.61 UC1.B25
  BOTTOM w0.094: v1(281.69,52.53) 281.69,52.28 282.14,51.83 285.92,51.83 286.37,52.27 CN32.1
PCIE_PTX_RD_DRX_N8: length 4
  TOP w0.094: v1(290.43,64.8) 290.23,65 289.87,65 289.71,64.83 UZ36.17
  BOTTOM w0.094: CZ10.1 291.9,66 291.56,66 291.22,65.66 291.22,65.27 290.94,65 290.63,65 v1(290.43,64.8)
PCIE_PTX_RD_DRX_N11: length 9.5
  TOP w0.094: UN4.17 265.73,47.76 266.04,48.07 266.64,48.07 266.81,48.24 269.53,48.24 269.8,47.97 269.8,46.3 270.65,45.44 270.65,45.26 270.55,45.16 270.31,45.16 v1(270,45.46)
  BOTTOM w0.094: CN69.2 282.57,39.54 282.15,39.12 282.02,39.12 281.92,39.22 v1(281.92,39.24)
PCIE_PTX_RD_DRX_N12: length 2
  TOP w0.094: UN5.17 289.39,58.32 289.05,58.65 v1(289.05,58.98)
  BOTTOM w0.094: CN71.2 282.57,37.44 282.45,37.32 282.08,37.32 v1(281.93,37.48)
PCIE_PTX_RD_DRX_P8: length 4
  TOP w0.094: v1(290.43,65.38) 290.23,65.18 289.86,65.18 289.7,65.33 UZ36.18
  BOTTOM w0.094: CZ11.1 291.9,66.18 291.47,66.18 v4(291.27,65.98) 291.03,65.75 291.03,65.35 290.86,65.18 290.63,65.18 v1(290.43,65.38)
PCIE_PTX_RD_DRX_P11: length 9.7
  TOP w0.094: v1(270,44.88) 270.1,44.97 270.62,44.97 270.83,45.18 270.83,45.52 269.98,46.37 269.98,48.05 269.6,48.42 266.73,48.42 266.57,48.26 UN4.18
  BOTTOM w0.094: v1(281.92,38.66) 282.15,38.88 282.44,38.88 CN70.2
PCIE_PTX_RD_DRX_P12: length 2.2
  TOP w0.094: UN5.18 288.89,58.57 v1(288.47,58.98)
  BOTTOM w0.094: v1(281.91,36.89) 282.05,37.03 282.05,37.03 282.16,37.13 282.42,37.13 282.57,36.99 CN72.2
PCIE_RCOMPN: length 3.3
  TOP w0.381: RC45.1 132.33,67.64 v2(133,66.97) 133.12,67.1 133.68,67.1 134.2,66.58 v1(134.35,66.58)
  BOTTOM w0.254: v1(134.35,66.58) UC1.F5
PCIE_RCOMPP: length 1.9
  TOP w0.381: v1(134.35,67.21) 133.69,67.87 RC45.2
  BOTTOM w0.254: v1(134.35,67.21) UC1.E5
PCIE_WAKE#: length 89
  TOP w0.102: v1(307.13,66.59) 307.13,66.83 307.51,67.2 RE275.1 307.51,67.51 308.31,68.31 RE274.1
  BOTTOM w0.102: JNGFF2.46 300.05,51.38 302.02,53.36 v1(302.36,53.36) ; 205.76,7.5 203.74,9.51 203.74,11.12 203.61,11.25 JNGFF1.47 ; 205.76,7.5 JNGFF1.62 ; 205.76,7.5 205.36,7.11 205.36,4.59 205.85,4.1 208.88,4.1 209.13,3.86 221.53,3.86 225.32,7.64 v1(225.32,11.42) ; JNGFF3.54 294.7,25.57 294.01,24.88 v2(285.77,24.88) 268.51,24.88 265.78,22.16 260.04,22.16 258.49,23.71 v1(254.73,23.71)
PCIE_WAKE#_R: length 9.7
  TOP w0.102: v1(311.86,69.14) 311.86,67.09 311.28,66.52 v2(309.01,66.52) 308.97,66.52 308.42,67.06 RE275.2 ; RE35.1 306.58,82.71 v1(306.42,82.54) 306.18,82.54 UE1.N13
PD1_GPIO2: length 2.7
  TOP w0.102: UT5.D10 33.64,78.57 34.07,79 34.08,79 v1(34.13,79.05)
  BOTTOM w0.102: RT71.1 33.43,79.75 v1(34.13,79.05) 34.41,79.05 v2(34.65,79.29)
PD1_GPIO6: length 5.5
  TOP w0.076: UT5.G10 32.14,78.47 31.9,78.22 31.9,76.75
  TOP w0.102: v2(30.74,73.93) 30.49,74.19 30.49,75.6 RT75.1 31.49,76.6 31.75,76.6 31.9,76.75
PD1_GPIO7: length 5.3
  TOP w0.102: v1(34.15,79.72) 33.83,80.04 UT5.D7
  BOTTOM w0.102: v2(37.47,80.16) 37.39,80.08 RT339.1 35.59,79.01 34.88,79.72 v1(34.15,79.72)
PD1_GPIO8: length 5.3
  TOP w0.076: UT5.H6 v1(31.16,80.54)
  BOTTOM w0.102: v1(31.16,80.54) 30.5,80.54 RT377.1 30.22,80.54 RT76.1 28.54,80.54 27.91,79.9 v2(26.74,79.9)
PD#: length 8.3
  TOP w0.102: v2(297.05,43.48) 296.61,43.48 296.26,43.12 RA48.2 296.87,42.36 RA50.2 295.75,42.26 DA8.2 295.51,41.43 RA18.1 296.8,40.14 CA31.1 297.8,38.9 UA1.47
PDA_RESET#_R: length 2.5
  TOP w0.203: UT5.F11 32.64,77.52 32.66,77.5 v1(32.66,77.49)
  BOTTOM w0.102: v2(31.69,78.06) 32.09,78.06 v1(32.66,77.49)
  BOTTOM w0.254: v1(32.66,77.49) 32.63,77.46 RT110.2
PECI_EC: length 62.5
  TOP w0.102: v1(106.94,80.41) 107.56,80.41 108.53,81.37 109.86,81.37 110.57,82.09 110.57,83.24 114.14,86.8 114.14,87.31 115.67,88.84 122.16,88.84 122.53,88.48 125.67,88.48 131.17,93.98 141.08,93.98 142.02,93.04 143.76,93.04 v2(144.09,93.37) 144.69,93.97 145.7,93.97 v1(147.85,96.12) ; RE60.2 302.71,85.31 v1(302.74,85.35)
  BOTTOM w0.076: UC1.A54 106.68,70.06 106.75,70.12 106.75,70.81 106.42,71.14 105.91,71.14 105.75,71.3 105.75,73.1 106.99,74.34 106.99,75.84 106.41,76.41
  BOTTOM w0.102: 106.41,76.41 106.41,78.74 106.94,79.27 v1(106.94,80.41)
PECI_EC_R: length 3.2
  TOP w0.102: RE60.1 303.54,82.97 v2(303.54,82.9) 303.13,82.9 302.82,82.59 302.82,81.59 UE1.K13
PGOOD_3V: length 3.6
  TOP w0.102: v2(152.47,115.16) PR107.2
  TOP w0.254: PU100.9 154.99,114.25 154.31,114.93 PR119.1 153.41,115.16 PR107.2
PGOOD_5V: length 4.9
  BOTTOM w0.102: v2(170.52,119.47) 170.52,117.95 PR113.2
  BOTTOM w0.254: PR113.2 170.06,117.51 PR120.1 168.54,116.86 168.39,116.86 168.14,116.6 PU102.9
PLTRST_LAN#: length 28.4
  TOP w0.102: UL1.36 274.92,83.42 274.83,83.33 274.83,82.95 273.03,81.15 271.75,81.15 271.37,80.77 v1(270.47,80.77)
  BOTTOM w0.102: v1(182.31,54.03) 179.78,54.03 178.04,52.29 v2(173.09,52.29) 164.77,52.29 164.76,52.29 162.09,52.29 161.41,52.96 RC62.2
PLTRST_TPM#: length 23.6
  TOP w0.102: UZ12.17 164.05,39.17 163.82,39.4 v1(163.82,39.89)
  BOTTOM w0.102: v1(163.82,39.89) 160.61,36.67 158.4,36.67 155.34,39.73 155.34,41.51 156.66,42.83 v2(156.66,48.02) RC325.2 RC60.2
PM_LANPHY_ENABLE: length 74.7
  TOP w0.102: RL7.1 282.21,79 v1(282.33,78.89)
  BOTTOM w0.076: UC1.AW17 127.72,48.94 127.55,48.76 127.55,48.76 127.33,48.06 127.33,47.98 127.28,47.82 127.28,47.68 127.34,47.46 127.34,47.34 127.29,47.23 127.29,46.86 127.49,46.67 127.49,45.15 128.84,43.79 128.84,43.45 128.84,43.45
  BOTTOM w0.102: v1(178.7,22.46) 178.64,22.52 135.41,22.52 130.43,27.5 130.43,29.22 130.05,29.6 130.05,36.39 130.79,37.13 130.79,38.65 128.84,40.6 v2(128.84,41.74) 128.84,43.45
PME#: length 1.2
  TOP w0.102: v1(130.62,49.88) 130.62,49.61 T115.1
  BOTTOM w0.102: UC1.AU11 130.95,50.2 v1(130.62,49.88)
POA_WAKE#: length 28.9
  TOP w0.102: JUSH1.4 224.29,8.65 226.88,11.23 226.88,17.54 223.14,21.28 v1(223.14,23.51) 223.14,23.63 v3(223.49,23.97) ; v1(292.49,69.36) 292.13,69 RE324.1
  TOP w0.107: v1(298.36,73.93) UE1.E4
  BOTTOM w0.102: v1(292.49,69.36) 292.54,69.36 293.64,70.47 295.64,70.47 297.96,72.79 297.96,73.53 v1(298.36,73.93)
PORT80_DET#: length 16
  TOP w0.102: v2(310.16,69.89) 309.86,70.2 v1(309.5,70.2) RE512.1 ; v1(297.69,52.98) 297.31,52.6 297.31,51.34 RZ131.1
  TOP w0.107: v1(303.16,73.93) UE1.K4
  BOTTOM w0.102: v1(303.16,73.93) 302.94,73.93 302.75,73.74 302.75,70.83 303.58,70.01 RE513.1 307.28,70.01 307.47,70.2 v1(309.5,70.2)
POWER_SW#_MB: length 7.1
  TOP w0.254: SW3.4 319.91,96.55 v1(319.92,96.54) 320.05,96.54 320.06,96.55 SW3.2 ; RE33.2 CE10.1 284.76,69.92 v1(284.21,70.48)
  BOTTOM w0.254: JAPS1.11 v1(318.78,67.25)
POWER_SW_IN#: length 4.3
  TOP w0.127: CE12.1 v2(288.88,70.83)
  TOP w0.254: v1(285.98,71.5) 285.88,71.4 RE33.1 RE31.2 CE12.1 ; v1(297.56,74.7) 297.96,75.1 UE1.D5
PRIM_PWRGD_GPIO024: length 5.5
  TOP w0.102: UE1.C1 297.16,71.6 296.96,71.39 v2(296.96,70.53) 296.96,69.75 297.05,69.66 RE362.1 RE361.1
PROCHOT#_ISL88738: length 7.5
  TOP w0.203: PU901.23 15.49,15.96 ; PQ1216.1 10.29,15.32 12.97,15.32 13.21,15.09 PR926.2
  TOP w0.254: PR926.2 13.7,14.79 14.46,15.55 15.08,15.55 v2(15.3,15.77) 15.49,15.96
PROG1_CPU: length 3.4
  TOP w0.203: PU602.32 71.69,48.78 72.42,48.05 v2(73.35,48.05) 73.42,47.97 PR608.1
PROG2_CPU: length 3.1
  TOP w0.203: PR611.1 72.32,46.89 v2(72.32,47.14) 72.32,47.59 71.53,48.38 PU602.31
PS8348B_CFG: length 7.8
  TOP w0.102: UV7.21 105.21,92.58 106.11,91.68 106.35,91.68 106.81,91.22 106.81,90 106.9,89.91 v2(106.9,89.71) 106.9,88.89 RV86.1 107.35,88.27 107.35,87.05 RV85.1
PS8348B_PC1: length 8.3
  TOP w0.102: RV83.1 RV84.1 108.19,87.89 108.46,88.16 108.46,89.99 v2(107.21,91.24) 106.46,91.99 106.23,91.99 105.61,92.61 UV7.22
PS8348B_PC2: length 8.3
  TOP w0.102: UV7.23 106.01,92.5 106.25,92.26 106.72,92.26 v2(108.61,90.37) 108.72,90.26 108.72,88.54 RV82.1 108.84,87.39 RV81.1
PS8348B_PC3: length 6.2
  TOP w0.102: v1(100.86,99.9) 100.86,99.8 101.17,99.48 101.17,99.02 101.61,98.59 UV7.45
  BOTTOM w0.102: v1(100.86,99.9) 100.86,100.15 100.67,100.35 100.67,101.8 RV80.1 RV79.1 v2(102.56,101.87)
PS8348B_PEQ: length 9.7
  TOP w0.102: RV87.1 RV88.1 ; RV88.1 105.03,87.02 105.03,90.2 105.16,90.33 105.16,90.56 104.27,91.45 104.27,91.92 104.01,92.19 UV7.18 ; RV88.1 103.96,85.95 v2(103.56,85.95)
PS8348B_PI0: length 8.3
  TOP w0.102: RV96.1 RV95.1 92.97,89.24 v2(93.43,89.69) 93.54,89.81 95.61,89.81 97.61,91.8 UV7.2
PS8348B_PI1: length 6.7
  TOP w0.102: UV7.3 v2(98.01,91.88) 98.01,91.59 95.84,89.43 95.51,89.43 RV93.1 94.86,88.8 93.87,88.8 RV94.1
PS8348B_SW0: length 5.4
  TOP w0.102: UV7.5 98.81,90.44 v2(98.4,90.04) 97.92,89.55 RV90.1 98.19,88.79 RV89.1
PS8348B_SW1: length 5.7
  TOP w0.102: RV91.1 96.7,88.79 RV92.1 96.97,89.87 v2(97.11,90.01) 98.41,91.31 UV7.4
PS_ID: length 6.1
  TOP w0.102: v1(66.12,89.18) v2(66.12,92.27) 65.61,92.78 PR5.2 64.94,92.78 PR4.1
  TOP w0.107: UE1.L11 303.99,80.35 v1(303.99,80.39)
PWM1_GT: length 4.3
  TOP w0.102: v1(64.88,52.01) 64.87,52.01 v2(64.52,52.37)
  TOP w0.203: v1(64.88,52.01) 65.31,51.58 PU602.12
  BOTTOM w0.203: PU612.8 58.36,67.14 PR680.1
  BOTTOM w0.254: PR680.1 57.92,67.2 v1(57.66,66.95)
PWM_IA: length 4.2
  TOP w0.203: v1(66.43,46.83) 67.03,46.83 67.36,47.16 PU602.22
  BOTTOM w0.102: v1(66.43,46.83) 66.88,46.83 v2(67.01,46.96)
  BOTTOM w0.254: PU610.8 58.34,71.83 v1(57.65,72.52) PR662.1
PWM_SA: length 2.8
  BOTTOM w0.102: v2(67.32,81.22) 67.86,80.68 PR606.2
  BOTTOM w0.254: PR606.2 67.86,80.09 68.09,79.86 PU614.3
PWM_VSA: length 2.8
  TOP w0.203: PU602.30 70.56,46.95 v1(70.95,46.56)
  BOTTOM w0.102: v1(68.52,81.08) v2(68.52,81.7)
  BOTTOM w0.254: v1(68.52,81.08) 68.78,80.83 PR606.1
RD1_A_DE0: length 4.9
  TOP w0.102: UN4.6 260.83,45.76 RN38.1 258.83,43.76 RN25.2 257.96,43.15 v2(257.88,43.22)
RD1_A_DE1: length 4.2
  TOP w0.102: UN4.8 262.65,44.48 262.37,44.2 261.58,44.2 v2(261.27,43.88) 260.86,43.48 RN26.2 RN39.1
RD1_A_EQ0: length 3.2
  TOP w0.102: RN42.2 RN179.1 262.19,50.55 v2(262.19,50.11) 262.23,50.11 262.65,49.69 UN4.23
RD1_A_EQ1: length 6.6
  TOP w0.102: RN43.2 RN176.1 263.2,53.51 263.4,53.51 v2(263.56,53.36) 263.15,52.96 UN4.22
RD1_A_EQ2: length 3.3
  TOP w0.102: UN4.19 264.65,49.4 v2(265.44,50.18) RN44.2 RN174.1
RD1_B_DE0: length 3.5
  TOP w0.102: RN27.2 RN40.1 267.21,45.48 266.81,45.08 v2(266.54,45.08) 266.32,45.08 265.64,45.76 UN4.13
RD1_B_DE1: length 3.3
  TOP w0.102: UN4.9 263.15,44.42 v2(262.62,43.88) 262.9,43.6 RN41.1 RN28.2
RD1_B_EQ0: length 4.2
  TOP w0.102: UN4.11 264.15,44.4 264.47,44.09 264.47,43.48 RN52.1 RN49.2 v2(266.91,43.02)
RD1_B_EQ1: length 3
  TOP w0.102: RN50.2 RN53.1 263.66,50.2 v2(263.7,50.16) 263.7,49.69 263.66,49.65 263.66,49.06 UN4.21
RD1_B_EQ2: length 3.2
  TOP w0.102: RN54.1 RN51.2 v2(266.55,47.52) 266.3,47.26 UN4.16
RD1_REXT: length 2
  TOP w0.102: RN30.1 v2(263.91,43.88) 263.65,44.14 UN4.10
RD2_A_DE0: length 4.4
  TOP w0.102: v1(291.96,53.67) 291.9,53.61 291.5,53.61 291.39,53.72 UN5.6
  BOTTOM w0.102: RN55.2 RN59.1 292.13,51.84 292.13,52.98 292.19,53.04 292.19,53.44 v1(291.96,53.67)
RD2_A_DE1: length 4.9
  TOP w0.102: RN60.1 294.24,51.48 RN56.2 293.35,53.23 v2(293.35,53.43) 292.92,53.87 292.92,54.91 292.61,55.21 UN5.8
RD2_A_EQ0: length 9.1
  TOP w0.102: UN5.23 288.01,55.29 286.16,55.29 286.03,55.42 284.31,55.42 v1(283.9,55.82) ; RN225.2 227.03,34.82 228.09,33.76 v2(228.09,32.12) v1(228.09,31.5)
RD2_A_EQ0_R: length 3.5
  TOP w0.102: RN63.2 224.21,35.83 QN5.3 ; RN63.2 RN225.1 ; RN63.2 v2(225.23,36.81)
RD2_A_EQ1: length 5
  TOP w0.102: v1(218.91,33.04) 219.17,33.29 RN224.2 ; v1(284.26,56.3) 284.26,56.14 284.51,55.89 286.15,55.89 286.32,55.71 v2(286.97,55.71) UN5.22
RD2_A_EQ1_R: length 3.8
  TOP w0.102: v2(221.54,32.28) RN64.2 RN224.1 221.43,34.17 QN5.6
RD2_A_EQ2: length 4.9
  TOP w0.102: RN223.2 v1(208.09,32.39) ; UN5.19 287.67,57.63 v2(286.77,57.63) 284.2,57.63 284.1,57.52 v1(284.1,57.5)
RD2_A_EQ2_R: length 3.3
  TOP w0.102: QN4.3 208.08,34.42 v2(207.9,34.24) 207.9,33.8 208.4,33.3 RN223.1 RN65.2
RD2_B_DE0: length 4
  TOP w0.102: v2(292.8,59.34) v1(292.41,58.95) 291.98,58.95 291.39,58.35 UN5.13
  BOTTOM w0.102: v1(292.41,58.95) 292.08,59.28 RN57.2 292.08,60.57 RN61.1
RD2_B_DE1: length 3.9
  TOP w0.102: UN5.9 292.85,55.71 293.35,55.21 v2(293.35,54.73) 293.83,54.73 RN62.1 RN58.2
RD2_B_EQ0: length 3.3
  TOP w0.102: RN72.1 RN69.2 293.39,57.23 v2(293.35,57.27) 292.79,56.71 UN5.11
RD2_B_EQ1: length 4
  TOP w0.102: UN5.21 v1(286.53,56.21) 285.91,56.21 v2(285.83,56.29)
  BOTTOM w0.102: v1(286.53,56.21) 286.59,56.15 RN70.2 RN73.1
RD2_B_EQ2: length 3.3
  TOP w0.102: UN5.16 289.89,58.65 v1(289.72,58.82) v2(289.72,59.38)
  BOTTOM w0.102: v1(289.72,58.82) 290.05,58.49 RN71.2 RN74.1
RD2_REXT: length 2.4
  TOP w0.102: UN5.10 293.14,56.21 v2(293.35,56) 293.81,55.54 294.04,55.54 RN31.1
RD5_A_DE0: length 3.6
  TOP w0.102: v2(283.8,60.32) RZ154.2 RZ155.1 284.66,62.25 UZ36.6
RD5_A_DE1: length 4.1
  TOP w0.102: UZ36.8 286.55,61.52 286.26,61.23 v1(285.59,61.23) 285.59,60.99 285.3,60.7 v2(285.25,60.7)
  BOTTOM w0.102: v1(285.59,61.23) 285.15,60.78 RZ157.1 RZ156.2
RD5_A_EQ0: length 4.2
  TOP w0.102: UZ36.23 286.55,66.44 286.17,66.82 v1(285.31,66.82) v2(285.31,67.37)
  BOTTOM w0.102: v1(285.31,66.82) 286.03,67.54 RZ354.2 RZ355.1
RD5_A_EQ1: length 3.2
  TOP w0.102: v2(286.69,67.54) v1(286.69,66.93) 286.69,66.85 287.05,66.49 UZ36.22
  BOTTOM w0.102: RZ357.1 RZ356.2 286.69,67.28 v1(286.69,66.93)
RD5_A_EQ2: length 4.4
  TOP w0.102: v1(289.13,66.13) 288.83,66.44 288.65,66.44 288.55,66.34 UZ36.19
  BOTTOM w0.102: v1(289.13,66.13) 289.39,66.39 290.1,66.39 290.76,67.05 RZ358.2 RZ359.1
RD5_B_DE0: length 4.9
  TOP w0.102: v1(291.45,62.29) 290.35,62.29 289.8,62.83 UZ36.13
  BOTTOM w0.102: RZ159.1 RZ158.2 291.92,62.76 v1(291.45,62.29) 291.23,62.07 v2(290.91,62.07)
RD5_B_DE1: length 3.2
  TOP w0.102: UZ36.9 287.05,61.38 v1(286.91,61.24) 286.91,60.99 286.59,60.67 v2(286.54,60.67)
  BOTTOM w0.102: RZ161.1 RZ160.2 287.03,61.13 v1(286.91,61.24)
RD5_B_EQ0: length 3.7
  TOP w0.102: v1(289.34,61.21) 289.13,61 v2(288.84,61) 288.65,61 288.05,61.61 UZ36.11
  BOTTOM w0.102: v1(289.34,61.21) 289.72,60.83 RZ163.1 RZ162.2
RD5_B_EQ1: length 3.6
  TOP w0.102: UZ36.21 287.55,66.41 v1(288.07,66.93) v2(288.07,67.48)
  BOTTOM w0.102: v1(288.07,66.93) 288.09,66.95 288.1,66.95 288.69,67.54 RZ165.1 RZ164.2
RD5_B_EQ2: length 6.3
  TOP w0.102: v1(291.57,64.46) 291.49,64.53 291.09,64.53 290.89,64.33 UZ36.16
  BOTTOM w0.102: RZ166.2 RZ167.1 ; RZ167.1 291.78,64.66 v1(291.57,64.46) ; RZ167.1 292.79,64.15 v2(294.2,64.15)
RD5_REXT: length 3.2
  TOP w0.102: v2(287.76,60.29) 287.79,60.32 v1(287.79,61.23) 287.55,61.47 UZ36.10
  BOTTOM w0.102: v1(287.79,61.23) 288.18,61.23 RZ348.1
RED: length 10.2
  BOTTOM w0.102: LV16.2 317.43,88.68 CV129.1 317.43,87.57 316.39,86.53 DV5.2 316.39,85.93 v2(318.27,85.93) 319.4,85.93 JCRT1.1
RED_CRT: length 5.5
  TOP w0.102: UV6.23 280.09,56.07 280.42,56.41 280.42,56.71 280.12,57.01 v1(280.12,57.35)
  BOTTOM w0.102: v1(316.74,90.43) CV126.1 RV116.1 318.39,89.53 v2(318.34,89.48) 317.38,89.48 LV16.1
REM_DIODE1_N: length 8
  TOP w0.254: QE3.3 123.11,57.44 123.53,57.66 CE35.1 124.12,57.3 123.92,57.11 v1(123.49,57.11) ; v1(291.84,77.52) 291.92,77.44 292.74,77.44 CE24.1 v2(294.15,77.63) 295.46,77.63 UE1.A8
REM_DIODE1_P: length 8.8
  TOP w0.254: v1(123.37,58.74) 123.95,58.74 CE35.2 123.63,58.09 QE3.1 121.73,58.09 QE3.2 ; UE1.A7 295.45,76.84 293.06,76.84 CE24.2 292.71,76.93 v1(291.84,76.93)
  BOTTOM w0.102: v1(291.84,76.93) 291.86,76.95 v2(292.44,76.95)
REM_DIODE2_N: length 115
  TOP w0.254: v1(290.43,82.12) 290.43,81.76 289.45,80.78 289.45,79.99 290.16,79.28 290.53,79.28 290.74,79.07 291.89,79.07 CE26.1 292.22,78.9 295.34,78.9 UE1.A10
  BOTTOM w0.254: v1(252.33,30.34) 252.25,30.26 252.25,29.58 239.57,16.89 v1(239.57,16) 239.6,15.96 CE37.2 239.8,11.76 QE5.3 ; QE7.1 112.39,8.92 QE7.2 112.39,10.95 CE46.2 112.76,11.83 112.96,12.03 112.96,13.36 115.8,16.2 150.44,16.2 151.11,16.87 170.98,16.87 172.03,15.82 176.38,15.82 177.24,14.96 185.79,14.96 v1(185.97,15.14)
REM_DIODE2_P: length 115.8
  TOP w0.254: v1(289.6,82.05) 289.6,81.65 288.94,80.99 288.94,79.78 289.95,78.77 290.32,78.77 290.53,78.56 291.66,78.56 CE26.2 292.14,78.4 295.49,78.4 UE1.A9
  BOTTOM w0.254: v1(186.82,15.05) 186.64,15.05 186.05,14.46 177.03,14.46 176.17,15.32 171.82,15.32 170.77,16.36 151.32,16.36 150.65,15.69 116.01,15.69 113.47,13.15 113.47,12.03 113.67,11.83 CE46.1 113.67,10.19 QE7.3 ; QE5.1 238.5,9.62 QE5.2 238.5,11.76 CE37.1 238.89,12.16 238.89,15.37 v1(238.93,15.41) 238.93,16.97 251.75,29.79 v1(251.75,30.34)
REM_DIODE4_N: length 127.3
  TOP w0.254: QE6.3 79.4,45.87 CE39.1 78.94,45.41 78.94,43.35 79.63,42.65 79.63,34.82 81.03,33.42 81.03,31.16 v1(81.07,31.12) ; v1(291.13,80.58) 291.27,80.44 292.82,80.44 CE27.1 294.76,80.55 295.38,79.93 UE1.A11
  BOTTOM w0.254: v1(181.87,19.07) 177.84,19.07 176.57,20.33 131.84,20.33 123.13,29.04 83.08,29.04 81.07,31.05 v1(81.07,31.12)
REM_DIODE4_P: length 132.7
  TOP w0.127: UE1.B10 296.01,79.48 295.09,79.48
  TOP w0.254: v1(290.46,80.3) 290.65,80.3 291.03,79.92 292.65,79.92 CE27.2 293.05,79.76 294.82,79.76 295.09,79.48 ; v1(80.48,31.12) 80.48,31.39 80.52,31.43 80.52,33.21 79.13,34.61 79.13,42.44 78.43,43.13 78.43,45.41 CE39.2 78.1,45.74 QE6.2 78.75,47.41 QE6.1
  BOTTOM w0.254: v1(80.48,31.12) 80.48,30.92 82.87,28.53 122.92,28.53 131.62,19.83 176.36,19.83 177.63,18.56 v1(182.5,18.56)
RES_BIAS: length 2.7
  TOP w0.102: UL1.12 281.48,87.82 v2(282.35,88.68) 283.01,89.35 RL13.1
RESET_OUT#_R: length 9.5
  TOP w0.102: v2(61.68,42.49) 61.85,42.31 61.85,41.15 RC129.2 RC128.2 61.35,40.16 61.86,39.65 61.86,38.86 CC33.1 62.36,37.71 62.91,37.16 63.68,37.16 63.95,36.89 JXDP1.47
RING2:
  vias: v1(298.14,30.94) v1(298.58,30.56) v1(298.71,31.2) v1(307.98,39.45) v1(308.55,38.82) v1(308.62,39.45) v2(308.32,38.19)
RING2_R:
  vias: v1(311.54,41.67) v1(311.54,41.04) v1(312.17,41.04) v3(317.89,40.15)
RJ45_MDIN0: length 2.3
  BOTTOM w0.229: TL1.14 291.71,102.17 291.39,102.49 291.39,103.1 v1(291.49,103.2)
RJ45_MDIN1: length 2.8
  BOTTOM w0.229: TL1.20 297.71,102.25 297.24,102.71 297.24,103.11 297.5,103.36 v1(297.79,103.36)
RJ45_MDIN2: length 2.5
  BOTTOM w0.229: TL1.17 294.71,102.34 294.38,102.66 294.38,103.06 v1(294.68,103.36)
RJ45_MDIN3: length 2.5
  BOTTOM w0.229: TL1.23 300.71,102.27 300.31,102.66 300.31,102.98 v1(300.63,103.3)
RJ45_MDIP0: length 2.3
  BOTTOM w0.229: TL1.13 290.71,102.23 291.03,102.55 291.03,103.08 v1(290.9,103.2)
RJ45_MDIP1: length 2.4
  BOTTOM w0.229: v1(296.68,103.36) 296.9,103.14 296.9,102.38 296.71,102.19 TL1.19
RJ45_MDIP2: length 2.7
  BOTTOM w0.229: TL1.16 293.71,102.42 294.04,102.76 294.04,103.07 v1(293.6,103.52)
RJ45_MDIP3: length 2.4
  BOTTOM w0.229: v1(299.67,103.29) 299.97,103 299.97,102.57 299.71,102.31 TL1.22
RTCRST_ON: length 3.9
  TOP w0.102: v2(288.65,75.74) 288.65,75.73 QE12.2 287.7,74.99 RE93.1 287.7,76.51 RE514.2 RE515.2
RTCRST_ON_GPIO122: length 12.8
  TOP w0.102: v1(291.37,83.91) 289.83,83.91 285.44,79.52 285.44,78.12 285.58,77.98 285.64,77.92 286.39,77.92 RE515.1
  TOP w0.112: UE1.F11 299.14,80.35 v1(299.14,81.15)
  BOTTOM w0.102: v2(291.37,84.52) v1(291.37,83.91)
RTCRST_ON_GPIO141: length 1.9
  TOP w0.102: v2(285.86,76.09) v1(286.21,76.68) 286.29,76.6 RE514.1 ; UE1.B6 v1(295.93,75.49)
RTD3_CIO_PWR_EN: length 6.7
  TOP w0.102: v1(137.97,56.8) 137.65,56.48 134.37,56.48 T18.1
  BOTTOM w0.102: v1(137.97,56.8) 137.97,56.74 137.85,56.62 136.65,56.62 136.49,56.78 UC1.AC2
RUN_ON: length 88.9
  TOP w0.102: v1(187.91,37.71) 188.47,37.15 188.47,34.19 v1(184.72,30.43) ; v1(268,53.49) 268.13,53.36 RZ345.1 ; RE280.2 RE292.1 303.1,96.54 302.32,96.54 302.21,96.43 302.21,95.35 302.52,95.04 302.52,94.25 303.52,93.25 UE5.4 v1(303.52,91.6) ; v1(189.82,17.14) 190.03,16.93 UZ4.3 ; v1(297.69,61.27) 297.57,61.39 QE2.2 ; v1(195.52,10.87) 195.13,10.48 195.13,9.44 196.97,7.59 197.69,7.59 198.36,6.92 200.86,6.92 201.14,7.21 UZ3.5
  TOP w0.254: v1(136.29,109.85) 136.29,109.85 136.56,110.12 PR402.1
  BOTTOM w0.102: v1(189.82,17.14) 188.04,17.14 187.07,18.11 185.87,18.11 185.36,18.62 185.36,22.09 184.88,22.57 184.88,23.77 187.53,26.42 187.53,27.62 v1(184.72,30.43) ; v1(300.56,59.7) 300,60.26 298.69,60.26 v1(297.69,61.27) ; v1(259.06,30.65) 256.16,33.55 256.16,39.18 257.32,40.34 257.32,41.1 259.13,42.92 259.13,48.64 260.22,49.73 261.82,49.73 262.46,49.1 264.81,49.1 265.56,49.85 265.56,52.22 266.96,53.61 267.87,53.61 v1(268,53.49) ; v1(134.43,83.58) 134.82,83.2 135.45,83.2 135.77,83.52 UZ35.2 ; RZ320.1 132.59,80.03 v1(132.72,80.16)
RUN_ON#: length 3.1
  TOP w0.102: RE68.1 298.15,58.95 298.52,59.31 v2(298.52,59.33) 298.22,59.63 QE2.6 298.22,60.29 298.11,60.39 297.75,60.39 297.57,60.21 QE2.5
RUN_ON_1.8V: length 3.6
  TOP w0.102: UZ8.3 270.65,53.31 CZ197.1 RZ345.2 269.7,52.95 v2(269.15,52.41)
RUN_ON_EC: length 5.6
  TOP w0.102: v1(304.17,93.8) UE5.2 304.17,95.17 303.87,95.47 303.26,95.47 RE292.2 ; v2(309.4,87.55) 309.11,87.55 308.72,87.93 v1(308.72,87.93) 308.48,88.18 RPE10.4
  TOP w0.112: v1(298.38,77.9) UE1.E8
RUNPWROK: length 172.7
  TOP w0.102: v1(299.89,59.12) 298.42,60.6 297.79,60.6 296.92,61.47 QE2.3 297.06,62.07 RE67.1 ; UC8.13 54.22,30.97 v1(54.65,30.54) 55.09,30.98 57.1,30.98 57.48,31.36 57.48,32.74 57.1,33.12 v2(56.52,33.12) 56.01,33.12 55.68,32.79 UC8.1 ; UC8.4 v1(53.22,34.65) ; UC8.10 v1(52.72,30.42)
  TOP w0.107: v1(299.97,73.11) 299.97,73.14 UE1.G3
  BOTTOM w0.102: v1(53.22,34.65) 53.22,34.22 50.81,31.81 50.81,30.18 51.15,29.83 52.13,29.83 v1(52.72,30.42) 52.83,30.54 v1(54.65,30.54) 56.56,30.54 60.52,26.59 65.64,26.59 66.07,26.15 79.25,26.15 79.58,26.48 123.14,26.48 130.72,18.91 175.93,18.91 177.91,16.93 183.66,16.93 183.93,17.21 183.93,18.44 183.67,18.71 183.67,22.85 187.03,26.21 v1(187.03,26.93)
SA_LGATE: length 0.6
  TOP w0.102: v2(68.49,75.61) v1(69.08,75.61)
  vias: v1(69.08,76.22) v1(71.58,76.12) v1(72.14,75.91)
SA_SNUB: length 1.2
  TOP w0.102: v2(72.25,79.22) 72.55,78.92 PC622.1
SA_SW: length 47.2
  TOP w0.254: v1(78.49,80.03) 78.29,79.82 78.29,75.11 77.2,74.02 74.13,74.02 73.26,73.16 73.26,58.82 73.87,58.22 73.87,56.82 77.23,53.46 v2(77.23,43.45) 76.59,42.82 PR624.1
  BOTTOM w0.254: v1(78.49,80.03) 78.11,79.65 78.11,78.5 77.79,78.19 PL614.2
  vias: v1(66.15,75.94) v1(66.76,75.94) v1(75.01,79.27) v1(75.06,78.5) v1(75.06,77.87) v1(75.06,77.23)
SA_UGATE: length 0.9
  BOTTOM w0.102: v1(66.49,79.52) v2(65.61,79.52)
  vias: v1(66.84,80) v1(71.31,79.92) v1(71.91,79.94)
SATA_LED_EN: length 31.2
  TOP w0.102: 267.98,66.75 v1(267.98,65.93)
  BOTTOM w0.102: v1(69.58,90.5) 69.58,90.42 v2(68.71,89.55) 64.14,84.98 56.98,84.98 56.38,84.38 54.55,84.38 53.62,83.46 53.62,81.3 53.95,80.97 53.95,77.73 53.72,77.5 UE2.14
SATA_PRX_C_DTX_N0: length 3.1
  BOTTOM w0.094: CN6.1 272.68,36.9 273.14,36.44 273.14,36.31 273.35,36.1 273.65,36.1 274.06,35.69 274.06,35.5 273.9,35.34 JSATA1.5
SATA_PRX_C_DTX_P0: length 3.1
  BOTTOM w0.094: JSATA1.6 274.4,35.34 274.24,35.5 274.24,35.77 273.73,36.28 273.43,36.28 273.32,36.39 273.32,36.53 CN7.1
SATA_PRX_C_RD_DTX_N0: length 3.6
  TOP w0.094: CN14.2 278.19,66.92 278.19,66.87 277.93,66.62 276.97,66.62 276.9,66.55 276.9,66.54 276.51,66.15 276.51,65.97 276.63,65.84 UN7.4
SATA_PRX_C_RD_DTX_P0: length 3.6
  TOP w0.094: UN7.5 276.14,65.79 276.32,65.97 276.32,66.23 v4(276.54,66.46) 276.89,66.8 277.86,66.8 277.98,66.93 277.98,67.17 277.78,67.38 CN15.2
SATA_PRX_DTX_N0: length 7.3
  TOP w0.094: v1(283.26,69.08) 283.36,69.08 283.45,69.18 283.45,69.51 283.33,69.63 v4(281.81,69.63) 279.01,69.63 278.38,68.99 278.38,68.56 CN14.1
  BOTTOM w0.076: UC1.F20 v1(126.12,66.58)
SATA_PRX_DTX_P0: length 8.5
  TOP w0.094: v1(283.85,69.08) 283.64,69.3 283.64,69.59 283.4,69.82 282.13,69.82 282.12,69.83 281.49,69.83 281.48,69.82 278.94,69.82 278.19,69.07 278.19,68.31 278.02,68.14 277.84,68.14 CN15.1
  BOTTOM w0.076: UC1.E20 126.5,66.92 126.27,66.92 126.12,67.07 v1(126.12,67.21)
SATA_PRX_RD_DTX_N0: length 19.3
  TOP w0.094: v1(277.46,59.94) 277.23,59.71 276.98,59.71 276.5,60.2 276.5,60.74 276.63,60.88 UN7.12
  BOTTOM w0.094: CN6.2 273.05,38.19 273.05,38.52 272.84,38.73 271.96,38.73 271.43,39.26 259.83,39.26 258.31,40.79 v1(258.02,40.79)
SATA_PRX_RD_DTX_P0: length 19.8
  TOP w0.094: UN7.11 276.14,60.89 276.31,60.72 276.31,60.12 276.91,59.53 277.28,59.53 v1(277.46,59.35)
  BOTTOM w0.094: v1(258.43,41.2) 258.43,40.93 259.91,39.45 271.51,39.45 272.04,38.92 272.92,38.92 273.24,38.6 273.24,38.27 CN7.2
SATA_PTX_C_DRX_N0: length 3.7
  BOTTOM w0.094: CN5.1 271.25,36.49 271.25,36.31 271.38,36.18 271.65,36.18 271.66,36.19 272.17,36.19 272.18,36.18 272.39,36.18 272.74,35.83 272.74,35.45 272.9,35.29 JSATA1.3
SATA_PTX_C_DRX_P0: length 3.7
  BOTTOM w0.094: JSATA1.2 272.4,35.3 272.56,35.46 272.56,35.75 272.31,36 v4(271.91,36) 271.3,36 271.06,36.24 271.06,36.48 CN4.1
SATA_PTX_C_RD_DRX_N0: length 4.2
  TOP w0.094: CN13.2 279.87,67.38 279.99,67.26 279.99,66.91 279.9,66.82 278.89,66.82 278.85,66.78 278.8,66.78 278.39,66.37 278.39,66.34 278.28,66.22 277.99,66.22 277.79,66.02 277.79,65.86 277.63,65.7 UN7.2
SATA_PTX_C_RD_DRX_P0: length 4.1
  TOP w0.094: UN7.1 278.14,65.67 277.98,65.83 277.98,65.94 278.07,66.03 278.36,66.03 v4(278.75,66.42) 278.97,66.63 279.98,66.63 280.18,66.84 280.18,67.28 280.27,67.38 CN12.2
SATA_PTX_DRX_N0: length 7.4
  TOP w0.094: v1(283.16,68.04) 283,68.19 283,68.49 282.31,69.18 280.18,69.18 279.87,68.87 279.87,68.57 CN13.1
  BOTTOM w0.076: v1(126.12,70.86) 125.98,70.99 125.68,70.99 125.48,70.8 125.48,70.2 125.7,69.98 125.7,69.64 UC1.B21
SATA_PTX_DRX_P0: length 6.9
  TOP w0.094: CN12.1 280.15,68.29 280.05,68.39 280.05,68.79 280.26,68.99 282.24,68.99 282.82,68.41 282.82,68.28 v1(282.58,68.04)
  BOTTOM w0.076: v1(126.12,71.44) 126.12,71.38 125.89,71.16 125.61,71.16 125.31,70.86 125.31,70.14 125.53,69.92 125.53,69.79 125.46,69.71 UC1.A21
SATA_PTX_RD_DRX_N0: length 18.3
  TOP w0.094: UN7.14 277.63,61.07 277.83,60.88 277.83,60.74 278.4,60.17 v1(279.76,60.17)
  BOTTOM w0.094: v1(257.34,39.64) 257.34,39.32 257.84,38.81 270.89,38.81 271.21,38.49 271.21,38.15 271.54,37.81 CN5.2
SATA_PTX_RD_DRX_P0: length 17.9
  TOP w0.094: UN7.15 278.14,61.07 278.01,60.95 278.01,60.82 278.47,60.35 279.36,60.35 v1(279.76,60.75)
  BOTTOM w0.094: v1(256.92,39.23) 257.16,39.23 257.76,38.63 270.81,38.63 271.02,38.42 271.02,38.19 CN4.2
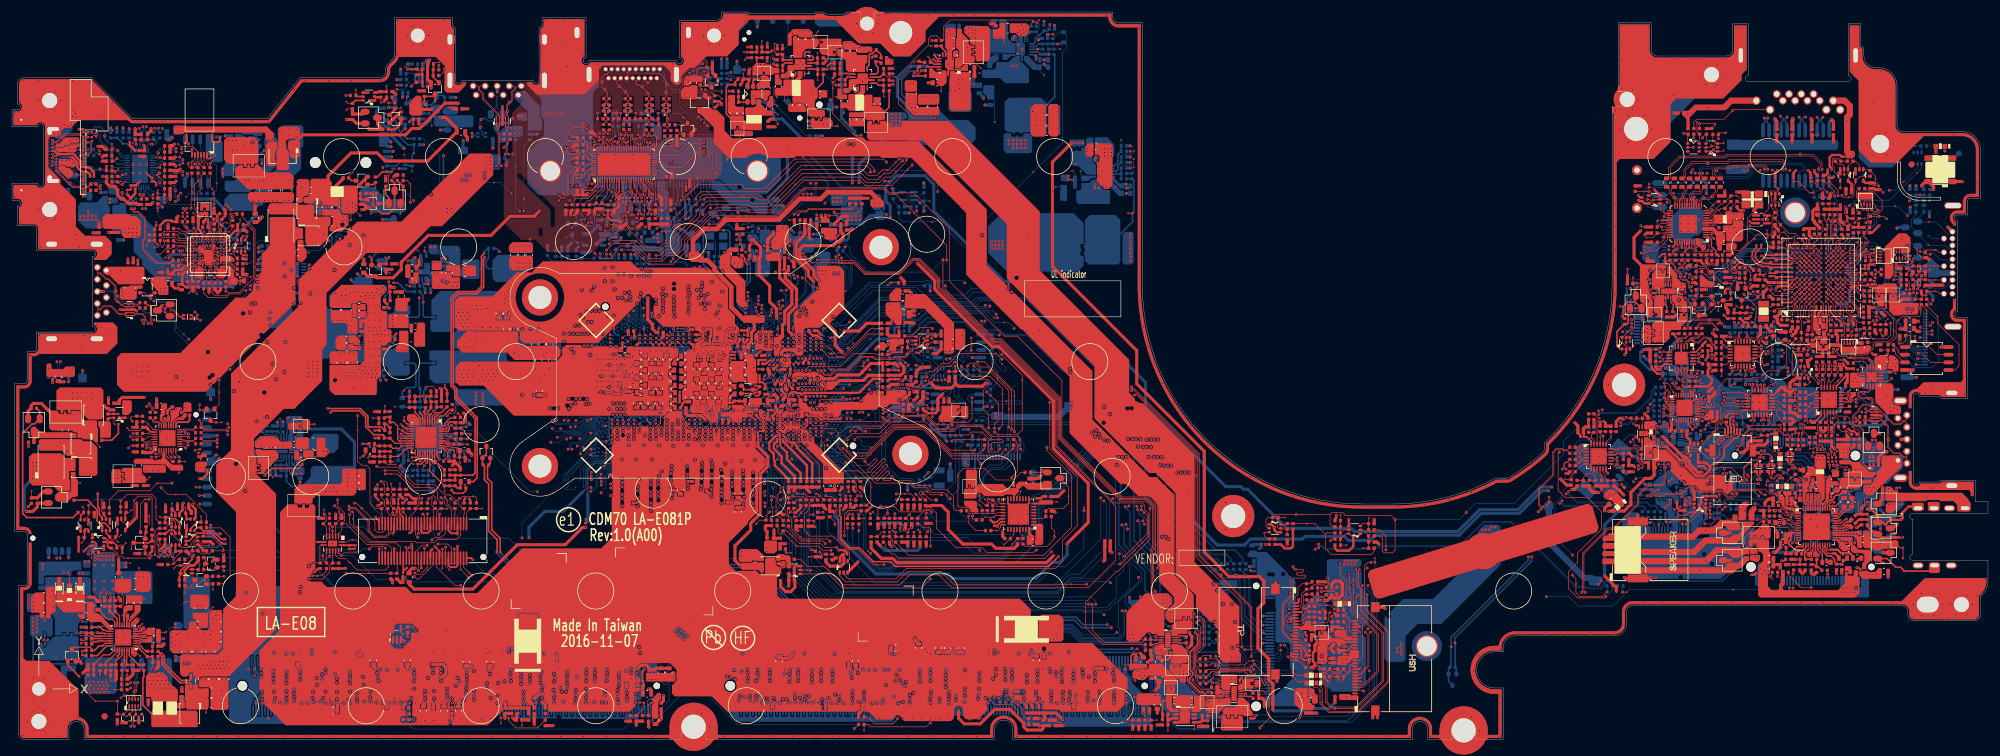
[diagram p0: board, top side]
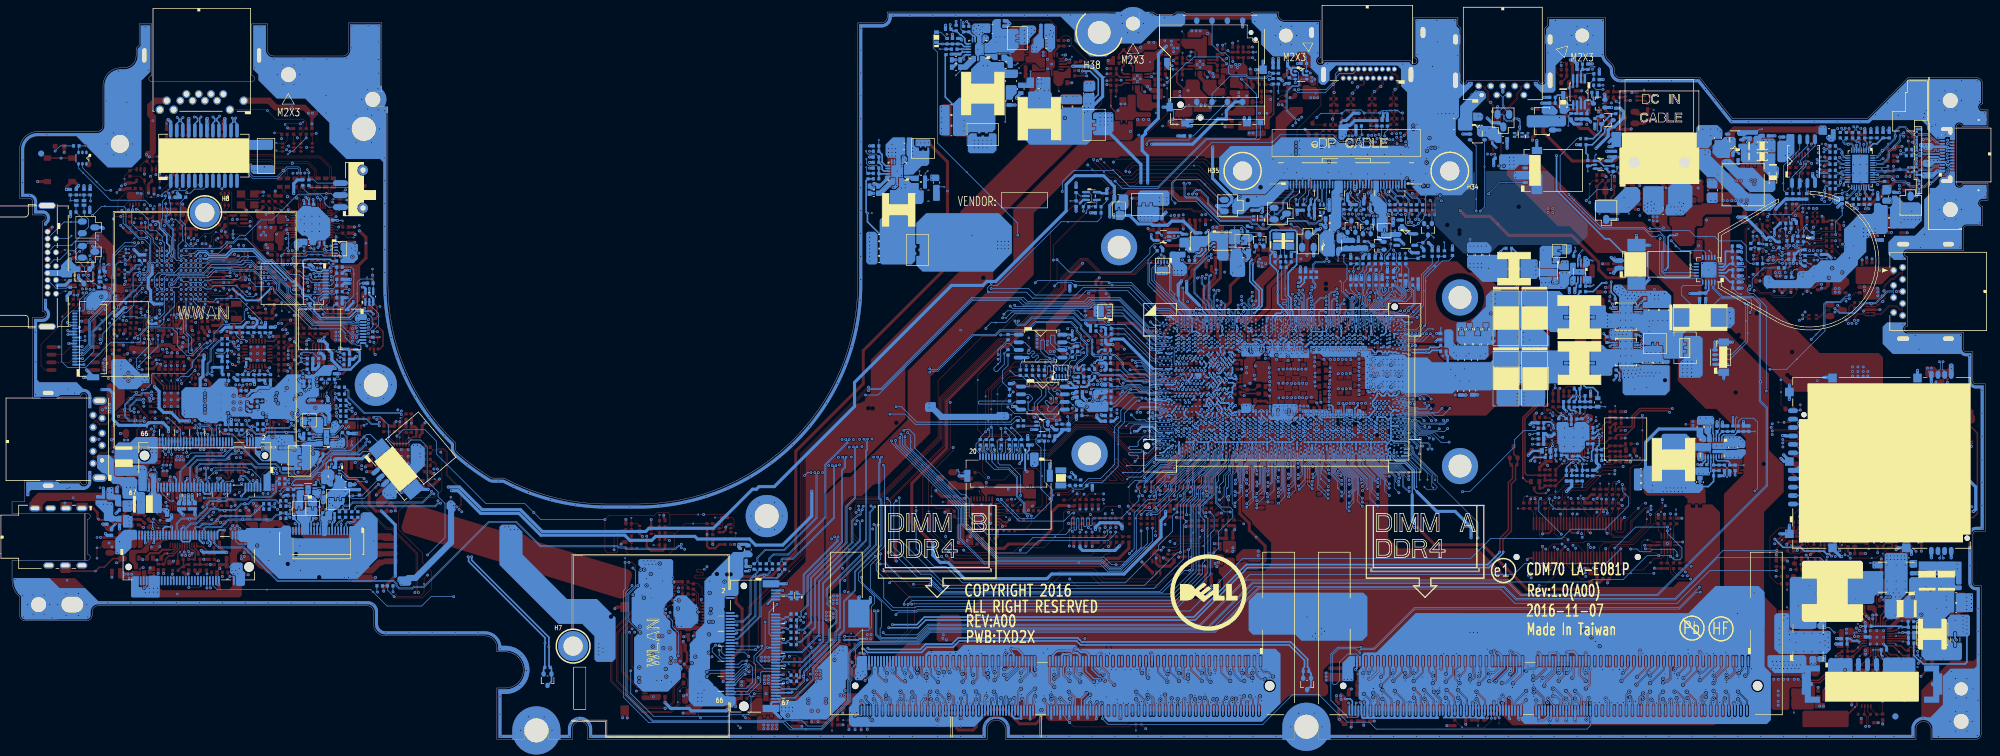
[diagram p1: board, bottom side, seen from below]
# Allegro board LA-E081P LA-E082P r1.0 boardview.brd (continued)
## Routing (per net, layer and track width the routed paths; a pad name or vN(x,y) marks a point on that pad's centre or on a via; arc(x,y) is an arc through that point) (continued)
SATALED#: length 70.5
  TOP w0.102: QZ2.4 v1(268.63,66.07) ; v1(256.87,47.72) 256.69,47.55 256.69,41.36 257.85,40.21 261.52,40.21 263.91,37.82 263.91,34.94 259.91,30.95 259.91,29.4 258.42,27.91 258.42,25.01 259.92,23.51 264.42,23.51 v1(264.61,23.7)
  BOTTOM w0.076: UC1.H1 138.17,65.54 138.44,65.8 138.69,65.8 140.47,67.58
  BOTTOM w0.102: RN100.2 266.52,25.55 265.71,25.55 RN101.2 265.71,24.81 v1(264.61,23.7) ; 140.47,67.58 143.71,70.82 RPC4.2 146.12,70.82 146.51,70.43 146.51,70.25 146.77,69.99 149.86,69.99 v2(150.55,70.68) 151.06,71.19 162.8,71.19 v1(163.38,70.61)
SBIOS_TX: length 2.7
  BOTTOM w0.076: UC1.AB2 137.25,58.02 137.36,57.98 137.63,57.98 v1(138.02,58.26)
  BOTTOM w0.102: v1(272.06,74.69) 272.92,74.69 RE306.1
SCL_ISL88738: length 3.4
  TOP w0.203: PU901.22 14.91,16.36
  TOP w0.254: PR922.2 13.62,16.26 v2(14.09,16.26) 14.36,16.26 14.46,16.36 14.91,16.36
SD/MMCCD#: length 3.8
  TOP w0.102: v3(30.36,48.02) 30.52,48.18 v1(31.18,48.18) ; UR1.30 26.39,47.55 v1(27.06,46.88)
  BOTTOM w0.102: v1(31.18,48.18) 32,49 JSD1.18
SD/MMCCLK: length 2.6
  TOP w0.102: RR5.1 22.2,52.77 v2(22.55,52.42) 23.52,51.46 UR1.17
SD/MMCCLK_R: length 4.1
  TOP w0.102: RR5.2 CR21.1 20.02,53.69 v2(19.75,53.42) 19.75,53.05 v1(19.97,52.83)
  BOTTOM w0.102: JSD1.5 v1(30.93,47.6)
SD/MMCCMD: length 2.1
  TOP w0.102: RR6.1 v2(22.65,50.82) 22.83,50.82 22.99,50.66 UR1.19
SD/MMCCMD_R: length 2.5
  TOP w0.102: v1(31.12,41.9) v3(30.51,41.9) ; RR6.2 v1(20.08,50.82)
  BOTTOM w0.102: JSD1.2 v1(31.12,41.9)
SD/MMCDAT0/RCLK+: length 2.4
  TOP w0.102: RR10.1 22.99,53.41 23.3,53.1 23.3,52.85 23.53,52.62 24.27,52.62 24.39,52.51 UR1.16
SD/MMCDAT0/RCLK+_R: length 3.2
  TOP w0.102: v1(22.35,55.32) 22.85,55.32 23.25,54.92 23.25,54.64 RR10.2
  BOTTOM w0.102: JSD1.7 31.76,51.8 31.45,52.11 v1(31.45,52.47)
SD/MMCDAT1/RCLK-: length 2.4
  TOP w0.102: RR9.1 23.53,53.12 23.53,52.95 23.62,52.85 24.36,52.85 24.79,52.43 UR1.15
SD/MMCDAT1/RCLK-_R: length 3.3
  TOP w0.102: RR9.2 23.47,54.67 23.47,55.02 v1(22.76,55.73)
  BOTTOM w0.102: v1(31.09,53) 31.22,52.88 31.6,52.88 31.93,53.2 JSD1.8
SD/MMCDAT2: length 2.6
  TOP w0.102: RR8.1 21.67,49.01 22.09,49.43 v2(22.64,49.43) 22.76,49.43 23.19,49.86 UR1.21
SD/MMCDAT2_R: length 2.8
  TOP w0.102: v3(19.31,48.41) 19.69,48.79 v1(20.13,48.79) RR8.2
  BOTTOM w0.102: JSD1.9 v1(31.18,39.1)
SD/MMCDAT3: length 4.6
  TOP w0.102: v3(19.65,50.3) 21.43,50.3 21.67,50.06 RR7.1 22.03,49.8 22.48,50.26 UR1.20
SD/MMCDAT3_R: length 2.7
  TOP w0.102: v1(31.12,40.5) v3(31.88,40.5) ; RR7.2 v1(20.1,49.8)
  BOTTOM w0.102: JSD1.1 v1(31.12,40.5)
SD_GPIO: length 2.5
  TOP w0.102: UR1.28 25.59,47.08 v2(25.83,46.84) 26.52,46.14 RR3.2
SD_RCOMP: length 2.6
  TOP w0.381: RC96.1 150.04,59.45 149.53,58.95 v2(149,58.95) v1(148.47,58.95)
  BOTTOM w0.254: v1(133.72,59.11) 133.83,59 133.83,58.79 UC1.AB7
SD_UHS2_D0N: length 2.7
  TOP w0.089: v1(23.87,47.47) 24.07,47.26 24.26,47.26 24.44,47.44 24.44,47.59 24.39,47.65 UR1.25
  BOTTOM w0.089: JSD1.12 7.2,30.92 7.57,30.55 7.57,30.27 v1(7.42,30.12)
SD_UHS2_D0P: length 3.2
  TOP w0.089: UR1.26 24.79,47.85 24.74,47.8 24.74,47.32 24.39,46.96 23.95,46.96 v1(23.87,46.88)
  BOTTOM w0.089: v1(8,30.12) 7.87,30.25 7.87,30.57 8.3,31 JSD1.11
SD_UHS2_D1N: length 4
  TOP w0.089: UR1.23 23.44,49.06 23.43,49.07 23.23,49.07 22.7,48.53 22.42,48.53 v1(22.32,48.43)
  BOTTOM w0.089: JSD1.15 7.2,61.15 7.55,61.5 7.55,62.64 v1(7.46,62.73)
SD_UHS2_D1P: length 4.2
  TOP w0.089: UR1.22 23.43,49.46 23.34,49.37 23.11,49.37 22.57,48.83 22.5,48.83 v1(22.32,49.01)
  BOTTOM w0.089: v1(8.04,62.73) 8.02,62.73 7.85,62.56 7.85,61.6 8.3,61.15 JSD1.16
SDA_ISL88738: length 6.1
  TOP w0.102: v2(10.86,17.8) 11.45,17.21 12.99,17.21 13.21,16.99 PR920.2
  TOP w0.203: PU901.21 14.78,16.76
  TOP w0.254: 14.78,16.76 13.23,16.76 PR920.2
SDWP: length 3.3
  TOP w0.102: v1(26.42,46.88) 25.99,47.32 UR1.29 ; QR1.1 33.28,52.66 v1(33.85,52.66) v2(34.8,52.66)
SDWP_Q: length 3.3
  TOP w0.102: QR1.3 32.15,54.72 v1(31.16,54.72) v3(31.16,55.58)
  BOTTOM w0.102: JSD1.19 31.27,54.6 v1(31.16,54.72)
SHD_CLK: length 1.2
  TOP w0.102: v1(307.73,80.17) RE374.1
  TOP w0.107: v1(302.36,77.93) UE1.J8
SHD_CLK_R1: length 26.7
  TOP w0.102: v1(316.46,64.15) 317,64.15 318.52,62.63 UE9.6 ; v1(308.36,80.16) 308.64,79.88 RE374.2
  BOTTOM w0.102: v1(308.36,80.16) 308.36,80.04 309.14,79.27 v2(310.02,79.27) 310.38,79.27 310.83,78.82 310.83,74.56 311.49,73.9 311.49,72.85 314.99,69.35 314.99,65.3 316.13,64.15 v1(316.46,64.15)
SHD_CS#: length 21.5
  TOP w0.102: RE364.1 306.81,74.51 v1(306.41,74.92) 306.29,75.04 305.8,75.04 305.61,74.85 305.49,74.85 305.34,74.69 304.82,74.69 304.39,75.13 UE1.M5 ; UE9.1 315.08,65.17 315.18,65.27 315.18,66.97 315.08,67.07 RE98.1 314.33,66.2 313.92,65.79 v1(313.34,65.79)
  BOTTOM w0.102: v1(313.34,65.79) 312.98,66.15 312.98,67.38 309.45,70.91 309.05,70.91 307.83,72.13 307.83,73.5 v2(307.31,74.01) v1(306.41,74.92)
SHD_IO0: length 10.8
  TOP w0.102: v1(312.69,76.98) 312.73,77.02 v2(312.73,77.51) 313.34,77.51 RE366.1 ; QE13.5 292.74,88.27 293.16,87.85 293.16,87.04 RE530.1 292.7,86.39 CE503.1 295.09,84 296.09,84 v1(297.24,82.86) ; v1(302.34,76.35) UE1.J7
SHD_IO0_R1: length 4.2
  TOP w0.102: RE366.2 314.53,77.46 314.98,77.91 314.98,78.82 315.43,79.27 v1(315.47,79.27) 315.61,79.41 v2(315.61,79.85) ; v1(318.61,72.3) 317.89,73.02 RE367.1
SHD_IO0_R2: length 14.4
  TOP w0.102: 321.51,61.36 322.56,61.36 323.25,62.05 323.25,65.58 319.69,69.13 v2(319.69,70.23) 317.89,72.03 RE367.2
SHD_IO1: length 1.7
  TOP w0.102: RE368.1 313.77,74.06 v1(313.23,73.51) ; v1(303.99,75.5) UE1.L6
SHD_IO1_R1: length 13.8
  TOP w0.102: v1(316.82,71.6) 316.82,70.42 316.59,70.2 313.77,70.2 v2(313.19,69.62) 312.8,69.22 312.8,66.77 311.58,65.55 RE369.1 ; v1(315.69,74.2) 315.69,74.16 315.59,74.06 RE368.2
  BOTTOM w0.102: v1(315.69,74.2) 315.69,74.14 316.82,73.01 v1(316.82,71.6)
SHD_IO1_R2: length 2.9
  TOP w0.102: 314.26,63.9 313.54,63.9 313.19,64.25 313.19,64.74 RE369.2
SHD_IO2: length 2.7
  TOP w0.102: RE360.1 RE370.1 v1(312.43,76.35) ; v1(303.98,76.3) UE1.L7
SHD_IO2_R1: length 3.7
  TOP w0.102: RE376.1 RE371.1 311.46,64.1 v1(311.36,64) ; RE370.2 314.97,75.91 314.97,74.87 v1(315.1,74.74)
SHD_IO2_R2: length 2.9
  TOP w0.102: UE9.3 314.08,62.63 312.68,64.03 312.68,64.36 RE371.2
SHD_IO3: length 3.7
  TOP w0.102: UE1.M6 304.72,75.57 305.3,75.57 305.62,75.89 v2(306.62,75.89) 307.15,75.89 RE372.1
SHD_IO3_R1: length 3
  TOP w0.102: RE372.2 308.81,76.34 309,76.14 309.02,76.14 309.07,76.09 v1(309.2,76.09) ; v1(316.28,74.15) 316.28,74.02 315.98,73.73 RE377.1 RE373.1
SHD_IO3_R2: length 11.3
  TOP w0.102: RE373.2 317.86,71.34 v2(317.86,67.56) 317.86,65.68 319.64,63.9 321.51,63.9
SIM_DET: length 32.5
  TOP w0.102: v1(144.92,92.72) v3(145.66,92.72)
  BOTTOM w0.102: JSIM1.9 120.8,99.95 121.11,99.64 129.69,99.64 137.83,91.49 143.69,91.49 v1(144.92,92.72) ; JNGFF2.58 v1(303.05,50.55)
SIO_EXT_SCI#: length 34
  TOP w0.102: v1(133.44,53.26) 133.76,52.93 134.5,52.93 134.64,52.79 144.47,52.79 146.1,54.41 147.45,54.41 147.6,54.26 149.73,54.26 RC237.1 150.35,54.15 150.45,54.04 151.74,54.04 153.44,52.34 155.69,52.34 156.04,52.7 158.73,52.7 159.39,53.36 v2(159.39,56.03) v1(159.39,56.79) ; v1(309.05,69.56) 308.95,69.56 308.59,69.2 RE341.1
  BOTTOM w0.076: v1(133.44,53.26) UC1.AN7
SIO_EXT_SCI#_EC: length 4.6
  TOP w0.102: UE1.M1 304.6,71.68 304.6,70.92 v2(305.22,70.3) 305.33,70.2 305.64,70.2 306.64,69.2 RE341.2
SIO_EXT_SMI#: length 91.5
  TOP w0.102: v1(309.34,76.66) 309.33,76.68 309.3,76.68 309.26,76.71 309.19,76.71 308.69,77.21 RE338.1 ; v1(189.8,26.39) 189.8,26.44 189.51,26.72 189.51,30.77 189.87,31.13 189.87,38.67 188.52,40.03 184.22,40.03 174.1,50.15 174.1,56.72 164.28,66.54 163.15,66.54 154.95,74.74 v1(154.95,75.33)
  BOTTOM w0.102: v1(154.95,75.33) 154.44,75.84 152.13,75.84 151.62,75.33 RC346.1 151.41,75.43 v2(148.09,75.43) 142.17,75.43 137.99,71.25 135.87,71.25 134.62,69.99 UC1.A6
SIO_EXT_SMI#_EC: length 1.3
  TOP w0.102: v1(307.14,77.06) 307.45,77.36 RE338.2
  TOP w0.107: v1(303.16,76.38) 303.11,76.38 UE1.K7
SIO_EXT_WAKE#: length 24.1
  TOP w0.102: v1(305.79,81.26) 305.75,81.22 305.05,81.22 304.56,80.73 UE1.M12 ; v1(148.85,58.18) 150.2,58.18 151.02,59.01 152.07,59.01 152.2,59.13 152.2,59.68 v2(153.68,61.17) 154.41,61.9 155.74,61.9 v1(156.5,62.67)
  BOTTOM w0.102: v1(148.85,58.18) 148.72,58.18 148.6,58.31 146.04,58.31 RC283.1 145.25,58.21 143.04,58.21 142.73,58.53 141.06,58.53 140.55,58.02 139.49,58.02 139.06,57.58 UC1.AC1
SIO_PWRBTN#: length 17.4
  TOP w0.102: UE1.K11 303.15,80.31 303.15,80.35 v1(303.16,80.35) ; CC269.1 RC241.1 64.92,38.34 v1(64.92,37.74) 65.44,37.23 65.44,35.85 JXDP1.41 ; v2(132.47,37.32) v1(133.05,37.32)
  BOTTOM w0.076: UC1.BA15 128.65,47.47 128.65,45.76 130.44,43.96 130.61,43.96
  BOTTOM w0.102: 130.61,43.96 131.73,42.84 131.73,40.37 133.05,39.05 v1(133.05,37.32)
SIO_RCIN#: length 74.5
  TOP w0.102: v1(309.15,72.44) 308.84,72.76 RE339.1 ; v2(177.96,38.55) v1(177.96,38.02) ; RC13.1 v1(134.63,37.74)
  BOTTOM w0.076: 132.15,43.54 129.84,45.85 129.84,46.72 129.71,46.85 129.71,47.23 129.76,47.34 129.76,47.46 129.7,47.68 129.7,47.82 129.75,47.98 129.75,48.06 129.97,48.76 129.97,48.76 130.15,48.94 UC1.AW13
  BOTTOM w0.102: v1(177.96,38.02) 177.96,31.72 174.93,28.69 172.93,28.69 170.25,26.01 143.23,26.01 137.67,31.57 137.67,32.27 135.39,34.55 135.39,37.1 134.75,37.74 v1(134.63,37.74) 134.63,39.06 133.61,40.07 133.61,41.03 132.97,41.67 132.97,42.41 132.82,42.56 132.82,42.87 132.15,43.54
SIO_RCIN#_EC: length 2.7
  TOP w0.102: UE1.N3 305.81,73.53 v2(306.58,72.76) RE339.2
SIO_SLP_A#: length 28.7
  TOP w0.102: UE1.M11 304.74,80.31 305.66,80.31 307.73,82.37 v1(307.73,82.49)
  BOTTOM w0.076: v1(127.95,52.54) 128.02,52.6 128.26,52.8 UC1.AN16
  BOTTOM w0.102: v1(307.73,82.49) 309.34,82.49 311.31,80.52 311.31,77.17 311.48,77 v2(311.48,75.46) 311.48,74.54 311.89,74.14 311.89,73.31 312.37,72.83 312.37,72.7 315.39,69.68 315.39,65.6 316.25,64.75 JAPS1.6
SIO_SLP_LAN#: length 109.9
  TOP w0.102: v1(289.95,42.49) 287.02,42.49 286.57,42.95 286.57,43.95 285.37,45.15 282.93,45.15 v2(282.18,44.4) 281.23,43.45 279.51,43.45 277.65,45.31 277.23,45.31 276.85,45.68 276.85,45.95 274.63,48.18 273.37,48.18 272.9,48.64 272.9,51.3 273.18,51.58 v1(273.18,52.04) ; RC344.1 RC68.1 134.41,30.76 v1(134.08,31.09)
  TOP w0.107: v1(301.56,78.73) UE1.H9
  BOTTOM w0.076: 132.18,43.2 130.26,45.13 129.75,45.13 129.03,45.85 129.03,46.77 129.19,46.93 129.19,48.4 129.03,48.74 129.03,48.73 128.87,48.89 UC1.AW15
  BOTTOM w0.102: v1(180.76,40.14) 180.76,33.33 172.97,25.53 140.1,25.53 134.63,31.01 134.17,31.01 v1(134.08,31.09) 134.08,39.04 133.29,39.83 133.29,41 132.72,41.57 132.72,42.26 132.57,42.41 132.57,42.82 132.18,43.2 ; UZ2.5 274.42,50.58 273.18,51.83 v1(273.18,52.04)
SIO_SLP_S0#: length 132.6
  TOP w0.102: RZ112.1 168.27,32.02 171.79,32.02 173.06,33.29 v1(173.06,33.7) 173.06,34.64 172.55,35.15 RZ363.1 ; PR425.1 136.89,109.6 136.43,109.14 v1(136.28,109.14) v2(136.28,108.12) 136.28,103.9 139.83,100.35 v1(140.98,100.35) ; v1(154.55,79.66) 154.55,74.85 163.06,66.34 164.19,66.34 173.89,56.64 173.89,50.06 184.14,39.81 188.4,39.81 189.59,38.63 189.59,31.54 189.31,31.26 189.31,25.07 v1(189.8,24.58)
  TOP w0.254: v1(126.38,112.19) 126.62,111.96 PR426.1
  BOTTOM w0.102: JAPS1.15 v1(318.87,69.25) ; v1(126.38,112.19) 127.54,113.35 131.81,113.35 132.72,112.44 132.97,112.44 v1(136.28,109.14) ; v1(154.55,79.66) 152.5,77.62 142.25,77.62 139.14,80.72 139.14,81.61 138.44,82.31 137.42,82.31 136.86,82.87 UZ35.1
  BOTTOM w0.254: UC1.AT11 131.07,50.85 130.73,50.51 v1(130.62,50.51)
SIO_SLP_S3#: length 33.5
  TOP w0.102: QE11.2 280.69,72.11 280.28,71.69 279.52,71.69 v1(279.28,71.45) ; UE3.2 306.71,95.37 306.05,96.03 RE280.1 304.82,95.21 UE5.1 304.82,93.78 v1(305.07,93.52)
  TOP w0.107: v1(303.16,78.73) UE1.K9
  BOTTOM w0.076: UC1.AP15 129.77,51.7 v1(129.77,51.26)
  BOTTOM w0.102: JAPS1.2 316.11,62.75 314.46,64.4 314.46,67.75 311.41,70.81 311.05,70.81 310.24,71.62 310.24,71.98 306.46,75.76 306.46,76.65 306.35,76.75 305.97,76.75 305.21,77.52 305.21,78.93 304.97,79.17 304.32,79.17 304.3,79.15 303.58,79.15 v1(303.16,78.73)
SIO_SLP_S4#: length 219.6
  TOP w0.102: UZ34.2 131.8,28.15 131.86,28.09 v2(132.04,28.09) v1(132.55,28.09) ; v1(133.72,79.65) 136.91,79.65 137.33,79.22 139.84,79.22 141.65,77.41 147.28,77.41 149.58,79.71 150.6,79.71 153.82,76.48 153.82,75 162.95,65.88 164.08,65.88 173.49,56.47 173.49,48.74 182.95,39.27 187.68,39.27 188.07,38.89 188.07,38.17 188.7,37.53 188.7,33.77 184.28,29.36 184.15,29.36 v1(183.94,29.15) ; v1(307.08,82.47) 306.17,81.56 306.17,81.1 305.8,80.73 UE1.N12 ; PR513.1 v1(199.27,3.98)
  BOTTOM w0.076: 130.15,43.07 130.15,43.76 128.32,45.59 128.32,48.03 UC1.BA16
  BOTTOM w0.102: JAPS1.5 317.08,64.25 316.79,64.53 316.13,64.53 315.19,65.48 315.19,69.6 312.17,72.62 312.17,72.74 311.69,73.23 311.69,73.98 311.03,74.64 311.03,80.29 309.38,81.93 307.61,81.93 v1(307.08,82.47) ; v1(133.72,79.65) 133.09,79.01 131.39,79.01 128.62,81.78 UZ21.4 ; 130.15,43.07 130.15,42.36 131.07,41.45 131.07,40.02 132.18,38.91 132.18,28.45 v1(132.55,28.09) 133.39,28.09 137.11,24.36 173.49,24.36 175.79,26.65 180.44,26.65 182.93,29.15 v1(183.94,29.15) ; v1(38.7,41.27) 38.28,41.68 38.28,52.75 38.89,53.36 40.9,53.36 41.47,52.79 PR208.2
SIO_SLP_S5#: length 96.7
  TOP w0.102: v1(306.85,77.56) 306.84,77.55 305.18,77.55 UE1.N8
  BOTTOM w0.076: UC1.AY16 128.29,48.52 127.99,48.22 127.99,47.79 128.16,47.63 128.16,45.5 129.88,43.78 129.88,42.7
  BOTTOM w0.102: v1(182.35,26.03) 182.17,26.21 175.72,26.21 173.67,24.16 135.88,24.16 131.96,28.09 131.96,38.62 130.77,39.81 130.77,41.31 129.88,42.2 129.88,42.7
  BOTTOM w0.112: JAPS1.4 316.21,63.75 314.76,65.19 314.76,67.75 311.4,71.11 311.05,71.11 310.51,71.65 310.51,72 307.96,74.55 307.96,77.05 307.45,77.56 v1(306.85,77.56)
SIO_SLP_SUS#: length 47
  TOP w0.102: v1(152.45,26.66) 152.45,26.65 150.96,25.16 137.86,25.16 135.53,27.5 UZ34.1 ; RZ64.1 198.93,7.98 198.93,8.06 198.73,8.26 197.42,8.26 196.05,9.63 v1(196.05,9.9) ; RE349.1 308.78,73.64 309.66,72.76 309.66,71.98 310.09,71.55 310.64,71.55 312.36,69.82 v2(312.36,67.91) 312.36,66.91 311.47,66.02 309.39,66.02 308.97,65.6 308.97,64.84 307.98,63.84 v1(305.96,63.84)
  TOP w0.254: PR504.1 119.05,107.64 v1(119.05,107.65) ; PR406.1 126.64,112.87 v1(126.4,113.1)
  BOTTOM w0.102: PR312.2 v1(185.68,97.68)
  BOTTOM w0.254: v1(128.8,52.47) 128.97,52.47 129.32,52.77 UC1.AN15
SIO_SLP_WLAN#: length 86.2
  TOP w0.102: RZ71.1 187.6,16.11 181.34,16.11 179.4,18.06 v2(179.4,19.06) 179.4,22.31 v1(179.29,22.42)
  TOP w0.112: v1(297.56,78.73) UE1.D9
  BOTTOM w0.076: UC1.BB17 127.83,46.98 127.83,45.27 129.36,43.74 129.36,42.98
  BOTTOM w0.102: 129.36,42.98 129.36,41.01 129.51,40.86 129.78,40.86 129.98,40.65 129.98,39.91 130.99,38.9 130.99,27.58 135.48,23.09 178.62,23.09 v1(179.29,22.42)
SLEEVE:
  vias: v1(299.22,30.56) v1(299.47,31.13) v1(299.85,30.63) v1(308.62,36.29) v1(308.62,35.64) v1(308.77,36.88) v2(308.22,36.64)
SLEEVE_R: length 0.9
  TOP w0.102: v1(312.87,39.07) 312.88,39.06 v3(313.77,39.06)
  vias: v1(311.54,39.07) v1(312.23,39.07)
SLOT2_CONFIG_0: length 11.9
  TOP w0.102: RPE9.3 309.71,80.02 v1(309.48,80.26) 308.96,80.26 308.67,80.55 307.57,80.55 306.59,79.57 v2(306.59,79.32) 305.59,78.33 UE1.N9
  BOTTOM w0.102: JNGFF2.13 291.8,41.08 292.77,40.11 v1(296.15,40.11)
SLOT2_CONFIG_1: length 10.1
  TOP w0.102: RPE9.1 309.53,81.02 v1(309.14,81.41) v2(308.64,81.41) 308.22,80.99 307.32,80.99 305.83,79.49 304.73,79.49 UE1.M10
  BOTTOM w0.102: v1(304.35,44.77) 303.99,44.42 303.99,42.79 303.8,42.6 JNGFF2.61
SLOT2_CONFIG_2: length 9.6
  TOP w0.102: RPE9.2 309.84,80.52 309.57,80.79 v1(309.12,80.79) 307.41,80.79 305.74,79.13 UE1.N10
  BOTTOM w0.102: v1(304.98,44.77) 305.53,44.23 305.53,43.36 305.3,43.13 JNGFF2.67 ; v1(309.12,80.79) v2(308.62,80.79)
SLOT2_CONFIG_3: length 12.8
  TOP w0.102: v1(309.28,79.7) 309.45,79.52 RPE9.4 ; v1(294.96,44.79) v2(294.62,44.16)
  TOP w0.112: v1(299.16,73.93) UE1.F4
  BOTTOM w0.102: JNGFF2.1 286.8,43.35 288.29,44.85 288.78,44.85 289.03,45.1 294.65,45.1 v1(294.96,44.79)
SLOT2_SATA_LED#: length 11.4
  TOP w0.102: v1(259.06,27.3) 259.64,26.71 v2(259.64,25.85) 259.64,24.38 260.3,23.72 264,23.72 v1(264.8,24.52)
  BOTTOM w0.102: v1(288.79,50.79) 289.11,50.47 289.11,49.98 289.05,49.92 JNGFF2.10 ; RN101.1 v1(264.8,24.52)
SM_RCOMP0: length 10.5
  TOP w0.254: 127.89,48.41 127.51,48.78 127.51,50.72 v1(127.07,51.16)
  TOP w0.381: 127.89,48.41 128.66,47.64 128.66,46.5 v2(130.12,45.03) 130.94,44.21 RC5.1
  BOTTOM w0.254: v1(127.07,51.16) 127.11,51.21 127.46,51.48 127.47,51.48 UC1.AR18
SM_RCOMP1: length 10.2
  TOP w0.381: RC6.1 128.91,43.22 v2(127.91,44.22) 126.62,45.5 126.62,46.25 126.5,46.37 126.5,47.39 125.74,48.15 125.74,49.36 126.83,50.45 v1(127.03,50.45)
  BOTTOM w0.254: v1(127.03,50.45) 127.03,50.46 127.49,50.8 UC1.AT18
SM_RCOMP2: length 9.3
  TOP w0.381: RC7.1 129.93,43.72 127.77,45.88 127.77,47.01 126.47,48.31 126.47,48.98 127.03,49.55 v1(127.03,49.87)
  BOTTOM w0.254: UC1.AU18 127.47,50.19 v1(127.03,49.87)
SML0_SMBCLK: length 61
  TOP w0.102: UL1.28 275.16,86.74 274.34,86.74 v1(274.26,86.83)
  BOTTOM w0.076: UC1.R9 132.78,61.73 133.79,60.72 133.79,60.55 134,60.34 134.56,60.34 135.13,59.76 135.13,59.51 135.38,59.26 137.12,59.26 arc(137.15,59.23) 137.19,59.2 arc(137.32,59.16) 137.45,59.14 138.59,59.14 138.77,59.32 139.25,59.32 139.34,59.23 139.71,59.23 139.74,59.2 139.76,59.2
  BOTTOM w0.102: RC347.1 150.12,60.37 150.5,60.75 151.61,60.75 151.87,61.01 151.87,61.77 151.36,62.27 151.36,62.43 150.73,63.06 150.53,63.06 149.67,63.92 149.67,65.58 150.7,66.61 150.7,67.13 151.39,67.82 151.39,68.29 152.31,69.22 158.04,69.22 159.44,67.82 163.96,67.82 164.74,67.04 168.46,67.04 174.34,61.16 175.59,61.16 175.69,61.06 v1(175.69,60.98) ; RC347.1 RC19.1 ; RC347.1 CC318.1 148.73,60.72 147.77,60.72 147.47,60.42 144.18,60.42 143.19,59.43 140.46,59.43 140.24,59.2 139.76,59.2
SML0_SMBDATA: length 55.2
  TOP w0.102: v1(273.82,85.11) 274.45,85.11 274.76,85.42 UL1.31
  BOTTOM w0.076: 139.76,59.43 139.74,59.43 139.7,59.39 139.41,59.39 139.32,59.48 138.7,59.48 138.52,59.31 137.45,59.31 arc(137.36,59.32) 137.27,59.35 137.19,59.43 136.96,59.43 UC1.W2
  BOTTOM w0.102: v1(175.69,61.56) 175.69,61.56 175.52,61.39 174.44,61.39 168.56,67.27 164.83,67.27 164.05,68.05 159.53,68.05 158.14,69.44 152.22,69.44 151.16,68.39 151.16,67.91 150.47,67.22 150.47,66.71 149.44,65.68 149.44,63.82 150.43,62.83 150.63,62.83 151.14,62.33 151.14,62.18 151.64,61.67 151.64,61.11 151.52,60.98 150.5,60.98 150.12,61.36 RC348.1 RC20.1 148.69,60.95 147.67,60.95 147.38,60.65 144.09,60.65 143.1,59.66 140.37,59.66 140.14,59.43 139.76,59.43
SML1_SMBCLK: length 34.7
  TOP w0.102: v1(297.56,77.88) 297.6,77.88 UE1.D8
  BOTTOM w0.076: 143.76,62.06 143.76,62.05 143.74,62.03 143.74,61.73 142.66,60.65 139.97,60.65 139.26,59.94 138.17,59.94 138.07,59.84 137.4,59.84 arc(137.34,59.83) 137.28,59.8 arc(137.21,59.79) 137.14,59.78 137.09,59.78 arc(137.06,59.78) 137.03,59.79 136.99,59.8 arc(136.96,59.81) 136.92,59.83 136.92,59.83 arc(136.9,59.85) 136.87,59.85 136.76,59.85 arc(136.7,59.85) 136.65,59.82 136.65,59.82 arc(136.58,59.79) 136.51,59.78 136.37,59.78 UC1.W3
  BOTTOM w0.102: 143.76,62.06 143.76,62.51 144.96,63.72 145.34,63.72 CC319.1 ; RC15.1 CC319.1 ; CC319.1 146.18,63.9 146.96,63.9 147.21,63.64 148.52,63.64 148.86,63.98 148.86,66.38 150.67,68.19 150.67,68.67 151.95,69.95 158.66,69.95 159.86,68.75 161.14,68.75 161.4,69 161.4,69.35 v1(161.53,69.49)
SML1_SMBDATA: length 34.5
  TOP w0.102: UE1.E11 v1(298.36,80.33)
  BOTTOM w0.076: UC1.V3 136.13,59.94 136.51,59.94 arc(136.53,59.95) 136.55,59.96 arc(136.65,60) 136.76,60.02 136.87,60.02 arc(136.95,60.01) 137.02,59.97 arc(137.03,59.96) 137.04,59.96 137.07,59.95 arc(137.08,59.95) 137.09,59.95 137.14,59.95 arc(137.18,59.95) 137.22,59.96 arc(137.31,59.99) 137.4,60 138,60 138.1,60.11 139.19,60.11 139.9,60.81 142.59,60.81 143.58,61.8 143.58,62 143.53,62.05 143.53,62.06
  BOTTOM w0.102: v1(160.95,69.49) 161.17,69.27 161.17,69.1 161.04,68.98 159.96,68.98 158.76,70.18 151.86,70.18 150.44,68.76 150.44,68.29 148.63,66.48 148.63,64.07 148.43,63.87 147.31,63.87 147.05,64.13 146.21,64.13 RC17.1 145.67,64.05 145.57,63.95 144.87,63.95 143.53,62.61 143.53,62.06
SNB_+1VALWP: length 1.3
  BOTTOM w0.102: PC302.1 v2(173.26,91.78)
SNUB_1.8VALW: length 1.4
  TOP w0.102: PR502.2 126.76,105.48 v2(127.07,105.17)
SNUB_1V_PRIM: length 3
  TOP w0.102: PR409.2 126.5,108.35 126.5,107.14 v2(127.01,106.63)
SNUB_1VS_VCCIO: length 1.4
  TOP w0.102: v2(136.75,106.73) PR405.2
SNUB_CHG1:
  vias: v2(17.53,24.99)
SNUB_CHG2: length 2.7
  TOP w0.102: PR924.2 31.85,20.45 v2(33.35,21.94)
SPKR: length 2.7
  TOP w0.102: RC183.1 148.98,37.36 v1(149.01,37.36) ; RA12.2 301.39,27.5 v1(301.44,27.45) v2(301.44,26.84)
  BOTTOM w0.102: v1(135.35,49.77) 135.07,49.49 UC1.AW5
SPKR_R: length 3.4
  TOP w0.254: CA72.1 299.6,29.88 CA27.1 ; CA72.1 299.89,28.67 RA12.1 ; CA72.1 299.22,29.05 RA51.1
SRTCRST#: length 3.3
  TOP w0.102: RC56.1 CC24.1 134.75,39.8 v1(134.07,40.48) 133.74,40.81 v2(133.48,40.81)
  BOTTOM w0.076: v1(127.03,52.52) 127.36,52.8 UC1.AN18
SS_1V_PRIM: length 3.1
  TOP w0.102: PR428.1 v2(133.72,114.04)
  TOP w0.254: PR428.1 PC420.1 133.67,112.34 PU402.7
SS_1VS_VCCIO: length 5.2
  TOP w0.102: PR427.1 145.22,110.03 v2(146.69,110.03)
  TOP w0.254: PU401.7 144.14,109.99 PR427.1 PC410.1
SUSACK#: length 1.8
  TOP w0.107: v1(303.18,81.15) UE1.K12
  BOTTOM w0.076: v1(130.65,52.44) 130.94,52.15 UC1.AP11
  BOTTOM w0.102: v2(303.18,81.7) v1(303.18,81.15)
SUSCLK: length 79
  TOP w0.102: v1(198.99,13.81) 198.89,13.91 197.72,13.91 197.24,13.43 RZ56.1 ; v1(130.31,40.89) 130.4,40.79 v2(131.3,40.79) 131.57,40.79 132.06,40.3 133.27,40.3 133.74,39.84 RC48.1 ; RN99.2 v1(293.13,27.07)
  BOTTOM w0.076: 129.65,43.69 127.99,45.34 127.99,47.27 127.72,47.53 UC1.BA17
  BOTTOM w0.102: v1(179.94,22.45) 179.94,22.85 179.1,23.68 135.68,23.68 131.47,27.89 131.47,38.69 130.31,39.86 v1(130.31,40.89) 130.31,41.4 129.65,42.06 129.65,43.69
SUSCLK_R: length 2.6
  TOP w0.102: RN99.1 292.22,27.4 v1(291.89,27.07) v2(292.27,26.68)
  BOTTOM w0.102: JNGFF3.68 291.2,26.86 291.41,27.07 v1(291.89,27.07)
SW1_ISL88738: length 0.8
  TOP w0.102: v1(21.09,27.67) 21.11,27.69 v2(21.11,28.49)
  vias: v1(21.11,27.02) v1(21.79,27.64) v1(21.86,27.03) v1(22.49,27.64) v1(22.56,27)
SW2_DP1_AUXN: length 12.7
  TOP w0.094: CT81.1 28.61,87.72 28.61,87.99 v1(28.41,88.19) ; UV7.61 96.14,95.72 96.03,95.61 95.57,95.61 95.2,95.24 94.97,95.24 94.82,95.39 RV70.1 94.3,95.18 93.44,95.18 92.23,93.97 92.23,90.64 91.55,89.96 91.02,89.96 90.93,90.05 v1(90.93,90.31)
  BOTTOM w0.094: CT116.1 21.82,88.49 21.82,88.33 v1(21.62,88.13)
SW2_DP1_AUXN_C: length 3.5
  TOP w0.094: v1(21.21,90.51) 21.26,90.51 21.62,90.15 21.62,89.91 RT131.1
  BOTTOM w0.094: UT9.25 21.01,91.38 21.15,91.24 21.15,91.14 21.37,90.91 21.37,90.67 v1(21.21,90.51) 21.26,90.51 21.68,90.09 21.68,89.97 RT131.1
SW2_DP1_AUXP: length 12.7
  TOP w0.094: v1(90.74,89.45) 91.06,89.77 91.62,89.77 92.42,90.57 92.42,93.9 93.52,95 94.36,95 94.79,94.57 RV76.1 94.82,94.89 94.99,95.06 95.28,95.06 95.65,95.43 96.07,95.43 96.17,95.32 UV7.62 ; v1(29,88.19) 28.8,87.99 28.8,87.72 CT80.1
  BOTTOM w0.094: CT115.1 22.01,88.49 22.01,88.33 v1(22.2,88.13)
SW2_DP1_AUXP_C: length 3.4
  TOP w0.094: v1(21.83,90.51) 21.83,90.28 RT130.1
  BOTTOM w0.094: RT130.1 22.28,89.76 21.83,90.2 v1(21.83,90.51) 21.56,90.78 21.56,90.99 21.34,91.21 21.34,91.35 21.41,91.42 UT9.24
SW2_DP1_CADET: length 4.5
  TOP w0.102: v1(100.15,100.22) v2(99.81,99.88) 99.75,99.83 99.75,99.45 99.69,99.38 99.69,99.12 100.41,98.4 UV7.48
  BOTTOM w0.102: RV73.1 99.7,101.18 100.21,100.67 100.21,100.28 v1(100.15,100.22)
SW2_DP1_HPD: length 3.2
  TOP w0.102: v1(98.1,98.95) 98.41,98.64 UV7.53 ; RT73.2 v1(35.5,74.44) ; RT380.1 17.96,92.16 v1(18.32,92.16) 18.67,92.51 v2(18.67,92.6)
SW2_DP1_HPD_R: length 5.5
  TOP w0.076: 33.9,77.09 33.9,77.22 34.02,77.34 34.02,77.76 33.9,77.89 33.9,78.32 34.11,78.54 UT5.C10
  TOP w0.102: v2(36.63,74.92) 36.38,75.18 36.37,75.18 35.91,75.63 35.86,75.69 35.86,75.9 35.72,76.04 RT73.1 35.07,76.47 34.36,76.47 33.9,76.94 33.9,77.09
SW2_DP1_N0: length 3.5
  TOP w0.094: UV7.54 98.01,98.35 97.9,98.46 97.9,98.61 97.54,98.96 96.93,98.96 v1(96.65,99.25)
  BOTTOM w0.094: v1(27.23,97.57) 26.99,97.8 26.87,97.8 26.68,97.99 26.6,97.99 26.24,97.63 CT104.1
SW2_DP1_N0_C: length 3.2
  BOTTOM w0.094: CT104.2 24.9,97.98 24.62,97.98 24.26,97.62 v4(24.26,97.4) 24.26,97.04 23.89,96.67 23.72,96.67 23.61,96.56 UT9.10
SW2_DP1_N1: length 5.5
  TOP w0.094: v1(97.44,100.03) 97.66,99.8 97.82,99.8 98.08,99.54 98.3,99.54 98.75,99.09 98.75,99 99.08,98.67 99.08,98.53 99.21,98.4 UV7.51
  BOTTOM w0.094: CT106.1 26.24,95.85 26.37,95.98 28.12,95.98 v1(28.36,95.74)
SW2_DP1_N1_C: length 2.5
  BOTTOM w0.094: UT9.13 23.73,95.36 23.84,95.47 24.37,95.47 24.84,95.94 24.91,95.94 CT106.2
SW2_DP1_N2: length 4.5
  TOP w0.094: UV7.49 100.01,98.46 99.21,99.25 99.21,99.44 v1(99.37,99.6)
  BOTTOM w0.094: v1(28.35,93.71) 28.11,93.94 27.59,93.94 27.58,93.94 26.86,93.94 26.85,93.94 26.38,93.94 26.24,93.81 CT108.1
SW2_DP1_N2_C: length 2.4
  BOTTOM w0.094: UT9.16 23.68,94.16 23.76,94.25 24.23,94.25 v4(24.42,94.06) 24.58,93.9 24.92,93.9 CT108.2
SW2_DP1_N3: length 5.2
  TOP w0.094: v1(100.7,99.32) 100.51,99.13 100.51,99 100.61,98.9 100.91,98.9 101.1,98.72 101.1,98.45 101.21,98.34 UV7.46
  BOTTOM w0.094: CT110.1 26.66,91.87 26.84,91.87 26.93,91.78 26.93,91.48 26.92,91.47 26.92,90.89 26.93,90.88 26.93,90.1 27.18,89.85 27.43,89.85 v1(27.61,89.67)
SW2_DP1_N3_C: length 3.2
  BOTTOM w0.094: UT9.19 23.69,92.96 23.81,93.08 24.17,93.08 24.47,92.78 v4(24.47,92.47) 24.47,92.08 24.67,91.87 24.91,91.87 CT110.2
SW2_DP1_P0: length 3.1
  TOP w0.094: v1(96.65,98.66) 96.76,98.78 97.46,98.78 97.71,98.53 97.71,98.43 97.61,98.32 UV7.55
  BOTTOM w0.094: v1(27.23,98.15) 27.06,97.99 26.95,97.99 26.76,98.18 26.56,98.18 26.24,98.49 CT103.1
SW2_DP1_P0_C: length 3.2
  BOTTOM w0.094: CT103.2 24.93,98.17 24.55,98.17 24.07,97.69 24.07,97.11 23.81,96.85 23.74,96.85 23.63,96.96 UT9.9
SW2_DP1_P1: length 4.9
  TOP w0.094: v1(97.44,99.44) 97.61,99.62 97.74,99.62 98,99.36 98.23,99.36 98.57,99.02 98.57,98.92 98.9,98.59 98.9,98.49 98.81,98.4 UV7.52
  BOTTOM w0.094: CT105.1 26.62,96.16 28.2,96.16 v1(28.36,96.32)
SW2_DP1_P1_C: length 2.5
  BOTTOM w0.094: CT105.2 24.92,96.13 24.77,96.13 24.3,95.66 23.8,95.66 23.7,95.76 UT9.12
SW2_DP1_P2: length 4.2
  TOP w0.094: v1(98.79,99.6) 99.03,99.37 99.03,99.18 99.61,98.6 UV7.50
  BOTTOM w0.094: CT107.1 26.62,94.13 v4(27.21,94.13) 28.19,94.13 v1(28.35,94.29)
SW2_DP1_P2_C: length 2.4
  BOTTOM w0.094: CT107.2 24.91,94.09 24.67,94.09 24.32,94.43 23.76,94.43 23.63,94.56 UT9.15
SW2_DP1_P3: length 5.4
  TOP w0.094: v1(100.11,99.32) 100.33,99.1 100.33,98.92 100.53,98.72 100.84,98.72 100.91,98.64 100.91,98.47 100.81,98.37 UV7.47
  BOTTOM w0.094: v1(27.61,90.25) 27.39,90.04 27.26,90.04 27.12,90.18 v4(27.12,91.18) 27.12,91.85 26.91,92.06 26.34,92.06 26.24,92.16 CT109.1
SW2_DP1_P3_C: length 3.2
  BOTTOM w0.094: CT109.2 24.92,92.06 24.75,92.06 24.66,92.15 24.66,92.85 24.25,93.26 23.78,93.26 23.68,93.36 UT9.18
SW2_DP2_AUXN: length 28
  TOP w0.094: v1(92.39,98.25) 92.19,98.05 92.19,97.62 92.53,97.28 94.24,97.28 94.82,97.87 RV71.1 94.82,97.4 94.98,97.25 95.22,97.25 95.64,96.83 95.64,96.53 95.76,96.41 96.16,96.41 96.27,96.52 UV7.59
  BOTTOM w0.094: CV150.1 204.71,29.18 204.4,29.49 204.4,30.2 204.1,30.5 203.03,31.57 199.84,31.57 194.58,36.84 194.58,44.12 v1(194.78,44.32)
SW2_DP2_AUXN_C: length 12.2
  BOTTOM w0.094: CV150.2 204.55,28.26 204.4,28.11 204.4,27.78 204.62,27.55 204.67,27.55 205.08,27.14 205.08,27.09 205.53,26.64 205.53,20.86 206.71,19.69 207.91,19.69 208.22,20 JNGFF1.12
SW2_DP2_AUXP: length 28
  TOP w0.094: UV7.60 96.25,96.12 96.14,96.23 95.68,96.23 95.45,96.45 95.45,96.75 95.14,97.06 94.92,97.06 94.82,96.97 RV77.1 94.32,97.1 92.45,97.1 92.01,97.54 92.01,98.05 v1(91.81,98.25)
  BOTTOM w0.094: v1(194.19,44.32) 194.39,44.12 194.39,36.76 199.77,31.39 202.95,31.39 204.21,30.12 204.21,29.55 CV149.1
SW2_DP2_AUXP_C: length 12.1
  BOTTOM w0.094: JNGFF1.14 206.63,19.5 205.34,20.79 205.34,26.57 v4(204.72,27.19) 204.21,27.7 204.21,27.89 CV149.2
SW2_DP2_CADET: length 4.6
  TOP w0.102: v1(103.92,100.42) 104.35,100.42 104.99,99.78 v2(104.99,99.5) 104.99,98.78 104.81,98.59 UV7.37
  BOTTOM w0.102: RV74.1 104.02,100.55 103.92,100.45 v1(103.92,100.42)
SW2_DP2_HPD: length 50.8
  TOP w0.102: v1(102.9,100.35) 102.9,100.19 102.65,99.94 102.65,98.7 102.81,98.54 UV7.42
  BOTTOM w0.102: v1(201.05,22.46) 202.37,21.14 202.37,17.57 202.05,17.25 JNGFF1.23 ; v1(102.9,100.35) 102.9,100.17 102.67,99.94 102.67,99.54 102.95,99.26 103.41,99.26 103.54,99.38 104.04,99.38 104.12,99.46 104.65,99.46 104.91,99.71 106.22,99.71 106.67,99.27 107.6,99.27 108.75,100.42 117.54,100.42 118.78,99.18 128.84,99.18 v2(131.3,96.71) 135.51,92.5 135.51,89.61 v1(134.96,89.06)
SW2_DP2_N0: length 22.6
  TOP w0.094: v1(102.22,99.22) 102.03,99.03 102.03,98.9 102.27,98.65 102.27,98.49 102.41,98.36 UV7.43
  BOTTOM w0.094: v1(191.86,45.47) 191.66,45.27 191.66,36.88 198.42,30.12 200.17,30.12 200.38,29.91 200.38,29.59 CV156.1
SW2_DP2_N0_C: length 17.6
  BOTTOM w0.094: CV156.2 200.51,28.26 200.27,28.03 200.27,27.78 v4(200.74,27.31) 201.18,26.86 203.59,26.86 203.9,26.56 203.9,20.52 207.62,16.8 207.94,16.8 208.14,17 JNGFF1.24
SW2_DP2_N1: length 29.6
  TOP w0.094: UV7.40 103.61,98.51 103.44,98.67 103.44,99.55 v1(103.69,99.79)
  BOTTOM w0.094: CV152.1 202.41,29.59 202.41,30.09 201.69,30.81 199.21,30.81 193.11,36.91 193.11,45.66 189.46,49.31 189.46,49.61 v1(189.66,49.81)
SW2_DP2_N1_C: length 14.9
  BOTTOM w0.094: CV152.2 202.54,28.26 202.36,28.08 202.36,27.73 202.64,27.45 202.85,27.45 202.89,27.48 203.47,27.48 203.5,27.45 203.86,27.45 204.72,26.59 204.72,20.55 207,18.27 207.91,18.27 208.14,18.5 JNGFF1.18
SW2_DP2_N2: length 36.4
  TOP w0.094: v1(104.46,98.96) 104.27,98.78 104.27,98.67 104.41,98.54 UV7.38
  BOTTOM w0.094: v1(188.37,48.59) 188.17,48.39 188.17,40.18 189.62,38.73 189.62,32.73 195.48,26.87 195.48,19.46 196.61,18.33 197.64,18.33 197.81,18.5 CV148.1
SW2_DP2_N2_C: length 2.9
  BOTTOM w0.094: JNGFF1.17 200.52,18.75 200.36,18.59 199.5,18.59 199.3,18.4 199.14,18.4 CV148.2
SW2_DP2_N3: length 31.7
  TOP w0.094: v1(106.01,99.16) 105.79,98.95 105.79,98.83 105.51,98.56 105.51,98.45 105.61,98.36 UV7.35
  BOTTOM w0.094: CV145.1 197.81,20.74 197.47,20.41 197.3,20.41 197.21,20.5 197.21,21.19 196.06,22.33 196.06,27.11 190.35,32.82 190.35,44.72 189.89,45.18 189.89,46.6 v1(190.16,46.87)
SW2_DP2_N3_C: length 2.9
  BOTTOM w0.094: CV145.2 199.14,20.43 199.65,20.43 199.98,20.09 200.35,20.09 200.51,20.25 JNGFF1.11
SW2_DP2_P0: length 22.6
  TOP w0.094: UV7.44 102.01,98.36 102.09,98.45 102.09,98.58 101.85,98.82 101.85,99.02 v1(101.64,99.22)
  BOTTOM w0.094: v1(191.28,45.47) 191.47,45.28 191.47,36.8 198.34,29.93 200.1,29.93 200.19,29.84 200.19,29.59 CV157.1
SW2_DP2_P0_C: length 17.6
  BOTTOM w0.094: CV157.2 200.09,27.95 200.09,27.7 200.38,27.41 200.38,27.36 200.79,26.95 200.84,26.95 201.11,26.68 203.51,26.68 203.71,26.48 203.71,20.45 207.54,16.61 207.97,16.61 208.08,16.5 JNGFF1.26
SW2_DP2_P1: length 29.5
  TOP w0.094: UV7.41 103.21,98.46 103.26,98.51 103.26,99.64 v1(103.1,99.79)
  BOTTOM w0.094: CV153.1 202.22,29.59 202.22,30.02 201.61,30.63 199.13,30.63 192.92,36.83 192.92,45.58 192.42,46.08 189.27,49.23 189.27,49.61 v1(189.07,49.81)
SW2_DP2_P1_C: length 15
  BOTTOM w0.094: CV153.2 202.17,27.9 202.17,27.65 202.56,27.26 v4(203.18,27.26) 203.79,27.26 204.54,26.51 204.54,20.47 206.92,18.09 207.96,18.09 208.05,18 JNGFF1.20
SW2_DP2_P2: length 36.5
  TOP w0.094: v1(103.87,98.96) 104.09,98.75 104.09,98.61 104.01,98.53 UV7.39
  BOTTOM w0.094: v1(187.78,48.59) 187.98,48.39 187.98,40.1 189.43,38.65 189.43,32.65 195.29,26.79 195.29,19.39 196.54,18.14 197.47,18.14 CV147.1
SW2_DP2_P2_C: length 2.9
  BOTTOM w0.094: JNGFF1.19 200.48,18.25 200.33,18.41 199.57,18.41 199.38,18.22 199.14,18.22 CV147.2
SW2_DP2_P3: length 31.9
  TOP w0.094: v1(105.42,99.16) 105.48,99.16 105.6,99.04 105.6,98.91 105.33,98.63 105.33,98.45 105.21,98.33 UV7.36
  BOTTOM w0.094: CV146.1 197.42,20.22 197.22,20.22 197.02,20.42 197.02,21.11 195.88,22.26 195.88,27.03 190.17,32.74 190.17,44.65 189.71,45.11 189.71,46.74 v1(189.58,46.87)
SW2_DP2_P3_C: length 2.9
  BOTTOM w0.094: JNGFF1.13 200.52,19.75 200.36,19.91 199.9,19.91 199.56,20.24 199.14,20.24 CV146.2
SW2_DP3_AUXN: length 23.5
  TOP w0.094: v1(95.4,101.38) 95.2,101.58 93.25,101.58 92.28,100.61 92.28,99.74 92.58,99.44 94.36,99.44 RV72.1 95.01,99.71 95.01,99.54 95.12,99.42 95.31,99.42 95.51,99.22 95.51,97.75 96.06,97.2 96.19,97.2 96.32,97.32 UV7.57
  BOTTOM w0.094: v1(263.4,53.96) 263.41,53.96 263.54,54.09 269.58,54.09 272.29,56.81 272.29,57.87 272.44,58.02 272.61,58.02 272.77,57.86 272.77,57.44 CV112.1
SW2_DP3_AUXN_C: length 4.4
  TOP w0.094: v1(274.4,57.45) 274.4,57.72 274.56,57.88 274.78,57.88 275.07,57.59 275.07,57.29 274.83,57.05 274.83,56.13 275.29,55.67 UV6.3
  BOTTOM w0.094: v1(274.4,57.45) 273.86,57.45 CV112.2
SW2_DP3_AUXP: length 23.8
  TOP w0.094: UV7.58 96.29,96.92 96.21,97.01 95.99,97.01 95.33,97.67 95.33,99.14 95.23,99.24 95.1,99.24 95.01,99.14 95.01,98.94 RV78.1 94.33,99.26 92.5,99.26 92.09,99.66 92.09,100.69 93.17,101.77 95.21,101.77 v1(95.4,101.96)
  BOTTOM w0.094: v1(263.4,54.55) 263.67,54.28 269.5,54.28 272.11,56.89 272.11,57.95 272.36,58.2 272.56,58.2 CV111.1
SW2_DP3_AUXP_C: length 4.4
  TOP w0.094: v1(274.4,58.59) 274.4,58.23 274.57,58.07 274.86,58.07 275.26,57.67 275.26,57.22 275.02,56.98 275.02,56.2 275.15,56.07 UV6.2
  BOTTOM w0.094: v1(274.4,58.59) 274.31,58.5 CV111.2
SW2_DP3_CADET: length 2.4
  TOP w0.102: RV75.1 v2(107.8,94.26) 107.54,94.52 UV7.26
SW2_DP3_HPD: length 7.9
  TOP w0.102: UV7.31 108.83,96.52 v1(109.43,95.93) ; v1(274.32,59.18) 274.85,59.18 275.34,58.69 275.34,58.28 276.29,57.33 UV6.32
  BOTTOM w0.102: v2(273.58,59.82) RV102.1 274.52,59.38 v1(274.32,59.18)
SW2_DP3_N0: length 10.3
  TOP w0.094: UV7.32 107.07,96.92 107.18,97.03 111.25,97.03 112.95,98.73 114.66,98.73 v1(114.87,98.52)
  BOTTOM w0.094: v1(271.59,54.47) 271.79,54.67 271.99,54.67 272.18,54.85 272.31,54.85 CV108.1
SW2_DP3_N0_C: length 2.7
  TOP w0.094: UV6.6 275.23,54.47 274.58,55.13 274.5,55.13 v1(274.27,54.9)
  BOTTOM w0.094: CV108.2 273.91,54.95 274.22,54.95 v1(274.27,54.9)
SW2_DP3_N1: length 15.8
  TOP w0.094: v1(114.88,97.26) 114.68,97.46 113.96,97.46 111.51,95.02 108.61,95.02 107.78,95.84 107.09,95.84 106.97,95.72 UV7.29
  BOTTOM w0.094: CV110.1 272.25,53.14 269.25,53.14 268.44,52.32 267.3,52.32 v1(267.08,52.1)
SW2_DP3_N1_C: length 2.7
  TOP w0.094: UV6.8 274.76,53.67 274.71,53.72 v1(274.2,53.72)
  BOTTOM w0.094: v1(274.2,53.72) 274.2,53.57 273.51,52.88 CV110.2
SW2_DP3_P0: length 10.4
  TOP w0.094: v1(114.87,99.1) 114.69,98.92 112.87,98.92 111.17,97.21 107.19,97.21 107.08,97.32 UV7.33
  BOTTOM w0.094: v1(271.59,55.05) 271.78,54.86 271.92,54.86 272.13,55.07 272.22,55.07 CV107.1
SW2_DP3_P0_C: length 2.6
  TOP w0.094: UV6.5 275.1,54.87 274.66,55.31 274.44,55.31 v1(274.27,55.48)
  BOTTOM w0.094: v1(274.27,55.48) 273.96,55.17 273.8,55.17 CV107.2
SW2_DP3_P1: length 15.8
  TOP w0.094: v1(114.88,97.85) 114.69,97.65 113.88,97.65 111.43,95.2 108.68,95.2 107.86,96.03 107.1,96.03 107.01,96.12 UV7.30
  BOTTOM w0.094: v1(267.08,52.68) 267.25,52.51 268.37,52.51 269.18,53.32 272.25,53.32 CV109.1
SW2_DP3_P1_C: length 2.7
  TOP w0.094: v1(274.2,54.3) 274.6,53.91 274.79,53.91 274.83,53.86 275.06,53.86 275.28,54.07 UV6.7
  BOTTOM w0.094: CV109.2 273.57,53.67 v1(274.2,54.3)
SW2_ISL88738: length 1.6
  TOP w0.102: v2(28.5,22.6) 28.78,22.88 29.98,22.88
  vias: v1(30.8,22.18) v1(31.5,22.18)
SW_+1VALWP: length 0.6
  TOP w0.102: v3(179.77,92.17) v1(179.77,91.59)
  vias: v1(179.71,96.22) v1(180.03,96.73) v1(180.41,91.59)
SW_USB20_N1: length 22.8
  TOP w0.094: UI3.11 308.99,58.12 308.93,58.06 308.64,58.06 308.19,57.61 v4(307.42,57.61) 306.78,57.61 306.63,57.46 306.63,57.01 306.82,56.81 307.95,56.81 307.96,56.82 308.61,56.82 308.62,56.81 308.69,56.81 308.98,56.52 308.98,55.81 308.69,55.51 307.35,55.51 306.76,54.92 306.76,54.68 305.68,53.6 305.68,52.65 306.19,52.14 306.68,52.14 307.42,51.4 307.42,45.82 308.35,44.88 308.75,44.88 308.86,44.99 308.86,45.1 308.72,45.24 308.55,45.24 308.44,45.34 LI7.1
SW_USB20_P1: length 22.9
  TOP w0.094: UI3.10 308.49,58.17 308.12,57.79 307.75,57.79 307.74,57.8 307.1,57.8 307.1,57.79 306.7,57.79 306.44,57.53 306.44,56.93 306.74,56.63 v4(308.28,56.63) 308.61,56.63 308.8,56.44 308.8,55.89 308.61,55.7 307.27,55.7 306.57,55 306.57,54.75 305.49,53.67 305.49,52.57 306.11,51.96 306.6,51.96 307.24,51.32 307.24,45.74 308.28,44.7 308.83,44.7 309.04,44.91 309.04,45.18 LI7.4
SYS_LED_MASK#: length 41.3
  TOP w0.102: QL1.5 281.88,98.32 v1(282.13,98.56) 282.91,98.56 QL1.2 ; RE21.1 298.43,65.12 298.18,65.12 297.23,66.06 296.61,66.06 295.99,65.44 295.35,65.44 295.15,65.64 v1(295.15,66.19) 294.65,65.68 294.65,62.38 293.49,61.22 291.49,61.22 v2(290.77,60.5) 290.34,60.07 288.93,60.07 288.75,59.89 284.66,59.89 283.31,58.53 283.31,57.42 282.53,56.64 282.53,55.87 282.78,55.62 283.16,55.62 283.66,55.12 283.66,53.1 282.86,52.31 282.86,51.47 280.49,49.1 UZ10.1 ; v1(293.86,83.24) 294.34,83.24 294.59,82.99 294.59,81.89 295.56,80.93 UE1.A12 ; QL2.2 v1(279.15,98.32)
SYS_PWROK: length 39.7
  TOP w0.102: v1(61.28,42.83) 62.05,42.83 62.36,42.51 RC129.1 ; RE56.1 302.65,68.97 302.65,69.15 v1(302.1,69.7) ; v1(165.48,74.88) v3(165.48,75.7)
  TOP w0.107: UE1.G4 300,73.97 v1(300,73.93)
  BOTTOM w0.076: UC1.B6 134.85,68.97 134.85,69.2 134.92,69.27 134.92,69.51 134.88,69.54 134.88,69.84 135.84,70.8 135.91,70.8
  BOTTOM w0.102: v1(165.48,74.88) 159.27,74.88 158.2,73.81 151.47,73.81 150.2,75.08 142.51,75.08 138.24,70.8 135.91,70.8
SYS_RESET#: length 63
  BOTTOM w0.076: UC1.B5 135.88,69.06 136.18,68.76 136.48,68.76 136.62,68.91 137.11,68.91 137.37,69.17 137.48,69.17 139.36,71.06
  BOTTOM w0.102: RC291.1 146.31,89.41 RC224.2 CC302.1 147.25,86.62 147.9,85.98 v2(152.75,85.98) 153.87,85.98 164.47,75.38 165.74,75.38 166.06,75.06 166.06,74.39 v1(165.95,74.28) 159.64,74.28 158.65,73.3 150.96,73.3 149.74,74.52 142.82,74.52 139.36,71.06 ; v1(316.83,68.47) 317.05,68.25 JAPS1.13
SYS_RESET#_R: length 3.6
  BOTTOM w0.102: UC12.4 147.95,88.68 RC224.1 RC290.2 149.28,88.26 149.71,87.83 v2(149.71,87.39)
TBT_FORCE_PWR: length 12.7
  BOTTOM w0.102: T19.1 139.2,78.95 139.2,75.96 133.64,70.41 133.64,69.44 133.94,69.14 UC1.B7
TBT_RESET_N_EC_R: length 5.4
  TOP w0.102: RE95.2 314.01,78.77 312.98,78.77 v1(312.83,78.92)
  TOP w0.107: v1(306.2,78) 306.08,77.87 303.9,77.87 UE1.L8
  BOTTOM w0.102: v2(305.94,78.47) 306.2,78.21 v1(306.2,78)
TBTA_AUXN_C: length 6
  TOP w0.076: 29.38,84.39 29.49,84.27 30.04,84.27 30.89,83.42 30.89,82.9 UT5.J2
  TOP w0.094: CT81.2 28.58,86.59 28.58,86.3 RT95.1 28.52,85.76 28.52,85.24 29.05,84.71 29.06,84.71 29.38,84.39
TBTA_AUXP_C: length 5.5
  TOP w0.076: UT5.J1 31.07,83.11 31.07,83.49 30.11,84.45 29.62,84.45 29.54,84.53
  TOP w0.094: CT80.2 28.79,86.55 28.79,86.34 RT96.1 28.73,85.59 28.73,85.34 v4(28.99,85.08) 29.54,84.53
TBTA_BOT_N: length 3.1
  TOP w0.094: RT122.2 14.38,91.63 14.51,91.63 14.7,91.44 v1(14.7,91.41) ; UT5.L7 28.7,80.04 v1(28.27,79.6)
TBTA_BOT_N_R: length 11.1
  TOP w0.094: v1(6.73,96.57) 6.73,96.59 6.99,96.84 7.08,96.84 7.15,96.78 7.15,94.47 10.01,91.61 11.66,91.61 DT20.1 12.07,91.65 12.58,91.65 RT122.1
  BOTTOM w0.094: JUSBC1.B7 6.63,96.67 v1(6.73,96.57)
TBTA_BOT_P: length 2.9
  TOP w0.076: v1(28.88,79.6) 29.06,79.79 30.36,79.79 30.61,80.04 UT5.K7
  TOP w0.094: RT123.2 14.32,91.84 14.55,91.84 v1(14.7,92)
TBTA_BOT_P_R: length 11.1
  TOP w0.094: RT123.1 12.68,91.86 12.24,91.86 DT19.1 11.42,91.82 10.1,91.82 v4(9.58,92.34) 7.36,94.56 7.36,96.87 7.17,97.06 6.98,97.06 6.89,97.15 v1(6.73,97.15)
  BOTTOM w0.094: v1(6.73,97.15) 6.71,97.18 JUSBC1.B6
TBTA_CC1: length 13.5
  TOP w0.203: UT5.L9 29.92,79.04 29.88,79.07 29.84,79.07
  TOP w0.254: 11.31,94.56 11.57,94.31 DT7.1 12.43,94.31 12.56,94.18 ; 28.4,78.35 28.62,78.58 29.13,78.58 29.62,79.07 29.84,79.07
  TOP w0.381: v1(12.96,93.49) 12.96,93.78 12.56,94.18 ; v1(25.86,78.24) CT86.1 26.12,77.3 RT104.2 26.73,77.59 27.11,77.97 28.01,77.97 28.4,78.35 ; 11.31,94.56 10.83,95.05 10.83,95.84 9.96,96.71 v1(9.78,96.71)
  BOTTOM w0.254: JUSBC1.A5 7.97,96.43 8.23,96.69 8.46,96.69
  BOTTOM w0.381: v1(9.78,96.71) 9.76,96.69 8.46,96.69
TBTA_CC2: length 16.1
  TOP w0.203: 29.78,78.45 29.87,78.54 UT5.L10
  TOP w0.254: 28.74,77.63 28.97,77.63 29.78,78.45 ; 12.45,95.04 DT16.1 11.61,95.04 11.33,95.32 11.33,95.37
  TOP w0.381: 11.33,95.37 11.33,96.06 10.11,97.27 9.34,97.27 9.26,97.2 7.55,97.2 6.99,97.75 v1(6.73,97.75) ; CT85.1 28.26,77.16 28.74,77.63 ; CT85.1 27.64,75.6 v1(27.63,75.58) ; CT85.1 28.33,75.6 28.8,75.13 RT105.2 ; v1(13.59,93.49) 13.59,94.21 v2(12.82,94.98) 12.76,95.04 12.45,95.04
  BOTTOM w0.254: v1(6.73,97.75) 6.65,97.67 JUSBC1.B5
TBTA_DBG_CTL1: length 2.2
  TOP w0.076: v1(32.89,82.01) 32.89,81.8 UT5.E4
  BOTTOM w0.102: RT106.1 33.36,82.48 v1(32.89,82.01) 32.89,81.89 v2(33.23,81.55)
TBTA_DBG_CTL2: length 3
  TOP w0.102: v1(34.18,80.89) 34.04,81.04 UT5.D5
  BOTTOM w0.102: v2(35.84,81.17) 35.23,81.17 RT107.1 34.69,81.4 v1(34.18,80.89)
TBTA_DEBUG1: length 4.1
  TOP w0.102: UT5.L2 29.75,82.54 29.11,83.18 27.72,83.18 v2(27.69,83.2) 27.65,83.24 27.65,83.57 27.39,83.84 RT92.2
TBTA_DEBUG2: length 7
  TOP w0.076: UT5.K2 30.39,82.79 29.91,82.79 29.14,83.56 29.05,83.56 v2(28.85,83.76)
  TOP w0.102: v2(28.85,83.76) 28.62,83.99 27.92,83.99 27.56,84.35 25.16,84.35 RT93.2
TBTA_DEBUG3: length 3.7
  TOP w0.102: RT89.2 27.17,82.47 28.73,82.47 v2(28.78,82.42) 29.16,82.04 UT5.L3
TBTA_DEBUG4: length 8.7
  TOP w0.076: 29.43,82.41 29.56,82.29 30.39,82.29 UT5.K3
  TOP w0.102: v2(23.56,81.76) 24.27,81.76 24.59,82.07 RT90.2 25.04,83.33 27.08,83.33 27.59,82.82 29.02,82.82 29.43,82.41
TBTA_LSRX_R: length 7.3
  TOP w0.076: UT5.K4 30.39,81.79 29.9,81.79
  TOP w0.094: 28.85,81.83 28.89,81.79 29.9,81.79
  TOP w0.102: v2(24.2,80.56) 24.62,80.56 25.56,81.5 26.38,81.5 RT88.2 26.94,82.06 28.62,82.06 28.85,81.83
TBTA_LSTX_R: length 5.6
  TOP w0.094: RT87.2 27.58,81.81 28.53,81.81 28.76,81.58 30.1,81.58 UT5.L4
  TOP w0.102: RT87.2 26.23,80.46 25.89,80.46 v2(25.38,79.95)
TBTA_MRESET: length 2.9
  TOP w0.076: UT5.E11 33.14,77.92 33.25,77.82 33.25,77.01 v2(33.53,76.73)
  TOP w0.102: RT86.1 33.8,76.6 33.66,76.6 v2(33.53,76.73)
TBTA_ROM_CLK_PD: length 6.3
  TOP w0.076: v1(36.01,82.23) 35.54,82.23 35.35,82.04 UT5.A3
  TOP w0.102: RT54.1 32.9,91.74 v2(33.16,91.47) 33.53,91.1 v1(33.53,88.92)
TBTA_ROM_CLK_PD_R: length 9
  TOP w0.102: JDB1.2 31.87,96.2 32.42,95.65 32.42,95.45 RT54.2 v1(32.9,95.65) v2(33.3,96.06)
  BOTTOM w0.102: v1(32.9,95.65) 29.98,98.57 UT6.6
TBTA_ROM_CS#_PD: length 7.7
  TOP w0.076: v1(36.14,82.82) 35.83,82.82 35.29,82.29 34.84,82.29 34.64,82.09 UT5.B3
  TOP w0.102: v1(29.72,88.22) 29.72,89.77 29.85,89.89 v2(29.85,91.03) RT57.1
TBTA_ROM_CS#_PD_R: length 11.2
  TOP w0.102: v1(29.27,95.64) 29.27,95.26 29.57,94.96 RT57.2 29.85,95.29 29.74,95.4 29.74,95.8 v2(29.91,95.97) 30.37,96.42 JDB1.5
  BOTTOM w0.102: v1(29.27,95.64) 29.68,96.05 30.51,96.05 30.66,95.9 30.66,95.27 32.52,93.41 UT6.1 32.52,90.77 RT51.2
TBTA_ROM_DI_PD: length 6.9
  TOP w0.102: v1(30.74,88.22) 30.74,90.8 v2(31.5,91.56) 31.5,93.67 RT55.1 ; UT5.B4 v1(34.01,81.54)
TBTA_ROM_DI_PD_R: length 8.4
  TOP w0.102: v1(31.08,95.61) 31.73,94.96 RT55.2 31.88,95.6 v2(31.52,95.96) 31.37,96.11 JDB1.3
  BOTTOM w0.102: UT6.5 28.71,98.57 31.08,96.19 v1(31.08,95.61)
TBTA_ROM_DO_PD: length 7.4
  TOP w0.076: v1(35.62,81.68) 35.44,81.68 35.29,81.54 UT5.A4
  TOP w0.102: v1(30.74,87.58) 30.33,87.99 30.33,92.19 v2(30.87,92.73) RT56.1
TBTA_ROM_DO_PD_R: length 13.1
  TOP w0.102: v2(27.56,98.89) 27.96,98.49 29.96,98.49 30.87,97.58 JDB1.4 30.87,96.1 30.67,95.89 30.67,95.4 30.87,95.2 RT56.2 30.46,94.96 30.36,95.06 30.36,95.46 v1(30.24,95.58)
  BOTTOM w0.102: v1(30.24,95.58) 30.24,95.16 31.25,94.15 UT6.2 31.25,90.77 RT52.2
TBTA_ROM_HOLD#_PD: length 10.4
  BOTTOM w0.102: UT6.7 31.25,97.98 33.98,95.25 v2(33.98,92.35) 33.98,91.22 RT50.2
TBTA_ROM_WP#_PD: length 3.2
  BOTTOM w0.102: UT6.3 30.1,92.28 RT53.2 29.42,90.65 v2(28.9,90.12)
TBTA_ROSC: length 2.8
  TOP w0.076: UT5.G2 31.89,82.79 v2(31.89,84.24)
  TOP w0.102: RT100.1 31.89,84.83 v2(31.89,84.24)
TBTA_RX1N: length 16
  BOTTOM w0.094: JUSBC1.B10 6.17,95.18 6.31,95.03 6.47,95.03 6.83,94.67 6.83,94.16 7.05,93.93 7.98,93.93 9.23,92.68 9.81,92.68 10.55,91.94 11.09,91.94 DT14.1 11.71,91.95 12.9,91.95 v4(13.25,92.31) 13.7,92.75 15.25,92.75 15.46,92.97 15.46,92.98 15.82,93.33 15.83,93.33 16.09,93.6 17.84,93.6 18.17,93.27 18.48,93.27 18.57,93.36 UT9.31
TBTA_RX1P: length 16
  BOTTOM w0.094: JUSBC1.B11 6.12,94.67 6.12,94.67 6.26,94.82 6.38,94.82 6.61,94.58 6.61,94.07 6.96,93.72 7.89,93.72 9.15,92.47 9.72,92.47 10.47,91.73 11.09,91.73 DT13.1 11.73,91.74 12.98,91.74 13.79,92.54 15.33,92.54 v4(15.8,93) 16.18,93.39 17.75,93.39 18.09,93.05 18.48,93.05 18.57,92.96 UT9.30
TBTA_RX2N: length 15.9
  BOTTOM w0.094: UT9.39 18.57,96.56 18.48,96.65 18.26,96.65 17.89,97.03 17.89,97.18 17.57,97.49 17.57,97.49 17.17,97.88 17.17,97.89 15.36,99.71 v4(15.36,100.22) 15.36,100.9 14.63,101.62 13.84,101.62 12.59,100.37 12.14,100.37 DT9.1 11.52,100.36 9.93,100.36 8.63,99.07 8.28,99.07 8.14,98.92 8.14,98.93 JUSBC1.A10
TBTA_RX2P: length 15.9
  BOTTOM w0.094: UT9.40 18.57,96.96 18.48,96.87 18.35,96.87 18.1,97.11 18.1,97.27 v4(17.54,97.82) 15.57,99.79 15.57,100.98 14.72,101.83 13.75,101.83 12.5,100.58 12.14,100.58 DT10.1 11.51,100.58 9.84,100.58 8.54,99.28 8.28,99.28 8.14,99.42 JUSBC1.A11
TBTA_SBU1: length 25
  TOP w0.094: v1(12.52,99.18) 12.86,99.18 13.03,99.01 13.03,97.65 12.76,97.38 11.74,97.38 11.69,97.43 11.69,97.71 DT8.1 11.32,97.85 v1(11.24,97.93) ; v1(19.78,88.13) 19.97,87.94 19.97,87.72 20.2,87.5 20.94,87.5 21.95,86.48 21.95,83.23 21.64,82.91 21.64,81.32 v4(22.99,79.96) 23.93,79.03 26.39,79.03 RT108.2
  BOTTOM w0.094: v1(11.24,97.93) 10.92,97.93 10.57,97.58 9.02,97.58 8.93,97.67 8.93,97.94 8.83,98.04 8.64,98.04 8.55,97.94 8.55,97.67 8.46,97.58 8.23,97.58 8.16,97.66 8.16,97.86 8.09,97.92 7.63,97.92 7.62,97.93 JUSBC1.A8 ; RT132.2 19.97,88.84 20.05,88.76 20.05,88.41 v1(19.78,88.13)
TBTA_SBU1_R: length 3.4
  TOP w0.076: 28.93,78.92 29.09,78.92 29.53,79.36 29.94,79.36 30.01,79.28 30.39,79.28 UT5.K8
  TOP w0.094: 28.93,78.92 27.87,78.92 RT108.1
TBTA_SBU2: length 19.8
  TOP w0.094: v1(13.24,99.38) 13.24,97.56 12.84,97.16 12,97.16 DT15.1 11.43,97.03 v1(11.32,96.93) ; v1(20.36,88.13) 20.19,87.95 20.19,87.81 20.29,87.71 21.02,87.71 22.17,86.57 v4(22.17,85.24) 22.17,83.14 21.85,82.82 21.85,81.41 24.02,79.24 26.39,79.24 RT109.2
  BOTTOM w0.094: v1(6.68,95.95) 6.46,96.18 JUSBC1.B8 ; RT133.2 20.27,88.59 20.27,88.23 v1(20.36,88.13)
TBTA_SBU2_R: length 2.9
  TOP w0.076: UT5.L8 29.44,79.54 29.04,79.14
  TOP w0.094: 29.04,79.14 28.08,79.14 RT109.1
TBTA_TOP_N: length 4.2
  TOP w0.094: UT5.L6 28.25,80.54 28.09,80.69 28.09,81 v1(28.29,81.19)
  BOTTOM w0.094: RT121.1 13.55,97.72 13.84,97.43 14.15,97.43 14.51,97.79 v1(14.51,97.8)
TBTA_TOP_N_R: length 5.8
  BOTTOM w0.094: RT121.2 12.64,97.68 12.52,97.56 12.11,97.56 DT12.1 11.49,97.52 10.91,97.52 10.73,97.34 8.02,97.34 7.93,97.43 JUSBC1.A7
TBTA_TOP_P: length 4.7
  TOP w0.076: UT5.K6 30.39,80.29 29.97,80.29
  TOP w0.094: v1(27.71,81.2) 27.88,81.03 27.88,80.6 28.16,80.32 29.93,80.32 29.97,80.29
  BOTTOM w0.094: RT120.1 13.8,97.22 v1(14.51,97.22)
TBTA_TOP_P_R: length 5.8
  BOTTOM w0.094: RT120.2 12.64,97.28 12.57,97.35 12.18,97.35 DT11.1 11.59,97.3 11,97.3 10.82,97.12 8.03,97.12 7.84,96.93 JUSBC1.A6
TBTA_TX1N: length 6.2
  BOTTOM w0.094: CT96.1 13.51,94.72 v4(14.61,94.72) 15.5,94.72 15.75,94.47 18.48,94.47 18.57,94.56 UT9.34
TBTA_TX1N_C: length 5.8
  BOTTOM w0.094: JUSBC1.A3 8.14,95.43 8.28,95.28 8.97,95.28 9.53,94.73 11.55,94.73 DT6.1 12.17,94.73 12.36,94.73 CT96.2
TBTA_TX1P: length 6.2
  BOTTOM w0.094: UT9.33 18.57,94.16 18.48,94.25 v4(17.09,94.25) 15.66,94.25 15.41,94.5 13.49,94.5 CT95.1
TBTA_TX1P_C: length 5.8
  BOTTOM w0.094: JUSBC1.A2 8.14,94.93 8.14,94.92 8.28,95.07 8.89,95.07 9.44,94.51 11.55,94.51 DT5.1 12.17,94.51 12.36,94.51 CT95.2
TBTA_TX2N: length 9.4
  TOP w0.094: v1(13.99,100.17) 13.82,100.34 13.53,100.34 CT98.1
  BOTTOM w0.094: UT9.36 18.57,95.36 18.48,95.45 17.45,95.45 16.35,96.54 16.35,97.52 v4(15.5,98.38) 14.52,99.35 14.52,100.26 14.41,100.37 14.19,100.37 v1(13.99,100.17)
TBTA_TX2N_C: length 7.8
  TOP w0.094: v1(6.73,98.94) 6.87,99.08 7.48,99.08 v4(8.31,99.91) 8.77,100.37 11.51,100.37 DT18.1 12.16,100.39 12.28,100.39 CT98.2
  BOTTOM w0.094: JUSBC1.B3 6.22,98.67 6.5,98.96 6.72,98.96 v1(6.73,98.94)
TBTA_TX2P: length 9.4
  TOP w0.094: CT97.1 13.51,100.56 13.79,100.56 v1(13.99,100.76)
  BOTTOM w0.094: UT9.37 18.57,95.76 18.48,95.67 17.53,95.67 16.57,96.63 16.57,97.6 15.83,98.35 15.83,98.35 15.47,98.71 15.46,98.71 14.74,99.44 14.74,100.34 14.5,100.58 14.16,100.58 v1(13.99,100.76)
TBTA_TX2P_C: length 7.8
  TOP w0.094: v1(6.71,99.53) 6.95,99.29 7.39,99.29 7.98,99.88 7.98,99.89 8.34,100.25 8.34,100.25 8.68,100.58 11.51,100.58 DT17.1 12.12,100.6 12.4,100.6 CT97.2
  BOTTOM w0.094: JUSBC1.B2 6.35,99.18 v1(6.71,99.53)
TDI_XDP: length 14.7
  TOP w0.102: JXDP1.56 v1(61.95,31.8) ; UC8.5 52.71,33.77 v2(52.71,34.94) RC229.1 52.8,35.82 53.21,35.41 v1(53.21,35.27)
  BOTTOM w0.102: v1(61.95,31.8) 58.48,35.27 v1(53.21,35.27)
TDO_XDP: length 20.8
  TOP w0.102: CC306.1 54.74,34.69 54.22,34.17 UC8.2 ; CC306.1 55.49,35.82 58.9,32.4 62.36,32.4 62.95,31.81 JXDP1.52 ; CC306.1 55.2,36.28 55.2,37.6 54.05,38.75 v2(54.05,39.31) v1(54.05,39.82)
  BOTTOM w0.102: RC230.1 104.39,79.91 104.27,79.79 104.27,78.44 v1(104.56,78.15)
THERMATRIP1#: length 5.8
  TOP w0.102: RE301.1 293.45,83.66 293.45,83.85 293.86,84.26 294.23,84.26 v2(294.23,84.25) 294.93,83.56 294.93,82.7 295.92,81.7 295.92,81.16 UE1.B12
THERMATRIP2#: length 5.3
  TOP w0.102: v1(301.52,73.13) 301.52,73.17 UE1.H3 ; RE69.2 285.32,73.86 285.37,73.81 CE36.1 285.17,72.92 QE4.1 283.67,72.92 v1(283.26,72.51) v2(283.26,71.17)
TOUCH_SCREEN_DET#: length 10.2
  BOTTOM w0.076: 136.03,47.02 136.03,47.18 135.83,47.38 135.34,47.38 135.17,47.55 135.17,48.06 134.81,48.41 UC1.AY5
  BOTTOM w0.102: v1(99.4,89.44) 99.32,89.36 RV8.1 99.49,88.79 99.95,89.26 99.95,89.64 100.71,90.4 100.71,90.93 100.85,91.08 100.85,92.09 JEDP1.32 ; v1(138.44,46) 137.91,46.54 136.41,46.54 136.03,46.92 136.03,47.02
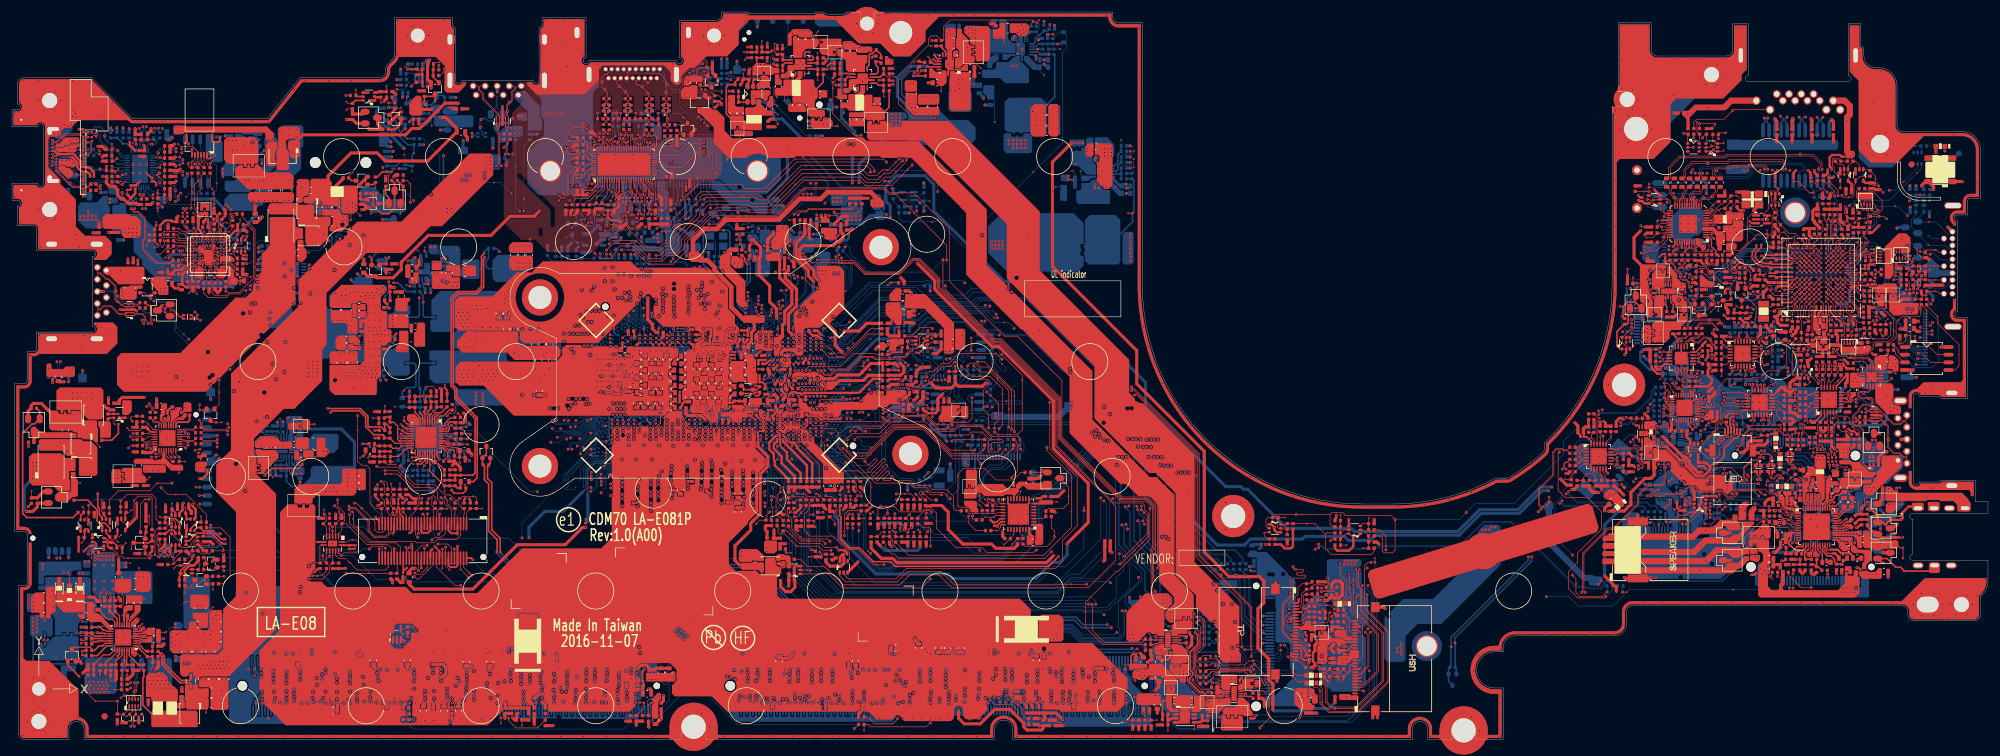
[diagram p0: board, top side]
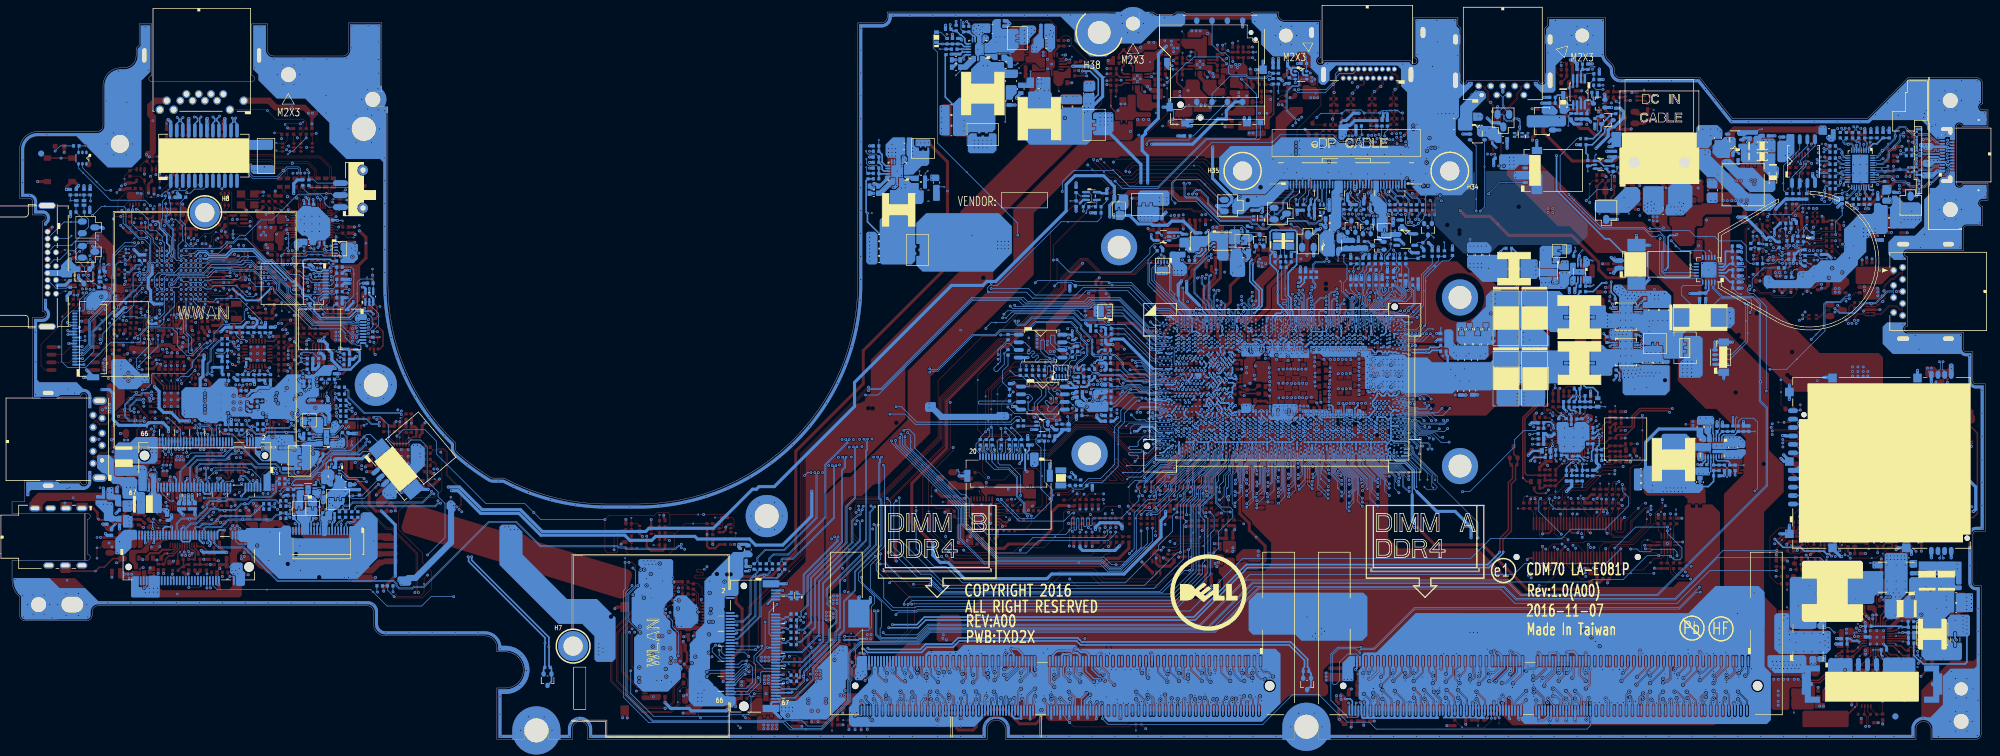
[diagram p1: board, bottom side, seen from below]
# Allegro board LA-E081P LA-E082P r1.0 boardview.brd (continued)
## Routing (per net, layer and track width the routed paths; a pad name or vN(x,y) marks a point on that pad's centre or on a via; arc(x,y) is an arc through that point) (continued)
TOUCH_SCREEN_PD#: length 20.2
  BOTTOM w0.102: UC1.A7 133.94,70.43 135.97,72.46 136.37,72.46 v2(138.37,74.46) 139.45,75.54 139.45,79.65 RC272.1 138.31,81.55 v1(138.31,81.81) ; v1(115.94,88.26) 115.94,89.61 115.3,90.24 114.91,90.24 114.3,90.85 JEDP1.5
TOUCHPAD_INTR#: length 18.4
  TOP w0.102: v1(140.04,43.49) 140.19,43.49 RC414.1 ; v1(211.71,19.53) 211.71,19.7 212.66,20.65 JKBTP1.5 ; v1(297.12,60.66) 296.17,60.66 296.11,60.6 v3(295.74,60.6) 295.55,60.79 295.55,64.07 295.85,64.38 297.34,64.38 297.51,64.54 RE318.2
  BOTTOM w0.102: UC1.BA5 134.87,47.66 134.63,47.42 134.63,46.92 134.81,46.74 135.28,46.74 135.45,46.56 135.67,46.56 136.17,46.06 137.55,46.06 138.33,45.28 138.49,45.28 140.04,43.73 v1(140.04,43.49)
TP_LAN_JTAG_TCK: length 4.7
  TOP w0.102: v3(271.66,81.6) 272.24,81.6 273.13,82.49 RL2.1 273.78,82.57 274.44,83.23 274.44,83.36 274.9,83.82 UL1.35
TP_LAN_JTAG_TDI: length 1.4
  TOP w0.102: T88.1 274.5,84.63 274.89,85.02
  TOP w0.112: 274.89,85.02 UL1.32
TP_LAN_JTAG_TDO: length 1.7
  TOP w0.102: UL1.34 274.77,84.22 273.99,83.44 T89.1
TP_LAN_JTAG_TMS: length 4.5
  TOP w0.102: RL1.1 272.4,83.36 v2(271.34,83.36)
  TOP w0.112: UL1.33 274.9,84.62 274.37,84.09 RL1.1
TPM_GPIO4: length 1.6
  TOP w0.102: T283.1 167.44,40.96 166.82,40.34 UZ12.13
TPM_LPM#: length 12.1
  TOP w0.102: UZ12.3 171.26,36.67 RZ363.2 RZ111.1 172.1,38.4 174.58,38.4 175.39,39.21 v2(175.39,40.38) 175.39,41.95 QZ9.1
TPM_PIRQ#: length 3.8
  TOP w0.102: v1(162.12,39.9) 162.68,39.9 RZ69.2 163.39,39.18 163.39,38.88 163.6,38.67 UZ12.18
  BOTTOM w0.102: UC1.AP8 132.98,52.12 v1(132.52,51.66)
TPM_TYPE: length 14.6
  TOP w0.102: v1(140.38,40.49) 140.09,40.19 RC349.1
  BOTTOM w0.076: 135.34,45.95 134.8,45.95 134.02,46.74 133.51,46.74 133.3,46.95 133.3,47.77 133.7,48.17 UC1.AY7
  BOTTOM w0.102: 135.34,45.95 135.44,45.95 136,45.39 137.31,45.39 139.94,42.77 140.84,42.77 141.33,42.27 v2(141.33,41.88) 140.85,41.39 140.85,40.96 v1(140.38,40.49)
TRST#_XDP: length 12.2
  TOP w0.102: JXDP1.54 62.45,28.6 61.99,28.13 57.28,28.13 v2(56.03,29.39) 55.4,30.02 54.3,30.02 53.72,30.6 UC8.12
TUSB546A_SBU1_R: length 2.4
  BOTTOM w0.094: UT9.27 20.21,91.25 20.31,91.15 20.31,90.81 20.07,90.56 20.07,90.06 19.77,89.76 RT132.1
TUSB546A_SBU2_R: length 2.2
  BOTTOM w0.094: RT133.1 20.28,89.99 20.28,90.48 20.53,90.72 20.53,91.17 20.61,91.25 UT9.26
TYPEC_ID: length 6.8
  TOP w0.102: RE343.2 CE62.1 298.9,67.71 298.84,67.77 298.84,70.4 v2(298.73,70.5) 298.73,71.32 299.19,71.77 299.19,72.35 UE1.F2
UART_MISO: length 4.7
  TOP w0.076: UT5.F2 32.89,82.79 32.89,83.15 32.85,83.19 32.85,84.08 v1(32.96,84.19)
  BOTTOM w0.102: v2(33.09,86.82) 33,86.73 33,86.02 RT82.1 32.69,85.72 RT83.2 32.69,84.45 v1(32.96,84.19)
UART_MOSI: length 4.5
  TOP w0.076: UT5.E2 33.4,82.79 33.4,83.56 v1(33.41,83.57)
  BOTTOM w0.102: RT83.1 34.3,84.85 v2(34.61,84.54) ; RT83.1 33.61,85.72 RT81.1 ; RT83.1 33.61,83.77 v1(33.41,83.57)
UG1_ISL88738: length 0.7
  BOTTOM w0.127: v1(19.12,20.66) v2(18.37,20.66)
  vias: v1(11.12,27.58) v1(11.75,27.58) v1(19.12,20.02)
UG2_ISL88738: length 0.6
  BOTTOM w0.127: v1(22.17,17.1) v2(22.17,17.66)
  vias: v1(21.53,17.1) v1(28.71,12.65) v1(29.3,12.64)
UIM_CLK: length 18.5
  BOTTOM w0.102: JSIM1.3 128.82,107.19 125.89,110.13 123.19,110.13 122.84,109.78 119.79,109.78 119.47,110.1 119.03,110.1 CZ38.1 118.85,109.59 v1(119.33,109.59) ; JNGFF2.24 294.55,50.35 294.69,50.48 294.69,51.56 295.34,52.22 296.76,52.22 v1(296.91,52.36)
UIM_DATA: length 24.3
  BOTTOM w0.102: CZ39.1 118.85,110.79 v1(119.33,110.79) ; CZ39.1 RZ335.2 ; CZ39.1 118.98,110.33 119.56,110.33 119.89,110 122.74,110 123.09,110.36 125.71,110.36 126.05,110.7 126.05,111.91 125.96,111.99 125.96,113.33 126.65,114.01 127.44,114.01 128.82,115.4 JSIM1.7 ; v1(296.89,51.73) 296.64,51.99 295.43,51.99 294.91,51.47 294.91,50.48 295.05,50.35 JNGFF2.26
UIM_RESET: length 21.3
  TOP w0.102: v1(293.51,52.22) 292.37,52.22 v3(292.34,52.25)
  BOTTOM w0.102: JNGFF2.22 294.05,50.43 294.13,50.51 294.13,52.04 293.96,52.22 v1(293.51,52.22) ; JSIM1.2 131.94,100.22 CZ40.1 132.47,99.76 132.69,99.54 139.21,99.54 139.65,99.11 v1(139.65,98.83)
UPD1_ALERT#: length 32.3
  TOP w0.102: RT60.1 v1(38.92,79.01) ; RE91.1 301.55,86.94 v1(301.55,86.39) ; UE1.F10 v1(299.16,79.53)
  BOTTOM w0.102: v1(301.55,86.39) 300.88,86.39 299.73,85.24 299.73,82.82 300.49,82.06 300.49,80.09 300.33,79.93 299.57,79.93 v1(299.16,79.53) ; v1(38.92,79.01) 39.5,79.01 40.14,79.65 40.14,81.98 40.95,82.8 44.62,82.8 45.33,83.51 v2(46.84,83.51) 48.57,83.51 49.56,84.5 53.98,84.5 54.35,84.87 56.1,84.87 v1(56.11,84.85)
UPD1_SMBCLK: length 4.1
  TOP w0.102: v1(288.57,74) 288.72,73.85 289.46,73.85 RE303.1 ; QT1.1 v1(36.81,81.05) ; UE1.C3 v1(296.74,73.11)
  BOTTOM w0.102: v1(36.81,81.05) 37.24,81.48 RT58.1
UPD1_SMBCLK_Q: length 12
  TOP w0.076: 35.97,81.29 34.89,81.29 UT5.B5
  TOP w0.102: RT375.2 v1(24.2,88.31) v2(24.2,87.78) ; QT1.6 37.39,82.3 v1(37.41,82.29) 36.97,82.29 35.97,81.29 ; RT92.1 v1(25.28,83.84)
  BOTTOM w0.102: v1(24.2,88.31) 24.2,87.03 25.28,85.95 v1(25.28,83.84) ; RT67.1 37.29,82.17 v1(37.41,82.29) 37.51,82.39 RT58.2
UPD1_SMBDAT: length 3.5
  TOP w0.102: QT1.4 38.99,83.25 v1(38.99,83.58) ; v1(295.96,73.93) UE1.B4 ; RE302.1 v1(289.06,74.36)
  BOTTOM w0.102: RT59.1 38.99,82.77 v1(38.99,83.58)
UPD1_SMBDAT_Q: length 8.4
  TOP w0.076: UT5.A5 36.06,81.04
  TOP w0.102: QT1.3 38.69,81.69 v1(38.71,81.71) 36.74,81.71 36.06,81.04 ; RT376.2 22.81,83.77 RT93.1 RT66.1 23.68,85.1 v1(23.94,85.36) v2(23.94,85.91)
  BOTTOM w0.102: RT59.2 39.14,81.71 v1(38.71,81.71)
UPD1_SMBUS_ALERT#: length 4.1
  TOP w0.076: 35.62,80.64 35.47,80.79 34.9,80.79 UT5.B6
  TOP w0.102: RT60.2 RT68.1 36.66,80.64 v2(36.38,80.64) 35.62,80.64
UPD2_ALERT#: length 19.9
  TOP w0.102: v1(299.16,74.73) UE1.F5 ; v1(287.54,73.93) v2(289.1,72.37) 289.57,71.9 289.57,70.05 289.36,69.84 RE92.1
  BOTTOM w0.102: v1(299.16,74.73) 298.77,75.12 296.32,75.12 296.02,74.82 295.07,74.82 294.54,75.35 290.83,75.35 288.99,73.51 287.96,73.51 v1(287.54,73.93)
UPD2_SMBCLK: length 2.2
  TOP w0.102: v1(315.13,80.33) 315.07,80.4 314.1,80.4 313.84,80.14 RPE12.3 ; v1(297.56,76.33) UE1.D7
UPD2_SMBDAT: length 1.8
  TOP w0.102: RPE12.4 314.34,80.05 314.46,80.17 314.72,80.17 315.07,79.82 v1(315.07,79.7) ; v1(298.36,76.33) UE1.E7
USB1_A_DE0: length 4.7
  TOP w0.102: RI53.1 302.13,62.18 302.13,61.02 RI54.1 v2(301.63,59.59) 301.63,59.51 301.38,59.26 UI5.16
USB1_A_DE1: length 5
  TOP w0.102: UI5.18 300.38,59.26 v2(300.02,59.62) 299.6,60.04 RI52.1 300.11,61.03 300.11,62.17 RI51.1
USB1_A_EQ0: length 4.8
  TOP w0.102: UI5.17 300.88,59.31 300.98,59.41 300.98,59.87 300.61,60.24 RI41.1 301.12,61.03 301.12,62.17 RI40.1
USB1_A_EQ1: length 6.1
  TOP w0.102: v2(303.6,63.01) 302.98,63.01 RI38.1 302.94,62.39 302.94,61.93 303.17,61.7 303.17,61.05 RI39.1 302.65,60.03 301.88,59.26 UI5.15
USB1_B_DE0: length 4.4
  TOP w0.102: UI5.3 301.38,52.93 RI57.1 301.6,52.2 301.6,50.93 RI58.1
USB1_B_DE1: length 8.2
  TOP w0.102: RI56.1 RI55.1 306.76,49.91 306.76,51.23 306.43,51.55 305.94,51.55 v2(305.66,51.84) 305.09,52.41 305.09,53.26 304.65,53.7 303.13,53.7 302.88,53.95 UI5.6
USB1_B_EQ0: length 4.6
  TOP w0.102: RI45.1 300.23,50.85 299.73,51.36 299.73,52.16 RI44.1 300.88,53.32 UI5.2
USB1_B_EQ1: length 4.3
  TOP w0.102: RI43.1 302.51,50.88 302.51,52.24 RI42.1 301.88,52.87 UI5.4
USB1_TEST: length 2.6
  TOP w0.102: UI5.14 302.38,58.82 v2(303.13,59.57) 303.66,60.1 RI34.2
USB2_ID: length 23.1
  TOP w0.102: RC337.1 v1(151.77,37.61)
  BOTTOM w0.102: v1(151.77,37.61) 152.07,37.61 153.42,36.26 160.83,36.26 v1(164.43,39.86) ; v1(39.54,74.69) 39.15,75.09 39.15,76.45 37.28,78.31 RT74.2 ; v1(135.99,56.06) 135.99,55.77 UC1.AG3
USB2_VBUSSENSE: length 1.7
  TOP w0.102: RC338.1 150.75,40.05 v1(150.07,40.73)
  BOTTOM w0.102: v1(135.12,55.94) 135.47,55.6 UC1.AG4
USB3_PD#: length 6.6
  TOP w0.102: UI5.5 302.38,53.95 303.24,53.09 RI81.2 303.24,51.62 303.7,51.16 v1(304.45,51.16) 304.73,51.16 305.21,50.68 RI37.2
  BOTTOM w0.102: v1(304.45,51.16) v2(304.45,52.08)
USB3_PRX_C_DTX_N6: length 2.8
  BOTTOM w0.094: CT112.2 21.85,99.51 21.85,99.41 21.77,99.33 21.42,99.33 21.14,99.05 21.14,98.34 21.01,98.21 UT9.4
USB3_PRX_C_DTX_P6: length 2.8
  BOTTOM w0.094: CT111.2 22.04,99.44 22.04,99.33 21.85,99.14 21.5,99.14 21.32,98.97 21.32,98.33 21.41,98.24 UT9.5
USB3_PRX_C_RD_DTX_N1: length 2.6
  TOP w0.094: CI42.2 298.21,55.06 298.38,55.06 298.58,55.27 298.58,55.7 298.68,55.8 298.97,55.8 299.11,55.66 UI5.23
USB3_PRX_C_RD_DTX_P1: length 2.6
  TOP w0.094: CI41.2 298.16,55.25 298.3,55.25 298.4,55.34 298.4,55.77 298.6,55.98 298.97,55.98 299.15,56.16 UI5.22
USB3_PRX_DTX_N1: length 1.7
  TOP w0.094: v1(296.02,54.84) 296.22,55.05 296.58,55.05 296.85,54.77 CI42.1
  BOTTOM w0.094: v1(132.56,65.34) 132.59,65.3 132.71,65.3 UC1.H8
USB3_PRX_DTX_N2: length 5.1
  TOP w0.094: v1(290.81,46.8) 290.77,46.77 290.64,46.77 290.53,46.88 290.53,46.97 290.4,47.09 290.4,47.21 290.55,47.36 291.66,47.36 292.04,46.98 v4(292.04,46.68) 292.04,46.32 291.97,46.25 291.78,46.25 291.73,46.2 LI16.4 291.56,45.43 RI28.1
  BOTTOM w0.076: UC1.J6 133.86,64.39 v1(133.47,64.78)
USB3_PRX_DTX_N3: length 11.1
  TOP w0.094: v1(21.58,69.6) 21.59,69.6 21.98,69.98 21.98,70.17 21.58,70.57 20.45,70.57 20.38,70.49 20.38,70.43 20.33,70.38 DI1.1 DI1.9 18.87,70.57 17.71,70.57 16.44,71.84 15.2,71.84 14.66,71.31 14.25,71.31 14.16,71.21 JUSB2.5
  BOTTOM w0.076: UC1.J10 131.82,64.39 v1(131.6,64.61)
USB3_PRX_DTX_N4: length 16.3
  TOP w0.094: v1(80.39,95.25) 80.71,95.57 80.71,100.5 80.53,100.68 80.53,101.72 80.53,101.72 80.41,101.84 DI6.1 DI6.9 80.41,103.41 80.57,103.57 80.57,103.85 78.05,106.37 78.05,107.24 77.46,107.83 77.46,108.43 77.36,108.52 JUSB3.5
  BOTTOM w0.076: v1(131.6,67.21) 131.83,66.99 UC1.E10
USB3_PRX_DTX_N6: length 1.7
  BOTTOM w0.076: UC1.G11 v1(130.67,65.89)
  BOTTOM w0.094: CT112.1 21.88,101.22 21.88,101.57 v1(21.7,101.75)
USB3_PRX_DTX_P1: length 1.6
  TOP w0.094: v1(296.02,55.43) 296.21,55.23 296.44,55.23 CI41.1
  BOTTOM w0.076: v1(132.55,65.99) 132.85,65.69 UC1.G8
USB3_PRX_DTX_P2: length 5.2
  TOP w0.094: v1(290.13,46.8) 290.21,46.88 290.21,47.29 290.47,47.55 291.73,47.55 292.23,47.05 292.23,46.96 292.24,46.95 292.24,46.38 292.23,46.37 LI16.1 292.4,45.43 RI27.1
  BOTTOM w0.076: v1(133.48,65.37) 133.81,65.04 UC1.H6
USB3_PRX_DTX_P3: length 11.2
  TOP w0.094: JUSB2.6 14.16,71.59 14.25,71.49 14.58,71.49 15.12,72.03 16.52,72.03 17.79,70.76 18.95,70.76 DI1.8 DI1.2 20.21,70.88 20.33,70.75 21.66,70.75 22.16,70.25 v1(22.16,69.6)
  BOTTOM w0.076: v1(131.6,65.36) 131.91,65.04 UC1.H10
USB3_PRX_DTX_P4: length 16.3
  TOP w0.094: v1(81.24,95.26) 80.9,95.61 80.9,100.57 80.71,100.76 80.71,101.64 80.91,101.84 DI6.2 DI6.8 80.91,103.42 80.75,103.58 80.75,103.93 78.24,106.45 78.24,107.32 77.64,107.91 77.64,108.43 77.74,108.52 JUSB3.6
  BOTTOM w0.076: v1(131.6,66.58) 131.84,66.34 UC1.F10
USB3_PRX_DTX_P6: length 1.7
  BOTTOM w0.076: v1(130.72,66.62) 130.72,66.62 130.72,66.62 130.74,66.55 UC1.F11
  BOTTOM w0.094: CT111.1 22.07,101.22 22.07,101.53 v1(22.28,101.75)
USB3_PRX_L_DTX_N2: length 5.6
  TOP w0.094: v1(293.41,43.4) 293.61,43.6 293.61,43.73 293.51,43.83 293.12,43.83 292.54,43.25 292.12,43.25 291.88,43.49 291.88,43.74 291.73,43.89 LI16.3 291.56,44.52 RI28.2
  BOTTOM w0.094: JNGFF2.21 293.8,42.45 293.97,42.62 293.97,42.73 293.64,43.05 293.64,43.16 v1(293.41,43.4)
USB3_PRX_L_DTX_P2: length 5.6
  TOP w0.094: RI27.2 292.4,44.52 LI16.2 292.23,43.87 292.07,43.71 292.07,43.56 292.19,43.44 292.46,43.44 293.04,44.01 293.59,44.01 293.79,43.81 293.79,43.6 v1(293.99,43.4)
  BOTTOM w0.094: v1(293.99,43.4) 293.83,43.24 293.83,43.13 294.15,42.81 294.15,42.59 294.3,42.44 JNGFF2.23
USB3_PRX_RD_DTX_N1: length 16
  TOP w0.094: v1(306.19,55.93) 305.9,56.22 305.65,56.22 305.45,56.03 305.45,56.03 305.44,56.02 304.8,56.02 304.79,56.03 304.66,56.03 304.6,55.97 304.38,55.97 304.06,55.66 UI5.8 ; v1(307.77,54.92) 308.05,54.64 308.29,54.64 308.52,54.87 DI4.1 DI4.9 309.74,54.87 309.9,54.71 310.16,54.71 312.43,52.45 313.47,52.45 313.96,52.94 314.33,52.94 314.6,53.22 JUSB1.5
  BOTTOM w0.094: v1(306.19,55.93) 306.59,56.33 307.32,56.33 308.43,55.21 308.43,54.8 308.26,54.63 308.06,54.63 v1(307.77,54.92)
USB3_PRX_RD_DTX_P1: length 16
  TOP w0.094: JUSB1.6 314.6,52.49 314.34,52.76 314.04,52.76 313.54,52.26 312.35,52.26 310.09,54.52 309.89,54.52 309.73,54.37 DI4.8 DI4.2 308.49,54.37 308.4,54.46 307.89,54.46 v1(307.77,54.34) ; v1(306.19,56.51) 306.09,56.41 305.57,56.41 305.38,56.22 v4(305.12,56.22) 304.59,56.22 304.53,56.16 UI5.9
  BOTTOM w0.094: v1(307.77,54.34) 307.87,54.44 308.34,54.44 308.62,54.72 308.62,55.29 307.39,56.51 v1(306.19,56.51)
USB3_PTX_C_DRX_N1: length 12.9
  TOP w0.094: JUSB1.8 314.6,47.04 314.51,46.94 314.11,46.94 313.36,47.69 312.43,47.69 311.54,48.59 v4(311.54,49.76) 311.54,52.05 311.28,52.3 311.28,52.35 310.87,52.76 310.82,52.76 310.38,53.2 310.21,53.2 310.05,53.37 DI4.7 DI4.4 308.46,53.37 308.3,53.21 307.77,53.21 307.68,53.3 CI13.1
USB3_PTX_C_DRX_N2: length 1.8
  TOP w0.094: RI30.1 294.73,47.4 LI17.4 294.9,47.82 295.06,47.98 295.06,48.55 CI29.1
USB3_PTX_C_DRX_N3: length 11.6
  TOP w0.094: CI5.1 20.86,72 20.07,72 DI1.4 DI1.7 18.58,71.88 18.42,72.03 18.15,72.03 v4(17.46,72.73) 17.08,73.11 17.08,74.15 17.05,74.19 17.05,74.77 17.08,74.8 17.08,75.26 15.93,76.41 15.56,76.41 14.66,77.31 14.25,77.31 14.16,77.21 JUSB2.8
USB3_PTX_C_DRX_N4: length 9.7
  TOP w0.094: JUSB3.8 83.25,108.52 83.47,108.3 83.47,108.12 82.88,107.53 82.88,106.14 v4(82.55,105.81) 82.07,105.33 82.07,104.62 82.04,104.58 82.04,104 82.07,103.97 82.07,103.6 81.91,103.44 DI6.7 DI6.4 81.91,101.87 82.08,101.7 82.08,100.97 CI27.1
USB3_PTX_C_DRX_N6: length 3.6
  BOTTOM w0.094: CT114.2 23.89,99.5 23.89,99.17 23.75,99.03 23.52,99.03 23.51,99.03 22.88,99.03 22.87,99.03 22.63,99.03 22.32,98.72 22.32,98.37 22.21,98.26 UT9.7
USB3_PTX_C_DRX_P1: length 12.9
  TOP w0.094: CI16.1 307.68,52.92 307.78,53.02 308.3,53.02 308.46,52.87 DI4.5 DI4.6 310.05,52.87 310.2,53.02 310.3,53.02 v4(310.92,52.4) 311.35,51.97 311.35,50.09 311.32,50.06 311.32,49.47 311.35,49.44 311.35,48.51 312.36,47.5 313.29,47.5 314.03,46.76 314.51,46.76 314.6,46.66 JUSB1.9
USB3_PTX_C_DRX_P2: length 1.8
  TOP w0.094: CI30.1 295.25,48.55 295.25,47.98 295.4,47.82 LI17.1 295.57,47.4 RI29.1
USB3_PTX_C_DRX_P3: length 11.7
  TOP w0.094: JUSB2.9 14.16,77.59 14.25,77.49 14.74,77.49 15.63,76.6 16.01,76.6 17.26,75.34 v4(17.26,74.48) 17.26,73.18 17.36,73.09 17.37,73.09 17.82,72.64 17.82,72.63 18.23,72.22 18.42,72.22 18.58,72.38 DI1.6 DI1.5 20.14,72.18 20.86,72.18 CI4.1
USB3_PTX_C_DRX_P4: length 9.6
  TOP w0.094: JUSB3.9 83.87,108.52 83.65,108.3 83.65,108.04 83.06,107.45 83.06,106.06 82.91,105.91 82.91,105.86 82.5,105.45 82.45,105.45 82.25,105.25 v4(82.25,104.29) 82.25,103.6 82.41,103.44 DI6.6 DI6.5 82.41,101.85 82.27,101.71 82.27,100.97 CI28.1
USB3_PTX_C_DRX_P6: length 3.6
  BOTTOM w0.094: CT113.2 24.08,99.45 24.08,99.1 23.82,98.84 v4(23.2,98.84) 22.71,98.84 22.51,98.64 22.51,98.38 22.61,98.27 UT9.8
USB3_PTX_C_RD_DRX_N1: length 2.1
  TOP w0.094: CI40.1 298.14,57.03 298.14,57.03 298.2,57.08 298.63,57.08 298.85,57.31 299.07,57.31 299.22,57.16 UI5.20
USB3_PTX_C_RD_DRX_P1: length 2.1
  TOP w0.094: UI5.19 299.22,57.66 299.07,57.5 298.78,57.5 298.55,57.27 298.17,57.27 CI39.1
USB3_PTX_DRX_N1: length 5
  TOP w0.094: v1(296.01,56.87) 296.2,57.07 296.45,57.07 CI40.2
  BOTTOM w0.076: UC1.C13 130.54,68.21 130.6,68.21 130.71,68.32 130.71,68.45 130.65,68.51 130.65,68.55 130.47,68.73 130.43,68.73 130.41,68.75 130.22,68.75 130.11,68.85 130.07,68.98 130.07,69.15 130.13,69.34 130.13,69.49 130.07,69.61 130.07,70.24 130.41,70.58 130.63,70.58 130.75,70.46 130.75,70.35 v1(130.69,70.29)
USB3_PTX_DRX_N2: length 14.7
  TOP w0.094: v1(286.51,48.08) 286.51,48.22 287.39,49.1 287.39,49.78 287.56,49.95 287.56,50.49 288.51,51.43 v4(290.9,51.43) 293.21,51.43 294.15,50.49 294.9,50.49 295.07,50.33 295.07,50.18 CI29.2
  BOTTOM w0.076: UC1.B13 130.34,69.21 130.41,69.29 130.84,69.29 131.19,69.63 131.19,69.87 131.48,70.16 131.48,70.68 131.56,70.76 131.66,70.76 v1(131.88,70.55)
USB3_PTX_DRX_N3: length 12.7
  TOP w0.094: v1(22.59,69.08) 22.6,69.08 22.93,69.41 22.93,71.78 22.63,72.09 22.42,72.09 22.13,71.79 CI5.2
  BOTTOM w0.076: UC1.B15 128.68,69.68 128.68,70.85 129.28,71.45 129.28,72.51 130.03,73.26 130.03,73.73 130.02,73.74 130.02,73.76
  BOTTOM w0.094: v1(130.44,76.91) 130.44,75.77 130.02,75.35 130.02,73.76
USB3_PTX_DRX_N4: length 18
  TOP w0.094: CI27.2 82.08,99.22 82.08,97.91 81.99,97.82 81.99,97.28 v1(81.88,97.17)
  BOTTOM w0.076: 131.32,73.6 131.31,73.59 131.3,73.59 129.94,72.23 129.94,71.34 129.43,70.83 129.43,69.61 129.36,69.41 129.36,69.34 129.42,69.18 129.42,68.97 129.34,68.69 129.31,68.66 129.31,68.37 129.29,68.31 129.29,68.26 129.19,68.16 129.03,68.16 128.95,68.24 128.95,68.38 UC1.C15
  BOTTOM w0.094: v1(128.95,80.56) 129.11,80.39 129.43,80.39 131.83,77.99 131.83,74.11 131.32,73.6
USB3_PTX_DRX_N6: length 10.5
  BOTTOM w0.076: 129.16,73.72 129.16,73.7 129.17,73.69 129.17,73.22 128.81,72.86 128.81,71.57 128.34,71.1 128.34,69.41 128.13,69.01 128.13,68.64 UC1.D16
  BOTTOM w0.094: CT114.1 23.91,101.21 23.91,101.31 v1(23.71,101.5) ; v1(129.02,77.09) 129.24,76.88 129.24,75.98 129.16,75.9 129.16,73.72
USB3_PTX_DRX_P1: length 5
  TOP w0.094: v1(296.01,57.45) 296.21,57.25 296.43,57.25 CI39.2
  BOTTOM w0.076: UC1.D13 130.12,68.09 130.04,68.36 130.04,68.47 129.9,68.95 129.9,69.2 129.94,69.29 129.94,69.48 129.9,69.58 129.9,70.3 130.35,70.75 130.9,70.75 v1(130.95,70.79)
USB3_PTX_DRX_P2: length 14.8
  TOP w0.094: v1(286.48,48.76) 286.79,48.76 287.2,49.18 287.2,49.85 287.38,50.03 287.38,50.56 288.43,51.61 290.57,51.61 290.58,51.62 291.22,51.62 291.22,51.61 293.29,51.61 294.23,50.68 294.98,50.68 295.25,50.4 295.25,50.16 CI30.2
  BOTTOM w0.076: v1(131.85,71.13) 131.65,70.93 131.49,70.93 131.32,70.75 131.32,70.23 131.03,69.94 131.03,69.7 130.78,69.45 130.44,69.45 130.34,69.56 UC1.A13
USB3_PTX_DRX_P3: length 12.7
  TOP w0.094: CI4.2 22.39,72.27 22.7,72.27 23.12,71.86 23.12,69.14 v1(23.17,69.08)
  BOTTOM w0.076: UC1.A15 129.02,69.71 129.1,69.79 129.1,69.99 129.03,70.06 128.9,70.06 128.84,70.12 128.84,70.78 129.44,71.39 129.44,72.44 130.19,73.19 130.19,73.73 130.2,73.74 130.2,73.76
  BOTTOM w0.094: v1(131.23,76.62) 131.04,76.81 130.91,76.81 130.62,76.53 130.62,75.7 130.2,75.28 130.2,73.76
USB3_PTX_DRX_P4: length 18.1
  TOP w0.094: CI28.2 82.27,99.22 82.27,97.83 82.18,97.74 82.18,97.46 v1(82.47,97.17)
  BOTTOM w0.076: UC1.D15 128.69,68.28 128.69,68.45 128.75,68.62 128.86,68.73 129,68.73 129.16,68.8 129.22,68.86 129.26,69 129.26,69.15 129.19,69.31 129.19,69.44 129.26,69.64 129.26,70.9 129.77,71.41 129.77,72.3 131.18,73.7 131.18,73.72 131.19,73.73
  BOTTOM w0.094: v1(128.95,79.97) 129.19,80.21 129.36,80.21 131.65,77.92 131.65,74.19 131.19,73.73
USB3_PTX_DRX_P6: length 10.5
  BOTTOM w0.076: UC1.C16 128.61,68.74 128.72,68.85 128.72,69.01 128.64,69.09 128.48,69.09 128.45,69.12 128.45,69.26 128.5,69.37 128.5,71.03 128.98,71.51 128.98,72.79 129.34,73.15 129.34,73.69 129.35,73.7 129.35,73.72
  BOTTOM w0.094: v1(24.29,101.5) 24.09,101.3 24.09,101.23 CT113.1 ; 129.35,73.72 129.35,75.83 129.42,75.9 129.42,77.04 129.54,77.16 v1(129.77,77.16)
USB3_PTX_L_DRX_N2: length 5.6
  TOP w0.094: v1(295.53,45.07) 295.73,45.27 295.73,45.4 295.64,45.5 295.29,45.5 295.06,45.72 295.06,45.93 294.9,46.09 LI17.3 294.74,46.49 RI30.2
  BOTTOM w0.094: JNGFF2.27 295.3,42.57 295.45,42.72 295.45,42.97 295.76,43.28 295.76,44.84 v1(295.53,45.07)
USB3_PTX_L_DRX_P2: length 5.6
  TOP w0.094: RI29.2 295.57,46.49 LI17.2 295.4,46.09 295.25,45.93 295.25,45.8 295.36,45.68 295.71,45.68 295.91,45.48 295.91,45.27 v1(296.11,45.07)
  BOTTOM w0.094: JNGFF2.29 295.8,42.58 295.64,42.74 295.64,42.89 295.94,43.2 295.94,44.9 v1(296.11,45.07)
USB3_PTX_RD_DRX_N1: length 13.2
  TOP w0.094: v1(304.87,57.13) 304.87,57.14 304.63,57.38 304.28,57.38 304.06,57.16 UI5.11 ; v1(306.09,53.4) 306.35,53.13 306.67,53.13 306.76,53.23 CI13.2
  BOTTOM w0.094: v1(306.09,53.4) 306.44,53.04 v4(307.57,53.04) 308.54,53.04 309.19,53.69 309.19,54.43 309.18,54.44 309.18,55.02 309.19,55.03 309.19,55.57 307.63,57.13 306.64,57.13 306.38,57.39 305.13,57.39 v1(304.87,57.13)
USB3_PTX_RD_DRX_P1: length 13.2
  TOP w0.094: v1(306.09,52.81) 306.22,52.95 306.5,52.95 306.76,52.68 CI16.2 ; UI5.12 304.12,57.66 304.21,57.57 304.72,57.57 v1(304.87,57.71)
  BOTTOM w0.094: v1(304.87,57.71) 305,57.57 306.46,57.57 306.72,57.31 307.71,57.31 309.38,55.64 v4(309.38,54.73) 309.38,53.61 308.62,52.85 307.87,52.85 307.86,52.85 307.28,52.85 307.28,52.85 306.12,52.85 v1(306.09,52.81)
USB20_N1: length 8.8
  TOP w0.094: v1(303.08,64.8) 302.86,64.58 302.86,64.48 303.48,63.85 304.46,63.85 304.87,63.45 v4(305.27,63.45) 305.89,63.45 305.95,63.39 308.28,63.39 308.34,63.33 308.35,63.33 308.83,62.85 308.83,62.32 308.99,62.15 UI3.2
  BOTTOM w0.076: UC1.AB9 132.78,58.31 133.02,58.08 v1(133.09,58.08)
USB20_N1_R: length 4.1
  TOP w0.094: v1(308.83,49.73) 308.83,49.41 DI5.2 308.72,48.74 309.04,48.42 309.04,48.1 308.65,47.71 308.65,47.34 308.44,47.13 LI7.2
USB20_N2: length 1.9
  TOP w0.094: LI3.4 29.9,70.29 30.58,70.29 30.76,70.48 v1(30.76,70.5)
  BOTTOM w0.076: v1(134.99,56.99) 134.87,56.99 134.74,57.12 UC1.AD6
USB20_N2_R: length 17
  TOP w0.094: LI3.3 28.25,70.25 27.95,70.25 26.85,71.36 26.33,71.36 26.22,71.47 DI2.3 25.54,71.56 v1(25.41,71.56)
  BOTTOM w0.094: v1(25.41,71.56) 25.21,71.36 25.03,71.36 24.61,70.93 22.18,70.93 20.58,72.54 19.71,72.54 19.7,72.54 19.07,72.54 19.06,72.54 18.67,72.54 v4(17.56,73.65) 16.72,74.49 15.75,74.49 15.66,74.59 JUSB2.2
USB20_N3: length 5.3
  BOTTOM w0.076: UC1.AH3 135.84,54.93 136.28,54.72 136.29,54.72 136.4,54.66 136.57,54.66 136.73,54.72 136.88,54.72 136.91,54.71 136.91,54.71 137.09,54.66 137.21,54.66 137.33,54.7 137.65,54.7 137.83,54.88 138.99,54.88 139.22,54.64 139.22,54.47 v1(139.43,54.26)
  BOTTOM w0.094: LI4.4 77.15,100.69 76.95,100.49 76.56,100.49 v1(76.37,100.68)
USB20_N3_R: length 12
  BOTTOM w0.094: LI4.3 78.52,100.69 78.31,100.49 78.17,100.49 78.07,100.59 78.07,101.04 77.78,101.34 v4(77.78,101.69) 77.78,102.6 77.8,102.62 77.81,102.62 78.22,103.03 78.57,103.03 79.02,102.58 79.91,102.58 80.4,103.07 80.4,103.63 80.57,103.8 DI3.3 81.42,103.99 80.52,104.89 80.52,105.2 80.64,105.32 80.64,106.72 80.95,107.02 JUSB3.2
USB20_N4: length 7.3
  TOP w0.094: RI48.1 289.53,45.43 LI8.4 289.7,45.86 289.88,46.04 289.88,46.13 289.74,46.27 288.76,46.27 287.62,45.12 287.62,43.58 287.76,43.44 288.32,43.44 288.44,43.56 288.44,43.73 288.24,43.94 v1(288.13,43.94)
  BOTTOM w0.076: v1(133.09,57.01) 132.94,57.23 UC1.AD9
USB20_N4_L: length 5.5
  TOP w0.094: v1(289.73,43.13) 289.73,43.27 289.8,43.34 289.94,43.34 290.01,43.41 290.01,43.78 289.91,43.89 289.76,43.89 289.7,43.95 LI8.3 289.53,44.52 RI48.2
  BOTTOM w0.094: JNGFF2.9 288.8,42.52 288.73,42.59 288.65,42.59 288.59,42.65 288.59,42.79 289.5,43.7 289.94,43.7 290.03,43.61 290.03,43.44 289.94,43.34 289.82,43.34 289.73,43.25 v1(289.73,43.13)
USB20_N5: length 32.6
  BOTTOM w0.094: v1(139.3,53.26) 139.09,53.46 139.09,53.51 139.09,53.66 138.88,53.87 138.54,53.87 138.51,53.89 137.95,53.89 137.88,53.97 137.46,53.97 137.29,54.14 137.29,54.22 137.34,54.27 UC1.AJ1 ; v1(132.53,92.37) 132.63,92.47 132.9,92.47 133.11,92.27 133.11,92.2 133.3,92.01 133.3,90.34 133.06,90.1 131.36,90.1 127.41,86.15 122.58,86.15 122.17,85.74 121.39,85.74 120.56,84.91 119.72,84.91 119.03,85.59 116.93,85.59 116.34,86.19 113.09,86.19 112.67,85.77 111.58,85.77 111.17,86.19 110.89,86.19 110.63,86.45 110.63,87.12 110.88,87.36 LZ1.1
USB20_N5_R: length 3.5
  BOTTOM w0.094: LZ1.2 110.88,89.11 110.63,89.35 110.63,91.36 110.8,91.53 JEDP1.12
USB20_N7: length 18.7
  BOTTOM w0.076: v1(140.69,54.33) 140.69,54.33 140.8,54.33 140.88,54.41 140.88,54.49 141.06,54.68 141.06,54.73 140.64,55.15 140.58,55.15 138.25,55.15 138.22,55.18 137.99,55.18 137.97,55.15 137.97,55.07 137.94,55.04 137.77,55.04 137.72,55.09 137.72,55.14 137.68,55.18 137.49,55.18 137.45,55.14 137.45,54.92 137.4,54.87 137.2,54.87 UC1.AH1
  BOTTOM w0.094: v1(190.91,33.65) 190.91,32.93 196.54,27.31 196.54,24.04 196.78,23.79 197.01,23.79 197.16,23.64 LI9.1 197.73,23.48 RI50.1
USB20_N7_L: length 3
  BOTTOM w0.094: JNGFF1.5 200.56,23.75 200.4,23.91 199.64,23.91 199.53,23.8 199.26,23.8 199.11,23.64 LI9.2 198.65,23.48 RI50.2
USB20_N8: length 13.7
  BOTTOM w0.094: UC1.AF8 133.3,56.4 133.2,56.31 v1(133.2,55.94) ; LV27.3 127.23,86.87 129.37,89 129.37,89.96 130.77,91.37 131.52,91.37 131.9,90.99 131.9,90.75 v1(132.07,90.57)
USB20_N8_R: length 10.5
  BOTTOM w0.094: JEDP1.2 115.8,91.46 115.73,91.4 115.58,91.4 115.49,91.3 115.49,91.05 117.1,89.43 117.1,88.24 117.95,87.39 118.43,87.39 118.52,87.48 DV4.2 119.42,87.39 119.68,87.39 119.97,87.1 119.97,86.89 120.22,86.64 120.44,86.64 LV27.4
USB20_N9: length 5
  TOP w0.076: UT5.K5 30.64,81.21 30.57,81.29 30.05,81.29 29.84,81.07 29.73,81.07 v1(29.61,81.18)
  BOTTOM w0.076: v1(139.82,56.63) 139.69,56.63 139.62,56.56 139.62,56.25 139.26,55.89 138.1,55.89 138.05,55.84 138.05,55.78 137.99,55.72 137.87,55.72 137.8,55.79 137.8,55.84 137.75,55.89 137.43,55.89 137.29,55.78 137.29,55.64 137.34,55.6 UC1.AG1
USB20_N10: length 9.2
  TOP w0.094: v1(225.53,17.81) 225.28,17.56 225.28,12.13 223.8,10.65 JUSH1.8
  BOTTOM w0.094: v1(134.36,54.88) UC1.AH7
USB20_P1: length 8.9
  TOP w0.094: v1(302.39,64.84) 302.47,64.84 302.67,64.64 302.67,64.4 303.41,63.66 304.39,63.66 304.79,63.26 304.95,63.26 304.96,63.25 305.59,63.25 305.6,63.26 305.82,63.26 305.87,63.21 308.2,63.21 308.2,63.2 v4(308.44,62.97) 308.45,62.97 308.64,62.78 308.64,62.3 308.49,62.15 UI3.3
  BOTTOM w0.076: v1(132.45,58.08) UC1.AB10
USB20_P1_R: length 4.1
  TOP w0.094: LI7.3 309.04,47.1 308.83,47.3 308.83,47.64 309.22,48.02 309.22,48.44 309.52,48.74 DI5.3 309.42,49.41 v1(309.42,49.73)
USB20_P2: length 1.8
  TOP w0.094: v1(30.77,69.86) 30.77,69.87 30.59,70.05 29.97,70.05 29.79,69.87 LI3.1
  BOTTOM w0.076: UC1.AD7 134.31,57.24 v1(134.31,56.99)
USB20_P2_R: length 17
  TOP w0.094: LI3.2 28.28,70.06 27.88,70.06 26.77,71.17 26.33,71.17 26.22,71.06 DI2.2 25.54,70.97 v1(25.41,70.97)
  BOTTOM w0.094: v1(25.41,70.97) 25.21,71.17 25.11,71.17 24.69,70.75 22.11,70.75 20.5,72.35 v4(19.39,72.35) 18.6,72.35 18.29,72.66 17.65,73.29 17.64,73.29 17.18,73.76 17.18,73.77 16.64,74.31 15.75,74.31 15.66,74.21 JUSB2.3
USB20_P3: length 5.2
  BOTTOM w0.076: v1(138.65,54.26) 138.72,54.2 138.87,54.2 139.04,54.37 139.04,54.59 138.92,54.71 137.9,54.71 137.72,54.54 137.36,54.54 137.24,54.49 137.07,54.49 136.87,54.55 136.85,54.55 136.76,54.55 136.6,54.5 136.36,54.5 136.28,54.54 136.11,54.48 136.06,54.37 136.15,54.27 UC1.AJ3
  BOTTOM w0.094: v1(76.37,100.09) 76.58,100.3 76.99,100.3 77.2,100.09 LI4.1
USB20_P3_R: length 12
  BOTTOM w0.094: JUSB3.3 80.15,107.02 80.46,106.71 80.46,105.4 80.34,105.28 80.34,104.86 79.49,104.02 DI3.2 80.07,103.8 80.22,103.65 80.22,103.14 79.84,102.76 79.1,102.76 78.64,103.22 78.14,103.22 v4(77.88,102.96) 77.59,102.68 77.59,101.99 77.59,101.98 77.59,101.4 77.59,101.4 77.59,101.26 77.89,100.97 77.89,100.51 78.1,100.3 78.28,100.3 78.49,100.09 LI4.2
USB20_P4: length 7.3
  TOP w0.094: v1(288.03,43.02) 287.8,43.25 287.69,43.25 287.43,43.51 287.43,45.2 288.69,46.45 289.81,46.45 290.06,46.2 290.06,46.01 290.2,45.88 LI8.1 290.36,45.43 RI47.1
  BOTTOM w0.076: v1(132.45,57.01) 132.3,57.23 UC1.AD10
USB20_P4_L: length 5.5
  TOP w0.094: v1(290.31,43.13) 290.2,43.25 LI8.2 290.36,44.52 RI47.2
  BOTTOM w0.094: JNGFF2.7 288.3,42.52 288.41,42.63 288.41,42.87 289.42,43.88 290.02,43.88 290.22,43.68 290.22,43.23 v1(290.31,43.13)
USB20_P5: length 32.5
  BOTTOM w0.094: v1(133.49,92.38) 133.49,92.36 133.48,92.35 133.48,90.26 133.14,89.92 131.44,89.92 127.49,85.96 122.65,85.96 122.25,85.56 121.47,85.56 120.64,84.73 119.64,84.73 118.96,85.41 116.86,85.41 116.26,86 113.16,86 112.75,85.59 111.51,85.59 111.09,86 110.81,86 110.45,86.37 110.45,87.12 110.28,87.29 LZ1.4 ; UC1.AJ2 136.98,54.19 137.38,53.78 137.8,53.78 137.88,53.71 138.44,53.71 138.47,53.68 138.81,53.68 138.87,53.62 138.87,53.54 v1(138.6,53.27)
USB20_P5_R: length 3.5
  BOTTOM w0.094: LZ1.3 110.28,89.16 110.45,89.33 110.45,91.37 110.3,91.51 JEDP1.13
USB20_P7: length 19
  BOTTOM w0.076: UC1.AH2 136.52,54.92 137.24,55.29 137.42,55.34 138.29,55.34 138.32,55.31 140.51,55.31 140.71,55.31 141.27,54.75 v1(141.27,54.33)
  BOTTOM w0.094: v1(191.5,33.65) 191.37,33.65 191.32,33.6 191.32,33.48 191.1,33.27 191.1,33.01 196.72,27.39 196.72,24.11 196.86,23.98 197.02,23.98 197.18,24.14 LI9.4 197.73,24.31 RI49.1
USB20_P7_L: length 3
  BOTTOM w0.094: JNGFF1.3 200.56,24.25 200.41,24.09 199.56,24.09 199.45,23.98 199.28,23.98 199.12,24.14 LI9.3 198.65,24.31 RI49.2
USB20_P8: length 13.6
  BOTTOM w0.094: UC1.AF9 132.78,56.17 v1(132.55,55.94) ; LV27.2 122.03,86.27 122.44,86.68 127.31,86.68 129.55,88.93 129.55,89.88 130.85,91.18 131.44,91.18 131.71,90.91 131.71,90.76 131.52,90.57 v1(131.37,90.57)
USB20_P8_R: length 10.5
  BOTTOM w0.094: JEDP1.3 115.3,90.97 116.92,89.35 116.92,88.16 117.87,87.2 118.46,87.2 118.52,87.14 DV4.3 119.36,87.2 119.61,87.2 119.79,87.02 119.79,86.81 120.15,86.45 120.48,86.45 LV27.1
USB20_P9: length 4.8
  TOP w0.076: v1(29.01,81.18) 29.4,80.79 29.89,80.79 UT5.L5
  BOTTOM w0.076: v1(139.11,56.55) 139.38,56.55 139.45,56.48 139.45,56.32 139.19,56.06 137.37,56.06 UC1.AG2
USB20_P10: length 9.2
  TOP w0.094: JUSH1.9 223.37,11.15 223.47,11.05 223.47,10.91 223.55,10.84 223.72,10.84 225.09,12.21 225.09,17.4 v1(224.67,17.82)
  BOTTOM w0.094: v1(133.67,54.88) UC1.AH8
USB_OC0#: length 105
  TOP w0.102: UI3.13 311.56,59.47 v1(312.06,59.97) ; v1(136.78,80.16) 137.4,79.54 139.82,79.54 141.74,77.62 147.2,77.62 149.49,79.91 150.68,79.91 154.03,76.57 154.03,75.09 163.01,66.11 164.14,66.11 173.69,56.55 173.69,49.98 184.1,39.57 188.26,39.57 189.31,38.52 189.31,31.76 v2(189.11,31.56) 189.11,24.81 189.21,24.7 v1(189.21,24.44)
  BOTTOM w0.076: 135.22,73.56 135.22,73.27 132.92,70.97 132.92,69.82 UC1.A9
  BOTTOM w0.102: 135.22,73.56 135.9,74.23 135.9,78.53 136,78.63 136.53,78.63 136.78,78.88 RPC3.2 136.78,80.15 v1(136.78,80.16)
USB_OC1#: length 37.9
  TOP w0.102: UI1.3 22.04,74.18 v1(23.02,73.2)
  BOTTOM w0.076: UC1.C9 132.81,68.59 133.12,68.9 133.12,70.94 135.41,73.23 135.41,73.27
  BOTTOM w0.102: v1(36.2,61.49) 33.41,61.49 v2(31.69,63.21) 27.06,67.84 27.06,72.25 26.75,72.55 24.42,72.55 23.78,73.2 v1(23.02,73.2) ; v1(137.28,80.48) RPC3.3 137.28,78.9 137.55,78.63 138.05,78.63 138.44,78.25 138.44,76.3 135.41,73.27
USB_OC2#: length 27.8
  BOTTOM w0.076: UC1.D9 132.81,67.97 133.24,68.39 133.49,68.39 133.72,68.62 133.72,68.87 133.36,69.23 133.36,70.76 133.61,71.01
  BOTTOM w0.102: 133.61,71.01 138.82,76.22 138.82,78.23 RPC3.4 137.75,79.29 137.75,79.91 v1(137.7,79.96) ; v1(84.97,87.76) v2(84.97,89.79) 84.97,98.58 UI2.3
USB_OC3#: length 11.9
  BOTTOM w0.076: 135.51,74.46 v2(135.04,73.99) 135.04,73.33 132.75,71.04 132.75,70.08 132.5,69.83 132.5,69.38 UC1.B9
  BOTTOM w0.102: RPC3.1 135.64,78.63 135.64,74.59 135.51,74.46
USB_PWR_EN1#: length 13.7
  TOP w0.102: RPE11.3 v1(304.68,66.5) ; UI1.4 23.3,73.81 v1(23.02,73.81)
  TOP w0.107: v1(303.16,73.13) UE1.K3
  BOTTOM w0.102: v1(29.34,66.44) v2(28.5,67.28) 27.26,68.52 27.26,72.33 26.83,72.76 24.52,72.76 23.64,73.63 23.19,73.63 v1(23.02,73.81)
USB_PWR_EN2#: length 13.6
  TOP w0.102: RPE11.1 305.68,66.2 v1(306.03,66.55) ; v1(299.96,74.73) UE1.G5
  BOTTOM w0.102: v1(84.28,87.74) 83.58,88.44 v2(83.58,95.13) UI2.4
USB_PWR_SHR_LFT_EN#: length 9.8
  TOP w0.102: UI3.6 306.93,60.47 306.46,60.94 v1(306.46,61.41) ; v1(305.39,66.51) 305.18,66.3 RPE11.2
  TOP w0.107: v1(302.36,73.13) UE1.J3
  BOTTOM w0.102: v1(305.39,66.51) 305.01,66.12 v2(305.01,65.68) 305.01,65.63 307.39,63.25 307.39,61.7 307.1,61.41 v1(306.46,61.41)
USB_PWR_SHR_VBUS_EN: length 17.2
  TOP w0.102: UI3.5 307.19,61.68 v1(306.98,61.9) ; 303.95,67.1 304.01,67.1 304.18,66.93 RPE11.4 ; 303.95,67.1 v1(303.82,67.1) ; 303.95,67.1 304.26,67.41 304.26,69.3 302.34,71.21 302.34,72.34 UE1.J2 ; RI81.1 304.16,53.18 v1(304.3,53.32)
  BOTTOM w0.102: v1(306.98,61.9) 306.98,62.09 303.82,65.25 v2(303.82,66.41) v1(303.82,67.1)
USBCOMP: length 4.7
  TOP w0.102: RC44.1 130.81,58.59 v2(131.53,58.59) 133.93,58.59 v1(134.38,58.14)
  BOTTOM w0.102: UC1.AB6 134.74,58.5 v1(134.38,58.14)
USH_DET#: length 20.9
  TOP w0.102: RZ87.1 220.15,21.99 DZ7.2 220.15,23.06 220.85,23.06 221.49,23.7 221.49,26.38 220.52,27.36 v2(220.52,28.44) v1(220.52,29.21) ; v1(297.55,82.32) 297.55,82.17 297.16,81.78 UE1.C13
  BOTTOM w0.102: RE526.1 300.14,89.12 300.14,86.34 299.25,85.44 299.25,82.6 298.58,81.93 297.94,81.93 v1(297.55,82.32)
USH_DET#_R: length 5.4
  TOP w0.102: v2(221.91,23.58) 221.31,22.98 DZ7.1 221.06,22.27 RZ87.2 221.63,20.92 221.63,20.46 222.43,19.65 JUSH1.26
USH_PWR_STATE#: length 12.5
  TOP w0.102: RZ10.2 222,19.65 v1(222,18.69) 222,18.18 222.53,17.65 JUSH1.22 ; v1(52.58,82.82) 52.58,82.82 51.82,82.06 v3(51.82,81.93)
  BOTTOM w0.102: UE2.9 46.86,80.78 47.29,81.21 50.97,81.21 v1(52.58,82.82)
USH_RST#_R: length 3.9
  TOP w0.102: RZ114.2 221.62,19.02 221.62,17.28 v2(221.66,17.24) 221.75,17.15 JUSH1.21
USH_SMBCLK: length 44.5
  TOP w0.102: JUSH1.11 222.7,12.15 222.56,12.29 222.4,12.29 222.23,12.12 222.23,11.35 221.84,10.97 221.59,10.97 CZ62.1 220.52,10.97 219.31,10.97 RZ8.2 218.27,10.94 217.61,10.94 217.43,10.76 217.43,9.75 218.32,8.86 218.32,6.26 219.19,5.39 223.11,5.39 227.45,9.73 227.45,17.66 223.87,21.25 223.87,24.93 223.28,25.52 223.28,28.01 v1(223.09,28.2) ; v1(295.96,73.13) UE1.B3
USH_SMBDAT: length 45.7
  TOP w0.102: v1(223.67,28.2) 223.51,28.04 223.51,25.61 224.1,25.03 224.1,21.34 227.68,17.76 227.68,9.64 223.21,5.16 v4(219.63,5.16) 219.1,5.16 218.09,6.16 218.09,8.76 217.2,9.65 217.2,10.85 217.52,11.17 218.24,11.17 RZ9.2 219.28,11.2 220.56,11.2 CZ63.1 221.57,11.19 221.75,11.19 222,11.45 222,12.21 222.31,12.51 222.61,12.51 222.75,12.65 JUSH1.12 ; UE1.E5 298.76,75.1 v1(298.36,74.7)
VCI_IN1#: length 6.6
  TOP w0.102: RE507.1 291.88,75.33 292.77,74.44 v2(293.57,74.44) 293.96,74.04 294.59,74.04 295.24,74.69 295.73,74.69 296.17,75.13 UE1.B5
VCI_IN2#: length 16.1
  TOP w0.102: v1(297.56,73.93) UE1.D4 ; RE508.1 286.75,69.18 v1(286.64,69.18) v2(286.22,68.76)
  BOTTOM w0.102: v1(286.64,69.18) 286.64,69.58 290.26,73.19 294.12,73.19 294.63,72.68 297.07,72.68 297.17,72.78 297.17,73.53 v1(297.56,73.93)
VCT_LAN_R1: length 2.3
  TOP w0.102: RL3.1 282.96,85.42 v2(282.45,85.42) UL1.6
VGA_ID: length 15.8
  TOP w0.102: RE85.1 RE84.1 300.86,92.78 302.58,91.07 v1(302.58,90.27)
  TOP w0.107: v1(301.59,80.36) UE1.H11
  BOTTOM w0.102: v1(301.59,80.36) 301.6,80.37 301.6,83.38 303.19,84.97 303.19,86.26 v2(303.09,86.37) 303.09,89.35 302.58,89.87 v1(302.58,90.27)
VID0_PRIM_CORE: length 4.8
  TOP w0.102: PR420.1 v2(124.49,115.97)
  TOP w0.254: PR420.1 124.51,114.97 PR418.2 PR408.2 125.93,114.14 v1(126.2,114.4) ; v1(132.32,114.16) 132.29,114.18 131.76,114.18 131.58,114.01 PU402.9
VID0_VCCIO: length 5.7
  TOP w0.254: PU401.9 141.98,111.72 142.31,112.04 v2(142.31,112.35) 142.31,113.72 142.5,113.91 142.88,113.91 PR416.1 144.28,113.73 PR414.2
VID1_PRIM_CORE: length 4.7
  TOP w0.102: v1(121.99,114.14) v2(121.48,114.14)
  TOP w0.254: v1(132.49,113.51) 132.8,113.51 133.05,113.27 133.05,113.02 132.87,112.84 PU402.8 ; v1(121.99,114.14) PR411.2 122.77,114.14 PR417.2 123.67,114.17 PR419.1
VID1_VCCIO: length 4
  TOP w0.254: PU401.8 142.81,110.51 143.47,110.51 143.81,110.85 v2(143.81,111.19) 143.81,111.59 143.41,111.98 PR415.1 144.02,112.57 PR413.2
VIDALERT_N: length 3.4
  TOP w0.102: PR625.1 v1(75.62,49.92)
  BOTTOM w0.102: RC153.2 99.73,76.07 v1(99.7,76.09) RC152.1 ; PR604.2 v1(75.62,49.92)
VIDALERT_N_B: length 2.5
  TOP w0.102: PU602.36 72.22,50.38 72.69,49.92 PR625.2
VIDSCLK: length 16.7
  TOP w0.102: PR618.1 75.91,50.82 v1(76.09,50.64)
  BOTTOM w0.076: 100.47,72.9 100.72,72.65 100.72,72.36 101.83,71.24 101.83,70.84 101.69,70.69 101.49,70.69 101.35,70.55 101.35,70.35 101.57,70.13 101.57,69.85 UC1.A63
  BOTTOM w0.102: CC321.1 100.54,75.46 100.04,74.96 v1(100.04,74.73) 100.04,74.4 100.21,74.23 100.43,74.23 100.55,74.35 100.55,74.91 100.62,74.98 100.85,74.98 100.95,74.88 100.95,74.21 100.52,73.77 100.17,73.77 v2(99.51,74.43) 99.51,74.9 99.4,75.01 98.92,75.01 98.83,74.91 98.83,74.54 100.47,72.9 ; PR601.2 75.39,50.78 75.53,50.64 v1(76.09,50.64)
VIDSCLK_B: length 2.5
  TOP w0.102: PR618.2 72.37,50.82 72.33,50.78 PU602.37
VIDSOUT: length 15.8
  TOP w0.102: v1(75.62,49.03) 75.61,49.04 PR626.1
  BOTTOM w0.076: 99.75,72.99 100.02,72.72 100.02,72.5 100.19,72.33 100.19,72.21 100.07,72.09 100.07,71.96 100.16,71.87 100.28,71.87 100.4,71.99 100.53,71.99 100.62,71.9 100.62,71.78 100.41,71.57 100.41,71.45 100.5,71.36 100.63,71.36 100.83,71.56 100.96,71.56 101.02,71.5 101.02,70.21 101.24,69.99 101.24,69.08 101.46,68.86 101.46,68.62 101.16,68.33 UC1.D64
  BOTTOM w0.102: RC157.1 98.68,76.41 98.42,76.15 v1(98.42,76.09) 98.31,75.98 98.31,75.38 97.1,74.17 97.1,73.83 97.64,73.3 99.45,73.3 99.75,72.99 ; v1(75.62,49.03) PR605.2
VIDSOUT_B: length 2.5
  TOP w0.102: PU602.35 72.1,49.98 v2(72.37,49.71) 73.04,49.04 PR626.2
VR_HOT#_CPU: length 3.9
  TOP w0.203: PU602.38 72.38,51.18 v2(72.58,51.39) 72.58,51.85 72.42,52.01 72.42,52.4 72.8,52.78 73.39,52.78 PR678.2
VR_READY_CPU: length 4.3
  TOP w0.203: PU602.39 72.04,51.58 v1(72.13,51.68)
  BOTTOM w0.254: PR614.2 PR612.2 73.6,52.74 72.63,52.74 v2(72.39,52.5) 72.13,52.24 v1(72.13,51.68)
VRALERT#: length 2.2
  TOP w0.102: v1(130.69,53.04) 130.5,53.04 v2(130.26,52.8) ; v1(152.02,34.56) 151.77,34.31 RC73.1
  BOTTOM w0.076: UC1.AM11 131.1,53.45 v1(130.69,53.04)
VSA_SEN+: length 14.3
  TOP w0.254: v1(122.18,79.65) 122.43,79.9 RC168.2
  BOTTOM w0.203: v1(68.46,45.48) 68.46,45.34 68.25,45.14 PR649.2 68.28,44.71 PC650.1 69.07,43.86 PC652.1 PC640.2
  BOTTOM w0.254: v1(121.79,71.54) 121.51,71.54 121.01,72.05 121.01,74.54 122.56,76.09 v2(122.56,77.45) 122.56,79.27 v1(122.18,79.65) ; UC1.H20 126.39,65.04 v1(126.12,65.31)
VSA_SEN-: length 16.3
  TOP w0.203: PU602.26 68.96,46.11 v1(68.84,45.99)
  TOP w0.254: v1(122.05,79.01) 121.67,79.39 121.67,79.89 RC166.1
  BOTTOM w0.203: PC649.1 69.99,43.83 PC650.2 69.99,45.2 69.19,45.99 v1(68.84,45.99)
  BOTTOM w0.254: UC1.H21 125.46,65.04 v1(125.2,65.29) ; v1(121.81,70.82) 121.74,70.82 120.53,72.02 120.53,74.7 v2(121.25,75.42) 122.05,76.22 v1(122.05,79.01)
VSET_5105: length 4.3
  TOP w0.102: v2(294.23,82.89) 293.91,82.57 RE77.1
  TOP w0.112: RE77.1 CE38.1 294.24,81.68 v1(294.85,81.07) ; v1(296.76,78.73) UE1.C9
VSYNC_CONN: length 5.3
  TOP w0.102: RV121.1 315.71,76.24 316.54,76.24 LV20.2 317.6,76.32 CV132.1 317.68,76.31 v2(319.22,76.31) JCRT1.14
VSYNC_CRT: length 1.7
  TOP w0.102: v1(280.67,54) 280.6,54.07 UV6.18 ; v1(316.36,74.82) 316.62,75.08 LV20.1
VSYS_ISL88738: length 4.1
  TOP w0.203: v1(21.39,16.17) 21.2,16.36 PU901.3
  BOTTOM w0.254: v1(21.39,16.17) 21.59,16.36 v2(22.08,16.36) 22.48,16.36 22.86,16.74 PR929.1 23.42,15.89 PC939.1
WIGIG_32KHZ: length 11.7
  TOP w0.102: RZ56.2 198.18,13.38 v2(200.08,13.38) 200.08,13.18 200.89,12.37 204.72,12.37 205.39,13.04 v1(206.07,13.04)
  BOTTOM w0.102: v1(206.07,13.04) 206.9,13.04 207.44,12.5 JNGFF1.42
WLAN_COEX1: length 7.4
  TOP w0.102: RZ130.2 302.96,46.08 v1(302.96,45.56) 303.36,45.56 303.69,45.23 v2(304.6,45.23)
  BOTTOM w0.102: JNGFF1.40 210.24,13 211.82,14.57 211.82,15.11 v1(211.26,15.66)
WLAN_COEX2: length 4.6
  TOP w0.102: v2(303.2,45.08) 302.85,45.08 v1(302.37,45.56) 302.37,46.04 RZ129.2
  BOTTOM w0.102: v1(210.65,14.83) 210.65,13.99 210.16,13.5 JNGFF1.38
WLAN_COEX3: length 4.2
  TOP w0.102: v2(301.78,45.03) v1(301.78,45.56) 301.78,45.93 RZ128.2
  BOTTOM w0.102: v1(210.65,15.67) 210.22,15.23 210.22,14.45 209.77,14 JNGFF1.36
WLAN_WIGIG60GHZ_DIS#: length 42.9
  TOP w0.102: DZ1.1 216.58,9.38 217.52,8.44 v2(217.52,6.16) 217.52,5.84 218.68,4.67 223.43,4.67 228.45,9.7 228.45,17.72 224.58,21.6 224.58,26.67 224.57,26.68 224.57,28.85 225.13,29.41 v1(225.63,29.41) ; UE1.L13 303.56,81.76 303.38,81.93 v1(303.38,82.39) 304.07,82.39 304.81,83.13 RE8.1
WLAN_WIGIG60GHZ_DIS#_R: length 6.7
  TOP w0.102: DZ1.2 214.68,9.57 v2(213.8,9.57) 213.53,9.57 v1(212.68,10.41)
  BOTTOM w0.102: v1(212.68,10.41) 212.1,11 JNGFF1.48
WRST#: length 5.1
  BOTTOM w0.254: CE500.1 RE6.2 43.36,81.04 v2(43.44,81.12) 43.59,80.97 43.59,78.89 43.98,78.5 UE2.4
WWAN_COEX1: length 4
  TOP w0.102: v2(303.08,47.91) 302.86,47.91 302.55,47.6 v1(302.55,47.33) 302.84,47.04 RZ130.1
  BOTTOM w0.102: JNGFF2.56 302.55,48.86 302.93,48.48 302.93,47.7 v1(302.55,47.33)
WWAN_COEX2: length 3.2
  TOP w0.102: RZ129.1 302.05,46.94 v1(302.05,47.77) 302.05,47.93 v2(301.78,48.2)
  BOTTOM w0.102: JNGFF2.54 v1(302.05,47.77)
WWAN_COEX3: length 4.8
  TOP w0.102: v2(299.6,47.58) 299.66,47.64 301.25,47.64 v1(301.57,47.33) RZ128.1
  BOTTOM w0.102: v1(301.57,47.33) 301.55,47.34 JNGFF2.52
WWAN_PWR_EN: length 4.6
  TOP w0.102: v1(288.27,50.5) 288.57,50.21 v2(289.45,50.21) 290.05,50.21 290.35,50.51 RZ43.1 CZ198.1
  BOTTOM w0.102: v1(288.27,50.5) 288.05,50.28 JNGFF2.6
WWAN_RADIO_DIS#: length 12.7
  TOP w0.102: UE1.M2 304.81,72.28 304.81,71.22 305.6,70.43 v1(305.97,70.43) v2(306.49,70.43) 306.84,70.08 RE10.1 ; DZ5.1 292.83,48.14 v1(292.66,47.97)
  BOTTOM w0.102: v1(292.66,47.97) 293.05,47.59 298.31,47.59 v1(298.92,46.99)
WWAN_RADIO_DIS#_R: length 8.3
  TOP w0.102: v1(292.08,50.73) 292.22,50.87 DZ5.2
  BOTTOM w0.102: JNGFF2.8 288.55,48.74 288.84,48.46 289.16,48.46 291.43,50.73 v1(292.08,50.73) 292.99,50.73 293.68,51.41 v2(293.68,51.72)
WWAN_WAKE#: length 26
  TOP w0.102: v1(285.55,40.82) 285.55,41.08 286.03,41.56 291.05,41.56 291.84,40.77 v1(292.77,40.77) ; UE1.M13 304.36,82 v1(305.71,83.34) 305.85,83.48 305.85,83.99 RE38.1
  BOTTOM w0.102: v1(314.69,87.01) 313.16,88.54 v2(312.65,88.54) 309.5,88.54 309.15,88.18 309.15,85.55 306.94,83.34 v1(305.71,83.34) ; v1(292.77,40.77) 292.59,40.77 292.3,41.05 JNGFF2.15
XCLK_BIASREF: length 5.5
  TOP w0.102: v2(110.43,68.22) 111.7,68.22 112.2,67.72 112.48,67.72 112.97,67.24 RC324.1
  TOP w0.254: RC324.1 114.21,67.24 v1(114.22,67.23) ; v1(123.9,61.5) 123.92,61.47 RC52.1
  BOTTOM w0.254: v1(114.22,67.23) 114.01,67.23 UC1.E42
XDP_DBRESET#: length 15.6
  TOP w0.102: v1(55.47,27.59) v2(59.28,27.59) RC137.1 CC32.1 63.95,27.66 JXDP1.48
  BOTTOM w0.102: UC12.1 149.32,90.9 148.87,90.45 148.87,89.38 149.12,89.12 149.66,89.12 150.2,88.58 RC290.1 v1(150.2,87.75)
XDP_JTAGX: length 10.7
  BOTTOM w0.076: 103.11,74.12 103.13,74.1 103.13,74.08 103.45,73.76 103.45,72.26 104.05,71.66 104.05,69.87 UC1.A59
  BOTTOM w0.102: 103.11,74.12 v2(103.11,74.19) 103.11,74.57 102.75,74.93 CC305.1 103.26,75.95 103.26,77.23 RC328.1 102.49,78.23 RC87.1
XDP_OBS0: length 3.9
  TOP w0.102: v2(72.19,38.26) 72.09,38.36 RC239.2 71.05,38.36 70.45,37.76 JXDP1.21
XDP_OBS0_R: length 14.5
  TOP w0.102: v1(61.93,44.67) 63.96,44.67 66.76,41.87 69.91,41.87 70.64,41.14 70.64,39.88 RC239.1
  BOTTOM w0.076: UC1.C55 106.01,68.85 106.01,70.01 105.95,70.07 105.95,70.51 v1(106.21,70.77)
XDP_OBS1: length 4.7
  TOP w0.102: v2(69.7,40.23) 69.7,38.89 RC240.2 69.95,38.07 JXDP1.23
XDP_OBS1_R: length 13.2
  TOP w0.102: RC240.1 70.24,40.28 69.13,41.39 66.67,41.39 63.97,44.09 v2(62.86,44.09) v1(61.96,44.09)
  BOTTOM w0.076: v1(106.32,70.22) 106.38,70.16 106.38,68.9 106.41,68.86 106.41,68.62 106.12,68.33 UC1.D55
XDP_OBS2_R: length 8.6
  BOTTOM w0.076: T10.1 107.32,75.89 107.32,74.44 105.92,73.04 105.92,71.37 105.98,71.31 106.5,71.31 106.91,70.9 106.91,70.12 106.97,70.06 106.97,69.35 UC1.B54
XDP_OBS3_R: length 7.5
  BOTTOM w0.076: 105.26,73.07 105.58,72.75 105.58,71.05 105.78,70.85 105.78,69.99 105.83,69.94 105.83,68.86 105.56,68.59 UC1.C56
  BOTTOM w0.102: T11.1 106.02,74.03 105.47,74.03 105.16,73.71 105.16,73.17 105.26,73.07
XDP_PRSNT_PIN1: length 4.7
  TOP w0.102: JXDP1.1 75.45,37.73 RC122.1 RC121.1 v2(78.05,38.36)
XDP_TMS: length 16.6
  TOP w0.102: v1(59.33,31.62) 59.81,32.1 61.35,32.1 61.45,32 JXDP1.58 ; v1(51.62,30.54) 51.62,29.84 52.15,29.3 RC228.1 v2(52.2,30.17) 52.2,30.22 52.22,30.23 UC8.9
  BOTTOM w0.102: v1(59.33,31.62) 58.24,31.62 57.86,31.24 56.03,31.24 55.68,31.58 52.07,31.58 51.62,31.13 v1(51.62,30.54)
XTAL24_IN: length 13.7
  BOTTOM w0.102: UC1.E37 116.29,67.22 116.29,67.89 116.34,67.94 116.34,68.22 116.15,68.41 115.91,68.41 115.73,68.58 115.73,68.6 115.73,68.61 115.73,68.87 115.73,68.87 115.73,68.89 115.75,68.9 115.75,71.04 115.8,71.09 116.16,71.45 116.16,73.17 116.69,73.7 v2(116.69,74.85) 116.69,78.2 RC46.2 115.66,79.23 RC417.1
XTAL24_IN_R: length 4.8
  BOTTOM w0.102: RC417.2 116.57,79.33 CC21.1 116.83,80.47 116.83,82.65 YC1.3
XTAL24_OUT: length 15.3
  BOTTOM w0.102: RC295.1 117.44,78.46 RC46.1 117.3,78.33 v2(117.3,77.21) 117.3,73.2 117.2,73.09 116.5,73.09 116.4,72.99 116.4,72.73 116.5,72.62 117.01,72.62 117.11,72.52 117.11,72.32 117.01,72.22 116.5,72.22 116.4,72.12 116.4,71.32 115.99,70.91 115.99,69.8 116.32,69.48 116.32,68.9 116.48,68.74 116.74,68.74 116.9,68.57 116.9,67.52 UC1.E35
XTAL24_OUT_R: length 3.2
  BOTTOM w0.102: YC1.1 117.44,81.27 CC22.1 117.46,80.21 RC295.2
XTALI: length 10.8
  TOP w0.102: YL1.1 289.12,89.67 287.11,89.67 286.49,90.29 v2(286.33,90.29) 285.4,90.29 RL11.2 284.46,89.35 CL14.1 283.93,88.92 283.68,88.92 281.78,87.02 UL1.10
XTALO: length 5.4
  TOP w0.102: UL1.9 281.87,86.62 283.22,87.97 v2(283.48,87.97) 283.67,88.16 RL34.2 284.41,88.38 RL11.1
XTALO_R: length 3.3
  TOP w0.102: RL34.1 285.32,88.31 CL13.1 286.59,89.17 287.44,89.17 YL1.3
Z2805: length 3.8
  TOP w0.508: RL18.1 v2(302.39,102.25) 302.39,102.54 302.14,102.79 v1(302.14,102.96)
  BOTTOM w0.508: TL1.24 301.71,102.53 v1(302.14,102.96)
Z2806: length 3.9
  TOP w0.508: RL16.1 v2(295.53,102.28) 295.53,102.76 295.65,102.87 v1(295.65,103.13)
  BOTTOM w0.508: v1(295.65,103.13) 295.71,103.07 TL1.18
Z2807: length 3.9
  TOP w0.508: v1(298.71,103.12) 298.71,102.96 298.84,102.82 v2(298.84,102.28) RL17.1
  BOTTOM w0.508: TL1.21 v1(298.71,103.12)
Z2808: length 3.9
  TOP w0.508: v1(292.73,103.09) 292.73,102.92 292.99,102.66 v2(292.99,102.25) RL15.1
  BOTTOM w0.508: v1(292.73,103.09) 292.71,103.07 TL1.15
N43975: length 3.5
  TOP w0.102: QN1.6 QN1.5 278.94,38.81 277.9,38.81 RN2.2 277.75,39.29 277.73,39.31 v2(277.73,40.1)
N16399089:
  vias: v2(8.51,21.74)
N16400770: length 2.5
  TOP w0.254: v1(16.9,23.65) 16.9,23.25 PR910.1
  BOTTOM w0.127: v1(16.9,23.65) 17,23.65 v2(17.49,23.16)
  BOTTOM w0.254: v1(5.91,16.53) 5.45,16.07 PR901.3
N16404606: length 7
  TOP w0.102: v2(28.58,24.15) 28.71,24.28 PR950.1 29.09,25.16 30.33,25.16 PD905.3 33.3,27.11 PR939.2
N16404788: length 2.5
  TOP w0.102: v2(29.72,25.55) 30.38,26.21 PD905.1 29.87,26.98 PU903.1
N16404800: length 2.9
  TOP w0.102: v2(26.86,28.4) 27.35,28.9 PU903.4 28.44,28.9 28.7,29.15 PR946.1
N16783126: length 1.4
  TOP w0.102: PC111.1 154.27,107.67 v2(154.25,107.65)
N17185089: length 3.3
  TOP w0.102: PR1218.1 16.55,31.78 v2(17.47,30.87)
  TOP w0.254: PR1218.1 16.13,31.78 15.88,32.04 15.88,32.52 15.59,32.81 PQ1204.5
N17185092: length 4.9
  TOP w0.102: v2(18.93,32.68) 18.51,32.26 17.82,32.26 PR1214.2
  TOP w0.254: PR1214.2 17.39,32.19 16.88,32.7 PR1218.2 16.2,32.7 15.44,33.46 PQ1204.6
N17185371: length 3.4
  TOP w0.102: v2(13.16,30.17) 13.16,30.83 PR1223.2
  TOP w0.254: PQ1204.2 13.7,32.81 13.98,32.53 13.98,32.01 13.44,31.48 PR1223.2
N17370862: length 5.8
  TOP w0.102: PC4.2 v2(49.27,80.85)
  TOP w0.508: v1(59.23,101.38) 59.3,101.31 PR16.1 60.69,102.18 PQ5.1
  vias: v1(48.04,81.98)
N17370885: length 4.2
  TOP w0.102: PR15.1 55.69,104.73 v2(55.5,104.54)
  TOP w0.508: PQ5.2 58.24,103.87 PR10.2 56.52,103.88 PR15.1
N17370921: length 3.1
  TOP w0.102: PR15.2 55.8,105.64 v2(55.5,105.94)
  TOP w0.254: PQ1.6 57,106.12 PR15.2
N17370961: length 12.3
  TOP w0.254: PR3.1 63.51,92.35 PQ2.1 63.51,88.29 62.53,87.31 v2(61.35,87.31) 59.96,88.7 59.96,90.32 PL3.1 59.59,90.67 PR6.2
N17370983: length 6.2
  TOP w0.102: PQ2.3 v2(64.48,87.29)
  TOP w0.254: PQ2.3 64.94,89.51 PR5.1 64.91,91.86 PR3.2
N17370995: length 4.7
  TOP w0.102: v2(59.61,87.32) 59.61,88.97 PQ3.2
  TOP w0.254: PQ3.2 57.98,89.65 PR8.2 57.81,89.81 PR6.1
N17370999: length 6.8
  TOP w0.102: PR7.2 62.53,92.36 v2(62.53,93.72)
  TOP w0.254: PQ3.1 62.5,89 PQ2.2 62.55,90 62.03,90.52 PR7.2
N17371029: length 2.3
  TOP w0.508: v1(53.43,91.59) 54.97,93.13 PR18.1
  vias: v1(48.11,91.59) v2(47.76,92.73)
N17371125: length 2.5
  TOP w0.102: PR20.1 64.43,104.79 v2(64.57,104.93)
  TOP w0.381: PQ7.2 63.56,104.59 PR20.1
N17371184: length 3.7
  TOP w0.254: PR23.2 60.65,93.41 v2(61.24,94) 61.47,94.23 v1(62.94,94.23)
  BOTTOM w0.254: v1(62.94,94.23) 63.35,94.65 PU1.4
N17372063: length 3
  TOP w0.102: PR17.2 v2(62.16,108.54)
  TOP w0.381: PR17.2 62.13,107.56 PR19.1 60.75,107.56 60.61,107.42 PQ1.3
N17372074: length 2.2
  TOP w0.102: v2(57.08,107.92) PR25.2
  TOP w0.254: PR25.2 57.26,106.77 PQ1.5
N17372283: length 2
  TOP w0.102: v2(61.22,105.73) PR19.2
  TOP w0.381: PQ1.2 60.31,106.65 PR19.2
N17400451: length 4.1
  TOP w0.102: v2(191.91,1.48) PR516.1
  TOP w0.381: PR515.2 191.91,3.29 PR516.1 ; PR515.2 191.91,4.16 PC515.2 ; PR515.2 192.29,3.29 192.51,3.51 PU503.3
N17479322: length 28.9
  TOP w0.254: PR1251.2 4.59,54.5 PQ1215.2 3.74,52.41 3.31,52.41 1.76,50.86 1.76,37.53 2.44,36.85 v2(6.99,36.85) 10.12,36.85 PR1252.1
N17494434: length 14.5
  TOP w0.254: PR1255.2 v2(16.52,49.68) 17.66,50.82 v1(17.66,52.34) ; PR1238.1 68.46,105.63 PC1211.1 69.84,106.8 PQ1212.1 v1(70.21,105.96)
  BOTTOM w0.254: PU1201.5 69.63,105.38 v1(70.21,105.96) 70.52,106.28 PD1205.1 71.45,107.02 PR1246.1 71.84,105.67 PR1239.2
N17509431: length 4.5
  TOP w0.102: v2(16.92,8.27) PR947.1
  TOP w0.203: PR947.1 PR935.1 PC947.1 18.17,10.56 18.24,10.64 PR949.2
N18490882: length 2.6
  TOP w0.102: v2(312.72,60.78) 312.57,60.78 312.32,61.03 RI14.2 311.08,61.03 311.02,60.97 UI3.16
N18762046: length 0.9
  TOP w0.102: RA17.2 CA33.1
N18762152: length 2.4
  TOP w0.203: CZ127.1 274.71,72 v2(274.58,72.13) 274.56,72.14 UZ5.10
N18762172: length 2.6
  TOP w0.203: CZ126.1 275.72,71.72 275.85,71.85 v2(275.85,72.13) 275.85,72.15 275.36,72.64 UZ5.12
N18762349:
  vias: v2(304.61,33.9)
N18762353: length 2.8
  TOP w0.102: UA1.7 295.84,35.12 v2(295.25,35.71) 294.96,35.71 294.65,36.02 CA53.1
N18762355: length 6.1
  TOP w0.102: v2(305.52,41.22) 304.28,41.22 CA52.1
  TOP w0.203: 301.41,39.29 301,38.88 UA1.39
  TOP w0.254: CA52.1 303.98,40.91 303.69,40.91 303.36,40.58 302.8,40.58 302.47,40.25 302.47,39.98 302.25,39.77 301.89,39.77 301.41,39.29
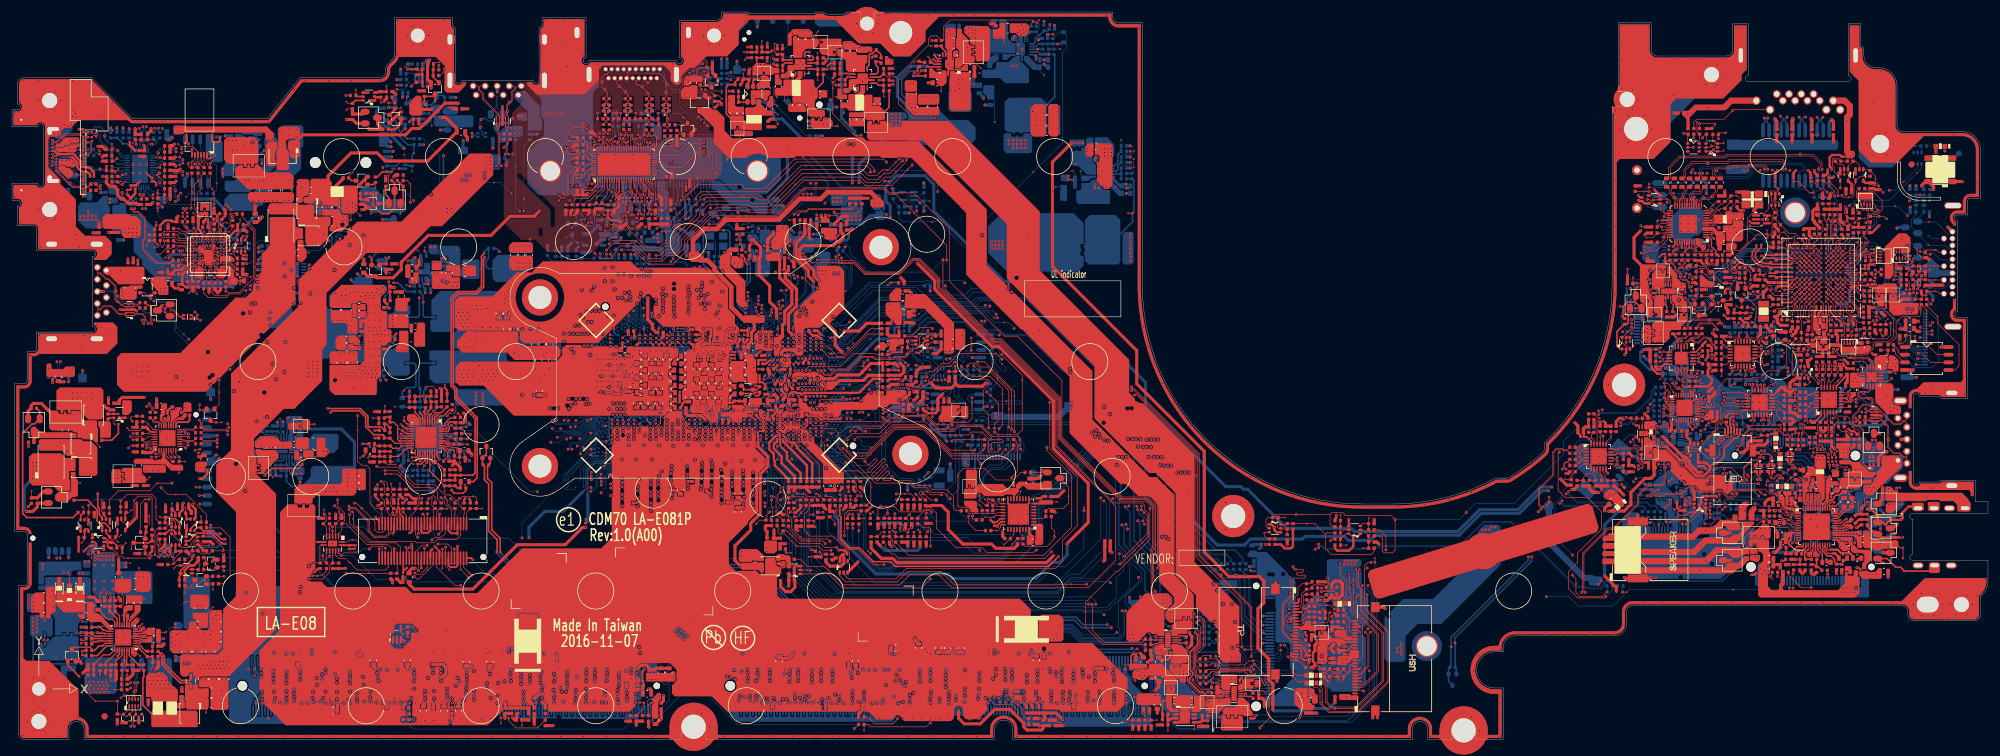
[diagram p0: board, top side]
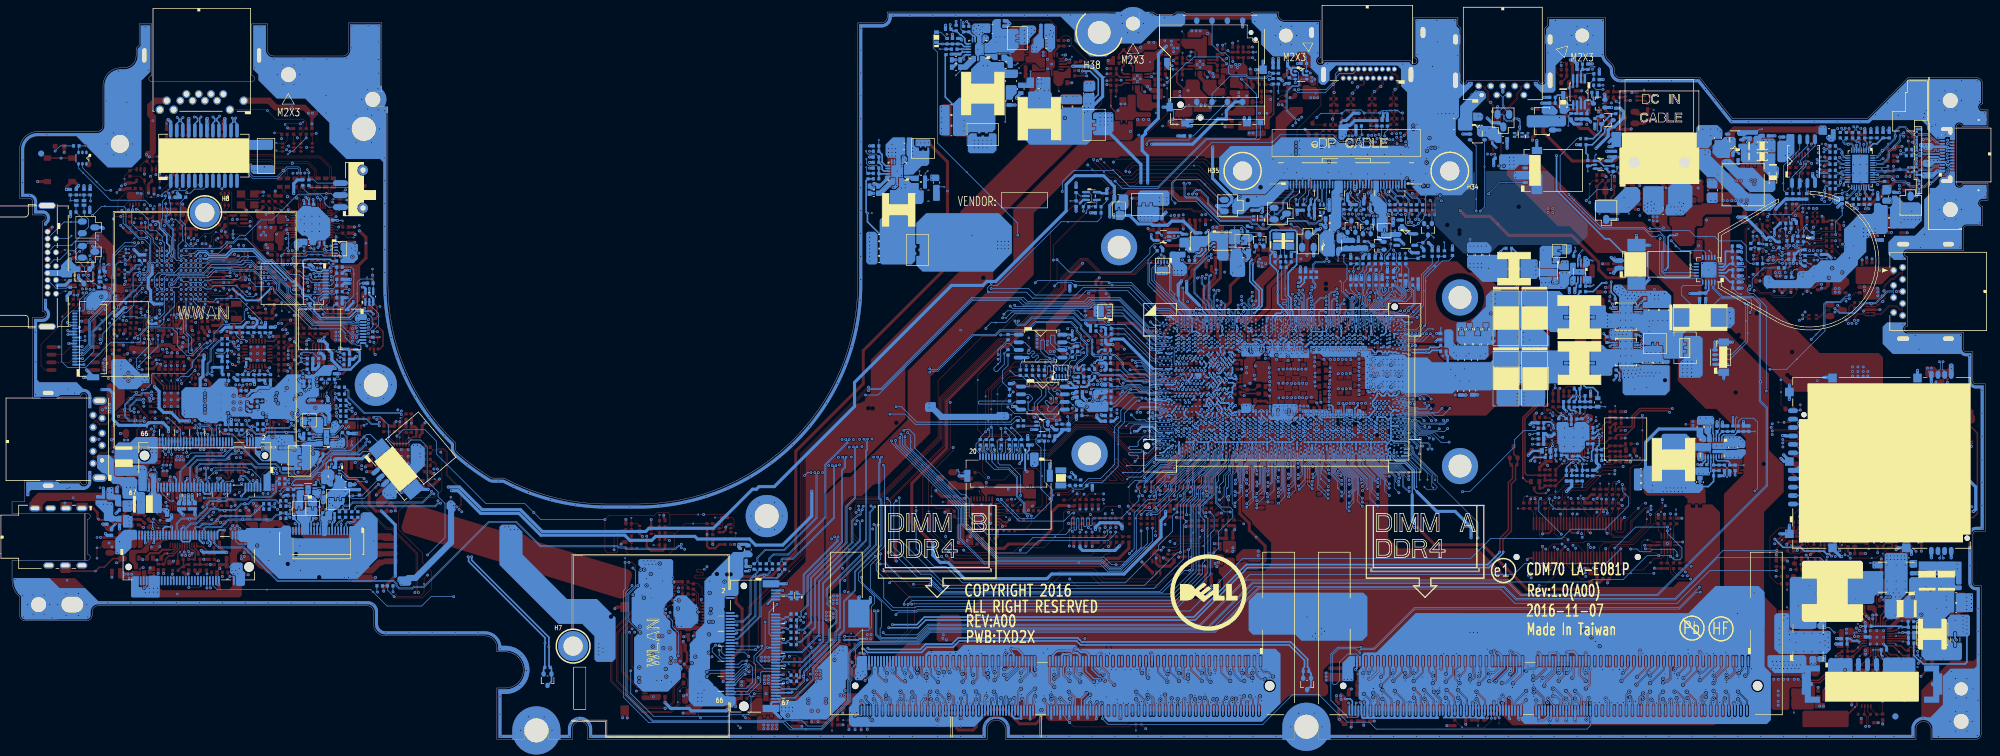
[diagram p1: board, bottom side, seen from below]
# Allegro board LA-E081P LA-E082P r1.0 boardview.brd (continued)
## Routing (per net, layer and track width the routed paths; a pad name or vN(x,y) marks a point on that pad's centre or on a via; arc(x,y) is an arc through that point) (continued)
N18762401: length 5.5
  TOP w0.203: 300.68,31.21 300.68,31.25 300.2,31.73 UA1.20
  TOP w0.254: 300.68,31.21 301.39,30.5 302.01,30.5 302.58,29.92 302.58,29.43 RA54.1 RA53.1
N18762411: length 2.4
  TOP w0.203: 303.55,37.73 303.55,37.65 303.02,37.12 UA1.35
  TOP w0.254: 303.55,37.73 304.17,38.35 CA29.1
N18762416: length 3.2
  TOP w0.203: 303.28,39.26 302.79,38.76 v1(302.33,38.76) 301.91,38.76 301.8,38.65 UA1.37
  TOP w0.254: CA29.2 304.11,40.09 303.28,39.26
N18762426:
  vias: v2(305.86,34.41)
N18762428: length 3.7
  TOP w0.203: UA1.34 302.99,36.72 303,36.73 303.13,36.73 v2(303.93,37.54) 304.52,38.13
  TOP w0.254: 304.52,38.13 304.98,38.13 305.44,38.59 CA49.1
N18762438: length 3.2
  TOP w0.203: UA1.19 299.8,31.52 v2(300.19,31.13) 300.55,30.77 CA25.1
N20151644: length 2.4
  TOP w0.127: v1(16.31,23.65) v2(16.31,24.3)
  TOP w0.254: PR909.1 16.38,23.2 16.38,23.56 16.31,23.63 v1(16.31,23.65)
  BOTTOM w0.254: v1(5.21,16.53) 5.45,16.77 PR901.2
N27076242: length 1.2
  TOP w0.102: PC930.1 v2(22.01,23.32)
N27077001: length 8.8
  TOP w0.254: PR937.2 24.51,14.34 24.8,14.34 v2(25.28,13.86) 25.28,12.59 28.06,9.81 29.47,9.81 29.7,10.04 PR917.2
N28424999: length 8.4
  BOTTOM w0.076: T113.1 91.79,43.86 95.36,47.43 95.36,47.73 95.5,47.87 95.5,48.44 95.8,48.73 96.72,48.73 UC1.AW71
N28425002: length 12.7
  BOTTOM w0.076: T114.1 93.1,41.46 91.81,41.46 91.48,41.79 91.48,42 92.16,42.68 92.16,43.99 95.53,47.36 95.53,47.66 95.67,47.8 95.67,48.37 95.86,48.57 96.27,48.57 96.3,48.53 97.3,48.53 UC1.AW70
N28489601: length 7.2
  BOTTOM w0.102: SW1.2 274.79,90.39 275.09,90.7 v3(275.85,90.7) 278.9,90.7 279.79,91.59 RC222.1
N28810563: length 1.9
  BOTTOM w0.203: UZ2.10 277.65,50.58 277.75,50.69 v2(277.86,50.69) 278.6,50.69 CZ110.1
N28811129: length 2.3
  TOP w0.203: UZ3.10 204.63,7.21 204.69,7.14 v2(205.06,7.14) 205.73,7.14 CZ114.1
N28856399: length 9.2
  BOTTOM w0.076: UC1.BA70 97.31,47.87 96.3,47.87 96.19,47.77 95.99,47.77 95.71,47.49 95.71,47.08 92.33,43.7 92.33,42.06 T16.1
N28856402: length 7.4
  BOTTOM w0.076: 95.94,46.37 96.15,46.59 97.95,46.59 98.29,46.93 98.29,47.3 98.12,47.48 UC1.BA68
  BOTTOM w0.102: T17.1 94.34,44.77 95.94,46.37
N28857231: length 7.7
  BOTTOM w0.076: 96.19,46.2 96.42,46.42 98.08,46.42 98.6,46.94 UC1.BB68
  BOTTOM w0.102: 96.19,46.2 94.9,44.9 94.9,41.97 T12.1
N28857234: length 7.1
  BOTTOM w0.076: T13.1 93.06,44.17 95.64,46.75 97.61,46.75 97.89,47.03 UC1.BB69
N28857237: length 1.8
  TOP w0.102: v1(129.6,54.64) 129.22,55.02 128.64,55.02 T14.1
  BOTTOM w0.102: UC1.AK13 129.85,54.39 v1(129.6,54.64)
N28857240: length 1.1
  TOP w0.102: v1(130.54,54.84) 130.34,54.84 T15.1
  BOTTOM w0.102: v1(130.54,54.84) 130.83,54.55 UC1.AK12
N28861827: length 14.2
  BOTTOM w0.076: UC1.C64 101.16,68.92 101.07,69.01 101.07,69.91 100.86,70.13 100.86,70.71 99.81,71.76 99.81,72.41 99.16,73.05 97.53,73.05 97.27,73.31
  BOTTOM w0.102: RC120.1 98.54,79 97.8,78.25 v2(97.8,78.06) 97.8,77.81 98.19,77.41 98.19,76.73 98.01,76.54 98.01,75.39 96.8,74.19 96.8,73.78 97.27,73.31
N28938912: length 1.3
  BOTTOM w0.102: RC29.2 151.14,64.38 CC8.1
N28938914: length 1.8
  BOTTOM w0.102: RC28.2 CC7.1 v2(149.47,53.8)
N29708559: length 8.9
  BOTTOM w0.076: 137.38,47.17 137.16,47.39 137.15,47.39 137.14,47.4 137.12,47.4 136.08,47.4 135.87,47.61 135.87,47.92 UC1.AY4
  BOTTOM w0.102: 137.38,47.17 138.17,47.17 139.88,45.46 T126.1
N29708561: length 8.4
  BOTTOM w0.102: T127.1 140.68,44.32 138.26,46.74 136.7,46.74 UC1.BB3
N29708599: length 9.9
  BOTTOM w0.076: UC1.AU5 135.22,50.62 135.22,51.08 135.39,51.25 137.61,51.25 137.97,51.61 137.97,51.87 138.4,52.29 141.79,52.29 142.31,51.77 T128.1
N29708601: length 9.5
  BOTTOM w0.076: T129.1 142.6,52.55 138.3,52.55 137.71,51.95 135.39,51.95 135.1,51.66 135.1,51.34 134.8,51.04 UC1.AT5
N29708639: length 9.6
  BOTTOM w0.102: UC1.BB5 135.2,47.09 135.53,46.75 135.75,46.75 136.25,46.25 137.64,46.25 138.42,45.47 138.7,45.47 140.59,43.58 142.58,43.58 T130.1
N30342894: length 2.6
  TOP w0.102: v2(112.11,99.51) 111.5,100.12 QV4.2 111.08,100.43 RV18.2
N32590572: length 2.2
  TOP w0.203: CZ117.1 194.76,17.21 v2(194,17.21) 193.86,17.21 193.57,16.93 UZ4.12
N32592963: length 3.5
  TOP w0.102: v2(195.27,14.75) 194.94,15.08 CZ118.1
  TOP w0.203: CZ118.1 193.68,16.02 193.57,16.13 UZ4.10
N32594166: length 4.1
  BOTTOM w0.102: CZ109.1 279.19,49.45 280.47,49.45 v2(280.57,49.55)
  BOTTOM w0.203: CZ109.1 278.47,49.68 277.58,49.68 277.47,49.78 UZ2.12
N32817808: length 4.6
  TOP w0.102: v2(207.98,7.79) 207.62,8.15 206.48,8.15 CZ113.1
  TOP w0.203: UZ3.12 204.5,8.01 204.64,8.15 205.62,8.15 CZ113.1
N32818355: length 1.3
  TOP w0.102: RZ65.2 200.39,8.98 v2(200.39,9.82)
N32819772: length 3.1
  TOP w0.102: CZ121.1 269.91,48.83 v2(269.25,48.83)
  TOP w0.254: UZ8.6 270.65,48.36 CZ121.1
N32875032: length 4.2
  BOTTOM w0.102: CZ130.1 281.72,41.9 283.01,41.9 v2(283.63,41.28)
  BOTTOM w0.254: UZ23.6 281.07,41.73 CZ130.1
N33199744: length 2.4
  TOP w0.102: T51.1 82.43,14.57 v1(82.5,14.5)
  BOTTOM w0.102: JDIMM1.165 82.28,14.24 82.54,14.51 82.48,14.51 82.48,14.5 v1(82.5,14.5)
N33298471: length 2
  TOP w0.102: v1(163.1,14.29) 163.24,14.43 T55.1
  BOTTOM w0.102: JDIMM2.165 163.28,14.11 v1(163.1,14.29)
N35551558:
  vias: v2(16.02,51.12)
N35551572: length 2.6
  TOP w0.254: v1(17.61,54.07) PQ1209.5 16.88,54.06 PC1214.1 ; PR1243.2 v1(66.61,102.12)
N35551576:
  vias: v2(19.69,55.9)
N35551584: length 4.3
  TOP w0.508: v1(69.7,104.77) 69.54,104.61 67.42,104.61
  BOTTOM w0.254: PU1201.7 67.57,106.38 v1(67.73,106.55) ; v1(66.37,104.53) 66.58,104.33 PC1213.1
  vias: v2(66.3,105.56)
N35551592: length 5.4
  BOTTOM w0.102: PR1237.2 69.24,103.94 69.67,103.51 v2(69.67,101.94)
  BOTTOM w0.254: PR1247.1 68.22,104.09 PU1201.6 ; PR1247.1 69.23,103.95 PR1237.2 ; PR1247.1 68.35,103.94 PC1212.1
N35551616: length 4.6
  TOP w0.102: PR1249.1 70.23,112.44 v2(70.89,112.44)
  TOP w0.254: PQ1212.2 69.92,110.01 PR1248.1 69.94,110.28 PR1250.1 69.98,111.26 PR1249.1
N35551696:
  vias: v2(6.77,50.73)
N35551783: length 1
  TOP w0.102: PC1203.2 v2(11.31,42.61)
N35551785: length 4.4
  TOP w0.102: v2(3.22,41.29) PR1209.1
  TOP w0.508: PR1209.1 3.25,40.14 PR1202.2 5.24,41.18 PQ1203.2
N35551806: length 2.6
  TOP w0.254: PQ1204.3 12.84,32.16 v2(12.3,31.62) v1(11.94,31.26) ; v1(2.66,38.64) PR1209.2
N36626863: length 1.2
  BOTTOM w0.102: v2(37.51,101.35) 37.94,101.35 RT111.2
N36827741:
  vias: v2(128.06,30.36)
N37776698: length 3.6
  TOP w0.102: UV7.56 96.99,97.86 96.02,97.86 95.76,98.11 95.76,98.87 v2(95.97,99.08) 96.02,99.13 CV96.1
N37776840: length 4.5
  TOP w0.102: UV7.9 100.41,91.55 v2(100.39,91.53) 100.39,91.03 100.16,90.8 100.16,89.73 100.27,89.62 100.27,89.12 RV97.1
N37894644: length 29.5
  TOP w0.102: v2(278.45,76.73) 278.71,76.73 278.84,76.85 279.46,76.85 RE348.1 279.6,76.74 RE536.1 279.6,77.83 280,78.24 281.18,78.24 281.52,77.9 281.52,77.51 281.76,77.27 282.59,77.27 283,77.68 UE7.3 284.53,78.14 283.95,78.71 RE34.2 RE537.2 283.95,80.64 284.33,81.02 285.26,81.02 285.48,81.23 286.86,81.23 288.09,82.46 288.09,86.52 288.93,87.37 290.91,87.37 291.57,88.03 291.57,90.76 291.9,91.09 293.11,91.09 293.39,90.81 QE13.1
N37894887: length 3.2
  TOP w0.102: CE5.1 280.14,78.67 280.27,78.54 281.13,78.54 v2(281.18,78.59) 281.74,78.03 281.74,77.78 281.84,77.68 UE7.4
N38798736: length 24.2
  TOP w0.076: 33.03,76.6 33.03,77.76 32.89,77.9 32.89,78.29 UT5.F10
  TOP w0.102: RT97.2 39.07,85.49 v2(39.76,84.8) 40.07,84.49 40.07,76.6 37.72,74.25 36.01,74.25 35.44,73.68 33.72,73.68 33.22,74.19 33.22,75.32 33.44,75.54 33.48,75.54 RT99.1 RT98.1 33.03,76.11 33.03,76.6
N38798744: length 3.4
  TOP w0.203: UT5.G4 31.72,81.96 v1(31.72,82.01)
  BOTTOM w0.102: v2(29.62,82.29) 29.98,82.65 RT85.1 30.62,82.28 30.8,82.1 31.63,82.1 v1(31.72,82.01)
N38798745: length 2.8
  TOP w0.076: UT5.F4 32.3,81.88 v1(32.3,82.01)
  BOTTOM w0.102: v2(31.4,81.62) 32.05,81.62 32.3,81.87 v1(32.3,82.01) 31.66,82.65 RT84.1
N38798858: length 7.6
  TOP w0.076: UT5.F1 32.64,83.93 32.57,84 32.57,84.38 32.79,84.6
  TOP w0.102: v2(33.03,89.87) 33.03,86.71 33.3,86.43 RT63.1 33.53,86.33 33.03,85.82 33.03,84.84 32.79,84.6
N38798904: length 3.5
  TOP w0.076: 29.46,77.69 30.05,78.29 30.39,78.29 UT5.K10
  TOP w0.102: RT105.1 29.15,76.7 v2(28.95,76.9) 29.15,77.11 29.15,77.38 29.46,77.69
N38798905: length 3.7
  TOP w0.076: v2(28.88,78.17) 29.13,78.17 29.74,78.79 30.39,78.79 UT5.K9
  TOP w0.102: RT104.1 27.87,77.3 28.75,78.17 v2(28.88,78.17)
N38798908: length 4.4
  TOP w0.102: RT103.1 29.61,75.61 29.61,74.35 v2(29.37,74.11)
  TOP w0.203: UT5.L11 29.86,77.75 29.86,77.56
  TOP w0.381: 29.86,77.56 29.86,76.22 RT103.1
N38798948: length 2.2
  BOTTOM w0.102: RT85.2 30.62,85.03 30.16,85.49 T220.1
N38798949: length 1.1
  BOTTOM w0.102: RT84.2 31.56,83.65 31.5,83.72 T219.1
N38799002: length 2.7
  TOP w0.076: v1(31.16,79.95) 31.24,80.04 UT5.H7
  BOTTOM w0.102: v2(29.39,78.99) 29.8,78.99 30.35,79.53 CT87.1 30.74,79.53 v1(31.16,79.95)
N38799008: length 2.5
  TOP w0.102: UT5.D6 33.94,80.54 v1(34.17,80.31)
  BOTTOM w0.102: v2(34.7,80.59) 34.42,80.31 v1(34.17,80.31) 33.84,80.64 RT101.1
N38802239: length 4.1
  BOTTOM w0.102: v2(104.02,80.85) 103.89,80.98 102.94,80.98 102.17,81.75 QV2.1
  BOTTOM w0.254: RV5.2 102.89,82.71 QV2.1
N38802260: length 29.4
  BOTTOM w0.102: QV7.1 121.29,84.22 122.81,84.22 RV6.1 122.94,84.48 123.82,85.36 127.46,85.36 131.46,89.37 134.44,89.37 135.31,90.24 135.31,92.42 134.75,92.98 130.82,92.98 v2(130.01,92.18) 127.46,89.63 QV8.2
N38804727: length 3.5
  BOTTOM w0.102: JEDP1.21 106.3,91.41 106.84,90.87 106.84,89 LV1.1
N39067212: length 3.8
  TOP w0.102: RE58.1 295.33,69.67 RE57.1 v2(295.58,70.53) 295.58,70.87 296.36,71.65 UE1.B1
N39067288: length 14
  TOP w0.102: v2(295.66,64.99) 295.78,64.87 RE318.1 296.6,65.32 296.88,65.6 v1(296.88,65.61)
  TOP w0.107: UE1.G2 300.74,72.34 300.74,70.78 v1(300.58,70.62)
  BOTTOM w0.102: v1(300.58,70.62) 299.62,69.66 299.62,67.59 298.75,66.71 298.75,64.25 298.58,64.09 298.14,64.09 296.88,65.35 v1(296.88,65.61)
N39067419: length 2.9
  TOP w0.102: RE349.2 307.13,73.64 v2(306.54,74.23) 306.13,74.64 305.58,74.64 305.26,74.33 UE1.N4
N39070459: length 3.6
  TOP w0.102: RE70.1 v2(278.45,73.68) ; RE70.1 279.58,73.04 279.39,72.85 QE11.3 ; RE70.1 RE90.2
N39070470: length 5
  TOP w0.102: RE70.2 280.61,73.57 QE4.2 282.2,73.04 282.44,72.8 282.51,72.8 282.86,72.46 282.86,71.79 v2(282.01,70.95)
N39154673: length 3
  TOP w0.102: UV6.10 276.69,51.81 RV123.2 v2(277.23,50.28)
N39154676: length 3.1
  TOP w0.102: UV6.9 276.29,51.44 RV124.2 276.12,51.06 v2(275.35,50.3)
N39468508: length 1.8
  TOP w0.102: PC647.2 v2(61.88,55.4)
  TOP w0.254: PR650.2 PC647.2
N39468570: length 1.9
  BOTTOM w0.102: v2(63.17,46.07) 63.45,46.35 PC629.2
  BOTTOM w0.203: PR639.1 64.14,46.38 PC629.2
N39469718: length 1.9
  TOP w0.102: v2(64.97,56.94) PR632.2
  TOP w0.254: PR632.2 65.97,56.08 PC627.1
N39469798: length 1.3
  BOTTOM w0.254: PU614.7 67.59,75.41 PR679.1
N39469812: length 2.4
  BOTTOM w0.254: PH602.1 68.33,57.88 v2(68.33,57.3) 68.33,56.46 PR628.2
N39469818: length 2
  BOTTOM w0.102: PR630.2 71.75,46.29 v2(71.65,46.18)
  BOTTOM w0.203: PC631.1 PR630.2
N39469908: length 3.2
  TOP w0.102: PC617.2 70.45,58.08 69.89,58.65 68.78,58.65 v2(68.66,58.53)
  TOP w0.254: PC617.2 70.45,57.01 PR621.1
N39470129: length 1.9
  BOTTOM w0.102: v2(67.36,41.95) PR646.2
  BOTTOM w0.203: PC640.1 67.36,42.91 PR646.2
N39470145: length 2.1
  BOTTOM w0.102: v2(64.39,43.79) PC601.1
  BOTTOM w0.203: PR652.2 65.61,43.78 PC601.1
N39470169: length 2.9
  TOP w0.102: v2(63.68,45.69) 62.31,45.69 61.88,46.12 PC630.2
  TOP w0.203: PC630.2 61.07,46.12 PR644.1
N39470173: length 0.9
  TOP w0.254: PC632.2 73.56,44.79 PR641.1
N39470189: length 4.3
  TOP w0.254: v1(72.97,41.42) 72.97,41.34 v2(73.43,40.88) 74.87,40.88 75.33,41.34 PR642.2
  BOTTOM w0.254: v1(80.9,81.04) 80.4,81.55 PH604.1
N39470248: length 0.9
  TOP w0.254: PR623.1 70.46,55.22 PC621.2
N39470270: length 5.1
  TOP w0.203: PR657.2 v1(58.21,49.1)
  BOTTOM w0.254: PH605.1 65.55,74.38 64.09,75.84 v2(63.94,75.84) v1(63.38,75.84)
N39470328: length 2.1
  BOTTOM w0.102: v2(66.49,53.96) 67.17,53.28 PC614.2
  BOTTOM w0.254: PR617.1 67.46,53.21 PC614.2
N39470375: length 3.8
  TOP w0.203: v1(70.57,53.82) 70.47,53.82 70.16,53.5 PU602.2
  BOTTOM w0.102: v1(70.57,53.82) v2(70.97,54.22)
  BOTTOM w0.254: PC613.2 v1(70.57,53.82) 71,53.82 71.25,53.56 PR613.2
N39470546: length 1.9
  TOP w0.102: PR645.1 v2(59.92,53.37)
  TOP w0.254: PC639.2 PR645.1
N39473183: length 6.9
  TOP w0.102: v1(58.33,47.06) 58.07,47.06 v2(57.79,46.78)
  TOP w0.203: PR661.1 58.7,47.43 v1(58.33,47.06)
  BOTTOM w0.254: v1(67.61,73.34) 67.61,70.38 67.35,70.12 PL610.3
N40543303: length 1.4
  TOP w0.102: UI5.7 304.9,55.16 RI36.2
N40543312: length 3.7
  TOP w0.102: v2(298.12,52.6) 298.12,53.26 RI35.2 297.77,53.84 299.08,55.16 UI5.24
N40719702: length 3.2
  TOP w0.102: RE350.2 286.95,78.38 287.48,78.9 287.48,79.49 287.28,79.69 286.35,79.69 CE57.1
N41288260: length 3.9
  TOP w0.102: RZ326.1 291.29,42.19 v2(291.24,42.25) 291.24,42.74 v1(291.45,42.95)
  BOTTOM w0.102: v1(291.45,42.95) 291.52,42.89 292.43,42.89 292.8,42.52 JNGFF2.17
N41303246: length 2.4
  BOTTOM w0.102: v2(117.8,107.33) RZ334.1 CZ38.2
N41840158: length 5.5
  TOP w0.102: RN183.1 RN192.2 210.77,34.93 QN4.5 210.25,35.07 210.06,35.26 210.06,36.71 RN182.2 v2(211.33,36.85)
N41840194: length 4.8
  TOP w0.102: QN5.2 224.21,34.82 RN184.2 RN185.1 RN186.2 v2(224.3,31.77)
N41840238: length 4.6
  TOP w0.102: QN5.5 221.06,34.82 RN189.2 RN187.2 RN188.1 v2(220.55,37.29)
N45131598: length 3.9
  TOP w0.102: RZ71.2 189.06,17.29 v2(188.74,17.61)
  TOP w0.203: RZ71.2 RZ70.2 189.66,15.77 189.81,15.91 190.22,15.91 190.44,16.13 UZ4.5
N45200928: length 3.4
  BOTTOM w0.102: JNGFF2.59 303.3,41.05 301.86,39.6 T225.1
N45242868: length 5.2
  BOTTOM w0.102: RE13.2 41.42,74 v2(40.96,74)
  BOTTOM w0.254: RE13.2 RE14.1 42.83,75.96 43.86,77 UE2.1
N45242870: length 5.3
  BOTTOM w0.102: RE16.1 41.86,76.47 v2(40.45,76.47)
  BOTTOM w0.254: RE16.1 RE15.2 42.99,78 43.49,77.5 UE2.2
N45242966: length 5.6
  BOTTOM w0.102: RE17.2 42.36,79.01 41.85,78.5 v2(40.39,78.5)
  BOTTOM w0.254: UE2.3 43.9,78 42.89,79.01 RE17.2 RE18.1
N45269008: length 2.8
  BOTTOM w0.102: JESPI.8 268.2,66.84 RE375.1 v2(267,66.81)
N45589397: length 7.6
  TOP w0.102: v1(301.35,90.9) 300.79,91.46 v2(300.25,91.46) 299.01,92.69 CL17.1
  BOTTOM w0.102: TL1.4 298.71,91.71 299.23,91.18 301.06,91.18 v1(301.35,90.9)
N45589399: length 6.3
  TOP w0.102: v1(303.16,90.28) 303.16,91.16 CL16.1
  BOTTOM w0.102: TL1.1 301.71,91.61 302.37,90.94 302.7,90.94 303.16,90.49 v1(303.16,90.28)
N45589425: length 8.8
  TOP w0.102: CL20.1 296.53,92.69 v2(297.07,92.14) 298.41,90.81 v1(299.05,90.81)
  BOTTOM w0.102: TL1.7 295.71,91.92 296.23,91.4 297.76,91.4 298.46,90.7 298.94,90.7 v1(299.05,90.81)
N45589439: length 3.1
  TOP w0.102: CL21.1 v2(292.74,91.79) 293.08,91.45 v1(293.22,91.45)
  BOTTOM w0.102: v1(293.22,91.45) 292.71,91.97 TL1.10
N45863109: length 2.1
  TOP w0.102: CD31.2 v2(84.66,2.3)
  TOP w0.508: RD18.1 CD31.2
N45863346: length 2.3
  TOP w0.102: T50.1 v1(81.16,3.6)
  BOTTOM w0.102: JDIMM1.162 81.53,3.97 v1(81.16,3.6)
N45879530: length 7.6
  TOP w0.102: T54.1 167.02,4.78 165.99,5.81 163.14,5.81 v1(162.36,6.6)
  BOTTOM w0.102: v1(162.36,6.6) 162.53,6.43 JDIMM2.162
N45879727: length 2.1
  TOP w0.102: v2(174.2,2.82) 173.61,2.82 RD31.1
  TOP w0.508: CD62.2 RD31.1
N45886539: length 4.9
  TOP w0.076: UT5.D1 33.64,83.17 33.85,83.38 33.85,84.09 34.12,84.36
  TOP w0.102: 34.12,84.36 34.17,84.41 34.37,84.41 v2(34.47,84.51) 34.47,84.83 34.32,84.98 34.32,87.18 RT378.1
N45886541: length 4.7
  TOP w0.076: UT5.D2 33.89,82.79 33.89,83.17 34.03,83.3 34.03,83.95 34.25,84.18
  TOP w0.102: 34.25,84.18 34.64,84.18 34.8,84.35 34.8,85.39 RT379.1 35.17,85.81 v2(35.7,85.81)
N45912878: length 1.7
  BOTTOM w0.102: PC119.1 170.63,111.03 v2(171.38,110.28)
N45957243: length 2.7
  TOP w0.203: PU901.29 18.65,13.73 v2(18.66,13.71) 18.66,12.82 PR949.1
N45957346: length 3.5
  TOP w0.203: PR948.1 PR936.1 19.05,12.45 PU901.30
N45971013: length 7.2
  BOTTOM w0.254: PR28.1 62.42,103.91 PQ8.3 64.22,102.11 64.22,101.11 v2(65.55,99.78) 66.73,99.78 PR26.2
N45971015: length 9.3
  BOTTOM w0.254: PQ8.1 63.63,101.45 63.63,100.82 65.69,98.76 PR27.1 66.73,97.38 v2(66.71,97.35) 66.43,97.07 PR22.1
N45971023: length 3.6
  BOTTOM w0.102: v2(64.81,101.1) 64.81,102.82 64.9,102.91 65.07,102.91 PR29.2
  BOTTOM w0.254: PQ8.2 64.87,103.5 PR29.2
N45972642: length 2.4
  TOP w0.102: v2(23.2,30.5) 22.48,30.5 PR1225.1
  TOP w0.254: PQ1205.2 22.12,30.89 PR1225.1
N45972646: length 5.4
  TOP w0.102: v2(19.8,31.6) 19.8,32.26 PQ1205.1
  TOP w0.254: PQ1205.1 20.23,32.66 22.74,32.66 23.02,32.94 PR1226.2 PR1215.1
N45972650: length 4.1
  TOP w0.102: PR1224.1 22.76,35.86 v2(22.76,37.11)
  TOP w0.254: PR1224.1 22.23,34.46 PR1221.2 22.12,34.3 PQ1205.3
N45973945: length 3.4
  TOP w0.102: PR1259.1 v2(26.55,39.21)
  TOP w0.254: PQ1208.2 27.13,37.66 PR1259.1 26.48,38.18 PQ1208.3
N45973953: length 10.9
  TOP w0.102: v1(23.73,30.67) 23.73,34.64 24.16,35.07 PR1260.2 PR1261.1 25.91,35.58 25.91,36.16 26.12,36.37 26.87,36.37 27.13,36.1 PQ1208.5 ; v1(63.91,108.65) v2(64.79,108.65)
  BOTTOM w0.102: PR1244.2 v1(63.91,108.65)
N45973980: length 6.4
  TOP w0.102: PR1234.1 24.61,36.89 v2(24.5,37)
  TOP w0.254: PQ1211.1 27.78,34.19 PQ1208.6 27.78,35.99 27.13,36.64 26.14,36.64 25.9,36.89 PR1234.1 25.48,36.55 25.41,36.47 PR1261.2
N45974004: length 3.8
  TOP w0.102: v2(26.8,29.82) 26.8,29.9 28,31.09 PR1233.1
  TOP w0.254: PQ1211.5 27.13,31.31 PR1242.2 PR1233.1
N45974006: length 5.5
  TOP w0.102: PR1257.2 24.26,34.18 24.08,34 24.08,32.44 v2(24.25,32.28)
  TOP w0.254: PR1257.2 PR1235.1 25.53,34.18 26.09,34.74 26.82,34.74 27.13,34.42 PQ1211.2
N45974105: length 19.6
  TOP w0.254: PQ1211.4 26.48,32.15 26.17,31.83 25.86,31.83 PR1230.1 25.28,31.13 v1(25.98,30.43) ; v1(35.39,33.28) 34.72,33.28 v2(33.46,34.54) 33.36,34.64 31.78,34.64 31.36,35.06 PR1258.2 30.77,35.2 PQ1207.6
  BOTTOM w0.254: v1(25.98,30.43) 26.36,30.82 26.8,30.82 27.27,31.29 30.45,31.29 31.06,31.9 34,31.9 v1(35.39,33.28)
N45974290: length 2.6
  TOP w0.102: v2(28.78,38.51) 28.84,38.46 PR1232.1
  TOP w0.254: PQ1207.2 PQ1207.3 28.98,37.05 28.84,37.2 PR1232.1
N45981582: length 4.3
  TOP w0.203: PR951.2 15.52,12.36 PR933.2 15.54,12.78 v2(16.12,13.37) 16.28,13.37 17.45,14.54 PU901.26
N46029111: length 6
  TOP w0.102: v2(68.07,112.31) PR1219.1
  TOP w0.254: PR1219.1 68.07,110.41 PC1206.1 ; PC1206.1 68.1,110.36 PR1203.1 68.1,108.61 v1(68.22,108.48) ; PC1206.1 67.2,110.4 PR1201.2
  BOTTOM w0.254: PU1201.3 v1(68.22,108.48)
N46029167: length 4.7
  BOTTOM w0.102: PR1208.2 65.98,111.7 65.33,111.7 v2(65.33,111.7)
  BOTTOM w0.254: PC1205.1 67.57,111.04 PU1201.2 ; PC1205.1 66.43,111.28 PR1208.2 ; PC1205.1 67.32,111.28 PR1217.1
N46142452: length 3.2
  TOP w0.102: v2(17.63,32.76) 17.25,33.14 16.44,33.14 16.24,33.34 PR1216.2
  TOP w0.254: PR1216.2 15.6,34.28 PQ1201.2
N46142922: length 2.3
  TOP w0.102: v2(18.1,33.97) 17.77,33.63 PR1216.1
  TOP w0.254: PR1216.1 17.49,33.98 PU1200.4
N46144380: length 2.4
  TOP w0.102: PR1252.2 11.87,38.44 v2(11.68,38.64)
  TOP w0.254: PR1252.2 11.39,37.21 PQ1214.6
N46177388: length 3.3
  TOP w0.381: PR16.2 v2(63.61,101.31) 64.58,102.29 PQ7.1
N46177446: length 2.6
  TOP w0.102: PR18.2 55.88,93.5 v2(56.56,94.18)
  TOP w0.254: PR18.2 56.34,92.8 PQ6.1
N46177523: length 2.2
  TOP w0.102: PQ1209.6 16.89,52.49 v2(17.05,52.33)
  TOP w0.254: PQ1209.6 16.14,53.42 PR1229.2
N46178128: length 5.3
  TOP w0.254: PR1212.2 2.72,48.67 v1(2.74,48.66) ; v1(14.22,40.82) v2(14.22,38.62) 14.23,38.62 14.49,38.36 14.49,37.35 14.95,36.89 PQ1201.6
N46178191: length 9.4
  TOP w0.254: PR1213.2 12.6,39.74 v2(12.88,39.47) 12.88,39.39 14.13,38.13 14.13,36.31 14.48,35.96 15.37,35.96 16.25,35.09 PQ1201.3
N46204184:
  vias: v2(183.22,91.74)
N46204205: length 2
  BOTTOM w0.102: v2(186.21,95.01) 186.21,94.29 PC307.2
  BOTTOM w0.254: PR308.1 185.07,94.01 PC307.2
N46260620: length 1.8
  TOP w0.102: v2(16.37,9.68) PC944.1
  TOP w0.203: PR934.2 16.4,10.66 PC944.1
N46425689: length 2.2
  TOP w0.102: v2(19.83,38.11) 19.45,37.73 PR1211.2
  TOP w0.254: PR1211.2 18.79,37.58 PU1200.1
N46425853: length 14.5
  TOP w0.102: PU1200.2 18.14,36.36 18.55,35.96 19.33,35.96 20.25,36.88 v2(20.25,39.69) 20.96,40.4 22.99,40.4 23.25,40.15 PR1215.2
N46425954: length 3.5
  TOP w0.102: PR1220.1 14.81,37.97 14.81,39.64 v2(14.88,39.71)
  TOP w0.254: PQ1201.5 15.6,36.88 15.24,37.23 PR1220.1
N46426354: length 3.4
  TOP w0.102: v2(31.36,37.04) PR1241.2
  TOP w0.254: PR1241.2 30.74,36.09 29.63,34.98 PQ1207.5
N46426548: length 4.4
  TOP w0.102: PR1245.2 29.96,31.92 30.32,32.28 30.32,32.76 30.55,32.99 PQ1210.5 30.86,32.99 31.63,32.23 v2(32.69,32.23)
N46427561: length 4.5
  BOTTOM w0.102: PU1.1 65.25,96.97 v2(65.09,97.13)
  BOTTOM w0.254: PU1.1 64.63,96.09 63.8,95.26 PR21.2
N46427605: length 2.2
  BOTTOM w0.102: v2(66.43,94.34) PR22.2
  BOTTOM w0.254: PR22.2 65.96,95.24 65.76,95.44 PU1.2
N46427645: length 2.4
  TOP w0.102: v2(60.33,91.6) PR23.1
  TOP w0.254: PQ6.2 59.98,92.15 PR23.1
N46428671: length 3.7
  TOP w0.203: PU602.1 70.56,53.18 71.13,53.74 71.62,53.74 v2(72.19,54.3) 72.6,54.72 PR620.2
N46430626: length 2.1
  TOP w0.102: PD905.2 33.32,25.81 PR941.2 v2(33.35,24.87)
N46430682: length 2
  TOP w0.102: PU903.2 30.87,28.25 PR942.2 31.12,28.41 v2(31.12,29.08)
N46447690: length 3.2
  TOP w0.102: v2(269.12,76.71) RZ25.1 269.12,75.46 269.55,75.02 269.55,74.97 269.58,74.94 QZ3.1
N46932507: length 2.4
  TOP w0.102: v2(18.86,93.93) 18.69,93.76 v1(18.29,93.76) 18.04,93.5 RT380.2
  BOTTOM w0.102: v1(18.29,93.76) UT9.32
N47045001: length 2
  TOP w0.102: RZ63.1 CZ56.1 161.05,38.49 v2(160.6,38.94)
N47045031: length 4
  TOP w0.102: v2(165.97,32.38) 166.95,33.36 RZ362.2 RZ112.2 167.84,33.8 167.32,34.31 UZ12.29
N47045035: length 3.2
  TOP w0.102: UZ12.27 166.32,33.93 RZ62.1 164.77,32.38 v2(164.7,32.38)
N47045174: length 2.8
  TOP w0.102: QZ9.2 v2(170.08,44.35) 169.11,44.35 RZ113.2
N47046012: length 4.5
  TOP w0.102: RZ131.2 298.46,48.29 v2(298.47,48.28) 299.13,48.28 299.39,48.54 299.91,48.54 v1(300.31,48.14)
  BOTTOM w0.102: v1(300.31,48.14) 300.31,48.51 300.55,48.75 JNGFF2.48
N47046031: length 3.4
  TOP w0.102: v1(300.89,48.16) 300.89,48.28 v2(300.57,48.6) 300.28,48.89 299.74,48.89 RZ132.2
  BOTTOM w0.102: JNGFF2.50 301.05,48.32 v1(300.89,48.16)
N47298137: length 2.3
  TOP w0.102: v2(286.26,72.03) 286.52,71.77 RE94.1 287.2,72.93 QE12.1
N49127672: length 3
  TOP w0.102: QE13.6 293.39,89.13 293.29,89.24 292.37,89.24 292.09,89.52 QE13.3
N132000604: length 1.3
  TOP w0.102: PR921.2 v2(25.53,17.81)
N132005053: length 8.7
  TOP w0.254: PR917.3 29.7,9.21 29.47,9.44 27.86,9.44 v2(26.75,10.55) 24.9,12.4 24.9,13.71 24.64,13.96 24.42,13.96 PR938.2
N379222690: length 1.4
  TOP w0.102: T224.1 102.01,91.68 UV7.13
N379222980: length 1.7
  TOP w0.102: UV7.6 99.21,92.11 99.14,92.04 T223.1
N3792239420: length 3.1
  TOP w0.102: T204.1 99.95,90.29 99.95,92.92 UV7.8
N4919186218: length 3.7
  TOP w0.203: PU901.27 17.85,14.16 v1(17.52,13.83)
  BOTTOM w0.102: v2(19.12,14.88) PR932.1
  BOTTOM w0.254: v1(17.52,13.83) 17.73,14.05 PR932.1

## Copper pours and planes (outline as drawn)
2.5VSP on TOP (solid shape): 192.16,8.83 192.16,8.31 192.19,8.28 192.59,8.28 192.63,8.32 192.63,8.8 192.67,8.84 192.97,8.84 193.09,8.72 193.09,7.78 193.06,7.75 193.06,7.72 192.55,7.21 192.55,5.36 192.84,5.07 193.62,5.07 193.73,4.97 193.73,4.71 193.59,4.57 192.38,4.57 191.63,5.32 191.63,8.68 191.79,8.85 192.14,8.85
3V_SN on BOTTOM (solid shape): 159.62,109.72 159.62,109.11 159.67,109.06 160.99,109.06 161.04,109.01 161.04,108.32 160.91,108.2 158.45,108.2 158.37,108.27 158.37,109.87 158.42,109.92 159.42,109.92
3V_VIN on TOP (solid shape): 157.71,117.87 157.71,117.32 158.82,116.21 158.82,115.93 158.81,115.92 158.81,115.54 159.12,115.22 159.76,115.22 159.81,115.18 159.81,114.83 159.78,114.8 159.25,114.8 159.25,114.25 159.8,114.24 159.81,114.23 159.81,114.02 159.8,114.01 159.26,114.01 159.26,114 159.26,113.45 159.79,113.45 159.81,113.42 159.81,112.57 159.64,112.39 158.2,112.39 157.38,111.57 156.6,111.57 156.55,111.63 156.55,113.12 156.62,113.2 157.03,113.2 157.24,113.42 157.24,114.38 156.75,114.88 156.75,116.32 156.9,116.48 156.9,117.92 157,118.03 157.56,118.03
3V_VIN on BOTTOM (solid shape): 157.52,118.77 157.52,117.32 157.52,117.32 157.52,117.28 158.46,116.34 158.46,115.61 158.83,115.25 158.83,114.19 158.68,114.04 157.79,114.04 156.93,114.9 156.82,114.9 156.8,114.93 156.8,116.35 156.94,116.49 156.94,118.75 157.06,118.88 157.41,118.88
5V_SN on BOTTOM (solid shape): 163.07,108.54 163.07,106.44 162.88,106.25 162.06,106.25 161.87,106.44 161.87,106.7 161.23,107.33 161.23,108.48 161.42,108.67 162.95,108.67
5V_VIN on TOP (solid shape): 164.9,116.4 164.88,116.38 163.1,116.38 162.86,116.61 162.86,117.84 162.95,117.92 163.61,117.92 163.99,118.31 163.99,118.94 164.04,118.99 164.9,118.99
5V_VIN on BOTTOM (solid shape): 165.36,119.15 165.36,116.4 166.1,115.66 166.5,115.66 166.6,115.56 166.6,114.11 166.5,114.01 164.69,114.01 164.61,114.09 162.44,114.09 162.37,114.02 162.3,114.03 162.24,114.02 161.85,114.02 160.94,114.93 160.94,115.76 160.95,115.77 161.47,115.77 161.49,115.79 161.49,116.28 161.46,116.3 160.95,116.3 160.93,116.32 160.93,116.57 160.94,116.57 161.45,116.57 161.49,116.61 161.49,117.06 161.45,117.1 160.96,117.1 160.93,117.13 160.93,117.76 161.17,118 163.68,118 163.91,118.23 163.91,119.56 163.97,119.63 164.88,119.63
+0.6V_DDR_VTT on TOP (solid shape): 190.72,7.49 190.72,5.86 190.55,5.69 186.97,5.69 186.68,5.98 186.68,7.26 187.07,7.65 190.56,7.65
+0.6V_DDR_VTT on TOP (solid shape): 49.48,52.96 49.48,51.62 49.33,51.47 48.3,51.47 48.25,51.52 48.25,51.95 48.23,51.97 47.72,51.97 47.69,52 47.69,52.12 47.75,52.18 48.23,52.18 48.23,52.69 48.22,52.69 48.22,52.93 48.4,53.11 49.34,53.11
+0.6V_DDR_VTT on TOP (solid shape): 107.73,7.58 107.73,6.69 107.5,6.45 107.4,6.45 107.4,6.35 107.31,6.26 107.31,3.58 107.2,3.47 106.33,3.47 106.22,3.58 106.22,5.71 106.25,5.72 106.51,6.07 106.24,6.41 106.21,6.42 106.21,6.71 106.49,6.99 106.57,6.99 106.57,7.07 107.23,7.73 107.59,7.73
+0.6VSP on TOP (solid shape): 48.1,52.59 48.1,52.31 47.56,52.31 47.56,52.31 47.56,51.82 48.09,51.82 48.1,51.82 48.1,51.53 48.03,51.46 46.02,51.46 45.84,51.64 45.84,52.41 46.03,52.61 48.09,52.61
+0.6VSP on BOTTOM (solid shape): 47.09,52.06 47.09,50.96 46.6,50.47 46.6,49.5 46.49,49.38 45.95,49.38 45.88,49.46 45.88,50.62 46.05,50.79 46.05,51.17 45.96,51.26 45.96,52.1 45.99,52.13 47.03,52.13
+0.9V_LAN on TOP (solid shape): 285.18,87.75 285.18,87.75 285.3,87.72 285.41,87.73 285.44,87.74 285.66,87.51 287.27,87.51 287.37,87.46 287.47,87.44 287.49,87.44 287.56,87.38 287.56,86.73 287.15,86.33 285.73,86.33 285.7,86.3 285.65,86.3 285.65,86.25 285.6,86.2 285.6,85.74 285.42,85.56 284.57,85.56 284.36,85.77 284.36,87.44 284.52,87.61 284.54,87.61 284.66,87.66 284.78,87.74 284.79,87.75
+0.9V_LAN on TOP (solid shape): 280.2,83.14 280.2,82.14 280.34,82 280.4,82 280.46,81.99 280.56,82.01 280.63,82.06 280.67,82.14 280.8,82.14 281.07,82.14 281.24,81.96 281.24,81.49 280.91,81.15 280.58,81.15 280.47,81.26 280.47,81.53 280.3,81.71 280.29,81.71 280.25,81.75 280.02,81.75 279.94,81.83 279.93,81.9 279.91,81.93 279.8,82.05 279.66,82.12 279.61,82.12 279.61,82.64 279.58,82.79 279.49,82.91 279.49,83.16 279.55,83.22 280.12,83.22
+0.9V_LAN on BOTTOM (solid shape): 281.26,82.62 281.26,81.76 280.73,81.22 280.57,81.22 280.5,81.26 280.47,81.34 280.36,81.65 280.04,81.74 279.96,81.75 279.92,81.82 279.67,82.11 279.31,82.01 279.15,82.01 279,82.16 279,83.03 279.13,83.15 280.73,83.15
+1.0V_AMPHYPLL on TOP (solid shape): 147.47,72.58 147.47,71.63 147.69,71.42 147.69,71.29 147.68,71.17 147.72,71.06 147.72,71.05 147.72,70.77 147.72,70.76 147.68,70.6 147.72,70.45 147.72,70.44 147.72,69.07 147.47,68.82 147.32,68.82 147.25,68.83 147.18,68.82 146.85,68.82 146.4,69.27 146.41,69.3 146.31,69.61 145.99,69.71 145.96,69.71 145.04,70.63 145.04,72.33 145.29,72.59 145.81,72.59 145.83,72.6 147.45,72.6
+1.0V_APLL on TOP (solid shape): outline of 163 points within 129.52,59.46 134.9,61.09
+1.0V_APLLEBB on TOP (solid shape): 147.71,74.69 147.71,74.07 147.56,73.93 147.56,72.9 147.45,72.79 145.93,72.79 145.67,73.04 145.67,73.93 146.69,74.95 147.45,74.95
+1.0V_CLK2 on TOP (solid shape): 127.6,80.73 127.6,79.54 127.5,79.44 125.45,79.44 125.12,79.77 125.12,80.51 125.14,80.52 125.71,80.52 125.76,80.58 125.76,80.72 125.96,80.92 127.41,80.92
+1.0V_CLK2 on TOP (solid shape): outline of 89 points within 126.47,63.64 128.17,67.76
+1.0V_CLK4 on BOTTOM (solid shape): 124.94,81.49 125.29,81.49 125.72,81.06 125.72,80.07 125.86,79.93 125.86,77.29 125.39,76.82 123.56,76.82 123.32,77.06 123.32,78.68 123.36,78.72 123.36,79.2 123.55,79.47 123.45,79.77 123.38,79.84 123.7,80.16 123.7,80.74 123.86,80.91 123.96,81.07 123.95,81.26 123.95,81.29 124.21,81.55 124.88,81.55
+1.0V_CLK5 on TOP (solid shape): 136.18,84.92 136.89,84.92 137.04,84.77 137.04,84.04 136.81,83.71 137.04,83.38 137.04,83.2 136.82,82.99 135.13,82.99 134.88,83.24 134.88,83.77 134.63,84.03 134.37,84.03 134.31,84.09 134.31,84.92 134.37,84.98 136.12,84.98
+1.0V_MPHYAON on TOP (solid shape): outline of 725 points within 129.19,63.75 138.17,78.66
+1.0V_MPHYAON on BOTTOM (solid shape): 135.9,80.79 135.9,79.2 135.35,78.66 135.35,77.2 135.13,76.98 133.48,76.98 132.97,77.49 132.97,78.61 133.63,79.27 133.99,79.27 134.12,79.39 134.12,79.9 133.99,80.03 133.36,80.03 133.23,80.16 133.23,80.92 133.29,80.98 134.88,80.98 134.94,81.04 135.64,81.04
+1.0V_MPHYGT on TOP (solid shape): 120.66,80.03 120.76,80.03 120.76,80.01 121.18,80.01 121.42,79.77 121.42,78.63 121.04,78.25 120.02,78.25 119.39,78.89 119.39,80.03 119.64,80.28 120.4,80.28
+1.0V_MPHYGT on TOP (solid shape): 149.08,73.83 149.4,73.74 149.66,73.95 149.67,73.98 151.57,73.98 156.41,69.15 156.41,64.39 156.1,64.08 154.84,64.08 154.69,64.23 154.69,67.71 154.72,67.74 154.7,67.75 154.7,68.31 151.44,71.57 148.38,71.57 148.19,71.76 148.19,72.68 148.26,72.76 148.26,73.92 148.32,73.98 148.93,73.98
+1.0V_MPHYGT on TOP (solid shape): 128.02,63.38 128.11,63.33 128.1,63.22 128.36,62.69 128.62,63.22 128.61,63.33 128.7,63.38 129.16,63.38 129.33,63.22 129.33,62.38 129.28,62.21 129.31,62.04 129.31,61.94 129.22,61.89 128.69,61.89 128.63,61.83 128.08,61.83 128.08,62.05 128.03,62.09 128.04,62.12 127.95,62.41 127.65,62.51 127.62,62.5 127.43,62.69 127.43,63.12 127.69,63.38
+1.0V_MPHYGT on BOTTOM (solid shape): 141.11,90.73 141.11,88.67 141.08,88.64 140.56,88.64 140.55,88.66 140.55,89.16 140.51,89.19 139.83,89.19 139.81,89.17 139.81,88.66 139.79,88.64 139.37,88.64 139.34,88.67 139.34,89.16 139.33,89.17 139.33,89.18 139.32,89.18 139.31,89.19 138.64,89.19 138.62,89.17 138.62,88.67 138.58,88.63 137.95,88.63 137.95,88.61 136.19,88.61 135.89,88.91 135.89,90.8 136.25,91.16 140.68,91.16
+1.0V_PRIM on BOTTOM (solid shape): 177.93,85.74 177.93,82.29 177.37,82.29 177.37,80.31 177.93,80.31 177.93,78.74 176.88,77.69 165.15,77.69 162.06,80.79 162.06,85.24 164.22,87.39 176.28,87.39
+1.0V_PRIM on BOTTOM (solid shape): 140.42,88.6 140.43,88.6 140.43,88.53 140.5,88.53 140.51,88.51 141.13,88.51 141.14,88.52 141.23,88.43 141.23,86.39 140.82,85.97 138.8,85.97 138.79,85.97 137.95,85.97 137.56,86.36 137.56,88.28 137.77,88.49 138.62,88.49 138.66,88.53 138.73,88.53 138.73,88.6 138.75,88.61 138.75,89.06 139.17,89.06 139.21,89.02 139.21,88.61 139.22,88.61 139.22,88.55 139.23,88.53 139.3,88.53 139.32,88.51 139.84,88.51 139.86,88.53 139.93,88.53 139.93,88.6 139.94,88.61 139.95,88.63 139.95,89.07 140.42,89.07
+1.0V_PRIM on BOTTOM (solid shape): 126.7,84.47 126.77,84.44 126.8,84.36 127.15,83.98 127.51,84.36 127.54,84.44 127.61,84.47 128.91,84.47 129.8,83.58 132.47,83.58 132.72,83.33 134.05,83.33 134.24,83.14 134.24,81.79 134.19,81.74 133.29,81.74 133.14,81.59 133.14,81.28 132.72,80.85 131.71,80.85 131.51,81.07 131.21,81.06 131.11,81.14 130.99,81.17 130.94,81.18 130.94,81.55 130.69,81.81 129.82,81.81 128.86,82.76 128.2,82.76 128.02,82.58 128.02,79.9 127.64,79.52 126.37,79.52 126.11,79.78 126.11,81.3 126.17,81.35 126.17,84.37 126.27,84.47
+1.0V_PRIM_CORE on TOP (solid shape): 134.05,103.26 134.05,102.72 134.6,102.72 134.61,102.73 134.61,103.26 135.64,103.26 136.26,102.64 136.26,102.03 135.64,101.4 133.06,101.4 132.6,101.86 132.6,102.96 132.9,103.26 133.24,103.26 133.25,103.25 133.25,102.72 133.26,102.71 133.8,102.71 133.8,102.72 133.8,103.26 134.04,103.26
+1.0V_PRIM_COREP on TOP (solid shape): 133.2,109.38 133.2,108.5 133.73,107.97 133.73,106.52 133.58,106.37 133.58,106.37 133.33,106.11 133.33,105.75 133.32,105.74 133.25,105.4 133.32,105.06 133.33,105.05 133.33,104.95 133.75,104.53 134.75,104.53 134.96,104.33 134.96,103.44 134.93,103.42 134.41,103.42 134.4,103.41 134.4,102.87 134.18,102.87 134.18,103.39 134.16,103.39 134.16,103.41 132.45,103.41 132.06,103.8 132.06,105.07 131.39,105.75 131.29,105.75 131.29,105.75 130.99,105.75 130.97,105.76 129.69,105.76 129.57,105.89 129.57,106.72 130.84,107.99 130.84,109.2 131.25,109.6 132.98,109.6
+1.0V_SRAM on TOP (solid shape): 120.66,81.46 120.66,81.14 120.47,80.95 119.59,80.95 119.45,80.81 119.45,80.27 119.26,80.08 119.26,80.05 119.24,80.03 119.24,78.63 121.73,76.13 121.73,72.87 121.83,72.77 121.83,72.75 121.93,72.57 122.11,72.48 122.12,72.47 122.21,72.39 122.21,71.9 122.13,71.81 122.03,71.81 122.01,71.82 121.79,71.9 121.56,71.81 121.02,71.81 120.25,72.58 120.25,75.26 118.15,77.36 118.12,77.44 118.16,77.51 118.16,78.05 117.62,77.97 117.59,77.95 117.55,77.96 117.51,78 117.51,80.11 118.03,80.63 118.04,80.64 118.06,80.64 118.1,80.63 118.6,80.63 118.6,81.13 118.59,81.17 118.59,81.19 118.6,81.2 119.1,81.71 120.42,81.71
+1.0V_VCCST on BOTTOM (solid shape): 123.4,83.96 124.05,83.32 124.05,83.01 124.04,83 123.49,83 123.47,82.98 123.47,82.54 123.5,82.52 124.03,82.52 124.05,82.5 124.05,82.2 123.94,82.1 123.13,82.1 123.05,82.13 123.03,82.22 122.87,82.59 122.46,82.57 122.05,82.98 122.05,83.71 122.31,83.97 122.53,83.97
+1.0V_VCCST_C on BOTTOM (solid shape): 126.02,84.44 126.02,84.41 126.01,84.33 126.03,84.23 126.03,82.29 125.98,82.23 125.11,82.23 124.84,82.36 124.57,82.23 124.21,82.23 124.19,82.26 124.19,82.62 124.15,82.65 123.64,82.65 123.61,82.69 123.61,82.83 123.64,82.86 124.15,82.86 124.17,82.89 124.17,82.95 124.18,82.95 124.18,83.37 124.17,83.38 124.08,83.47 124.08,84.47 124.34,84.73 125.74,84.73
+1.0V_VCCSTG on TOP (solid shape): 144.73,89.35 144.73,88.61 144.48,88.36 142.83,88.36 142.47,88.71 142.47,89.5 142.65,89.68 144.4,89.68
+1.0V_VCCSTG on TOP (solid shape): 114.81,80.18 114.81,79.65 114.46,79.29 112.86,79.29 112.32,79.82 112.32,80.84 112.53,81.04 113.95,81.04
+1.0V_VCCSTG on TOP (solid shape): 124.95,70.34 124.95,69.3 124.83,69.17 121.57,69.17 121.32,69.41 121.32,70.23 121.53,70.44 123.62,70.44 123.63,70.41 123.94,70.22 124.23,70.42 124.25,70.45 124.84,70.45
+1.0V_VCCSTG on BOTTOM (solid shape): 144.3,90.29 144.3,89.58 144.96,88.92 144.96,87.98 144.86,87.88 144.56,87.88 144.51,87.93 144.51,88.38 144.5,88.4 144.5,88.42 144.47,88.42 144.45,88.44 144.12,88.44 144.11,88.42 144.06,88.42 144.06,87.89 144.05,87.88 143.21,87.88 142.73,88.36 142.73,90.24 143.01,90.52 144.07,90.52
+1.0V_VCCSTG_C on BOTTOM (solid shape): 144.38,88.28 144.38,87.87 144.38,87.78 144.4,87.75 144.66,87.75 144.81,87.6 144.81,87.32 144.81,87.32 144.78,87.19 144.81,87.07 144.81,87.06 144.81,86.4 144.66,86.25 143.64,86.25 143.31,86.58 143.31,87.55 143.51,87.75 144.1,87.75 144.11,87.76 144.16,87.76 144.16,87.81 144.2,87.85 144.2,88.31 144.35,88.31
+1.0V_VCCSTG_R on TOP (solid shape): outline of 367 points within 123.23,64.53 126.34,67.92
+1.0VS_VCCIO on TOP (solid shape): outline of 152 points within 117.63,52.65 123.08,55.58
+1.0VS_VCCIO on TOP (solid shape): outline of 1648 points within 141.97,12.8 204.03,102.72
+1.2V_DDR_B+ on TOP (solid shape): 41.37,48.06 43.6,48.06 44.19,47.47 44.19,46.72 41.56,44.09 40.75,44.09 40.75,44.42 40.78,44.42 41.31,44.42 41.31,45.79 40.75,45.79 40.75,47.21 40.47,47.49 40.47,48.13 40.55,48.21 41.22,48.21
+1.2V_DDR_B+ on BOTTOM (solid shape): 41.78,48.03 43.4,48.03 43.49,48.11 45.62,48.11 45.76,47.97 45.76,47.58 45.73,47.54 44.06,47.54 43.97,47.45 43.97,47.35 43.96,47.31 43.95,47.26 43.95,46.89 43.67,46.61 40.99,46.61 40.2,47.4 40.2,48.05 40.33,48.18 41.63,48.18
+1.2V_DDR_BST on TOP (solid shape): 47.61,47.92 47.61,46.97 47.65,46.93 47.89,46.93 48.02,46.8 48.02,46.37 47.94,46.28 47.6,46.28 47.46,46.42 47.04,46.42 46.87,46.59 46.87,47.9 46.96,47.98 47.55,47.98
+1.2V_DDR_BST on BOTTOM (solid shape): 48.29,47.49 48.29,46.48 48.07,46.26 47.42,46.26 47.22,46.46 47.22,47.5 47.39,47.67 48.1,47.67
+1.2V_DDR_BST_R on TOP (solid shape): 50.1,47.85 50.1,46.98 49.93,46.81 48.45,46.81 48.33,46.94 48.33,47.91 48.43,48.02 49.94,48.02
+1.2V_DDR_LX on TOP (solid shape): 52.02,49.96 52.02,48.63 52.62,48.03 52.62,47.58 51.92,46.88 50.76,46.88 50.57,47.07 50.57,49.92 50.75,50.1 51.87,50.1
+1.2V_DDR_LX on BOTTOM (solid shape): 54.18,50.5 54.18,48.34 53.37,47.53 51.34,47.53 50.9,47.96 48.28,47.96 48.15,47.83 46.09,47.83 45.98,47.95 45.98,49.19 46.03,49.24 48.58,49.24 50.09,50.75 53.93,50.75
+1.2V_DDR_SNB on TOP (solid shape): 49.25,50.02 49.25,48.33 49.1,48.18 47.41,48.18 47.06,48.53 47.06,49.75 47.49,50.18 49.09,50.18
+1.2V_DDRP on TOP (solid shape): 57.18,44.85 57.18,41 56.66,40.48 50.47,40.48 49.87,39.88 49.87,39.19 46.88,39.19 46.86,39.21 46.86,40.29 46.88,40.32 46.88,41.56 47.67,42.35 48.8,42.35 48.86,42.41 54.45,42.41 54.81,42.77 54.81,44.82 55,45 57.03,45
+1.2V_DDRP on BOTTOM (solid shape): 48.37,51.59 48.37,50.31 47.46,49.41 46.83,49.41 46.77,49.47 46.77,50.21 47.27,50.71 47.27,51.68 48.17,51.79
+1.2V_DDRP on BOTTOM (solid shape): 57.2,45.05 57.2,41.66 56.47,40.93 47.92,40.93 47.28,41.57 47.28,42.3 47.35,42.36 48.32,42.36 49.57,43.62 49.57,44.97 50.05,45.44 56.82,45.44
+1.2V_LDO on TOP (solid shape): 25.74,54.93 25.43,54.63 25.43,53.99 24.97,53.54 24.97,52.98 25.3,52.65 25.3,51.71 25.25,51.66 25.13,51.66 25.07,51.71 25.07,52.49 24.54,53.03 24.54,53.87 24.74,54.07 24.74,55.67 24.85,55.77 25.74,55.77
+1.2V_LDO on TOP (solid shape): 29.01,54.15 29.01,53.66 28.4,53.05 27.46,53.05 27.39,52.98 27.38,52.98 26.95,52.55 26.95,52.54 26.9,52.49 26.9,52.47 26.9,51.7 26.85,51.65 26.75,51.65 26.68,51.72 26.68,52.61 27.56,53.5 27.96,53.5 28.43,53.97 28.43,54.15 28.5,54.22 28.93,54.22
+1.2V_MEM on TOP (solid shape): outline of 25177 points within 41.08,2.36 185.19,54.53
+1.8V_3.3V_ALW_VTR3 on TOP (solid shape): 312.99,75.4 312.99,74.33 312.82,74.16 312.42,74.16 312.41,74.16 312.41,73.61 312.4,73.6 312.26,73.6 312.23,73.62 312.23,74.12 312.2,74.15 310.06,74.15 310.05,74.14 310.05,73.62 310.02,73.59 309.87,73.59 309.85,73.61 309.85,74.14 309.84,74.16 309.41,74.16 309.35,74.22 309.35,74.36 309.35,74.37 309.39,74.51 309.35,74.66 309.35,74.67 309.35,75.02 309.6,75.27 309.64,75.3 309.67,75.34 309.98,75.65 310.12,75.56 310.29,75.53 310.31,75.53 310.53,75.58 310.68,75.74 312.64,75.74
+1.8V_PRIM on TOP (solid shape): 120.52,101.71 120.52,101.15 120.91,101.15 120.91,101.15 121.52,101.15 121.63,101.04 122.85,101.04 123,100.89 123,100.33 122.84,100.17 120.05,100.17 119.89,100.32 119.89,100.72 119.89,100.72 119.89,101.09 119.96,101.16 120.34,101.16 120.34,101.71 120.34,101.71 120.51,101.71
+1.8V_PRIM on TOP (solid shape): 311.2,73.6 311.2,72.9 310.87,72.56 310.78,72.56 310.78,72.03 310.64,71.89 309.96,71.89 309.83,72.02 309.83,72.79 309.81,72.81 309.81,72.83 309.37,73.27 309.37,73.97 309.42,74.01 309.68,74.01 309.7,73.99 309.7,73.46 309.72,73.44 310.16,73.44 310.2,73.48 310.2,74.01 310.21,74.02 310.78,74.02
+1.8V_PRIM on TOP (solid shape): 273.16,52.52 273.16,52.39 273.12,52.39 272.84,52.13 272.94,51.77 272.98,51.7 272.95,51.62 272.78,51.45 271.15,51.45 270.99,51.61 270.99,52.69 271.15,52.85 272.83,52.85
+1.8V_PRIM on BOTTOM (solid shape): 164.61,54.22 164.61,53.45 164.24,53.08 162.74,53.08 162.48,53.34 162.48,54.02 162.83,54.37 164.45,54.37
+1.8V_PRIM on BOTTOM (solid shape): 176.48,55.67 176.48,54.68 176.2,54.4 174.98,54.4 174.67,54.71 174.67,55.9 174.8,56.03 176.12,56.03
+1.8V_PRIM on BOTTOM (solid shape): 264.06,26.83 264.06,26.32 263.78,26.03 263.78,25.78 263.52,25.53 262.07,25.53 261.78,25.81 261.78,26.57 262.29,27.08 263.81,27.08
+1.8V_PRIM on BOTTOM (solid shape): 255.91,39.26 255.91,38.37 255.28,37.74 254.74,37.74 254.4,38.07 254.4,38.3 254.6,38.62 254.4,38.93 254.4,39.15 254.94,39.68 255.49,39.68
+1.8V_RUN on TOP (solid shape): 303.34,44.56 303.34,43.84 303.08,43.57 302.21,43.57 302.17,43.61 302.17,44.34 302.07,44.44 302.07,44.68 302.21,44.82 303.08,44.82
+1.8V_RUN on TOP (solid shape): outline of 306 points within 271.94,40.75 285.71,48.41
+1.8V_RUN_AUDIO on TOP (solid shape): 303.15,38.37 303.15,38 303.09,37.94 303.09,37.48 303.03,37.42 302.14,37.42 302.01,37.55 302.01,37.95 302.02,37.99 302.03,38.03 302.03,38.26 302.2,38.43 302.33,38.41 302.46,38.44 303.09,38.44
+1.8V_RUN_AUDIO on TOP (solid shape): 302.05,43.74 302.05,43.56 302.08,43.53 302.08,43.24 302.13,43.19 302.13,42.9 302.2,42.84 303.17,42.84 303.22,42.79 303.22,42.27 303.13,42.18 303.03,42.18 303.03,42.18 302.2,42.18 301.88,41.86 301.88,41.09 301.77,40.98 301.72,40.83 301.72,40.81 301.63,40.72 301.63,39.83 301.25,39.45 301.22,39.41 301.19,39.36 300.79,38.96 300.79,38.93 300.74,38.88 300.74,37.99 300.68,37.93 300.55,37.93 300.49,37.99 300.49,38.82 300.55,38.88 300.55,39.17 301.12,39.74 301.12,43.21 301.17,43.21 301.42,43.38 301.44,43.69 301.46,43.78 301.54,43.83 301.96,43.83
+1.8V_RUN_AUDIO on BOTTOM (solid shape): 303.07,38.33 303.07,37.97 302.65,37.55 302.65,37.04 302.58,36.98 302.02,36.98 301.93,37.07 301.93,38.1 302.25,38.42 302.36,38.41 302.46,38.44 302.96,38.44
+1.8V_RUN_CARD on TOP (solid shape): 25.63,53.46 25.63,52.72 25.68,52.67 25.68,51.71 25.63,51.66 25.53,51.66 25.48,51.71 25.48,52.57 25.43,52.62 25.43,52.72 25.15,53 25.15,53.46 25.23,53.54 25.56,53.54
+1.8V_RUN_CARD on TOP (solid shape): 6.55,62.25 6.55,61.68 6.74,61.49 8.45,61.49 8.9,61.93 10.36,61.93 10.42,61.87 10.42,60.41 10.23,60.22 5.97,60.22 5.72,60.47 5.72,62.25 5.91,62.44 6.36,62.44
+1.8V_RUN_CARD on BOTTOM (solid shape): 6.48,62.22 6.48,60.41 5.72,60.41 5.72,62.25 5.87,62.4 6.3,62.4
+1.8V_RUN_UZ8 on TOP (solid shape): 272.21,49.63 272.75,49.63 272.75,48.88 272.39,48.52 272.39,48.43 272.37,48.41 272.37,47.89 272.35,47.87 271.91,47.87 271.9,47.86 271.84,47.86 271.84,47.82 271.83,47.79 271.81,47.77 271.81,47.51 271.83,47.49 271.84,47.46 271.84,47.43 271.9,47.43 271.91,47.41 272.35,47.41 272.39,47.37 272.39,46.87 272.18,46.65 271.45,46.65 270.95,47.16 270.95,50.18 270.99,50.22 271.62,50.22
+1.8VALWP on TOP (solid shape): 121.49,103.56 121.49,102.96 121.77,102.68 124.28,102.68 124.46,102.5 124.46,102.18 124.46,102.17 124.46,101.21 124.42,101.17 121.83,101.17 121.68,101.32 120.72,101.32 120.7,101.31 120.68,101.33 120.68,101.88 120.2,101.88 120.16,101.85 120.16,101.33 120.15,101.33 119.37,101.33 119.23,101.47 119.23,103.59 119.25,103.61 121.44,103.61
+1VALWP on BOTTOM (solid shape): 184,86.28 184,79.24 183.65,78.89 178.69,78.89 178.1,79.47 178.1,86.25 178.97,87.11 183.16,87.11
+1VALWP_B+ on TOP (solid shape): 179.53,98.93 179.53,97.02 179.28,96.77 178.31,96.77 178.24,96.84 178.24,98.54 178.64,98.95 179.51,98.95
+1VALWP_B+ on BOTTOM (solid shape): 179.52,99.85 179.52,97.05 179.33,96.86 179.33,96.03 179.99,95.37 179.99,93.9 179.9,93.81 178.45,93.81 176.99,95.27 176.13,95.27 175.77,95.62 175.77,98.32 176.09,98.32 176.09,97.74 177.49,97.74 177.49,98.32 177.93,98.32 178.31,98.7 178.31,99.65 178.63,99.97 179.39,99.97
+1VS_VCCIOP on TOP (solid shape): 142.85,106.96 142.85,105.32 143.01,105.16 144.08,105.16 144.95,104.28 144.95,103.02 144.77,102.84 143.98,102.84 143.96,102.85 143.96,102.29 143.73,102.29 143.73,102.3 143.73,102.84 143.18,102.84 143.17,102.84 143.17,102.29 143.18,102.29 142.94,102.29 142.93,102.3 142.93,102.84 142.93,102.84 141.94,102.84 141.43,103.35 139.04,103.35 138.96,103.43 138.96,104.01 139.11,104.16 141.19,104.16 141.5,104.46 141.5,106.98 141.61,107.09 142.72,107.09
+2.5V_MEM on TOP (solid shape): 110.14,11.19 110.14,9.77 109.98,9.62 107.41,9.62 107.05,9.7 106.69,9.62 105.33,9.62 105.23,9.72 105.23,10.94 105.35,11.06 109.39,11.06 109.62,11.3 110.04,11.3
+2.5V_MEM on TOP (solid shape): 193.38,10.08 193.38,9.29 193.06,8.96 192.57,8.96 192.56,8.95 192.51,8.95 192.51,8.85 192.51,8.85 192.51,8.43 192.49,8.41 192.33,8.41 192.29,8.44 192.29,8.94 192.26,8.98 192.2,8.98 192.2,8.97 191.43,8.97 191.21,9.19 191.21,10.21 190.83,10.59 188.7,10.59 187.99,9.88 186.95,9.88 186.74,10.09 186.64,10.09 186.63,10.09 186.43,10.15 186.24,10.09 186.23,10.09 185.99,10.33 185.99,11.09 186.38,11.49 186.4,11.49 186.56,11.64 188.46,11.64 188.73,11.91 188.73,12.46 188.86,12.59 190.87,12.59
+2.5V_MEM on BOTTOM (solid shape): 107.19,12.66 107.19,9.84 107.07,9.71 105.58,9.71 105.38,9.9 105.38,11.38 105.39,11.38 105.39,11.93 105.14,12.18 105.14,13.76 105.21,13.84 106.02,13.84
+2.5V_MEM on BOTTOM (solid shape): 187.83,13.55 187.83,11.98 188.12,11.69 188.12,10.02 187.94,9.84 186.87,9.84 186.86,9.88 186.77,10.07 186.61,10.19 186.6,10.2 186.08,10.71 186.08,11.55 186.09,11.56 186.13,11.68 186.12,11.81 186.12,13.8 186.19,13.86 187.53,13.86
+2.5V_VIN on TOP (solid shape): 198.05,6.99 198.05,6.34 198.08,6.31 198.61,6.31 198.62,6.3 198.62,6.13 198.6,6.11 198.08,6.11 198.05,6.09 198.05,5.49 197.13,4.56 195.93,4.56 195.79,4.7 195.79,5.27 196.24,5.72 196.24,7.22 196.31,7.29 197.75,7.29
+3.3V_1.8V_ESPI on TOP (solid shape): 158.76,55.29 158.76,53.49 158.53,53.26 157.79,53.26 157.54,53.51 157.54,54.19 157.54,54.55 157.54,54.64 157.52,54.65 156.99,54.65 156.98,54.66 156.98,54.84 156.98,54.85 157.51,54.85 157.53,54.86 157.53,55.28 157.59,55.34 158.7,55.34
+3.3V_1.8V_PGPPA on TOP (solid shape): 157.38,55.39 157.38,55.01 157.36,54.98 156.88,54.98 156.86,54.97 156.85,54.97 156.85,54.54 156.86,54.54 156.88,54.53 157.38,54.53 157.41,54.5 157.41,54.25 156.01,52.85 155.98,52.85 155.85,52.72 154.09,52.72 153.84,52.98 153.84,53.65 154.31,54.12 154.31,55.31 154.41,55.41 155.91,55.41 156.01,55.52 157.26,55.52
+3.3V_ALW on TOP (solid shape): 145.75,113.02 146.21,113.02 146.33,112.9 146.33,112.21 146.16,112.03 144.94,112.03 144.94,113.45 145.32,113.45
+3.3V_ALW on TOP (solid shape): 203.41,10.5 203.41,9.17 203.29,9.05 202.4,9.05 202.33,8.98 202.31,8.98 202.31,8.96 202.27,8.92 202.27,8.41 202.14,8.28 201,8.28 200.75,8.54 200.75,10.55 200.98,10.79 203.12,10.79
+3.3V_ALW on TOP (solid shape): 281.38,76.35 281.43,76.35 281.72,76.07 282.43,76.07 282.48,76.04 282.53,76.02 282.68,75.88 282.68,75.47 282.3,75.09 280.88,75.09 280.88,75.1 280.45,75.1 280.19,75.35 280.19,77.01 280.23,77.04 280.69,77.04
+3.3V_ALW on TOP (solid shape): 171.2,35.57 171.2,32.53 170.97,32.3 169.88,32.3 169.87,32.31 169.87,33.36 169.93,33.42 169.93,35.39 169.8,35.51 169.26,35.51 169.17,35.6 169.17,35.71 169.27,35.81 170.97,35.81
+3.3V_ALW on TOP (solid shape): 191.33,15.8 191.33,15.16 191.49,15.16 191.98,14.66 191.98,14.51 192.01,14.49 192.01,14.19 191.53,13.71 191.27,13.71 190.97,14.01 190.96,14.01 190.96,14.06 190,14.06 189.7,14.36 189.7,15.39 189.96,15.66 190.29,15.66 190.53,15.89 191.24,15.89
+3.3V_ALW on TOP (solid shape): 202.3,6.84 202.3,5.85 202.19,5.73 201.63,5.73 200.34,4.44 198.51,4.44 198.19,4.76 198.19,5.98 198.2,5.99 198.65,5.99 198.66,5.99 198.75,5.99 198.75,6.47 198.18,6.47 198.18,6.69 198.24,6.75 201.3,6.75 201.48,6.93 202.21,6.93
+3.3V_ALW on TOP (solid shape): 125.29,112.1 125.91,112.1 126.46,111.54 127.26,111.54 127.39,111.41 127.39,110.69 127.31,110.61 126.6,110.61 126.37,110.38 125.04,110.38 125.04,110.9 124.61,110.9 124.61,110.38 124.02,110.38 123.94,110.3 122.98,110.3 122.94,110.33 122.94,111.75 123.53,112.34 125.05,112.34
+3.3V_ALW on TOP (solid shape): 223.59,14.67 223.59,13.55 223.53,13.48 222.54,13.48 222.36,13.3 222.36,13.18 221.52,12.34 220.15,12.34 220.05,12.44 220.05,13.61 220.3,13.86 220.81,13.86 220.81,13.85 221.42,13.85 221.42,13.85 221.48,13.85 221.49,13.85 221.83,13.86 222,14.15 222,14.17 222.05,14.22 222.05,14.6 222.26,14.8 223.46,14.8
+3.3V_ALW on TOP (solid shape): 298.33,66.06 298.52,65.87 299.34,65.87 299.41,65.93 299.41,65.99 299.6,66.19 299.92,66.19 300.06,66.05 300.06,65.63 300.16,65.52 300.44,65.52 300.44,64.99 300.46,64.97 300.94,64.97 300.94,65.52 301.42,65.52 301.71,65.81 302.87,65.81 303.09,65.73 303.31,65.81 303.32,65.81 303.34,65.79 303.53,65.79 304.09,65.23 306.76,65.23 306.87,65.33 307.68,65.33 307.79,65.45 308.41,65.45 308.68,65.18 308.68,64.76 307.97,64.05 306.25,64.05 305.96,64.2 305.67,64.05 305.15,64.05 305,64.2 303.68,64.2 303.48,64.4 303.48,64.99 303.27,65.2 302.06,65.2 301.43,64.57 301.38,64.55 301.33,64.53 300.81,64.53 300.61,64.59 300.42,64.53 299.91,64.53 299.42,65.02 298.81,65.02 297.72,66.11 297.72,66.57 298.33,66.57
+3.3V_ALW on TOP (solid shape): outline of 94 points within 310.93,76.48 315.18,84.07
+3.3V_ALW on TOP (solid shape): outline of 139 points within 311.64,70.4 316.57,74.04
+3.3V_ALW on BOTTOM (solid shape): 273.38,50.06 273.82,49.63 273.91,49.63 273.93,49.62 274.18,49.62 274.25,49.55 275.05,49.55 275.28,49.32 275.28,48.81 275.28,48.81 275.28,48.64 275.06,48.42 274,48.42 274,48.42 273.66,48.42 273.65,48.44 273.1,48.44 272.78,48.76 272.78,49.87 273.02,50.11 273.38,50.11
+3.3V_ALW on BOTTOM (solid shape): 148.58,103.85 148.58,103.08 148.53,103.04 148.07,103.04 148.04,103.02 148.04,102.31 148.07,102.28 148.58,102.28 148.6,102.26 148.6,101.88 148.57,101.84 148.07,101.84 148.05,101.82 148.05,101.1 148.06,101.09 148.15,101.09 148.16,101.09 148.55,101.09 148.58,101.06 148.59,100.61 148.33,100.35 147.82,100.35 146.36,100.35 145.88,100.35 145.19,101.03 145.19,103.83 145.5,104.13 148.29,104.13
+3.3V_ALW on BOTTOM (solid shape): 274.41,52.97 274.53,52.91 274.67,52.9 274.69,52.9 274.88,52.71 274.89,52.71 275.06,52.55 275.06,51.99 275.21,51.83 275.21,50.95 275.09,50.82 274.45,50.82 273.6,51.67 273.58,51.67 273.5,51.75 273.5,51.88 273.5,51.89 273.53,51.98 273.53,52.07 273.53,52.1 273.81,52.38 273.89,52.38 273.89,52.59 273.92,52.64 273.93,52.7 274.2,52.97
+3.3V_ALW on BOTTOM (solid shape): outline of 109 points within 270.62,79.11 273.51,82.52
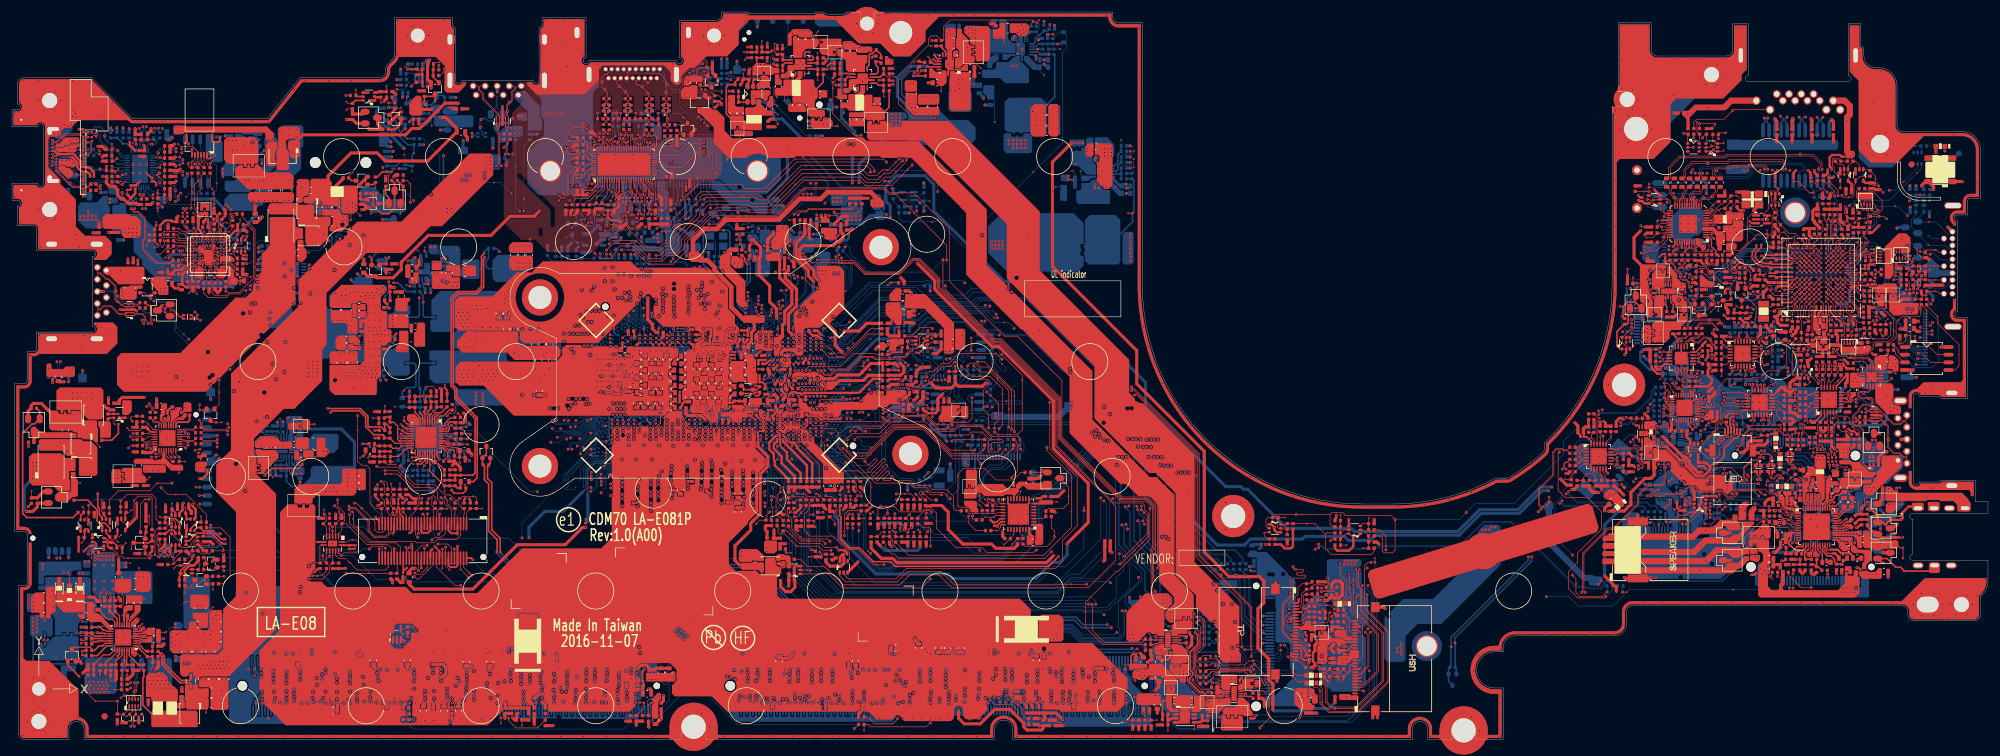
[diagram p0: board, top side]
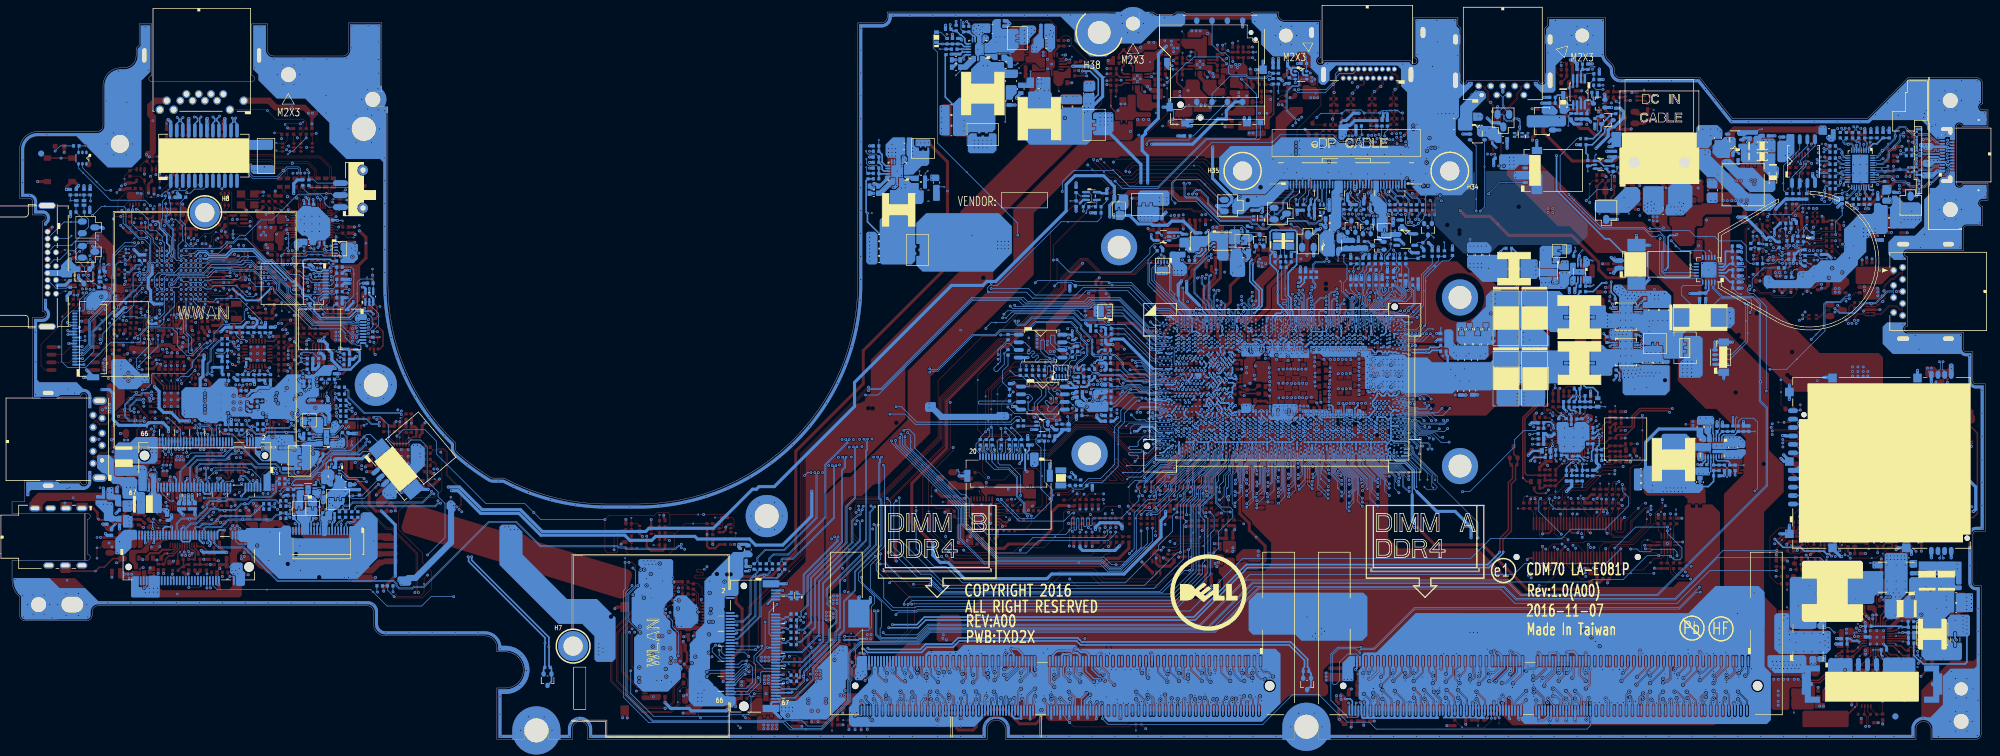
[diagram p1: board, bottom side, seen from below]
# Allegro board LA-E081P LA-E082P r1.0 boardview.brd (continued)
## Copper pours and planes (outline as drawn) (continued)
+3.3V_ALW on BOTTOM (solid shape): outline of 531 points within 189.29,3.35 200.54,15.61
+3.3V_ALW on BOTTOM (solid shape): outline of 1159 points within 216.71,7.95 225.18,29.95
+3.3V_ALW_DSW on TOP (solid shape): outline of 691 points within 127.09,42.49 138.09,54.84
+3.3V_ALW_PCH on TOP (solid shape): 207.4,9.72 207.4,8.76 207.29,8.65 206.35,8.65 206.31,8.7 206.31,9.17 206.3,9.17 206.3,9.8 206.38,9.87 207.24,9.87
+3.3V_ALW_PCH on TOP (solid shape): 160.23,44.6 160.23,42.36 159.66,41.79 159.19,41.79 159.19,42.35 158.7,42.35 158.7,41.79 158.36,41.79 158.35,41.8 158.35,44.65 158.49,44.79 160.04,44.79
+3.3V_ALW_PCH on TOP (solid shape): outline of 659 points within 127.72,53.42 148.42,58.02
+3.3V_ALW_PCH on BOTTOM (solid shape): 137.48,78.48 137.9,78.48 138.03,78.35 138.03,77.26 137.88,77.11 136.28,77.11 136.07,77.31 136.07,78.35 136.2,78.48 136.59,78.48 136.62,78.5 137.46,78.5
+3.3V_ALW_PCH on BOTTOM (solid shape): outline of 158 points within 146.03,54.41 151.61,58.16
+3.3V_ALW_PCH_UZ3 on TOP (solid shape): 206.25,10.05 206.15,9.95 206.15,9.57 205.57,9.57 205.57,9.01 206.15,9.01 206.15,8.6 205.99,8.44 204.59,8.44 204.55,8.4 204.55,8.39 204.4,8.24 203.61,8.24 203.51,8.34 203.51,8.98 203.79,9.27 204.12,9.27 204.2,9.35 204.2,9.89 204.23,9.92 204.25,9.93 204.4,10 204.5,10.13 206.03,10.13 206.03,10.13 206.25,10.13
+3.3V_ALW_UE1 on TOP (solid shape): 301.31,67.7 301.21,67.6 301.08,67.29 301.21,66.99 301.39,66.81 301.39,65.8 301.29,65.7 300.21,65.7 300.21,66.28 300.42,66.5 300.57,66.5 300.57,67.11 300.54,67.11 300.54,67.9 300.57,67.93 301.08,67.93
+3.3V_ALWP on TOP (solid shape): 150.25,107.08 150.25,105.17 150.37,105.05 153.8,105.05 153.93,104.92 153.93,103.78 153.8,103.65 149.74,103.65 148.34,105.05 148.34,107.08 148.6,107.33 149.99,107.33
+3.3V_ALWP on BOTTOM (solid shape): outline of 82 points within 148.18,98.77 159.97,107.33
+3.3V_EC_PLL on TOP (solid shape): 299.75,72.03 299.75,71.24 299.47,70.96 299.47,70.15 299.78,69.84 299.78,69.1 300.05,68.83 300.05,68.52 300.23,68.34 300.23,67.84 300.32,67.76 300.32,67.27 300.16,67.11 299.86,67.11 299.49,67.47 299.49,67.64 299.04,68.09 299.04,69.16 299.06,69.18 299.06,70.02 299.06,71.16 299.39,71.49 299.39,72 299.5,72.1 299.67,72.1
+3.3V_HDD on BOTTOM (solid shape): 274.08,40.08 274.08,39.62 274.09,39.61 274.09,39.57 274.6,39.57 274.6,40.1 274.61,40.11 275.46,40.11 275.63,39.95 275.63,38.62 275.74,38.51 275.7,38.47 275.62,38.08 275.95,37.86 276.02,37.83 276.05,37.76 276.05,37.23 276.18,37.1 276.74,37.1 276.84,37 276.84,36.44 276.69,36.29 276.69,36.25 276.66,36.23 276.66,35.49 276.64,35.46 276.64,34.01 276.4,33.77 275.99,33.77 275.67,34.09 275.67,35.56 275.53,35.7 275.5,35.77 275.53,35.85 275.54,36.36 275.03,36.35 274.99,36.34 274.95,36.36 274.92,36.39 274.92,37.65 274.82,37.76 274.82,37.89 274.69,37.89 274.2,38.37 273.84,38.37 273.59,38.63 273.59,38.75 273.07,39.27 272.95,39.27 272.82,39.4 272.82,40.05 272.87,40.11 273.28,40.11 273.29,40.1 273.29,39.56 273.3,39.56 273.79,39.56 273.82,39.58 273.82,40.09 273.85,40.12 274.04,40.12
+3.3V_HDD_M2 on TOP (solid shape): outline of 208 points within 288.36,23.58 306.68,33.76
+3.3V_HDD_M2 on BOTTOM (solid shape): 291.85,28.91 291.85,27.7 291.65,27.5 291.23,27.5 291.05,27.32 291.03,27.32 290.84,27.13 290.84,27.11 290.77,27.04 290.77,26.37 290.79,26.25 290.84,26.14 290.84,25.67 290.64,25.48 289.63,25.48 289.37,25.74 289.37,27.7 289.76,28.09 289.76,29.16 289.95,29.36 291.41,29.36
+3.3V_HDD_M2 on BOTTOM (solid shape): 305.38,27.07 305.38,25.42 305.5,25.29 305.65,25.29 305.72,25.26 305.75,25.19 306.11,24.84 306.46,25.19 306.49,25.26 306.56,25.29 306.9,25.29 307.03,25.42 307.03,27.01 307.09,27.07 308.04,27.07 308.3,26.82 308.3,23.77 308.11,23.58 303.66,23.58 303.54,23.7 303.54,27.07 303.66,27.2 305.25,27.2
+3.3V_LAN on TOP (solid shape): 286.32,82.18 286.32,81.5 286.21,81.4 285.4,81.4 285.2,81.2 284.66,81.2 284.57,81.29 284.57,82.29 284.75,82.47 286.02,82.47
+3.3V_LAN on TOP (solid shape): 305.31,97.74 305.76,97.74 305.95,97.55 305.95,96.85 305.6,96.5 304.51,96.5 304.42,96.59 304.42,97.11 304.17,97.36 304.17,97.87 305.19,97.87
+3.3V_LAN on TOP (solid shape): 285.12,105.36 285.12,105.11 284.49,104.48 279.72,104.48 278.52,103.27 278.52,101.94 278.01,101.94 278.01,103.02 277.25,103.78 277.25,104.35 277.31,104.41 278.33,104.41 279.34,105.43 285.06,105.43
+3.3V_LAN on BOTTOM (solid shape): 280.27,53.42 280.27,52.96 280.26,52.89 280.27,52.83 280.27,52.11 280.12,51.96 279.84,51.96 279.84,51.98 279.61,52.19 279.31,52.15 279.25,52.15 279.07,52.32 279.07,52.91 278.52,52.91 278.52,53.09 279.07,53.09 279.07,53.5 279.1,53.52 280.17,53.52
+3.3V_LAN_OUT on TOP (solid shape): 282.35,85.16 282.43,85.14 282.51,85.14 283.25,84.4 283.98,84.4 284.42,83.96 284.42,82.64 283.89,82.11 283.89,81.26 283.86,81.23 283.18,81.23 283.15,81.26 283.15,81.96 282.94,82.17 282.94,83.63 282.64,83.93 282.65,83.96 282.55,84.29 282.22,84.39 282.19,84.38 282.1,84.47 280.7,84.47 280.62,84.55 280.62,85.03 280.75,85.16 282.34,85.16
+3.3V_LAN_UZ2 on BOTTOM (solid shape): 278.95,53.46 278.95,53.22 278.39,53.22 278.39,52.78 278.95,52.78 278.95,52.37 278.66,52.09 278.52,52.09 278.39,51.96 278.39,51.68 277.96,51.25 277.53,50.83 276.59,50.83 276.42,50.99 276.42,51.56 276.41,51.56 276.41,52.87 276.41,52.87 276.41,53.25 276.71,53.55 278.86,53.55
+3.3V_M_TPM on TOP (solid shape): 172.66,42.69 172.66,41.8 172.34,41.48 168.66,41.48 168.03,42.12 167.77,42.12 167.14,41.48 167.14,41.1 166.45,40.42 166.45,39.57 166.4,39.52 166.25,39.52 166.2,39.57 166.2,40.51 166.02,40.68 164.88,40.68 164.6,40.4 161.45,40.4 160.89,40.96 160.39,40.96 160.15,40.72 160.15,40.21 159.96,40.02 158.06,40.02 158.06,41.51 158.18,41.64 158.86,41.64 158.86,42.2 159.04,42.2 159.04,41.64 159.69,41.64 160.36,42.31 160.36,42.31 160.48,42.44 164.47,42.44 165.17,41.74 166.57,41.74 166.69,41.86 166.69,42.31 167.2,42.82 168.33,42.82 168.52,42.63 171.01,42.63 171.33,42.94 172.41,42.94
+3.3V_MMI_AUX on TOP (solid shape): 26.32,45.84 26.32,45.76 26.45,45.76 26.57,45.64 28.22,45.64 28.4,45.46 28.4,44.77 28.28,44.65 26.42,44.65 25.38,45.69 21.41,45.69 21.41,45.8 20.52,45.8 20.52,45.8 20.48,45.75 20.43,45.76 20.2,45.99 20.2,46.37 20.45,46.63 22.89,46.63 23.11,46.53 23.34,46.59 23.38,46.6 23.41,46.58 23.8,46.33 24.24,46.47 24.63,46.47 25,46.84 25.32,46.84
+3.3V_MMI_IN on TOP (solid shape): 28.17,55.03 28.17,54.73 28.07,54.63 27.87,54.63 27.83,54.59 27.79,54.59 27.79,54.55 27.74,54.5 27.74,53.8 27.56,53.63 27.51,53.63 26.55,52.67 26.55,52.61 26.49,52.55 26.49,51.71 26.42,51.64 26.36,51.64 26.28,51.72 26.28,52.72 26.41,52.85 26.41,53.76 26.28,53.89 26.28,54.45 26.55,54.72 26.96,54.72 27.11,54.87 27.11,55.06 27.21,55.16 28.05,55.16
+3.3V_MMI_IN on TOP (solid shape): 21.57,45 21.57,44.19 22.26,43.5 22.26,42.79 22.05,42.59 18.32,42.59 18.2,42.71 18.2,43 18.24,43.05 18.72,43.05 18.73,43.05 18.75,43.05 18.75,43.07 18.75,43.55 18.72,43.58 18.22,43.58 18.2,43.6 18.2,43.81 18.22,43.83 18.72,43.83 18.75,43.86 18.75,44.34 18.75,44.36 18.73,44.36 18.72,44.37 18.22,44.37 18.2,44.39 18.2,44.88 18.42,45.1 21.47,45.1
+3.3V_PGPPE on TOP (solid shape): 134.68,59.47 134.78,59.41 134.76,59.3 135.01,58.75 135.27,59.3 135.25,59.41 135.34,59.47 137.12,59.47 137.17,59.41 137.17,59.08 136.49,58.4 136.47,58.4 136.12,58.05 135.45,58.05 135.38,58.07 135.34,58.14 135.13,58.44 134.77,58.36 134.7,58.33 134.63,58.36 134.53,58.44 134.42,58.47 134.4,58.47 134.1,58.78 134.1,59.21 134.35,59.47
+3.3V_RUN on TOP (solid shape): 294.54,58.69 294.54,58.34 294.87,58.01 295.48,58.01 295.81,58.34 296.12,58.34 296.22,58.23 296.22,57.93 296.12,57.83 295.86,57.83 295.41,57.37 295.41,56.96 294.92,56.96 294.92,57.4 294.62,57.7 294.24,57.7 294.01,57.93 294.01,58.72 294.52,58.72
+3.3V_RUN on TOP (solid shape): 291.74,35.54 291.74,35.28 291.98,35.04 291.98,33.61 291.71,33.34 291,33.34 290.97,33.36 290.97,33.86 290.93,33.9 290.25,33.9 290.24,33.89 290.24,33.36 290.22,33.34 289.8,33.34 289.78,33.36 289.78,33.87 289.75,33.9 289.07,33.9 289.04,33.87 289.04,33.39 289,33.35 288.49,33.35 288.45,33.39 288.45,33.69 289.78,35.02 289.94,35.02 290.64,35.72 290.82,35.72 290.88,35.72 290.93,35.73 291.54,35.73
+3.3V_RUN on TOP (solid shape): 273.82,77.51 273.87,77.46 274.27,77.46 274.3,77.49 274.3,78 274.35,78.05 274.55,78.05 274.6,78 274.6,76.98 274.33,76.7 274.33,75.13 274.25,75.05 273.83,75.05 273.79,75.01 273.59,75.01 273.59,74.81 273.48,74.69 272.55,74.69 272.53,74.68 272.4,74.82 272.39,74.83 272.34,74.92 272.27,74.99 272.27,75.64 272.27,75.65 272.29,75.77 272.27,75.9 272.27,75.9 272.27,77.31 273,78.05 273.82,78.05
+3.3V_RUN on TOP (solid shape): 18.06,44.75 18.06,44.34 18.09,44.32 18.09,44.27 18.1,44.25 18.12,44.23 18.62,44.23 18.62,44.23 18.62,43.98 18.61,43.97 18.11,43.97 18.07,43.94 18.07,43.87 18.06,43.86 18.06,43.55 18.07,43.54 18.07,43.45 18.08,43.44 18.62,43.44 18.62,43.18 18.62,43.18 18.4,43.18 18.4,43.18 18.09,43.18 18.08,43.17 18.08,43.06 18.06,43.05 18.06,42.66 18.08,42.65 18.08,42.61 18.01,42.54 16.68,42.54 16.49,42.73 16.49,44.53 16.82,44.86 17.95,44.86
+3.3V_RUN on TOP (solid shape): 201.6,3.99 201.6,3.57 201.62,3.55 201.62,3.46 201.68,3.46 201.7,3.45 201.72,3.45 202.24,3.45 202.3,3.45 202.31,3.46 202.33,3.48 202.33,3.54 202.33,3.54 202.33,3.99 202.35,4 202.78,4 202.81,3.97 202.81,3.47 202.84,3.44 202.92,3.44 203.43,3.44 203.5,3.44 203.54,3.48 203.54,3.55 203.54,3.55 203.54,3.97 203.56,3.98 204.08,3.98 204.37,3.69 204.37,1.62 204.23,1.48 200.91,1.48 200.75,1.64 200.75,3.35 200.79,3.39 200.82,3.44 200.86,3.63 200.8,3.81 200.77,3.85 200.93,4.01 201.58,4.01
+3.3V_RUN on TOP (solid shape): outline of 104 points within 216.72,12.54 221.4,18.03
+3.3V_RUN on BOTTOM (solid shape): 148.52,71.82 148.52,70.3 148.39,70.17 146.94,70.17 146.79,70.33 146.79,71.93 146.94,72.08 148.26,72.08
+3.3V_RUN on BOTTOM (solid shape): 17.53,89.81 17.53,89.13 17.37,88.97 16.12,88.97 16.01,89.08 16.01,89.64 16.03,89.67 16.03,89.92 16.11,90 17.34,90
+3.3V_RUN on BOTTOM (solid shape): 107.83,102 107.83,99.84 107.57,99.59 107.07,99.59 106.45,100.2 106.46,100.22 106.45,100.29 106.43,100.37 106.43,100.98 106.18,101.24 106.18,102 106.3,102.13 107.7,102.13
+3.3V_RUN on BOTTOM (solid shape): 271.12,70.16 271.12,69.64 270.9,69.41 270.49,69.41 270.24,69.66 269.32,69.66 269.25,69.69 269.22,69.76 269.2,69.87 269.14,69.96 269.14,70.45 269.33,70.64 270.65,70.64
+3.3V_RUN on BOTTOM (solid shape): 274.73,46.58 274.73,46.22 274.55,46.04 274.55,45.59 274.65,45.48 274.68,45.44 274.78,45.34 274.78,45.23 274.8,45.13 274.83,45.03 274.85,44.99 274.78,44.93 274.17,44.93 274.09,45.01 274.1,45.04 274.14,45.13 274.15,45.23 274.15,45.51 274.07,45.59 274.07,46.25 273.92,46.4 273.77,46.4 273.77,46.88 274.43,46.88
+3.3V_RUN on BOTTOM (solid shape): 274.39,43.9 274.39,42.76 274.68,42.46 274.68,42 274.68,41.97 275.95,40.7 275.95,40.67 275.98,40.67 276.07,40.58 276.49,40.58 276.66,40.41 276.66,39.87 276.76,39.77 276.76,39.26 276.59,39.08 276.13,39.08 275.88,39.33 275.88,39.88 275.51,40.25 274.51,40.25 274.48,40.22 274.48,40.16 274.46,40.14 274.46,39.7 274.22,39.7 274.21,39.7 274.21,40.13 274.2,40.14 274.2,40.22 274.19,40.24 274.11,40.24 274.1,40.25 273.8,40.25 273.78,40.24 273.71,40.24 273.68,40.21 273.68,39.69 273.67,39.68 273.43,39.68 273.42,39.7 273.42,40.15 273.41,40.16 273.41,40.23 273.4,40.24 272.83,40.24 272.55,40.53 272.55,40.53 271.85,41.23 270.13,41.23 270.13,41.74 272.1,41.74 272.36,41.74 272.55,41.93 272.55,42.75 272.72,42.93 272.73,42.93 273.64,43.83 273.98,43.83 274.15,44 274.29,44
+3.3V_RUN on BOTTOM (solid shape): outline of 1404 points within 274.15,52.5 299.93,62.17
+3.3V_RUN_AUDIO on TOP (solid shape): 295.43,41.15 295.43,40.59 295.33,40.49 294.26,40.49 294.06,40.7 294.06,41.19 294.1,41.23 295.36,41.23
+3.3V_RUN_AUDIO on TOP (solid shape): outline of 217 points within 270.26,70.12 274.63,78.89
+3.3V_RUN_AUDIO_DVDD on TOP (solid shape): 293.69,41.18 293.69,40.77 294.28,40.19 294.28,39.69 294.28,39.68 294.28,39.05 294.41,38.78 294.71,38.7 294.77,38.7 294.83,38.72 294.88,38.68 294.9,38.63 294.96,38.56 295.66,38.56 296.42,37.8 296.93,37.8 296.99,37.74 296.99,37.47 296.93,37.41 296.17,37.41 295.52,38.05 294.92,38.05 294.84,38.14 294.47,38.14 293.78,38.83 293.78,38.99 293.76,39.01 293.76,39.19 293.65,39.29 293.57,39.31 293.48,39.31 293.45,39.31 293.25,39.52 293.25,39.9 293.28,39.93 293.28,40.56 293.13,40.71 293.13,40.74 293.12,40.87 293.06,40.98 293.06,41.22 293.65,41.22
+3.3V_RUN_AUDIO_IO on TOP (solid shape): 295.76,34.42 296.89,34.42 296.93,34.37 296.93,34.31 296.87,34.24 295.86,34.24 295.48,33.86 295.48,33.56 295.47,33.55 294.96,33.55 294.84,33.42 294.84,33.23 294.77,33.17 294.77,32.53 294.71,32.47 294.26,32.47 294.14,32.59 294.14,34.24 294.26,34.37 294.92,34.37 295.11,34.56 295.61,34.56
+3.3V_RUN_AUDIO_UZ5 on TOP (solid shape): 274.3,73.75 274.3,71.9 274.13,71.73 274.13,70.25 274.01,70.12 273.18,70.12 273.18,70.88 272.61,70.88 272.61,73.06 272.69,73.13 272.75,73.23 272.78,73.25 272.78,73.74 273.19,73.74 273.28,73.83 274.22,73.83
+3.3V_RUN_CARD on TOP (solid shape): 32.34,46.09 32.34,45.46 32.03,45.15 32.03,44.54 31.91,44.42 30.71,44.42 30.41,44.72 30.41,45.84 30.69,46.12 32.31,46.12
+3.3V_RUN_CARD on TOP (solid shape): 26.27,53.69 26.27,52.9 26.09,52.72 26.09,51.71 26.04,51.66 25.94,51.66 25.89,51.71 25.89,52.67 25.76,52.8 25.76,53.71 25.84,53.79 26.17,53.79
+3.3V_RUN_CARD on BOTTOM (solid shape): 31.81,45.1 33.08,45.1 33.2,44.98 33.2,44.42 33.08,44.29 30.82,44.29 30.36,44.75 30.36,45.23 30.49,45.36 31.55,45.36
+3.3V_RUN_DIMM2 on TOP (solid shape): 187.27,12.54 187.43,12.54 188.31,12.54 188.38,12.49 188.47,12.45 188.48,12.44 188.48,11.9 188.35,11.77 186.29,11.77 186,11.49 185.64,11.49 185.45,11.68 185.45,12.39 185.66,12.6 187.2,12.6
+3.3V_RUN_UT9 on BOTTOM (solid shape): 17.53,91.97 17.53,90.53 17.49,90.49 16.35,90.49 16.03,90.81 16.03,91.92 16.21,92.09 17.4,92.09
+3.3V_RUN_UT9 on BOTTOM (solid shape): 26.08,101.27 26.08,100.42 26.22,100.27 26.62,100.27 26.85,100.04 26.85,99.78 26.34,99.27 25.66,99.27 25.28,99.65 25.28,101.25 25.35,101.33 26.02,101.33
+3.3V_RUN_UZ3 on TOP (solid shape): 205.55,5.85 205.54,5.82 205.55,5.16 205.95,4.63 205.95,3.99 205.83,3.87 204.5,3.87 204.26,4.11 203.45,4.11 203.42,4.11 203.42,4.08 203.41,4.07 203.41,3.61 203.38,3.57 202.97,3.57 202.94,3.61 202.94,4.1 202.89,4.14 202.24,4.14 202.21,4.11 202.21,3.6 202.18,3.57 201.77,3.57 201.73,3.62 201.73,4.1 201.72,4.11 201.69,4.14 201.05,4.14 201.05,4.89 201.51,5.34 202.95,5.34 203.46,5.85 203.46,6.75 203.64,6.94 204.47,6.94
+3.3V_TBTA_FLASH on BOTTOM (solid shape): 33.47,100.33 33.47,99.55 33.59,99.44 34.71,99.44 34.97,99.18 34.97,96.1 34.73,95.87 33.67,95.87 32.14,97.4 32.14,100.42 32.26,100.54 33.27,100.54
+3.3V_TP on TOP (solid shape): 215.65,19.69 215.65,19.02 215.69,18.97 218.13,18.97 218.22,18.89 218.22,18.31 218.06,18.15 217.56,18.15 217.53,18.13 217.53,17.6 217.52,17.59 217.34,17.59 217.33,17.6 217.33,18.14 217.32,18.15 216.36,18.15 216.17,17.96 215.41,17.96 215.19,18.17 214,18.17 213.69,18.48 212.7,18.48 212.63,18.56 212.63,18.74 212.71,18.82 214.03,18.82 214.03,18.82 214.22,18.82 214.7,19.3 214.7,19.54 214.86,19.7 215.64,19.7
+3.3V_TP on BOTTOM (solid shape): outline of 126 points within 214.12,18.49 218.23,23.92
+3.3V_VCCHDA on TOP (solid shape): 125.99,33.02 126.89,33.02 127.02,32.9 127.02,31.36 126.57,30.91 125.25,30.91 124.86,31.29 124.86,31.62 124.85,31.64 124.85,32.78 125.1,33.04 125.99,33.04
+3.3V_VDD_DCIN on BOTTOM (solid shape): 74.09,104.96 74.09,104.1 73.77,103.78 71.72,103.78 71.45,104.05 71.45,104.53 72.14,105.23 73.82,105.23
+3.3V_VDD_PIC on TOP (solid shape): 28.81,101.61 28.81,100.91 28.45,100.55 27.06,100.55 26.85,100.75 26.85,101.81 26.99,101.95 28.47,101.95
+3.3V_VDD_PIC on TOP (solid shape): 43.45,100.59 43.45,99.62 43.31,99.48 42.31,99.48 42.04,99.75 42.04,100.72 42.18,100.86 43.19,100.86
+3.3V_VDD_PIC on TOP (solid shape): 32.77,89.05 32.77,87.9 32.64,87.78 32.2,87.78 32.2,88.35 31.69,88.35 31.69,87.78 31.31,87.78 31.25,87.84 31.25,89.05 31.37,89.17 32.64,89.17
+3.3V_VDD_PIC on BOTTOM (solid shape): 28.12,101.66 28.12,100.54 28,100.41 26.79,100.41 26.77,100.43 26.77,101.74 26.97,101.94 27.84,101.94
+3.3V_VDD_PIC on BOTTOM (solid shape): 43.92,99.86 43.92,99.85 44.24,99.53 45.25,99.53 45.37,99.4 45.37,98.93 45.74,98.57 45.74,97.42 44.88,96.56 42.97,96.56 42.8,96.73 42.8,97.57 41.88,98.49 41.88,99.79 42.14,100.05 43.73,100.05
+3.3V_VDD_PIC_PDA on TOP (solid shape): 32.58,87.52 32.58,86.95 32.39,86.76 31.56,86.76 31.18,86.38 31.18,85.36 31.12,85.3 30.68,85.3 30.68,87.01 31.25,87.58 32.52,87.58
+3.3V_WLAN on TOP (solid shape): 215.08,8.48 215.08,7.12 215.5,6.7 215.5,6 215.73,5.77 216.12,5.77 216.24,5.64 216.24,5.14 215.97,4.87 213.93,4.87 212.92,5.87 212.92,7.98 212.92,7.98 212.92,8.21 213.23,8.52 215.04,8.52
+3.3V_WLAN on TOP (solid shape): 195.35,12.29 195.35,11.18 195.25,11.11 195.19,11 195.18,10.99 194.93,10.73 194.93,9.62 194.67,9.37 194.19,9.37 193.82,9.74 193.82,9.85 192.16,11.51 192.16,12.29 192.38,12.51 192.74,12.51 192.77,12.49 192.77,12.06 192.77,11.96 192.87,11.96 193.2,11.96 193.25,11.96 193.26,11.97 193.28,11.97 193.28,12.03 193.3,12.06 193.3,12.51 193.53,12.51 193.55,12.49 193.55,12.08 193.55,12.01 193.57,11.99 193.57,11.97 193.59,11.97 193.6,11.96 193.99,11.96 194.04,11.96 194.05,11.97 194.08,11.97 194.08,12 194.09,12.01 194.09,12.49 194.11,12.51 194.9,12.51 195.13,12.51
+3.3V_WLAN on BOTTOM (solid shape): outline of 732 points within 205.11,5.32 215.72,31.39
+3.3V_WLAN_UZ4 on TOP (solid shape): 193.77,15.64 194.16,15.64 194.99,14.81 195.03,14.6 195.2,14.48 195.2,13 194.85,12.64 194.01,12.64 193.99,12.62 193.97,12.62 193.97,12.61 193.96,12.59 193.96,12.11 193.93,12.08 193.73,12.08 193.68,12.13 193.68,12.59 193.68,12.62 193.65,12.62 193.63,12.64 193.2,12.64 193.17,12.62 193.17,12.11 193.15,12.08 192.92,12.08 192.89,12.11 192.89,12.62 192.87,12.64 192.38,12.64 192.36,12.67 192.36,13.34 192.66,13.64 192.66,14.19 192.69,14.19 192.69,14.8 192.66,14.8 192.66,14.95 192.49,15.13 192.49,15.72 192.64,15.87 193.54,15.87
+3.3V_WWAN on TOP (solid shape): 305.25,49.1 305.25,48.67 304.98,48.4 304.98,48.11 305.19,47.9 305.24,47.9 305.24,47.83 305.23,47.81 305.14,47.68 305.07,47.53 305.06,47.52 304.93,47.39 304.93,46.75 304.87,46.69 303.41,46.69 303.34,46.75 303.34,47.82 303.36,47.88 303.36,47.94 303.36,47.99 303.34,48 303.28,48.11 303.17,48.17 302.81,48.53 302.81,49.12 302.9,49.21 305.15,49.21
+3.3V_WWAN on BOTTOM (solid shape): outline of 156 points within 303.89,45.81 311.03,50.21
+3.3V_WWAN on BOTTOM (solid shape): outline of 264 points within 280.09,44.73 287.74,50.6
+3.3V_WWAN_UZ2 on BOTTOM (solid shape): outline of 117 points within 276.46,44.72 280.51,49.55
+5V_ALW on TOP (solid shape): 67.51,53.3 67.51,52.19 67.45,52.13 66.89,52.13 66.8,52.22 66.39,52.22 65.57,53.05 65.57,53.75 65.85,54.03 66.78,54.03
+5V_ALW on TOP (solid shape): 306.3,60.87 306.6,60.57 306.6,60.31 306.74,60.18 307.49,60.18 307.65,60.02 307.65,59.06 307.13,58.54 307.02,58.54 306.91,58.42 305.18,58.42 305.12,58.48 305.12,60.67 305.34,60.88 306.3,60.88
+5V_ALW on TOP (solid shape): 128.58,29.36 128.58,29.1 128.45,28.98 128.45,28.96 128.39,28.9 128.39,28.62 128.17,28.4 127.99,28.4 127.45,28.94 127.09,28.94 126.93,29.1 126.93,29.38 127.04,29.49 127.53,29.49 127.7,29.66 128.27,29.66
+5V_ALW on TOP (solid shape): 25.48,76.78 25.48,76.22 25.76,75.94 25.76,75.1 25.96,74.9 25.96,74.01 25.79,73.83 24.41,73.83 24.26,73.98 24.26,74.38 23.03,75.61 23.03,76.35 23.53,76.85 25.41,76.85
+5V_ALW on TOP (solid shape): 311.43,63.42 311.43,62.49 311.27,62.33 311.27,61.67 310.88,61.28 309.53,61.28 309.27,61.54 309.29,61.58 309.33,61.67 309.34,61.77 309.34,62.3 309.24,62.41 309.24,63.54 309.27,63.58 309.79,63.58 309.81,63.58 309.81,63.59 310.08,63.86 310.99,63.86
+5V_ALW on TOP (solid shape): 137.71,116.21 137.71,115.01 137.71,115.01 137.52,114.82 136.9,114.82 136.82,114.74 136.82,114.34 136.29,114.34 136.29,113.9 136.83,113.9 136.83,113.56 136.75,113.48 135.59,113.48 135.41,113.66 134.58,113.66 134.07,114.18 134.07,114.68 134.07,114.69 134.07,114.95 134.07,114.95 134.07,115.59 134.6,115.59 134.6,116.03 134.07,116.03 134.07,116.3 134.13,116.36 137.56,116.36
+5V_ALW on TOP (solid shape): 40.86,99.33 40.86,95.63 40.25,95.63 40.2,95.58 40.16,95.58 40.16,95.07 40.13,95.05 39.69,95.05 39.66,95.07 39.66,95.55 39.66,95.58 39.63,95.58 39.61,95.6 39.01,95.6 38.99,95.58 38.96,95.58 38.96,95.05 38.95,95.04 38.49,95.04 38.48,95.05 38.48,95.55 38.46,95.56 38.46,95.58 37.68,95.58 37.68,95.57 35.92,95.57 35.2,96.29 35.2,99.22 39.56,99.22 39.56,99.17 39.57,99.11 39.59,99.06 39.61,99.01 39.64,98.97 39.68,98.93 39.72,98.9 39.77,98.87 39.82,98.85 39.87,98.84 39.92,98.84 39.97,98.84 40.03,98.85 40.08,98.87 40.12,98.9 40.16,98.93 40.2,98.97 40.23,99.01 40.25,99.06 40.27,99.11 40.28,99.17 40.28,99.22 40.27,99.27 40.25,99.32 40.23,99.37 40.2,99.42 40.16,99.45 40.12,99.49 40.08,99.51 40.03,99.53 39.97,99.55 39.92,99.55 39.87,99.55 39.82,99.53 39.77,99.51 39.72,99.49 39.68,99.45 39.64,99.42 39.61,99.37 39.59,99.32 39.57,99.27 39.56,99.22 35.2,99.22 35.2,99.5 35.72,100.02 40.18,100.02
+5V_ALW on TOP (solid shape): 188.91,24.26 189.21,24.09 189.52,24.26 189.64,24.26 189.65,24.26 189.8,24.22 189.96,24.26 189.97,24.26 191.91,24.26 192.14,24.03 192.57,23.61 192.57,22.53 191.3,21.26 191.3,17.8 191.29,17.8 191.29,17.21 191.27,17.19 190.3,17.19 189.97,17.52 189.24,17.52 188.9,17.85 188.88,17.85 188.74,17.89 188.6,17.85 188.58,17.85 187,16.27 185.35,16.27 185.01,16.61 185.01,21.03 185.03,21.04 185.17,21.15 185.23,21.32 185.23,21.33 187.24,23.34 187.27,23.34 187.6,23.43 187.69,23.76 187.69,23.79 188.16,24.26
+5V_ALW on BOTTOM (solid shape): 37.45,99.65 37.45,97.69 37.27,97.52 35.47,97.52 35.31,97.68 35.31,99.38 35.68,99.75 37.34,99.75
+5V_ALW on BOTTOM (solid shape): 84.84,101.75 84.84,100.48 84.46,100.09 83.19,100.09 82.58,99.48 82,99.48 82,99.41 81.67,99.08 80.9,99.08 80.78,99.21 80.78,100.73 81.92,101.87 84.71,101.87
+5V_ALW on BOTTOM (solid shape): 165.87,100.09 167.9,100.09 167.9,100.67 168.92,100.67 169.36,100.22 169.36,97.68 169.04,97.36 165.11,97.36 164.6,97.87 164.6,100.41 164.85,100.67 165.87,100.67
+5V_ALW on BOTTOM (solid shape): 277.36,41.54 277.45,41.47 277.45,41.46 278.12,41.46 278.2,41.39 278.2,40.63 278.16,40.6 277.97,40.6 277.45,40.07 277.13,40.07 276.97,40.23 276.97,40.58 276.78,40.78 276.78,41.46 276.9,41.58 276.9,41.58 276.94,41.61 277.3,41.61
+5V_ALW on BOTTOM (solid shape): outline of 191 points within 305.3,58.17 311.56,63.16
+5V_ALW_PDA on TOP (solid shape): 35.57,78.03 35.57,77.01 35.22,76.66 34.39,76.66 34.05,77 34.05,77.09 34.04,77.16 34.16,77.28 34.16,77.82 34.04,77.94 34.04,78.19 34.06,78.21 35.39,78.21
+5V_ALW_PDA on TOP (solid shape): 42.19,94.18 46.08,94.18 46.75,93.5 46.75,92.5 46.65,92.25 46.75,92 46.75,91.65 46.46,91.36 39.16,91.36 38.12,92.4 38.06,92.47 37.99,92.53 37.05,93.46 37.05,94.78 37.71,95.44 38.33,95.44 38.35,95.43 38.35,94.95 38.38,94.92 38.43,94.92 38.44,94.91 39,94.91 39.04,94.92 39.05,94.93 39.06,94.94 39.08,94.96 39.08,94.99 39.09,95 39.09,95.47 39.53,95.47 39.54,95.47 39.54,95.02 39.56,95 39.56,94.94 39.56,94.93 39.57,94.93 39.58,94.92 39.63,94.92 40.19,94.92 40.25,94.92 40.28,94.94 40.28,95.01 40.3,95.03 40.3,95.48 40.88,95.48
+5V_ALW_PDA on BOTTOM (solid shape): 46.66,93.02 46.66,92.35 46.65,92.25 46.66,92.15 46.66,91.84 46.36,91.53 45.06,91.53 44.91,91.69 44.91,92.63 45.43,93.14 46.54,93.14
+5V_ALWP on TOP (solid shape): 171.61,105.24 171.61,100.42 171.3,100.11 169.55,100.11 169.09,100.57 169.09,104.84 169.75,105.5 171.35,105.5
+5V_ALWP on BOTTOM (solid shape): 171.84,105.56 171.84,100.41 171.65,100.22 169.74,100.22 169.11,100.86 165.3,100.86 164.79,101.36 164.79,105.87 165.49,106.57 170.82,106.57
+5V_HDD on BOTTOM (solid shape): 280.51,38.56 280.51,38.02 280.54,37.99 280.93,37.99 280.99,37.93 280.99,37.61 280.74,37.36 280.74,36.52 280.17,35.96 280.17,35.77 280.04,35.64 280.04,34.18 279.91,34.05 278.83,34.05 278.71,34.18 278.71,35.96 278.63,36.04 278.63,36.2 278.45,36.38 278.45,36.98 278.41,37.01 278.41,37.03 278.4,37.03 278.39,37.04 277.71,37.04 277.7,37.04 277.63,37.07 277.55,37.08 277.53,37.08 277.37,37.23 277.37,38.43 277.52,38.58 277.89,38.58 277.9,38.56 277.9,38.04 277.92,38.02 278.35,38.02 278.38,38.04 278.38,38.58 278.38,38.58 278.47,38.58 278.77,38.58 278.77,38.59 279.12,38.59 279.72,37.99 280.29,37.99 280.32,38.02 280.32,38.58 280.34,38.6 280.48,38.6
+5V_HDD_UZ23 on BOTTOM (solid shape): 280.8,41.17 280.8,39.58 281.06,39.32 281.06,38.28 280.96,38.18 280.74,38.18 280.68,38.25 280.68,38.7 280.64,38.73 280.18,38.73 280.17,38.72 280.17,38.18 279.91,38.18 279.72,38.37 279.72,40.47 279.6,40.59 279.6,41.36 279.66,41.42 280.55,41.42
+5V_PD_VDD on BOTTOM (solid shape): 38.24,100.27 38.65,100.27 38.92,100 38.92,99.19 39.18,98.93 39.68,98.93 39.92,98.84 40.16,98.93 41.29,98.93 41.46,98.77 41.46,98.37 41.03,97.94 41.03,97.61 41,97.61 41,96.99 41.03,96.99 41.03,96.13 40.7,95.8 37.87,95.8 37.57,96.1 37.57,97.76 37.59,97.86 37.57,97.95 37.57,99.38 37.59,99.48 37.57,99.58 37.57,99.83 37.48,99.92 37.13,99.92 37.06,99.98 37.06,100.48 37.18,100.59 37.93,100.59
+5V_RUN on TOP (solid shape): 267.59,39.83 267.59,38.79 267.41,38.61 266.62,38.61 265.43,39.8 264.84,39.8 264.36,40.27 264.36,40.82 265.04,41.49 265.93,41.49
+5V_RUN on TOP (solid shape): 221.11,18.18 221.29,18.18 221.47,18 221.47,17.44 221.43,17.07 221.8,17 222.29,17 222.45,16.84 223.29,16.84 223.41,16.73 223.41,16.58 223.28,16.45 221.51,16.45 221.5,16.45 221.27,16.45 220.81,16.91 220.8,16.91 220.79,16.92 219.86,16.92 219.58,17.2 219.58,17.92 219.84,18.18 221.11,18.18
+5V_RUN on TOP (solid shape): 275.49,78.47 275.49,78.38 275.65,78.22 275.65,78.1 276.45,77.29 276.45,76.64 276.48,76.61 276.48,76.56 277.21,75.83 277.34,75.83 277.37,75.81 277.73,75.81 277.91,75.63 277.91,74.77 277.87,74.7 277.8,74.67 277.73,74.67 277.65,74.64 277.6,74.64 277.42,74.47 276.92,74.47 276.36,75.02 275.65,75.02 275.6,75.08 275.6,75.97 275.64,76.02 275.64,76.68 275.4,76.92 275.4,76.94 275.24,77.2 274.94,77.25 274.85,77.26 274.81,77.34 274.81,78.45 274.92,78.57 275.39,78.57
+5V_RUN on TOP (solid shape): 272.14,68.52 272.14,68 272.15,67.99 272.69,67.99 272.7,67.98 272.7,67.74 272.68,67.73 272.23,67.73 272.23,67.72 272.18,67.72 272.16,67.71 272.15,67.69 272.15,67.64 272.13,67.62 272.13,67.28 272.15,67.26 272.15,67.22 272.16,67.2 272.21,67.2 272.23,67.18 272.68,67.18 272.68,66.94 272.23,66.94 272.2,66.91 272.16,66.91 272.15,66.89 272.15,66.86 272.12,66.83 272.12,66.18 272.15,66.15 272.15,65.86 272.06,65.78 271.34,65.78 271.01,66.11 271.01,66.12 270.93,66.25 270.8,66.33 270.79,66.33 270.51,66.62 270.51,67.32 270.55,67.4 270.64,67.41 271.12,67.75 270.64,68.08 270.55,68.1 270.51,68.18 270.51,68.25 271.07,68.81 271.84,68.81
+5V_RUN on TOP (solid shape): outline of 1033 points within 113.72,19.39 196.18,105.05
+5V_RUN on BOTTOM (solid shape): 278.97,40.11 278.97,38.96 278.71,38.71 278.52,38.71 278.26,38.71 278.23,38.68 278.23,38.17 278.21,38.15 278.05,38.15 278.03,38.16 278.03,38.69 278,38.72 277.45,38.72 277.41,38.76 277.41,39.84 278,40.42 278.66,40.42
+5V_RUN on BOTTOM (solid shape): 261.87,48.76 261.87,45.81 262.03,45.64 262.25,45.42 262.47,45.42 265.33,42.56 265.38,42.49 265.44,42.44 265.54,42.35 266.58,41.32 266.58,40.61 265.89,39.92 264.45,39.92 264.2,40.17 264.2,40.83 264.04,40.99 264.01,41.08 264.07,41.15 264.16,41.72 263.59,41.63 263.52,41.57 263.43,41.6 259.53,45.5 259.53,48.33 260.33,49.13 261.5,49.13
+5V_RUN on BOTTOM (solid shape): 247.12,35.31 247.12,28.99 238.29,20.15 238.28,20.15 237.32,19.19 233.39,19.19 231.35,17.15 231.35,13.26 230.98,12.89 228.38,12.89 227.86,13.41 227.86,20.25 228.08,20.47 228.19,20.49 228.25,20.39 228.86,20.13 228.6,20.74 228.5,20.8 228.52,20.91 230.93,23.32 235.91,23.32 243.32,30.73 243.32,34.47 244.52,35.67 246.76,35.67
+5V_RUN_AUDIO on TOP (solid shape): 301.12,47.01 301.12,45.17 300.93,44.98 299.69,44.98 299.28,45.38 299.28,47.01 299.57,47.3 299.65,47.3 299.72,47.33 300.8,47.33
+5V_RUN_AUDIO on TOP (solid shape): 310.46,28.4 310.46,26.89 310.25,26.68 307.29,26.68 306.58,27.39 306.58,27.83 306.65,27.89 307.15,27.89 307.28,28.02 308.11,28.02 308.3,27.83 309.31,27.83 309.95,28.47 310.39,28.47
+5V_RUN_AUDIO on TOP (solid shape): 277.37,70.83 277.37,70.25 277.88,70.25 277.88,70.83 278.14,70.83 278.16,70.81 278.16,69.6 277.11,68.55 277.11,68.03 277.06,67.98 275.5,67.98 275.2,67.68 275.2,66.62 274.45,65.88 274.39,65.88 274.32,65.91 274.25,65.92 274.22,65.96 272.96,65.96 272.88,65.88 272.6,65.88 272.25,66.23 272.25,66.33 272.26,66.33 272.26,66.79 272.27,66.8 272.81,66.8 272.81,67.31 272.28,67.31 272.26,67.33 272.26,67.57 272.29,67.6 272.79,67.6 272.81,67.6 272.81,67.62 272.82,67.63 272.82,68.09 272.81,68.1 272.8,68.11 272.79,68.12 272.33,68.12 272.28,68.17 272.28,68.89 272.82,69.42 276.26,69.42 276.84,70 276.84,70.73 276.94,70.84 277.37,70.84
+5V_RUN_AUDIO_UZ5 on TOP (solid shape): outline of 127 points within 275.6,70.99 278.14,73.81
+5V_RUN_PVDD_L on TOP (solid shape): outline of 138 points within 297.19,37.99 300.93,45.32
+5V_RUN_UZ4 on TOP (solid shape): 194.68,20.28 194.68,19.75 194.69,19.73 195.2,19.73 195.21,19.75 195.21,20.29 195.22,20.3 195.46,20.3 195.49,20.26 195.49,19.77 195.51,19.76 195.53,19.74 195.97,19.74 195.97,18.56 195.59,18.18 195.2,18.18 195.1,18.08 195.1,17.62 195.03,17.54 193.81,17.54 193.43,17.16 192.58,17.16 192.51,17.24 192.51,18.9 193.35,19.74 194.36,19.74 194.41,19.74 194.42,19.74 194.42,20.29 194.43,20.3 194.66,20.3
+5V_TBT_VBUS on BOTTOM (solid shape): 25.63,89.99 25.63,89.08 25.41,88.86 25.07,88.86 24.49,89.45 23.99,89.45 23.89,89.55 23.89,90.02 24.08,90.21 25.41,90.21
+5V_TBT_VBUS on BOTTOM (solid shape): 37.34,97.08 37.34,94.51 36.37,93.54 34.95,93.54 34.71,93.78 34.71,94.92 35.32,95.53 35.32,96.35 35.34,96.37 35.34,97.24 35.42,97.32 37.09,97.32
+5V_TBTA_VBUS_D on TOP (solid shape): 44.05,99.1 44.05,98.07 43.65,97.67 43.65,95.33 43.51,95.19 42.62,95.19 42.11,95.7 42.11,97.55 42.27,97.85 42.11,98.15 42.11,98.76 42.66,99.31 43.84,99.31
+5V_TBTA_VBUS_D on BOTTOM (solid shape): outline of 154 points within 35.29,90.9 44.21,96.37
+5V_TSP on BOTTOM (solid shape): outline of 107 points within 116.09,87.22 125.45,92.79
+5V_USB_CHG_PWR on TOP (solid shape): 313.71,46.59 313.71,45.7 313.72,45.69 313.72,45.33 312.27,43.88 312.15,43.88 310.55,42.28 310.52,42.28 310.27,42.18 310.16,41.93 310.16,41.9 308.79,40.53 307.98,40.53 307.35,41.17 307.35,42.03 307.6,42.28 308.59,42.28 309.08,42.78 309.08,43.24 309.63,43.78 309.63,43.88 309.63,44.39 309.63,44.47 310.39,45.23 310.39,46.75 310.77,47.14 313.16,47.14
+5V_USB_CHG_PWR on TOP (solid shape): 312.35,58.77 312.35,56.73 312.26,55.91 312.95,55.47 313.27,55.47 313.61,55.13 313.61,54.25 313.36,54 313.33,54.01 313.08,54.05 312.83,54 312.02,54 312.02,54 311.37,54 310.31,55.06 309.34,56.03 309.34,59.09 309.39,59.14 311.98,59.14
+5V_USB_CHG_PWR on BOTTOM (solid shape): 313.95,47.01 313.95,46.17 313.88,45.85 313.95,45.53 313.95,45.1 313.07,44.23 312.95,44.23 312.37,43.96 312.19,43.34 311.28,42.44 310.27,42.44 309.76,41.93 309.76,40.7 309.69,40.64 309.69,40.21 309.44,39.96 307.75,39.96 307.62,39.83 307.54,39.83 307.35,39.64 307.35,39.11 307.34,39.09 307.31,38.94 307.34,38.79 307.35,38.78 307.35,37.61 307.22,37.48 306.08,37.48 305.96,37.61 305.96,40.86 306.2,41.1 307.09,41.1 307.28,41.29 307.28,43.13 307.73,43.58 310.77,43.58 310.88,43.69 310.98,43.69 310.98,43.78 311.16,43.96 311.16,45.94 311.16,45.94 311.16,46.5 311.92,47.26 313.7,47.26
+GND_CHASSIS on BOTTOM (solid shape): 303.2,99.28 303.2,98.22 302.9,97.91 284.93,97.91 284.74,98.1 284.74,99.42 284.88,99.56 302.93,99.56
+VBUS_DC_SS on TOP (solid shape): 11.84,49.5 13.19,49.5 14.18,48.51 14.18,44.09 13.87,43.78 11.23,43.78 11.1,43.91 11.1,46.3 11.13,46.32 11.13,46.58 10.62,47.08 9.15,47.08 8.29,47.95 4.65,47.95 4.45,48.15 4.45,49.68 4.64,49.87 11.47,49.87
+VCC_1P8 on BOTTOM (solid shape): 131.67,60.75 131.67,60.36 131.64,60.34 131.45,60.17 131.45,59.91 131.45,59.87 131.42,59.85 131.38,59.83 130.94,59.83 130.57,60.2 130.57,60.76 130.64,60.84 131.58,60.84
+VCC_CORE on TOP (solid shape): outline of 5275 points within 73.52,52.6 120.72,79.39
+VCC_CORE on BOTTOM (solid shape): outline of 303 points within 69.44,65.55 88.24,74.49
+VCC_CORE on BOTTOM (solid shape): outline of 326 points within 114.62,52.78 119.46,55.71
+VCC_CORE on BOTTOM (solid shape): outline of 512 points within 112.69,63.35 119.79,66.18
+VCC_GT on TOP (solid shape): outline of 2372 points within 73.64,53.78 110.55,65.52
+VCC_GT on BOTTOM (solid shape): outline of 1798 points within 69.28,57.46 112.58,65.36
+VCC_GTUS on BOTTOM (solid shape): outline of 992 points within 103.36,53.1 113.88,54.96
+VCC_SA on TOP (solid shape): 86.49,80.03 86.49,78.3 86.09,77.89 82.94,77.89 82.56,78.28 82.56,79.9 82.94,80.28 86.24,80.28
+VCC_SA on TOP (solid shape): 124.46,56.63 124.46,55.64 124.43,55.57 124.36,55.53 124.12,55.42 124.04,55.18 124.04,55.12 123.94,55.12 123.76,55.3 122.36,55.3 122.31,55.35 122.31,56.39 122.61,56.69 124.4,56.69
+VCC_SA on TOP (solid shape): 124.46,56.63 124.46,55.64 124.43,55.57 124.36,55.53 124.12,55.42 124.04,55.18 124.04,55.12 123.94,55.12 123.87,55.19 122.48,55.19 122.31,55.35 122.31,56.39 122.61,56.69 124.4,56.69
+VCC_SA on TOP (solid shape): 121.98,64.5 122.02,64.09 122.41,63.99 122.88,63.99 123.09,63.77 123.09,63.45 123.52,63.02 123.52,60.98 123.77,60.74 123.77,59.19 123.7,59.13 123.22,59.13 123.01,58.92 122.23,58.92 122.1,59.05 122.1,60.11 122,60.22 121.7,60.22 121.59,60.32 121.59,61.41 122.03,61.84 122.03,62.48 121.59,62.91 121.59,63.85 121.54,63.9 121.54,64.15 121.45,64.15 121.25,64.36 121.25,64.66 121.37,64.79 121.7,64.79
+VCC_SA on BOTTOM (solid shape): 123.99,55.56 123.99,54.68 123.98,54.67 123.96,54.55 123.98,54.43 123.99,54.42 123.99,54.29 123.89,54.19 122.71,54.19 122.29,54.62 122.29,55.62 122.42,55.76 123.79,55.76
+VCC_SA on BOTTOM (solid shape): 86.36,80.3 86.36,80.28 86.4,80.13 86.46,79.99 86.46,78.5 83.96,76 80.32,76 79.79,76.54 79.79,79.62 80.65,80.48 86.18,80.48
+VCC_SA on BOTTOM (solid shape): outline of 329 points within 119.97,63.6 124.34,66.21
+VCC_SFR_OC on TOP (solid shape): 123.77,29.4 124.65,29.4 124.84,29.21 124.84,27.89 124.65,27.7 124.33,27.7 123.86,28.17 121.2,28.17 121.04,28.34 121.04,29.23 121.16,29.36 122.87,29.36 123.07,29.56 123.62,29.56
+VCC_SFR_OC on TOP (solid shape): 124.63,54.76 124.64,54.75 124.71,54.62 124.84,54.54 124.85,54.54 125.01,54.38 125.01,54.34 124.98,54.26 124.91,54.23 124.59,53.91 124.9,53.57 124.97,53.54 125,53.47 125,53.31 124.87,53.05 124.99,52.79 125.01,52.77 125.01,52.69 124.87,52.41 125.01,52.14 125.01,52.05 124.87,51.77 125.01,51.5 125.01,51.41 124.9,51.27 124.88,51.09 124.88,51.07 124.82,51.01 124.57,51.01 124.52,51.06 124.52,51.53 124.62,51.77 124.52,52.02 124.52,52.13 124.64,52.41 124.52,52.68 124.52,52.82 124.61,53.15 124.35,53.38 124.34,53.39 124,53.72 124,54.73 124.11,54.84 124.55,54.84
+VDDA_AVDD1 on TOP (solid shape): 305.57,33.42 305.57,32.67 305.56,32.62 305.57,32.53 305.58,32.51 305.67,32.37 305.81,32.28 305.82,32.27 306.58,31.51 308.36,31.51 308.62,31.26 308.62,29.74 307.85,28.97 307.85,28.4 307.73,28.28 307.22,28.28 307.15,28.34 307.15,29.23 307.54,29.61 307.54,30.63 307.47,30.69 307.22,30.94 305.75,30.94 305.31,31.38 305.31,32.09 304.88,32.52 304.89,32.55 304.79,32.92 304.4,32.98 304.39,32.97 303.73,32.97 303.28,33.42 302.33,33.42 302.27,33.48 302.27,33.55 302.33,33.61 305.38,33.61
+VSS_PLL on TOP (solid shape): 300.54,72 300.54,71.09 300.21,70.76 300.21,70.16 300.47,69.89 300.48,69.88 300.48,69.81 300.47,69.81 300.47,69.2 301.08,69.2 301.08,68.17 300.44,68.17 300.39,68.22 300.39,68.39 300.25,68.52 300.25,68.85 299.93,69.18 299.93,69.91 299.7,70.14 299.7,70.83 300.18,71.32 300.18,72 300.28,72.1 300.44,72.1
GND on TOP (solid shape): 46.83,90.57 46.83,89.59 46.45,89.21 39.67,89.21 39.16,89.72 39.16,90.57 39.5,90.91 46.49,90.91
GND on TOP (solid shape): 86.49,82.19 86.49,81.04 86.24,80.79 82.81,80.79 82.56,81.04 82.56,82.06 83.06,82.57 86.11,82.57
GND on TOP (solid shape): 87.34,20.77 87.34,17.46 86.84,16.96 84.3,16.96 84.04,17.21 84.04,20.77 84.17,20.89 87.22,20.89
GND on TOP (solid shape): 150.25,109.24 150.25,107.71 150.12,107.59 148.47,107.59 148.21,107.84 148.21,109.24 148.47,109.49 149.99,109.49
GND on TOP (solid shape): 153.94,106.94 153.94,105.67 153.68,105.42 150.51,105.42 150.38,105.55 150.38,106.94 150.64,107.2 153.68,107.2
GND on TOP (solid shape): 158.25,67.96 158.25,65.04 157.87,64.66 156.85,64.66 156.6,64.92 156.6,68.09 156.72,68.22 157.99,68.22
GND on TOP (solid shape): 173.76,105.28 173.76,100.42 173.47,100.13 172.45,100.13 172.04,100.54 172.04,105.2 172.37,105.54 173.5,105.54
GND on TOP (solid shape): 174.56,20.05 174.56,16.58 174.23,16.25 171.31,16.25 170.53,17.03 170.53,20.36 170.9,20.72 173.89,20.72
GND on TOP (solid shape): 24.72,45.55 25.29,45.55 25.53,45.31 25.53,44.39 25.43,44.29 21.87,44.29 21.75,44.42 21.75,45.48 21.82,45.56 24.72,45.56
GND on TOP (solid shape): 144.22,106.61 144.22,105.38 144.13,105.3 143.12,105.3 143.04,105.38 143.04,106.59 143.11,106.67 144.16,106.67
GND on TOP (solid shape): 135.35,107.69 135.35,106.63 135.34,106.62 135.3,106.62 134.05,106.62 133.94,106.74 133.94,107.72 134.07,107.85 135.19,107.85
GND on TOP (solid shape): 141.45,103.02 141.45,101.93 141.34,101.82 139.06,101.82 138.93,101.94 138.93,102.92 139.2,103.19 141.29,103.19
GND on TOP (solid shape): 9.09,94.91 9.54,94.91 10.13,94.32 10.13,93.72 9.74,93.32 9.73,93.32 9.57,93.16 9.25,93.16 7.71,94.7 7.71,95.21 8.79,95.21
GND on TOP (solid shape): 58.72,44.63 58.72,41.63 58.54,41.45 57.66,41.45 57.33,41.77 57.33,44.62 57.34,44.62 57.34,44.88 57.41,44.95 58.4,44.95
GND on TOP (solid shape): 169.11,35.13 169.11,34.31 169.68,33.74 169.68,32.72 169.23,32.28 168.47,32.28 168.47,33.74 168.72,33.99 168.72,35.26 168.79,35.32 168.92,35.32
GND on TOP (solid shape): 307.75,90.95 307.9,90.95 307.94,90.91 308.78,90.91 309,90.7 309,89.93 308.74,89.68 306.84,89.68 306.68,89.68 306.39,89.97 306.39,90.78 306.56,90.95
GND on TOP (solid shape): 168.88,118.5 168.88,117.43 168.24,116.79 167.15,116.79 166.63,117.32 165.77,117.32 165.66,117.42 165.66,118.81 165.74,118.89 168.48,118.89
GND on TOP (solid shape): 182.71,98.57 182.71,92.09 182.02,91.41 181.41,91.41 180.14,92.68 180.14,95.67 180.55,96.08 180.55,96.92 180.32,97.15 179.79,97.15 179.79,98.72 180.04,98.98 182.3,98.98
GND on TOP (solid shape): 44.59,49.46 46.43,49.46 46.52,49.38 46.52,48.59 46.22,48.29 41.74,48.29 41.64,48.39 40.56,48.39 40.34,48.61 40.34,49.44 41.27,50.37 43.69,50.37
GND on TOP (solid shape): 35.95,10.11 35.95,5.16 35.69,4.91 33.22,4.91 32.96,5.16 32.96,8.34 32.78,8.51 32.78,8.6 32.7,8.6 32.64,8.65 31.06,8.65 30.99,8.72 30.99,9.86 31.44,10.31 35.76,10.31
GND on TOP (solid shape): 160.22,39.32 160.22,38.44 160.41,38.25 160.41,37.74 159.21,37.74 159.01,37.93 159.01,38.25 158.81,38.45 158.55,38.45 158.12,38.88 158.12,39.64 159.9,39.64
GND on TOP (solid shape): 21.66,75.27 21.66,74.95 21.53,74.82 20.9,74.82 20.71,74.63 20.71,73.3 20.45,73.04 18.17,73.04 17.91,73.3 17.91,74.82 18.29,75.2 19.37,75.2 19.56,75.39 21.53,75.39
GND on TOP (solid shape): 114.64,110 114.64,109.26 114.53,109.16 112.83,109.16 112.37,108.7 112.37,108.57 111.7,108.57 111.52,108.76 111.52,109.26 111.52,109.27 111.52,109.72 112.03,110.23 114.41,110.23
GND on TOP (solid shape): 77.84,67.76 83.84,67.76 84.02,67.58 84.02,66.03 84.67,65.38 90.53,65.38 91.04,64.87 91.04,63.74 90.32,63.02 83.44,63.02 82.21,64.25 74.79,64.25 73.88,65.16 73.88,66.18 75.51,67.81 77.79,67.81
GND on TOP (solid shape): 124.85,30.5 124.85,29.74 124.72,29.61 123.75,29.61 123.75,29.68 123.63,29.68 123.58,29.74 122.94,29.74 122.69,29.48 121.11,29.48 120.91,29.48 120.66,29.74 120.66,31.26 121.01,31.62 123.73,31.62
GND on TOP (solid shape): 128.95,85.13 128.95,83.25 128.91,83.22 128.88,83.2 127.9,82.21 127.9,81.82 127.44,81.36 126.35,81.36 126.07,81.64 126.07,82.95 126.83,83.71 126.83,85.21 127.06,85.44 127.06,85.44 128.63,85.44
GND on TOP (solid shape): 131.86,104.99 131.86,104.32 131.75,104.21 129.09,104.21 128.85,104.45 128.85,105.29 129.17,105.62 131.23,105.62
GND on TOP (solid shape): 132.91,117.43 132.91,116.65 132.84,116.58 130.62,116.58 130.62,116.8 130.48,116.95 129.64,116.95 129.44,116.74 129.44,115.3 129.4,115.26 128.86,115.26 128.79,115.32 128.79,117.1 129.65,117.96 132.38,117.96
GND on TOP (solid shape): 287.42,86.07 287.42,83.09 287.04,82.71 284.72,82.71 284.62,82.82 284.62,84.02 284.04,84.59 284.04,85.32 284.08,85.35 285.49,85.35 285.49,85.35 285.69,85.54 285.69,85.65 285.73,85.69 285.73,86.13 285.79,86.19 287.3,86.19
GND on TOP (solid shape): 305.38,28.72 305.38,28.28 305.5,28.15 305.5,27.51 305.44,27.45 304.93,27.45 304.87,27.51 304.87,27.89 304.86,27.91 304.86,27.92 304.84,27.92 304.81,27.96 304.36,27.96 304.3,28.02 304.3,28.66 304.42,28.78 305.31,28.78
GND on TOP (solid shape): 5.38,24.19 5.38,20.24 5.29,20.15 4.77,20.15 4.58,20.34 4.58,20.93 4.45,21.06 3.27,21.06 3.16,21.17 3.16,23.66 3.9,24.41 5.17,24.41
GND on TOP (solid shape): 47.83,101.45 47.83,100.56 47.06,99.79 45.93,99.79 45.49,99.35 45.49,98.15 45.96,97.68 45.96,96.86 46,96.83 46,94.82 45.74,94.57 44.13,94.57 43.9,94.79 43.9,97.72 44.22,98.03 44.22,101.47 44.51,101.77 47.5,101.77
GND on TOP (solid shape): 120.02,106.96 120.02,105.38 120.02,105.37 120.32,105.07 121.41,105.07 121.49,104.98 121.4,103.75 119.26,103.75 118.82,104.19 118.82,106.79 119.08,107.04 119.94,107.04
GND on TOP (solid shape): 125.94,107.69 125.94,107.19 125.44,106.69 125.44,106.18 125.37,106.11 124.86,106.11 124.44,106.53 123.57,106.53 123.41,106.36 123.41,105.6 123.19,105.38 122.88,105.38 122.65,105.6 122.65,107.66 122.81,107.81 125.82,107.81
GND on TOP (solid shape): 216.23,8.27 216.23,7.74 216.46,7.51 216.62,7.51 216.79,7.33 216.79,6.18 216.6,5.99 215.91,5.99 215.8,6.09 215.8,6.66 215.27,7.19 215.27,8.34 215.4,8.46 216.03,8.46
GND on TOP (solid shape): 29.77,55.75 29.77,54.48 29.7,54.4 28.55,54.4 28.5,54.35 28.45,54.35 28.43,54.32 28.4,54.32 28.4,54.3 28.3,54.2 28.3,54.14 28.25,54.09 27.87,54.09 27.87,54.45 27.87,54.45 28.17,54.45 28.45,54.73 28.45,55.8 28.63,55.97 29.55,55.97
GND on TOP (solid shape): 34.85,21.43 34.85,15.31 33.91,14.37 26.68,14.37 26.24,14.8 26.24,17.85 26.54,18.15 29.04,18.15 29.37,18.48 29.37,19.32 29.62,19.57 30.47,19.57 30.61,19.43 30.61,19.02 31.48,18.15 32.41,18.15 32.78,18.52 32.78,21.11 33.15,21.48 34.8,21.48
GND on TOP (solid shape): 305.5,46.06 306.65,46.06 308.3,44.4 309.44,44.4 309.44,44.02 308.93,43.52 307.22,43.52 307.09,43.64 304.3,43.64 304.11,43.83 304.11,44.28 304.23,44.4 305.25,44.4 305.44,44.6 305.44,45.36 305.12,45.67 303.6,45.67 303.41,45.87 303.41,46.37 305.19,46.37
GND on TOP (solid shape): 313.19,63 313.19,61.28 312.97,61.05 312.51,61.05 312.2,61.37 312.2,61.41 312.15,61.41 312.05,61.52 311.61,61.52 311.45,61.68 311.45,62.27 311.57,62.39 311.57,63.66 311.58,63.67 311.68,63.72 311.75,63.79 312.4,63.79
GND on TOP (solid shape): 11.18,99.79 11.18,99.21 11.07,99.1 10.81,99.1 10.8,99.09 9.73,99.09 9.31,98.68 8.75,98.68 8.46,98.39 7.31,98.39 7.24,98.46 7.24,98.8 7.3,98.86 7.59,98.86 7.69,98.96 7.83,98.96 8.84,99.97 11,99.97
GND on TOP (solid shape): 196.06,7.24 196.06,5.82 195.55,5.31 195.55,2.71 195.47,2.63 192.86,2.63 192.76,2.73 192.76,3.02 192.83,3.09 193.65,3.09 193.9,3.35 193.9,5.23 193.69,5.44 193.23,5.44 192.75,5.92 192.75,7.09 193.03,7.37 195.92,7.37
GND on TOP (solid shape): 139.85,115.59 140.09,115.59 140.34,115.33 140.72,115.33 140.98,115.08 142.6,115.08 142.8,114.88 142.8,114.24 142.2,114.24 141.96,114.01 140.52,114.01 140,114.53 138.21,114.53 137.91,114.83 137.91,115.75 138.14,115.99 139.45,115.99
GND on TOP (solid shape): 142.08,110.58 142.08,109.94 142.09,109.94 142.39,109.63 143.17,109.63 143.24,109.57 143.24,109.41 143.18,109.35 142.16,109.35 142.08,109.27 142.08,108.91 142.04,108.86 140.41,108.86 138.88,107.32 138.06,107.32 138.01,107.38 138.01,108.08 138.13,108.2 138.78,108.2 138.92,108.34 138.92,109.5 139.04,109.62 140.06,109.62 140.38,109.94 140.38,110.58 140.4,110.6 142.07,110.6
GND on TOP (solid shape): 148.09,66.44 148.09,65.68 147.96,65.55 147.55,65.55 147.44,65.55 147.4,65.51 147.38,65.51 147.38,65.48 147.18,65.29 146.96,65.29 146.76,65.09 146.76,64.58 146.73,64.55 146,64.55 145.99,64.54 145.75,64.54 145.66,64.63 145.66,65.49 145.66,65.5 145.67,65.6 145.66,65.71 145.66,65.72 145.66,66.46 145.76,66.57 147.96,66.57
GND on TOP (solid shape): 121.87,62.43 121.87,61.92 121.44,61.49 121.44,60.22 121.59,60.06 121.82,60.06 121.95,59.94 121.95,59.66 121.71,59.42 120.51,59.42 120.35,59.26 119.77,59.26 119.58,59.45 119.58,59.47 119.48,59.67 119.28,59.77 119.26,59.77 119.03,60 119.03,60.37 119.14,60.47 119.14,62.47 119.51,62.83 121.47,62.83
GND on TOP (solid shape): 131.71,112.94 131.71,112.23 131.83,112.11 131.83,112.1 131.91,112.02 132.77,112.02 132.85,111.93 132.85,111.72 132.8,111.67 131.73,111.67 131.71,111.64 131.71,111.23 131.69,111.22 129.96,111.22 129.96,111.22 129.29,110.55 129.29,110.18 128.91,109.79 127.67,109.79 127.57,109.89 127.57,110.37 127.79,110.58 128.32,110.58 128.73,110.99 128.73,111.84 128.87,111.98 129.74,111.98 129.96,112.2 129.96,112.94 130.01,112.99 131.65,112.99
GND on TOP (solid shape): 36.02,80.4 36.18,80.26 36.38,80.21 36.48,80.21 36.94,79.75 36.94,79.42 36.85,79.34 36.28,79.34 36.26,79.36 35.45,79.36 35.38,79.43 34.84,79.43 34.75,79.34 34.52,79.34 34.45,79.41 34.45,79.52 34.46,79.54 34.51,79.72 34.46,79.9 34.45,79.91 34.45,80.09 34.47,80.12 34.61,80.26 35.39,80.26 35.53,80.4
GND on TOP (solid shape): 156.66,117.94 156.66,116.62 156.6,116.55 156.6,114.8 156.04,114.24 156.04,113.36 156.06,113.34 156.06,113.32 156.16,113.21 156.24,113.14 156.26,113.14 156.37,113.03 156.37,111.37 156.37,111.25 156.3,111.17 156.27,111.17 155.96,111.17 155.89,111.18 155.82,111.17 155.76,111.17 155.73,111.14 155.63,111.14 155.58,111.09 155.58,110.23 155.48,110.13 155.4,110.13 155.3,110.23 155.3,111.27 154.92,111.65 154.92,112.72 155.3,113.1 155.3,114.56 154.94,114.92 154.94,117.87 155.2,118.13 156.47,118.13
GND on TOP (solid shape): 182.5,120 182.5,119.96 182.53,119.73 182.59,119.51 182.66,119.38 182.74,119.26 182.8,119.18 182.84,119.14 182.94,119.04 183.02,118.98 183.1,118.93 183.27,118.84 183.45,118.78 183.59,118.76 183.73,118.75 183.75,118.75 187.4,118.75 187.4,118.5 183.75,118.5 182.7,118.92 182.25,119.96 182.25,120.55 182.5,120.55
GND on TOP (solid shape): 52.96,88.03 54.23,88.03 54.49,87.78 54.49,87.39 54.74,87.14 55.76,87.14 55.86,87.04 55.86,85.47 54.74,84.35 52.95,84.35 52.69,84.61 52.69,84.99 53.23,85.52 54.49,85.52 54.49,85.47 54.49,85.42 54.51,85.37 54.53,85.32 54.56,85.27 54.6,85.24 54.64,85.2 54.69,85.18 54.74,85.16 54.79,85.14 54.84,85.14 54.9,85.14 54.95,85.16 55,85.18 55.04,85.2 55.09,85.24 55.12,85.27 55.15,85.32 55.17,85.37 55.19,85.42 55.2,85.47 55.2,85.52 55.19,85.58 55.17,85.63 55.15,85.67 55.12,85.72 55.09,85.76 55.04,85.79 55,85.82 54.95,85.84 54.9,85.85 54.84,85.85 54.79,85.85 54.74,85.84 54.69,85.82 54.64,85.79 54.6,85.76 54.56,85.72 54.53,85.67 54.51,85.63 54.49,85.58 54.49,85.52 53.23,85.52 53.23,86.8 53,87.02 51.65,87.02 51.46,87.21 51.46,87.93 51.54,88 52.89,88 52.94,88.05
GND on TOP (solid shape): 315.4,42.75 316.02,42.01 316.86,42.5 319.85,42.5 320.14,42.57 320.35,42.76 320.36,42.77 320.4,42.8 325.7,42.8 325.7,40.4 325.19,40.4 325.19,41.13 324.89,41.42 315.98,41.42 315.88,41.52 315.17,41.96 314.89,42.75 314.89,44.59 315.4,44.59
GND on TOP (solid shape): outline of 87 points within 69.73,74.82 74.38,77.74
GND on TOP (solid shape): 2.85,8.4 4.45,10 6.05,8.4 6.05,6.67 7.78,5.21 8.45,3.05 8.45,3.05 8.45,0.25 2.1,0.25 1.57,0.47 1.35,1 1.35,3.05 1.36,3.05 1.36,5.53 2.04,6.19 2.85,6.67
GND on TOP (solid shape): outline of 116 points within 52.7,57.23 63,75.5
GND on TOP (solid shape): 109.15,1.99 113.1,6.1 117.15,2.1 117.15,2.04 117.15,0 116.55,0 113.15,-1.9 109.75,0 109.15,0
GND on TOP (solid shape): 237,1.46 240.98,5.5 245,1.5 245,1.43 245,0 244.71,0 241,-2.5 237.29,0 237,0
GND on TOP (solid shape): 322.75,71.31 322.26,70.47 323,69.85 324.4,69.85 324.4,56.9 320.4,56.9 320.36,56.92 320.35,56.94 320.14,57.13 319.85,57.2 316.86,57.2 316.02,57.69 315.4,56.95 315.4,55.01 314.89,55.01 314.89,56.95 315.28,57.87 316.22,58.21 317.33,59.32 323.48,59.32 323.89,59.73 323.89,69.34 323,69.34 321.8,70.2 322.24,71.61 322.24,73.17 322.75,73.17
GND on TOP (solid shape): 17.48,68.49 17.48,65.79 15.72,64.03 4.51,64.03 4.09,63.74 3.59,63.64 3.26,63.64 3.26,59.55 2.89,58.66 2,58.29 1.21,58.29 1.21,35.31 2,35.31 2.87,34.96 3.26,34.11 2.75,34.11 2.51,34.6 2,34.8 0.7,34.8 0.7,58.8 2,58.8 2.53,59.02 2.75,59.55 2.75,64.15 3.59,64.15 4.12,64.37 4.34,64.9 4.34,67.4 13.37,67.4 14.11,68.03 13.61,68.86 13.61,69.23 16.74,69.23
GND on TOP (solid shape): 247.31,15.46 247.3,15.2 247.3,14.8 246.15,14.8 245.93,14.8 245.71,14.77 242.9,11.74 245.33,8.4 245.74,8.32 246.15,8.3 247.3,8.3 247.3,7.55 246.15,7.55 242.15,11.55 246.15,15.55 247.07,15.55 247.07,15.55 247.32,15.55
GND on TOP (solid shape): 268.15,108.55 270.18,107.27 269.9,104.89 270.75,98.08 267.36,104.05 265.65,104.05 265.65,105.05 268.15,105.05 269.4,106.3 268.15,107.55 266.65,107.55 266.65,108.55
GND on TOP (solid shape): 306.7,115.19 307.12,114.77 307.18,114.69 307.2,114.59 307.2,113.55 307.86,111.96 309.45,111.3 309.95,111.3 311.89,110.49 312.7,108.55 312.7,101.95 313.06,101.06 313.95,100.7 323.8,100.7 325.74,99.89 326.55,97.95 326.55,90.1 325.15,90.1 324.62,89.88 324.4,89.35 324.4,87.35 323,87.35 322.26,86.73 322.75,85.89 322.75,85.36 322.24,85.36 322.24,85.59 321.8,87 323,87.86 323.89,87.86 323.89,89.35 324.26,90.24 325.15,90.61 326.04,90.61 326.04,97.95 325.38,99.53 323.8,100.19 317.38,100.19 312.97,95.78 308.62,95.78 306.58,97.81 306.58,109.42 305.11,110.89 305.1,110.89 305.1,118.58 306.7,118.58
GND on TOP (solid shape): outline of 92 points within 0.25,79.65 75.39,119.65
GND on TOP (solid shape): outline of 104 points within 30.82,78.69 33.91,82.39
GND on TOP (solid shape): outline of 152 points within 85.53,38.34 288,120.8
GND on TOP (solid shape): outline of 113 points within 1.35,0.25 327.8,32.72
GND on BOTTOM (solid shape): 46.55,71.5 46.55,68.69 46.14,68.28 42.81,68.28 42.06,69.02 42.06,71.39 42.48,71.8 46.25,71.8
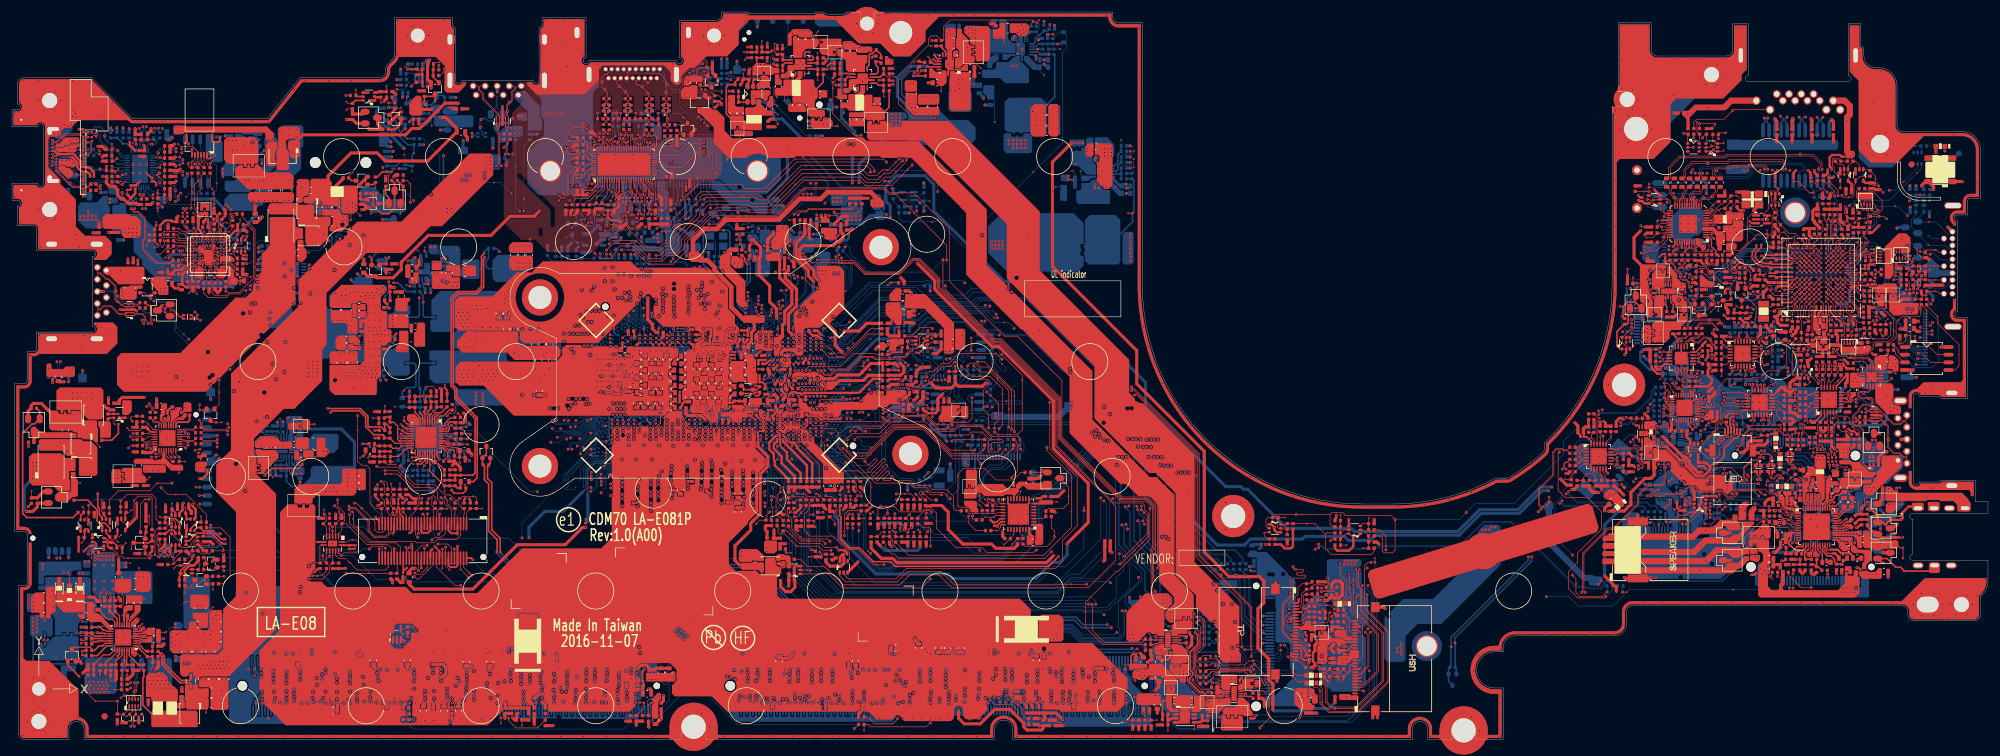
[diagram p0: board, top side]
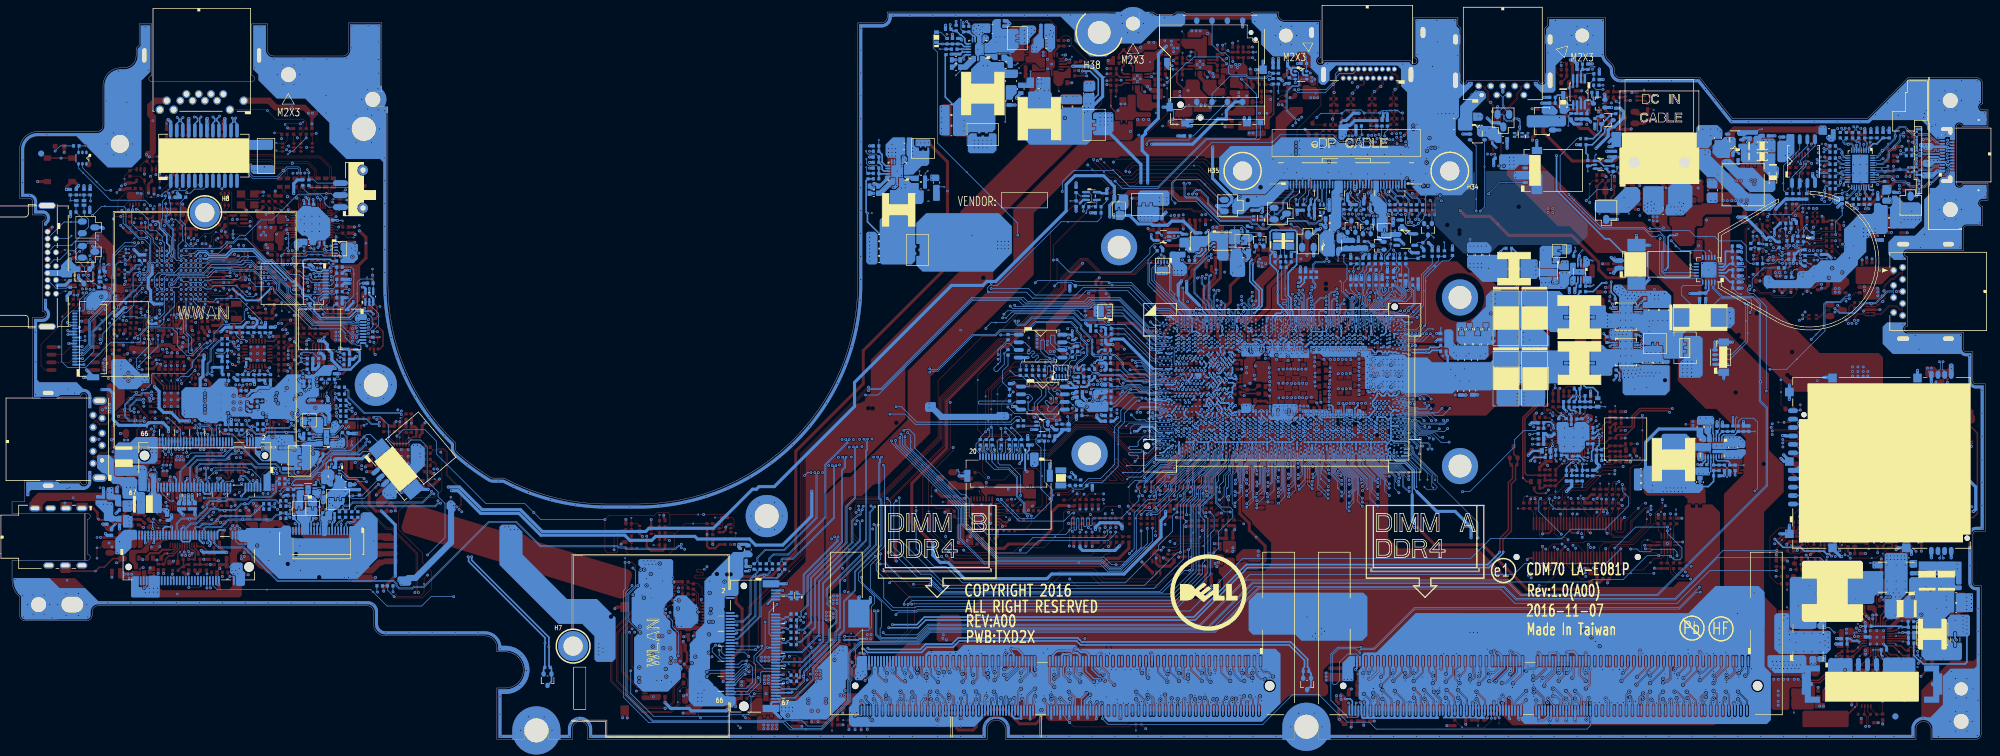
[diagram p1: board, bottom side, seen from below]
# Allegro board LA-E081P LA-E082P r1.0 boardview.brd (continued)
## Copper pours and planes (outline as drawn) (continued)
GND on BOTTOM (solid shape): 46.66,90.62 46.66,89.25 46.5,89.08 45.01,89.08 44.86,89.24 44.86,90.71 44.98,90.82 46.46,90.82
GND on BOTTOM (solid shape): 81.35,67.9 81.35,65.34 80.9,64.89 73.34,64.89 72.83,65.4 72.83,67 73.87,68.03 81.22,68.03
GND on BOTTOM (solid shape): 81.59,57.96 81.59,55.74 81.31,55.45 73.73,55.45 73.54,55.64 73.54,57.92 73.77,58.15 81.39,58.15
GND on BOTTOM (solid shape): 85.48,104.03 85.48,102.82 85.41,102.76 84.14,102.76 83.83,103.08 83.83,103.71 84.21,104.09 85.41,104.09
GND on BOTTOM (solid shape): 86.49,82.31 86.49,81.04 86.24,80.79 82.81,80.79 82.43,81.17 82.43,81.81 83.19,82.57 86.24,82.57
GND on BOTTOM (solid shape): 150.12,109.08 150.12,107.71 149.99,107.59 148.6,107.59 148.21,107.97 148.21,109.11 148.47,109.37 149.84,109.37
GND on BOTTOM (solid shape): 159.03,47.46 159.03,45.51 158.76,45.23 157.99,45.23 157.62,45.6 157.62,47.5 157.77,47.64 158.85,47.64
GND on BOTTOM (solid shape): 174.06,105.17 174.06,100.54 173.87,100.35 172.47,100.35 172.41,100.41 172.41,105.24 172.53,105.36 173.87,105.36
GND on BOTTOM (solid shape): 186.23,84.07 186.23,79.26 185.86,78.89 184.64,78.89 184.36,79.16 184.36,83.87 184.79,84.31 186,84.31
GND on BOTTOM (solid shape): 288.42,95.15 288.42,94.32 287.99,93.89 284.72,93.89 284.55,94.06 284.55,95.2 284.74,95.4 288.17,95.4
GND on BOTTOM (solid shape): 5.34,24.08 5.34,21.35 5.15,21.16 2.61,21.16 2.48,21.29 2.48,24.15 2.61,24.28 5.15,24.28
GND on BOTTOM (solid shape): 48.31,53.45 48.31,52.35 48.25,52.29 45.63,52.29 45.46,52.46 45.46,53.45 45.74,53.73 48.03,53.73
GND on BOTTOM (solid shape): 58.77,44.88 58.77,41.5 58.61,41.34 57.73,41.34 57.36,41.7 57.36,44.67 57.69,45 58.65,45
GND on BOTTOM (solid shape): 122.74,23 122.74,18.12 122.04,17.42 114.99,17.42 113.99,16.41 103.87,16.41 103.03,17.25 103.03,23.7 103.7,24.36 121.38,24.36
GND on BOTTOM (solid shape): 175.58,93.74 175.58,92.86 175.46,92.73 174.25,92.73 174.12,92.86 174.12,93.68 174.25,93.81 175.52,93.81
GND on BOTTOM (solid shape): 153.96,106.97 153.96,105.75 153.73,105.52 150.53,105.52 150.38,105.67 150.38,106.69 150.76,107.07 153.86,107.07
GND on BOTTOM (solid shape): 48.56,45.07 48.56,44.1 48.33,43.86 46.27,43.86 46.21,43.93 46.21,44.27 46.32,44.38 46.32,45.04 46.48,45.2 48.44,45.2
GND on BOTTOM (solid shape): 310.9,33.36 310.9,30.88 310.77,30.75 309.31,30.75 308.23,31.83 308.23,32.91 307.98,33.17 307.41,33.17 307.28,33.29 307.28,34.56 307.54,34.82 309.44,34.82
GND on BOTTOM (solid shape): 156.66,118.75 156.66,116.46 156.49,116.3 156.49,114.78 155.87,114.15 155.54,114.15 154.87,114.83 154.87,118.38 155.36,118.87 156.54,118.87
GND on BOTTOM (solid shape): 9.02,94.21 10.78,94.21 11.01,93.98 11.01,93.42 10.76,93.16 9.16,93.16 8.16,94.16 7.24,94.16 7.07,94.33 7.07,94.53 7.14,94.61 8.26,94.61 8.29,94.63 8.59,94.63
GND on BOTTOM (solid shape): 78.75,94.13 78.75,93.24 78.55,93.05 76.14,93.05 75.77,92.68 75.77,90.67 75.67,90.57 74.05,90.57 74,90.62 74,93.79 74.58,94.38 78.49,94.38
GND on BOTTOM (solid shape): 53.08,91.65 53.07,91.63 53.07,91.55 53.09,91.47 53.09,88.94 53.5,88.54 53.5,87.29 53.24,87.04 50.58,87.04 49.08,88.54 49.08,91.84 49.54,92.3 52.43,92.3
GND on BOTTOM (solid shape): 311.01,45.39 311.01,44.07 310.75,43.81 307.24,43.81 307.07,43.64 307.07,41.38 306.92,41.23 306.15,41.23 306.13,41.21 305.76,41.21 305.68,41.29 305.68,43.3 305.68,45.06 306.16,45.54 310.85,45.54
GND on BOTTOM (solid shape): 11.5,29.47 11.5,28.15 11.44,28.09 10.19,28.09 9.91,27.81 9.91,27.46 9.71,27.26 5.53,27.26 5.34,27.07 5.34,25.93 5.14,25.72 4.53,25.72 4.39,25.86 4.39,29.44 4.48,29.53 11.44,29.53
GND on BOTTOM (solid shape): 35.47,20.57 35.47,15.03 34.64,14.2 26.83,14.2 26.1,14.93 26.1,17.85 26.25,17.99 26.92,17.99 26.93,17.99 32.14,17.99 32.26,18.1 32.82,18.1 33.02,18.3 33.02,18.69 33.03,18.7 33.03,20.75 33.22,20.94 35.1,20.94
GND on BOTTOM (solid shape): 43.45,50.34 43.76,50.34 43.85,50.25 43.85,49.4 44.04,49.21 45.7,49.21 45.74,49.17 45.74,48.3 45.69,48.25 43.02,48.25 43,48.27 41.77,48.27 41.66,48.39 40.49,48.39 40.27,48.62 40.27,49.52 41.09,50.34 43.45,50.34
GND on BOTTOM (solid shape): 90.25,67.86 90.25,65.17 90.15,65.07 89.7,65.07 89.49,64.86 89.49,63.96 88.62,63.09 83.52,63.09 82.93,63.68 82.93,65.28 83.07,65.43 88.24,65.43 88.75,65.94 88.75,67.73 89.12,68.09 90.02,68.09
GND on BOTTOM (solid shape): 305.31,44.04 305.31,43.74 304.96,43.39 304.96,41.06 305.01,41.01 305.08,41.01 305.82,40.27 305.82,37.87 305.57,37.61 303.28,37.61 303.22,37.67 303.22,40.47 303.54,40.79 303.92,40.79 304.14,41.01 304.14,44.04 304.27,44.16 305.18,44.16
GND on BOTTOM (solid shape): 276.74,44.34 276.74,42.59 276.53,42.39 275.8,42.39 275.39,41.98 274.91,41.98 274.81,42.08 274.81,42.52 274.76,42.57 274.76,43.05 274.55,43.25 274.55,44.39 275.01,44.85 275.04,44.83 275.23,44.8 275.42,44.85 276.23,44.85
GND on BOTTOM (solid shape): 48.39,101.63 48.39,100.7 48.35,100.7 48.35,98.54 48.07,98.25 48,98.25 48,98.23 47.32,98.23 47.11,98.23 47.1,98.23 47,98.24 46.9,98.23 46.89,98.23 46.46,98.23 45.86,98.82 45.86,99.43 45.52,99.77 44.48,99.77 44.1,100.15 44.1,101.18 44.94,102.03 48,102.03
GND on BOTTOM (solid shape): 280.75,87.65 280.75,84.5 279.91,83.66 279.28,83.66 278.72,83.1 278.72,82.34 278.47,82.09 277.8,82.09 277.55,82.34 277.55,82.59 277.3,82.85 277.27,82.87 276.13,82.87 276.1,82.85 275.21,83.74 275.21,85.84 275.21,86.45 277.2,88.44 278.36,88.44 278.54,88.61 279.79,88.61
GND on BOTTOM (solid shape): 167.51,118.88 168.29,118.88 168.66,118.51 168.66,117.49 167.77,116.6 167.82,116.55 167.82,115.74 168.18,115.38 168.18,113.81 167.82,113.45 167.82,112.72 167.72,112.62 167.65,112.62 167.57,112.69 167.57,113.45 167.38,113.65 166.83,113.65 166.73,113.74 166.73,113.79 166.7,113.82 166.7,114.03 166.73,114.06 166.73,115.44 166.88,115.59 166.94,115.59 167.01,115.66 167.02,115.66 167.11,115.75 167.11,116.86 166.63,117.34 165.79,117.34 165.61,117.52 165.61,118.74 165.77,118.89 167.49,118.89
GND on BOTTOM (solid shape): 69.4,79.01 69.4,77.92 69.55,77.77 70.95,77.77 71.13,77.59 71.13,75.79 71.35,75.56 72.34,75.56 72.55,75.76 72.55,76.19 72.42,76.32 72.42,76.69 72.52,76.79 74.3,76.79 74.36,76.73 74.36,75.01 74.17,74.82 70.29,74.82 69.5,75.61 69.5,76.78 69.07,77.21 67.01,77.21 66.93,77.28 66.93,78.02 67.01,78.1 68.33,78.1 68.46,78.22 68.46,79.09 68.53,79.16 69.25,79.16
GND on BOTTOM (solid shape): 9.65,102.51 3.6,102.51 3.6,104.15 3.48,104.43 3.2,104.55 1.46,104.55 1.62,105.24 1.15,105.76 1.15,108.85 2.23,108.85 2.23,108.85 4.19,108.85 6.19,109.35 9.65,109.35
GND on BOTTOM (solid shape): 68.71,52.34 68.71,51.99 68.79,51.91 68.89,51.91 68.97,51.83 69.54,51.83 69.6,51.9 69.6,52.47 69.86,52.72 71.38,52.72 71.63,52.47 71.63,51.45 71.51,51.33 71.51,49.17 71.25,48.91 71.25,47.9 71,47.64 67.7,47.64 66.93,48.41 66.93,49.42 66.88,49.48 66.88,49.49 66.86,49.49 66.68,49.68 66.3,49.68 66.17,49.8 66.17,52.09 66.51,52.42 66.52,52.43 66.68,52.52 66.77,52.68 66.78,52.69 66.81,52.72 68.33,52.72
GND on BOTTOM (solid shape): 181.94,13.72 181.94,12.28 181.97,12.14 182.06,12.03 182.06,11.72 181.77,11.43 181.74,11.43 181.66,11.42 181.58,11.39 181.48,11.39 181.43,11.47 181.43,11.98 181.56,12.1 181.61,12.28 181.61,13.72 181.6,13.82 181.95,13.82
GND on BOTTOM (solid shape): 183.01,98.8 183.01,97 182.63,96.61 181.39,96.61 181.23,96.46 181.23,95.55 181.44,95.34 182,95.34 182.07,95.27 182.07,93.49 182,93.41 181.41,93.41 181.23,93.24 181.23,92.22 181.55,91.9 181.74,91.9 181.93,91.71 181.93,91.59 181.74,91.39 181.42,91.39 180.92,91.9 180.92,92.22 180.98,92.28 180.98,93.31 180.88,93.41 180.22,93.41 180.14,93.49 180.14,95.27 180.22,95.34 180.42,95.34 180.52,95.45 180.52,96.87 180.22,97.17 179.77,97.17 179.77,99.86 179.89,99.98 181.83,99.98
GND on BOTTOM (solid shape): 9.65,84.85 5.79,84.85 4.33,85.22 4.2,85.25 3.93,85.47 3.59,85.55 1.15,85.55 1.15,88.34 1.63,88.86 1.46,89.55 2.7,89.55 3.2,89.55 3.48,89.67 3.6,89.95 3.6,91.59 9.65,91.59
GND on BOTTOM (solid shape): 182.5,120 182.5,119.96 182.53,119.73 182.59,119.51 182.66,119.38 182.74,119.26 182.8,119.18 182.84,119.14 182.94,119.04 183.02,118.98 183.1,118.93 183.27,118.84 183.45,118.78 183.59,118.76 183.73,118.75 183.75,118.75 187.4,118.75 187.4,118.5 183.75,118.5 182.7,118.92 182.25,119.96 182.25,120.55 182.5,120.55
GND on BOTTOM (solid shape): 315.4,42.75 316.02,42.01 316.86,42.5 319.85,42.5 320.14,42.57 320.35,42.76 320.36,42.77 320.4,42.8 325.7,42.8 325.7,40.4 325.19,40.4 325.19,41.13 324.89,41.42 315.98,41.42 315.88,41.52 315.17,41.96 314.89,42.75 314.89,44.59 315.4,44.59
GND on BOTTOM (solid shape): 314.15,74.51 314.18,74.47 314.22,74.43 314.26,74.39 314.31,74.37 314.36,74.35 314.42,74.34 314.47,74.34 314.53,74.34 314.58,74.36 314.64,74.39 315.73,73.3 315.73,71.39 315.6,71.27 315.42,71.27 315.39,71.27 315.33,71.28 315.27,71.27 315.23,71.27 314.83,71.27 314.79,71.27 314.74,71.28 314.68,71.27 314.64,71.27 314.2,71.27 312.04,73.42 312.04,73.54 312.87,73.54 312.87,73.49 312.88,73.43 312.89,73.38 312.92,73.33 312.95,73.29 312.98,73.25 313.02,73.22 313.07,73.19 313.12,73.17 313.17,73.16 313.23,73.16 313.28,73.16 313.33,73.17 313.38,73.19 313.43,73.22 313.47,73.25 313.5,73.29 313.53,73.33 313.56,73.38 313.57,73.43 313.58,73.49 313.58,73.54 313.57,73.59 313.56,73.64 313.53,73.69 313.5,73.74 313.47,73.77 313.43,73.81 313.38,73.83 313.33,73.85 313.28,73.87 313.23,73.87 313.17,73.87 313.12,73.85 313.07,73.83 313.02,73.81 312.98,73.77 312.95,73.74 312.92,73.69 312.89,73.64 312.88,73.59 312.87,73.54 312.04,73.54 312.04,74.19 312.43,74.57 314.12,74.57
GND on BOTTOM (solid shape): 17.15,30.68 17.15,24.08 17.11,24 17.01,23.98 16.83,24 16.67,23.92 16.6,23.9 16.54,23.92 15.96,23.65 16.54,23.37 16.6,23.4 16.67,23.37 16.83,23.3 17.01,23.31 17.11,23.3 17.15,23.22 17.15,20.52 16.66,20.03 14.93,20.03 14.61,20.35 14.61,23.13 13.34,24.39 13.34,24.59 13.34,24.59 13.34,29.39 13.35,29.4 13.35,30.71 13.6,30.96 16.87,30.96
GND on BOTTOM (solid shape): 2.85,8.4 4.45,10 6.05,8.4 6.05,6.67 7.78,5.21 8.45,3.05 8.45,3.05 8.45,0.25 2.1,0.25 1.57,0.47 1.35,1 1.35,3.05 1.36,3.05 1.36,5.53 2.04,6.19 2.85,6.67
GND on BOTTOM (solid shape): outline of 106 points within 12.01,7.57 17.4,13.61
GND on BOTTOM (solid shape): outline of 117 points within 52.58,57.17 62.8,75.52
GND on BOTTOM (solid shape): 109.16,1.88 113.04,6.1 117.15,2.1 117.15,2 117.15,0 116.55,0 113.15,-1.9 109.75,0 109.16,0
GND on BOTTOM (solid shape): 6.36,94.23 6.36,94.04 7.02,93.37 7.66,93.37 8.03,92.99 8.03,92.23 10.59,89.67 10.59,85.18 12.12,83.64 15.47,83.64 16.52,82.59 16.52,80.57 15.6,79.65 13.61,79.65 13.61,79.94 14.11,80.77 13.37,81.4 4.34,81.4 4.34,84.8 4.12,85.33 3.59,85.55 1.15,85.55 1.15,88.34 1.64,89.18 0.9,89.8 0.25,89.8 0.25,92.1 4.04,92.1 4.88,91.61 5.5,92.35 5.5,94.26 5.57,94.33 6.25,94.33
GND on BOTTOM (solid shape): 17.47,68.53 17.47,65.7 15.8,64.02 4.5,64.02 4.46,63.99 4.06,63.73 3.59,63.64 3.26,63.64 3.26,59.55 2.89,58.66 2,58.29 1.21,58.29 1.21,35.31 2,35.31 2.34,35.27 2.65,35.13 2.65,34.43 2.37,34.7 2,34.8 0.7,34.8 0.7,58.8 2,58.8 2.53,59.02 2.75,59.55 2.75,64.15 3.59,64.15 4.12,64.37 4.34,64.9 4.34,67.4 13.37,67.4 14.11,68.03 13.61,68.86 13.61,69.23 16.77,69.23
GND on BOTTOM (solid shape): 237,1.4 240.95,5.5 245,1.5 245,1.44 245,0 244.71,0 241,-2.5 237.29,0 237,0
GND on BOTTOM (solid shape): 322.75,71.31 322.26,70.47 323,69.85 324.4,69.85 324.4,56.9 320.4,56.9 320.36,56.92 320.35,56.94 320.14,57.13 319.85,57.2 316.86,57.2 316.02,57.69 315.4,56.95 315.4,55.01 314.89,55.01 314.89,56.95 315.28,57.87 316.22,58.21 317.33,59.32 323.48,59.32 323.89,59.73 323.89,69.34 323,69.34 321.8,70.2 322.24,71.61 322.24,73.17 322.75,73.17
GND on BOTTOM (solid shape): 247.31,15.46 247.3,15.2 247.3,14.8 246.15,14.8 245.93,14.8 245.71,14.77 242.9,11.74 245.33,8.4 245.74,8.32 246.15,8.3 247.3,8.3 247.3,7.55 246.15,7.55 242.15,11.55 246.15,15.55 247.07,15.55 247.07,15.55 247.32,15.55
GND on BOTTOM (solid shape): 72.85,118.49 73.35,117.99 73.35,109.45 73.97,108.71 74.81,109.2 75.39,109.2 75.39,108.69 74.12,107.42 72.19,107.42 71.82,107.8 71.82,111.91 70.4,113.33 64.2,113.33 64.18,113.31 63.95,112.78 63.6,112.32 62.98,111.7 62.82,111.46 62.76,111.18 62.76,110.9 62.25,109.65 61,109.14 48.18,109.14 42.77,102.34 19.73,102.34 19.21,102.86 11.04,102.86 10.1,101.92 10.1,101.29 8.56,99.76 7.31,99.76 7,100.06 6.36,100.06 6.3,100 6.3,99.6 6.24,99.54 5.57,99.54 5.51,99.59 5.51,99.63 5.5,99.64 5.5,101.75 4.88,102.49 4.04,102 0.25,102 0.25,104.3 0.9,104.3 1.64,104.92 1.15,105.76 1.15,108.9 1.37,109.43 1.9,109.65 13.15,109.65 19.95,102.85 42.52,102.85 47.93,109.65 61,109.65 61.89,110.01 62.25,110.9 62.25,111.18 62.35,111.66 62.62,112.06 63.24,112.68 63.62,113.25 63.75,113.92 63.75,119.65 72.85,119.65
GND on BOTTOM (solid shape): outline of 237 points within 267.35,26.68 290.61,37.73
GND on BOTTOM (solid shape): 306.7,115.19 307.12,114.77 307.18,114.69 307.2,114.59 307.2,113.55 307.86,111.96 309.45,111.3 309.95,111.3 311.89,110.49 312.7,108.55 312.7,101.95 313.06,101.06 313.95,100.7 323.8,100.7 325.74,99.89 326.55,97.95 326.55,90.1 325.15,90.1 324.62,89.88 324.4,89.35 324.4,87.35 323,87.35 322.26,86.73 322.75,85.89 322.75,85.36 322.24,85.36 322.24,85.59 321.8,87 323,87.86 323.89,87.86 323.89,89.35 324.26,90.24 325.15,90.61 326.04,90.61 326.04,97.95 325.38,99.53 323.8,100.19 317.35,100.19 317.3,100.14 317.3,100.12 315.99,98.81 315.66,98.77 315.61,98.43 312.17,94.99 308.18,94.99 306.58,96.59 306.58,109.42 305.11,110.89 305.1,110.89 305.1,118.58 306.7,118.58
GND on BOTTOM (solid shape): outline of 117 points within 133.28,38.34 288,120.8
GND on BOTTOM (solid shape): outline of 121 points within 1.35,0.25 327.8,32.1
GND on BOTTOM (solid shape): outline of 1007 points within 85.53,90.37 127.64,120.55
GND on BOTTOM (solid shape): outline of 9526 points within 117.47,2.11 189.11,15.7
GND on BOTTOM (solid shape): outline of 10057 points within 36.04,2.56 104.49,25.48
GND on TOP: 88.99,80.87 86.91,82.96 84.57,82.96 81.66,85.87 81.66,95.71 83.06,97.11 83.06,104.08 84.69,105.72 84.69,109.2 86.29,109.2 87.13,108.71 87.75,109.45 87.75,113.67 88.03,113.95 95.05,113.95 95.05,113.41 94.77,112.17 96.01,112.45 110.09,112.45 111.33,112.17 111.05,113.41 111.05,115.2 114.45,115.2 114.45,113.74 115.61,112.57 115.61,109.69 116.14,109.17 116.14,105.56 115.7,105.12 114.42,105.12 114.33,105.04 114.33,103.82 117.85,100.3 117.85,93.98 116.46,92.59 114.56,92.59 110.59,88.62 108.55,88.62 108.46,88.53 107.55,88.53 107.55,89.16 107.02,89.16 107.02,89.07 106.38,89.07 106.38,88.17 107.34,88.17 107.34,88.19 107.4,88.19 107.4,88.17 107.19,87.96 107.19,87.26 106.33,86.4 104.19,86.4 104.02,86.22 104.02,85.89 104.06,85.85 104.79,85.85 104.83,85.8 104.83,84.9 104.4,84.47 100,84.47 96.41,80.87 ; 13 cut-outs
GND on BOTTOM: 88.24,90.76 90.86,90.76 92.03,89.59 92.03,85.66 87.08,80.7 82.65,80.7 81.23,82.13 67.99,82.13 66.48,83.64 66.48,85.66 72.03,91.2 72.03,93.35 73.09,94.41 85.12,94.41 85.53,94.01 85.53,93.47 ; 1 cut-out
GNDA on TOP (solid shape): 320.03,39.28 320.03,38.19 319.83,37.99 318.2,37.99 318.08,38.12 318.08,39.39 318.14,39.45 319.85,39.45
GNDA on TOP (solid shape): 305.69,42.88 306.2,42.88 306.2,43.45 306.84,43.45 307.15,43.13 308.68,43.13 308.68,42.63 308.55,42.5 307.41,42.5 306.58,41.67 303.66,41.67 303.47,41.48 303.47,41.29 303.15,40.98 302.52,40.98 302.52,41.86 303.15,41.86 303.41,42.12 303.41,43.33 303.54,43.45 305.69,43.45
GNDA on TOP (solid shape): 303.66,32.85 303.67,32.85 304.1,32.85 304.18,32.81 304.2,32.73 304.21,32.56 304.28,32.42 304.3,32.4 304.42,32.28 304.93,32.28 305.12,32.09 305.12,31.45 305.06,31.39 303.85,31.39 303.28,31.96 303.28,32.59 302.84,33.04 302.27,33.04 302.2,33.1 302.2,33.17 302.27,33.23 303.28,33.23
GNDA on TOP (solid shape): 308.42,34.38 308.42,33.8 309,33.23 309.98,33.23 310.03,33.18 309.99,33.13 310.1,32.51 310.54,32.97 310.55,33.06 310.63,33.1 312.87,33.1 313.19,32.78 313.19,32.02 312.87,31.7 310.46,31.7 310.14,31.39 309.25,31.39 308.87,31.77 307.6,31.77 307.28,32.09 307.28,34.5 307.41,34.63 308.18,34.63
VCCSA_B+ on TOP (solid shape): 71.34,79.27 71.34,78.04 71.25,77.95 69.8,77.95 69.73,78.02 69.73,79.32 69.86,79.44 71.16,79.44
VCCSA_B+ on BOTTOM (solid shape): 74.43,81.62 74.43,78.44 74.24,78.25 71.58,78.25 71.32,78.25 71.01,77.95 69.63,77.95 69.6,77.97 69.6,79.43 69.74,79.57 70.74,79.57 70.88,79.43 70.88,79.1 71.07,78.91 72.29,78.91 72.44,79.06 72.44,79.98 72.08,80.34 71.04,80.34 70.92,80.46 70.92,80.89 71.51,80.89 71.51,81.4 70.92,81.4 70.92,81.89 71.02,82 71.38,82 71.38,82 74.05,82
VIN_1.8VALW on TOP (solid shape): 125.82,109.73 125.82,108.29 125.73,108.2 124.36,108.2 124.15,107.99 123.74,107.99 123.64,108.1 123.64,108.68 123.64,108.68 123.64,108.84 123.99,109.19 124.11,109.19 124.27,109.36 124.27,109.5 124.31,109.67 124.27,109.84 124.27,110.16 124.32,110.21 125.35,110.21
VIN_1V_PRIM on TOP (solid shape): 130.43,116.61 130.43,116.45 130.52,116.36 133.85,116.36 133.91,116.3 133.91,115.3 133.32,114.71 131.88,114.71 131.2,114.03 131.2,113.24 131.16,113.2 129.82,113.2 129.68,113.33 129.68,116.68 129.78,116.78 130.27,116.78
VIN_1VS_VCCIO on TOP (solid shape): 137.19,114.62 137.9,114.62 138.3,114.22 138.36,114.22 140.03,114.22 140.23,114.01 140.23,113.72 140.29,113.67 141.95,113.67 141.99,113.63 141.99,112.44 141.61,112.06 141.61,110.89 141.56,110.84 139.3,110.84 139.25,110.89 138.82,110.89 138.44,111.27 138.44,112.67 137.8,113.3 137.42,113.3 137.17,113.56 137.01,113.56 136.98,113.59 137,114.62 137.18,114.62
+AC_IN on TOP (solid shape): 7.26,54.6 7.35,54.6 7.36,54.58 7.66,54.58 7.67,54.57 7.67,54.07 7.7,54.05 8.01,54.05 8.02,54.04 8.55,54.04 8.56,54.05 8.64,54.05 8.64,54.13 8.65,54.14 8.65,54.6 8.85,54.6 8.88,54.57 8.88,54.07 8.9,54.05 9.22,54.05 9.23,54.04 9.76,54.04 9.77,54.05 9.84,54.05 9.84,54.12 9.85,54.13 9.85,54.6 10.12,54.6 10.13,54.59 11.04,54.59 11.81,53.82 11.81,53.24 11.81,53.24 12.05,53 13.71,53 13.71,53 13.96,53 14.1,52.85 14.1,51.88 14.28,51.71 14.28,49.45 14.23,49.4 13.72,49.4 13.27,49.85 11.8,49.85 11.59,50.06 10.99,50.06 10.86,50.18 10.86,50.88 10.74,51.01 10.25,51.01 9.94,51.31 6.56,51.31 6.14,51.74 6.14,54.18 6.1,54.22 6.1,54.44 6.28,54.61 7.26,54.61
+BL_PWR_SRC on BOTTOM (solid shape): 108.51,92.67 108.51,91.46 109,90.98 109,89.2 109,88.38 109,88.26 109,87.5 109,87.39 109.39,86.99 109.39,84.89 109.4,84.88 109.4,84.76 109.53,84.63 109.53,84.58 109.58,84.58 109.6,84.56 109.69,84.56 109.7,84.57 110.14,84.57 111,83.71 111,81.12 110.09,80.21 108.65,80.21 108.42,80.43 108.42,82.24 108.59,82.41 108.59,83.99 108.59,83.99 108.59,84.06 108.59,84.07 108.59,84.12 107.92,84.79 107.77,84.79 107.38,85.18 107.38,89.39 107.12,89.65 107.12,89.95 107.15,90.03 107.23,90.05 107.64,90.4 107.23,90.76 107.15,90.78 107.12,90.86 107.12,92.7 107.22,92.8 108.38,92.8
+CHARGER_SRC on TOP (solid shape): 7.07,25.19 7.07,24.75 7.23,24.59 7.23,21.27 7.05,21.09 6.76,21.09 6.42,20.75 6.42,20.32 6.22,20.12 5.7,20.12 5.61,20.21 5.61,25.24 5.77,25.4 6.87,25.4
+CHARGER_SRC on BOTTOM (solid shape): outline of 284 points within 4.35,17.29 14.06,26.94
+CRT_VCC on TOP (solid shape): 282.58,54.54 282.58,53.28 282.48,53.18 281.53,53.18 281.38,53.02 281.14,53.02 280.99,53.17 280.99,53.81 281.34,54.16 281.34,54.21 281.84,54.71 282.41,54.71
+CRT_VCC on BOTTOM (solid shape): 319.92,78.73 319.92,78.15 320.1,77.97 320.22,77.97 320.25,77.95 320.25,76.95 320,76.95 319.77,76.73 318.19,76.73 318.09,76.83 318.09,77.31 317.78,77.62 316.84,77.62 316.84,78.09 318.18,79.42 318.18,80.05 318.59,80.05
+DC_IN on TOP (solid shape): 53.09,92.54 53.09,91.81 53.12,91.77 53.11,91.74 53.18,91.33 53.58,91.27 53.62,91.28 54.47,90.43 54.47,88.67 54.35,88.55 53.19,88.55 52.97,88.77 52.77,88.77 52.76,88.77 52.63,88.79 52.51,88.77 52.5,88.77 52.18,88.77 52.17,88.77 52.05,88.79 51.92,88.77 51.92,88.77 51.64,88.77 51.52,88.89 51.52,88.94 51.52,88.95 51.57,89.12 51.52,89.29 51.52,89.31 51.52,89.35 51.44,89.43 51.4,89.43 51.38,89.43 51.21,89.48 51.03,89.43 50.3,89.43 50.27,89.4 50.27,89.38 49.94,89.05 48.62,89.05 48.4,89.27 48.4,89.9 48.56,90.06 49.03,90.06 49.53,90.56 49.53,92.9 49.76,93.12 52.5,93.12
+DC_IN on BOTTOM (solid shape): 72,103.64 72.06,103.64 72.47,103.64 72.53,103.64 72.6,103.65 76.36,103.65 76.58,103.42 76.58,101.91 76.32,101.64 72.95,101.64 72.8,101.79 70.37,101.79 70.04,102.12 70.04,103.4 70.28,103.65 71.93,103.65
+DC_IN_SS on TOP (solid shape): 47.68,88.82 49.85,88.82 50.15,88.51 50.17,88.51 50.17,87.8 50.16,87.78 50.16,87 50.34,86.82 51.63,86.82 51.64,86.84 52.79,86.84 52.89,86.73 52.89,85.51 52.46,85.08 52.46,83.23 51.16,81.93 49.15,81.93 48.7,82.39 48.7,84.93 48.37,85.26 47.53,85.26 47.38,85.41 47.38,86.68 46.87,87.19 42.75,87.19 42.5,87.44 42.5,88.43 42.57,88.54 42.59,88.68 42.96,89.05 47.45,89.05
+DCIN_JACK on TOP (solid shape): 57.37,91.75 57.37,87.94 56.83,87.39 55,87.39 54.67,87.72 54.67,91.84 54.83,91.99 57.13,91.99
+DCIN_JACK on BOTTOM (solid shape): 57.27,91.56 57.27,87.84 56.59,87.16 55.65,87.16 55.6,87.17 55.56,87.16 54.43,87.16 53.82,87.77 53.82,91.78 53.89,91.85 56.97,91.85
+EDP_VDD on BOTTOM (solid shape): 100.31,84.73 100.31,84.23 100.32,84.22 100.32,84.2 100.34,84.2 100.35,84.19 100.74,84.19 100.78,84.15 100.78,83.5 100.75,83.42 100.75,83.35 100.75,83.3 100.58,83.13 99.18,83.13 98.9,83.41 97.67,83.41 97.36,83.73 97.36,84.07 97.56,84.27 99.27,84.27 99.34,84.2 99.36,84.2 99.39,84.17 100.08,84.17 100.11,84.2 100.11,84.73 100.14,84.76 100.28,84.76
+LCDVDD on BOTTOM (solid shape): 102.03,92.69 102.03,91.21 102.1,91.14 102.09,91.11 102.11,90.83 102.34,90.66 102.41,90.65 102.48,90.65 102.56,90.63 102.59,90.55 102.59,89.52 102.32,89.24 102.22,89.24 102.22,88.73 101.95,88.46 101.95,87.75 101.52,87.32 101.5,87.28 101.46,87.27 101.18,87.15 101.09,86.85 101.2,86.64 101.42,86.55 101.49,86.52 101.52,86.45 101.52,84.67 101.16,84.32 100.47,84.32 100.44,84.35 100.44,84.78 100.43,84.79 100.43,84.88 100.42,84.89 100.33,84.89 100.33,84.89 100.08,84.89 100.08,84.89 100,84.89 99.98,84.87 99.98,84.33 99.97,84.32 99.71,84.32 99.65,84.38 99.65,86.85 99.69,86.86 99.91,87.13 99.8,87.47 99.8,88.84 101.11,90.15 101.14,90.15 101.5,90.48 101.18,90.86 101.16,90.86 101.12,90.91 101.12,92.65 101.25,92.79 101.94,92.79
+LINE1-VREFO-L on TOP (solid shape): 305.76,36.59 305.76,36.47 305.25,35.96 304.55,35.96 303.98,35.39 302.33,35.39 302.2,35.51 302.2,35.58 302.27,35.64 302.43,35.64 302.53,35.59 302.65,35.57 303.54,35.57 303.54,35.57 303.66,35.57 303.66,35.58 303.79,35.58 304.42,36.21 304.8,36.21 305,36.4 305,36.59 305.31,36.91 305.44,36.91
+LINE1-VREFO-R on TOP (solid shape): 305.76,35.32 305.76,35.2 305.44,34.88 305.19,34.88 305.07,34.99 305.07,35.05 304.73,35.39 304.37,35.09 304.36,35.07 304.3,35.01 302.33,35.01 302.27,35.07 302.27,35.13 302.33,35.2 303.98,35.2 304.55,35.77 305.31,35.77
+PBATT on TOP (solid shape): 30.8,4.49 30.8,2.18 30.68,2.05 23.31,2.05 23.12,2.24 23.12,4.53 23.37,4.78 30.51,4.78
+PWR_SRC on TOP (solid shape): 162.34,118.13 162.34,113.05 161.9,112.62 160.17,112.62 160.17,112.62 159.97,112.82 159.97,113.61 159.43,113.61 159.42,113.62 159.42,113.83 159.43,113.85 159.97,113.85 159.97,114.39 159.43,114.4 159.41,114.42 159.41,114.64 159.42,114.65 159.96,114.65 159.96,115.27 159.82,115.41 159.29,115.41 159.03,115.66 159.03,116.4 158.05,117.39 158.05,118.1 158.41,118.46 162.01,118.46
+PWR_SRC on TOP (solid shape): outline of 1350 points within 27.88,9.99 79.89,97.3
+PWR_SRC on BOTTOM (solid shape): 36.6,13.82 36.6,12.18 35.44,11.02 30.59,11.02 30.17,11.45 30.17,13.66 30.5,13.99 36.43,13.99
+PWR_SRC on BOTTOM (solid shape): 178.06,99.56 178.06,98.63 177.93,98.51 175.71,98.51 175.58,98.63 175.58,99.52 175.71,99.65 177.97,99.65
+PWR_SRC on BOTTOM (solid shape): 108.09,83.87 108.09,82.62 107.86,82.39 107.19,82.39 107.12,82.45 105.16,82.45 105.05,82.57 105.05,83.07 105.3,83.32 106.07,83.32 106.37,83.62 106.51,83.62 106.52,83.63 106.57,83.63 107.1,84.16 107.8,84.16
+PWR_SRC on BOTTOM (solid shape): 50.49,66.82 50.49,66.05 50.49,66.05 49.94,66.05 49.94,65.28 50.48,65.28 50.49,65.28 50.49,64.84 49.94,64.84 49.94,64.09 50.49,64.09 50.5,64.07 50.5,63.18 51.29,62.39 51.29,60.18 51.19,60.08 47.8,60.08 47.38,60.5 47.38,66.57 47.82,67.01 50.29,67.01
+PWR_SRC on BOTTOM (solid shape): 160.79,118.12 160.79,116.99 160.81,116.97 161.33,116.97 161.35,116.95 161.35,116.73 161.33,116.71 160.81,116.71 160.79,116.68 160.79,116.2 160.81,116.17 161.34,116.17 161.36,116.16 161.36,115.92 161.34,115.91 160.8,115.91 160.79,115.9 160.79,115.49 160.71,115.41 159.59,115.41 159.14,115.87 159.14,116.42 158.03,117.54 158.03,118.21 158.39,118.57 160.34,118.57
+PWR_SRC on BOTTOM (solid shape): 81.16,96.92 81.16,95.61 81.1,95.59 81.05,95.57 81.01,95.53 80.97,95.5 80.94,95.45 80.91,95.4 80.89,95.35 80.88,95.3 80.88,95.25 80.89,95.19 80.9,95.14 80.92,95.09 80.95,95.05 80.99,95.01 81.03,94.97 81.07,94.95 81.09,94.93 81.1,94.9 81.1,94.87 81.1,94.84 81.08,94.81 81.07,94.8 80.9,94.63 78.62,94.63 77.98,95.27 80.04,95.27 80.04,95.22 80.04,95.17 80.06,95.12 80.08,95.07 80.11,95.03 80.15,94.99 80.19,94.95 80.24,94.93 80.29,94.91 80.34,94.89 80.39,94.89 80.44,94.89 80.5,94.91 80.55,94.93 80.59,94.95 80.63,94.99 80.67,95.03 80.7,95.07 80.72,95.12 80.74,95.17 80.75,95.22 80.75,95.27 80.74,95.33 80.72,95.38 80.7,95.43 80.67,95.47 80.63,95.51 80.59,95.54 80.55,95.57 80.5,95.59 80.44,95.6 80.39,95.6 80.34,95.6 80.29,95.59 80.24,95.57 80.19,95.54 80.15,95.51 80.11,95.47 80.08,95.43 80.06,95.38 80.04,95.33 80.04,95.27 77.98,95.27 77.81,95.45 76.36,95.45 76.13,95.67 76.13,96.87 76.43,97.17 80.9,97.17
+PWR_SRC_AC on BOTTOM (solid shape): 8.9,17.67 8.9,17.16 8.92,17.14 9.58,17.14 9.63,17.19 9.63,17.67 9.66,17.7 10.06,17.7 10.09,17.67 10.09,17.19 10.11,17.16 10.86,17.16 11.05,16.97 11.05,13.86 10.32,13.13 4.62,13.13 4.32,13.42 4.32,15.92 4.49,16.08 5.1,16.08 5.1,15.55 5.45,15.19 5.81,15.55 5.81,16.08 5.97,16.08 5.97,16.1 5.99,16.1 7.05,17.16 8.36,17.16 8.41,17.21 8.41,17.67 8.44,17.7 8.87,17.7
+PWR_SRC_R on TOP (solid shape): 222.31,7.31 223.45,7.31 223.55,7.21 223.55,6.75 223.34,6.55 220.5,6.55 220.4,6.64 220.4,7.13 220.39,7.26 220.36,7.38 220.35,7.41 220.47,7.54 222.08,7.54
+REGCTL_PNP10 on TOP (solid shape): 284.1,87.04 284.1,85.74 283.98,85.62 283.22,85.62 283.16,85.67 282.58,85.67 282.45,85.7 282.33,85.67 280.8,85.67 280.68,85.79 280.68,85.87 280.8,86 282.12,86 282.61,86.13 282.47,86.62 282.41,86.68 282.41,86.93 282.65,87.17 283.97,87.17
+SDC_IN on TOP (solid shape): 8.9,46.75 10.29,46.75 10.55,46.5 10.55,44.72 10.42,44.6 9.62,44.6 9.5,44.47 9.5,43.04 9.66,42.88 9.66,41.42 9.53,41.29 7.63,41.29 6.74,42.18 3.43,42.18 2.8,42.82 2.8,46.88 3.43,47.52 8.13,47.52
+SDC_IN on TOP (solid shape): outline of 957 points within 17.43,57.75 48.29,86.78
+SDC_IN on BOTTOM (solid shape): 6.74,20.15 6.74,17.29 6.55,17.1 5.81,17.1 5.81,17.63 5.45,17.99 5.1,17.63 5.1,17.1 3.31,17.1 2.99,17.42 2.99,20.47 3.24,20.72 6.16,20.72
+SDREG2 on TOP (solid shape): 24.16,48.68 24.16,48.61 24.01,48.46 24.01,48.15 23.22,47.36 21.54,47.36 21.42,47.49 21.42,48.05 21.93,48.05 22.05,47.92 23.14,47.92 23.35,48.13 23.35,48.53 23.3,48.58 23.3,48.68 23.37,48.76 24.08,48.76
+TBTA_VBUS on TOP (solid shape): 9.23,96.31 9.94,96.31 10.53,95.72 10.53,95.32 10.18,94.96 9.82,94.96 9.66,95.12 9.13,95.12 8.92,95.33 7.8,95.33 7.76,95.38 7.76,96.13 8.02,96.39 9.15,96.39
+TBTA_VBUS on TOP (solid shape): 11.14,98.91 11.3,98.91 11.41,98.8 11.41,98.57 11.33,98.49 10.95,98.49 10.67,98.21 10.67,97.67 10.52,97.52 10.39,97.52 10.34,97.57 9.22,97.57 9.17,97.52 7.64,97.52 7.21,97.94 7.21,98.2 7.25,98.24 8.48,98.24 8.75,98.51 9.45,98.51 9.87,98.92 11.13,98.92
+TBTA_VBUS on BOTTOM (solid shape): 15.92,90.26 15.92,89.99 15.88,89.95 15.88,89.03 15.92,88.99 15.92,88.74 16.26,88.4 16.26,84.98 16.13,84.85 12.26,84.85 10.98,86.14 10.98,88.69 11.49,89.2 14.07,89.2 15.18,90.31 15.87,90.31
+TBTA_VBUS on BOTTOM (solid shape): 8.34,96.4 9.63,96.4 9.77,96.26 10.6,96.26 10.85,96 10.85,95.4 10.52,95.06 9.51,95.06 8.85,95.73 7.19,95.73 6.99,95.52 6.99,95.34 6.89,95.24 6.51,95.24 6.48,95.27 6.48,95.4 6.46,95.42 6.46,95.57 6.79,95.57 7.02,95.8 7.02,95.95 7.14,96.08 8.02,96.08 8.34,96.4
+TBTA_VBUS on BOTTOM (solid shape): 11.44,98.87 11.44,98.52 11.21,98.29 10.93,98.29 10.5,97.86 9.4,97.86 9.06,98.2 7.11,98.2 6.99,98.09 6.56,98.09 6.53,98.06 5.92,98.06 5.9,98.09 5.9,98.29 6.32,98.29 6.5,98.47 6.5,98.48 6.61,98.6 6.84,98.6 6.89,98.64 8.93,98.64 9.33,99.05 10.2,99.05 10.21,99.05 10.49,99.05 10.5,99.05 11.26,99.05
+TBTA_VBUS_1 on TOP (solid shape): 47.78,99.14 47.78,96.88 47.4,96.5 46.5,96.5 46.09,96.92 46.09,97.79 45.78,98.1 45.78,99.11 46.14,99.47 47.45,99.47
+TBTA_VBUS_1 on TOP (solid shape): 19.75,86.91 20.58,86.91 21.39,86.1 21.39,83.77 20.91,83.29 18.64,83.29 18.23,83.71 18.23,84.53 17.98,84.77 15.39,84.77 15.03,85.13 15.03,86.73 15.56,87.25 19.41,87.25
+TBTA_VBUS_1 on TOP (solid shape): 36.16,78.48 36.32,78.48 36.78,78.02 36.78,77.63 36.82,77.59 36.82,76.88 37.1,76.6 37.47,76.6 37.47,75.71 37.28,75.52 36.24,75.52 36.01,75.75 36.01,76.43 35.8,76.64 35.8,77.98 35.43,78.35 34.58,78.35 34.47,78.46 34.47,78.54 34.61,78.68 35.96,78.68
+TBTA_VBUS_1 on TOP (solid shape): 31.27,78.5 31.39,78.5 31.4,78.47 31.51,78.32 31.69,78.29 31.72,78.29 31.76,78.26 31.76,76.96 31.55,76.75 31.43,76.75 31.29,76.62 30.6,76.62 30.33,76.89 30.33,77.87 30.39,77.96 30.4,78.06 30.39,78.09 30.45,78.15 30.57,78.26 30.73,78.26 30.91,78.44 30.91,78.61 31.03,78.74 31.04,78.74
+TBTA_VBUS_1 on TOP (solid shape): 15.17,57.98 15.17,55.7 14.98,55.44 15.08,55.13 15.17,55.04 15.17,53.49 14.83,53.15 12.66,53.15 11.08,54.73 9.74,54.73 9.72,54.71 9.72,54.18 9.71,54.17 9.28,54.17 9.26,54.19 9.26,54.69 9.23,54.73 8.53,54.73 8.52,54.71 8.52,54.19 8.5,54.17 8.07,54.17 8.05,54.19 8.05,54.68 8.04,54.7 8.02,54.7 8.02,54.71 7.42,54.71 7.37,54.76 7.37,57.93 7.88,58.44 14.71,58.44
+TBTA_VBUS_1 on BOTTOM (solid shape): outline of 187 points within 16.64,74.95 37.22,89.11
+TBTA_VBUS_1 on BOTTOM (solid shape): outline of 199 points within 35.23,87.78 48,98.1
+USB_EX2_PWR on TOP (solid shape): 20.59,78.5 21.2,78.5 21.2,78.5 21.72,78.5 21.98,78.25 21.98,75.84 21.72,75.58 17.66,75.58 16.13,77.11 15.63,77.11 15.05,77.68 15.05,78.06 15.5,78.5 20.59,78.5
+USB_EX3_PWR on BOTTOM (solid shape): 87.64,105.17 87.64,103.34 88.02,102.96 88.02,101.36 87.76,101.11 85.73,101.11 85.6,101.24 85.6,104.29 83.32,106.57 83.32,107.21 83.83,107.71 85.1,107.71
+UZ12_TPM on TOP (solid shape): 172.8,39.68 172.8,39.11 172.69,39.01 170.31,39.01 170.31,39.26 170.38,39.26 170.5,39.39 170.5,39.58 170.63,39.71 172.77,39.71
+VCHGR on TOP (solid shape): 29.34,8.6 29.7,8.25 30.05,8.6 30.05,9.15 30.69,9.15 30.87,8.97 30.87,8.66 30.87,8.59 30.99,8.46 32.45,8.46 32.58,8.34 32.58,5.16 32.39,4.97 29.09,4.97 28.9,5.16 28.9,6.3 28.71,6.5 28.71,9.07 28.78,9.15 29.34,9.15
+VHDMI_VCC on TOP (solid shape): 113.81,108.44 113.81,106.48 113.78,106.44 113.75,106.4 113.64,106.29 111.21,106.29 111,106.49 111,107.8 111.61,108.4 112.48,108.4 112.73,108.65 113.59,108.65
AUD_HP_NB_SENSE on TOP (solid shape): 320.05,29.23 320.05,27.83 319.85,27.64 318.46,27.64 318.27,27.83 318.27,29.23 318.46,29.42 319.85,29.42
AUD_HP_OUT_L1 on TOP (solid shape): 317.39,39.12 317.39,38.2 317.22,38.04 317.11,38.04 317.06,37.99 315.66,37.99 315.47,38.18 315.47,39.2 315.6,39.32 317.19,39.32
BGATE_ISL88738 on TOP (solid shape): 20.33,15.26 20.45,15.26 20.71,15 20.71,13.99 20.45,13.73 20.2,13.73 20.07,13.86 20.07,13.9 19.75,14.21 19.75,15.26 19.82,15.32 20.26,15.32
BGATE_ISL88738 on TOP (solid shape): 28.52,7.26 28.52,6.3 28.77,6.05 28.77,5.29 28.64,5.16 27.12,5.16 27.06,5.23 27.06,5.92 27.18,6.05 27.56,6.05 27.75,6.24 27.75,7.26 27.82,7.32 28.45,7.32
BL_PWR_SRC_ON on BOTTOM (solid shape): 104.9,81.97 104.93,81.97 104.95,81.95 106.91,81.95 106.97,81.88 106.99,81.88 107.06,81.81 107.96,81.81 108.21,81.56 108.21,80.54 108.08,80.4 107.77,80.4 107.58,80.59 107.58,80.69 107.23,81.04 104.22,81.04 104.1,81.12 103.96,81.13 103.95,81.13 103.04,81.13 102.88,81.3 102.88,81.81 103.13,82.06 104.81,82.06
BOOT1_ISL88738 on TOP (solid shape): 20.07,22.24 20.07,21.54 19.94,21.42 19.31,21.42 18.74,20.85 18.74,20.84 18.74,19.97 18.74,19.97 18.74,18.69 18.67,18.62 18.61,18.62 18.55,18.69 18.55,19.51 18.42,19.64 18.42,21.04 18.48,21.1 18.48,21.94 18.85,22.31 20.01,22.31
BOOT2_ISL88738 on TOP (solid shape): 23.25,17.04 23.25,16.15 23.18,16.08 21.85,16.08 21.78,16.11 21.75,16.18 21.63,16.44 21.36,16.52 21.33,16.52 21.28,16.56 21.18,16.56 21.09,16.66 20.07,16.66 20.07,16.78 20.13,16.85 20.58,16.85 20.64,16.91 21.23,16.91 21.31,16.82 21.42,16.76 21.43,16.76 21.47,16.72 22.35,16.72 22.36,16.72 22.48,16.85 22.48,16.86 22.55,16.92 22.55,17.04 22.61,17.1 23.18,17.1
BST_3V on TOP (solid shape): 158.71,112.03 158.71,111.07 158.66,111.02 157.51,111.02 157.43,111.09 156.57,111.09 156.49,111.17 156.49,111.32 156.57,111.4 157.41,111.4 158.09,112.08 158.65,112.08
BST_5V on BOTTOM (solid shape): 166.6,113.73 166.6,113.66 166.43,113.48 165.79,113.48 165.13,112.82 164.47,112.82 164.44,112.84 164.44,113.7 164.6,113.86 166.48,113.86
BST_5V_R on BOTTOM (solid shape): 163.78,113.71 163.78,112.77 163.68,112.67 163.35,112.67 162.77,112.08 162.77,111.63 162.64,111.5 162.01,111.5 161.9,111.6 161.9,113.12 162.18,113.4 162.64,113.4 162.97,113.73 163.76,113.73
BST_+1VALWP on BOTTOM (solid shape): 179.96,93.55 179.96,93.43 179.77,93.24 179.2,93.24 178.69,92.73 177.55,92.73 177.55,93.62 179.9,93.62
BST_+1VALWP_C on BOTTOM (solid shape): 176.79,91.52 176.15,91.52 176.15,93.62 176.79,93.62
BST_C_GT on TOP (solid shape): 55.53,66.95 55.53,64.92 55.3,64.69 54.03,64.69 53.73,64.99 53.73,66.59 54.21,67.07 55.4,67.07
BST_C_IA on TOP (solid shape): 57.22,72.25 57.22,72.14 57.22,72.13 57.22,71.55 57.22,71.49 57.22,71.36 57.22,71.35 57.22,70.96 57.22,70.92 57.22,70.87 57.22,70.2 57.14,70.12 56.63,70.12 56.54,70.21 56.54,71.09 56.49,71.14 56.49,72.2 56.63,72.34 57.13,72.34
BST_C_SA on TOP (solid shape): 66.17,78.76 66.17,76.73 66.11,76.66 65.41,76.66 65.28,76.79 65.28,78.76 65.41,78.89 66.05,78.89
BST_GT on TOP (solid shape): 57.79,66.31 57.79,65.55 57.7,65.46 56.97,65.46 56.71,65.71 56.71,65.74 56.68,65.74 56.6,65.83 55.94,65.83 55.83,65.93 55.83,66.95 55.99,67.1 57,67.1
BST_IA on TOP (solid shape): 58.69,72.27 58.69,71.38 58.63,71.32 57.44,71.32 57.34,71.41 57.34,72.08 57.44,72.18 57.75,72.15 57.99,72.35 58.6,72.35
BST_R_GT on TOP (solid shape): 56.85,65.35 56.9,65.35 56.92,65.33 57.75,65.33 57.77,65.35 57.89,65.22 57.89,64.74 57.82,64.66 55.94,64.66 55.73,64.86 55.73,65.5 55.94,65.7 56.5,65.7
BST_R_IA on TOP (solid shape): 58.82,71.09 58.82,70.22 58.64,70.04 57.62,70.04 57.36,70.31 57.36,71.04 57.49,71.17 57.52,71.17 57.6,71.17 57.7,71.19 58.72,71.19
CPU_B+ on TOP (solid shape): 56.42,71.03 56.42,70.14 56.44,70.11 56.44,70.05 56.5,70.05 56.56,70 57.23,70 57.36,69.87 57.36,67.53 57.23,67.4 55.81,67.4 55.68,67.53 55.68,68.83 55.35,69.16 53.19,69.16 52.91,69.44 52.91,70.99 53.19,71.27 56.18,71.27
CPU_B+ on BOTTOM (solid shape): 70.78,82.06 70.78,81.23 71.33,81.23 71.33,81.05 70.77,81.05 70.77,80.57 70.77,80.57 69.76,80.57 69.76,80.57 69.53,80.57 69.1,81.01 69.1,82.08 69.23,82.21 70.62,82.21
CPU_B+ on BOTTOM (solid shape): 52.76,71.39 57.13,71.39 57.19,71.33 57.19,70.89 57.22,70.86 57.23,70.82 57.53,70.56 57.89,70.75 58.81,70.75 58.83,70.73 58.83,67.99 58.68,67.84 57.87,67.84 57.35,67.32 57.35,67.11 57.34,67.1 57.31,66.95 57.34,66.8 57.35,66.79 57.35,66.02 57.21,65.89 57.15,65.71 57.12,65.64 57.05,65.61 56.96,65.52 55.96,65.52 55.94,65.54 55.94,66.02 55.9,66.06 55.41,66.06 55.39,66.04 55.39,65.51 55.38,65.5 55.17,65.5 55.15,65.51 55.15,66.02 55.12,66.05 54.63,66.05 54.61,66.03 54.61,65.53 54.58,65.51 54.04,65.51 53.85,65.32 53.85,63.39 53.73,63.26 50.71,63.26 50.63,63.34 50.63,64.19 50.6,64.22 50.3,64.22 50.29,64.22 50.1,64.22 50.07,64.25 50.07,64.68 50.09,64.7 50.61,64.7 50.65,64.74 50.65,65.4 50.61,65.44 50.11,65.44 50.08,65.46 50.08,65.88 50.09,65.89 50.55,65.89 50.62,65.96 50.62,67.32 49.26,68.69 49.26,71.75 49.62,72.12 52.04,72.12
DCIN_ISL88738 on TOP (solid shape): 13.58,22.75 13.58,21.16 13.79,20.95 14.31,20.95 14.32,20.96 14.5,20.78 14.5,20.78 16.84,18.43 16.84,18.3 16.76,18.23 16.01,18.23 14.72,19.51 12.92,19.51 12.47,19.97 12.47,22.81 12.5,22.85 13.48,22.85
GPU_B+ on TOP (solid shape): 57.35,64.27 57.35,62.5 57.22,62.38 52.9,62.38 52.73,62.55 52.73,64.15 53.04,64.46 57.16,64.46
GPU_B+ on BOTTOM (solid shape): 55,65.36 55.57,65.36 55.57,65.87 55.76,65.87 55.76,65.36 56.96,65.36 57.16,65.16 57.16,65.14 57.33,64.78 57.73,64.81 58.81,64.81 58.81,62.57 58.74,62.5 57.54,62.5 57.44,62.4 53.02,62.4 52.85,62.56 52.85,62.9 52.97,63.02 53.71,63.02 54.04,63.35 54.04,65.23 54.17,65.36 54.81,65.36 54.81,65.87 55,65.87
GT_SNUB1 on TOP (solid shape): 68.59,68.98 68.59,65.37 68.43,65.22 66.98,65.22 66.72,65.49 66.72,67.46 67.19,67.93 67.19,68.98 67.44,69.23 68.33,69.23
GT_SW1 on TOP (solid shape): 65.8,67.72 65.8,64.45 65.66,64.31 63.86,64.31 63.76,64.41 63.76,65.17 64.27,65.68 64.27,67.76 64.39,67.89 65.64,67.89
GT_SW1 on BOTTOM (solid shape): 65.98,65.08 65.98,62.92 65.97,62.91 65.05,62.91 65.05,62.1 65.97,62.1 65.97,60.71 65.66,60.41 62.62,60.41 62.36,60.66 62.36,61.68 62.11,61.93 62.1,61.93 61.57,61.93 61.42,62.08 61.42,64.81 63.24,64.81 63.9,65.48 65.59,65.48
IA_SNUB on TOP (solid shape): 66.1,73.25 66.1,72.92 65.69,72.51 65.69,71.26 65.53,71.11 63.85,71.11 63.65,71.31 63.65,73.14 63.86,73.35 65.99,73.35
IA_SW on TOP (solid shape): 65.79,70.43 65.79,68.45 65.69,68.34 62.62,68.34 62.49,68.47 62.49,70.38 62.74,70.63 65.59,70.63
IA_SW on BOTTOM (solid shape): 66.11,72.03 66.11,70.63 66.05,70.57 65.09,70.57 65.03,70.5 65.03,69.74 65.09,69.68 65.92,69.68 65.98,69.61 65.98,68.41 65.85,68.28 62.61,68.28 62.61,68.28 61.54,68.28 61.45,68.37 61.45,70.76 63.12,70.76 63.44,71.07 63.44,71.96 63.57,72.09 66.05,72.09
INT_SPK_L+ on TOP (solid shape): 300.23,40.72 300.23,39.77 299.92,39.45 299.92,38.12 299.85,38.05 299.79,38.05 299.73,38.12 299.73,38.82 299.66,38.88 299.66,39.58 299.73,39.64 299.73,40.76 299.8,40.83 300.12,40.83
INT_SPK_L+ on TOP (solid shape): 290.2,30.54 290.2,29.86 289.83,29.48 289.35,29.48 289.02,29.65 288.66,29.7 288.58,29.73 288.55,29.8 288.55,30.42 288.55,30.5 288.68,30.62 289.82,30.62 289.88,30.69 290.05,30.69
INT_SPK_L+ on BOTTOM (solid shape): 300.3,40.72 300.3,39.83 300.68,39.45 300.68,39.01 300.55,38.88 300.11,38.88 299.98,39.01 299.98,39.58 299.79,39.77 299.79,40.72 299.85,40.79 300.23,40.79
INT_SPK_L- on TOP (solid shape): 289.82,31.59 289.82,30.88 289.69,30.75 288.61,30.75 288.55,30.82 288.55,31.7 288.65,31.81 289.6,31.81
INT_SPK_L- on TOP (solid shape): 299.6,40.73 299.6,39.77 299.53,39.71 299.53,38.12 299.41,37.99 299.34,37.99 299.28,38.05 299.28,39.39 299.15,39.52 299.15,40.82 299.19,40.86 299.47,40.86
INT_SPK_L- on BOTTOM (solid shape): 299.66,40.66 299.66,40.63 299.65,40.58 299.66,40.52 299.66,40.07 299.65,40 299.66,39.93 299.66,39.72 299.66,39.64 299.79,39.52 299.79,38.94 299.73,38.88 299.22,38.88 299.15,38.94 299.15,40.66 299.22,40.72 299.6,40.72
INT_SPK_R+ on TOP (solid shape): 289.62,38.62 289.62,38.09 289.29,37.76 289.29,36.47 289.21,36.39 288.42,36.39 288.32,36.49 288.32,38.03 289.04,38.75 289.48,38.75
INT_SPK_R+ on TOP (solid shape): 298.39,40.77 298.39,40.14 298.38,40.05 298.39,39.95 298.39,39.46 298.39,39.45 298.71,39.13 298.71,38.12 298.58,37.99 298.52,37.99 298.46,38.05 298.46,39.01 298.36,39.1 298.36,39.13 297.88,39.61 297.88,40.01 297.88,40.06 297.88,40.8 298,40.91 298.25,40.91
INT_SPK_R+ on BOTTOM (solid shape): 298.39,40.59 298.39,40.14 298.38,40.05 298.39,39.95 298.39,39.83 298.07,39.52 298.07,38.94 298.01,38.88 297.44,38.88 297.38,38.94 297.38,39.52 297.54,39.68 297.56,39.68 297.8,39.8 297.88,40.06 297.88,40.59 298.01,40.72 298.26,40.72
INT_SPK_R- on TOP (solid shape): 288.27,39.34 288.27,38.85 287.91,38.49 287.91,36.66 287.66,36.4 286.71,36.4 286.64,36.47 286.64,38.69 287.45,39.5 288.12,39.5
INT_SPK_R- on TOP (solid shape): 299.03,40.8 299.03,40.65 299.01,40.56 299.03,40.46 299.03,40.13 299.02,40.12 298.99,39.97 299.02,39.82 299.03,39.81 299.03,39.46 299.03,39.45 299.09,39.39 299.09,38.05 299.03,37.99 298.96,37.99 298.9,38.05 298.9,39.13 298.52,39.52 298.52,40.85 298.58,40.91 298.91,40.91
INT_SPK_R- on BOTTOM (solid shape): 299.03,40.66 299.01,40.56 299.03,40.46 299.03,40.13 299.02,40.12 298.99,39.97 299.02,39.82 299.03,39.81 299.03,38.94 298.96,38.88 298.33,38.88 298.26,38.94 298.26,39.45 298.52,39.71 298.52,39.78 298.52,40.66 298.58,40.72 298.96,40.72
INT_SPKR_L+ on TOP (solid shape): 266.22,30.05 266.54,29.86 266.9,29.8 267.02,29.8 267.02,29.23 266.9,29.1 264.1,29.1 264.04,29.16 264.04,29.93 264.17,30.05
INT_SPKR_L+ on TOP (solid shape): 288.42,30.37 288.42,29.67 288.33,29.64 288.26,29.61 288.17,29.61 286.96,28.4 284.49,28.4 284.49,28.91 284.93,29.36 286.52,29.36 287.6,30.43 288.36,30.43
INT_SPKR_L- on TOP (solid shape): 266.4,31.26 266.64,31.16 266.9,31.13 267.28,31.13 267.28,30.56 267.15,30.43 264.23,30.43 264.04,30.63 264.04,31.07 264.23,31.26
INT_SPKR_L- on TOP (solid shape): 286.83,31.99 287.24,31.65 287.75,31.8 287.96,32.02 288.23,32.02 288.42,31.83 288.42,30.82 288.36,30.75 287.28,30.75 286.64,30.12 285.69,30.12 284.87,30.94 283.98,30.94 283.85,31.07 283.85,31.77 284.03,31.95 284.08,31.89 286.35,31.89 286.47,32.02 286.82,32.02
INT_SPKR_R+ on TOP (solid shape): 267.21,32.66 267.47,32.66 267.66,32.47 267.66,31.9 267.59,31.83 266.9,31.83 266.64,31.8 266.4,31.7 264.23,31.7 264.1,31.83 264.1,32.47 264.29,32.66 267.19,32.66
INT_SPKR_R+ on TOP (solid shape): 289.21,36.14 289.21,35.68 289.18,35.65 289.02,35.65 287.05,33.69 287.05,33.31 286.14,32.4 284.9,32.4 284.73,32.45 284.55,32.47 284.23,32.47 284.1,32.59 284.1,33.36 284.29,33.55 285.25,33.55 285.76,34.05 286.52,34.05 287.22,34.75 287.22,35.9 287.5,36.18 289.17,36.18
INT_SPKR_R- on TOP (solid shape): 267.66,33.99 267.66,33.23 267.59,33.17 266.9,33.17 266.58,33.12 266.3,32.97 264.23,32.97 264.06,33.15 265.16,34.24 267.4,34.24
INT_SPKR_R- on TOP (solid shape): 286.45,37.29 286.45,36.28 286.96,35.77 286.96,34.94 286.77,34.75 285.44,34.75 285.43,34.76 285.25,34.8 285.08,34.75 285.06,34.75 284.42,35.39 284.42,36.21 284.68,36.47 285.5,36.47 285.63,36.59 285.63,37.29 285.69,37.36 286.39,37.36
LG1_ISL88738 on TOP (solid shape): 21.15,20.02 21.15,19.64 20.13,18.62 19.82,18.62 19.75,18.69 19.75,19.39 20.58,20.21 20.96,20.21
LG1_ISL88738 on BOTTOM (solid shape): 19.18,29.48 19.18,28.53 19.06,28.4 17.59,28.4 17.47,28.53 17.47,29.22 17.79,29.55 19.12,29.55
LG2_ISL88738 on TOP (solid shape): 22.1,18.62 22.1,18.31 21.98,18.18 21.79,18.18 21.47,17.86 20.13,17.86 20.07,17.93 20.07,17.99 20.13,18.05 20.96,18.05 21.66,18.75 21.98,18.75
LG2_ISL88738 on BOTTOM (solid shape): 28.31,19.19 28.31,18.61 28.2,18.5 28.2,18.5 28.01,18.31 26.93,18.31 26.87,18.37 26.87,19.45 26.93,19.51 27.98,19.51
LX1_ISL88738 on TOP (solid shape): 21.34,22.24 21.34,21.29 19.56,19.51 19.56,18.69 19.5,18.62 19.44,18.62 19.37,18.69 19.37,19.71 19.56,19.9 19.56,20.4 20.33,21.16 20.33,22.24 20.45,22.37 21.21,22.37
LX1_ISL88738 on BOTTOM (solid shape): 13.02,29.67 13.02,28.72 12.83,28.53 11.88,28.53 11.75,28.66 11.75,29.67 11.88,29.8 12.9,29.8
LX2_ISL88738 on TOP (solid shape): 23.75,18.43 23.75,17.42 23.63,17.29 22.55,17.29 22.36,17.48 21.09,17.48 21.02,17.42 20.13,17.42 20.07,17.48 20.07,17.61 20.13,17.67 20.9,17.67 20.96,17.73 21.52,17.73 21.53,17.73 21.85,18.05 22.04,18.05 22.55,18.56 23.63,18.56
LX2_ISL88738 on BOTTOM (solid shape): 27.44,13.86 28.08,13.86 28.31,13.63 28.31,13.09 28.07,12.85 26.93,12.85 26.87,12.91 26.87,13.99 26.93,14.05 27.25,14.05
LX_1.8VALW on TOP (solid shape): 124.35,106.17 124.35,105.52 125.42,104.45 126.22,104.45 126.29,104.38 126.29,103.66 126.23,103.61 121.95,103.61 121.71,103.85 121.71,104.76 121.92,104.96 123.22,104.96 123.61,105.34 123.61,106.14 123.85,106.39 124.13,106.39
LX_1V_PRIM on TOP (solid shape): 131.2,110.94 131.2,109.9 130.36,109.05 130.36,107.89 129.37,106.9 127.09,106.9 127.02,106.91 126.95,106.91 126.67,107.18 126.67,107.99 126.87,108.19 127.72,108.19 127.72,108.2 128.07,108.55 128.07,109.44 128.21,109.58 129.89,109.58 130.44,110.13 130.44,110.91 130.54,111.01 131.14,111.01
LX_1VS_VCCIO on TOP (solid shape): 141.64,108.58 141.64,107.44 141.31,107.12 141.31,105.09 140.65,104.42 138.94,104.42 138.46,104.9 137.57,104.9 137.5,104.97 137.5,105.72 137.57,105.78 138.67,105.78 138.84,105.96 138.84,106.99 139.03,107.17 140.24,107.17 140.85,107.78 140.85,108.6 140.88,108.63 141.58,108.63
LX_3V on TOP (solid shape): 157.1,114.27 157.1,113.51 156.93,113.33 156.57,113.33 156.52,113.33 156.46,113.27 156.33,113.27 156.26,113.29 156.19,113.37 156.19,114.14 156.47,114.42 156.95,114.42
LX_3V on TOP (solid shape): 155.95,111.04 156.12,110.99 156.28,111.04 156.29,111.04 156.42,111.04 156.65,110.81 158.65,110.81 158.66,110.81 158.88,110.81 159.14,110.55 159.14,104.69 158.87,104.43 156.05,104.43 155.62,104.86 155.62,109.97 155.76,110.11 155.76,110.99 155.81,111.04 155.94,111.04
LX_3V on BOTTOM (solid shape): 157.99,109.77 157.99,107.99 158.37,107.61 159.16,107.61 159.36,107.41 159.36,104.51 159.07,104.22 155.83,104.22 155.43,104.63 155.43,107.31 155.66,107.54 155.66,109.87 155.76,109.97 157.79,109.97
LX_5V on BOTTOM (solid shape): 166.93,116.83 166.93,115.77 166.86,115.74 166.81,115.72 166.71,115.72 166.65,115.77 166.65,115.84 166.5,115.99 166.04,115.99 165.87,116.17 165.87,116.68 166.22,117.04 166.73,117.04
LX_5V on BOTTOM (solid shape): 166.95,113.49 167.05,113.51 167.29,113.51 167.37,113.43 167.37,112.62 167.52,112.46 167.67,112.46 168.84,111.3 168.84,109.16 168.66,108.98 164.88,108.98 164.01,109.85 161.32,109.85 161.04,110.13 161.04,111.14 161.14,111.24 162.97,111.24 163.35,111.63 163.35,112.44 163.4,112.49 165.46,112.49 166.3,113.33 166.48,113.33 166.65,113.51 166.85,113.51
NB_PSID on BOTTOM (solid shape): 62.15,89.73 64.72,89.73 65.28,89.17 65.28,87.85 64.89,87.46 59.7,87.46 57.75,89.41 57.75,91.2 58.29,91.74 60.13,91.74
PBATT+_C on TOP (solid shape): 25.85,10.31 25.85,9.73 26.85,8.73 26.98,8.73 27.5,8.21 27.5,6.43 27.37,6.3 23.25,6.3 23.12,6.43 23.12,6.94 22.99,7.07 22.29,7.07 22.23,7.13 22.23,10.5 22.74,11 24.1,11 24.26,11.17 24.99,11.17
PBATT+_C on BOTTOM (solid shape): 26.55,13.16 26.55,8.34 26.17,7.96 22.87,7.96 22.48,8.34 22.48,11.56 23.39,11.56 23.39,11.51 23.4,11.46 23.42,11.4 23.44,11.36 23.47,11.31 23.51,11.27 23.55,11.24 23.59,11.21 23.64,11.19 23.7,11.18 23.75,11.18 23.8,11.18 23.85,11.19 23.9,11.21 23.95,11.24 23.99,11.27 24.03,11.31 24.06,11.36 24.08,11.4 24.1,11.46 24.1,11.51 24.1,11.56 24.1,11.61 24.08,11.67 24.06,11.71 24.03,11.76 23.99,11.8 23.95,11.83 23.9,11.86 23.85,11.88 23.8,11.89 23.75,11.89 23.7,11.89 23.64,11.88 23.59,11.86 23.55,11.83 23.51,11.8 23.47,11.76 23.44,11.71 23.42,11.67 23.4,11.61 23.39,11.56 22.48,11.56 22.48,13.29 22.67,13.48 26.23,13.48
RING2 on TOP (solid shape): 299.09,32.66 299.09,31.26 298.84,31.01 298.84,30.5 298.71,30.37 298.1,30.37 298,30.47 298,30.95 298.18,31.13 298.26,31.13 298.47,31.19 298.61,31.35 298.61,31.36 298.95,31.7 298.95,32.27 298.94,32.37 298.9,32.46 298.9,32.66 298.96,32.72 299.03,32.72
RING2 on BOTTOM (solid shape): 309.69,39.58 309.69,37.93 309.57,37.8 308.3,37.8 308.04,38.05 308.04,39.07 307.73,39.39 307.73,39.58 307.85,39.71 309.57,39.71
RING2_R on TOP (solid shape): 312.55,41.29 312.93,41.29 313.25,40.98 323.73,40.98 324.82,39.88 324.82,39.67 325.19,39.3 325.19,38.09 324.97,37.86 323.09,37.86 322.97,37.99 322.97,38.95 322.33,39.58 320.17,39.58 319.98,39.77 317.95,39.77 317.76,39.58 311.22,39.58 311.03,39.77 311.03,41.86 311.16,41.99 311.85,41.99
RING2_R on BOTTOM (solid shape): 312.33,41.77 312.33,41.39 312.36,41.36 312.36,40.09 312.11,39.83 311.09,39.83 310.96,39.71 310.96,38.94 310.71,38.69 310.01,38.69 309.95,38.75 309.95,39.68 309.95,39.68 309.95,40.53 310.08,40.66 311.03,40.66 311.22,40.85 311.22,41.67 311.41,41.86 312.23,41.86
SA_LGATE on BOTTOM (solid shape): 69.35,76.67 69.35,75.51 69.22,75.38 68.9,75.38 68.56,75.72 68.56,75.74 68.47,75.83 68.47,76.88 68.55,76.95 69.07,76.95
SA_LGATE on BOTTOM (solid shape): 72.24,76.7 72.24,76.27 72.37,76.14 72.37,75.81 72.24,75.68 71.48,75.68 71.3,75.86 71.3,76.66 71.43,76.79 72.15,76.79
SA_SNUB on TOP (solid shape): 74.43,78.69 74.43,76.98 74.36,76.92 73.28,76.92 73.22,76.98 73.22,77.55 73.03,77.74 72.14,77.74 72.08,77.81 72.08,78.69 72.14,78.76 74.36,78.76
SA_SW on TOP (solid shape): 76.99,78.58 76.99,76.95 74.94,76.95 74.83,77.06 74.83,78.61 74.94,78.71 76.87,78.71
SA_SW on TOP (solid shape): 67.44,75.9 67.25,75.71 66.51,75.71 66.49,75.69 66.17,75.69 66.07,75.8 66.07,76.24 66.62,76.79 66.62,76.79 66.62,77.42 66.74,77.54 67.44,77.54
SA_SW on BOTTOM (solid shape): 67.23,76.88 67.23,75.84 67.1,75.71 66.55,75.71 66.55,75.71 65.88,75.71 65.82,75.77 65.82,76.79 65.98,76.95 67.15,76.95
SA_SW on BOTTOM (solid shape): 77.58,79.62 77.58,76.64 77.41,76.47 75,76.47 74.55,76.92 74.35,76.92 74.35,76.92 74.03,76.92 73.96,76.92 73.89,76.92 73.38,76.92 73.31,76.92 73.24,76.92 72.73,76.92 72.66,76.92 72.59,76.92 72.08,76.92 72.01,76.92 71.94,76.92 71.63,76.92 71.57,76.98 71.57,78.06 71.63,78.12 74.43,78.12 74.74,78.44 74.74,79.52 74.95,79.72 77.48,79.72
SA_UGATE on BOTTOM (solid shape): 72.24,79.9 72.24,79.18 72.14,79.08 71.16,79.08 71.05,79.18 71.05,79.96 71.31,80.22 71.93,80.22
SA_UGATE on BOTTOM (solid shape): 67.19,80.17 67.19,79.13 67.23,79.09 67.23,78.43 67.18,78.38 66.55,78.38 66.09,78.84 66.09,79.65 66.71,80.26 67.09,80.26
SLEEVE on TOP (solid shape): 299.53,32.66 299.53,31.32 299.73,31.13 299.73,31.01 299.79,30.94 299.98,30.94 300.11,30.82 300.11,30.5 299.98,30.37 299.09,30.37 298.96,30.5 298.96,30.94 299.28,31.26 299.28,32.66 299.34,32.72 299.47,32.72
SLEEVE on BOTTOM (solid shape): 309.63,37.17 309.63,35.26 309.57,35.2 308.11,35.2 308.04,35.26 308.04,37.04 308.11,37.1 308.49,37.1 308.68,37.29 309.5,37.29
SLEEVE_R on TOP (solid shape): 313.06,39.13 313.06,38.56 312.18,37.67 311.28,37.67 311.09,37.86 311.09,39.01 311.41,39.32 312.87,39.32
SLEEVE_R on BOTTOM (solid shape): 314.2,39.64 314.2,39.01 312.81,37.61 312.81,36.47 312.62,36.28 311.98,36.28 311.85,36.15 311.13,36.15 310.9,36.21 310.67,36.15 309.89,36.15 309.89,37.17 310.45,37.17 311.03,37.11 311.28,37.63 311.28,37.64 311.28,39.26 311.47,39.45 312.11,39.45 312.36,39.71 314.14,39.71
SNB_+1VALWP on BOTTOM (solid shape): 175.14,91.97 175.14,89.55 175.07,89.49 174.06,89.49 174.06,92.03 174.12,92.09 175.01,92.09
